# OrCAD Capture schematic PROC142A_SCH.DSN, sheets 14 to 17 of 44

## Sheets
14 13. CURRENT MONITORING DEVICES: size C; title: CURRENT MONITORING DEVICES
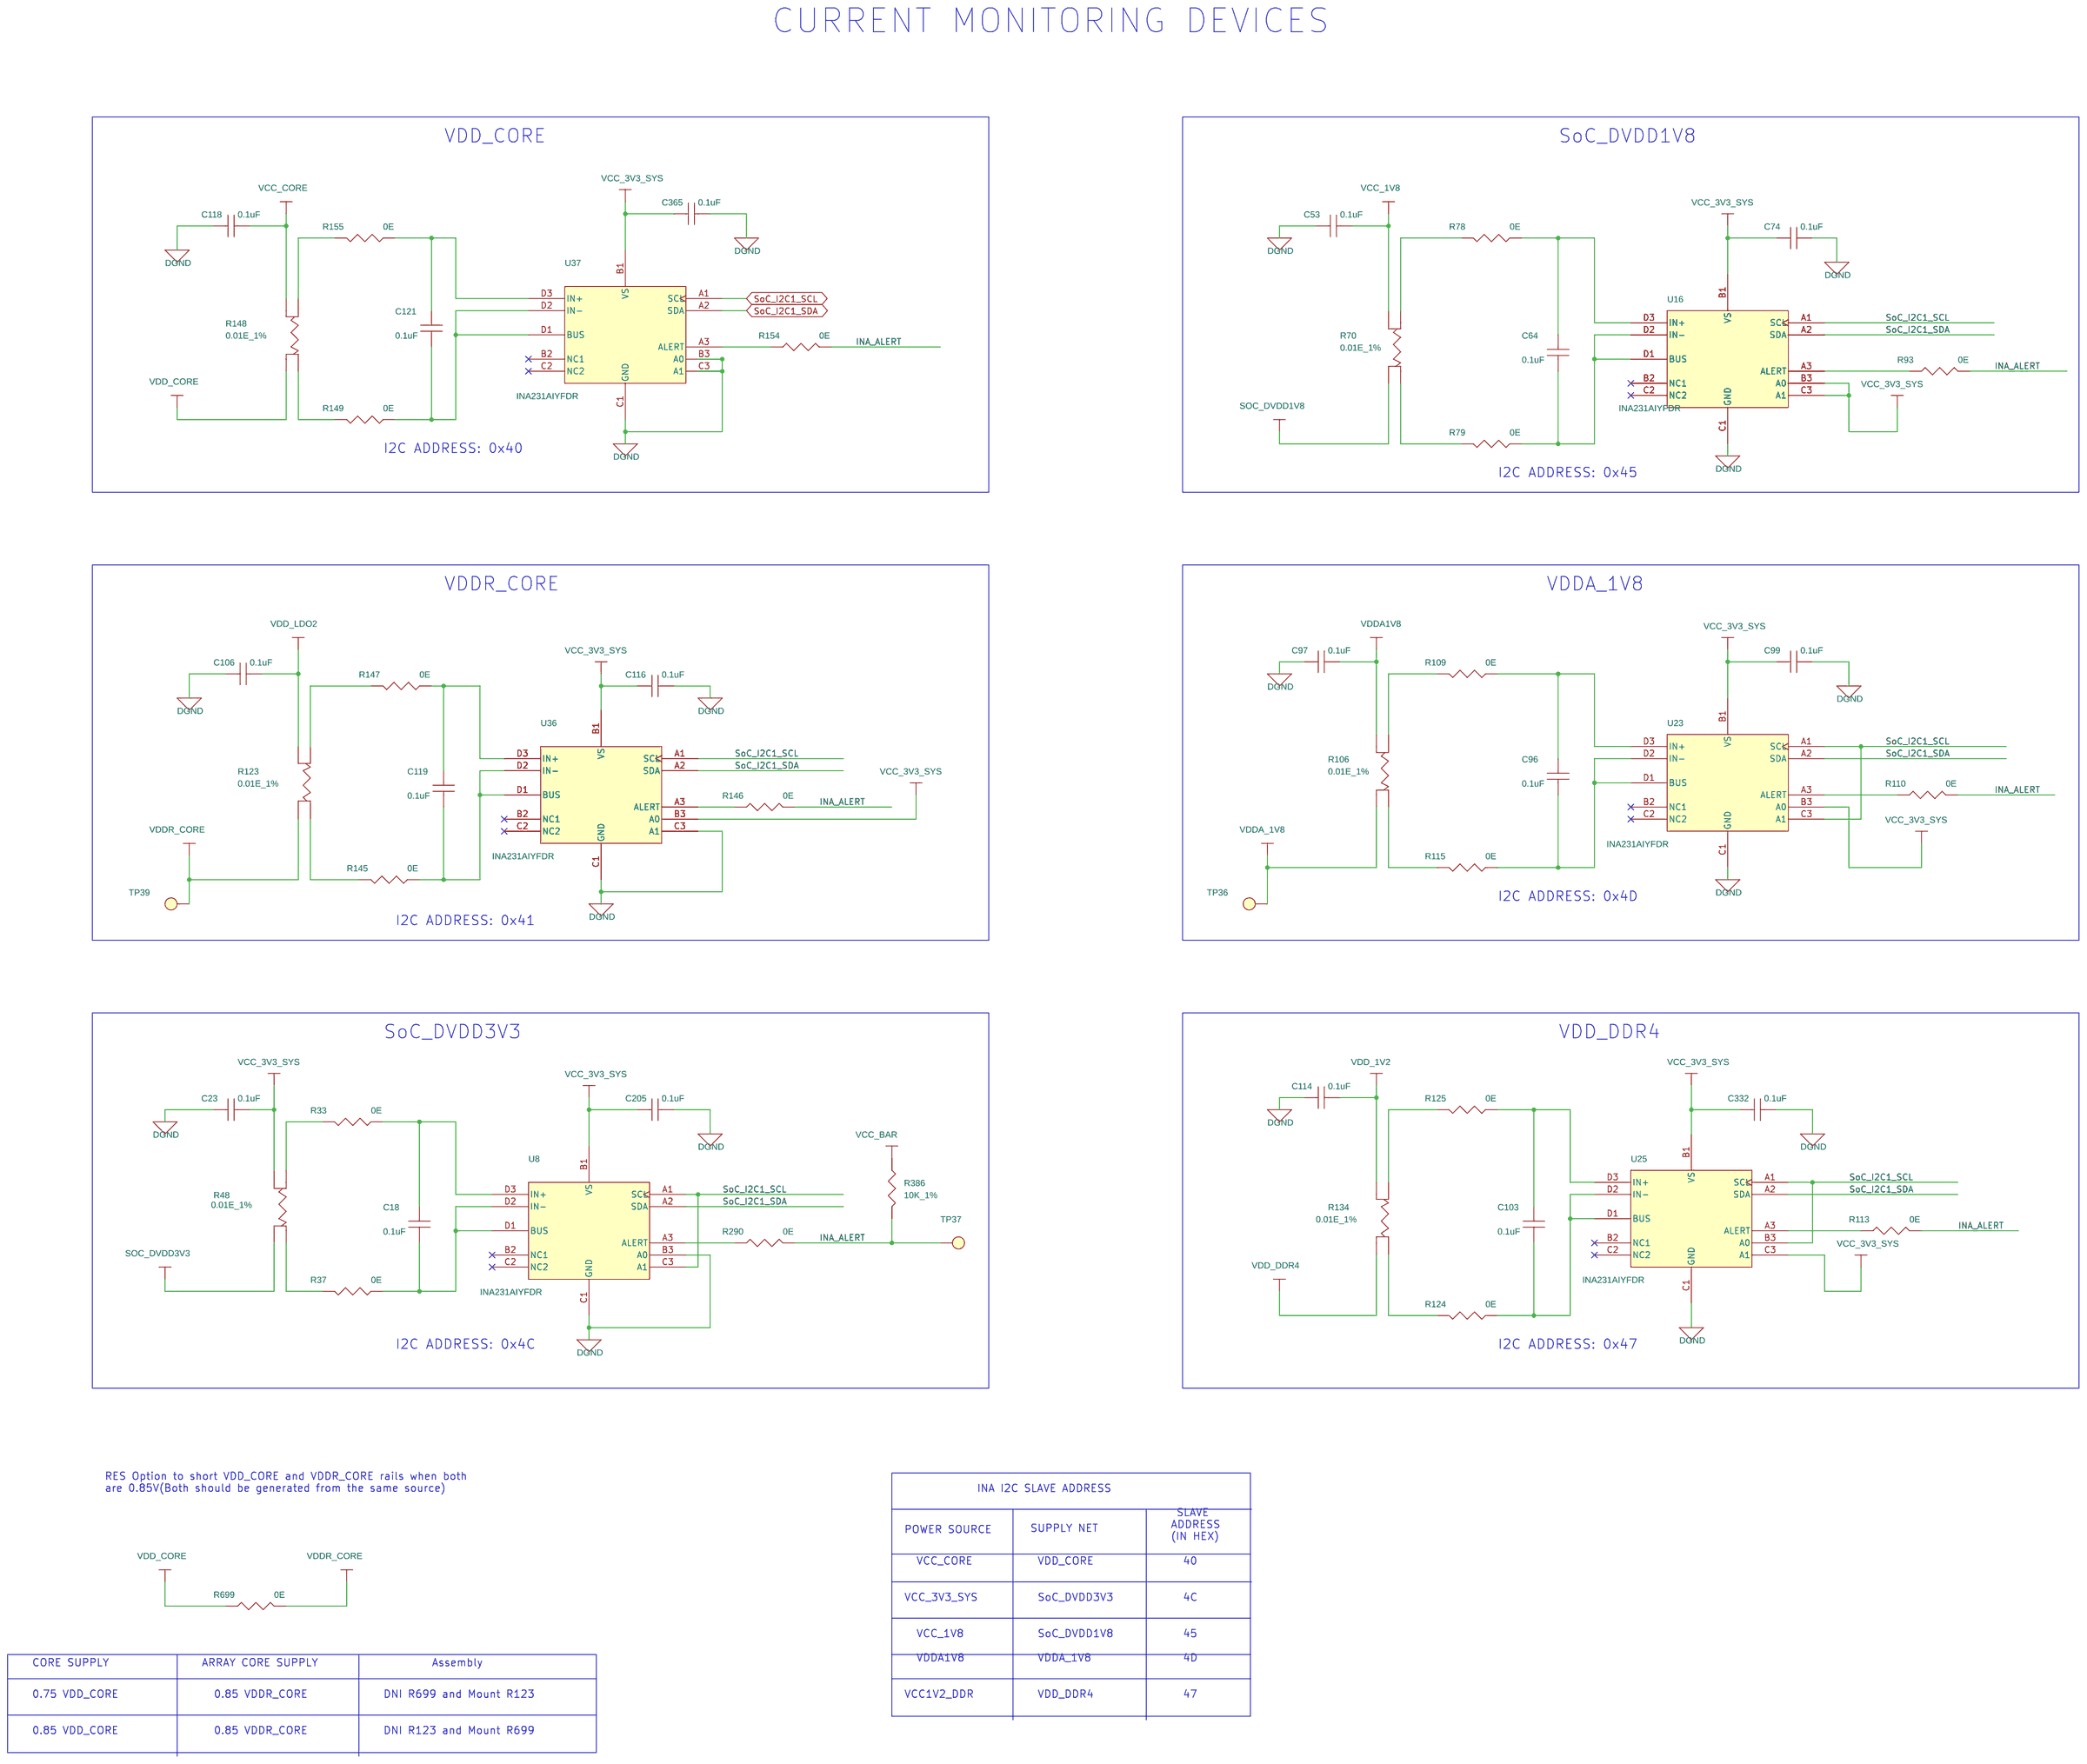
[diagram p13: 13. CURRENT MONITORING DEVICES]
15 14. SOC POWER: size C; title: SOC POWER
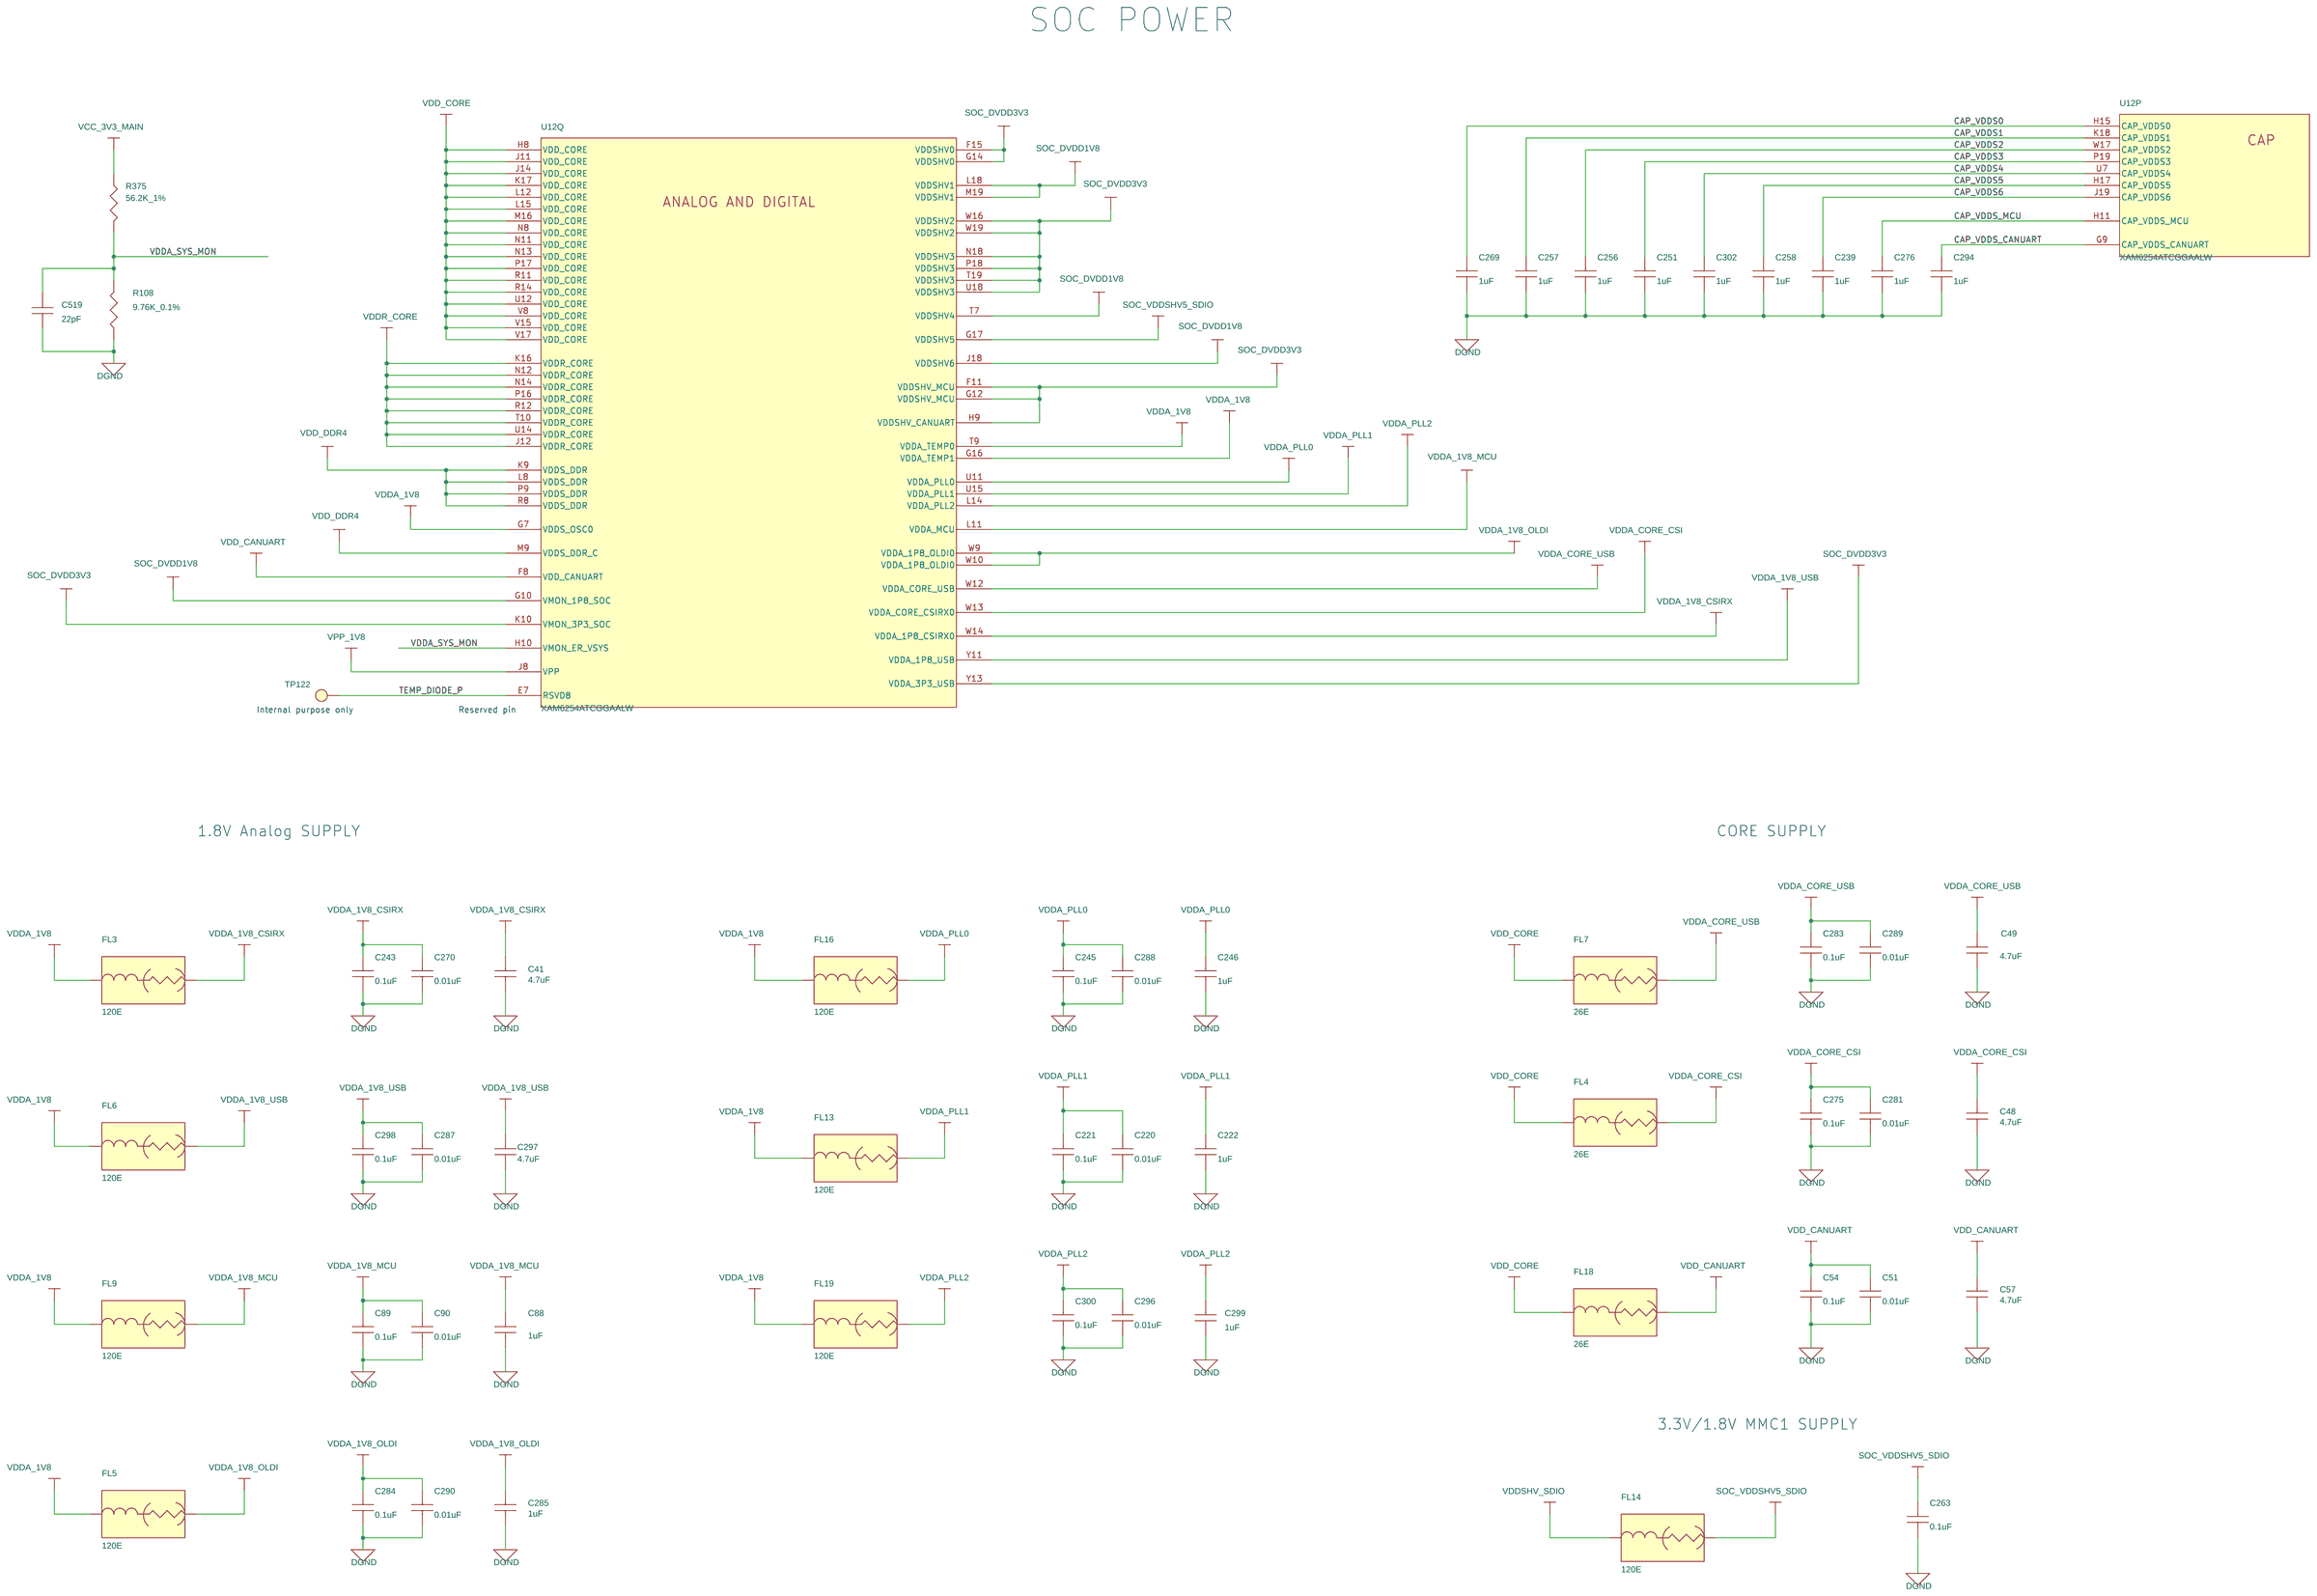
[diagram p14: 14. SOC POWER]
16 15. SOC POWER CAPS: size C; title: SOC POWER CAPS & SOC VSS
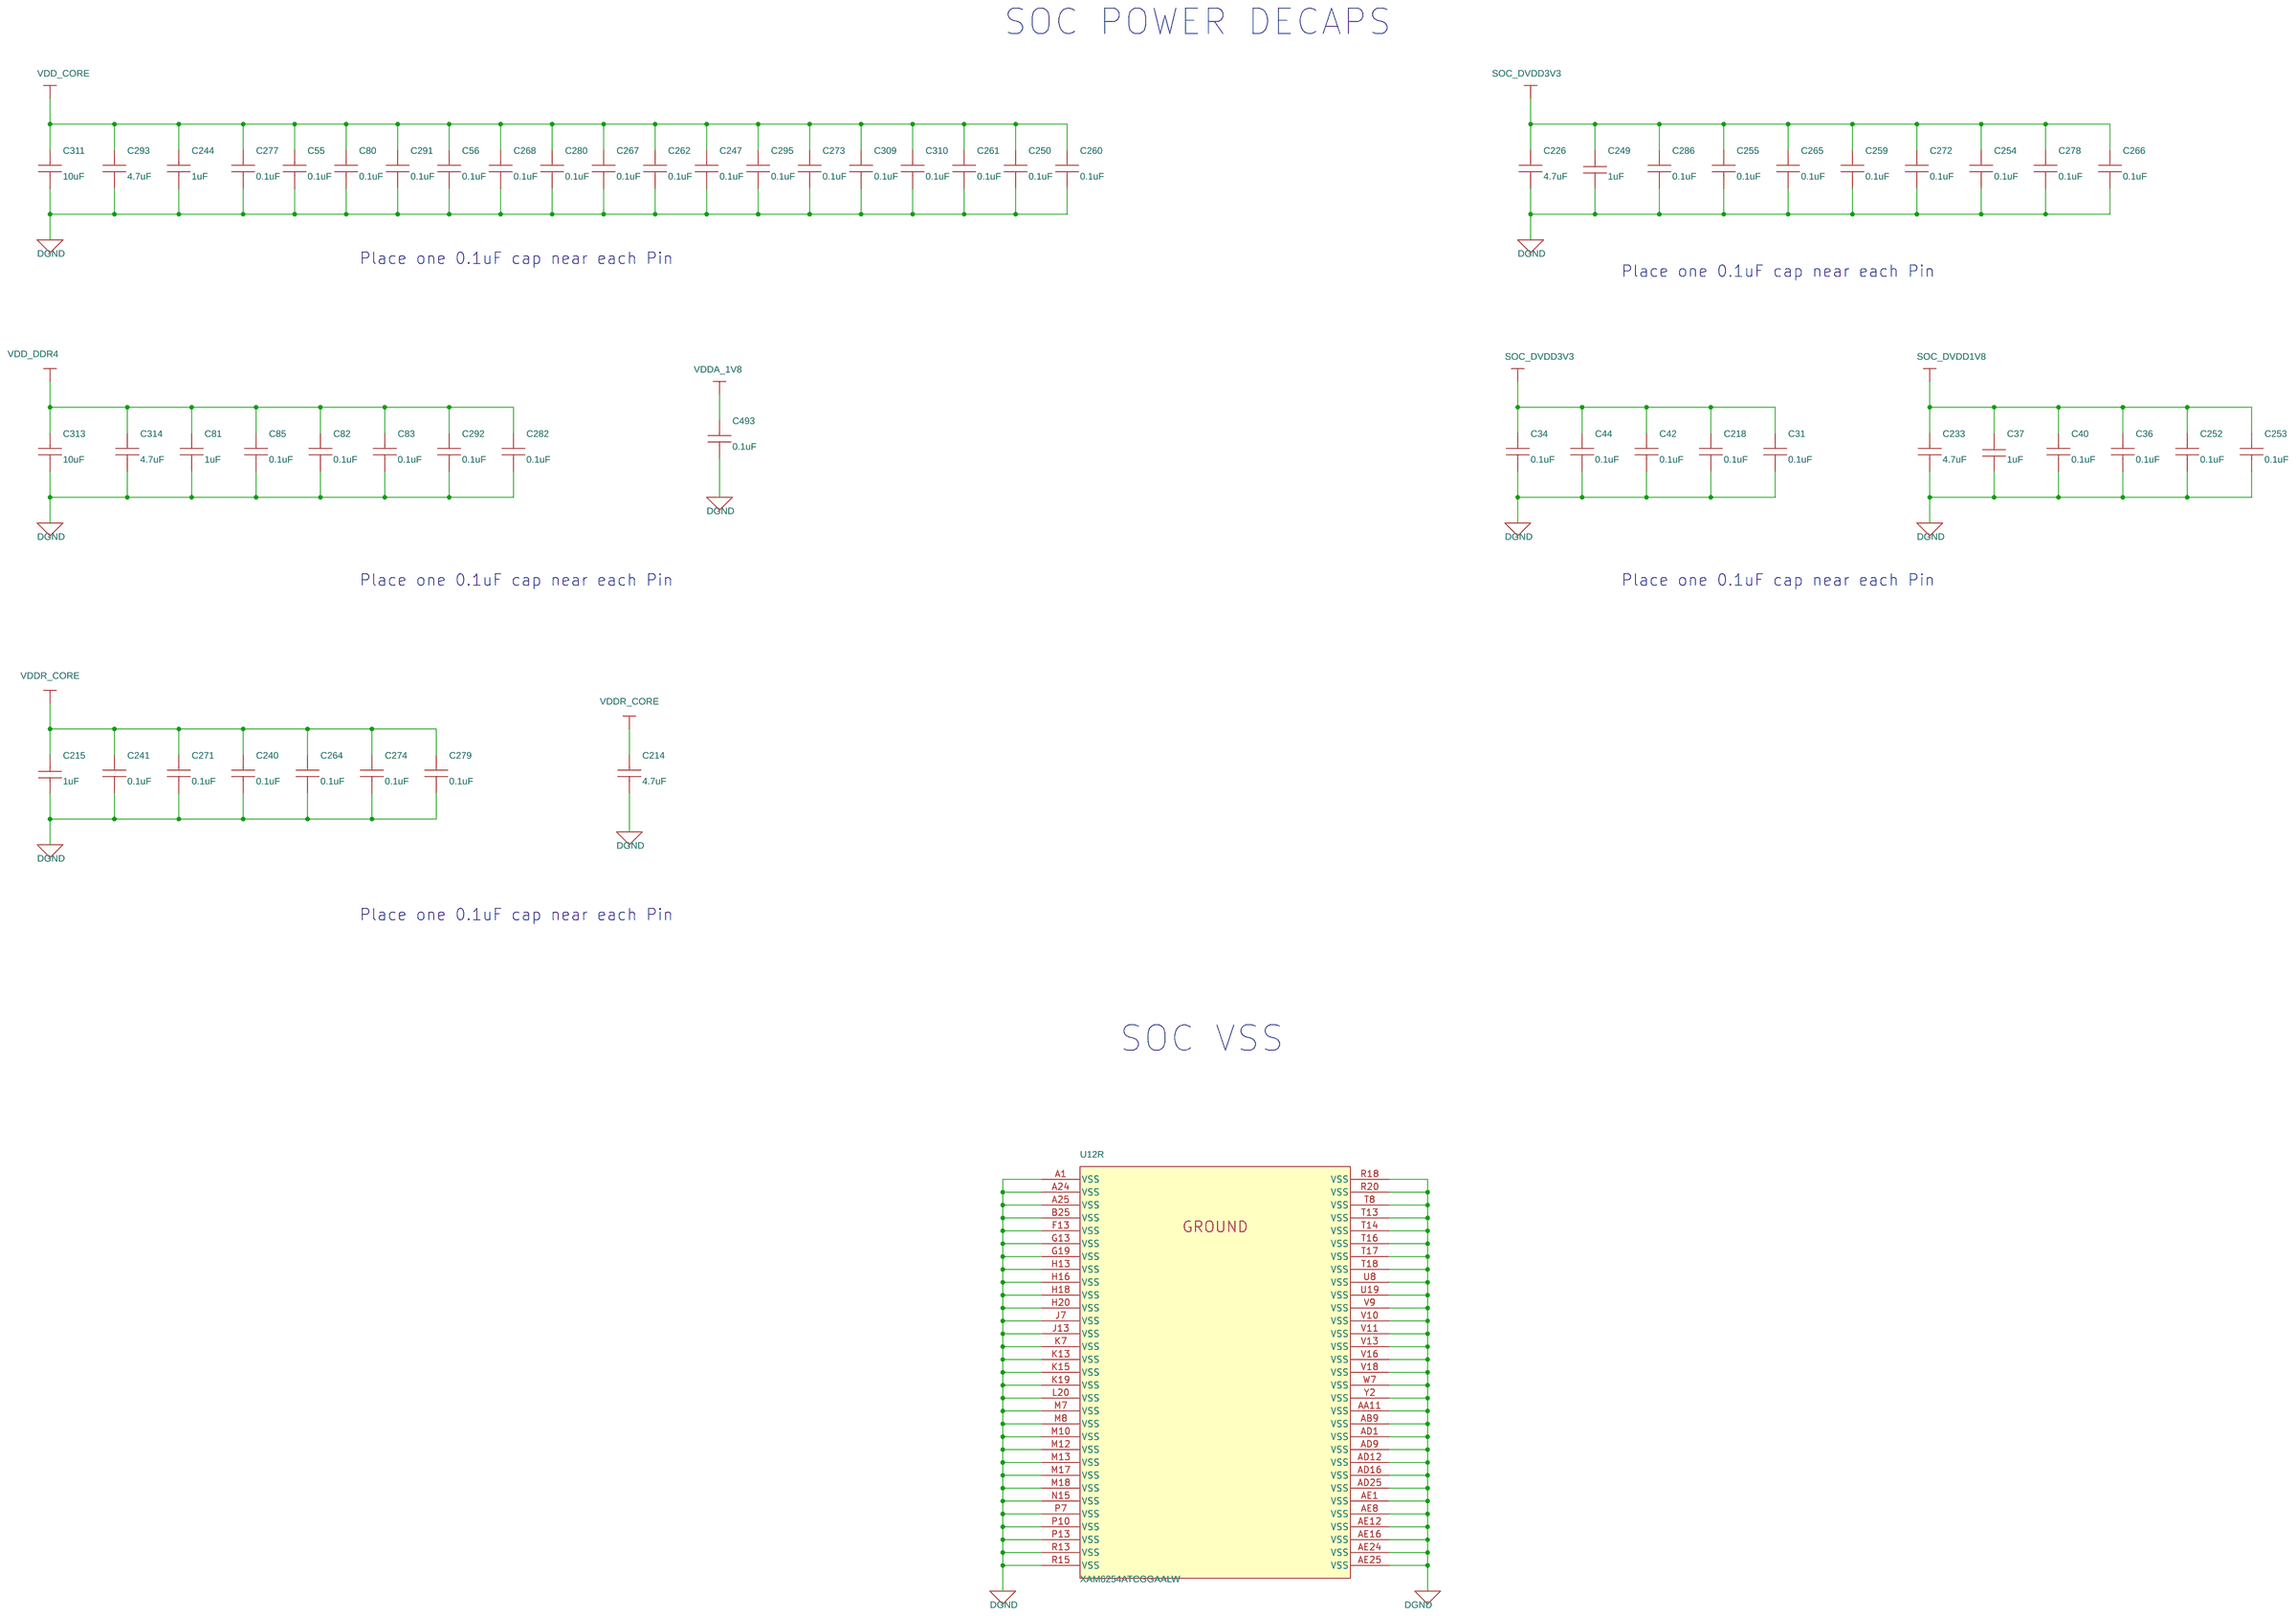
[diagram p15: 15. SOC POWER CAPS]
17 16. DDR4 INTERFACE: size C; title: DDR4 Interface

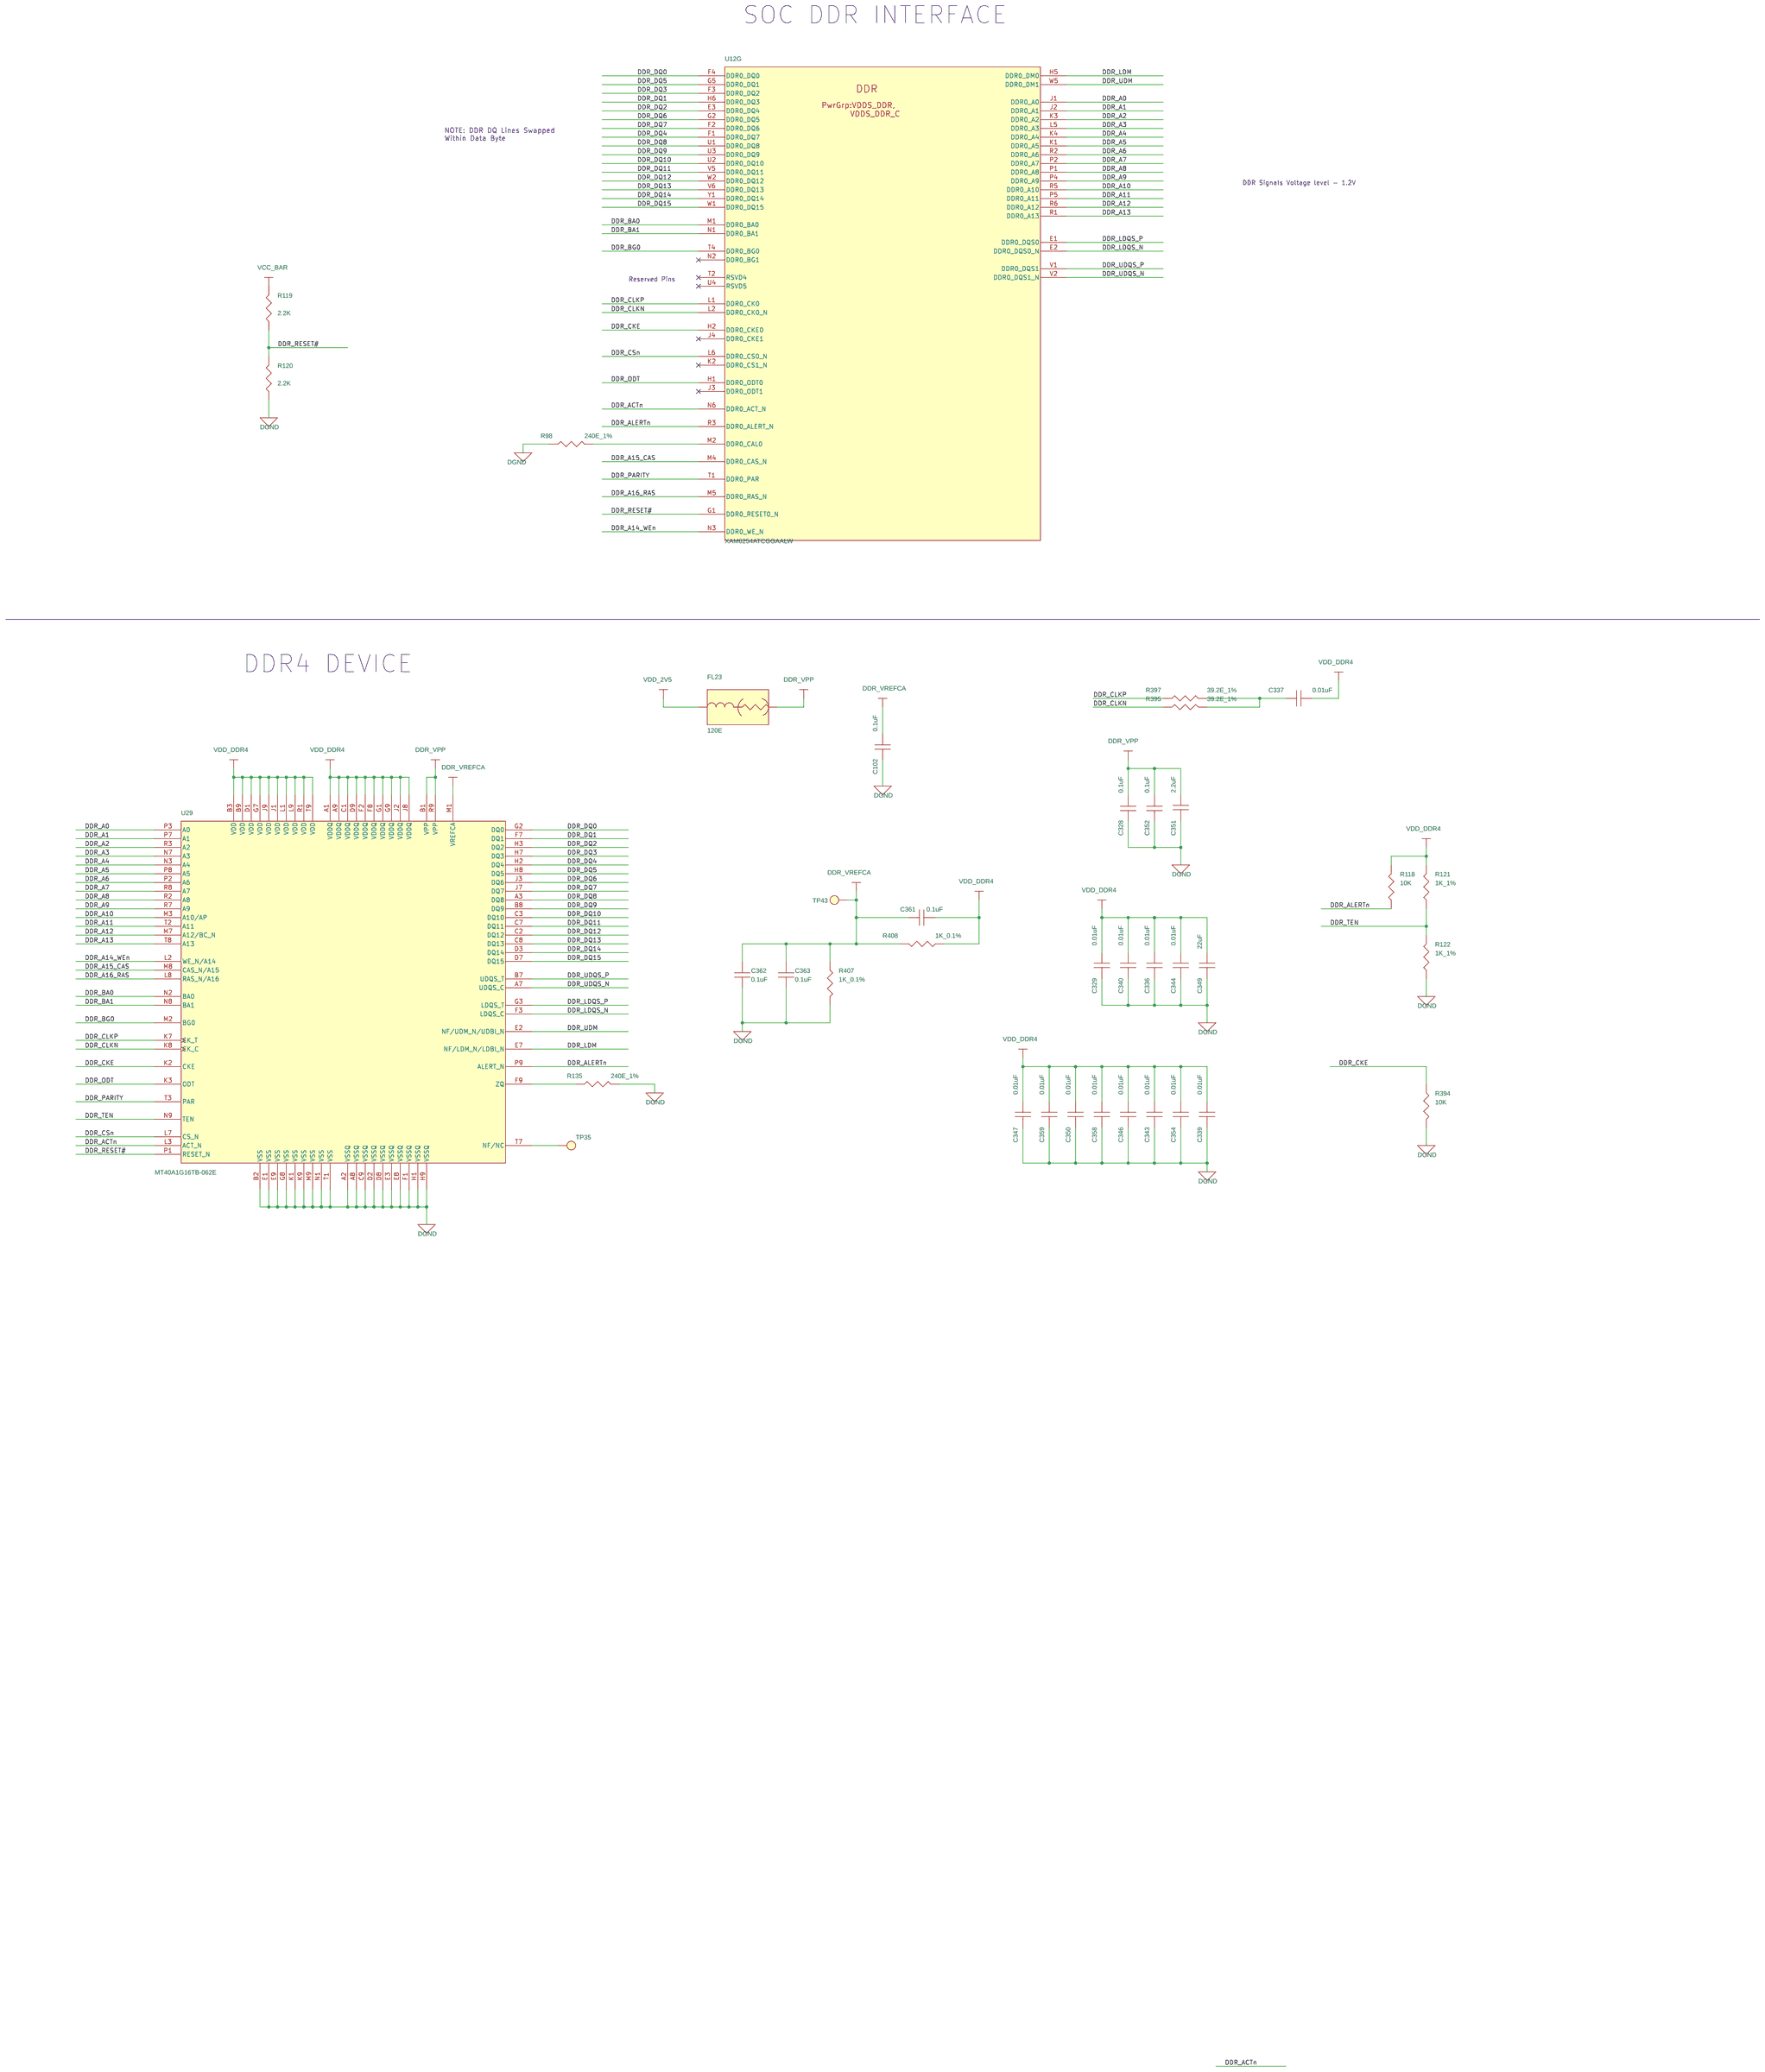
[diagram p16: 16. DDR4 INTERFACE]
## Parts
sheet 13. CURRENT MONITORING DEVICES
C18  0.1uF  [CAP0402_0-75]
C23  0.1uF  [CAP0402_0-75]
C53  0.1uF  [CAP0402_0-75]
C64  0.1uF  [CAP0402_0-75]
C74  0.1uF  [CAP0402_0-75]
C96  0.1uF  [CAP0402_0-75]
C97  0.1uF  [CAP0402_0-75]
C99  0.1uF  [CAP0402_0-75]
C103  0.1uF  [CAP0402_0-75]
C106  0.1uF  [CAP0402_0-75]
C114  0.1uF  [CAP0402_0-75]
C116  0.1uF  [CAP0402_0-75]
C118  0.1uF  [CAP0402_0-75]
C119  0.1uF  [CAP0402_0-75]
C121  0.1uF  [CAP0402_0-75]
C205  0.1uF  [CAP0402_0-75]
C332  0.1uF  [CAP0402_0-75]
C365  0.1uF  [CAP0402_0-75]
R33  0E  [RES0402_0-5]
R37  0E  [RES0402_0-5]
R48  0.01E_1%  [RES_KRL3216T4_1206-4_0-7]
R70  0.01E_1%  [RES_KRL3216T4_1206-4_0-7]
R78  0E  [RES0402_0-5]
R79  0E  [RES0402_0-5]
R93  0E  [RES0402_0-5]
R106  0.01E_1%  [RES_KRL3216T4_1206-4_0-7]
R109  0E  [RES0402_0-5]
R110  0E  [RES0402_0-5]
R113  0E  [RES0402_0-5]
R115  0E  [RES0402_0-5]
R123  0.01E_1%  [RES_KRL3216T4_1206-4_0-7]
R124  0E  [RES0402_0-5]
R125  0E  [RES0402_0-5]
R134  0.01E_1%  [RES_KRL3216T4_1206-4_0-7]
R145  0E  [RES0402_0-5]
R146  0E  [RES0402_0-5]
R147  0E  [RES0402_0-5]
R148  0.01E_1%  [RES_KRL3216T4_1206-4_0-7]
R149  0E  [RES0402_0-5]
R154  0E  [RES0402_0-5]
R155  0E  [RES0402_0-5]
R290  0E  [RES0402_0-5]
R386  10K_1%  [RES0201_0-5]
R699  0E  [RES0805_0-75]
TP36  TP20_SMD  [TP20_SMD]
TP37  TP20_SMD  [TP20_SMD]
TP39  TP20_SMD  [TP20_SMD]
U8  INA231AIYFDR  [DSBGA12_15-74_60X70_0-4]
U16  INA231AIYFDR  [DSBGA12_15-74_60X70_0-4]
U23  INA231AIYFDR  [DSBGA12_15-74_60X70_0-4]
U25  INA231AIYFDR  [DSBGA12_15-74_60X70_0-4]
U36  INA231AIYFDR  [DSBGA12_15-74_60X70_0-4]
U37  INA231AIYFDR  [DSBGA12_15-74_60X70_0-4]
sheet 14. SOC POWER
C41  4.7uF  [CAP0402_0-75]
C48  4.7uF  [CAP0402_0-75]
C49  4.7uF  [CAP0402_0-75]
C51  0.01uF  [CAP0201_0-5]
C54  0.1uF  [CAP0201_0-5]
C57  4.7uF  [CAP0402_0-75]
C88  1uF  [CAP0201_0-5]
C89  0.1uF  [CAP0201_0-5]
C90  0.01uF  [CAP0201_0-5]
C220  0.01uF  [CAP0201_0-5]
C221  0.1uF  [CAP0201_0-5]
C222  1uF  [CAP0201_0-5]
C239  1uF  [CAP0201_0-5]
C243  0.1uF  [CAP0201_0-5]
C245  0.1uF  [CAP0201_0-5]
C246  1uF  [CAP0201_0-5]
C251  1uF  [CAP0201_0-5]
C256  1uF  [CAP0201_0-5]
C257  1uF  [CAP0201_0-5]
C258  1uF  [CAP0201_0-5]
C263  0.1uF  [CAP0201_0-5]
C269  1uF  [CAP0201_0-5]
C270  0.01uF  [CAP0201_0-5]
C275  0.1uF  [CAP0201_0-5]
C276  1uF  [CAP0201_0-5]
C281  0.01uF  [CAP0201_0-5]
C283  0.1uF  [CAP0201_0-5]
C284  0.1uF  [CAP0201_0-5]
C285  1uF  [CAP0201_0-5]
C287  0.01uF  [CAP0201_0-5]
C288  0.01uF  [CAP0201_0-5]
C289  0.01uF  [CAP0201_0-5]
C290  0.01uF  [CAP0201_0-5]
C294  1uF  [CAP0201_0-5]
C296  0.01uF  [CAP0201_0-5]
C297  4.7uF  [CAP0402_0-75]
C298  0.1uF  [CAP0201_0-5]
C299  1uF  [CAP0201_0-5]
C300  0.1uF  [CAP0201_0-5]
C302  1uF  [CAP0201_0-5]
C519  22pF  [CAP0201_0-5]
FL3  120E  [EMIFIL_BLM15A_0402_0-6]
FL4  26E  [EMIFIL_BLM18K_0603_0-7]
FL5  120E  [EMIFIL_BLM15A_0402_0-6]
FL6  120E  [EMIFIL_BLM15A_0402_0-6]
FL7  26E  [EMIFIL_BLM18K_0603_0-7]
FL9  120E  [EMIFIL_BLM15A_0402_0-6]
FL13  120E  [EMIFIL_BLM15A_0402_0-6]
FL14  120E  [EMIFIL_BLM15A_0402_0-6]
FL16  120E  [EMIFIL_BLM15A_0402_0-6]
FL18  26E  [EMIFIL_BLM18K_0603_0-7]
FL19  120E  [EMIFIL_BLM15A_0402_0-6]
R108  9.76K_0.1%  [RES0402_0-5]
R375  56.2K_1%  [RES0402_0-5]
TP122  TP20_SMD  [TP20_SMD]
sheet 15. SOC POWER CAPS
C31  0.1uF  [CAP0201_0-5]
C34  0.1uF  [CAP0201_0-5]
C36  0.1uF  [CAP0201_0-5]
C37  1uF  [CAP0201_0-5]
C40  0.1uF  [CAP0201_0-5]
C42  0.1uF  [CAP0201_0-5]
C44  0.1uF  [CAP0201_0-5]
C55  0.1uF  [CAP0201_0-5]
C56  0.1uF  [CAP0201_0-5]
C80  0.1uF  [CAP0201_0-5]
C81  1uF  [CAP0201_0-5]
C82  0.1uF  [CAP0201_0-5]
C83  0.1uF  [CAP0201_0-5]
C85  0.1uF  [CAP0201_0-5]
C214  4.7uF  [CAP0402_0-75]
C215  1uF  [CAP0201_0-5]
C218  0.1uF  [CAP0201_0-5]
C226  4.7uF  [CAP0402_0-75]
C233  4.7uF  [CAP0402_0-75]
C240  0.1uF  [CAP0201_0-5]
C241  0.1uF  [CAP0201_0-5]
C244  1uF  [CAP0201_0-5]
C247  0.1uF  [CAP0201_0-5]
C249  1uF  [CAP0201_0-5]
C250  0.1uF  [CAP0201_0-5]
C252  0.1uF  [CAP0201_0-5]
C253  0.1uF  [CAP0201_0-5]
C254  0.1uF  [CAP0201_0-5]
C255  0.1uF  [CAP0201_0-5]
C259  0.1uF  [CAP0201_0-5]
C260  0.1uF  [CAP0201_0-5]
C261  0.1uF  [CAP0201_0-5]
C262  0.1uF  [CAP0201_0-5]
C264  0.1uF  [CAP0201_0-5]
C265  0.1uF  [CAP0201_0-5]
C266  0.1uF  [CAP0201_0-5]
C267  0.1uF  [CAP0201_0-5]
C268  0.1uF  [CAP0201_0-5]
C271  0.1uF  [CAP0201_0-5]
C272  0.1uF  [CAP0201_0-5]
C273  0.1uF  [CAP0201_0-5]
C274  0.1uF  [CAP0201_0-5]
C277  0.1uF  [CAP0201_0-5]
C278  0.1uF  [CAP0201_0-5]
C279  0.1uF  [CAP0201_0-5]
C280  0.1uF  [CAP0201_0-5]
C282  0.1uF  [CAP0201_0-5]
C286  0.1uF  [CAP0201_0-5]
C291  0.1uF  [CAP0201_0-5]
C292  0.1uF  [CAP0201_0-5]
C293  4.7uF  [CAP0402_0-75]
C295  0.1uF  [CAP0201_0-5]
C309  0.1uF  [CAP0201_0-5]
C310  0.1uF  [CAP0201_0-5]
C311  10uF  [CAP0402_0-75]
C313  10uF  [CAP0402_0-75]
C314  4.7uF  [CAP0402_0-75]
C493  0.1uF  [CAP0201_0-5]
sheet 16. DDR4 INTERFACE
C102  0.1uF  [CAP0201_0-5]
C328  0.1uF  [CAP0201_0-5]
C329  0.01uF  [CAP0201_0-5]
C336  0.01uF  [CAP0201_0-5]
C337  0.01uF  [CAP0201_0-5]
C339  0.01uF  [CAP0201_0-5]
C340  0.01uF  [CAP0201_0-5]
C343  0.01uF  [CAP0201_0-5]
C344  0.01uF  [CAP0201_0-5]
C346  0.01uF  [CAP0201_0-5]
C347  0.01uF  [CAP0201_0-5]
C349  22uF  [CAP0603_1]
C350  0.01uF  [CAP0201_0-5]
C351  2.2uF  [CAP0402_0-75]
C352  0.1uF  [CAP0201_0-5]
C354  0.01uF  [CAP0201_0-5]
C358  0.01uF  [CAP0201_0-5]
C359  0.01uF  [CAP0201_0-5]
C361  0.1uF  [CAP0201_0-5]
C362  0.1uF  [CAP0201_0-5]
C363  0.1uF  [CAP0201_0-5]
FL23  120E  [EMIFIL_BLM15A_0402_0-6]
R98  240E_1%  [RES0402_0-5]
R118  10K  [RES0201_0-5]
R119  2.2K  [RES0201_0-5]
R120  2.2K  [RES0402_0-5]
R121  1K_1%  [RES0402_0-5]
R122  1K_1%  [RES0402_0-5]
R135  240E_1%  [RES0402_0-5]
R394  10K  [RES0201_0-5]
R395  39.2E_1%  [RES0402_0-5]
R397  39.2E_1%  [RES0402_0-5]
R407  1K_0.1%  [RES0201_0-5]
R408  1K_0.1%  [RES0201_0-5]
TP35  TP20_SMD  [TP20_SMD]
TP43  TP20_SMD  [TP20_SMD]
U29  MT40A1G16TB-062E  [FBGA96_31-49_300X520_1-2]
sheet 29. JTAG BUFFER
U12  XAM6254ATCGGAALW  [BGA425_19-68_510X510_0-7]  (sections A,B,C,D,E,F,G,H,I,J,K,L,M,N,O,P,Q,R)

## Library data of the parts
C18 C23 C53 C64 C74 C96 C97 C99 C103 C106 C114 C116 C118 C119 C121 C205 C332 C365 = CAP: CAP CERAMIC 0.1uF 50V 10% X7R 0402; Alt_Mfr_name: YAGEO AMERICA; Alt_Mfr_part_number: CC0402KRX5R8BB104; Chkd/date: MANIRAJA/261020; Crtd /date: ALVY/211020; Custom_Duty: 15%; Customs_HS_Code: 85322990; Distributor_name: DIGIKEY; Distributor_part_number: 490-10700-1-ND; Footprint Path: Y:\MIS_DATABASE\Library\ALTIUM_TOOL\PCB_FOOTPRINTS\Altium_Footprint_Lib.PcbLib; Height: 0.55MM; Library Path: Y:\MIS_DATABASE\Library\ALTIUM_TOOL\SCHEMATICS_PARTS\MS_DISCRETE_Library.schlib; Mfr_name: MURATA; Mfr_part_number: GRM155R71H104KE14D; Mistral Part No: 120011100014-R; Package: 0402; Part_type: CAPACITORS\CERAMIC; Project: J7_CP; RoHS: RoHS; Temperature: -55°C+125°C; Tolerance: 10%; Voltage: 50V; Wattage: NA; Weight: 3.1mg; Datasheet: Y:\MIS_DATABASE\DATASHEETS\CAPACITORS\GRM155R71H104KE14.PDF
R33 R37 R78 R79 R93 R109 R110 R113 R115 R124 R125 R145-R147 R149 R154 R155 R290 = RESISTOR: RES 0E 1/16W JUMPER 0402; Chkd/date: VASANTHA/201216; Crtd /date: MUDDU/190810; Custom_Duty: 15%; Customs_HS_Code: 85332119; Distributor_name: DIGIKEY; Distributor_part_number: 541-0.0JCT-ND; Footprint Path: Y:\MIS_DATABASE\Library\ALTIUM_TOOL\PCB_FOOTPRINTS\Altium_Footprint_Lib.PcbLib; Height: 0.40MM; Library Path: Y:\MIS_DATABASE\Library\ALTIUM_TOOL\SCHEMATICS_PARTS\MS_DISCRETE_Library.schlib; Mfr_name: VISHAY; Mfr_part_number: CRCW04020000Z0ED; Mistral Part No: 110010080019-R; Package: 0402; Part_type: RESISTORS\FIXED; Project: PB_BUGBASE; RoHS: RoHS; Temperature: -55°C+155°C; Tolerance: NA; Voltage: NA; Wattage: 1/16W; Weight: 0.65mg; Datasheet: Y:\MIS_DATABASE\DATASHEETS\RESISTORS\CRCW0603.PDF
R48 R70 R106 R123 R134 R148 = RESISTOR-4TERM: RES 0.01E 1W 1% 1206-4; Chkd/date: MANIRAJA/060318; Crtd /date: MANIRAJA/060318; Custom_Duty: 15%; Customs_HS_Code: 85332119; Distributor_name: DIGIKEY; Distributor_part_number: 408-1974-1-ND; Footprint Path: Y:\MIS_DATABASE\Library\ALTIUM_TOOL\PCB_FOOTPRINTS\Altium_Footprint_Lib.PcbLib; Height: 0.70MM; Library Path: Y:\MIS_DATABASE\Library\ALTIUM_TOOL\SCHEMATICS_PARTS\MS_DISCRETE_Library.schlib; Mfr_name: SUSUMU; Mfr_part_number: KRL3216T4A-M-R010-F-T1; Mistral Part No: 110018030003-R; Package: 1206-4; Part_type: RESISTORS\FIXED; Project: GRACO SMART MODULE; RoHS: RoHS; Temperature: -55°C+155°C; Tolerance: 1%; Voltage: NA; Wattage: 1W; Weight: 16.2mg; Datasheet: Y:\MIS_DATABASE\DATASHEETS\RESISTORS\KRL-SERIES.PDF
R386 = RESISTOR: RES 10K 1/20W 1% 0201; Chkd/date: VASANTHA/270117; Crtd /date: MANIRAJA/270117; Custom_Duty: 15%; Customs_HS_Code: 85332119; Distributor_name: DIGIKEY; Distributor_part_number: 311-10.0KMCT-ND; Footprint Path: Y:\MIS_DATABASE\Library\ALTIUM_TOOL\PCB_FOOTPRINTS\Altium_Footprint_Lib.PcbLib; Height: 0.26MM; Library Path: Y:\MIS_DATABASE\Library\ALTIUM_TOOL\SCHEMATICS_PARTS\MS_DISCRETE_Library.schlib; Mfr_name: YAGEO AMERICA; Mfr_part_number: RC0201FR-0710KL; Mistral Part No: 110011040018-R; Package: 0201; Part_type: RESISTORS\FIXED; Project: GOLDEN-I LITE; RoHS: RoHS; Temperature: -55°C+125°C; Tolerance: 1%; Voltage: NA; Wattage: 1/20W; Weight: 0.17mg; Datasheet: Y:\MIS_DATABASE\DATASHEETS\RESISTORS\RCXXXXL-SER_MAR18.PDF
R699 = RESISTOR: RES 0E 1/8W 5% 0805; Chkd/date: VASANTHA/130416; Crtd /date: JEBRAN/020316; Custom_Duty: 15%; Customs_HS_Code: 85332119; Distributor_name: DIGIKEY; Distributor_part_number: 311-0.0ARCT-ND; Footprint Path: Y:\MIS_DATABASE\Library\ALTIUM_TOOL\PCB_FOOTPRINTS\Altium_Footprint_Lib.PcbLib; Height: 0.60MM; Library Path: Y:\MIS_DATABASE\Library\ALTIUM_TOOL\SCHEMATICS_PARTS\MS_DISCRETE_Library.schlib; Mfr_name: YAGEO AMERICA; Mfr_part_number: RC0805JR-070RL; Mistral Part No: 110009030074-R; Package: 0805; Part_type: RESISTORS\FIXED; Project: ZK_BIOMETRIC; RoHS: RoHS; Temperature: -55°C+155°C; Tolerance: 5%; Voltage: NA; Wattage: 1/8W; Weight: 5.5mg; Datasheet: Y:\MIS_DATABASE\DATASHEETS\RESISTORS\RCXXXXL-SER_MAR18.PDF
TP35-TP37 TP39 TP43 TP122 = TESTPOINT: TESTPOINT CIR 20 SMD; Chkd/date: SHREESHAIL/171006; Crtd /date: MAZHAR/171006; Custom_Duty: NA; Customs_HS_Code: NA; Distributor_name: NA; Distributor_part_number: NA; Footprint Path: Y:\MIS_DATABASE\Library\ALTIUM_TOOL\PCB_FOOTPRINTS\Altium_Footprint_Lib.PcbLib; Height: NA; Library Path: Y:\MIS_DATABASE\Library\ALTIUM_TOOL\SCHEMATICS_PARTS\MS_DISCRETE_Library.schlib; MECHANICAL 3D STEP FILE: NA; Mfr_name: LOCAL; Mistral Part No: NA; Package: SMD; Project: BT MODULE_CSRBC04; RoHS: NA; Temperature: NA; Tolerance: NA; Voltage: NA; Wattage: NA; Weight: NA; Datasheet: NA
U8 U16 U23 U25 U36 U37 = INA231_DSBGA12: IC HIGH OR LOW SIDE MEASUREMENT BI-DIR CURRENT AND POWER MONITOR WITH 1.8V I2C INTERFACE DSBGA12; Chkd/date: MANIRAJA/250821; Crtd /date: ALVY/250821; Custom_Duty: 15%; Customs_HS_Code: 85423100; Distributor_name: DIGIKEY; Distributor_part_number: 296-49645-1-ND; Footprint Path: Y:\MIS_DATABASE\Library\ALTIUM_TOOL\PCB_FOOTPRINTS\Altium_Footprint_Lib.PcbLib; Height: 0.40MM; Library Path: Y:\MIS_DATABASE\Library\ALTIUM_TOOL\SCHEMATICS_PARTS\MS_MISCPOWER_Library.schlib; Mfr_name: TEXAS INSTRUMENTS; Mistral Part No: 142021080022-R; Package: DSBGA12; Part_type: ICS\POWER\MANAGEMENT; Project: TI_AM62x SVB_BRD; RoHS: RoHS; Temperature: -40°C+125°C; Tolerance: NA; Voltage: NA; Wattage: NA; Weight: 200mg; Datasheet: Y:\MIS_DATABASE\DATASHEETS\ICS\POWER\INA231XXX.PDF
C41 C48 C49 C57 C214 C226 C233 C293 C297 C314 = CAP: CAP CERAMIC 4.7uF 10V 20% X5R 0402; Chkd/date: MANIRAJA/110718; Crtd /date: ALVY/110718; Custom_Duty: 15%; Customs_HS_Code: 85322990; Distributor_name: DIGIKEY; Distributor_part_number: 490-14306-1-ND; Footprint Path: Y:\MIS_DATABASE\Library\ALTIUM_TOOL\PCB_FOOTPRINTS\Altium_Footprint_Lib.PcbLib; Height: 0.65MM; Library Path: Y:\MIS_DATABASE\Library\ALTIUM_TOOL\SCHEMATICS_PARTS\MS_DISCRETE_Library.schlib; Mfr_name: MURATA; Mfr_part_number: GRM155R61A475MEAAD; Mistral Part No: 120012060002-R; Package: 0402; Part_type: CAPACITORS\CERAMIC; Project: TI_J7SVB_PCIE_ADD-ON-CARD; RoHS: RoHS; Temperature: -55°C+85°C; Tolerance: 20%; Voltage: 10V; Wattage: NA; Weight: 14mg; Datasheet: Y:\MIS_DATABASE\DATASHEETS\CAPACITORS\GRM155R61A475MEAAD.PDF
C51 C90 C220 C270 C281 C287-C290 C296 C329 C336 C337 C339 C340 C343 C344 C346 C347 C350 C354 C358 C359 = CAP: CAP CERAMIC 0.01uF 25V 10% X5R 0201; Chkd/date: MANIRAJA/230118; Crtd /date: MANIRAJA/230118; Custom_Duty: 15%; Customs_HS_Code: 85322990; Distributor_name: DIGIKEY; Distributor_part_number: GRM033R61E103KA12J-ND; Footprint Path: Y:\MIS_DATABASE\Library\ALTIUM_TOOL\PCB_FOOTPRINTS\Altium_Footprint_Lib.PcbLib; Height: 0.33MM; Library Path: Y:\MIS_DATABASE\Library\ALTIUM_TOOL\SCHEMATICS_PARTS\MS_DISCRETE_Library.schlib; Mfr_name: MURATA; Mfr_part_number: GRM033R61E103KA12J; Mistral Part No: 120018010007-R; Package: 0201; Part_type: CAPACITORS\CERAMIC; Project: TI_MAXIE_CPB; RoHS: RoHS; Temperature: -55°C+85°C; Tolerance: 10%; Voltage: 25V; Wattage: NA; Weight: 0.33mg; Datasheet: Y:\MIS_DATABASE\DATASHEETS\CAPACITORS\GRM033R61E103KA12.PDF
C31 C34 C36 C40 C42 C44 C54-C56 C80 C82 C83 C85 C89 C102 C218 C221 C240 C241 C243 C245 C247 C250 C252-C255 C259-C268 C271-C275 C277-C280 C282-C284 C286 C291 C292 C295 C298 C300 C309 C310 C328 C352 C493 = CAP: CAP CERAMIC 0.1uF 16V 10% X5R 0201; Chkd/date: MANIRAJA/230118; Crtd /date: MANIRAJA/230118; Custom_Duty: 15%; Customs_HS_Code: 85322990; Distributor_name: DIGIKEY; Distributor_part_number: 490-14305-1-ND; Footprint Path: Y:\MIS_DATABASE\Library\ALTIUM_TOOL\PCB_FOOTPRINTS\Altium_Footprint_Lib.PcbLib; Height: 0.33MM; Library Path: Y:\MIS_DATABASE\Library\ALTIUM_TOOL\SCHEMATICS_PARTS\MS_DISCRETE_Library.schlib; Mfr_name: MURATA; Mfr_part_number: GRM033R61C104KE14D; Mistral Part No: 120009030072-R; Package: 0201; Part_type: CAPACITORS\CERAMIC; Project: TI_MAXIE_CPB; RoHS: RoHS; Temperature: -55°C+85°C; Tolerance: 10%; Voltage: 16V; Wattage: NA; Weight: 0.33mg; Datasheet: Y:\MIS_DATABASE\DATASHEETS\CAPACITORS\GRM033R61C104KE14.PDF
C37 C81 C88 C215 C222 C239 C244 C246 C249 C251 C256-C258 C269 C276 C285 C294 C299 C302 = CAP: CAP CERAMIC 1uF 16V 20% X5R 0201; Chkd/date: MANIRAJA/300520; Crtd /date: ALVY/260520; Custom_Duty: 15%; Customs_HS_Code: 85322990; Distributor_name: DIGIKEY; Distributor_part_number: 490-18654-1-ND; Footprint Path: Y:\MIS_DATABASE\Library\ALTIUM_TOOL\PCB_FOOTPRINTS\Altium_Footprint_Lib.PcbLib; Height: 0.39MM; Library Path: Y:\MIS_DATABASE\Library\ALTIUM_TOOL\SCHEMATICS_PARTS\MS_DISCRETE_Library.schlib; Mfr_name: MURATA; Mfr_part_number: GRM033R61C105ME15D; Mistral Part No: 120018090038-R; Package: 0201; Part_type: CAPACITORS\CERAMIC; Project: QCS610_NANOSOM; RoHS: RoHS; Temperature: -55°C+85°C; Tolerance: 20%; Voltage: 16V; Wattage: NA; Weight: 0.33mg; Datasheet: Y:\MIS_DATABASE\DATASHEETS\CAPACITORS\GRM033R61C105ME15.PDF
C519 = CAP: CAP CERAMIC 22pF 25V 1% C0G(NP0) 0201; Chkd/date: MANIRAJA/270721; Crtd /date: ALVY/260721; Custom_Duty: 15%; Customs_HS_Code: 85322990; Distributor_name: DIGIKEY; Distributor_part_number: 490-14545-1-ND; Footprint Path: Y:\MIS_DATABASE\Library\ALTIUM_TOOL\PCB_FOOTPRINTS\Altium_Footprint_Lib.PcbLib; Height: 0.33MM; Library Path: Y:\MIS_DATABASE\Library\ALTIUM_TOOL\SCHEMATICS_PARTS\MS_DISCRETE_Library.schlib; Mfr_name: MURATA; Mfr_part_number: GRM0335C1E220FA01D; Mistral Part No: 120021070019-R; Package: 0201; Part_type: CAPACITORS\CERAMIC; Project: TI_AM335x SK_BRD; RoHS: RoHS; Temperature: -55°C+125°C; Tolerance: 1%; Voltage: 25V; Wattage: NA; Weight: 0.33mg; Datasheet: Y:\MIS_DATABASE\DATASHEETS\CAPACITORS\GRM0335C1E220FA01.PDF
FL3 FL5 FL6 FL9 FL13 FL14 FL16 FL19 FL23 = EMIFILTER_IND: IND FERRITE BEAD CHIP 120E 2A 0402; Chkd/date: NAVEED/241114; Crtd /date: USMAN/170613; Custom_Duty: 24%; Customs_HS_Code: 85369090; Distributor_name: DIGIKEY; Distributor_part_number: 490-9656-1-ND; Footprint Path: Y:\MIS_DATABASE\Library\ALTIUM_TOOL\PCB_FOOTPRINTS\Altium_Footprint_Lib.PcbLib; Height: 0.55MM; Library Path: Y:\MIS_DATABASE\Library\ALTIUM_TOOL\SCHEMATICS_PARTS\MS_FILTER_Library.schlib; Mfr_name: MURATA; Mfr_part_number: BLM15PX121SN1D; Mistral Part No: 130013060022-R; Package: 0402; Part_type: INDUCTOR; Project: GEN_3-8; RoHS: RoHS; Temperature: -55°C+125°C; Tolerance: 25%; Voltage: NA; Wattage: NA; Weight: 1mg; Datasheet: Y:\MIS_DATABASE\DATASHEETS\DISCRETES\INDUCTORS\BLM15-SN1-SER.PDF
FL4 FL7 FL18 = EMIFILTER_IND: FERRITE CHIP 26E 6A 0603; Chkd/date: NAVEED/190115; Crtd /date: USMAN/251013; Custom_Duty: 15%; Customs_HS_Code: 85412900; Distributor_name: DIGIKEY; Distributor_part_number: 490-3995-1-ND; Height: 0.65MM; Mfr_name: MURATA; Mfr_part_number: BLM18SG260TN1D; Mistral Part No: 130013100028-R; Package: 0603; Part_type: FILTER; Project: DTRM_SBAND; RoHS: RoHS; Temperature: -55°C+125°C; Tolerance: 25%; Voltage: NA; Wattage: NA; Weight: 2mg; Datasheet: Y:\MIS_DATABASE\DATASHEETS\DISCRETES\INDUCTORS\BLM18K-SERIES.PDF
R108 = RESISTOR: RES 9.76K 1/16W 0.1% 0402; Chkd/date: MANIRAJA/190419; Crtd /date: MANIRAJA/190419; Custom_Duty: 15%; Customs_HS_Code: 85332119; Distributor_name: DIGIKEY; Distributor_part_number: P9.76KDCCT-ND; Footprint Path: Y:\MIS_DATABASE\Library\ALTIUM_TOOL\PCB_FOOTPRINTS\Altium_Footprint_Lib.PcbLib; Height: 0.40MM; Library Path: Y:\MIS_DATABASE\Library\ALTIUM_TOOL\SCHEMATICS_PARTS\MS_DISCRETE_Library.schlib; Mfr_name: PANASONIC-ECG; Mfr_part_number: ERA-2AEB9761X; Mistral Part No: 110019040291-R; Package: 0402; Part_type: RESISTORS\FIXED; Project: TI_J7ES_EVM_FUSION2_SER_CAP; RoHS: RoHS; Temperature: -55°C+155°C; Tolerance: 0.1%; Voltage: NA; Wattage: 1/16W; Weight: 0.6mg; Datasheet: Y:\MIS_DATABASE\DATASHEETS\RESISTORS\ERA-1A.PDF
R375 = RESISTOR: RES 56.2K 1/16W 1% 0402; Chkd/date: SHREESHAIL/240507; Crtd /date: MAZHAR/010806; Custom_Duty: 15%; Customs_HS_Code: 85332119; Distributor_name: NA; Distributor_part_number: NA; Footprint Path: Y:\MIS_DATABASE\Library\ALTIUM_TOOL\PCB_FOOTPRINTS\Altium_Footprint_Lib.PcbLib; Height: 0.40MM; Library Path: Y:\MIS_DATABASE\Library\ALTIUM_TOOL\SCHEMATICS_PARTS\MS_DISCRETE_Library.schlib; Mfr_name: YAGEO AMERICA; Mfr_part_number: 9C04021A5622FLHF3; Mistral Part No: 110009030982; Package: 0402; Part_type: RESISTORS\FIXED; Project: POWERBOX; RoHS: NA; Temperature: -55°C+155°C; Tolerance: 1%; Voltage: NA; Wattage: 1/16W; Weight: 0.58mg; Datasheet: Y:\MIS_DATABASE\DATASHEETS\RESISTORS\9C_SERIES.PDF
C311 C313 = CAP: CAP CERAMIC 10uF 10V 20% X5R 0402; Chkd/date: MANIRAJA/300520; Crtd /date: ALVY/260520; Custom_Duty: 15%; Customs_HS_Code: 85322990; Distributor_name: DIGIKEY; Distributor_part_number: 490-GRM155R61A106ME11DTR-ND; Footprint Path: Y:\MIS_DATABASE\Library\ALTIUM_TOOL\PCB_FOOTPRINTS\Altium_Footprint_Lib.PcbLib; Height: 0.55MM; Library Path: Y:\MIS_DATABASE\Library\ALTIUM_TOOL\SCHEMATICS_PARTS\MS_DISCRETE_Library.schlib; Mfr_name: MURATA; Mfr_part_number: GRM155R61A106ME11D; Mistral Part No: 120013110019-R; Package: 0402; Part_type: CAPACITORS\CERAMIC; Project: QCS610_NANOSOM; RoHS: RoHS; Temperature: -55°C+85°C; Tolerance: 20%; Voltage: 10V; Wattage: NA; Weight: 3.1mg; Datasheet: Y:\MIS_DATABASE\DATASHEETS\CAPACITORS\MURATA-GXX-SER_NOV17.PDF
C349 = CAP: CAP CERAMIC 22uF 10V 20% X5R 0603; Chkd/date: MANIRAJA/230118; Crtd /date: MANIRAJA/230118; Custom_Duty: 15%; Customs_HS_Code: 85322990; Distributor_name: DIGIKEY; Distributor_part_number: 490-10476-1-ND; Footprint Path: Y:\MIS_DATABASE\Library\ALTIUM_TOOL\PCB_FOOTPRINTS\Altium_Footprint_Lib.PcbLib; Height: 1.00MM; Library Path: Y:\MIS_DATABASE\Library\ALTIUM_TOOL\SCHEMATICS_PARTS\MS_DISCRETE_Library.schlib; Mfr_name: MURATA; Mfr_part_number: GRM188R61A226ME15D; Mistral Part No: 120014100009-R; Package: 0603; Part_type: CAPACITORS\CERAMIC; Project: TI_MAXIE_CPB; RoHS: RoHS; Temperature: -55°C+85°C; Tolerance: 20%; Voltage: 10V; Wattage: NA; Weight: 6.3mg; Datasheet: Y:\MIS_DATABASE\DATASHEETS\CAPACITORS\GRM188R61A226ME15.PDF
C351 = CAP: CAP CERAMIC 2.2uF 25V 10% X5R 0402; Chkd/date: ALVY/010721; Crtd /date: MANIRAJA/010721; Custom_Duty: 15%; Customs_HS_Code: 85322990; Distributor_name: DIGIKEY; Distributor_part_number: 490-12703-1-ND; Footprint Path: Y:\MIS_DATABASE\Library\ALTIUM_TOOL\PCB_FOOTPRINTS\Altium_Footprint_Lib.PcbLib; Height: 0.70MM; Library Path: Y:\MIS_DATABASE\Library\ALTIUM_TOOL\SCHEMATICS_PARTS\MS_DISCRETE_Library.schlib; Mfr_name: MURATA; Mfr_part_number: GRM155R61E225KE11D; Mistral Part No: 120015120001-R; Package: 0402; Part_type: CAPACITORS\CERAMIC; Project: TI_AM263X_CC; RoHS: RoHS; Temperature: -55°C+85°C; Tolerance: 10%; Voltage: 25V; Wattage: NA; Weight: 1.5mg; Datasheet: Y:\MIS_DATABASE\DATASHEETS\CAPACITORS\GRM155R61E225KE11.PDF
C361-C363 = CAP: CAP CERAMIC 0.1uF 16V 10% X5R 0201; Alt_Mfr_name: YAGEO AMERICA; Alt_Mfr_part_number: CC0402KRX5R8BB104; Chkd/date: MANIRAJA/230118; Crtd /date: MANIRAJA/230118; Custom_Duty: 15%; Customs_HS_Code: 85322990; Distributor_name: DIGIKEY; Distributor_part_number: 490-14305-1-ND; Footprint Path: Y:\MIS_DATABASE\Library\ALTIUM_TOOL\PCB_FOOTPRINTS\Altium_Footprint_Lib.PcbLib; Height: 0.33MM; Library Path: Y:\MIS_DATABASE\Library\ALTIUM_TOOL\SCHEMATICS_PARTS\MS_DISCRETE_Library.schlib; Mfr_name: MURATA; Mfr_part_number: GRM033R61C104KE14D; Mistral Part No: 120009030072-R; Package: 0201; Part_type: CAPACITORS\CERAMIC; Project: TI_MAXIE_CPB; RoHS: RoHS; Temperature: -55°C+85°C; Tolerance: 10%; Voltage: 16V; Wattage: NA; Weight: 0.33mg; Datasheet: Y:\MIS_DATABASE\DATASHEETS\CAPACITORS\GRM033R61C104KE14.PDF
R98 R135 = RESISTOR: RES 240E 1/10W 1% 0402; Chkd/date: MAZHAR/150611; Crtd /date: BAVISH/020611; Custom_Duty: 15%; Customs_HS_Code: 85332119; Distributor_name: DIGIKEY; Distributor_part_number: P240LCT-ND; Footprint Path: Y:\MIS_DATABASE\Library\ALTIUM_TOOL\PCB_FOOTPRINTS\Altium_Footprint_Lib.PcbLib; Height: 0.40MM; Library Path: Y:\MIS_DATABASE\Library\ALTIUM_TOOL\SCHEMATICS_PARTS\MS_DISCRETE_Library.schlib; Mfr_name: PANASONIC-ECG; Mfr_part_number: ERJ-2RKF2400X; Mistral Part No: 110011060017-R; Package: 0402; Part_type: RESISTORS\FIXED; Project: AM4515_EVM_LCD; RoHS: RoHS; Temperature: -55°C+155°C; Tolerance: 1%; Voltage: NA; Wattage: 1/10W; Weight: 0.8mg; Datasheet: Y:\MIS_DATABASE\DATASHEETS\RESISTORS\PAN-ERJSER_NOV17.PDF
R118 R394 = RESISTOR: RES 10K 1/20W 5% 0201; Chkd/date: MANIRAJA/050517; Crtd /date: MANIRAJA/050517; Custom_Duty: 15%; Customs_HS_Code: 85332119; Distributor_name: DIGIKEY; Distributor_part_number: 311-10KNCT-ND; Footprint Path: Y:\MIS_DATABASE\Library\ALTIUM_TOOL\PCB_FOOTPRINTS\Altium_Footprint_Lib.PcbLib; Height: 0.26MM; Library Path: Y:\MIS_DATABASE\Library\ALTIUM_TOOL\SCHEMATICS_PARTS\MS_DISCRETE_Library.schlib; Mfr_name: YAGEO AMERICA; Mfr_part_number: RC0201JR-0710KL; Mistral Part No: 110010070051-R; Package: 0201; Part_type: RESISTORS\FIXED; Project: GOLDEN-I LITE; RoHS: RoHS; Temperature: -55°C+125°C; Tolerance: 5%; Voltage: NA; Wattage: 1/20W; Weight: 0.17mg; Datasheet: Y:\MIS_DATABASE\DATASHEETS\RESISTORS\RCXXXXL-SER_MAR18.PDF
R119 = RESISTOR: RES 2.2K 1/20W 5% 0201; Chkd/date: VASANTHA/010117; Crtd /date: MAZHAR/010605; Custom_Duty: 15%; Customs_HS_Code: 85332119; Distributor_name: DIGIKEY; Distributor_part_number: P2.2KAGCT-ND; Footprint Path: Y:\MIS_DATABASE\Library\ALTIUM_TOOL\PCB_FOOTPRINTS\Altium_Footprint_Lib.PcbLib; Height: 0.26MM; Library Path: Y:\MIS_DATABASE\Library\ALTIUM_TOOL\SCHEMATICS_PARTS\MS_DISCRETE_Library.schlib; Mfr_name: PANASONIC-ECG; Mfr_part_number: ERJ-1GEJ222C; Mistral Part No: 110009030427-R; Package: 0201; Part_type: RESISTORS\FIXED; Project: G4SLIM; RoHS: RoHS; Temperature: -55°C+125°C; Tolerance: 5%; Voltage: NA; Wattage: 1/20W; Weight: 0.15mg; Datasheet: Y:\MIS_DATABASE\DATASHEETS\RESISTORS\PAN-ERJXGE-FEB06.PDF
R120 = RESISTOR: RES 2.2K 1/16W 5% 0402; Chkd/date: VASANTHA/061216; Crtd /date: BAVISH/021210; Custom_Duty: 15%; Customs_HS_Code: 85332119; Distributor_name: DIGIKEY; Distributor_part_number: 311-2.2KJRCT-ND; Footprint Path: Y:\MIS_DATABASE\Library\ALTIUM_TOOL\PCB_FOOTPRINTS\Altium_Footprint_Lib.PcbLib; Height: 0.40MM; Library Path: Y:\MIS_DATABASE\Library\ALTIUM_TOOL\SCHEMATICS_PARTS\MS_DISCRETE_Library.schlib; Mfr_name: YAGEO AMERICA; Mfr_part_number: RC0402JR-072K2L; Mistral Part No: 110010120018-R; Package: 0402; Part_type: RESISTORS\FIXED; Project: TE4; RoHS: RoHS; Temperature: -55°C+155°C; Tolerance: 5%; Voltage: NA; Wattage: 1/16W; Weight: 0.65mg; Datasheet: Y:\MIS_DATABASE\DATASHEETS\RESISTORS\RCXXXXL-SER_MAR18.PDF
R121 R122 = RESISTOR: RES 1K 1/10W 1% 0402; Chkd/date: VASANTHA/281216; Crtd /date: MAZHAR/150506; Custom_Duty: 15%; Customs_HS_Code: 85332119; Distributor_name: DIGIKEY; Distributor_part_number: P1.00KLCT-ND; Footprint Path: Y:\MIS_DATABASE\Library\ALTIUM_TOOL\PCB_FOOTPRINTS\Altium_Footprint_Lib.PcbLib; Height: 0.40MM; Library Path: Y:\MIS_DATABASE\Library\ALTIUM_TOOL\SCHEMATICS_PARTS\MS_DISCRETE_Library.schlib; Mfr_name: PANASONIC-ECG; Mfr_part_number: ERJ-2RKF1001X; Mistral Part No: 110009030411-R; Package: 0402; Part_type: RESISTORS\FIXED; Project: VOCERA; RoHS: RoHS; Temperature: -55°C+155°C; Tolerance: 1%; Voltage: NA; Wattage: 1/10W; Weight: 0.8mg; Datasheet: Y:\MIS_DATABASE\DATASHEETS\RESISTORS\PAN-ERJSER_NOV17.PDF
R395 R397 = RESISTOR: RES 39.2E 1/16W 1% 0402; Chkd/date: RAGESH/210411; Crtd /date: MAZHAR/210411; Custom_Duty: 15%; Customs_HS_Code: 85332119; Distributor_name: DIGIKEY; Distributor_part_number: RMCF0402FT39R2CT-ND; Footprint Path: Y:\MIS_DATABASE\Library\ALTIUM_TOOL\PCB_FOOTPRINTS\Altium_Footprint_Lib.PcbLib; Height: 0.40MM; Library Path: Y:\MIS_DATABASE\Library\ALTIUM_TOOL\SCHEMATICS_PARTS\MS_DISCRETE_Library.schlib; Mfr_name: STACKPOLE ELECTRONICS; Mfr_part_number: RMCF0402FT39R2; Mistral Part No: 110011040030-R; Package: 0402; Part_type: RESISTORS\FIXED; Project: AOD_POD-BASECARD; RoHS: RoHS; Temperature: -55°C+155°C; Tolerance: 1%; Voltage: NA; Wattage: 1/16W; Weight: 0.57mg; Datasheet: Y:\MIS_DATABASE\DATASHEETS\RESISTORS\RMCF-SER_JUL18.PDF
R407 R408 = RESISTOR: RES 1K 1/20W 0.1% 0201; Chkd/date: ALVY/160222; Crtd /date: ALVY/160222; Custom_Duty: 15%; Customs_HS_Code: 85332119; Distributor_name: DIGIKEY; Distributor_part_number: P1.0KBXCT-ND; Footprint Path: Y:\MIS_DATABASE\Library\ALTIUM_TOOL\PCB_FOOTPRINTS\Altium_Footprint_Lib.PcbLib; Height: 0.26MM; Library Path: Y:\MIS_DATABASE\Library\ALTIUM_TOOL\SCHEMATICS_PARTS\MS_DISCRETE_Library.schlib; Mfr_name: PANASONIC-ECG; Mfr_part_number: ERA-1AEB102C; Mistral Part No: 110019050021-R; Package: 0201; Part_type: RESISTORS\FIXED; Project: AM263x_CC_BRD; RoHS: RoHS; Temperature: -55°C+155°C; Tolerance: 0.1%; Voltage: NA; Wattage: 1/20W; Weight: 0.14mg; Datasheet: Y:\MIS_DATABASE\DATASHEETS\RESISTORS\ERA-1A.PDF
U29 = MT40A512M16LY_FBGA96: IC 16Gb DDR4 SDRAM FBGA96; Chkd/date: PRAVEEN/031122; Crtd /date: PRAVEEN/031122; Custom_Duty: 15%; Customs_HS_Code: 85423100; Distributor_name: DIGIKEY; Distributor_part_number: 557-MT40A1G16TB-062EIT:F-ND; Footprint Path: Y:\MIS_DATABASE\Library\ALTIUM_TOOL\PCB_FOOTPRINTS\Altium_Footprint_Lib.PcbLib; Height: 1.20MM; Library Path: Y:\MIS_DATABASE\Library\ALTIUM_TOOL\SCHEMATICS_PARTS\MS_MISCMEMORY_Library.schlib; Mfr_name: MICRON; Mfr_part_number: MT40A1G16TB-062E IT:F; Mistral Part No: 141022110006-R; Package: FBGA96; Part_type: ICS\DIGITAL\MEMORY; Project: AM64x_SK_BRD; RoHS: RoHS; Temperature: -40°C+95°C; Tolerance: NA; Voltage: NA; Wattage: NA; Weight: NA; Datasheet: Y:\MIS_DATABASE\DATASHEETS\ICS\MEMORY\MT40A-SER.PDF
U12 = AM62-EVM_BGA425: IC AM62 SoC MICROPROCESSOR BGA425; Chkd/date: ALVY/110621; Crtd /date: MANIRAJA/110621; Custom_Duty: 15%; Customs_HS_Code: 85423100; Distributor_name: NA; Distributor_part_number: NA; Footprint Path: Y:\MIS_DATABASE\Library\ALTIUM_TOOL\PCB_FOOTPRINTS\Altium_Footprint_Lib.PcbLib; Height: 0.65MM; Library Path: Y:\MIS_DATABASE\Library\ALTIUM_TOOL\SCHEMATICS_PARTS\MS_MICROPROCESSOR_Library.schlib; Mfr_name: TEXAS INSTRUMENTS; Mistral Part No: 141221060001; Package: BGA425; Part_type: ICS\DIGITAL\MICROPROCESSOR; Project: AM62_EVM_BRD; RoHS: NA; Temperature: NA; Tolerance: NA; Voltage: NA; Wattage: NA; Weight: NA; Datasheet: Y:\MIS_DATABASE\DATASHEETS\ICS\DIGITAL\MICROCONTROLLER\AM62-SoC_SVB.PDF

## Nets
DGND: C23.1 C31.2 C34.2 C36.2 C37.1 C40.2 C41.2 C42.2 C44.2 C48.2 C49.2 C51.2 C53.1 C54.2 C55.2 C56.2 C57.2 C74.2 C80.2 C81.2 C82.2 C83.2 C85.2 C88.2 C89.2 C90.2 C97.1 C99.2 C102.1 C106.1 C114.1 C116.2 C118.1 C205.2 C214.2 C215.1 C218.2 C220.2 C221.2 C222.2 C226.2 C233.2 C239.2 C240.2 C241.2 C243.2 C244.2 C245.2 C246.2 C247.2 C249.1 C250.2 C251.2 C252.2 C253.2 C254.2 C255.2 C256.2 C257.2 C258.2 C259.2 C260.2 C261.2 C262.2 C263.2 C264.2 C265.2 C266.2 C267.2 C268.2 C269.2 C270.2 C271.2 C272.2 C273.2 C274.2 C275.2 C276.2 C277.2 C278.2 C279.2 C280.2 C281.2 C282.2 C283.2 C284.2 C285.2 C286.2 C287.2 C288.2 C289.2 C290.2 C291.2 C292.2 C293.2 C294.2 C295.2 C296.2 C297.2 C298.2 C299.2 C300.2 C302.2 C309.2 C310.2 C311.2 C313.2 C314.2 C328.1 C329.2 C332.2 C336.2 C339.2 C340.2 C343.2 C344.2 C346.2 C347.2 C349.2 C350.2 C351.2 C352.1 C354.2 C358.2 C359.2 C362.1 C363.1 C365.2 C493.2 C519.1 R98.2 R108.2 R120.1 R122.1 R135.2 R394.2 R407.2 U8.B3(A0) U8.C1(GND) U12.A1(VSS) U12.A24(VSS) U12.A25(VSS) U12.AA11(VSS) U12.AB9(VSS) U12.AD1(VSS) U12.AD9(VSS) U12.AD12(VSS) U12.AD16(VSS) U12.AD25(VSS) U12.AE1(VSS) U12.AE8(VSS) U12.AE12(VSS) U12.AE16(VSS) U12.AE24(VSS) U12.AE25(VSS) U12.B25(VSS) U12.F13(VSS) U12.G13(VSS) U12.G19(VSS) U12.H13(VSS) U12.H16(VSS) U12.H18(VSS) U12.H20(VSS) U12.J7(VSS) U12.J13(VSS) U12.K7(VSS) U12.K13(VSS) U12.K15(VSS) U12.K19(VSS) U12.L20(VSS) U12.M7(VSS) U12.M8(VSS) U12.M10(VSS) U12.M12(VSS) U12.M13(VSS) U12.M17(VSS) U12.M18(VSS) U12.N15(VSS) U12.P7(VSS) U12.P10(VSS) U12.P13(VSS) U12.R13(VSS) U12.R15(VSS) U12.R18(VSS) U12.R20(VSS) U12.T8(VSS) U12.T13(VSS) U12.T14(VSS) U12.T16(VSS) U12.T17(VSS) U12.T18(VSS) U12.U8(VSS) U12.U19(VSS) U12.V9(VSS) U12.V10(VSS) U12.V11(VSS) U12.V13(VSS) U12.V16(VSS) U12.V18(VSS) U12.W7(VSS) U12.Y2(VSS) U16.C1(GND) U23.C1(GND) U25.C1(GND) U29.A2(VSSQ) U29.A8(VSSQ) U29.B2(VSS) U29.C9(VSSQ) U29.D2(VSSQ) U29.D8(VSSQ) U29.E1(VSS) U29.E3(VSSQ) U29.E8(VSSQ) U29.E9(VSS) U29.F1(VSSQ) U29.G8(VSS) U29.H1(VSSQ) U29.H9(VSSQ) U29.K1(VSS) U29.K9(VSS) U29.M9(VSS) U29.N1(VSS) U29.T1(VSS) U36.C1(GND) U36.C3(A1) U37.B3(A0) U37.C1(GND) U37.C3(A1) ; also on sheet 1 10 11 12 13 18 19 20 21 22 23 24 25 26 27 28 29 30 31 32 33 34 35 36 37 38 39 40 41 42 43
VCC_1V8: C53.2 R70.2 ; also on sheet 12 13 18 19 21 25 34 37 39 40 42
VCC_3V3_MAIN: R375.1 ; also on sheet 12 13 26
VCC_3V3_SYS: C23.2 C74.1 C99.1 C116.1 C205.1 C332.1 C365.1 R48.2 R386.2 U8.B1(VS) U16.B1(VS) U16.B3(A0) U16.C3(A1) U23.B1(VS) U23.B3(A0) U25.B1(VS) U25.C3(A1) U36.B1(VS) U36.B3(A0) U37.B1(VS) ; also on sheet 10 12 13 18 19 20 22 23 24 25 26 27 29 30 31 32 33 34 35 36 37 38 39 40 41 42 43
VCC_CORE: C118.2 R148.2 ; also on sheet 13
VDD_1V2: C114.2 R134.3 ; also on sheet 13 41
VDD_2V5: FL23.1 ; also on sheet 13 23 24
VDD_CANUART: C51.1 C54.1 C57.1 FL18.2 U12.F8(VDD_CANUART)
VDD_CORE: C55.1 C56.1 C80.1 C244.1 C247.1 C250.1 C260.1 C261.1 C262.1 C267.1 C268.1 C273.1 C277.1 C280.1 C291.1 C293.1 C295.1 C309.1 C310.1 C311.1 FL4.1 FL7.1 FL18.1 R148.3 R699.1 U12.H8(VDD_CORE) U12.J11(VDD_CORE) U12.J14(VDD_CORE) U12.K17(VDD_CORE) U12.L12(VDD_CORE) U12.L15(VDD_CORE) U12.M16(VDD_CORE) U12.N8(VDD_CORE) U12.N11(VDD_CORE) U12.N13(VDD_CORE) U12.P17(VDD_CORE) U12.R11(VDD_CORE) U12.R14(VDD_CORE) U12.U12(VDD_CORE) U12.V8(VDD_CORE) U12.V15(VDD_CORE) U12.V17(VDD_CORE)
VDD_DDR4: C81.1 C82.1 C83.1 C85.1 C282.1 C292.1 C313.1 C314.1 C329.1 C336.1 C337.2 C339.1 C340.1 C343.1 C344.1 C346.1 C347.1 C349.1 C350.1 C354.1 C358.1 C359.1 C361.2 R118.2 R119.2 R121.2 R134.2 R408.1 U12.K9(VDDS_DDR) U12.L8(VDDS_DDR) U12.M9(VDDS_DDR_C) U12.P9(VDDS_DDR) U12.R8(VDDS_DDR) U29.A1(VDDQ) U29.A9(VDDQ) U29.B3(VDD) U29.B9(VDD) U29.C1(VDDQ) U29.D1(VDD) U29.D9(VDDQ) U29.F2(VDDQ) U29.F8(VDDQ) U29.G1(VDDQ) U29.G7(VDD) U29.G9(VDDQ) U29.J1(VDD) U29.J2(VDDQ) U29.J8(VDDQ) U29.J9(VDD) U29.L1(VDD) U29.L9(VDD) U29.R1(VDD) U29.T9(VDD)
VDD_LDO2: C106.2 R123.3 ; also on sheet 13
VDDA1V8: C97.2 R106.2 ; also on sheet 13
VDDA_1V8: C493.1 FL3.1 FL5.1 FL6.1 FL9.1 FL13.1 FL16.1 FL19.1 R106.3 TP36.1(TP) U12.G7(VDDS_OSC0) U12.G16(VDDA_TEMP1) U12.T9(VDDA_TEMP0)
VDDA_1V8_CSIRX: C41.1 C243.1 C270.1 FL3.2 U12.W14(VDDA_1P8_CSIRX0)
VDDA_1V8_MCU: C88.1 C89.1 C90.1 FL9.2 U12.L11(VDDA_MCU)
VDDA_1V8_OLDI: C284.1 C285.1 C290.1 FL5.2 U12.W9(VDDA_1P8_OLDI0) U12.W10(VDDA_1P8_OLDI0)
VDDA_1V8_USB: C287.1 C297.1 C298.1 FL6.2 U12.Y11(VDDA_1P8_USB)
VDDA_CORE_CSI: C48.1 C275.1 C281.1 FL4.2 U12.W13(VDDA_CORE_CSIRX0)
VDDA_CORE_USB: C49.1 C283.1 C289.1 FL7.2 U12.W12(VDDA_CORE_USB)
VDDA_PLL0: C245.1 C246.1 C288.1 FL16.2 U12.U11(VDDA_PLL0)
VDDA_PLL1: C220.1 C221.1 C222.1 FL13.2 U12.U15(VDDA_PLL1)
VDDA_PLL2: C296.1 C299.1 C300.1 FL19.2 U12.L14(VDDA_PLL2)
VDDA_SYS_MON: C519.2 R108.1 R375.2 U12.H10(VMON_ER_VSYS)
VDDR_CORE: C214.1 C215.2 C240.1 C241.1 C264.1 C271.1 C274.1 C279.1 R123.2 R699.2 TP39.1(TP) U12.J12(VDDR_CORE) U12.K16(VDDR_CORE) U12.N12(VDDR_CORE) U12.N14(VDDR_CORE) U12.P16(VDDR_CORE) U12.R12(VDDR_CORE) U12.T10(VDDR_CORE) U12.U14(VDDR_CORE)
VDDSHV_SDIO: FL14.1 ; also on sheet 13 20
CAP_VDDS0: C269.1 U12.H15(CAP_VDDS0)
CAP_VDDS1: C257.1 U12.K18(CAP_VDDS1)
CAP_VDDS2: C256.1 U12.W17(CAP_VDDS2)
CAP_VDDS3: C251.1 U12.P19(CAP_VDDS3)
CAP_VDDS4: C302.1 U12.U7(CAP_VDDS4)
CAP_VDDS5: C258.1 U12.H17(CAP_VDDS5)
CAP_VDDS6: C239.1 U12.J19(CAP_VDDS6)
CAP_VDDS_CANUART: C294.1 U12.G9(CAP_VDDS_CANUART)
CAP_VDDS_MCU: C276.1 U12.H11(CAP_VDDS_MCU)
DDR_A0: U12.J1(DDR0_A0) U29.P3(A0)
DDR_A1: U12.J2(DDR0_A1) U29.P7(A1)
DDR_A2: U12.K3(DDR0_A2) U29.R3(A2)
DDR_A3: U12.L5(DDR0_A3) U29.N7(A3)
DDR_A4: U12.K4(DDR0_A4) U29.N3(A4)
DDR_A5: U12.K1(DDR0_A5) U29.P8(A5)
DDR_A6: U12.R2(DDR0_A6) U29.P2(A6)
DDR_A7: U12.P2(DDR0_A7) U29.R8(A7)
DDR_A8: U12.P1(DDR0_A8) U29.R2(A8)
DDR_A9: U12.P4(DDR0_A9) U29.R7(A9)
DDR_A10: U12.R5(DDR0_A10) U29.M3(A10/AP)
DDR_A11: U12.P5(DDR0_A11) U29.T2(A11)
DDR_A12: U12.R6(DDR0_A12) U29.M7(A12/BC_N)
DDR_A13: U12.R1(DDR0_A13) U29.T8(A13)
DDR_A14_WEn: U12.N3(DDR0_WE_N) U29.L2(WE_N/A14)
DDR_A15_CAS: U12.M4(DDR0_CAS_N) U29.M8(CAS_N/A15)
DDR_A16_RAS: U12.M5(DDR0_RAS_N) U29.L8(RAS_N/A16)
DDR_ACTn: U12.N6(DDR0_ACT_N) U29.L3(ACT_N)
DDR_ALERTn: R118.1 U12.R3(DDR0_ALERT_N) U29.P9(ALERT_N)
DDR_BA0: U12.M1(DDR0_BA0) U29.N2(BA0)
DDR_BA1: U12.N1(DDR0_BA1) U29.N8(BA1)
DDR_BG0: U12.T4(DDR0_BG0) U29.M2(BG0)
DDR_CKE: R394.1 U12.H2(DDR0_CKE0) U29.K2(CKE)
DDR_CLKN: R395.1 U12.L2(DDR0_CK0_N) U29.K8(CK_C)
DDR_CLKP: R397.1 U12.L1(DDR0_CK0) U29.K7(CK_T)
DDR_CSn: U12.L6(DDR0_CS0_N) U29.L7(CS_N)
DDR_DQ0: U12.F4(DDR0_DQ0) U29.G2(DQ0)
DDR_DQ1: U12.H6(DDR0_DQ3) U29.F7(DQ1)
DDR_DQ2: U12.E3(DDR0_DQ4) U29.H3(DQ2)
DDR_DQ3: U12.F3(DDR0_DQ2) U29.H7(DQ3)
DDR_DQ4: U12.F1(DDR0_DQ7) U29.H2(DQ4)
DDR_DQ5: U12.G5(DDR0_DQ1) U29.H8(DQ5)
DDR_DQ6: U12.G2(DDR0_DQ5) U29.J3(DQ6)
DDR_DQ7: U12.F2(DDR0_DQ6) U29.J7(DQ7)
DDR_DQ8: U12.U1(DDR0_DQ8) U29.A3(DQ8)
DDR_DQ9: U12.U3(DDR0_DQ9) U29.B8(DQ9)
DDR_DQ10: U12.U2(DDR0_DQ10) U29.C3(DQ10)
DDR_DQ11: U12.V5(DDR0_DQ11) U29.C7(DQ11)
DDR_DQ12: U12.W2(DDR0_DQ12) U29.C2(DQ12)
DDR_DQ13: U12.V6(DDR0_DQ13) U29.C8(DQ13)
DDR_DQ14: U12.Y1(DDR0_DQ14) U29.D3(DQ14)
DDR_DQ15: U12.W1(DDR0_DQ15) U29.D7(DQ15)
DDR_LDM: U12.H5(DDR0_DM0) U29.E7(NF/LDM_N/LDBI_N)
DDR_LDQS_N: U12.E2(DDR0_DQS0_N) U29.F3(LDQS_C)
DDR_LDQS_P: U12.E1(DDR0_DQS0) U29.G3(LDQS_T)
DDR_ODT: U12.H1(DDR0_ODT0) U29.K3(ODT)
DDR_PARITY: U12.T1(DDR0_PAR) U29.T3(PAR)
DDR_RESET#: R119.1 R120.2 U12.G1(DDR0_RESET0_N) U29.P1(RESET_N)
DDR_TEN: R121.1 R122.2 U29.N9(TEN)
DDR_UDM: U12.W5(DDR0_DM1) U29.E2(NF/UDM_N/UDBI_N)
DDR_UDQS_N: U12.V2(DDR0_DQS1_N) U29.A7(UDQS_C)
DDR_UDQS_P: U12.V1(DDR0_DQS1) U29.B7(UDQS_T)
DDR_VPP: C328.2 C351.1 C352.2 FL23.2 U29.B1(VPP) U29.R9(VPP)
DDR_VREFCA: C102.2 C361.1 C362.2 C363.2 R407.1 R408.2 TP43.1(TP) U29.M1(VREFCA)
INA_ALERT: R93.2 R110.2 R113.2 R146.2 R154.2 R290.2 R386.1 TP37.1(TP)
SOC_DVDD1V8: C36.1 C37.2 C40.1 C233.1 C252.1 C253.1 R70.3 U12.G10(VMON_1P8_SOC) U12.J18(VDDSHV6) U12.L18(VDDSHV1) U12.M19(VDDSHV1) U12.T7(VDDSHV4)
SoC_DVDD3V3: C31.1 C34.1 C42.1 C44.1 C218.1 C226.1 C249.2 C254.1 C255.1 C259.1 C265.1 C266.1 C272.1 C278.1 C286.1 R48.3 U12.F11(VDDSHV_MCU) U12.F15(VDDSHV0) U12.G12(VDDSHV_MCU) U12.G14(VDDSHV0) U12.H9(VDDSHV_CANUART) U12.K10(VMON_3P3_SOC) U12.N18(VDDSHV3) U12.P18(VDDSHV3) U12.T19(VDDSHV3) U12.U18(VDDSHV3) U12.W16(VDDSHV2) U12.W19(VDDSHV2) U12.Y13(VDDA_3P3_USB)
SOC_I2C1_SCL: U8.A1(SCL) U8.C3(A1) U16.A1(SCL) U23.A1(SCL) U23.C3(A1) U25.A1(SCL) U25.B3(A0) U36.A1(SCL) U37.A1(SCL) ; also on sheet 22 26 39 40 41 42
SOC_I2C1_SDA: U8.A2(SDA) U16.A2(SDA) U23.A2(SDA) U25.A2(SDA) U36.A2(SDA) U37.A2(SDA) ; also on sheet 22 26 39 40 41 42
SoC_VDDSHV5_SDIO: C263.1 FL14.2 U12.G17(VDDSHV5)
TEMP_DIODE_P: TP122.1(TP) U12.E7(RSVD8)
VPP_1V8: U12.J8(VPP) ; also on sheet 12
N15835426: R135.1 U29.F9(ZQ)
N15835430: TP35.1(TP) U29.T7(NF/NC)
N16839912: C64.1 R78.1 U16.D3(IN+)
N16839940: C96.1 R109.1 U23.D3(IN+)
N16839975: C103.1 R125.1 U25.D3(IN+)
N16887346: R98.1 U12.M2(DDR0_CAL0)
N17010152: C337.1 R395.2 R397.2
N17153379: R148.1 R155.2
N17153381: R148.4 R149.2
N17153415: R123.4 R147.2
N17153417: R123.1 R145.2
N17153507: R33.2 R48.1
N17153509: R37.2 R48.4
N17153511: C18.2 R37.1 U8.D1(BUS) U8.D2(IN-)
N17153515: C18.1 R33.1 U8.D3(IN+)
N17153617: R70.1 R78.2
N17153619: R70.4 R79.2
N17153623: R106.1 R109.2
N17153625: R106.4 R115.2
N17153667: R125.2 R134.4
N17153669: R124.2 R134.1
N17153681: C121.1 R155.1 U37.D3(IN+)
N17153685: C121.2 R149.1 U37.D1(BUS) U37.D2(IN-)
N17153701: C119.2 R145.1 U36.D1(BUS) U36.D2(IN-)
N17153703: C119.1 R147.1 U36.D3(IN+)
N17153749: C64.2 R79.1 U16.D1(BUS) U16.D2(IN-)
N17153787: C96.2 R115.1 U23.D1(BUS) U23.D2(IN-)
N17153799: C103.2 R124.1 U25.D1(BUS) U25.D2(IN-)
N17153878: R146.1 U36.A3(ALERT)
N17153949: R93.1 U16.A3(ALERT)
N17153951: R110.1 U23.A3(ALERT)
N17154063: R113.1 U25.A3(ALERT)
N18516151: R154.1 U37.A3(ALERT)
N18520654: R290.1 U8.A3(ALERT)

Not connected (* = marked no-connect by the designer): U8 B2(NC1)* C2(NC2)*; U12 J3(DDR0_ODT1)* J4(DDR0_CKE1)* K2(DDR0_CS1_N)* N2(DDR0_BG1)* T2(RSVD4)* U4(RSVD5)*; U16 B2(NC1)* C2(NC2)*; U23 B2(NC1)* C2(NC2)*; U25 B2(NC1)* C2(NC2)*; U36 B2(NC1)* C2(NC2)*; U37 B2(NC1)* C2(NC2)*

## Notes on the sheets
sheet 14
- CURRENT MONITORING DEVICES
- VDD_CORE
- SoC_DVDD1V8
- I2C ADDRESS: 0x40
- I2C ADDRESS: 0x45
- VDDR_CORE
- VDDA_1V8
- I2C ADDRESS: 0x4D
- I2C ADDRESS: 0x41
- SoC_DVDD3V3
- VDD_DDR4
- I2C ADDRESS: 0x4C
- I2C ADDRESS: 0x47
- RES Option to short VDD_CORE and VDDR_CORE rails when both
  are 0.85V(Both should be generated from the same source)
- INA I2C SLAVE ADDRESS
- SLAVE
  ADDRESS
  (IN HEX)
- POWER SOURCE
- SUPPLY NET
- VCC_CORE
- VDD_CORE
- 40
- VCC_3V3_SYS
- SoC_DVDD3V3
- 4C
- VCC_1V8
- SoC_DVDD1V8
- 45
- VDDA1V8
- VDDA_1V8
- 4D
- CORE SUPPLY
- ARRAY CORE SUPPLY
- Assembly
- 0.75 VDD_CORE
- 0.85 VDDR_CORE
- DNI R699 and Mount R123
- VCC1V2_DDR
- VDD_DDR4
- 47
- 0.85 VDD_CORE
- 0.85 VDDR_CORE
- DNI R123 and Mount R699
sheet 15
- SOC POWER
- Internal purpose only
- Reserved pin
- 1.8V Analog SUPPLY
- CORE SUPPLY
- 3.3V/1.8V MMC1 SUPPLY
sheet 16
- SOC POWER DECAPS
- Place one 0.1uF cap near each Pin
- Place one 0.1uF cap near each Pin
- Place one 0.1uF cap near each Pin
- Place one 0.1uF cap near each Pin
- Place one 0.1uF cap near each Pin
- SOC VSS
sheet 17
- SOC DDR INTERFACE
- NOTE: DDR DQ Lines Swapped
  Within Data Byte
- DDR Signals Voltage level - 1.2V
- Reserved Pins
- DDR4 DEVICE
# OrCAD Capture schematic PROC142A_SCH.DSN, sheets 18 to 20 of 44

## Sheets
18 17. M.2 INTERFACE: size C; title: M.2 CONNECTOR
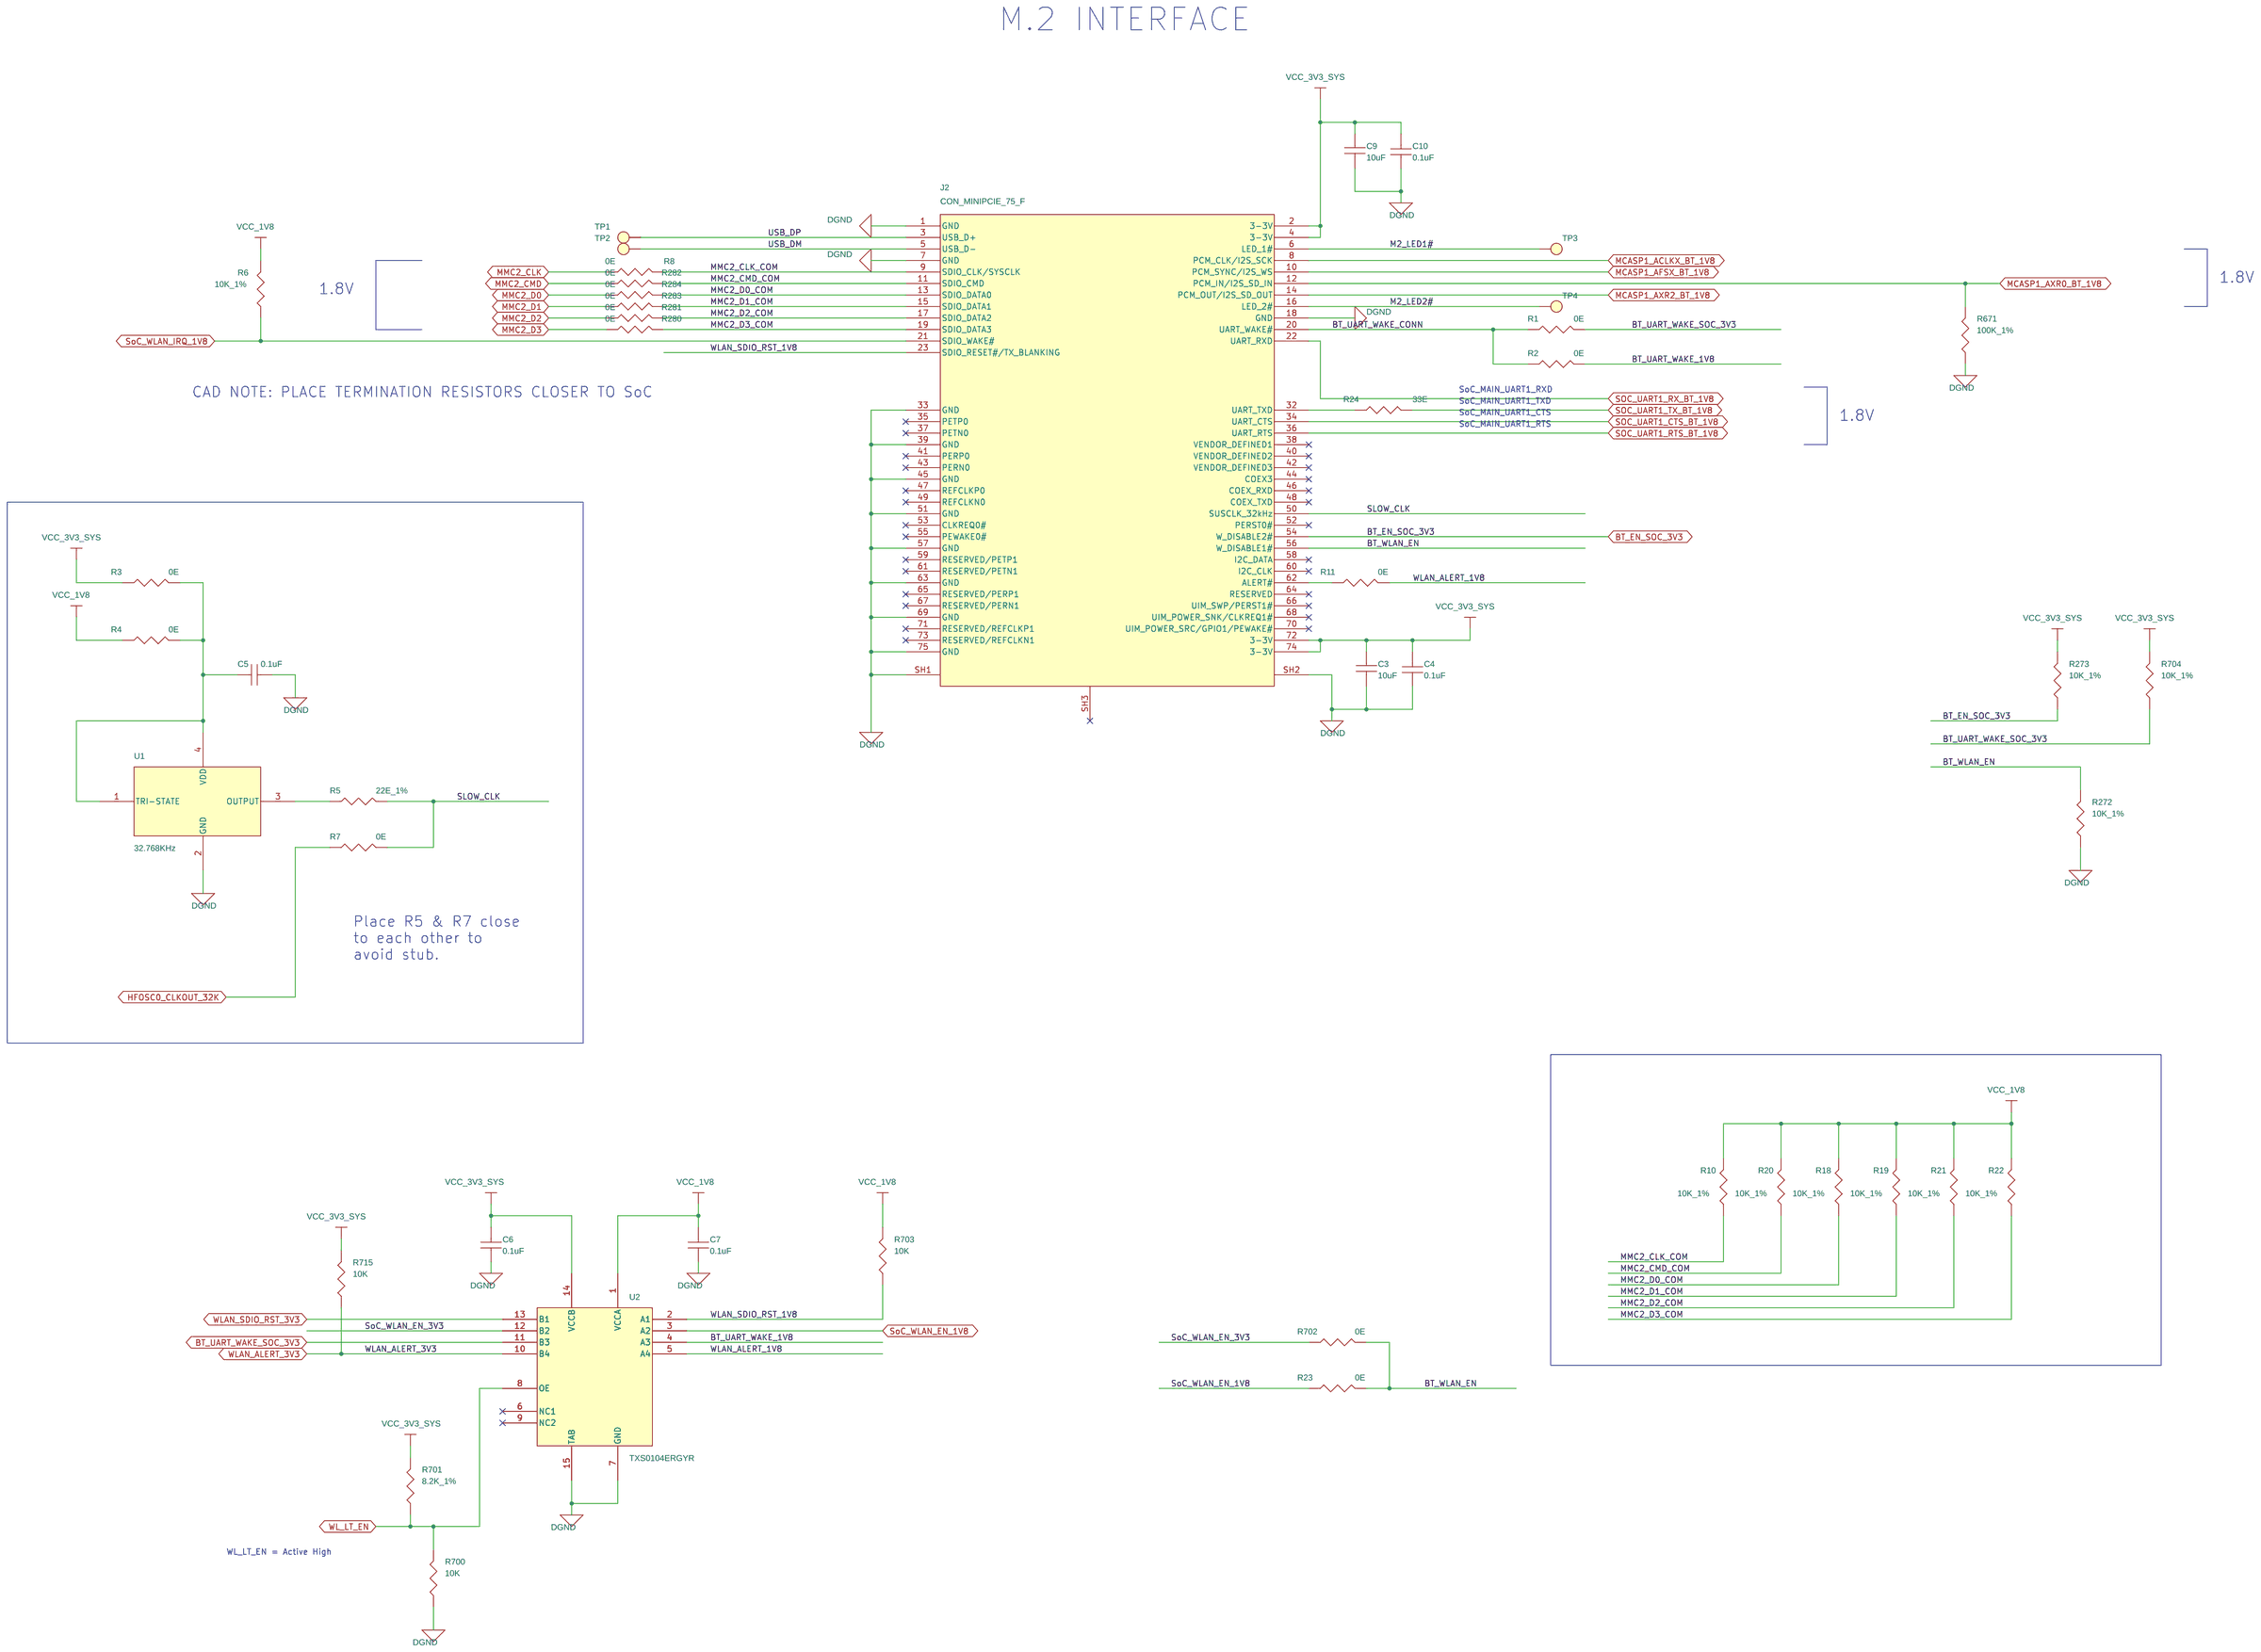
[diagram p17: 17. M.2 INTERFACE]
19 18. eMMC FLASH: size C; title: eMMC FLASH INTERFACE
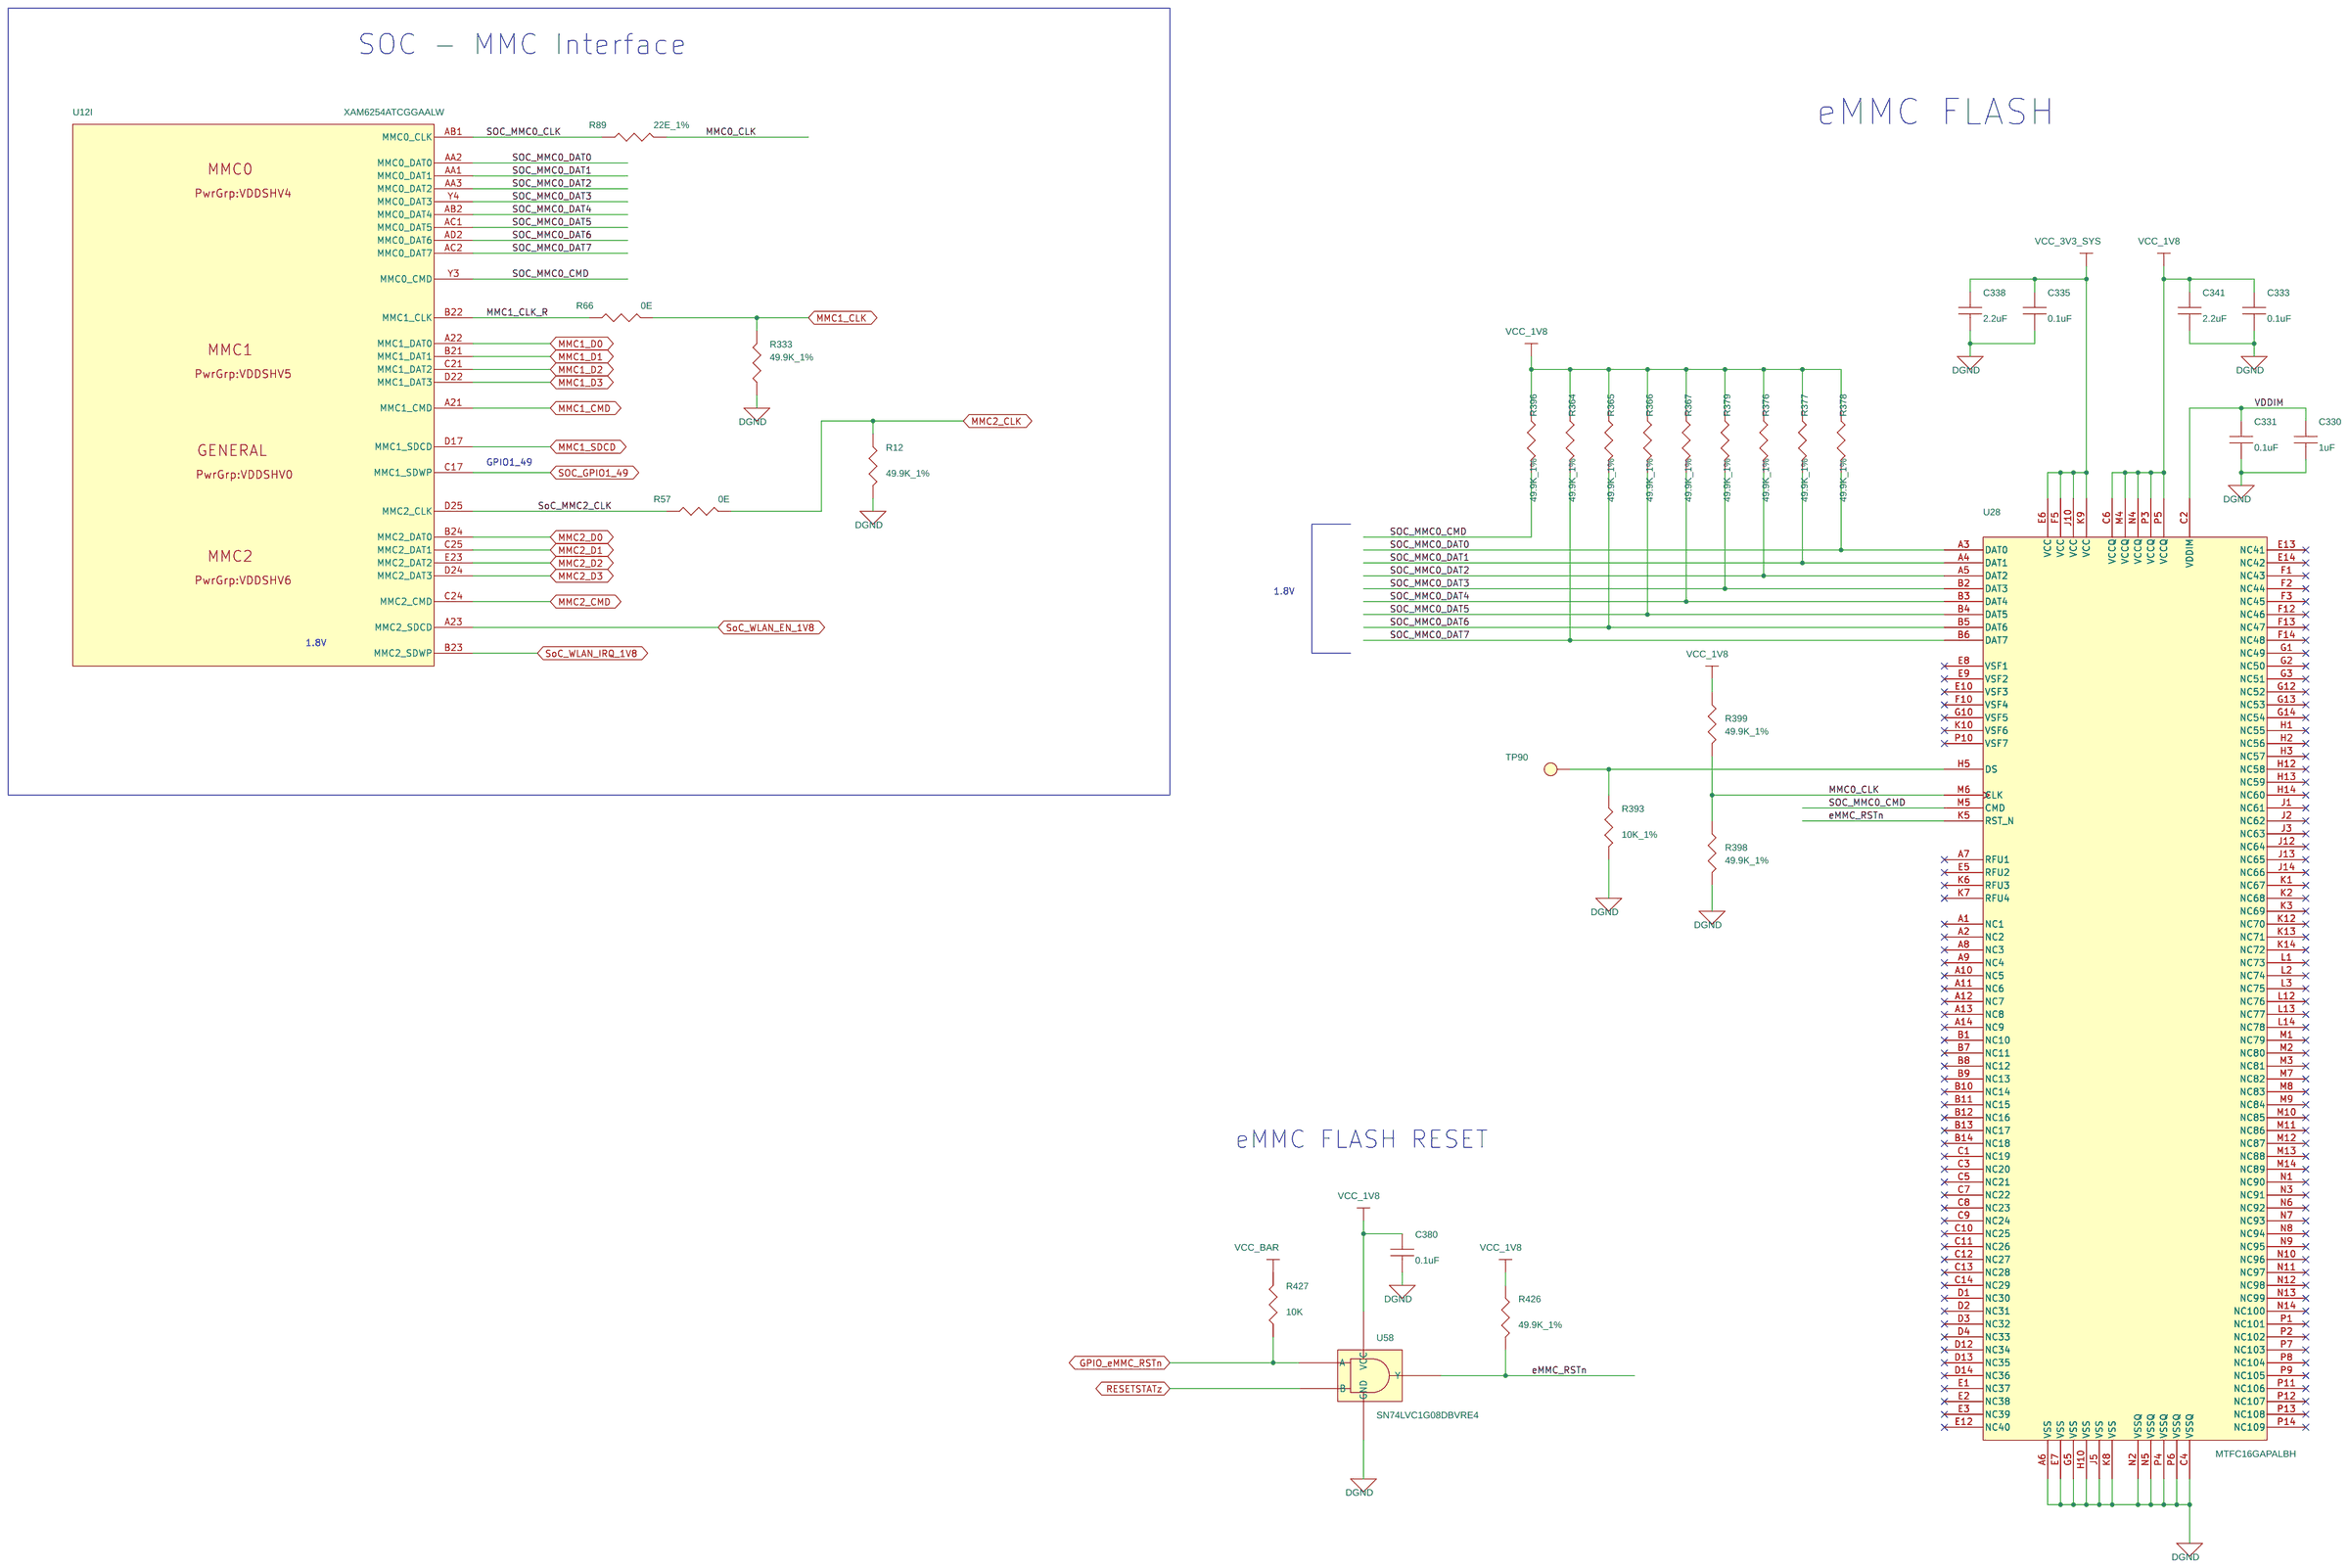
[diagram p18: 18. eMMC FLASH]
20 19. SD CARD INTERFACE: size C; title: SD CARD INTERFACE

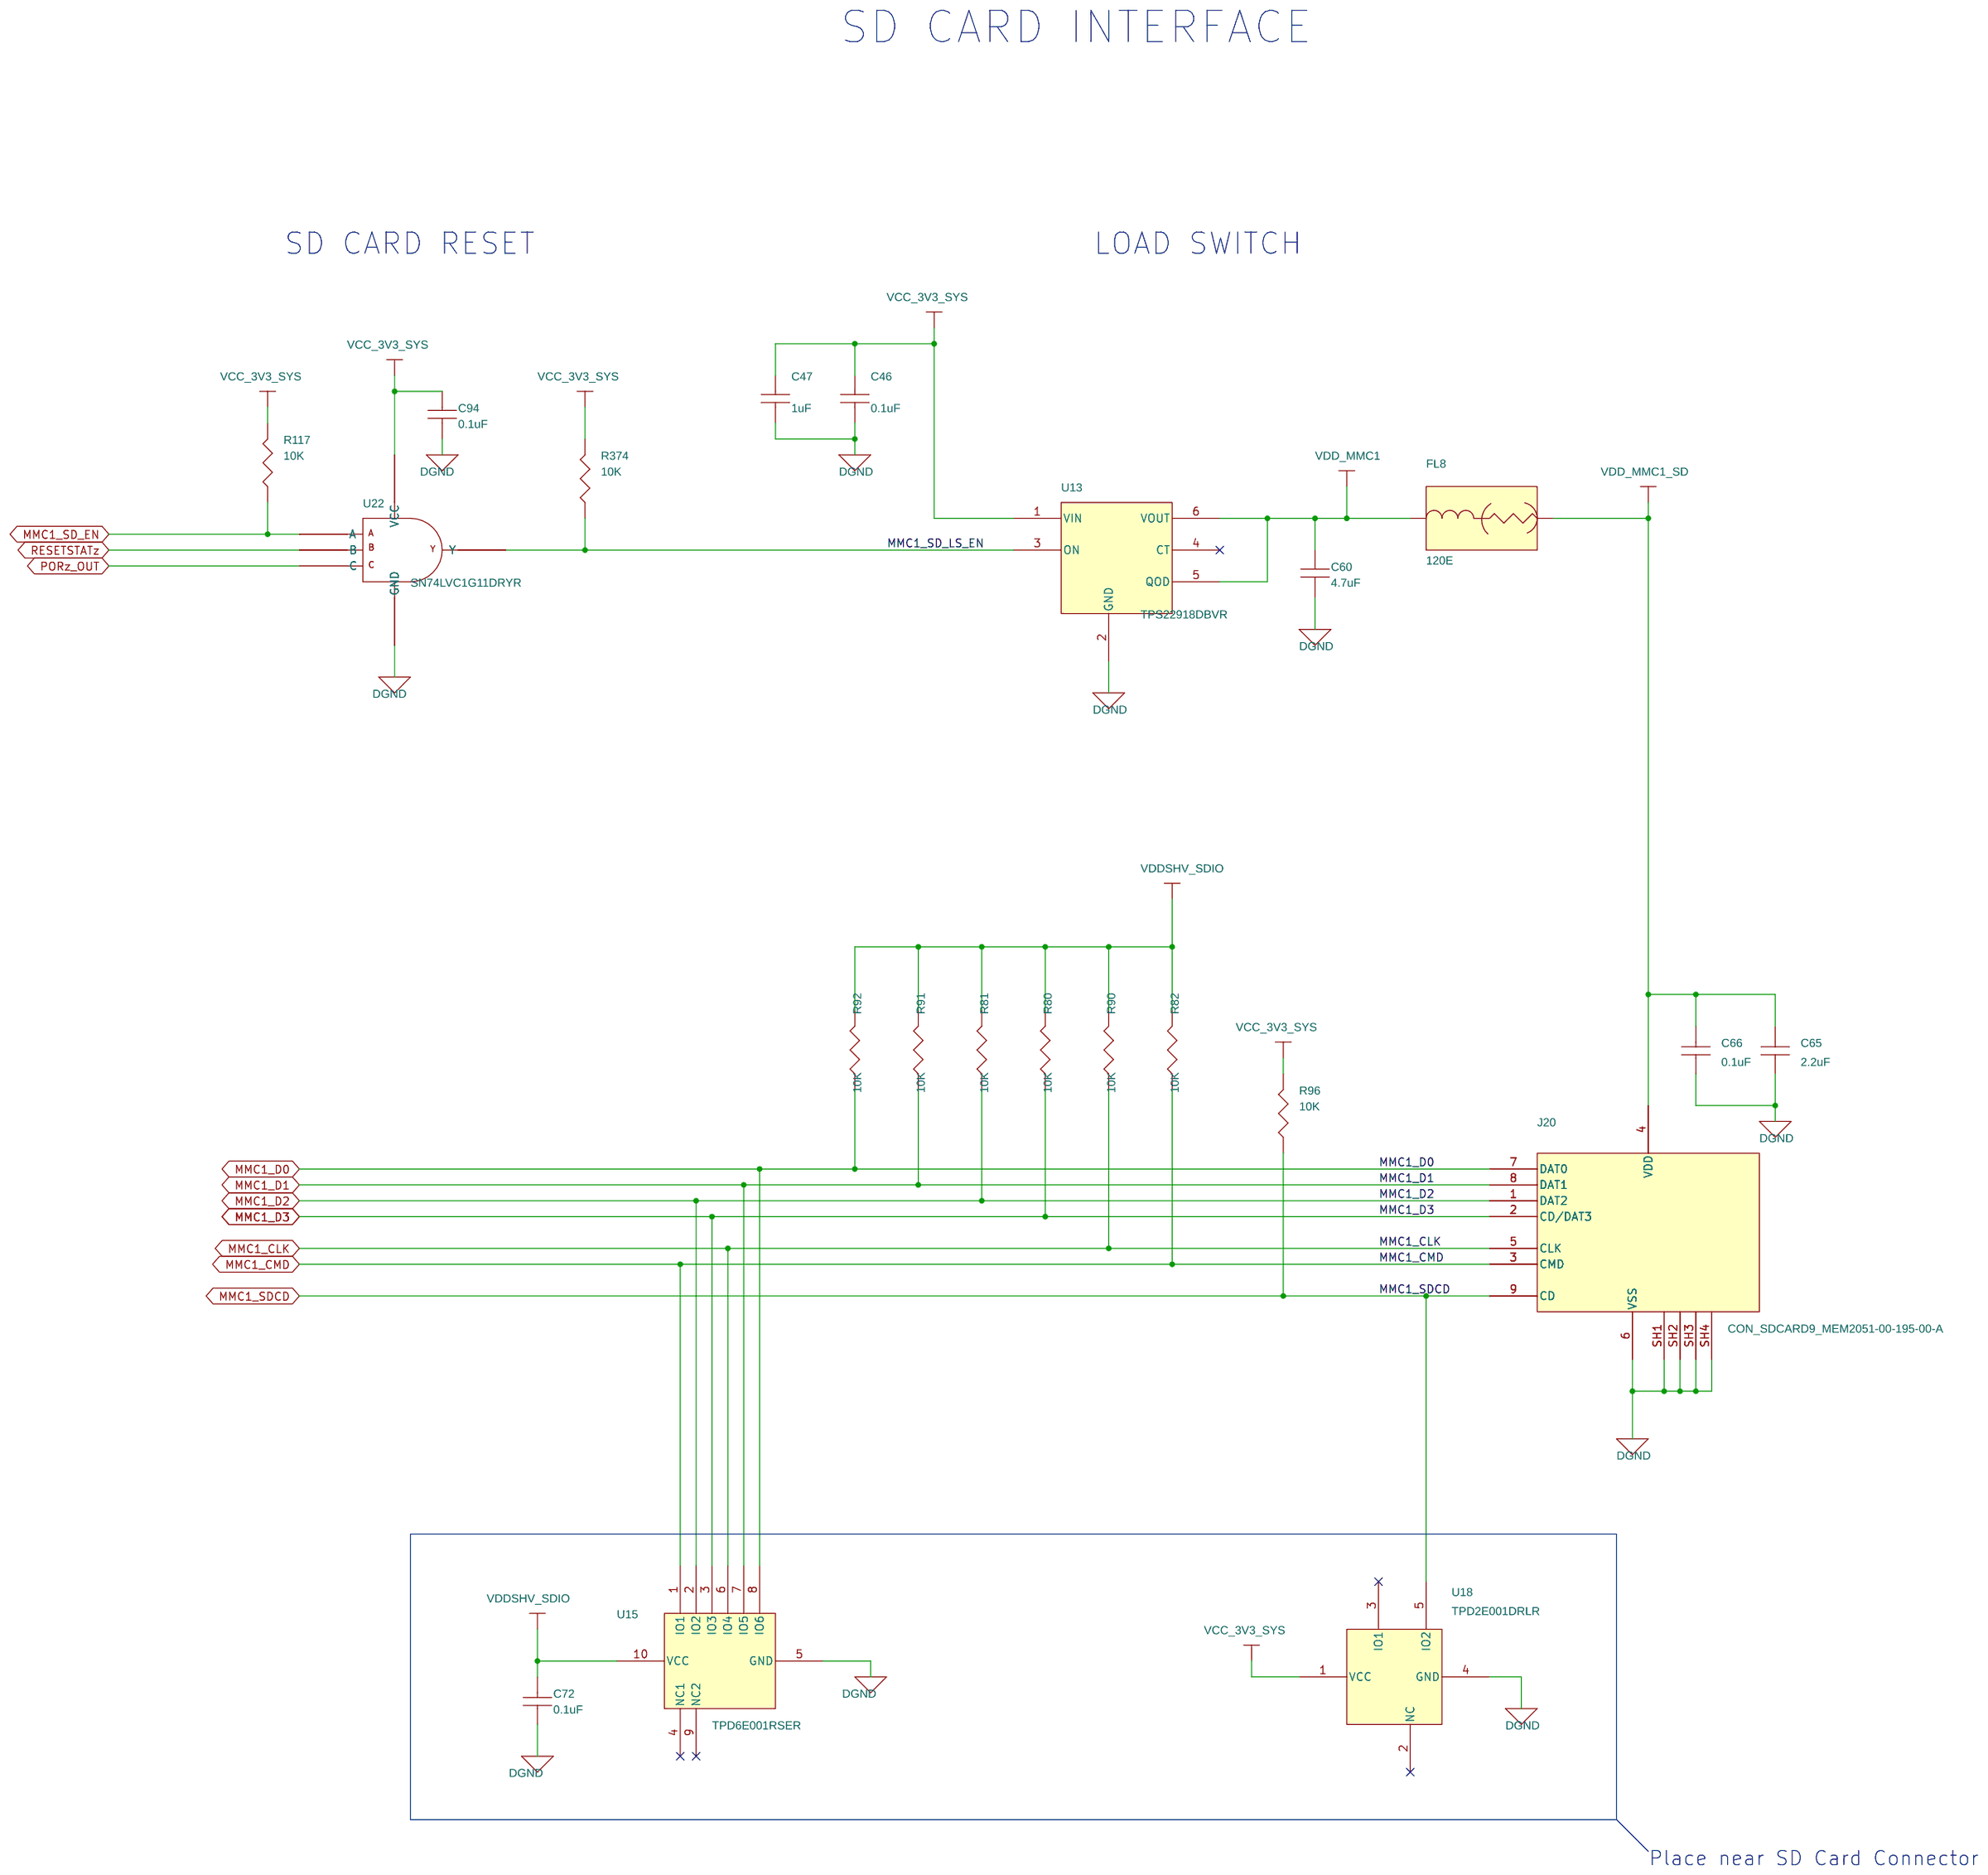
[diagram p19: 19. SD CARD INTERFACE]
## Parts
sheet 17. M.2 INTERFACE
C3  10uF  [CAP0402_0-75]
C4  0.1uF  [CAP0201_0-5]
C5  0.1uF  [CAP0201_0-5]
C6  0.1uF  [CAP0201_0-5]
C7  0.1uF  [CAP0201_0-5]
C9  10uF  [CAP0402_0-75]
C10  0.1uF  [CAP0201_0-5]
J2  CON_MINIPCIE_75_F  [CON_MINIPCI75_2199119-4_S_R_S_3-2_2230]
R1  0E  [RES0201_0-5]
R2  0E  [RES0201_0-5]
R3  0E  [RES0201_0-5]
R4  0E  [RES0201_0-5]
R5  22E_1%  [RES0201_0-5]
R6  10K_1%  [RES0201_0-5]
R7  0E  [RES0201_0-5]
R8  0E  [RES0402_0-5]
R10  10K_1%  [RES0201_0-5]
R11  0E  [RES0201_0-5]
R18  10K_1%  [RES0201_0-5]
R19  10K_1%  [RES0201_0-5]
R20  10K_1%  [RES0201_0-5]
R21  10K_1%  [RES0201_0-5]
R22  10K_1%  [RES0201_0-5]
R23  0E  [RES0201_0-5]
R24  33E  [RES0201_0-5]
R272  10K_1%  [RES0201_0-5]
R273  10K_1%  [RES0201_0-5]
R280  0E  [RES0402_0-5]
R281  0E  [RES0402_0-5]
R282  0E  [RES0402_0-5]
R283  0E  [RES0402_0-5]
R284  0E  [RES0402_0-5]
R671  100K_1%  [RES0402_0-5]
R700  10K  [RES0201_0-5]
R701  8.2K_1%  [RES0201_0-5]
R702  0E  [RES0201_0-5]
R703  10K  [RES0201_0-5]
R704  10K_1%  [RES0201_0-5]
R715  10K  [RES0201_0-5]
TP1  TP20_SMD  [TP20_SMD]
TP2  TP20_SMD  [TP20_SMD]
TP3  TP20_SMD  [TP20_SMD]
TP4  TP20_SMD  [TP20_SMD]
U1  32.768KHz  [OSC4_ASDK_105X85_SMD]
U2  TXS0104ERGYR  [QFN14_19-68_145X145]
sheet 18. eMMC FLASH
C330  1uF  [CAP0201_0-5]
C331  0.1uF  [CAP0402_0-75]
C333  0.1uF  [CAP0402_0-75]
C335  0.1uF  [CAP0402_0-75]
C338  2.2uF  [CAP0402_0-75]
C341  2.2uF  [CAP0402_0-75]
C380  0.1uF  [CAP0402_0-75]
R12  49.9K_1%  [RES0402_0-5]
R57  0E  [RES0201_0-5]
R66  0E  [RES0201_0-5]
R89  22E_1%  [RES0201_0-5]
R333  49.9K_1%  [RES0402_0-5]
R364  49.9K_1%  [RES0201_0-5]
R365  49.9K_1%  [RES0201_0-5]
R366  49.9K_1%  [RES0201_0-5]
R367  49.9K_1%  [RES0201_0-5]
R376  49.9K_1%  [RES0201_0-5]
R377  49.9K_1%  [RES0201_0-5]
R378  49.9K_1%  [RES0201_0-5]
R379  49.9K_1%  [RES0201_0-5]
R393  10K_1%  [RES0201_0-5]
R396  49.9K_1%  [RES0201_0-5]
R398  49.9K_1%  [RES0402_0-5]
R399  49.9K_1%  [RES0402_0-5]
R426  49.9K_1%  [RES0402_0-5]
R427  10K  [RES0201_0-5]
TP90  TP20_SMD  [TP20_SMD]
U28  MTFC16GAPALBH  [VFBGA153_19-68_460X520_1-1]
U58  SN74LVC1G08DBVRE4  [SOT23-5]
sheet 19. SD CARD INTERFACE
C46  0.1uF  [CAP0402_0-75]
C47  1uF  [CAP0201_0-5]
C60  4.7uF  [CAP0402_0-75]
C65  2.2uF  [CAP0402_0-75]
C66  0.1uF  [CAP0402_0-75]
C72  0.1uF  [CAP0402_0-75]
C94  0.1uF  [CAP0402_0-75]
FL8  120E  [EMIFIL_BLM15A_0402_0-6]
J20  CON_SDCARD9_MEM2051-00-195-00-A  [CON_SD9_MEM2051-00-195-00_S_R_S_2-1]
R80  10K  [RES0201_0-5]
R81  10K  [RES0201_0-5]
R82  10K  [RES0201_0-5]
R90  10K  [RES0201_0-5]
R91  10K  [RES0201_0-5]
R92  10K  [RES0201_0-5]
R96  10K  [RES0201_0-5]
R117  10K  [RES0201_0-5]
R374  10K  [RES0201_0-5]
U13  TPS22918DBVR  [SOT23-6]
U15  TPD6E001RSER  [UQFN10_19-68_80X60_0-6]
U18  TPD2E001DRLR  [SOT553-5_0-6]
U22  SN74LVC1G11DRYR  [SON6_SN74LVC2G17_40X60_0-6]
sheet 29. JTAG BUFFER
U12  XAM6254ATCGGAALW  [BGA425_19-68_510X510_0-7]  (sections A,B,C,D,E,F,G,H,I,J,K,L,M,N,O,P,Q,R)

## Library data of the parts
C3 C9 = CAP: CAP CERAMIC 10uF 10V 20% X5R 0402; Chkd/date: MANIRAJA/300520; Crtd /date: ALVY/260520; Custom_Duty: 15%; Customs_HS_Code: 85322990; Distributor_name: DIGIKEY; Distributor_part_number: 490-GRM155R61A106ME11DTR-ND; Footprint Path: Y:\MIS_DATABASE\Library\ALTIUM_TOOL\PCB_FOOTPRINTS\Altium_Footprint_Lib.PcbLib; Height: 0.55MM; Library Path: Y:\MIS_DATABASE\Library\ALTIUM_TOOL\SCHEMATICS_PARTS\MS_DISCRETE_Library.schlib; Mfr_name: MURATA; Mfr_part_number: GRM155R61A106ME11D; Mistral Part No: 120013110019-R; Package: 0402; Part_type: CAPACITORS\CERAMIC; Project: QCS610_NANOSOM; RoHS: RoHS; Temperature: -55°C+85°C; Tolerance: 20%; Voltage: 10V; Wattage: NA; Weight: 3.1mg; Datasheet: Y:\MIS_DATABASE\DATASHEETS\CAPACITORS\MURATA-GXX-SER_NOV17.PDF
C4-C7 C10 = CAP: CAP CERAMIC 0.1uF 16V 10% X5R 0201; Alt_Mfr_name: YAGEO AMERICA; Alt_Mfr_part_number: CC0402KRX5R8BB104; Chkd/date: MANIRAJA/230118; Crtd /date: MANIRAJA/230118; Custom_Duty: 15%; Customs_HS_Code: 85322990; Distributor_name: DIGIKEY; Distributor_part_number: 490-14305-1-ND; Footprint Path: Y:\MIS_DATABASE\Library\ALTIUM_TOOL\PCB_FOOTPRINTS\Altium_Footprint_Lib.PcbLib; Height: 0.33MM; Library Path: Y:\MIS_DATABASE\Library\ALTIUM_TOOL\SCHEMATICS_PARTS\MS_DISCRETE_Library.schlib; Mfr_name: MURATA; Mfr_part_number: GRM033R61C104KE14D; Mistral Part No: 120009030072-R; Package: 0201; Part_type: CAPACITORS\CERAMIC; Project: TI_MAXIE_CPB; RoHS: RoHS; Temperature: -55°C+85°C; Tolerance: 10%; Voltage: 16V; Wattage: NA; Weight: 0.33mg; Datasheet: Y:\MIS_DATABASE\DATASHEETS\CAPACITORS\GRM033R61C104KE14.PDF
J2 = CON_PCI_75_2199119-4_2230: CON MINIPCI 75POS 0.50MM PITCH FEMALE RT SMD; Chkd/date: ALVY/300521; Crtd /date: ALVY/300521; Custom_Duty: 24%; Customs_HS_Code: 85369090; Distributor_name: DIGIKEY; Distributor_part_number: A115900CT-ND; Footprint Path: Y:\MIS_DATABASE\Library\ALTIUM_TOOL\PCB_FOOTPRINTS\Altium_Footprint_Lib.PcbLib; Height: 3.20MM; Library Path: Y:\MIS_DATABASE\Library\ALTIUM_TOOL\SCHEMATICS_PARTS\MS_CONNECTOR_Library.schlib; Mfr_name: TE CONNECTIVITY; Mfr_part_number: 2199119-4_2230; Mistral Part No: 150021030016-R; Package: SMD; Part_type: CONNECTOR\PCI; Project: VOLTA_CHARGER V5; RoHS: RoHS; Temperature: -40°C+80°C; Tolerance: NA; Voltage: NA; Wattage: NA; Weight: 506mg; Datasheet: Y:\MIS_DATABASE\DATASHEETS\CONNECTORS\2199119.PDF
R1-R4 R7 R11 R23 R702 = RESISTOR: RES 0E 1/20W 5% 0201; Chkd/date: NAVEED/301214; Crtd /date: MUDDU/120710; Custom_Duty: 15%; Customs_HS_Code: 85332119; Distributor_name: DIGIKEY; Distributor_part_number: 311-0.0NCT-ND; Footprint Path: Y:\MIS_DATABASE\Library\ALTIUM_TOOL\PCB_FOOTPRINTS\Altium_Footprint_Lib.PcbLib; Height: 0.26MM; Library Path: Y:\MIS_DATABASE\Library\ALTIUM_TOOL\SCHEMATICS_PARTS\MS_DISCRETE_Library.schlib; Mfr_name: YAGEO AMERICA; Mfr_part_number: RC0201JR-070RL; Mistral Part No: 110010070067-R; Package: 0201; Part_type: RESISTORS\FIXED; Project: PB_BUGBASE; RoHS: RoHS; Temperature: -55°C+125°C; Tolerance: 5%; Voltage: NA; Wattage: 1/20W; Weight: 0.17mg; Datasheet: Y:\MIS_DATABASE\DATASHEETS\RESISTORS\RCXXXXL-SER_MAR18.PDF
R5 = RESISTOR: RES 22E 1/20W 1% 0201; Chkd/date: MAZHAR/140709; Crtd /date: MAZHAR/220807; Custom_Duty: 15%; Customs_HS_Code: 85332119; Distributor_name: DIGIKEY; Distributor_part_number: P22.0ABCT-ND; Footprint Path: Y:\MIS_DATABASE\Library\ALTIUM_TOOL\PCB_FOOTPRINTS\Altium_Footprint_Lib.PcbLib; Height: 0.26MM; Library Path: Y:\MIS_DATABASE\Library\ALTIUM_TOOL\SCHEMATICS_PARTS\MS_DISCRETE_Library.schlib; Mfr_name: PANASONIC-ECG; Mfr_part_number: ERJ-1GEF22R0C; Mistral Part No: 110009030522-R; Package: 0201; Part_type: RESISTORS\FIXED; Project: V8TS; RoHS: RoHS; Temperature: -55°C+125°C; Tolerance: 1%; Voltage: NA; Wattage: 1/20W; Weight: 0.15mg; Datasheet: Y:\MIS_DATABASE\DATASHEETS\RESISTORS\PAN-ERJSER_NOV17.PDF
R6 R10 R18-R22 R272 R273 R393 R704 = RESISTOR: RES 10K 1/20W 1% 0201; Chkd/date: VASANTHA/270117; Crtd /date: MANIRAJA/270117; Custom_Duty: 15%; Customs_HS_Code: 85332119; Distributor_name: DIGIKEY; Distributor_part_number: 311-10.0KMCT-ND; Footprint Path: Y:\MIS_DATABASE\Library\ALTIUM_TOOL\PCB_FOOTPRINTS\Altium_Footprint_Lib.PcbLib; Height: 0.26MM; Library Path: Y:\MIS_DATABASE\Library\ALTIUM_TOOL\SCHEMATICS_PARTS\MS_DISCRETE_Library.schlib; Mfr_name: YAGEO AMERICA; Mfr_part_number: RC0201FR-0710KL; Mistral Part No: 110011040018-R; Package: 0201; Part_type: RESISTORS\FIXED; Project: GOLDEN-I LITE; RoHS: RoHS; Temperature: -55°C+125°C; Tolerance: 1%; Voltage: NA; Wattage: 1/20W; Weight: 0.17mg; Datasheet: Y:\MIS_DATABASE\DATASHEETS\RESISTORS\RCXXXXL-SER_MAR18.PDF
R8 R280-R284 = RESISTOR: RES 0E 1/16W JUMPER 0402; Chkd/date: VASANTHA/201216; Crtd /date: MUDDU/190810; Custom_Duty: 15%; Customs_HS_Code: 85332119; Distributor_name: DIGIKEY; Distributor_part_number: 541-0.0JCT-ND; Footprint Path: Y:\MIS_DATABASE\Library\ALTIUM_TOOL\PCB_FOOTPRINTS\Altium_Footprint_Lib.PcbLib; Height: 0.40MM; Library Path: Y:\MIS_DATABASE\Library\ALTIUM_TOOL\SCHEMATICS_PARTS\MS_DISCRETE_Library.schlib; Mfr_name: VISHAY; Mfr_part_number: CRCW04020000Z0ED; Mistral Part No: 110010080019-R; Package: 0402; Part_type: RESISTORS\FIXED; Project: PB_BUGBASE; RoHS: RoHS; Temperature: -55°C+155°C; Tolerance: NA; Voltage: NA; Wattage: 1/16W; Weight: 0.65mg; Datasheet: Y:\MIS_DATABASE\DATASHEETS\RESISTORS\CRCW0603.PDF
R24 = RESISTOR: RES 33E 1/20W 5% 0201; Chkd/date: VASANTHA/061216; Crtd /date: MAZHAR/170505; Custom_Duty: 15%; Customs_HS_Code: 85332119; Distributor_name: DIGIKEY; Distributor_part_number: P33AGCT-ND; Footprint Path: Y:\MIS_DATABASE\Library\ALTIUM_TOOL\PCB_FOOTPRINTS\Altium_Footprint_Lib.PcbLib; Height: 0.26MM; Library Path: Y:\MIS_DATABASE\Library\ALTIUM_TOOL\SCHEMATICS_PARTS\MS_DISCRETE_Library.schlib; Mfr_name: PANASONIC-ECG; Mfr_part_number: ERJ-1GEJ330C; Mistral Part No: 110010070052-R; Package: 0201; Part_type: RESISTORS\FIXED; Project: G4SLIM; RoHS: RoHS; Temperature: -55°C+125°C; Tolerance: 5%; Voltage: NA; Wattage: 1/20W; Weight: 0.15mg; Datasheet: Y:\MIS_DATABASE\DATASHEETS\RESISTORS\PAN-ERJXGE-FEB06.PDF
R671 = RESISTOR: RES 100K 1/10W 1% 0402; Chkd/date: VASANTHA/201216; Crtd /date: MAZHAR/130306; Custom_Duty: 15%; Customs_HS_Code: 85332119; Distributor_name: DIGIKEY; Distributor_part_number: P100KLCT-ND; Footprint Path: Y:\MIS_DATABASE\Library\ALTIUM_TOOL\PCB_FOOTPRINTS\Altium_Footprint_Lib.PcbLib; Height: 0.40MM; Library Path: Y:\MIS_DATABASE\Library\ALTIUM_TOOL\SCHEMATICS_PARTS\MS_DISCRETE_Library.schlib; Mfr_name: PANASONIC-ECG; Mfr_part_number: ERJ-2RKF1003X; Mistral Part No: 110009030187-R; Package: 0402; Part_type: RESISTORS\FIXED; Project: J32; RoHS: RoHS; Temperature: -55°C+155°C; Tolerance: 1%; Voltage: NA; Wattage: 1/10W; Weight: 0.8mg; Datasheet: Y:\MIS_DATABASE\DATASHEETS\RESISTORS\PAN-ERJSER_NOV17.PDF
R80-R82 R90-R92 R96 R117 R374 R427 R700 R703 R715 = RESISTOR: RES 10K 1/20W 5% 0201; Chkd/date: MANIRAJA/050517; Crtd /date: MANIRAJA/050517; Custom_Duty: 15%; Customs_HS_Code: 85332119; Distributor_name: DIGIKEY; Distributor_part_number: 311-10KNCT-ND; Footprint Path: Y:\MIS_DATABASE\Library\ALTIUM_TOOL\PCB_FOOTPRINTS\Altium_Footprint_Lib.PcbLib; Height: 0.26MM; Library Path: Y:\MIS_DATABASE\Library\ALTIUM_TOOL\SCHEMATICS_PARTS\MS_DISCRETE_Library.schlib; Mfr_name: YAGEO AMERICA; Mfr_part_number: RC0201JR-0710KL; Mistral Part No: 110010070051-R; Package: 0201; Part_type: RESISTORS\FIXED; Project: GOLDEN-I LITE; RoHS: RoHS; Temperature: -55°C+125°C; Tolerance: 5%; Voltage: NA; Wattage: 1/20W; Weight: 0.17mg; Datasheet: Y:\MIS_DATABASE\DATASHEETS\RESISTORS\RCXXXXL-SER_MAR18.PDF
R701 = RESISTOR: RES 8.2K 1/20W 1% 0201; Chkd/date: SUHAS/230910; Crtd /date: MUDDU/060710; Custom_Duty: 15%; Customs_HS_Code: 85332119; Distributor_name: DIGIKEY; Distributor_part_number: 541-8.20KAABCT-ND; Footprint Path: Y:\MIS_DATABASE\Library\ALTIUM_TOOL\PCB_FOOTPRINTS\Altium_Footprint_Lib.PcbLib; Height: 0.28MM; Library Path: Y:\MIS_DATABASE\Library\ALTIUM_TOOL\SCHEMATICS_PARTS\MS_DISCRETE_Library.schlib; Mfr_name: VISHAY; Mfr_part_number: CRCW02018K20FKED; Mistral Part No: 110010070001-R; Package: 0201; Part_type: RESISTORS\FIXED; Project: PB_BUGBASE; RoHS: RoHS; Temperature: -55°C+155°C; Tolerance: 1%; Voltage: NA; Wattage: 1/20W; Weight: 0.17mg; Datasheet: Y:\MIS_DATABASE\DATASHEETS\RESISTORS\CRCW0201.PDF
TP1-TP4 TP90 = TESTPOINT: TESTPOINT CIR 20 SMD; Chkd/date: SHREESHAIL/171006; Crtd /date: MAZHAR/171006; Custom_Duty: NA; Customs_HS_Code: NA; Distributor_name: NA; Distributor_part_number: NA; Footprint Path: Y:\MIS_DATABASE\Library\ALTIUM_TOOL\PCB_FOOTPRINTS\Altium_Footprint_Lib.PcbLib; Height: NA; Library Path: Y:\MIS_DATABASE\Library\ALTIUM_TOOL\SCHEMATICS_PARTS\MS_DISCRETE_Library.schlib; MECHANICAL 3D STEP FILE: NA; Mfr_name: LOCAL; Mistral Part No: NA; Package: SMD; Project: BT MODULE_CSRBC04; RoHS: NA; Temperature: NA; Tolerance: NA; Voltage: NA; Wattage: NA; Weight: NA; Datasheet: NA
U1 = OSC4_ASFL3: OSC 32.768KHz 1.8V SMD; Chkd/date: SUHAS/100710; Crtd /date: USMAN/020409; Custom_Duty: 24%; Customs_HS_Code: 85437099; Distributor_name: DIGIKEY; Distributor_part_number: 535-10003-1-ND; Height: 0.95MM; Mfr_name: ABRACON; Mfr_part_number: ASDK2-32.768KHZ-LRT; Mistral Part No: 130009031113-R; Package: SMD; Part_type: OSCILLATORS; Project: AXON; RoHS: RoHS; Temperature: -40°C+85°C; Voltage: 1.8V; Weight: NA; Datasheet: Y:\MIS_DATABASE\DATASHEETS\MISC\CRY_OSC\ASDK.PDF
U2 = TXS0104ERGYR_QFN14: IC 4-BIT BIDIRECTIONAL VOLTAGE-LEVEL TRANSLATOR QFN14; Chkd/date: SHREESHAIL/170108; Crtd /date: SHREESHAIL/170108; Custom_Duty: 15%; Customs_HS_Code: 85423100; Distributor_name: DIGIKEY; Distributor_part_number: 296-20698-1-ND; Height: 1.00MM; Mfr_name: TEXAS INSTRUMENTS; Mistral Part No: 141009030362-R; Package: QFN14; Part_type: ICS\INTERFACE; Project: HS100RD; RoHS: Sb/ Br FREE; Datasheet: Y:\MIS_DATABASE\DATASHEETS\ICS\INTERFACE\TXS0104E.PDF
C47 C330 = CAP: CAP CERAMIC 1uF 16V 20% X5R 0201; Chkd/date: MANIRAJA/300520; Crtd /date: ALVY/260520; Custom_Duty: 15%; Customs_HS_Code: 85322990; Distributor_name: DIGIKEY; Distributor_part_number: 490-18654-1-ND; Footprint Path: Y:\MIS_DATABASE\Library\ALTIUM_TOOL\PCB_FOOTPRINTS\Altium_Footprint_Lib.PcbLib; Height: 0.39MM; Library Path: Y:\MIS_DATABASE\Library\ALTIUM_TOOL\SCHEMATICS_PARTS\MS_DISCRETE_Library.schlib; Mfr_name: MURATA; Mfr_part_number: GRM033R61C105ME15D; Mistral Part No: 120018090038-R; Package: 0201; Part_type: CAPACITORS\CERAMIC; Project: QCS610_NANOSOM; RoHS: RoHS; Temperature: -55°C+85°C; Tolerance: 20%; Voltage: 16V; Wattage: NA; Weight: 0.33mg; Datasheet: Y:\MIS_DATABASE\DATASHEETS\CAPACITORS\GRM033R61C105ME15.PDF
C46 C66 C72 C94 C331 C333 C335 C380 = CAP: CAP CERAMIC 0.1uF 50V 10% X7R 0402; Alt_Mfr_name: YAGEO AMERICA; Alt_Mfr_part_number: CC0402KRX5R8BB104; Chkd/date: MANIRAJA/261020; Crtd /date: ALVY/211020; Custom_Duty: 15%; Customs_HS_Code: 85322990; Distributor_name: DIGIKEY; Distributor_part_number: 490-10700-1-ND; Footprint Path: Y:\MIS_DATABASE\Library\ALTIUM_TOOL\PCB_FOOTPRINTS\Altium_Footprint_Lib.PcbLib; Height: 0.55MM; Library Path: Y:\MIS_DATABASE\Library\ALTIUM_TOOL\SCHEMATICS_PARTS\MS_DISCRETE_Library.schlib; Mfr_name: MURATA; Mfr_part_number: GRM155R71H104KE14D; Mistral Part No: 120011100014-R; Package: 0402; Part_type: CAPACITORS\CERAMIC; Project: J7_CP; RoHS: RoHS; Temperature: -55°C+125°C; Tolerance: 10%; Voltage: 50V; Wattage: NA; Weight: 3.1mg; Datasheet: Y:\MIS_DATABASE\DATASHEETS\CAPACITORS\GRM155R71H104KE14.PDF
C65 C338 C341 = CAP: CAP CERAMIC 2.2uF 25V 10% X5R 0402; Chkd/date: ALVY/010721; Crtd /date: MANIRAJA/010721; Custom_Duty: 15%; Customs_HS_Code: 85322990; Distributor_name: DIGIKEY; Distributor_part_number: 490-12703-1-ND; Footprint Path: Y:\MIS_DATABASE\Library\ALTIUM_TOOL\PCB_FOOTPRINTS\Altium_Footprint_Lib.PcbLib; Height: 0.70MM; Library Path: Y:\MIS_DATABASE\Library\ALTIUM_TOOL\SCHEMATICS_PARTS\MS_DISCRETE_Library.schlib; Mfr_name: MURATA; Mfr_part_number: GRM155R61E225KE11D; Mistral Part No: 120015120001-R; Package: 0402; Part_type: CAPACITORS\CERAMIC; Project: TI_AM263X_CC; RoHS: RoHS; Temperature: -55°C+85°C; Tolerance: 10%; Voltage: 25V; Wattage: NA; Weight: 1.5mg; Datasheet: Y:\MIS_DATABASE\DATASHEETS\CAPACITORS\GRM155R61E225KE11.PDF
R12 R333 R398 R399 R426 = RESISTOR: RES 49.9K 1/16W 1% 0402; Chkd/date: MAZHAR/220709; Crtd /date: GEETHA/090606; Custom_Duty: 15%; Customs_HS_Code: 85332119; Distributor_name: DIGIKEY; Distributor_part_number: 311-49.9KLRCT-ND; Footprint Path: Y:\MIS_DATABASE\Library\ALTIUM_TOOL\PCB_FOOTPRINTS\Altium_Footprint_Lib.PcbLib; Height: 0.40MM; Library Path: Y:\MIS_DATABASE\Library\ALTIUM_TOOL\SCHEMATICS_PARTS\MS_DISCRETE_Library.schlib; Mfr_name: YAGEO AMERICA; Mfr_part_number: RC0402FR-0749K9L; Mistral Part No: 110009030902-R; Package: 0402; Part_type: RESISTORS\FIXED; Project: PNAV; RoHS: RoHS; Temperature: -55°C+155°C; Tolerance: 1%; Voltage: NA; Wattage: 1/16W; Weight: 0.65mg; Datasheet: Y:\MIS_DATABASE\DATASHEETS\RESISTORS\RCXXXXL-SER_MAR18.PDF
R57 R66 = RESISTOR: RES 0E 1/20W 5% 0201; Chkd/date: NAVEED/301214; Crtd /date: MUDDU/120710; Custom_Duty: 15%; Customs_HS_Code: 85332119; Distributor_name: DIGIKEY; Distributor_part_number: 311-0.0NCT-ND; Footprint Path: Y:\MIS_DATABASE\Library\ALTIUM_TOOL\PCB_FOOTPRINTS\Altium_Footprint_Lib.PcbLib; Height: 0.26MM; Library Path: Y:\MIS_DATABASE\Library\ALTIUM_TOOL\SCHEMATICS_PARTS\MS_DISCRETE_Library.schlib; Mfr_name: YAGEO AMERICA; Mfr_part_number: RC0201JR-070RL; Mistral Part No: 110010070067-R; Package: 0201; Part_type: RESISTORS\FIXED; Project: PB_BUGBASE; RoHS: RoHS; SIGNAL_MODEL: RESISTOR_RES0201_0-5_0E_0E; Temperature: -55°C+125°C; Tolerance: 5%; Voltage: NA; Wattage: 1/20W; Weight: 0.17mg; Datasheet: Y:\MIS_DATABASE\DATASHEETS\RESISTORS\RCXXXXL-SER_MAR18.PDF
R89 = RESISTOR: RES 22E 1/20W 1% 0201; Chkd/date: MAZHAR/140709; Crtd /date: MAZHAR/220807; Custom_Duty: 15%; Customs_HS_Code: 85332119; Distributor_name: DIGIKEY; Distributor_part_number: P22.0ABCT-ND; Footprint Path: Y:\MIS_DATABASE\Library\ALTIUM_TOOL\PCB_FOOTPRINTS\Altium_Footprint_Lib.PcbLib; Height: 0.26MM; Library Path: Y:\MIS_DATABASE\Library\ALTIUM_TOOL\SCHEMATICS_PARTS\MS_DISCRETE_Library.schlib; Mfr_name: PANASONIC-ECG; Mfr_part_number: ERJ-1GEF22R0C; Mistral Part No: 110009030522-R; Package: 0201; Part_type: RESISTORS\FIXED; Project: V8TS; RoHS: RoHS; SIGNAL_MODEL: RESISTOR_RES0201_0-5_22E_1%_22E_1%; Temperature: -55°C+125°C; Tolerance: 1%; Voltage: NA; Wattage: 1/20W; Weight: 0.15mg; Datasheet: Y:\MIS_DATABASE\DATASHEETS\RESISTORS\PAN-ERJSER_NOV17.PDF
R364-R367 R376-R379 R396 = RESISTOR: RES 49.9K 1/20W 1% 0201; Chkd/date: MAZHAR/140108; Crtd /date: USMAN/140108; Cust_part_number: 4700-80185E; Custom_Duty: 15%; Customs_HS_Code: 85332119; Distributor_name: DIGIKEY; Distributor_part_number: P49.9KABCT-ND; Footprint Path: Y:\MIS_DATABASE\Library\ALTIUM_TOOL\PCB_FOOTPRINTS\Altium_Footprint_Lib.PcbLib; Height: 0.26MM; Library Path: Y:\MIS_DATABASE\Library\ALTIUM_TOOL\SCHEMATICS_PARTS\MS_DISCRETE_Library.schlib; Mfr_name: PANASONIC-ECG; Mfr_part_number: ERJ-1GEF4992C; Mistral Part No: 110009030900-R; Package: 0201; Part_type: RESISTORS\FIXED; Project: SD_WATERLOO; RoHS: RoHS; Temperature: -55°C+125°C; Tolerance: 1%; Voltage: NA; Wattage: 1/20W; Weight: 0.15mg; Datasheet: Y:\MIS_DATABASE\DATASHEETS\RESISTORS\PAN-ERJSER_NOV17.PDF
U28 = MTFC16GAPALBH_TFBGA153: IC 16GB e-MMC MEMORY TFBGA153; Chkd/date: MANIRAJA/220618; Crtd /date: ALVY/220618; Custom_Duty: 15%; Customs_HS_Code: 85423100; Distributor_name: DIGIKEY; Distributor_part_number: MTFC16GAPALBH-AAT-ND; Footprint Path: Y:\MIS_DATABASE\Library\ALTIUM_TOOL\PCB_FOOTPRINTS\Altium_Footprint_Lib.PcbLib; Height: 1.10MM; Library Path: Y:\MIS_DATABASE\Library\ALTIUM_TOOL\SCHEMATICS_PARTS\MS_MISCMEMORY_Library.schlib; Mfr_name: MICRON; Mfr_part_number: MTFC16GAPALBH-AAT; Mistral Part No: 141118060005-R; Package: TFBGA153; Part_type: ICS\DIGITAL\MEMORY; Project: TI_J7_SVB-DUT; RoHS: RoHS; Temperature: -40°C+105°C; Tolerance: NA; Voltage: NA; Wattage: NA; Weight: NA; Datasheet: Y:\MIS_DATABASE\DATASHEETS\ICS\MEMORY\MTFCXXX.PDF
U58 = SN74LVC1G08DBVRE4_SOT23-5: IC SINGLE 2-INPUT POSITIVE AND GATE SOT23-5; Chkd/date: SUHAS/221010; Crtd /date: USMAN/151008; Custom_Duty: 15%; Customs_HS_Code: 85423100; Distributor_name: DIGIKEY; Distributor_part_number: SN74LVC1G08DBVRE4-ND; Height: 1.45MM; Mfr_name: TEXAS INSTRUMENTS; Mistral Part No: 141009060026-R; Part_type: ICS\DIGITAL\GATES; Project: KHAN_MAIN; RoHS: Sb/ Br FREE; Temperature: -40°C+85°C; Datasheet: Y:\MIS_DATABASE\DATASHEETS\ICS\DIGITAL\GATES\SN74LVC1G08.PDF
C60 = CAP: CAP CERAMIC 4.7uF 10V 20% X5R 0402; Chkd/date: MANIRAJA/110718; Crtd /date: ALVY/110718; Custom_Duty: 15%; Customs_HS_Code: 85322990; Distributor_name: DIGIKEY; Distributor_part_number: 490-14306-1-ND; Footprint Path: Y:\MIS_DATABASE\Library\ALTIUM_TOOL\PCB_FOOTPRINTS\Altium_Footprint_Lib.PcbLib; Height: 0.65MM; Library Path: Y:\MIS_DATABASE\Library\ALTIUM_TOOL\SCHEMATICS_PARTS\MS_DISCRETE_Library.schlib; Mfr_name: MURATA; Mfr_part_number: GRM155R61A475MEAAD; Mistral Part No: 120012060002-R; Package: 0402; Part_type: CAPACITORS\CERAMIC; Project: TI_J7SVB_PCIE_ADD-ON-CARD; RoHS: RoHS; Temperature: -55°C+85°C; Tolerance: 20%; Voltage: 10V; Wattage: NA; Weight: 14mg; Datasheet: Y:\MIS_DATABASE\DATASHEETS\CAPACITORS\GRM155R61A475MEAAD.PDF
FL8 = EMIFILTER_IND: IND FERRITE BEAD CHIP 120E 2A 0402; Chkd/date: NAVEED/241114; Crtd /date: USMAN/170613; Custom_Duty: 24%; Customs_HS_Code: 85369090; Distributor_name: DIGIKEY; Distributor_part_number: 490-9656-1-ND; Footprint Path: Y:\MIS_DATABASE\Library\ALTIUM_TOOL\PCB_FOOTPRINTS\Altium_Footprint_Lib.PcbLib; Height: 0.55MM; Library Path: Y:\MIS_DATABASE\Library\ALTIUM_TOOL\SCHEMATICS_PARTS\MS_FILTER_Library.schlib; Mfr_name: MURATA; Mfr_part_number: BLM15PX121SN1D; Mistral Part No: 130013060022-R; Package: 0402; Part_type: INDUCTOR; Project: GEN_3-8; RoHS: RoHS; Temperature: -55°C+125°C; Tolerance: 25%; Voltage: NA; Wattage: NA; Weight: 1mg; Datasheet: Y:\MIS_DATABASE\DATASHEETS\DISCRETES\INDUCTORS\BLM15-SN1-SER.PDF
J20 = CON_SDCARD9_MEM2075-00-140: CON MICROSD CARD 9POS FEMALE RT SMD; Chkd/date: MANIRAJA/270921; Crtd /date: ALVY/240921; Custom_Duty: 24%; Customs_HS_Code: 85369090; Distributor_name: DIGIKEY; Distributor_part_number: 2073-MEM2051-00-195-00-ACT-ND; Footprint Path: Y:\MIS_DATABASE\Library\ALTIUM_TOOL\PCB_FOOTPRINTS\Altium_Footprint_Lib.PcbLib; Height: 2.05MM; Library Path: Y:\MIS_DATABASE\Library\ALTIUM_TOOL\SCHEMATICS_PARTS\MS_CONNECTOR_Library.schlib; Mfr_name: GCT; Mfr_part_number: MEM2051-00-195-00-A; Mistral Part No: 150021090028-R; Package: SMD; Part_type: CONNECTOR\MEMORY CARD; Project: TI_AM62x SKEVM_BRD; RoHS: RoHS; Temperature: -40°C+85°C; Tolerance: NA; Voltage: NA; Wattage: NA; Weight: 1000mg; Datasheet: Y:\MIS_DATABASE\DATASHEETS\CONNECTORS\MEM2051-00-195-00-A.PDF
U13 = TPS22918DBVR_SOT23-6: IC ON RESISTANCE LOAD SWITCH SOT23-6; Automotive Alternate_mfr_name: TEXAS INSTRUMENTS; Automotive Alternate_mfr_part_number: TPS22918TDBVRQ1; Chkd/date: VASANTHA/130516; Crtd /date: VASANTHA/130516; Custom_Duty: 15%; Customs_HS_Code: 85423100; Distributor_name: DIGIKEY; Distributor_part_number: TPS22918DBVR-ND; Height: 1.45MM; Mfr_name: TEXAS INSTRUMENTS; Mistral Part No: 142016050007-R; Part_type: ICS\POWER; Project: TMDXCSK8127; RoHS: RoHS; Temperature: -40°C to 105°C; Tolerance: NA; Voltage: NA; Wattage: NA; Weight: NA; Datasheet: Y:\MIS_DATABASE\DATASHEETS\ICS\POWER\TPS22918DBV.PDF
U15 = TPD6E001RSE_UQFN10: IC 6CH ESD-PROTECTION ARRAY UQFN10; Chkd/date: USMAN/070612; Crtd /date: BAVISH/160811; Custom_Duty: 15%; Customs_HS_Code: 85423100; Distributor_name: DIGIKEY; Distributor_part_number: 296-21888-1-ND; Footprint Path: Y:\MIS_DATABASE\Library\ALTIUM_TOOL\PCB_FOOTPRINTS\Altium_Footprint_Lib.PcbLib; Height: 0.60MM; IBISSP_MODLES: Y:\MIS_DATABASE\IBIS\ICs\INTERFACE\TPD6E001RSE.IBS; Library Path: Y:\MIS_DATABASE\Library\ALTIUM_TOOL\SCHEMATICS_PARTS\MS_MISCINTERFACE_Library.schlib; Mfr_name: TEXAS INSTRUMENTS; Mistral Part No: 141011080020-R; Package: UQFN10; Part_type: ICS\INTERFACE; Project: DM385EVM_BASE-BOARD; RoHS: RoHS; Temperature: -40°C+85°C; Tolerance: NA; Voltage: NA; Wattage: NA; Weight: 7mg; Datasheet: Y:\MIS_DATABASE\DATASHEETS\ICS\INTERFACE\TPD6E001.PDF
U18 = TPD2E001DRLR_SOT-5: IC ESD-PROTECTION DIODE ARRAYS SOT-5; Chkd/date: NAVEED/150714; Crtd /date: MUDDU/250510; Custom_Duty: 15%; Customs_HS_Code: 85423100; Distributor_name: DIGIKEY; Distributor_part_number: 296-21883-1-ND; Footprint Path: Y:\MIS_DATABASE\Library\ALTIUM_TOOL\PCB_FOOTPRINTS\Altium_Footprint_Lib.PcbLib; Height: 0.60MM; Library Path: Y:\MIS_DATABASE\Library\ALTIUM_TOOL\SCHEMATICS_PARTS\MS_FILTER_Library.schlib; Mfr_name: TEXAS INSTRUMENTS; Mistral Part No: 140110060007-R; Package: SOT-5; Part_type: ICS\ANALOG\ACTIVE FILTER; Project: CENTAURUS; RoHS: RoHS; Temperature: -40°C+85°C; Tolerance: NA; Voltage: NA; Wattage: NA; Weight: 2.8mg; Datasheet: Y:\MIS_DATABASE\DATASHEETS\ICS\MISC\TPD2E001DRLR.PDF
U22 = SN74LVC1G11DCKR_SC70-6: IC SINGLE 3-INPUT POSITIVE-AND GATE SON6; Chkd/date: MANIRAJA/270121; Crtd /date: ALVY/270121; Custom_Duty: 15%; Customs_HS_Code: 85423100; Distributor_name: DIGIKEY; Distributor_part_number: 296-30120-1-ND; Footprint Path: Y:\MIS_DATABASE\Library\ALTIUM_TOOL\PCB_FOOTPRINTS\Altium_Footprint_Lib.PcbLib; Height: 0.60MM; Library Path: Y:\MIS_DATABASE\Library\ALTIUM_TOOL\SCHEMATICS_PARTS\MS_GATE_Library.schlib; Mfr_name: TEXAS INSTRUMENTS; Mistral Part No: 141021010013-R; Package: SON6; Part_type: ICS\DIGITAL\GATES; Project: AM64X_SKEVM; RoHS: RoHS; Temperature: -40°C+125°C; Tolerance: NA; Voltage: NA; Wattage: NA; Weight: 33mg; Datasheet: Y:\MIS_DATABASE\DATASHEETS\ICS\DIGITAL\GATES\SN74LVC1G_NOV16.PDF
U12 = AM62-EVM_BGA425: IC AM62 SoC MICROPROCESSOR BGA425; Chkd/date: ALVY/110621; Crtd /date: MANIRAJA/110621; Custom_Duty: 15%; Customs_HS_Code: 85423100; Distributor_name: NA; Distributor_part_number: NA; Footprint Path: Y:\MIS_DATABASE\Library\ALTIUM_TOOL\PCB_FOOTPRINTS\Altium_Footprint_Lib.PcbLib; Height: 0.65MM; Library Path: Y:\MIS_DATABASE\Library\ALTIUM_TOOL\SCHEMATICS_PARTS\MS_MICROPROCESSOR_Library.schlib; Mfr_name: TEXAS INSTRUMENTS; Mistral Part No: 141221060001; Package: BGA425; Part_type: ICS\DIGITAL\MICROPROCESSOR; Project: AM62_EVM_BRD; RoHS: NA; Temperature: NA; Tolerance: NA; Voltage: NA; Wattage: NA; Weight: NA; Datasheet: Y:\MIS_DATABASE\DATASHEETS\ICS\DIGITAL\MICROCONTROLLER\AM62-SoC_SVB.PDF

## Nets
DGND: C3.2 C4.1 C5.2 C6.1 C7.1 C9.2 C10.1 C46.2 C47.2 C60.2 C65.1 C66.1 C72.1 C94.2 C330.2 C331.2 C333.2 C335.2 C338.2 C341.2 C380.2 J2.1(GND) J2.7(GND) J2.18(GND) J2.33(GND) J2.39(GND) J2.45(GND) J2.51(GND) J2.57(GND) J2.63(GND) J2.69(GND) J2.75(GND) J2.SH1 J2.SH2 J20.6(VSS) J20.SH1 J20.SH2 J20.SH3 J20.SH4 R12.2 R272.2 R333.2 R393.2 R398.2 R671.1 R700.1 U1.2(GND) U2.7(GND) U2.15(TAB) U13.2(GND) U15.5(GND) U18.4(GND) U22.2(GND) U28.A6(VSS) U28.C4(VSSQ) U28.E7(VSS) U28.G5(VSS) U28.H10(VSS) U28.J5(VSS) U28.K8(VSS) U28.N2(VSSQ) U28.N5(VSSQ) U28.P4(VSSQ) U28.P6(VSSQ) U58.3(GND) ; also on sheet 1 10 11 12 13 14 15 16 17 21 22 23 24 25 26 27 28 29 30 31 32 33 34 35 36 37 38 39 40 41 42 43
VCC_1V8: C7.2 C333.1 C341.1 C380.1 R4.1 R6.2 R10.2 R18.2 R19.2 R20.2 R21.2 R22.2 R364.1 R365.1 R366.1 R367.1 R376.1 R377.1 R378.1 R379.1 R396.1 R399.1 R426.1 R703.2 U2.1(VCCA) U28.C6(VCCQ) U28.M4(VCCQ) U28.N4(VCCQ) U28.P3(VCCQ) U28.P5(VCCQ) U58.5(VCC) ; also on sheet 12 13 14 21 25 34 37 39 40 42
VCC_3V3_SYS: C3.1 C4.2 C6.2 C9.1 C10.2 C46.1 C47.1 C94.1 C335.1 C338.1 J2.2(3-3V) J2.4(3-3V) J2.72(3-3V) J2.74(3-3V) R3.1 R96.2 R117.2 R273.2 R374.2 R427.2 R701.2 R704.2 R715.2 U2.14(VCCB) U13.1(VIN) U18.1(VCC) U22.5(VCC) U28.E6(VCC) U28.F5(VCC) U28.J10(VCC) U28.K9(VCC) ; also on sheet 10 12 13 14 22 23 24 25 26 27 29 30 31 32 33 34 35 36 37 38 39 40 41 42 43
VDD_MMC1: C60.1 FL8.1 U13.5(QOD) U13.6(VOUT)
VDD_MMC1_SD: C65.2 C66.2 FL8.2 J20.4(VDD)
VDDIM: C330.1 C331.1 U28.C2(VDDIM)
VDDSHV_SDIO: C72.2 R80.2 R81.2 R82.2 R90.2 R91.2 R92.2 U15.10(VCC) ; also on sheet 13 15
BT_EN_SOC_3V3: J2.54(W_DISABLE2#) R273.1 ; also on sheet 34
BT_UART_WAKE_1V8: R2.2 U2.4(A3)
BT_UART_WAKE_CONN: J2.20(UART_WAKE#) R1.1 R2.1
BT_UART_WAKE_SOC_3V3: R1.2 R704.1 U2.11(B3) ; also on sheet 39
BT_WLAN_EN: J2.56(W_DISABLE1#) R23.2 R272.1 R702.2
eMMC_RSTn: R426.2 U28.K5(RST_N) U58.4(Y)
GPIO_eMMC_RSTn: R427.1 U58.1(A) ; also on sheet 39
HFOSC0_CLKOUT_32K: R7.1 ; also on sheet 32
M2_LED1#: J2.6(LED_1#) TP3.1(TP)
M2_LED2#: J2.16(LED_2#) TP4.1(TP)
MCASP1_ACLKX_BT_1V8: J2.8(PCM_CLK/I2S_SCK) ; also on sheet 39
MCASP1_AFSX_BT_1V8: J2.10(PCM_SYNC/I2S_WS) ; also on sheet 39
MCASP1_AXR0_BT_1V8: J2.12(PCM_IN/I2S_SD_IN) R671.2 ; also on sheet 39
MCASP1_AXR2_BT_1V8: J2.14(PCM_OUT/I2S_SD_OUT) ; also on sheet 39
MMC0_CLK: R89.1 R398.1 R399.2 U28.M6(CLK)
MMC1_CLK: J20.5(CLK) R66.1 R90.1 R333.1 U15.6(IO4)
MMC1_CLK_R: R66.2 U12.B22(MMC1_CLK)
MMC1_CMD: J20.3(CMD) R82.1 U12.A21(MMC1_CMD) U15.1(IO1)
MMC1_D0: J20.7(DAT0) R92.1 U12.A22(MMC1_DAT0) U15.8(IO6)
MMC1_D1: J20.8(DAT1) R91.1 U12.B21(MMC1_DAT1) U15.7(IO5)
MMC1_D2: J20.1(DAT2) R81.1 U12.C21(MMC1_DAT2) U15.2(IO2)
MMC1_D3: J20.2(CD/DAT3) R80.1 U12.D22(MMC1_DAT3) U15.3(IO3)
MMC1_SD_EN: R117.1 U22.1(A) ; also on sheet 39
MMC1_SD_LS_EN: R374.1 U13.3(ON) U22.4(Y)
MMC1_SDCD: J20.9(CD) R96.1 U12.D17(MMC1_SDCD) U18.5(IO2)
MMC2_CLK: R8.2 R12.1 R57.2
MMC2_CLK_COM: J2.9(SDIO_CLK/SYSCLK) R8.1 R10.1
MMC2_CMD: R282.2 U12.C24(MMC2_CMD)
MMC2_CMD_COM: J2.11(SDIO_CMD) R20.1 R282.1
MMC2_D0: R284.2 U12.B24(MMC2_DAT0)
MMC2_D0_COM: J2.13(SDIO_DATA0) R18.1 R284.1
MMC2_D1: R283.2 U12.C25(MMC2_DAT1)
MMC2_D1_COM: J2.15(SDIO_DATA1) R19.1 R283.1
MMC2_D2: R281.2 U12.E23(MMC2_DAT2)
MMC2_D2_COM: J2.17(SDIO_DATA2) R21.1 R281.1
MMC2_D3: R280.2 U12.D24(MMC2_DAT3)
MMC2_D3_COM: J2.19(SDIO_DATA3) R22.1 R280.1
PORz_OUT: U22.6(C) ; also on sheet 23 24 27 42
RESETSTATz: U22.3(B) U58.2(B) ; also on sheet 13 21 23 24 27 32 33 37 39 40 41 42
SLOW_CLK: J2.50(SUSCLK_32kHz) R5.2 R7.2
SOC_GPIO1_49: U12.C17(MMC1_SDWP) ; also on sheet 38
SOC_MMC0_CLK: R89.2 U12.AB1(MMC0_CLK)
SOC_MMC0_CMD: R396.2 U12.Y3(MMC0_CMD) U28.M5(CMD)
SOC_MMC0_DAT0: R378.2 U12.AA2(MMC0_DAT0) U28.A3(DAT0)
SOC_MMC0_DAT1: R377.2 U12.AA1(MMC0_DAT1) U28.A4(DAT1)
SOC_MMC0_DAT2: R376.2 U12.AA3(MMC0_DAT2) U28.A5(DAT2)
SOC_MMC0_DAT3: R379.2 U12.Y4(MMC0_DAT3) U28.B2(DAT3)
SOC_MMC0_DAT4: R367.2 U12.AB2(MMC0_DAT4) U28.B3(DAT4)
SOC_MMC0_DAT5: R366.2 U12.AC1(MMC0_DAT5) U28.B4(DAT5)
SOC_MMC0_DAT6: R365.2 U12.AD2(MMC0_DAT6) U28.B5(DAT6)
SOC_MMC0_DAT7: R364.2 U12.AC2(MMC0_DAT7) U28.B6(DAT7)
SoC_MMC2_CLK: R57.1 U12.D25(MMC2_CLK)
SOC_UART1_CTS_BT_1V8: J2.34(UART_CTS) ; also on sheet 37
SOC_UART1_RTS_BT_1V8: J2.36(UART_RTS) ; also on sheet 37
SOC_UART1_RX_BT_1V8: J2.22(UART_RXD) ; also on sheet 37
SOC_UART1_TX_BT_1V8: R24.2 ; also on sheet 37
SoC_WLAN_EN_1V8: R23.1 U2.3(A2) U12.A23(MMC2_SDCD)
SoC_WLAN_EN_3V3: R702.1 U2.12(B2)
SoC_WLAN_IRQ_1V8: J2.21(SDIO_WAKE#) R6.1 U12.B23(MMC2_SDWP)
USB_DM: J2.5(USB_D-) TP2.1(TP)
USB_DP: J2.3(USB_D+) TP1.1(TP)
WL_LT_EN: R700.2 R701.1 U2.8(OE) ; also on sheet 39
WLAN_ALERT_1V8: R11.2 U2.5(A4)
WLAN_ALERT_3V3: R715.1 U2.10(B4) ; also on sheet 39
WLAN_SDIO_RST_1V8: J2.23(SDIO_RESET#/TX_BLANKING) R703.1 U2.2(A1)
WLAN_SDIO_RST_3V3: U2.13(B1) ; also on sheet 39
N15951745: C5.1 R3.2 R4.2 U1.1(TRI-STATE) U1.4(VDD)
N15952254: R5.1 U1.3(OUTPUT)
N16878497: R393.1 TP90.1(TP) U28.H5(DS)
N20600664: J2.32(UART_TXD) R24.1
N20605838: J2.62(ALERT#) R11.1

Not connected (* = marked no-connect by the designer): J2 35(PETP0)* 37(PETN0)* 38(VENDOR_DEFINED1)* 40(VENDOR_DEFINED2)* 41(PERP0)* 42(VENDOR_DEFINED3)* 43(PERN0)* 44(COEX3)* 46(COEX_RXD)* 47(REFCLKP0)* 48(COEX_TXD)* 49(REFCLKN0)* 52(PERST0#)* 53(CLKREQ0#)* 55(PEWAKE0#)* 58(I2C_DATA)* 59(RESERVED/PETP1)* 60(I2C_CLK)* 61(RESERVED/PETN1)* 64(RESERVED)* 65(RESERVED/PERP1)* 66(UIM_SWP/PERST1#)* 67(RESERVED/PERN1)* 68(UIM_POWER_SNK/CLKREQ1#)* 70(UIM_POWER_SRC/GPIO1/PEWAKE#)* 71(RESERVED/REFCLKP1)* 73(RESERVED/REFCLKN1)* SH3*; U2 6(NC1)* 9(NC2)*; U13 4(CT)*; U15 4(NC1)* 9(NC2)*; U18 2(NC)* 3(IO1)*; U28 A1(NC1)* A2(NC2)* A7(RFU1)* A8(NC3)* A9(NC4)* A10(NC5)* A11(NC6)* A12(NC7)* A13(NC8)* A14(NC9)* B1(NC10)* B7(NC11)* B8(NC12)* B9(NC13)* B10(NC14)* B11(NC15)* B12(NC16)* B13(NC17)* B14(NC18)* C1(NC19)* C3(NC20)* C5(NC21)* C7(NC22)* C8(NC23)* C9(NC24)* C10(NC25)* C11(NC26)* C12(NC27)* C13(NC28)* C14(NC29)* D1(NC30)* D2(NC31)* D3(NC32)* D4(NC33)* D12(NC34)* D13(NC35)* D14(NC36)* E1(NC37)* E2(NC38)* E3(NC39)* E5(RFU2)* E8(VSF1)* E9(VSF2)* E10(VSF3)* E12(NC40)* E13(NC41)* E14(NC42)* F1(NC43)* F2(NC44)* F3(NC45)* F10(VSF4)* F12(NC46)* F13(NC47)* F14(NC48)* G1(NC49)* G2(NC50)* G3(NC51)* G10(VSF5)* G12(NC52)* G13(NC53)* G14(NC54)* H1(NC55)* H2(NC56)* H3(NC57)* H12(NC58)* H13(NC59)* H14(NC60)* J1(NC61)* J2(NC62)* J3(NC63)* J12(NC64)* J13(NC65)* J14(NC66)* K1(NC67)* K2(NC68)* K3(NC69)* K6(RFU3)* K7(RFU4)* K10(VSF6)* K12(NC70)* K13(NC71)* K14(NC72)* L1(NC73)* L2(NC74)* L3(NC75)* L12(NC76)* L13(NC77)* L14(NC78)* M1(NC79)* M2(NC80)* M3(NC81)* M7(NC82)* M8(NC83)* M9(NC84)* M10(NC85)* M11(NC86)* M12(NC87)* M13(NC88)* M14(NC89)* N1(NC90)* N3(NC91)* N6(NC92)* N7(NC93)* N8(NC94)* N9(NC95)* N10(NC96)* N11(NC97)* N12(NC98)* N13(NC99)* N14(NC100)* P1(NC101)* P2(NC102)* P7(NC103)* P8(NC104)* P9(NC105)* P10(VSF7)* P11(NC106)* P12(NC107)* P13(NC108)* P14(NC109)*

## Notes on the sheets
sheet 18
- M.2 INTERFACE
- 1.8V
- 1.8V
- CAD NOTE: PLACE TERMINATION RESISTORS CLOSER TO SoC
- SoC_MAIN_UART1_RXD
- SoC_MAIN_UART1_TXD
- SoC_MAIN_UART1_CTS
- 1.8V
- SoC_MAIN_UART1_RTS
- Place R5 & R7 close
  to each other to
  avoid stub.
- WL_LT_EN = Active High
sheet 19
- SOC - MMC Interface
- eMMC FLASH
- GPIO1_49
- 1.8V
- 1.8V
- eMMC FLASH RESET
sheet 20
- SD CARD INTERFACE
- SD CARD RESET
- LOAD SWITCH
- Place near SD Card Connector
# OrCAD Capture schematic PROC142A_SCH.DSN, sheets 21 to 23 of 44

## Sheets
21 20. OSPI INTERFACE: size C; title: OSPI INTERFACE
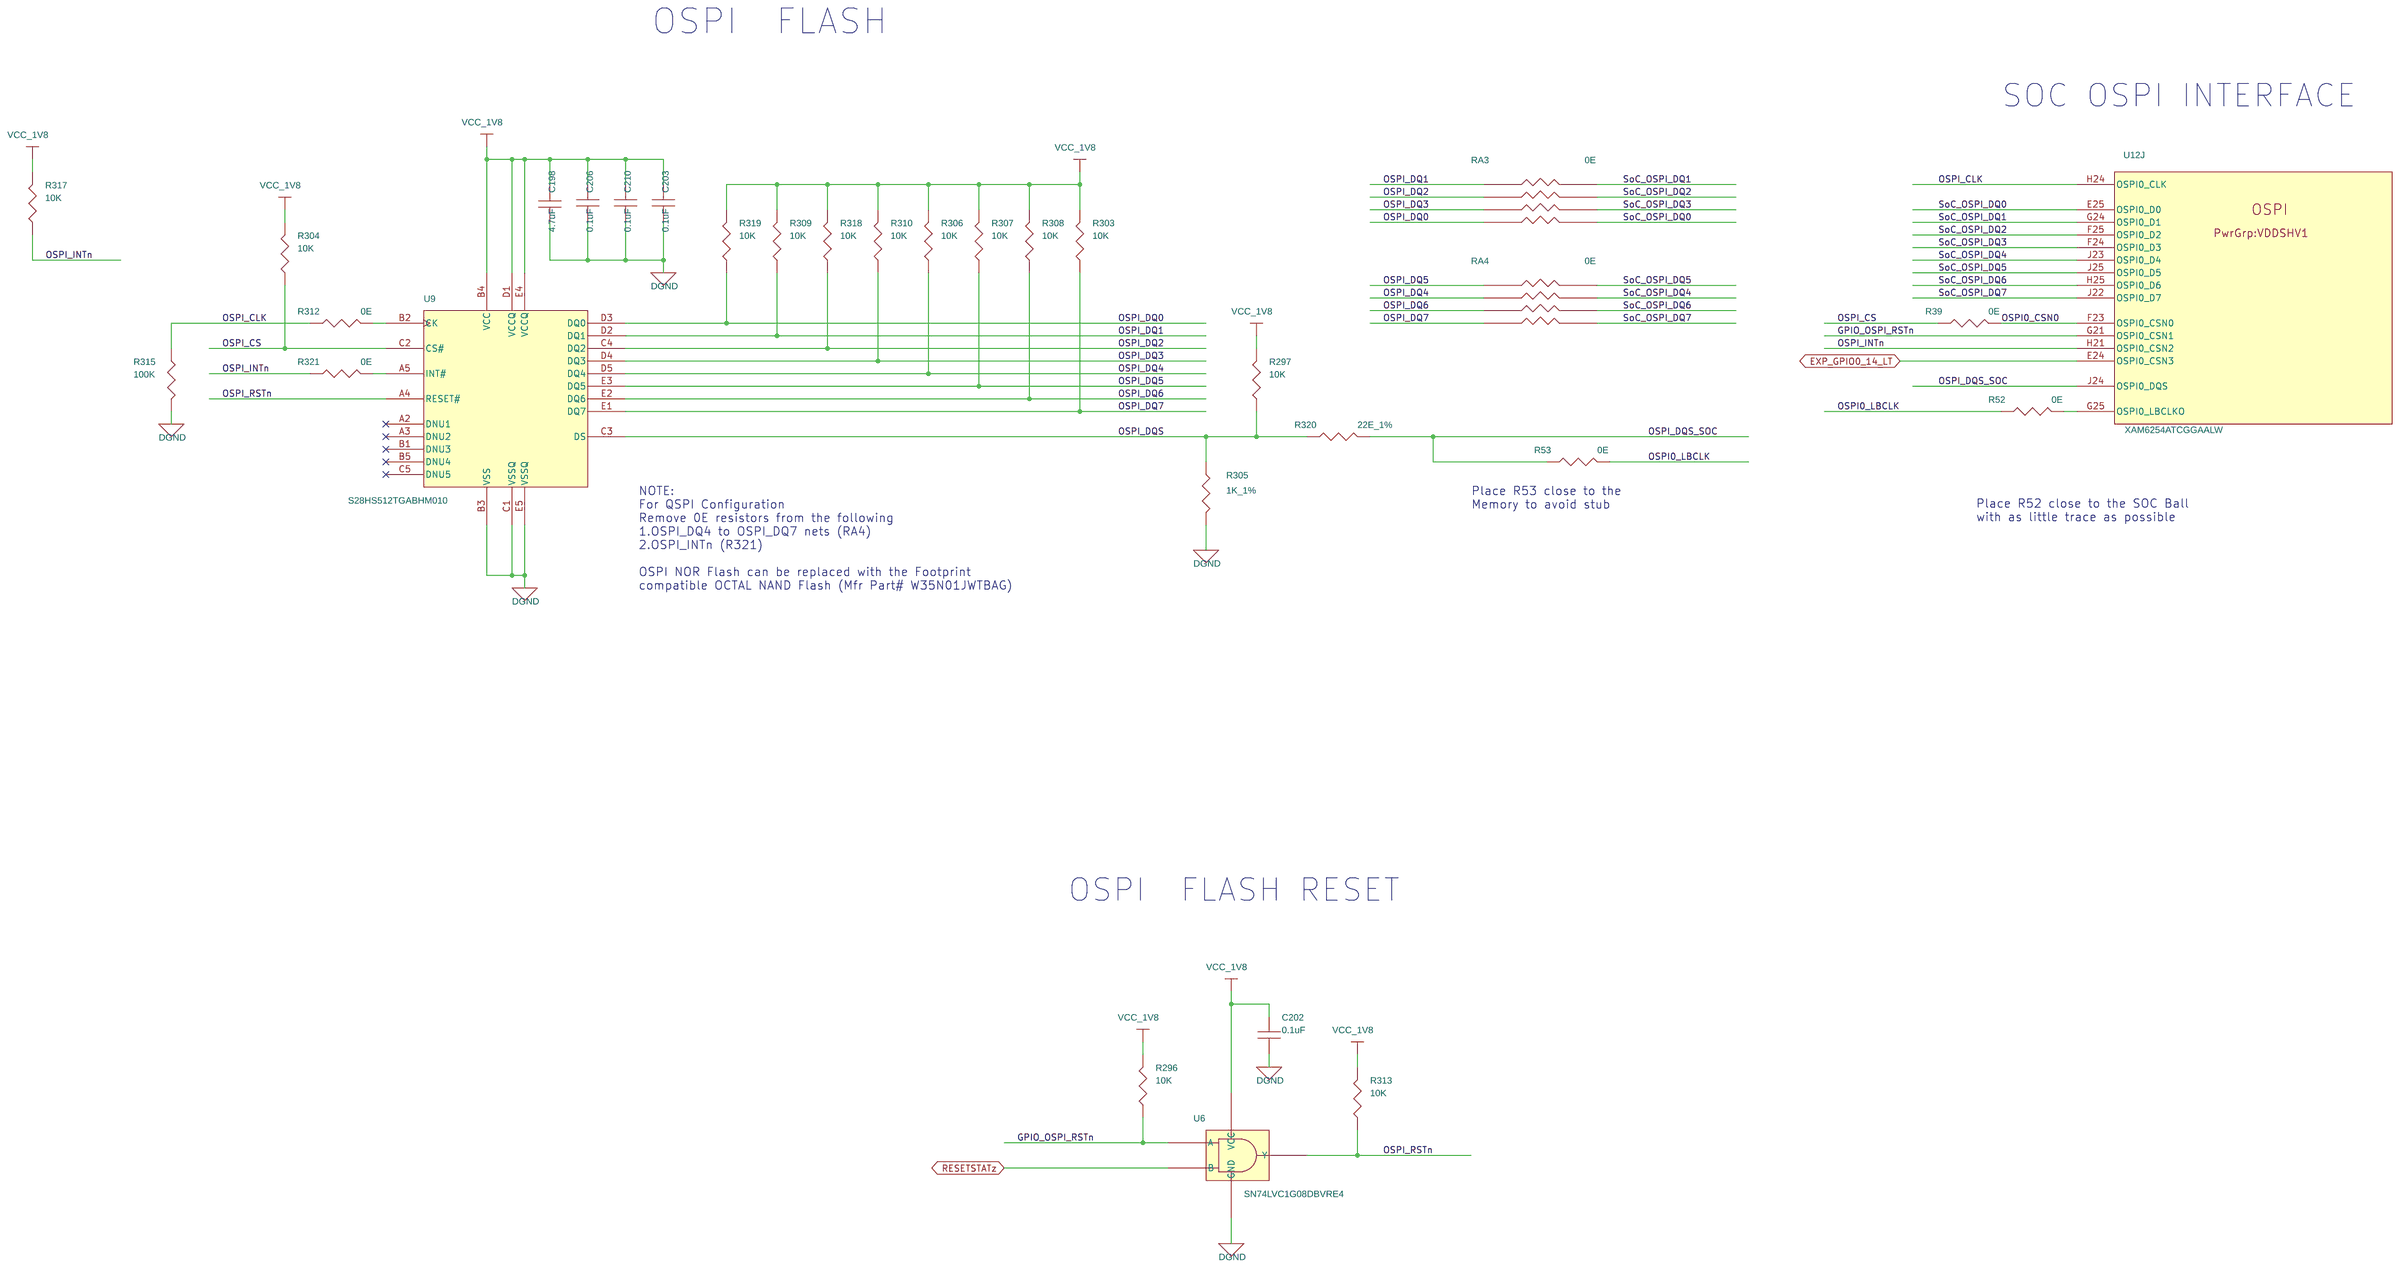
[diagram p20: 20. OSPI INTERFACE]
22 21. BRD ID EEPROM &TEMP SENSORS: size C; title: BOARD ID EEPROM & TEMPERATURE SENSORS
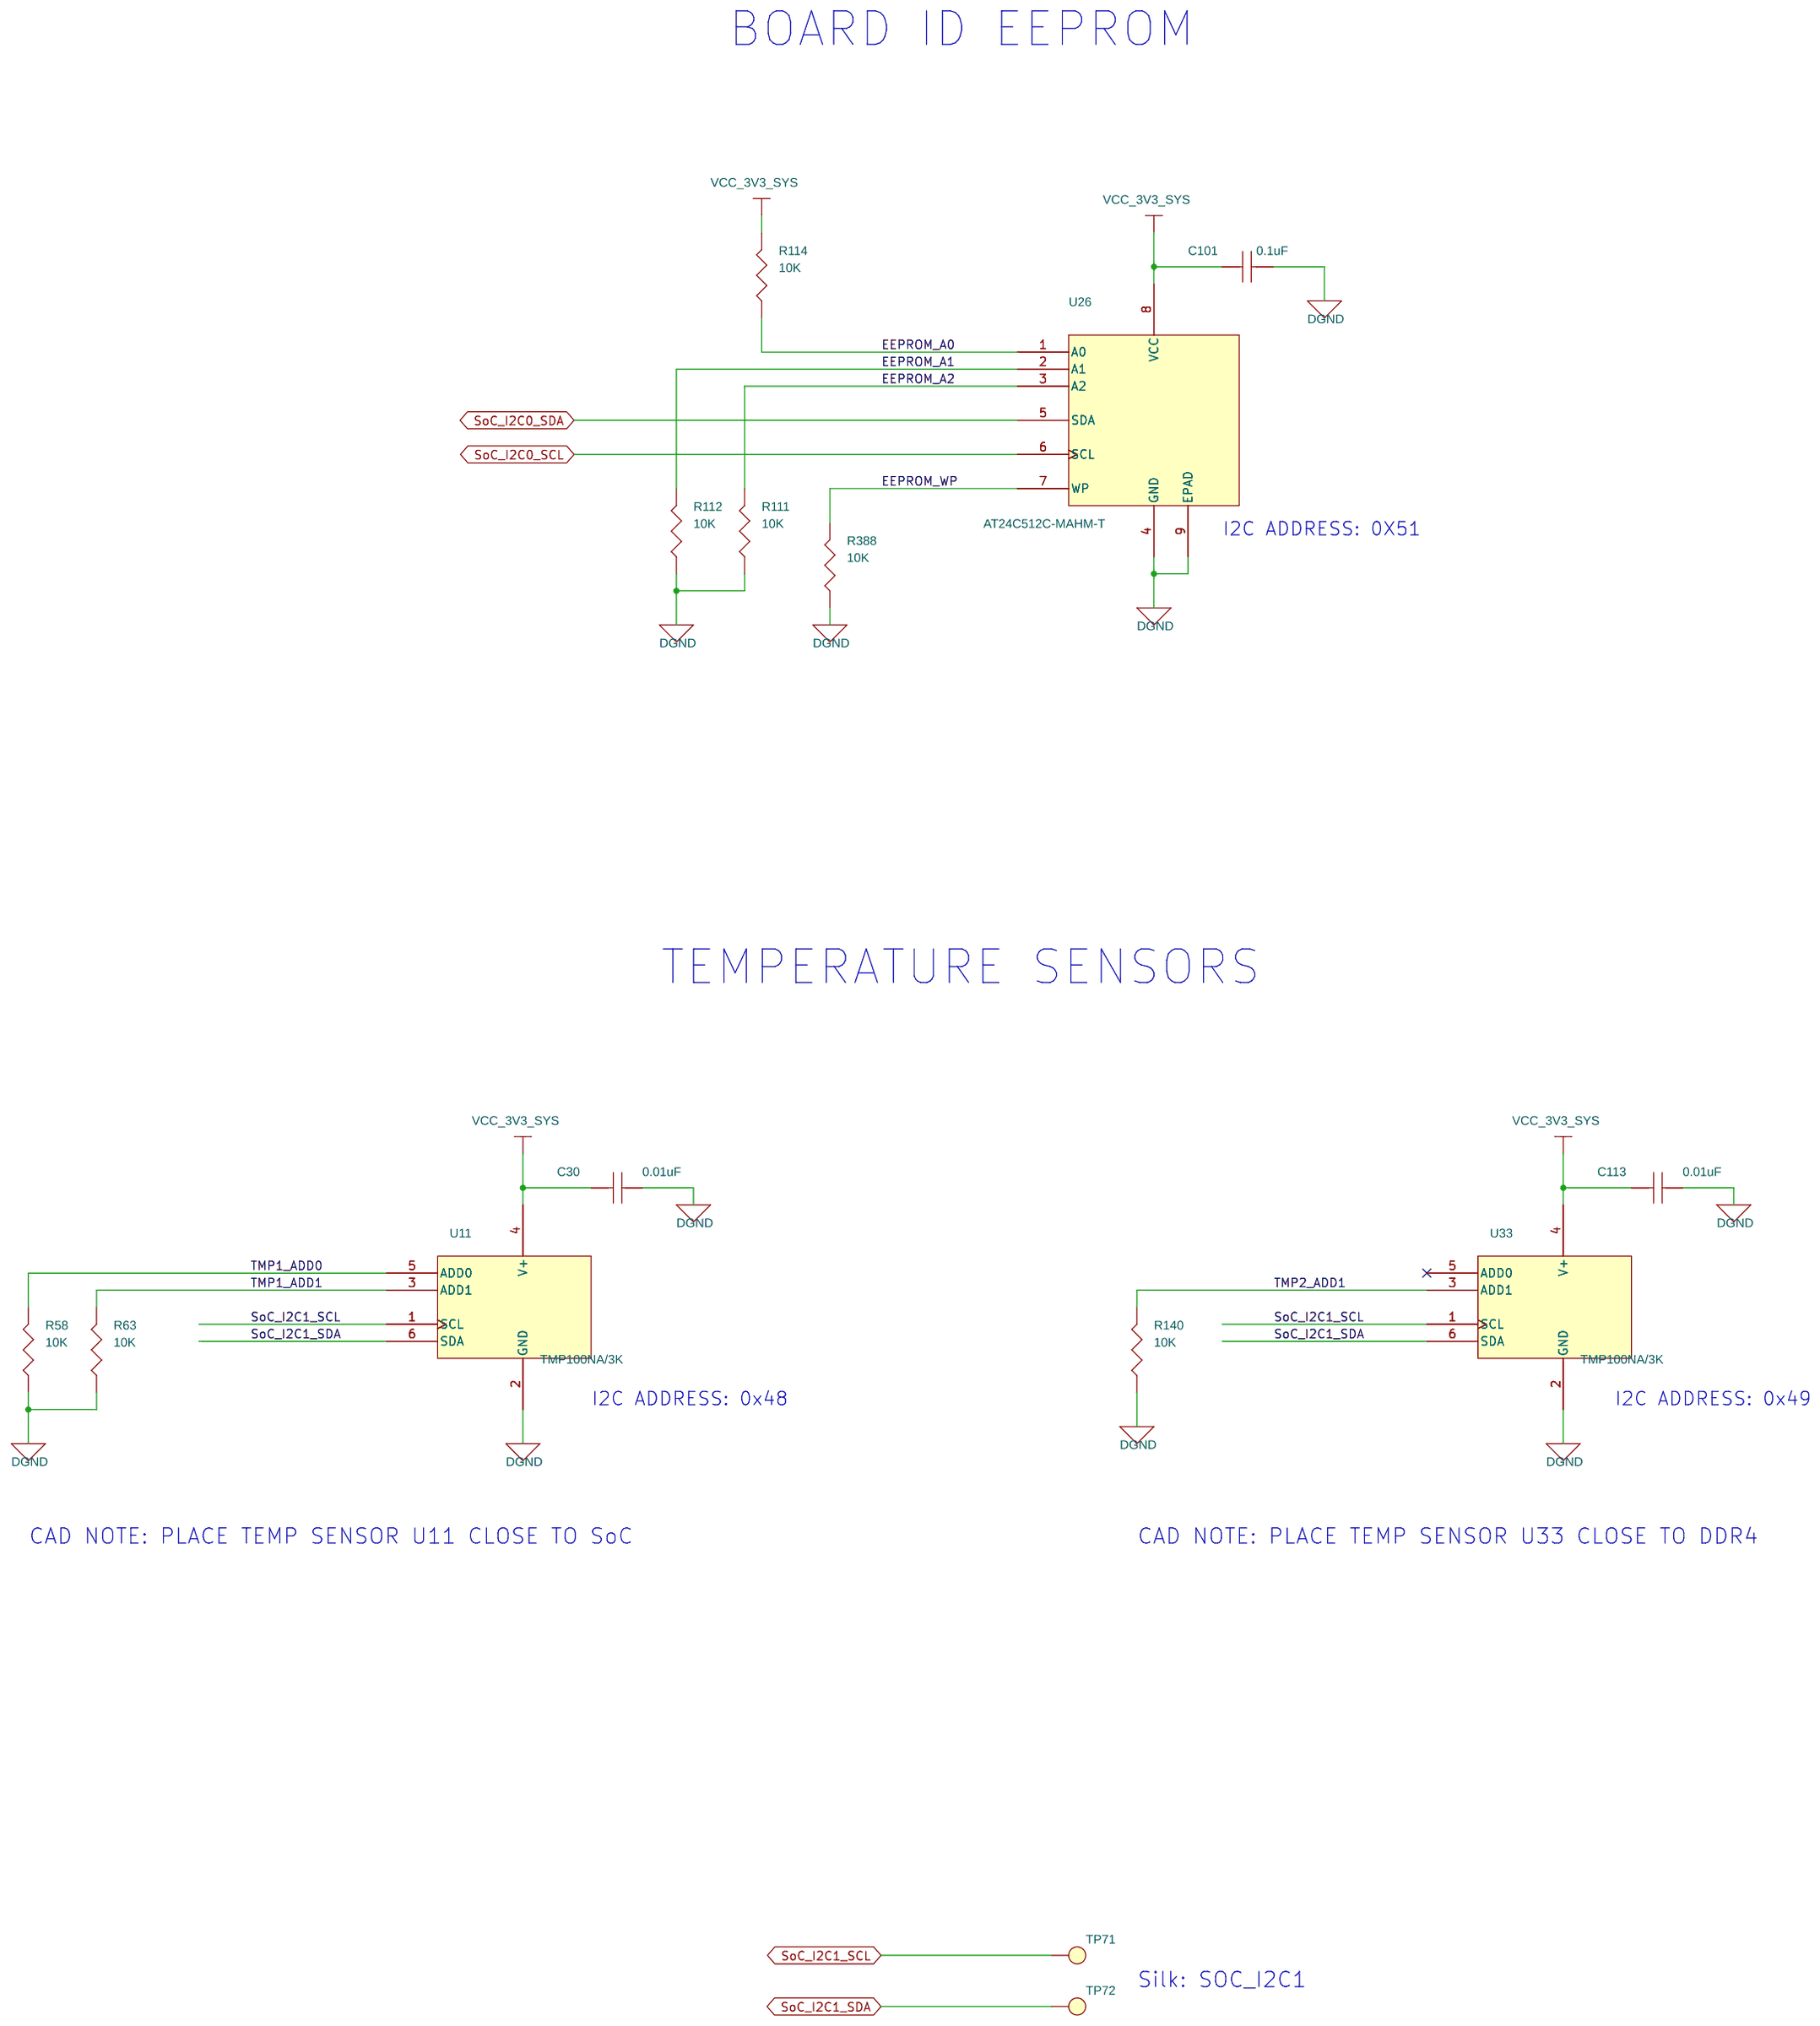
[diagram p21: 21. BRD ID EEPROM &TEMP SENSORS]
23 22. CPSW RGMII_1 ETHERNET PHY: size C; title: CPSW RGMII_1 ETHERNET PHY

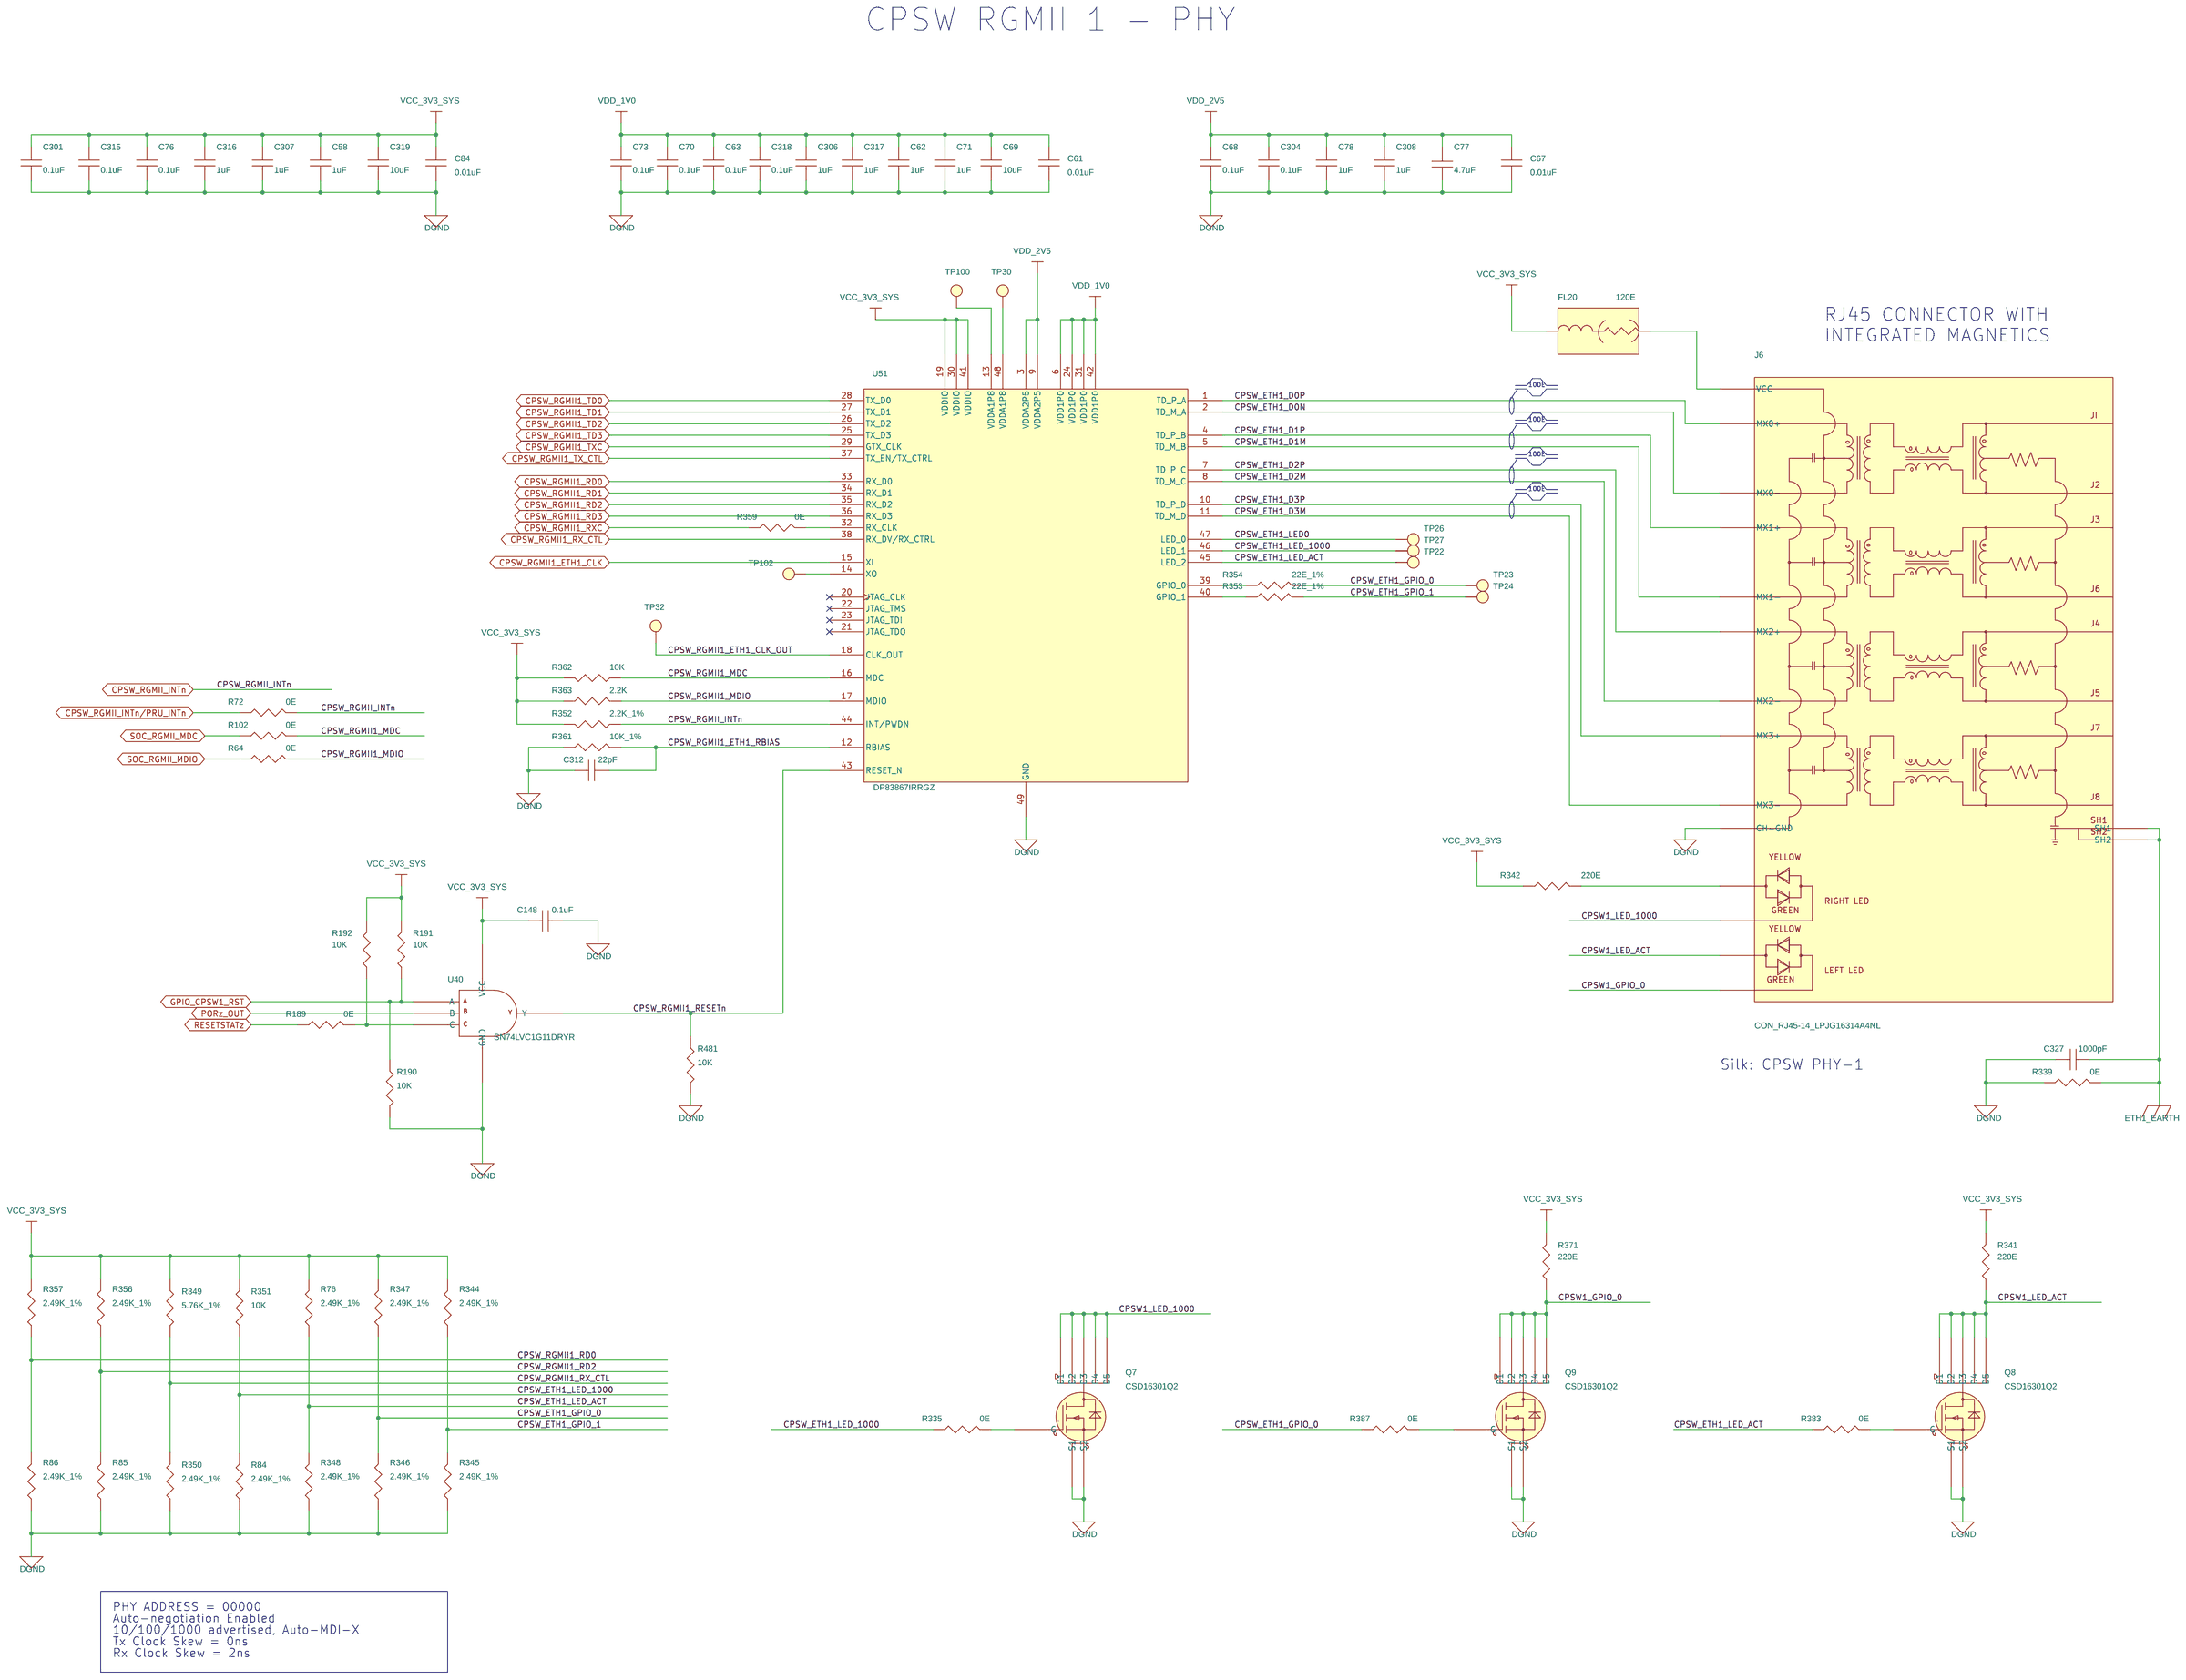
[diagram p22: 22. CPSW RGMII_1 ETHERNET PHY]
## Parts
sheet 20. OSPI INTERFACE
C198  4.7uF  [CAP0402_0-75]
C202  0.1uF  [CAP0402_0-75]
C203  0.1uF  [CAP0402_0-75]
C206  0.1uF  [CAP0402_0-75]
C210  0.1uF  [CAP0402_0-75]
R39  0E  [RES0201_0-5]
R52  0E  [RES0201_0-5]
R53  0E  [RES0201_0-5]
R296  10K  [RES0201_0-5]
R297  10K  [RES0201_0-5]
R303  10K  [RES0201_0-5]
R304  10K  [RES0201_0-5]
R305  1K_1%  [RES0402_0-5]
R306  10K  [RES0201_0-5]
R307  10K  [RES0201_0-5]
R308  10K  [RES0201_0-5]
R309  10K  [RES0201_0-5]
R310  10K  [RES0201_0-5]
R312  0E  [RES0402_0-5]
R313  10K  [RES0201_0-5]
R315  100K  [RES0201_0-5]
R317  10K  [RES0201_0-5]
R318  10K  [RES0201_0-5]
R319  10K  [RES0201_0-5]
R320  22E_1%  [RES0201_0-5]
R321  0E  [RES0402_0-5]
RA3  0E  [RESA_EXB_0201-4_0-5]
RA4  0E  [RESA_EXB_0201-4_0-5]
U6  SN74LVC1G08DBVRE4  [SOT23-5]
U9  S28HS512TGABHM010  [BGA24_39-37_240X310_1]
sheet 21. BRD ID EEPROM &TEMP SENSORS
C30  0.01uF  [CAP0201_0-5]
C101  0.1uF  [CAP0402_0-75]
C113  0.01uF  [CAP0201_0-5]
R58  10K  [RES0201_0-5]
R63  10K  [RES0201_0-5]
R111  10K  [RES0201_0-5]
R112  10K  [RES0201_0-5]
R114  10K  [RES0201_0-5]
R140  10K  [RES0201_0-5]
R388  10K  [RES0201_0-5]
TP71  THRU HOLE  [TP_36X22]
TP72  THRU HOLE  [TP_36X22]
U11  TMP100NA/3K  [SOT23-6_1-5]
U26  AT24C512C-MAHM-T  [UDFN8_19-68_120X80_0-6]
U33  TMP100NA/3K  [SOT23-6_1-5]
sheet 22. CPSW RGMII_1 ETHERNET PHY
C58  1uF  [CAP0201_0-5]
C61  0.01uF  [CAP0201_0-5]
C62  1uF  [CAP0201_0-5]
C63  0.1uF  [CAP0201_0-5]
C67  0.01uF  [CAP0201_0-5]
C68  0.1uF  [CAP0201_0-5]
C69  10uF  [CAP0402_0-75]
C70  0.1uF  [CAP0201_0-5]
C71  1uF  [CAP0201_0-5]
C73  0.1uF  [CAP0201_0-5]
C76  0.1uF  [CAP0201_0-5]
C77  4.7uF  [CAP0402_0-75]
C78  1uF  [CAP0201_0-5]
C84  0.01uF  [CAP0201_0-5]
C148  0.1uF  [CAP0201_0-5]
C301  0.1uF  [CAP0201_0-5]
C304  0.1uF  [CAP0201_0-5]
C306  1uF  [CAP0201_0-5]
C307  1uF  [CAP0201_0-5]
C308  1uF  [CAP0201_0-5]
C312  22pF  [CAP0201_0-5]
C315  0.1uF  [CAP0201_0-5]
C316  1uF  [CAP0201_0-5]
C317  1uF  [CAP0201_0-5]
C318  0.1uF  [CAP0201_0-5]
C319  10uF  [CAP0402_0-75]
C327  1000pF  [CAP1206_1-75]
FL20  120E  [EMIFIL_BLM15P_0402]
J6  CON_RJ45-14_LPJG16314A4NL  [CON_RJ45-14_LPJG16314A4NL_S_R_T_13-6]
Q7  CSD16301Q2  [WSON6_CSD13202Q2_80X80_0-8]
Q8  CSD16301Q2  [WSON6_CSD13202Q2_80X80_0-8]
Q9  CSD16301Q2  [WSON6_CSD13202Q2_80X80_0-8]
R64  0E  [RES0402_0-5]
R72  0E  [RES0402_0-5]
R76  2.49K_1%  [RES0402_0-5]
R84  2.49K_1%  [RES0402_0-5]
R85  2.49K_1%  [RES0402_0-5]
R86  2.49K_1%  [RES0402_0-5]
R102  0E  [RES0402_0-5]
R189  0E  [RES0402_0-5]
R190  10K  [RES0201_0-5]
R191  10K  [RES0201_0-5]
R192  10K  [RES0201_0-5]
R335  0E  [RES0402_0-5]
R339  0E  [RES0603_0-75]
R341  220E  [RES0402_0-5]
R342  220E  [RES0402_0-5]
R344  2.49K_1%  [RES0402_0-5]
R345  2.49K_1%  [RES0402_0-5]
R346  2.49K_1%  [RES0402_0-5]
R347  2.49K_1%  [RES0402_0-5]
R348  2.49K_1%  [RES0402_0-5]
R349  5.76K_1%  [RES0402_0-5]
R350  2.49K_1%  [RES0402_0-5]
R351  10K  [RES0201_0-5]
R352  2.2K_1%  [RES0201_0-5]
R353  22E_1%  [RES0201_0-5]
R354  22E_1%  [RES0201_0-5]
R356  2.49K_1%  [RES0402_0-5]
R357  2.49K_1%  [RES0402_0-5]
R359  0E  [RES0402_0-5]
R361  10K_1%  [RES0201_0-5]
R362  10K  [RES0201_0-5]
R363  2.2K  [RES0201_0-5]
R371  220E  [RES0402_0-5]
R383  0E  [RES0402_0-5]
R387  0E  [RES0402_0-5]
R481  10K  [RES0201_0-5]
TP22  TP20_SMD  [TP20_SMD]
TP23  TP20_SMD  [TP20_SMD]
TP24  TP20_SMD  [TP20_SMD]
TP26  TP20_SMD  [TP20_SMD]
TP27  TP20_SMD  [TP20_SMD]
TP30  TP20_SMD  [TP20_SMD]
TP32  TP20_SMD  [TP20_SMD]
TP100  TP20_SMD  [TP20_SMD]
TP102  TP20_SMD  [TP20_SMD]
U40  SN74LVC1G11DRYR  [SON6_SN74LVC2G17_40X60_0-6]
U51  DP83867IRRGZ  [QFN48_19-68_280X280_1]
sheet 29. JTAG BUFFER
U12  XAM6254ATCGGAALW  [BGA425_19-68_510X510_0-7]  (sections A,B,C,D,E,F,G,H,I,J,K,L,M,N,O,P,Q,R)

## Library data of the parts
C77 C198 = CAP: CAP CERAMIC 4.7uF 10V 20% X5R 0402; Chkd/date: MANIRAJA/110718; Crtd /date: ALVY/110718; Custom_Duty: 15%; Customs_HS_Code: 85322990; Distributor_name: DIGIKEY; Distributor_part_number: 490-14306-1-ND; Footprint Path: Y:\MIS_DATABASE\Library\ALTIUM_TOOL\PCB_FOOTPRINTS\Altium_Footprint_Lib.PcbLib; Height: 0.65MM; Library Path: Y:\MIS_DATABASE\Library\ALTIUM_TOOL\SCHEMATICS_PARTS\MS_DISCRETE_Library.schlib; Mfr_name: MURATA; Mfr_part_number: GRM155R61A475MEAAD; Mistral Part No: 120012060002-R; Package: 0402; Part_type: CAPACITORS\CERAMIC; Project: TI_J7SVB_PCIE_ADD-ON-CARD; RoHS: RoHS; Temperature: -55°C+85°C; Tolerance: 20%; Voltage: 10V; Wattage: NA; Weight: 14mg; Datasheet: Y:\MIS_DATABASE\DATASHEETS\CAPACITORS\GRM155R61A475MEAAD.PDF
C101 C202 C203 C206 C210 = CAP: CAP CERAMIC 0.1uF 50V 10% X7R 0402; Alt_Mfr_name: YAGEO AMERICA; Alt_Mfr_part_number: CC0402KRX5R8BB104; Chkd/date: MANIRAJA/261020; Crtd /date: ALVY/211020; Custom_Duty: 15%; Customs_HS_Code: 85322990; Distributor_name: DIGIKEY; Distributor_part_number: 490-10700-1-ND; Footprint Path: Y:\MIS_DATABASE\Library\ALTIUM_TOOL\PCB_FOOTPRINTS\Altium_Footprint_Lib.PcbLib; Height: 0.55MM; Library Path: Y:\MIS_DATABASE\Library\ALTIUM_TOOL\SCHEMATICS_PARTS\MS_DISCRETE_Library.schlib; Mfr_name: MURATA; Mfr_part_number: GRM155R71H104KE14D; Mistral Part No: 120011100014-R; Package: 0402; Part_type: CAPACITORS\CERAMIC; Project: J7_CP; RoHS: RoHS; Temperature: -55°C+125°C; Tolerance: 10%; Voltage: 50V; Wattage: NA; Weight: 3.1mg; Datasheet: Y:\MIS_DATABASE\DATASHEETS\CAPACITORS\GRM155R71H104KE14.PDF
R39 R52 R53 = RESISTOR: RES 0E 1/20W 5% 0201; Chkd/date: NAVEED/301214; Crtd /date: MUDDU/120710; Custom_Duty: 15%; Customs_HS_Code: 85332119; Distributor_name: DIGIKEY; Distributor_part_number: 311-0.0NCT-ND; Footprint Path: Y:\MIS_DATABASE\Library\ALTIUM_TOOL\PCB_FOOTPRINTS\Altium_Footprint_Lib.PcbLib; Height: 0.26MM; Library Path: Y:\MIS_DATABASE\Library\ALTIUM_TOOL\SCHEMATICS_PARTS\MS_DISCRETE_Library.schlib; Mfr_name: YAGEO AMERICA; Mfr_part_number: RC0201JR-070RL; Mistral Part No: 110010070067-R; Package: 0201; Part_type: RESISTORS\FIXED; Project: PB_BUGBASE; RoHS: RoHS; SIGNAL_MODEL: RESISTOR_RES0201_0-5_0E_0E; Temperature: -55°C+125°C; Tolerance: 5%; Voltage: NA; Wattage: 1/20W; Weight: 0.17mg; Datasheet: Y:\MIS_DATABASE\DATASHEETS\RESISTORS\RCXXXXL-SER_MAR18.PDF
R58 R63 R111 R112 R114 R140 R190-R192 R296 R297 R303 R304 R306-R310 R313 R317-R319 R351 R362 R388 R481 = RESISTOR: RES 10K 1/20W 5% 0201; Chkd/date: MANIRAJA/050517; Crtd /date: MANIRAJA/050517; Custom_Duty: 15%; Customs_HS_Code: 85332119; Distributor_name: DIGIKEY; Distributor_part_number: 311-10KNCT-ND; Footprint Path: Y:\MIS_DATABASE\Library\ALTIUM_TOOL\PCB_FOOTPRINTS\Altium_Footprint_Lib.PcbLib; Height: 0.26MM; Library Path: Y:\MIS_DATABASE\Library\ALTIUM_TOOL\SCHEMATICS_PARTS\MS_DISCRETE_Library.schlib; Mfr_name: YAGEO AMERICA; Mfr_part_number: RC0201JR-0710KL; Mistral Part No: 110010070051-R; Package: 0201; Part_type: RESISTORS\FIXED; Project: GOLDEN-I LITE; RoHS: RoHS; Temperature: -55°C+125°C; Tolerance: 5%; Voltage: NA; Wattage: 1/20W; Weight: 0.17mg; Datasheet: Y:\MIS_DATABASE\DATASHEETS\RESISTORS\RCXXXXL-SER_MAR18.PDF
R305 = RESISTOR: RES 1K 1/10W 1% 0402; Chkd/date: VASANTHA/281216; Crtd /date: MAZHAR/150506; Custom_Duty: 15%; Customs_HS_Code: 85332119; Distributor_name: DIGIKEY; Distributor_part_number: P1.00KLCT-ND; Footprint Path: Y:\MIS_DATABASE\Library\ALTIUM_TOOL\PCB_FOOTPRINTS\Altium_Footprint_Lib.PcbLib; Height: 0.40MM; Library Path: Y:\MIS_DATABASE\Library\ALTIUM_TOOL\SCHEMATICS_PARTS\MS_DISCRETE_Library.schlib; Mfr_name: PANASONIC-ECG; Mfr_part_number: ERJ-2RKF1001X; Mistral Part No: 110009030411-R; Package: 0402; Part_type: RESISTORS\FIXED; Project: VOCERA; RoHS: RoHS; Temperature: -55°C+155°C; Tolerance: 1%; Voltage: NA; Wattage: 1/10W; Weight: 0.8mg; Datasheet: Y:\MIS_DATABASE\DATASHEETS\RESISTORS\PAN-ERJSER_NOV17.PDF
R312 R359 = RESISTOR: RES 0E 1/16W JUMPER 0402; Chkd/date: VASANTHA/201216; Crtd /date: MUDDU/190810; Custom_Duty: 15%; Customs_HS_Code: 85332119; Distributor_name: DIGIKEY; Distributor_part_number: 541-0.0JCT-ND; Footprint Path: Y:\MIS_DATABASE\Library\ALTIUM_TOOL\PCB_FOOTPRINTS\Altium_Footprint_Lib.PcbLib; Height: 0.40MM; Library Path: Y:\MIS_DATABASE\Library\ALTIUM_TOOL\SCHEMATICS_PARTS\MS_DISCRETE_Library.schlib; Mfr_name: VISHAY; Mfr_part_number: CRCW04020000Z0ED; Mistral Part No: 110010080019-R; Package: 0402; Part_type: RESISTORS\FIXED; Project: PB_BUGBASE; RoHS: RoHS; SIGNAL_MODEL: RESISTOR_RES0402_0-5_0E_0E; Temperature: -55°C+155°C; Tolerance: NA; Voltage: NA; Wattage: 1/16W; Weight: 0.65mg; Datasheet: Y:\MIS_DATABASE\DATASHEETS\RESISTORS\CRCW0603.PDF
R315 = RESISTOR: RES 100K 1/20W 5% 0201; Chkd/date: VASANTHA/061216; Crtd /date: MAZHAR/141105; Custom_Duty: 15%; Customs_HS_Code: 85332119; Distributor_name: DIGIKEY; Distributor_part_number: P100KAGCT-ND; Footprint Path: Y:\MIS_DATABASE\Library\ALTIUM_TOOL\PCB_FOOTPRINTS\Altium_Footprint_Lib.PcbLib; Height: 0.26MM; Library Path: Y:\MIS_DATABASE\Library\ALTIUM_TOOL\SCHEMATICS_PARTS\MS_DISCRETE_Library.schlib; Mfr_name: PANASONIC-ECG; Mfr_part_number: ERJ-1GEJ104C; Mistral Part No: 110009030176-R; Package: 0201; Part_type: RESISTORS\FIXED; Project: J30; RoHS: RoHS; Temperature: -55°C+125°C; Tolerance: 5%; Voltage: NA; Wattage: 1/20W; Weight: 0.15mg; Datasheet: Y:\MIS_DATABASE\DATASHEETS\RESISTORS\PAN-ERJXGE-FEB06.PDF
R320 = RESISTOR: RES 22E 1/20W 1% 0201; Chkd/date: MAZHAR/140709; Crtd /date: MAZHAR/220807; Custom_Duty: 15%; Customs_HS_Code: 85332119; Distributor_name: DIGIKEY; Distributor_part_number: P22.0ABCT-ND; Footprint Path: Y:\MIS_DATABASE\Library\ALTIUM_TOOL\PCB_FOOTPRINTS\Altium_Footprint_Lib.PcbLib; Height: 0.26MM; Library Path: Y:\MIS_DATABASE\Library\ALTIUM_TOOL\SCHEMATICS_PARTS\MS_DISCRETE_Library.schlib; Mfr_name: PANASONIC-ECG; Mfr_part_number: ERJ-1GEF22R0C; Mistral Part No: 110009030522-R; Package: 0201; Part_type: RESISTORS\FIXED; Project: V8TS; RoHS: RoHS; SIGNAL_MODEL: RESISTOR_RES0201_0-5_22E_1%_22E_1%; Temperature: -55°C+125°C; Tolerance: 1%; Voltage: NA; Wattage: 1/20W; Weight: 0.15mg; Datasheet: Y:\MIS_DATABASE\DATASHEETS\RESISTORS\PAN-ERJSER_NOV17.PDF
R64 R72 R102 R189 R321 R335 R383 R387 = RESISTOR: RES 0E 1/16W JUMPER 0402; Chkd/date: VASANTHA/201216; Crtd /date: MUDDU/190810; Custom_Duty: 15%; Customs_HS_Code: 85332119; Distributor_name: DIGIKEY; Distributor_part_number: 541-0.0JCT-ND; Footprint Path: Y:\MIS_DATABASE\Library\ALTIUM_TOOL\PCB_FOOTPRINTS\Altium_Footprint_Lib.PcbLib; Height: 0.40MM; Library Path: Y:\MIS_DATABASE\Library\ALTIUM_TOOL\SCHEMATICS_PARTS\MS_DISCRETE_Library.schlib; Mfr_name: VISHAY; Mfr_part_number: CRCW04020000Z0ED; Mistral Part No: 110010080019-R; Package: 0402; Part_type: RESISTORS\FIXED; Project: PB_BUGBASE; RoHS: RoHS; Temperature: -55°C+155°C; Tolerance: NA; Voltage: NA; Wattage: 1/16W; Weight: 0.65mg; Datasheet: Y:\MIS_DATABASE\DATASHEETS\RESISTORS\CRCW0603.PDF
RA3 RA4 = RESARR_ISO4: RES ARRAY 0E 31mW JUMPER 0201-4; Chkd/date: MANIRAJA/290918; Crtd /date: MANIRAJA/290918; Custom_Duty: 15%; Customs_HS_Code: 85332119; Distributor_name: DIGIKEY; Distributor_part_number: Y6000CT-ND; Footprint Path: Y:\MIS_DATABASE\Library\ALTIUM_TOOL\PCB_FOOTPRINTS\Altium_Footprint_Lib.PcbLib; Height: 0.45MM; Library Path: Y:\MIS_DATABASE\Library\ALTIUM_TOOL\SCHEMATICS_PARTS\MS_DISCRETE_Library.schlib; Manufacturer: PANASONIC-ECG; Mfr_part_number: EXB-18VR000X; Mistral Part No: 110018090033-R; Package: 0201-4; Part_type: RESISTORS\ARRAY; Project: TI_60GHz-AOP; RoHS: RoHS; Temperature: -55°C+125°C; Tolerance: NA; Voltage: NA; Wattage: 31mW; Weight: 1mg; Datasheet: Y:\MIS_DATABASE\DATASHEETS\RESISTORS\EXB-18V.PDF
U6 = SN74LVC1G08DBVRE4_SOT23-5: IC SINGLE 2-INPUT POSITIVE AND GATE SOT23-5; Chkd/date: SUHAS/221010; Crtd /date: USMAN/151008; Custom_Duty: 15%; Customs_HS_Code: 85423100; Distributor_name: DIGIKEY; Distributor_part_number: SN74LVC1G08DBVRE4-ND; Height: 1.45MM; Mfr_name: TEXAS INSTRUMENTS; Mistral Part No: 141009060026-R; Part_type: ICS\DIGITAL\GATES; Project: KHAN_MAIN; RoHS: Sb/ Br FREE; Temperature: -40°C+85°C; Datasheet: Y:\MIS_DATABASE\DATASHEETS\ICS\DIGITAL\GATES\SN74LVC1G08.PDF
U9 = S28HS512T_BGA24: IC 1.8V 512Mb SEMPER FLASH WITH OCTAL INTERFACE BGA24; Chkd/date: MANIRAJA/170120; Crtd /date: ALVY/170120; Custom_Duty: 15%; Customs_HS_Code: 85423100; Distributor_name: NA; Distributor_part_number: NA; Footprint Path: Y:\MIS_DATABASE\Library\ALTIUM_TOOL\PCB_FOOTPRINTS\Altium_Footprint_Lib.PcbLib; Height: 1.00MM; Library Path: Y:\MIS_DATABASE\Library\ALTIUM_TOOL\SCHEMATICS_PARTS\MS_MISCMEMORY_Library.schlib; Mfr_name: CYPRESS SEMICONDUCTOR; Mistral Part No: 141120010002; Package: BGA24; Part_type: ICS\DIGITAL\MEMORY; Project: J7VCL_SOM DUAL LEO PMIC; RoHS: NA; Temperature: -40°C+125°C; Tolerance: NA; Voltage: NA; Wattage: NA; Weight: NA; Datasheet: Y:\MIS_DATABASE\DATASHEETS\ICS\MEMORY\S28HS512T.PDF
C30 C61 C67 C84 C113 = CAP: CAP CERAMIC 0.01uF 25V 10% X5R 0201; Chkd/date: MANIRAJA/230118; Crtd /date: MANIRAJA/230118; Custom_Duty: 15%; Customs_HS_Code: 85322990; Distributor_name: DIGIKEY; Distributor_part_number: GRM033R61E103KA12J-ND; Footprint Path: Y:\MIS_DATABASE\Library\ALTIUM_TOOL\PCB_FOOTPRINTS\Altium_Footprint_Lib.PcbLib; Height: 0.33MM; Library Path: Y:\MIS_DATABASE\Library\ALTIUM_TOOL\SCHEMATICS_PARTS\MS_DISCRETE_Library.schlib; Mfr_name: MURATA; Mfr_part_number: GRM033R61E103KA12J; Mistral Part No: 120018010007-R; Package: 0201; Part_type: CAPACITORS\CERAMIC; Project: TI_MAXIE_CPB; RoHS: RoHS; Temperature: -55°C+85°C; Tolerance: 10%; Voltage: 25V; Wattage: NA; Weight: 0.33mg; Datasheet: Y:\MIS_DATABASE\DATASHEETS\CAPACITORS\GRM033R61E103KA12.PDF
TP71 TP72 = TESTPOINT: TESTPOINT 0.56MM DRILL PTH; Chkd/date: BAVISH/040311; Crtd /date: MAZHAR/110405; Distributor_name: NA; Distributor_part_number: NA; Height: NA; Mfr_name: LOCAL; Mistral Part No: 130010010008; Package: THRU-HOLE; Project: KOPIN_MODULS; Temperature: NA; Tolerance: NA; Voltage: NA; Wattage: NA; Weight: NA; Datasheet: NA
U11 U33 = TMP100NA_3K_SOT23-6: IC TEMPERATURE SENSOR WITH I2C AND SMBUS INTERFACE SOT23-6; Chkd/date: MANIRAJA/290817; Crtd /date: MANIRAJA/290817; Custom_Duty: 15%; Customs_HS_Code: 85423100; Distributor_name: DIGIKEY; Distributor_part_number: 296-26833-1-ND; Height: 1.45MM; Library Ref: TMP100NA/3K_SOT23-6; Mfr_name: TEXAS INSTRUMENTS; Mistral Part No: 141017080030-R; Package: SOT23-6; Part_type: ICS\DIGITAL\PERIPHERAL; Project: TI_MAXIE_CPB; RoHS: RoHS; Temperature: -55°C+125°C; Tolerance: NA; Voltage: NA; Wattage: NA; Weight: 120mg; Datasheet: Y:\MIS_DATABASE\DATASHEETS\ICS\DIGITAL\PERIPHERAL\TMP10XX.PDF
U26 = AT24C64D-MAHM-T_UDFN8: IC 1.7-3.6V 512Kb I2C COMPATIBLE SERIAL EEPROM UDFN8; Chkd/date: MANIRAJA/240919; Crtd /date: ALVY/240919; Custom_Duty: 15%; Customs_HS_Code: 85423100; Distributor_name: DIGIKEY; Distributor_part_number: AT24C512C-MAHM-TCT-ND; Footprint Path: Y:\MIS_DATABASE\Library\ALTIUM_TOOL\PCB_FOOTPRINTS\Altium_Footprint_Lib.PcbLib; Height: 0.60MM; Library Path: Y:\MIS_DATABASE\Library\ALTIUM_TOOL\SCHEMATICS_PARTS\MS_MISCMEMORY_Library.schlib; Mfr_name: MICROCHIP; Mistral Part No: 141119090004-R; Package: UDFN8; Part_type: ICS\DIGITAL\MEMORY; Project: HAL_3U-T1042-SBC; RoHS: RoHS; Temperature: -40°C+85°C; Tolerance: NA; Voltage: NA; Wattage: NA; Weight: 9.5mg; Datasheet: Y:\MIS_DATABASE\DATASHEETS\ICS\MEMORY\AT24C512C.PDF
C58 C62 C71 C78 C306-C308 C316 C317 = CAP: CAP CERAMIC 1uF 16V 20% X5R 0201; Chkd/date: MANIRAJA/300520; Crtd /date: ALVY/260520; Custom_Duty: 15%; Customs_HS_Code: 85322990; Distributor_name: DIGIKEY; Distributor_part_number: 490-18654-1-ND; Footprint Path: Y:\MIS_DATABASE\Library\ALTIUM_TOOL\PCB_FOOTPRINTS\Altium_Footprint_Lib.PcbLib; Height: 0.39MM; Library Path: Y:\MIS_DATABASE\Library\ALTIUM_TOOL\SCHEMATICS_PARTS\MS_DISCRETE_Library.schlib; Mfr_name: MURATA; Mfr_part_number: GRM033R61C105ME15D; Mistral Part No: 120018090038-R; Package: 0201; Part_type: CAPACITORS\CERAMIC; Project: QCS610_NANOSOM; RoHS: RoHS; Temperature: -55°C+85°C; Tolerance: 20%; Voltage: 16V; Wattage: NA; Weight: 0.33mg; Datasheet: Y:\MIS_DATABASE\DATASHEETS\CAPACITORS\GRM033R61C105ME15.PDF
C63 C68 C70 C73 C76 C148 C301 C304 C315 C318 = CAP: CAP CERAMIC 0.1uF 16V 10% X5R 0201; Alt_Mfr_name: YAGEO AMERICA; Alt_Mfr_part_number: CC0402KRX5R8BB104; Chkd/date: MANIRAJA/230118; Crtd /date: MANIRAJA/230118; Custom_Duty: 15%; Customs_HS_Code: 85322990; Distributor_name: DIGIKEY; Distributor_part_number: 490-14305-1-ND; Footprint Path: Y:\MIS_DATABASE\Library\ALTIUM_TOOL\PCB_FOOTPRINTS\Altium_Footprint_Lib.PcbLib; Height: 0.33MM; Library Path: Y:\MIS_DATABASE\Library\ALTIUM_TOOL\SCHEMATICS_PARTS\MS_DISCRETE_Library.schlib; Mfr_name: MURATA; Mfr_part_number: GRM033R61C104KE14D; Mistral Part No: 120009030072-R; Package: 0201; Part_type: CAPACITORS\CERAMIC; Project: TI_MAXIE_CPB; RoHS: RoHS; Temperature: -55°C+85°C; Tolerance: 10%; Voltage: 16V; Wattage: NA; Weight: 0.33mg; Datasheet: Y:\MIS_DATABASE\DATASHEETS\CAPACITORS\GRM033R61C104KE14.PDF
C69 C319 = CAP: CAP CERAMIC 10uF 10V 20% X5R 0402; Chkd/date: MANIRAJA/300520; Crtd /date: ALVY/260520; Custom_Duty: 15%; Customs_HS_Code: 85322990; Distributor_name: DIGIKEY; Distributor_part_number: 490-GRM155R61A106ME11DTR-ND; Footprint Path: Y:\MIS_DATABASE\Library\ALTIUM_TOOL\PCB_FOOTPRINTS\Altium_Footprint_Lib.PcbLib; Height: 0.55MM; Library Path: Y:\MIS_DATABASE\Library\ALTIUM_TOOL\SCHEMATICS_PARTS\MS_DISCRETE_Library.schlib; Mfr_name: MURATA; Mfr_part_number: GRM155R61A106ME11D; Mistral Part No: 120013110019-R; Package: 0402; Part_type: CAPACITORS\CERAMIC; Project: QCS610_NANOSOM; RoHS: RoHS; Temperature: -55°C+85°C; Tolerance: 20%; Voltage: 10V; Wattage: NA; Weight: 3.1mg; Datasheet: Y:\MIS_DATABASE\DATASHEETS\CAPACITORS\MURATA-GXX-SER_NOV17.PDF
C312 = CAP: CAP CERAMIC 22pF 25V 1% C0G(NP0) 0201; Chkd/date: MANIRAJA/270721; Crtd /date: ALVY/260721; Custom_Duty: 15%; Customs_HS_Code: 85322990; Distributor_name: DIGIKEY; Distributor_part_number: 490-14545-1-ND; Footprint Path: Y:\MIS_DATABASE\Library\ALTIUM_TOOL\PCB_FOOTPRINTS\Altium_Footprint_Lib.PcbLib; Height: 0.33MM; Library Path: Y:\MIS_DATABASE\Library\ALTIUM_TOOL\SCHEMATICS_PARTS\MS_DISCRETE_Library.schlib; Mfr_name: MURATA; Mfr_part_number: GRM0335C1E220FA01D; Mistral Part No: 120021070019-R; Package: 0201; Part_type: CAPACITORS\CERAMIC; Project: TI_AM335x SK_BRD; RoHS: RoHS; Temperature: -55°C+125°C; Tolerance: 1%; Voltage: 25V; Wattage: NA; Weight: 0.33mg; Datasheet: Y:\MIS_DATABASE\DATASHEETS\CAPACITORS\GRM0335C1E220FA01.PDF
C327 = CAP: CAP CERAMIC 1000pF 2KV 10% X7R 1206; Chkd/date: SHREESHAIL/291106; Crtd /date: MAZHAR/281106; Custom_Duty: 15%; Customs_HS_Code: 85322990; Distributor_name: DIGIKEY; Distributor_part_number: 478-2956-1-ND; Footprint Path: Y:\MIS_DATABASE\Library\ALTIUM_TOOL\PCB_FOOTPRINTS\Altium_Footprint_Lib.PcbLib; Height: 1.52MM; Library Path: Y:\MIS_DATABASE\Library\ALTIUM_TOOL\SCHEMATICS_PARTS\MS_DISCRETE_Library.schlib; Mfr_name: AVX CORPORATION; Mfr_part_number: 1206GC102KAT1A; Mistral Part No: 120015080006-R; Package: 1206; Part_type: CAPACITORS\CERAMIC; Project: ADR1B; RoHS: RoHS; Temperature: -55°C+125°C; Tolerance: 10%; Voltage: 2KV; Wattage: NA; Weight: 16.2mg; Datasheet: Y:\MIS_DATABASE\DATASHEETS\CAPACITORS\AVX_HV-MLC.PDF
FL20 = EMIFILTER_IND: FERRITE CHIP 120E 2A 0402; Chkd/date: NAVEED/241114; Crtd /date: USMAN/170613; Custom_Duty: 24%; Customs_HS_Code: 85369090; Distributor_name: MOUSER; Distributor_part_number: 81-BLM15PX121SN1D; Height: 0.55MM; Mfr_name: MURATA; Mfr_part_number: BLM15PX121SN1D; Mistral Part No: 130013060022-R; Package: 0402; Part_type: FILTER; Project: GEN_3-8; RoHS: RoHS; Temperature: -55°C+125°C; Tolerance: 25%; Voltage: NA; Wattage: NA; Weight: NA; Datasheet: Y:\MIS_DATABASE\DATASHEETS\DISCRETES\INDUCTORS\BLM15X.PDF
J6 = CON_RJ45-14_LPJG16314A4NL: CON RJ-45 FEMALE 14POS RT TH; Chkd/date: VASANTHA/150714; Crtd /date: BALACHANDAR/120614; Custom_Duty: 24%; Customs_HS_Code: 85369090; Distributor_name: NA; Distributor_part_number: NA; Footprint Path: Y:\MIS_DATABASE\Library\ALTIUM_TOOL\PCB_FOOTPRINTS\Altium_Footprint_Lib.PcbLib; Height: 13.60MM; Library Path: Y:\MIS_DATABASE\Library\ALTIUM_TOOL\SCHEMATICS_PARTS\MS_CONNECTOR_Library.schlib; Mfr_name: LINK-PP; Mfr_part_number: LPJG16314A4NL; Mistral Part No: 150014060029-R; Package: THRU-HOLE; Part_type: CONNECTOR\JACK; Project: AEGIS; RoHS: RoHS; Temperature: -0°C+70°C; Tolerance: NA; Voltage: NA; Wattage: NA; Weight: NA; Datasheet: Y:\MIS_DATABASE\DATASHEETS\CONNECTORS\LPJG16314A4NL.PDF
Q7-Q9 = MOSFET_CSD17313Q2: IC MOSFET N-CHANNEL NEXFET 25V WSON6; Chkd/date: ALVY/071220; Crtd /date: MANIRAJA/071220; Custom_Duty: 15%; Customs_HS_Code: 85423100; Distributor_name: DIGIKEY; Distributor_part_number: 296-25260-1-ND; Footprint Path: Y:\MIS_DATABASE\Library\ALTIUM_TOOL\PCB_FOOTPRINTS\Altium_Footprint_Lib.PcbLib; Height: 0.80MM; Library Path: Y:\MIS_DATABASE\Library\ALTIUM_TOOL\SCHEMATICS_PARTS\MS_MOSFET_Library.schlib; Mfr_name: TEXAS INSTRUMENTS; Mistral Part No: 142020120008-R; Package: WSON6; Part_type: ICS\POWER\MOSFET; Project: TI_AM243x LP EVM; RoHS: RoHS; Temperature: -55°C+150°C; Tolerance: NA; Voltage: NA; Wattage: NA; Weight: 8.7mg; Datasheet: Y:\MIS_DATABASE\DATASHEETS\ICS\POWER\CSD16301Q2.PDF
R76 R84-R86 R344-R348 R350 R356 R357 = RESISTOR: RES 2.49K 1/16W 1% 0402; Chkd/date: VASANTHA/270516; Crtd /date: VASANTHA/270516; Custom_Duty: 15%; Customs_HS_Code: 85332119; Distributor_name: DIGIKEY; Distributor_part_number: 311-2.49KLRCT-ND; Footprint Path: Y:\MIS_DATABASE\Library\ALTIUM_TOOL\PCB_FOOTPRINTS\Altium_Footprint_Lib.PcbLib; Height: 0.40MM; Library Path: Y:\MIS_DATABASE\Library\ALTIUM_TOOL\SCHEMATICS_PARTS\MS_DISCRETE_Library.schlib; Mfr_name: YAGEO AMERICA; Mfr_part_number: RC0402FR-072K49L; Mistral Part No: 110016050020-R; Package: 0402; Part_type: RESISTORS\FIXED; Project: TMDXCSKCC; RoHS: RoHS; Temperature: -55°C+155°C; Tolerance: 1%; Voltage: NA; Wattage: 1/16W; Weight: 0.65mg; Datasheet: Y:\MIS_DATABASE\DATASHEETS\RESISTORS\RCXXXXL-SER_MAR18.PDF
R339 = RESISTOR: RES 0E 1/10W 5% 0603; Chkd/date: MANIRAJA/051217; Crtd /date: BAVISH/180211; Custom_Duty: 15%; Customs_HS_Code: 85332119; Distributor_name: DIGIKEY; Distributor_part_number: 311-0.0GRCT-ND; Footprint Path: Y:\MIS_DATABASE\Library\ALTIUM_TOOL\PCB_FOOTPRINTS\Altium_Footprint_Lib.PcbLib; Height: 0.55MM; Library Path: Y:\MIS_DATABASE\Library\ALTIUM_TOOL\SCHEMATICS_PARTS\MS_DISCRETE_Library.schlib; Manufacturer: YAGEO AMERICA; Mfr_name: PANASONIC-ECG; Mfr_part_number: RC0603JR-070RL; Mistral Part No: 110011020013-R; Package: 0603; Part_type: RESISTORS\FIXED; Project: KENNEL; RoHS: RoHS; Temperature: -55°C+155°C; Tolerance: 5%; Voltage: NA; Wattage: 1/10W; Weight: 2mg; Datasheet: Y:\MIS_DATABASE\DATASHEETS\RESISTORS\RCXXXXL-SER_MAR18.PDF
R341 R342 R371 = RESISTOR: RES 220E 1/10W 5% 0402; Chkd/date: VASANTHA/291216; Crtd /date: GEETHA/260406; Custom_Duty: 15%; Customs_HS_Code: 85332119; Distributor_name: DIGIKEY; Distributor_part_number: P220JCT-ND; Footprint Path: Y:\MIS_DATABASE\Library\ALTIUM_TOOL\PCB_FOOTPRINTS\Altium_Footprint_Lib.PcbLib; Height: 0.40MM; Library Path: Y:\MIS_DATABASE\Library\ALTIUM_TOOL\SCHEMATICS_PARTS\MS_DISCRETE_Library.schlib; Mfr_name: PANASONIC-ECG; Mfr_part_number: ERJ-2GEJ221X; Mistral Part No: 110009030506-R; Package: 0402; Part_type: RESISTORS\FIXED; Project: RED EYE; RoHS: RoHS; Temperature: -55°C+155°C; Tolerance: 5%; Voltage: NA; Wattage: 1/10W; Weight: 0.8mg; Datasheet: Y:\MIS_DATABASE\DATASHEETS\RESISTORS\PAN-ERJSER_NOV17.PDF
R349 = RESISTOR: RES 5.76K 1/10W 1% 0402; Chkd/date: MAZHAR/150709; Crtd /date: USMAN/220808; Custom_Duty: 15%; Customs_HS_Code: 85332119; Distributor_name: DIGIKEY; Distributor_part_number: P5.76KLCT-ND; Footprint Path: Y:\MIS_DATABASE\Library\ALTIUM_TOOL\PCB_FOOTPRINTS\Altium_Footprint_Lib.PcbLib; Height: 0.40MM; Library Path: Y:\MIS_DATABASE\Library\ALTIUM_TOOL\SCHEMATICS_PARTS\MS_DISCRETE_Library.schlib; Mfr_name: PANASONIC-ECG; Mfr_part_number: ERJ-2RKF5761X; Mistral Part No: 110009030945-R; Package: 0402; Part_type: RESISTORS\FIXED; Project: CPB; RoHS: RoHS; Temperature: -55°C+155°C; Tolerance: 1%; Voltage: NA; Wattage: 1/10W; Weight: 0.8mg; Datasheet: Y:\MIS_DATABASE\DATASHEETS\RESISTORS\PAN-ERJSER_NOV17.PDF
R352 = RESISTOR: RES 2.2K 1/20W 1% 0201; Chkd/date: VASANTHA/270117; Crtd /date: MANIRAJA/270117; Custom_Duty: 15%; Customs_HS_Code: 85332119; Distributor_name: DIGIKEY; Distributor_part_number: YAG2572CT-ND; Footprint Path: Y:\MIS_DATABASE\Library\ALTIUM_TOOL\PCB_FOOTPRINTS\Altium_Footprint_Lib.PcbLib; Height: 0.26MM; Library Path: Y:\MIS_DATABASE\Library\ALTIUM_TOOL\SCHEMATICS_PARTS\MS_DISCRETE_Library.schlib; Manufacturer: YAGEO AMERICA; Mfr_name: PANASONIC-ECG; Mfr_part_number: RC0201FR-072K2L; Mistral Part No: 110017010016-R; Package: 0201; Part_type: RESISTORS\FIXED; Project: GOLDEN-I LITE; RoHS: RoHS; Temperature: -55°C+125°C; Tolerance: 1%; Voltage: NA; Wattage: 1/20W; Weight: 0.17mg; Datasheet: Y:\MIS_DATABASE\DATASHEETS\RESISTORS\RCXXXXL-SER_MAR18.PDF
R353 R354 = RESISTOR: RES 22E 1/20W 1% 0201; Chkd/date: MAZHAR/140709; Crtd /date: MAZHAR/220807; Custom_Duty: 15%; Customs_HS_Code: 85332119; Distributor_name: DIGIKEY; Distributor_part_number: P22.0ABCT-ND; Footprint Path: Y:\MIS_DATABASE\Library\ALTIUM_TOOL\PCB_FOOTPRINTS\Altium_Footprint_Lib.PcbLib; Height: 0.26MM; Library Path: Y:\MIS_DATABASE\Library\ALTIUM_TOOL\SCHEMATICS_PARTS\MS_DISCRETE_Library.schlib; Mfr_name: PANASONIC-ECG; Mfr_part_number: ERJ-1GEF22R0C; Mistral Part No: 110009030522-R; Package: 0201; Part_type: RESISTORS\FIXED; Project: V8TS; RoHS: RoHS; Temperature: -55°C+125°C; Tolerance: 1%; Voltage: NA; Wattage: 1/20W; Weight: 0.15mg; Datasheet: Y:\MIS_DATABASE\DATASHEETS\RESISTORS\PAN-ERJSER_NOV17.PDF
R361 = RESISTOR: RES 10K 1/20W 1% 0201; Chkd/date: VASANTHA/270117; Crtd /date: MANIRAJA/270117; Custom_Duty: 15%; Customs_HS_Code: 85332119; Distributor_name: DIGIKEY; Distributor_part_number: 311-10.0KMCT-ND; Footprint Path: Y:\MIS_DATABASE\Library\ALTIUM_TOOL\PCB_FOOTPRINTS\Altium_Footprint_Lib.PcbLib; Height: 0.26MM; Library Path: Y:\MIS_DATABASE\Library\ALTIUM_TOOL\SCHEMATICS_PARTS\MS_DISCRETE_Library.schlib; Manufacturer: YAGEO AMERICA; Mfr_name: YAGEO AMERICA; Mfr_part_number: RC0201FR-0710KL; Mistral Part No: 110011040018-R; Package: 0201; Part_type: RESISTORS\FIXED; Project: GOLDEN-I LITE; RoHS: RoHS; Temperature: -55°C+125°C; Tolerance: 1%; Voltage: NA; Wattage: 1/20W; Weight: 0.17mg; Datasheet: Y:\MIS_DATABASE\DATASHEETS\RESISTORS\RCXXXXL-SER_MAR18.PDF
R363 = RESISTOR: RES 2.2K 1/20W 5% 0201; Chkd/date: VASANTHA/010117; Crtd /date: MAZHAR/010605; Custom_Duty: 15%; Customs_HS_Code: 85332119; Distributor_name: DIGIKEY; Distributor_part_number: P2.2KAGCT-ND; Footprint Path: Y:\MIS_DATABASE\Library\ALTIUM_TOOL\PCB_FOOTPRINTS\Altium_Footprint_Lib.PcbLib; Height: 0.26MM; Library Path: Y:\MIS_DATABASE\Library\ALTIUM_TOOL\SCHEMATICS_PARTS\MS_DISCRETE_Library.schlib; Mfr_name: PANASONIC-ECG; Mfr_part_number: ERJ-1GEJ222C; Mistral Part No: 110009030427-R; Package: 0201; Part_type: RESISTORS\FIXED; Project: G4SLIM; RoHS: RoHS; Temperature: -55°C+125°C; Tolerance: 5%; Voltage: NA; Wattage: 1/20W; Weight: 0.15mg; Datasheet: Y:\MIS_DATABASE\DATASHEETS\RESISTORS\PAN-ERJXGE-FEB06.PDF
TP22-TP24 TP26 TP27 TP30 TP32 TP100 TP102 = TESTPOINT: TESTPOINT CIR 20 SMD; Chkd/date: SHREESHAIL/171006; Crtd /date: MAZHAR/171006; Custom_Duty: NA; Customs_HS_Code: NA; Distributor_name: NA; Distributor_part_number: NA; Footprint Path: Y:\MIS_DATABASE\Library\ALTIUM_TOOL\PCB_FOOTPRINTS\Altium_Footprint_Lib.PcbLib; Height: NA; Library Path: Y:\MIS_DATABASE\Library\ALTIUM_TOOL\SCHEMATICS_PARTS\MS_DISCRETE_Library.schlib; MECHANICAL 3D STEP FILE: NA; Mfr_name: LOCAL; Mistral Part No: NA; Package: SMD; Project: BT MODULE_CSRBC04; RoHS: NA; Temperature: NA; Tolerance: NA; Voltage: NA; Wattage: NA; Weight: NA; Datasheet: NA
U40 = SN74LVC1G11DCKR_SC70-6: IC SINGLE 3-INPUT POSITIVE-AND GATE SON6; Chkd/date: MANIRAJA/270121; Crtd /date: ALVY/270121; Custom_Duty: 15%; Customs_HS_Code: 85423100; Distributor_name: DIGIKEY; Distributor_part_number: 296-30120-1-ND; Footprint Path: Y:\MIS_DATABASE\Library\ALTIUM_TOOL\PCB_FOOTPRINTS\Altium_Footprint_Lib.PcbLib; Height: 0.60MM; Library Path: Y:\MIS_DATABASE\Library\ALTIUM_TOOL\SCHEMATICS_PARTS\MS_GATE_Library.schlib; Mfr_name: TEXAS INSTRUMENTS; Mistral Part No: 141021010013-R; Package: SON6; Part_type: ICS\DIGITAL\GATES; Project: AM64X_SKEVM; RoHS: RoHS; Temperature: -40°C+125°C; Tolerance: NA; Voltage: NA; Wattage: NA; Weight: 33mg; Datasheet: Y:\MIS_DATABASE\DATASHEETS\ICS\DIGITAL\GATES\SN74LVC1G_NOV16.PDF
U51 = DP83867IRRGZ_VQFN48: IC HIGH IMMUNITY 10/100/1000 Mb/s ETHERNET PHY LAYER TRANSCEIVER VQFN48; Chkd/date: MANIRAJA/110817; Crtd /date: MANIRAJA/110817; Custom_Duty: 15%; Customs_HS_Code: 85423100; Distributor_name: DIGIKEY; Distributor_part_number: DP83867IRRGZT-ND; Height: 1.00MM; Mfr_name: TEXAS INSTRUMENTS; Mistral Part No: 143017080002-R; Package: VQFN48; Part_type: ICS\TELECOM\TRANSCEIVER; Project: TI_SVB_CONTROLLER CARD; RoHS: RoHS; Temperature: -40°C+85°C; Tolerance: NA; Voltage: NA; Wattage: NA; Weight: NA; Datasheet: Y:\MIS_DATABASE\DATASHEETS\ICS\DIGITAL\BUSTRANSCEIVER\DP83867I.PDF
U12 = AM62-EVM_BGA425: IC AM62 SoC MICROPROCESSOR BGA425; Chkd/date: ALVY/110621; Crtd /date: MANIRAJA/110621; Custom_Duty: 15%; Customs_HS_Code: 85423100; Distributor_name: NA; Distributor_part_number: NA; Footprint Path: Y:\MIS_DATABASE\Library\ALTIUM_TOOL\PCB_FOOTPRINTS\Altium_Footprint_Lib.PcbLib; Height: 0.65MM; Library Path: Y:\MIS_DATABASE\Library\ALTIUM_TOOL\SCHEMATICS_PARTS\MS_MICROPROCESSOR_Library.schlib; Mfr_name: TEXAS INSTRUMENTS; Mistral Part No: 141221060001; Package: BGA425; Part_type: ICS\DIGITAL\MICROPROCESSOR; Project: AM62_EVM_BRD; RoHS: NA; Temperature: NA; Tolerance: NA; Voltage: NA; Wattage: NA; Weight: NA; Datasheet: Y:\MIS_DATABASE\DATASHEETS\ICS\DIGITAL\MICROCONTROLLER\AM62-SoC_SVB.PDF

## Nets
DGND: C30.1 C58.2 C61.2 C62.2 C63.2 C67.2 C68.2 C69.2 C70.2 C71.2 C73.2 C76.2 C77.1 C78.2 C84.2 C101.2 C113.1 C148.2 C198.1 C202.2 C203.2 C206.2 C210.2 C301.2 C304.2 C306.2 C307.2 C308.2 C312.1 C315.2 C316.2 C317.2 C318.2 C319.2 C327.2 J6.1(CH-GND) Q7.4(S1) Q7.7(S2) Q8.4(S1) Q8.7(S2) Q9.4(S1) Q9.7(S2) R58.2 R63.2 R84.1 R85.1 R86.1 R111.2 R112.2 R140.2 R190.2 R305.2 R315.2 R339.2 R345.1 R346.1 R348.1 R350.1 R361.2 R388.2 R481.2 U6.3(GND) U9.B3(VSS) U9.C1(VSSQ) U9.E5(VSSQ) U11.2(GND) U26.4(GND) U26.9(EPAD) U33.2(GND) U40.2(GND) U51.49(GND) ; also on sheet 1 10 11 12 13 14 15 16 17 18 19 20 24 25 26 27 28 29 30 31 32 33 34 35 36 37 38 39 40 41 42 43
VCC_1V8: C198.2 C202.1 C203.1 C206.1 C210.1 R296.2 R297.2 R303.2 R304.2 R306.2 R307.2 R308.2 R309.2 R310.2 R313.2 R317.2 R318.2 R319.2 U6.5(VCC) U9.B4(VCC) U9.D1(VCCQ) U9.E4(VCCQ) ; also on sheet 12 13 14 18 19 25 34 37 39 40 42
VCC_3V3_SYS: C30.2 C58.1 C76.1 C84.1 C101.1 C113.2 C148.1 C301.1 C307.1 C315.1 C316.1 C319.1 FL20.1 R76.2 R114.1 R191.2 R192.2 R341.2 R342.1 R344.2 R347.2 R349.1 R351.2 R352.2 R356.2 R357.2 R362.2 R363.1 R371.2 U11.4(V+) U26.8(VCC) U33.4(V+) U40.5(VCC) U51.19(VDDIO) U51.30(VDDIO) U51.41(VDDIO) ; also on sheet 10 12 13 14 18 19 20 24 25 26 27 29 30 31 32 33 34 35 36 37 38 39 40 41 42 43
VDD_1V0: C61.1 C62.1 C63.1 C69.1 C70.1 C71.1 C73.1 C306.1 C317.1 C318.1 U51.6(VDD1P0) U51.24(VDD1P0) U51.31(VDD1P0) U51.42(VDD1P0) ; also on sheet 12 24
VDD_2V5: C67.1 C68.1 C77.2 C78.1 C304.1 C308.1 U51.3(VDDA2P5) U51.9(VDDA2P5) ; also on sheet 13 17 24
CPSW1_GPIO_0: J6.14 Q9.1(D1) Q9.2(D2) Q9.5(D3) Q9.6(D4) Q9.8(D5) R371.1
CPSW1_LED_1000: J6.12 Q7.1(D1) Q7.2(D2) Q7.5(D3) Q7.6(D4) Q7.8(D5)
CPSW1_LED_ACT: J6.13 Q8.1(D1) Q8.2(D2) Q8.5(D3) Q8.6(D4) Q8.8(D5) R341.1
CPSW_ETH1_D0N: J6.10(MX0-) U51.2(TD_M_A)
CPSW_ETH1_D0P: J6.9(MX0+) U51.1(TD_P_A)
CPSW_ETH1_D1M: J6.8(MX1-) U51.5(TD_M_B)
CPSW_ETH1_D1P: J6.7(MX1+) U51.4(TD_P_B)
CPSW_ETH1_D2M: J6.6(MX2-) U51.8(TD_M_C)
CPSW_ETH1_D2P: J6.5(MX2+) U51.7(TD_P_C)
CPSW_ETH1_D3M: J6.4(MX3-) U51.11(TD_M_D)
CPSW_ETH1_D3P: J6.3(MX3+) U51.10(TD_P_D)
CPSW_ETH1_GPIO_0: R346.2 R347.1 R354.1 R387.1 TP23.1(TP)
CPSW_ETH1_GPIO_1: R344.1 R345.2 R353.1 TP24.1(TP)
CPSW_ETH1_LED0: TP26.1(TP) U51.47(LED_0)
CPSW_ETH1_LED_1000: R84.2 R335.1 R351.1 TP27.1(TP) U51.46(LED_1)
CPSW_ETH1_LED_ACT: R76.1 R348.2 R383.1 TP22.1(TP) U51.45(LED_2)
CPSW_RGMII1_ETH1_CLK: U51.15(XI) ; also on sheet 25
CPSW_RGMII1_ETH1_CLK_OUT: TP32.1(TP) U51.18(CLK_OUT)
CPSW_RGMII1_ETH1_RBIAS: C312.2 R361.1 U51.12(RBIAS)
CPSW_RGMII1_MDC: R102.2 R362.1 U51.16(MDC)
CPSW_RGMII1_MDIO: R64.2 R363.2 U51.17(MDIO)
CPSW_RGMII1_RD0: R86.2 R357.1 U51.33(RX_D0) ; also on sheet 25
CPSW_RGMII1_RD1: U51.34(RX_D1) ; also on sheet 25
CPSW_RGMII1_RD2: R85.2 R356.1 U51.35(RX_D2) ; also on sheet 25
CPSW_RGMII1_RD3: U51.36(RX_D3) ; also on sheet 25
CPSW_RGMII1_RESETn: R481.1 U40.4(Y) U51.43(RESET_N)
CPSW_RGMII1_RX_CTL: R349.2 R350.2 U51.38(RX_DV/RX_CTRL) ; also on sheet 25
CPSW_RGMII1_RXC: R359.1 ; also on sheet 25
CPSW_RGMII1_TD0: U51.28(TX_D0) ; also on sheet 25
CPSW_RGMII1_TD1: U51.27(TX_D1) ; also on sheet 25
CPSW_RGMII1_TD2: U51.26(TX_D2) ; also on sheet 25
CPSW_RGMII1_TD3: U51.25(TX_D3) ; also on sheet 25
CPSW_RGMII1_TX_CTL: U51.37(TX_EN/TX_CTRL) ; also on sheet 25
CPSW_RGMII1_TXC: U51.29(GTX_CLK) ; also on sheet 25
CPSW_RGMII_INTn: R72.2 R352.1 U51.44(INT/PWDN) ; also on sheet 24
CPSW_RGMII_INTn/PRU_INTn: R72.1 ; also on sheet 32 42
EEPROM_A0: R114.2 U26.1(A0)
EEPROM_A1: R112.1 U26.2(A1)
EEPROM_A2: R111.1 U26.3(A2)
EEPROM_WP: R388.1 U26.7(WP)
ETH1_EARTH: C327.1 J6.15(SH1) J6.16(SH2) R339.1
EXP_GPIO0_14_LT: U12.E24(OSPI0_CSN3) ; also on sheet 34
GPIO_CPSW1_RST: R190.1 R191.1 U40.1(A) ; also on sheet 39
GPIO_OSPI_RSTn: R296.1 U6.1(A) U12.G21(OSPI0_CSN1)
OSPI0_CSN0: R39.2 U12.F23(OSPI0_CSN0)
OSPI0_LBCLK: R52.1 R53.2
OSPI_CLK: R312.1 R315.1 U12.H24(OSPI0_CLK)
OSPI_CS: R39.1 R304.1 U9.C2(CS#)
OSPI_DQ0: R319.1 RA3.4 U9.D3(DQ0)
OSPI_DQ1: R309.1 RA3.1 U9.D2(DQ1)
OSPI_DQ2: R318.1 RA3.2 U9.C4(DQ2)
OSPI_DQ3: R310.1 RA3.3 U9.D4(DQ3)
OSPI_DQ4: R306.1 RA4.2 U9.D5(DQ4)
OSPI_DQ5: R307.1 RA4.1 U9.E3(DQ5)
OSPI_DQ6: R308.1 RA4.3 U9.E2(DQ6)
OSPI_DQ7: R303.1 RA4.4 U9.E1(DQ7)
OSPI_DQS: R297.1 R305.1 R320.1 U9.C3(DS)
OSPI_DQS_SOC: R53.1 R320.2 U12.J24(OSPI0_DQS)
OSPI_INTn: R317.1 R321.1 U12.H21(OSPI0_CSN2)
OSPI_RSTn: R313.1 U6.4(Y) U9.A4(RESET#)
PORz_OUT: U40.3(B) ; also on sheet 20 24 27 42
RESETSTATz: R189.1 U6.2(B) ; also on sheet 13 19 20 24 27 32 33 37 39 40 41 42
SoC_I2C0_SCL: U26.6(SCL) ; also on sheet 10 13 32 33 37 42
SoC_I2C0_SDA: U26.5(SDA) ; also on sheet 10 13 32 33 37 42
SOC_I2C1_SCL: TP71.1(TP) U11.1(SCL) U33.1(SCL) ; also on sheet 14 26 39 40 41 42
SOC_I2C1_SDA: TP72.1(TP) U11.6(SDA) U33.6(SDA) ; also on sheet 14 26 39 40 41 42
SoC_OSPI_DQ0: RA3.5 U12.E25(OSPI0_D0)
SoC_OSPI_DQ1: RA3.8 U12.G24(OSPI0_D1)
SoC_OSPI_DQ2: RA3.7 U12.F25(OSPI0_D2)
SoC_OSPI_DQ3: RA3.6 U12.F24(OSPI0_D3)
SoC_OSPI_DQ4: RA4.7 U12.J23(OSPI0_D4)
SoC_OSPI_DQ5: RA4.8 U12.J25(OSPI0_D5)
SoC_OSPI_DQ6: RA4.6 U12.H25(OSPI0_D6)
SoC_OSPI_DQ7: RA4.5 U12.J22(OSPI0_D7)
SOC_RGMII_MDC: R102.1 ; also on sheet 24 32
SOC_RGMII_MDIO: R64.1 ; also on sheet 24 32
TMP1_ADD0: R58.1 U11.5(ADD0)
TMP1_ADD1: R63.1 U11.3(ADD1)
TMP2_ADD1: R140.1 U33.3(ADD1)
N16956470: R52.2 U12.G25(OSPI0_LBCLKO)
N16960510: R321.2 U9.A5(INT#)
N16960546: R312.2 U9.B2(CK)
N17110597: TP100.1(TP) U51.13(VDDA1P8)
N17133547: FL20.2 J6.2(VCC)
N17137240: J6.11 R342.2
N17167245: R359.2 U51.32(RX_CLK)
N17269599: R189.2 R192.1 U40.6(C)
N17653582: Q7.3(G) R335.2
N17796705: Q8.3(G) R383.2
N17796716: Q9.3(G) R387.2
N18576337: R354.2 U51.39(GPIO_0)
N18576340: R353.2 U51.40(GPIO_1)
N20273833: TP30.1(TP) U51.48(VDDA1P8)
N20274021: TP102.1(TP) U51.14(XO)

Not connected (* = marked no-connect by the designer): U9 A2(DNU1)* A3(DNU2)* B1(DNU3)* B5(DNU4)* C5(DNU5)*; U33 5(ADD0)*; U51 20(JTAG_CLK)* 21(JTAG_TDO)* 22(JTAG_TMS)* 23(JTAG_TDI)*

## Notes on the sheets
sheet 21
- OSPI  FLASH
- SOC OSPI INTERFACE
- NOTE:
  For QSPI Configuration
  Remove 0E resistors from the following
  1.OSPI_DQ4 to OSPI_DQ7 nets (RA4)
  2.OSPI_INTn (R321)
  OSPI NOR Flash can be replaced with the Footprint
  compatible OCTAL NAND Flash (Mfr Part# W35N01JWTBAG)
- Place R53 close to the
  Memory to avoid stub
- Place R52 close to the SOC Ball
  with as little trace as possible
- OSPI  FLASH RESET
sheet 22
- BOARD ID EEPROM
- I2C ADDRESS: 0X51
- TEMPERATURE SENSORS
- I2C ADDRESS: 0x48
- I2C ADDRESS: 0x49
- CAD NOTE: PLACE TEMP SENSOR U11 CLOSE TO SoC
- CAD NOTE: PLACE TEMP SENSOR U33 CLOSE TO DDR4
- Silk: SOC_I2C1
sheet 23
- CPSW RGMII 1 - PHY
- RJ45 CONNECTOR WITH
  INTEGRATED MAGNETICS
- 100E
- 100E
- 100E
- 100E
- Silk: CPSW PHY-1
- PHY ADDRESS = 00000
- Auto-negotiation Enabled
- 10/100/1000 advertised, Auto-MDI-X
- Tx Clock Skew = 0ns
- Rx Clock Skew = 2ns
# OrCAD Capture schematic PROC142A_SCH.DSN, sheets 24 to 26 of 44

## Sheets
24 23. CPSW RGMII_2 ETHERNET PHY: size C; title: CPSW RGMII_2 ETHERNET PHY
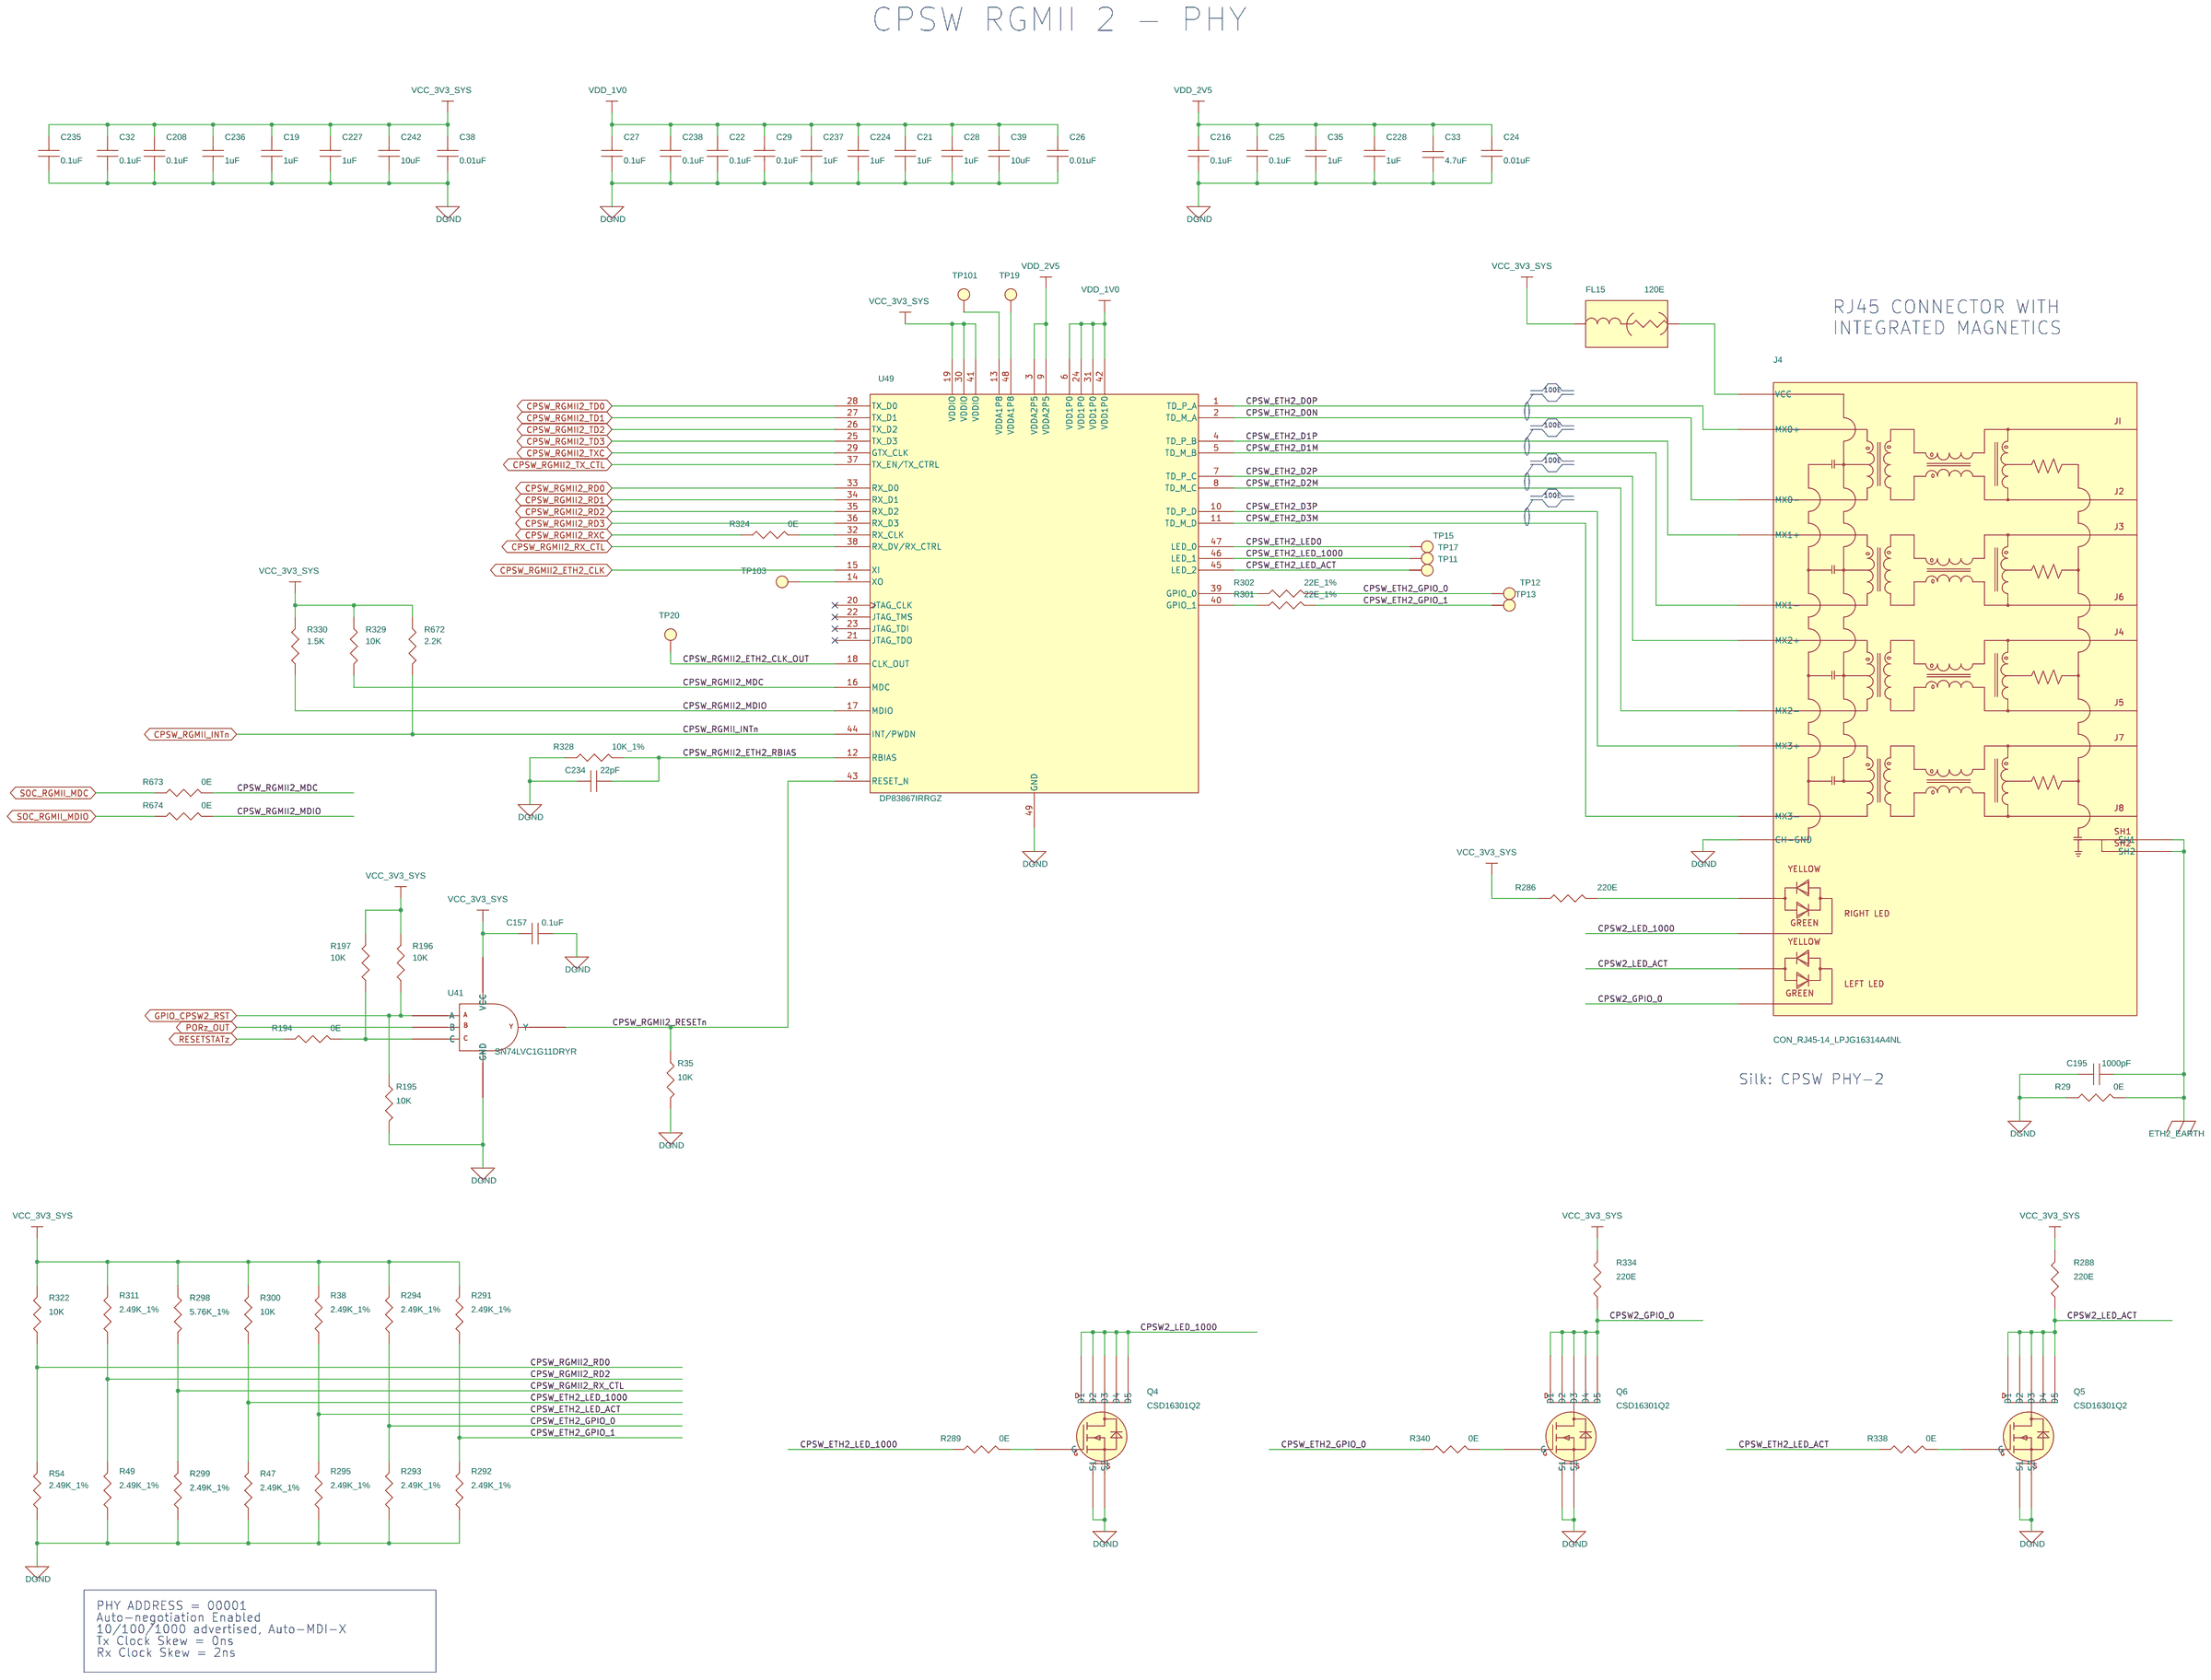
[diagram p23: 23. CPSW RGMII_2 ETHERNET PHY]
25 24. PHY CLK & LED DRIVER: size C; title: ETHERNET PHY CLOCK BUFFER & LED DRIVER
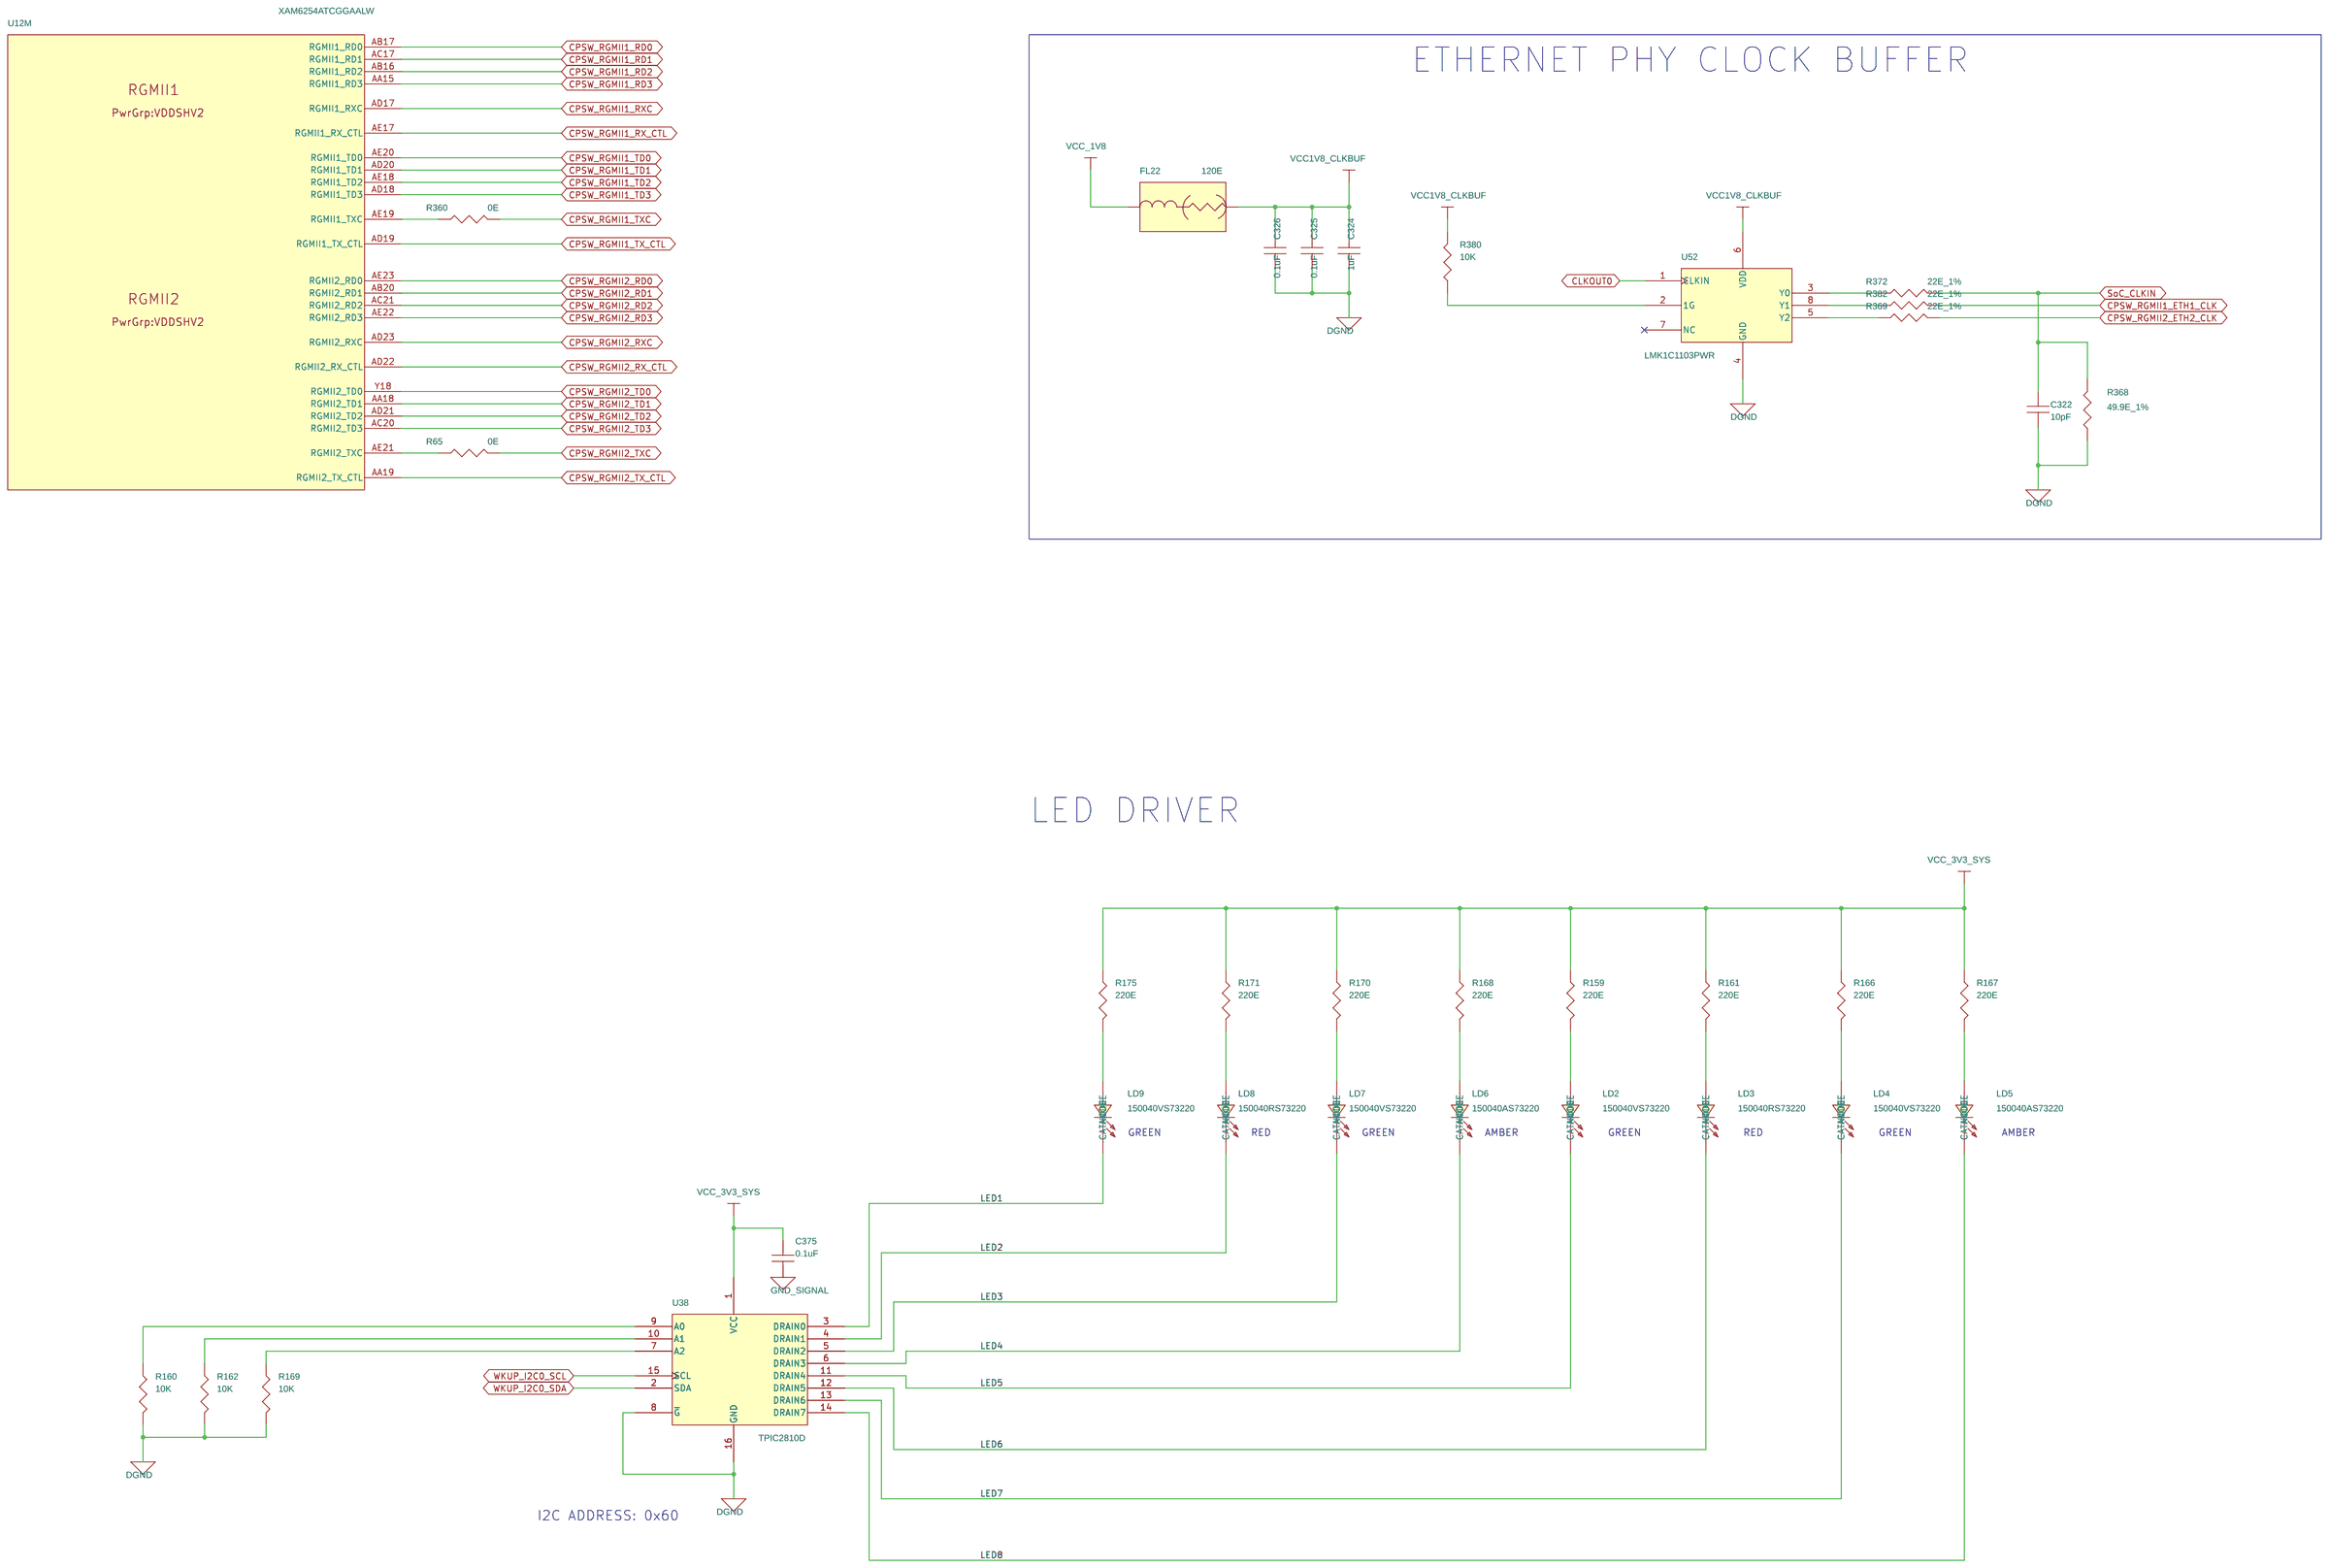
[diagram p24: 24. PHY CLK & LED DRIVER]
26 25. TEST AUTOMATION: size C; title: TEST AUTOMATION

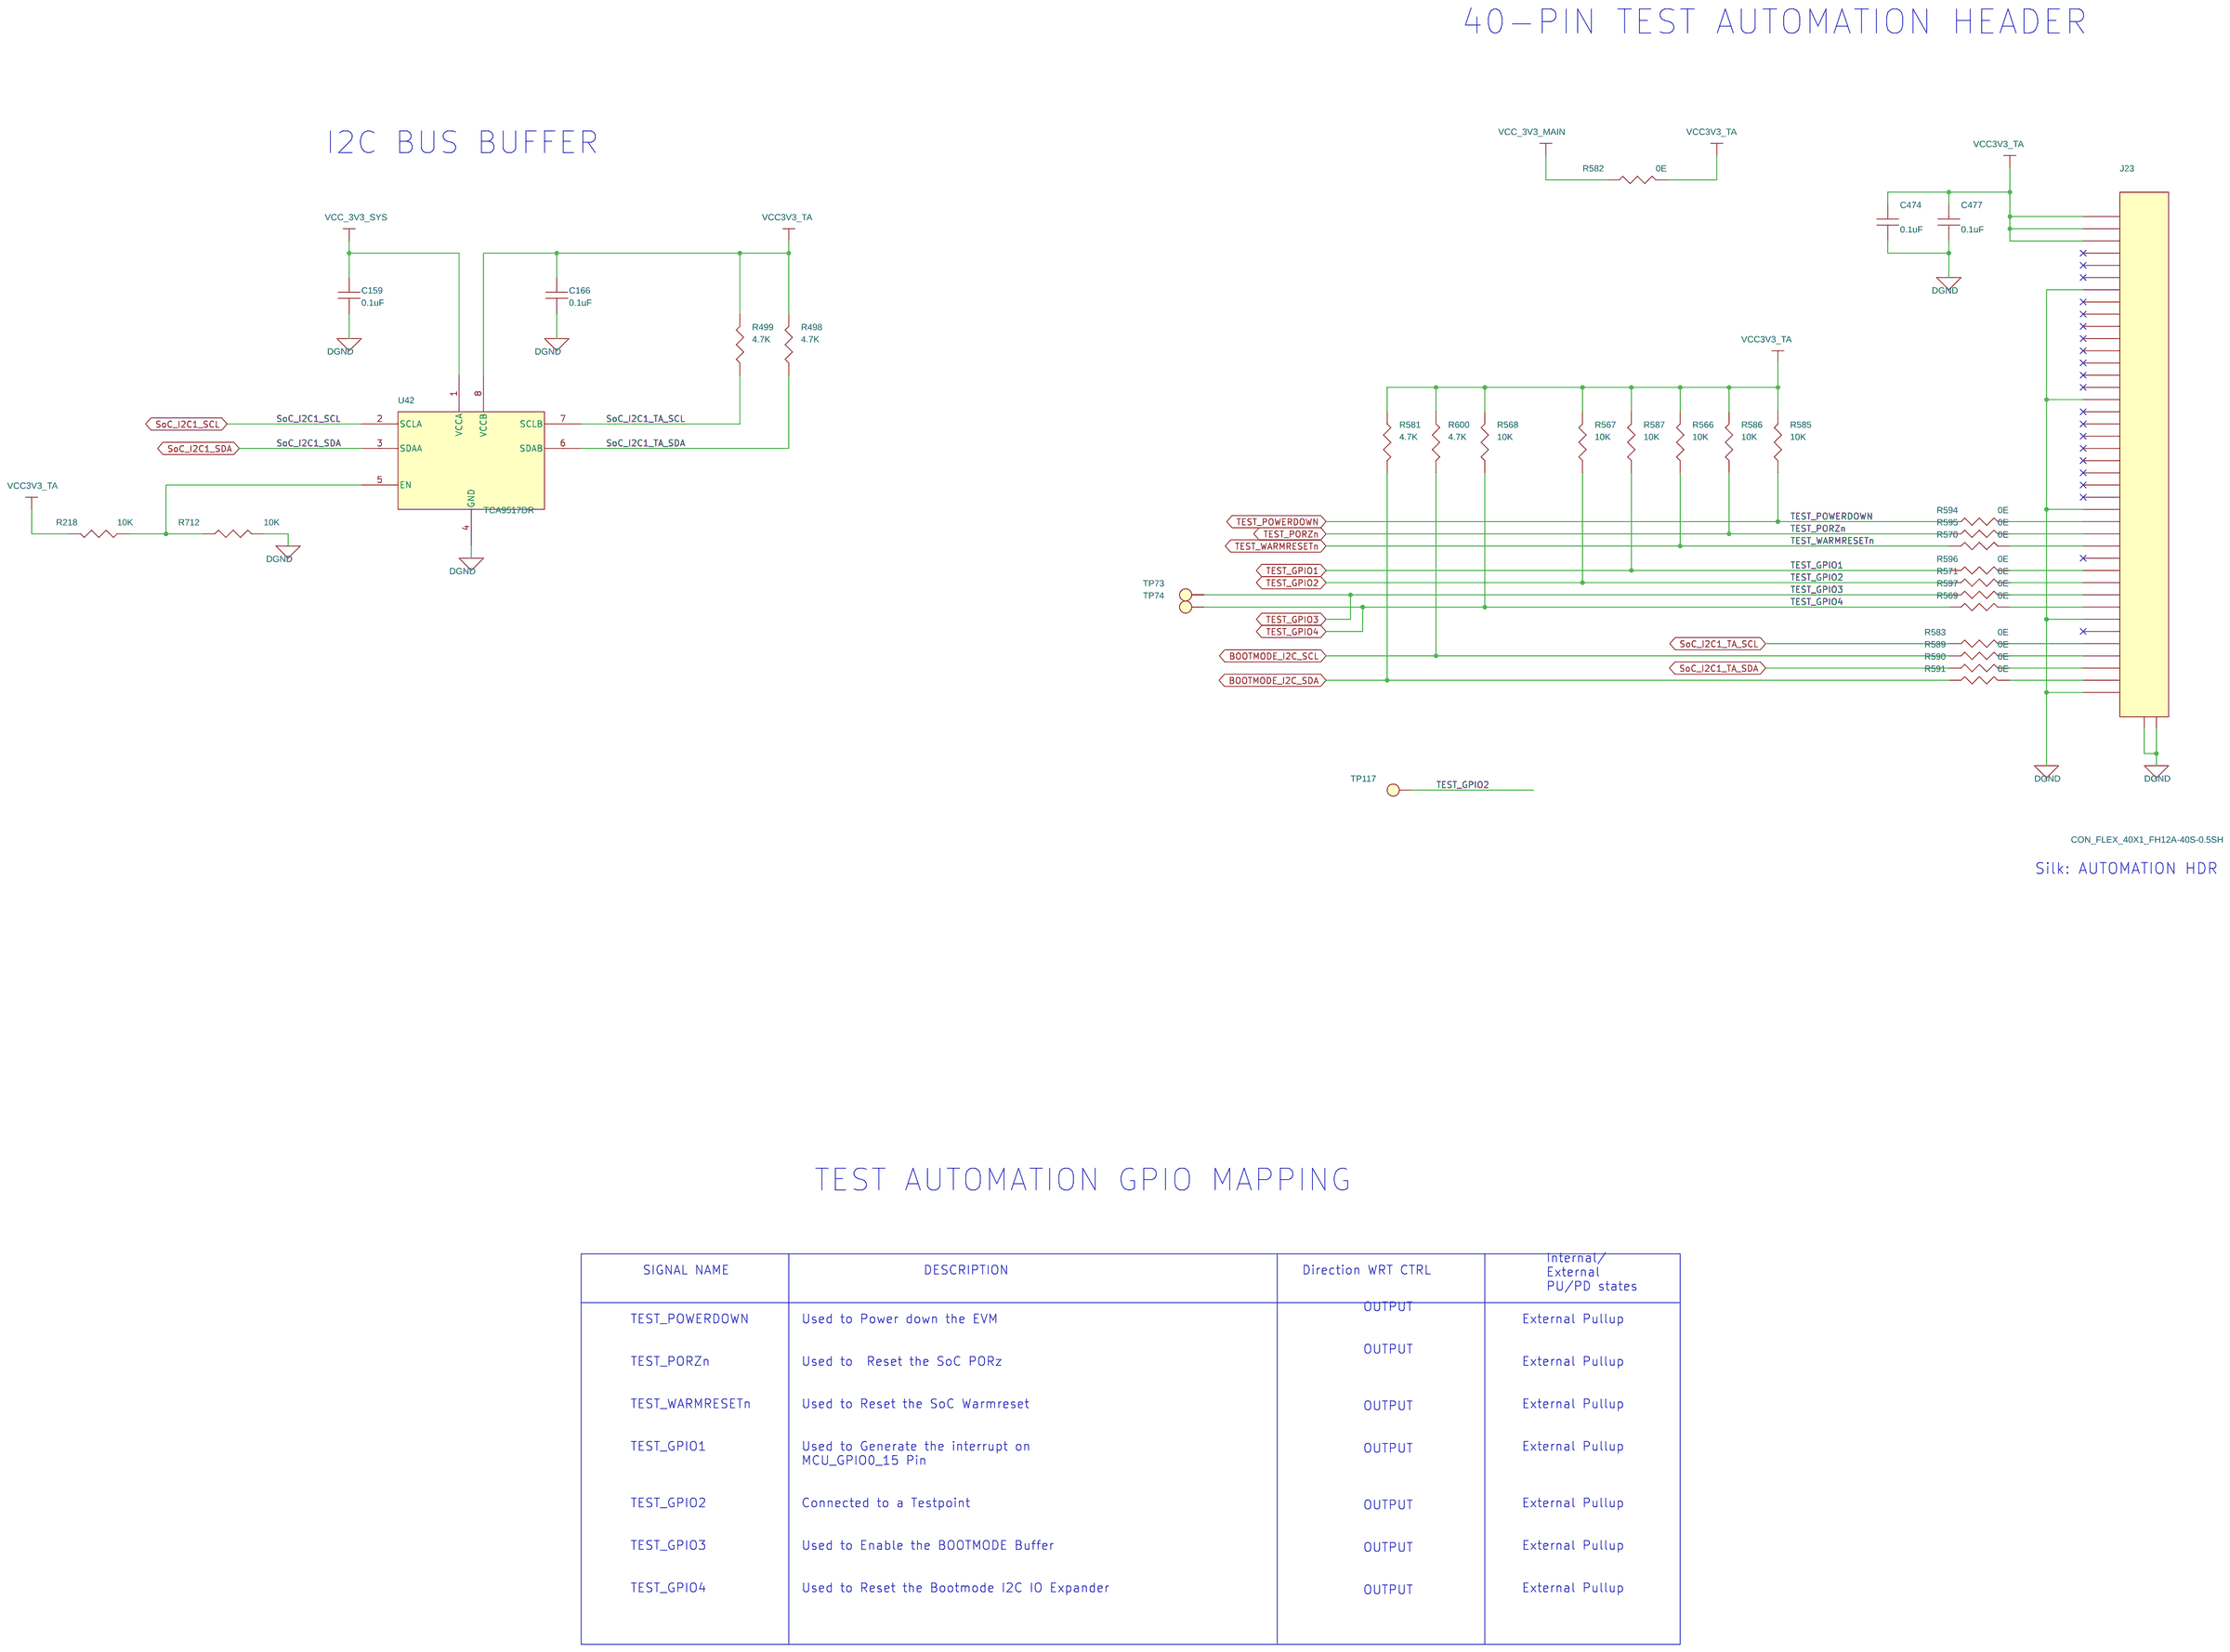
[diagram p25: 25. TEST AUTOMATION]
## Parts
sheet 23. CPSW RGMII_2 ETHERNET PHY
C19  1uF  [CAP0201_0-5]
C21  1uF  [CAP0201_0-5]
C22  0.1uF  [CAP0201_0-5]
C24  0.01uF  [CAP0201_0-5]
C25  0.1uF  [CAP0201_0-5]
C26  0.01uF  [CAP0201_0-5]
C27  0.1uF  [CAP0201_0-5]
C28  1uF  [CAP0201_0-5]
C29  0.1uF  [CAP0201_0-5]
C32  0.1uF  [CAP0201_0-5]
C33  4.7uF  [CAP0402_0-75]
C35  1uF  [CAP0201_0-5]
C38  0.01uF  [CAP0201_0-5]
C39  10uF  [CAP0402_0-75]
C157  0.1uF  [CAP0201_0-5]
C195  1000pF  [CAP1206_1-75]
C208  0.1uF  [CAP0201_0-5]
C216  0.1uF  [CAP0201_0-5]
C224  1uF  [CAP0201_0-5]
C227  1uF  [CAP0201_0-5]
C228  1uF  [CAP0201_0-5]
C234  22pF  [CAP0201_0-5]
C235  0.1uF  [CAP0201_0-5]
C236  1uF  [CAP0201_0-5]
C237  1uF  [CAP0201_0-5]
C238  0.1uF  [CAP0201_0-5]
C242  10uF  [CAP0402_0-75]
FL15  120E  [EMIFIL_BLM15P_0402]
J4  CON_RJ45-14_LPJG16314A4NL  [CON_RJ45-14_LPJG16314A4NL_S_R_T_13-6]
Q4  CSD16301Q2  [WSON6_CSD13202Q2_80X80_0-8]
Q5  CSD16301Q2  [WSON6_CSD13202Q2_80X80_0-8]
Q6  CSD16301Q2  [WSON6_CSD13202Q2_80X80_0-8]
R29  0E  [RES0603_0-75]
R35  10K  [RES0201_0-5]
R38  2.49K_1%  [RES0402_0-5]
R47  2.49K_1%  [RES0402_0-5]
R49  2.49K_1%  [RES0402_0-5]
R54  2.49K_1%  [RES0402_0-5]
R194  0E  [RES0402_0-5]
R195  10K  [RES0201_0-5]
R196  10K  [RES0201_0-5]
R197  10K  [RES0201_0-5]
R286  220E  [RES0402_0-5]
R288  220E  [RES0402_0-5]
R289  0E  [RES0402_0-5]
R291  2.49K_1%  [RES0402_0-5]
R292  2.49K_1%  [RES0402_0-5]
R293  2.49K_1%  [RES0402_0-5]
R294  2.49K_1%  [RES0402_0-5]
R295  2.49K_1%  [RES0402_0-5]
R298  5.76K_1%  [RES0402_0-5]
R299  2.49K_1%  [RES0402_0-5]
R300  10K  [RES0201_0-5]
R301  22E_1%  [RES0201_0-5]
R302  22E_1%  [RES0201_0-5]
R311  2.49K_1%  [RES0402_0-5]
R322  10K  [RES0201_0-5]
R324  0E  [RES0402_0-5]
R328  10K_1%  [RES0201_0-5]
R329  10K  [RES0201_0-5]
R330  1.5K  [RES0201_0-5]
R334  220E  [RES0402_0-5]
R338  0E  [RES0402_0-5]
R340  0E  [RES0402_0-5]
R672  2.2K  [RES0201_0-5]
R673  0E  [RES0402_0-5]
R674  0E  [RES0402_0-5]
TP11  TP20_SMD  [TP20_SMD]
TP12  TP20_SMD  [TP20_SMD]
TP13  TP20_SMD  [TP20_SMD]
TP15  TP20_SMD  [TP20_SMD]
TP17  TP20_SMD  [TP20_SMD]
TP19  TP20_SMD  [TP20_SMD]
TP20  TP20_SMD  [TP20_SMD]
TP101  TP20_SMD  [TP20_SMD]
TP103  TP20_SMD  [TP20_SMD]
U41  SN74LVC1G11DRYR  [SON6_SN74LVC2G17_40X60_0-6]
U49  DP83867IRRGZ  [QFN48_19-68_280X280_1]
sheet 24. PHY CLK & LED DRIVER
C322  10pF  [CAP0201_0-5]
C324  1uF  [CAP0201_0-5]
C325  0.1uF  [CAP0201_0-5]
C326  0.1uF  [CAP0201_0-5]
C375  0.1uF  [CAP0201_0-5]
FL22  120E  [EMIFIL_BLM15A_0402_0-6]
LD2  150040VS73220  [LED_150040GS73220_40X20_SMD_0-4]
LD3  150040RS73220  [LED_150040GS73220_40X20_SMD_0-4]
LD4  150040VS73220  [LED_150040GS73220_40X20_SMD_0-4]
LD5  150040AS73220  [LED_150040GS73220_40X20_SMD_0-4]
LD6  150040AS73220  [LED_150040GS73220_40X20_SMD_0-4]
LD7  150040VS73220  [LED_150040GS73220_40X20_SMD_0-4]
LD8  150040RS73220  [LED_150040GS73220_40X20_SMD_0-4]
LD9  150040VS73220  [LED_150040GS73220_40X20_SMD_0-4]
R65  0E  [RES0402_0-5]
R159  220E  [RES0402_0-5]
R160  10K  [RES0201_0-5]
R161  220E  [RES0402_0-5]
R162  10K  [RES0201_0-5]
R166  220E  [RES0402_0-5]
R167  220E  [RES0402_0-5]
R168  220E  [RES0402_0-5]
R169  10K  [RES0201_0-5]
R170  220E  [RES0402_0-5]
R171  220E  [RES0402_0-5]
R175  220E  [RES0402_0-5]
R360  0E  [RES0402_0-5]
R368  49.9E_1%  [RES0402_0-5]
R369  22E_1%  [RES0201_0-5]
R372  22E_1%  [RES0201_0-5]
R380  10K  [RES0201_0-5]
R382  22E_1%  [RES0201_0-5]
U38  TPIC2810D  [SOIC16_1-8]
U52  LMK1C1103PWR  [TSSOP8_25-59_125X180_1-2]
sheet 25. TEST AUTOMATION
C159  0.1uF  [CAP0201_0-5]
C166  0.1uF  [CAP0201_0-5]
C474  0.1uF  [CAP0201_0-5]
C477  0.1uF  [CAP0201_0-5]
J23  CON_FLEX_40X1_FH12A-40S-0.5SH  [CON_FLEX40X1_FH12A_S_R_S]
R218  10K  [RES0201_0-5]
R498  4.7K  [RES0201_0-5]
R499  4.7K  [RES0201_0-5]
R566  10K  [RES0201_0-5]
R567  10K  [RES0201_0-5]
R568  10K  [RES0201_0-5]
R569  0E  [RES0402_0-5]
R570  0E  [RES0402_0-5]
R571  0E  [RES0402_0-5]
R581  4.7K  [RES0201_0-5]
R582  0E  [RES0805_0-75]
R583  0E  [RES0402_0-5]
R585  10K  [RES0201_0-5]
R586  10K  [RES0201_0-5]
R587  10K  [RES0201_0-5]
R589  0E  [RES0402_0-5]
R590  0E  [RES0402_0-5]
R591  0E  [RES0402_0-5]
R594  0E  [RES0402_0-5]
R595  0E  [RES0402_0-5]
R596  0E  [RES0402_0-5]
R597  0E  [RES0402_0-5]
R600  4.7K  [RES0201_0-5]
R712  10K  [RES0201_0-5]
TP73  TP20_SMD  [TP20_SMD]
TP74  TP20_SMD  [TP20_SMD]
TP117  TP20_SMD  [TP20_SMD]
U42  TCA9517DR  [SOIC8_1-8]
sheet 29. JTAG BUFFER
U12  XAM6254ATCGGAALW  [BGA425_19-68_510X510_0-7]  (sections A,B,C,D,E,F,G,H,I,J,K,L,M,N,O,P,Q,R)

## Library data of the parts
C19 C21 C28 C35 C224 C227 C228 C236 C237 C324 = CAP: CAP CERAMIC 1uF 16V 20% X5R 0201; Chkd/date: MANIRAJA/300520; Crtd /date: ALVY/260520; Custom_Duty: 15%; Customs_HS_Code: 85322990; Distributor_name: DIGIKEY; Distributor_part_number: 490-18654-1-ND; Footprint Path: Y:\MIS_DATABASE\Library\ALTIUM_TOOL\PCB_FOOTPRINTS\Altium_Footprint_Lib.PcbLib; Height: 0.39MM; Library Path: Y:\MIS_DATABASE\Library\ALTIUM_TOOL\SCHEMATICS_PARTS\MS_DISCRETE_Library.schlib; Mfr_name: MURATA; Mfr_part_number: GRM033R61C105ME15D; Mistral Part No: 120018090038-R; Package: 0201; Part_type: CAPACITORS\CERAMIC; Project: QCS610_NANOSOM; RoHS: RoHS; Temperature: -55°C+85°C; Tolerance: 20%; Voltage: 16V; Wattage: NA; Weight: 0.33mg; Datasheet: Y:\MIS_DATABASE\DATASHEETS\CAPACITORS\GRM033R61C105ME15.PDF
C22 C25 C27 C29 C32 C157 C159 C166 C208 C216 C235 C238 C325 C326 C375 C474 C477 = CAP: CAP CERAMIC 0.1uF 16V 10% X5R 0201; Alt_Mfr_name: YAGEO AMERICA; Alt_Mfr_part_number: CC0402KRX5R8BB104; Chkd/date: MANIRAJA/230118; Crtd /date: MANIRAJA/230118; Custom_Duty: 15%; Customs_HS_Code: 85322990; Distributor_name: DIGIKEY; Distributor_part_number: 490-14305-1-ND; Footprint Path: Y:\MIS_DATABASE\Library\ALTIUM_TOOL\PCB_FOOTPRINTS\Altium_Footprint_Lib.PcbLib; Height: 0.33MM; Library Path: Y:\MIS_DATABASE\Library\ALTIUM_TOOL\SCHEMATICS_PARTS\MS_DISCRETE_Library.schlib; Mfr_name: MURATA; Mfr_part_number: GRM033R61C104KE14D; Mistral Part No: 120009030072-R; Package: 0201; Part_type: CAPACITORS\CERAMIC; Project: TI_MAXIE_CPB; RoHS: RoHS; Temperature: -55°C+85°C; Tolerance: 10%; Voltage: 16V; Wattage: NA; Weight: 0.33mg; Datasheet: Y:\MIS_DATABASE\DATASHEETS\CAPACITORS\GRM033R61C104KE14.PDF
C24 C26 C38 = CAP: CAP CERAMIC 0.01uF 25V 10% X5R 0201; Chkd/date: MANIRAJA/230118; Crtd /date: MANIRAJA/230118; Custom_Duty: 15%; Customs_HS_Code: 85322990; Distributor_name: DIGIKEY; Distributor_part_number: GRM033R61E103KA12J-ND; Footprint Path: Y:\MIS_DATABASE\Library\ALTIUM_TOOL\PCB_FOOTPRINTS\Altium_Footprint_Lib.PcbLib; Height: 0.33MM; Library Path: Y:\MIS_DATABASE\Library\ALTIUM_TOOL\SCHEMATICS_PARTS\MS_DISCRETE_Library.schlib; Mfr_name: MURATA; Mfr_part_number: GRM033R61E103KA12J; Mistral Part No: 120018010007-R; Package: 0201; Part_type: CAPACITORS\CERAMIC; Project: TI_MAXIE_CPB; RoHS: RoHS; Temperature: -55°C+85°C; Tolerance: 10%; Voltage: 25V; Wattage: NA; Weight: 0.33mg; Datasheet: Y:\MIS_DATABASE\DATASHEETS\CAPACITORS\GRM033R61E103KA12.PDF
C33 = CAP: CAP CERAMIC 4.7uF 10V 20% X5R 0402; Chkd/date: MANIRAJA/110718; Crtd /date: ALVY/110718; Custom_Duty: 15%; Customs_HS_Code: 85322990; Distributor_name: DIGIKEY; Distributor_part_number: 490-14306-1-ND; Footprint Path: Y:\MIS_DATABASE\Library\ALTIUM_TOOL\PCB_FOOTPRINTS\Altium_Footprint_Lib.PcbLib; Height: 0.65MM; Library Path: Y:\MIS_DATABASE\Library\ALTIUM_TOOL\SCHEMATICS_PARTS\MS_DISCRETE_Library.schlib; Mfr_name: MURATA; Mfr_part_number: GRM155R61A475MEAAD; Mistral Part No: 120012060002-R; Package: 0402; Part_type: CAPACITORS\CERAMIC; Project: TI_J7SVB_PCIE_ADD-ON-CARD; RoHS: RoHS; Temperature: -55°C+85°C; Tolerance: 20%; Voltage: 10V; Wattage: NA; Weight: 14mg; Datasheet: Y:\MIS_DATABASE\DATASHEETS\CAPACITORS\GRM155R61A475MEAAD.PDF
C39 C242 = CAP: CAP CERAMIC 10uF 10V 20% X5R 0402; Chkd/date: MANIRAJA/300520; Crtd /date: ALVY/260520; Custom_Duty: 15%; Customs_HS_Code: 85322990; Distributor_name: DIGIKEY; Distributor_part_number: 490-GRM155R61A106ME11DTR-ND; Footprint Path: Y:\MIS_DATABASE\Library\ALTIUM_TOOL\PCB_FOOTPRINTS\Altium_Footprint_Lib.PcbLib; Height: 0.55MM; Library Path: Y:\MIS_DATABASE\Library\ALTIUM_TOOL\SCHEMATICS_PARTS\MS_DISCRETE_Library.schlib; Mfr_name: MURATA; Mfr_part_number: GRM155R61A106ME11D; Mistral Part No: 120013110019-R; Package: 0402; Part_type: CAPACITORS\CERAMIC; Project: QCS610_NANOSOM; RoHS: RoHS; Temperature: -55°C+85°C; Tolerance: 20%; Voltage: 10V; Wattage: NA; Weight: 3.1mg; Datasheet: Y:\MIS_DATABASE\DATASHEETS\CAPACITORS\MURATA-GXX-SER_NOV17.PDF
C195 = CAP: CAP CERAMIC 1000pF 2KV 10% X7R 1206; Chkd/date: SHREESHAIL/291106; Crtd /date: MAZHAR/281106; Custom_Duty: 15%; Customs_HS_Code: 85322990; Distributor_name: DIGIKEY; Distributor_part_number: 478-2956-1-ND; Footprint Path: Y:\MIS_DATABASE\Library\ALTIUM_TOOL\PCB_FOOTPRINTS\Altium_Footprint_Lib.PcbLib; Height: 1.52MM; Library Path: Y:\MIS_DATABASE\Library\ALTIUM_TOOL\SCHEMATICS_PARTS\MS_DISCRETE_Library.schlib; Mfr_name: AVX CORPORATION; Mfr_part_number: 1206GC102KAT1A; Mistral Part No: 120015080006-R; Package: 1206; Part_type: CAPACITORS\CERAMIC; Project: ADR1B; RoHS: RoHS; Temperature: -55°C+125°C; Tolerance: 10%; Voltage: 2KV; Wattage: NA; Weight: 16.2mg; Datasheet: Y:\MIS_DATABASE\DATASHEETS\CAPACITORS\AVX_HV-MLC.PDF
C234 = CAP: CAP CERAMIC 22pF 25V 1% C0G(NP0) 0201; Chkd/date: MANIRAJA/270721; Crtd /date: ALVY/260721; Custom_Duty: 15%; Customs_HS_Code: 85322990; Distributor_name: DIGIKEY; Distributor_part_number: 490-14545-1-ND; Footprint Path: Y:\MIS_DATABASE\Library\ALTIUM_TOOL\PCB_FOOTPRINTS\Altium_Footprint_Lib.PcbLib; Height: 0.33MM; Library Path: Y:\MIS_DATABASE\Library\ALTIUM_TOOL\SCHEMATICS_PARTS\MS_DISCRETE_Library.schlib; Mfr_name: MURATA; Mfr_part_number: GRM0335C1E220FA01D; Mistral Part No: 120021070019-R; Package: 0201; Part_type: CAPACITORS\CERAMIC; Project: TI_AM335x SK_BRD; RoHS: RoHS; Temperature: -55°C+125°C; Tolerance: 1%; Voltage: 25V; Wattage: NA; Weight: 0.33mg; Datasheet: Y:\MIS_DATABASE\DATASHEETS\CAPACITORS\GRM0335C1E220FA01.PDF
FL15 = EMIFILTER_IND: FERRITE CHIP 120E 2A 0402; Chkd/date: NAVEED/241114; Crtd /date: USMAN/170613; Custom_Duty: 24%; Customs_HS_Code: 85369090; Distributor_name: MOUSER; Distributor_part_number: 81-BLM15PX121SN1D; Height: 0.55MM; Mfr_name: MURATA; Mfr_part_number: BLM15PX121SN1D; Mistral Part No: 130013060022-R; Package: 0402; Part_type: FILTER; Project: GEN_3-8; RoHS: RoHS; Temperature: -55°C+125°C; Tolerance: 25%; Voltage: NA; Wattage: NA; Weight: NA; Datasheet: Y:\MIS_DATABASE\DATASHEETS\DISCRETES\INDUCTORS\BLM15X.PDF
J4 = CON_RJ45-14_LPJG16314A4NL: CON RJ-45 FEMALE 14POS RT TH; Chkd/date: VASANTHA/150714; Crtd /date: BALACHANDAR/120614; Custom_Duty: 24%; Customs_HS_Code: 85369090; Distributor_name: NA; Distributor_part_number: NA; Footprint Path: Y:\MIS_DATABASE\Library\ALTIUM_TOOL\PCB_FOOTPRINTS\Altium_Footprint_Lib.PcbLib; Height: 13.60MM; Library Path: Y:\MIS_DATABASE\Library\ALTIUM_TOOL\SCHEMATICS_PARTS\MS_CONNECTOR_Library.schlib; Mfr_name: LINK-PP; Mfr_part_number: LPJG16314A4NL; Mistral Part No: 150014060029-R; Package: THRU-HOLE; Part_type: CONNECTOR\JACK; Project: AEGIS; RoHS: RoHS; Temperature: -0°C+70°C; Tolerance: NA; Voltage: NA; Wattage: NA; Weight: NA; Datasheet: Y:\MIS_DATABASE\DATASHEETS\CONNECTORS\LPJG16314A4NL.PDF
Q4-Q6 = MOSFET_CSD17313Q2: IC MOSFET N-CHANNEL NEXFET 25V WSON6; Chkd/date: ALVY/071220; Crtd /date: MANIRAJA/071220; Custom_Duty: 15%; Customs_HS_Code: 85423100; Distributor_name: DIGIKEY; Distributor_part_number: 296-25260-1-ND; Footprint Path: Y:\MIS_DATABASE\Library\ALTIUM_TOOL\PCB_FOOTPRINTS\Altium_Footprint_Lib.PcbLib; Height: 0.80MM; Library Path: Y:\MIS_DATABASE\Library\ALTIUM_TOOL\SCHEMATICS_PARTS\MS_MOSFET_Library.schlib; Mfr_name: TEXAS INSTRUMENTS; Mistral Part No: 142020120008-R; Package: WSON6; Part_type: ICS\POWER\MOSFET; Project: TI_AM243x LP EVM; RoHS: RoHS; Temperature: -55°C+150°C; Tolerance: NA; Voltage: NA; Wattage: NA; Weight: 8.7mg; Datasheet: Y:\MIS_DATABASE\DATASHEETS\ICS\POWER\CSD16301Q2.PDF
R29 = RESISTOR: RES 0E 1/10W 5% 0603; Chkd/date: MANIRAJA/051217; Crtd /date: BAVISH/180211; Custom_Duty: 15%; Customs_HS_Code: 85332119; Distributor_name: DIGIKEY; Distributor_part_number: 311-0.0GRCT-ND; Footprint Path: Y:\MIS_DATABASE\Library\ALTIUM_TOOL\PCB_FOOTPRINTS\Altium_Footprint_Lib.PcbLib; Height: 0.55MM; Library Path: Y:\MIS_DATABASE\Library\ALTIUM_TOOL\SCHEMATICS_PARTS\MS_DISCRETE_Library.schlib; Manufacturer: YAGEO AMERICA; Mfr_name: PANASONIC-ECG; Mfr_part_number: RC0603JR-070RL; Mistral Part No: 110011020013-R; Package: 0603; Part_type: RESISTORS\FIXED; Project: KENNEL; RoHS: RoHS; Temperature: -55°C+155°C; Tolerance: 5%; Voltage: NA; Wattage: 1/10W; Weight: 2mg; Datasheet: Y:\MIS_DATABASE\DATASHEETS\RESISTORS\RCXXXXL-SER_MAR18.PDF
R35 R160 R162 R169 R195-R197 R218 R300 R322 R329 R380 R566-R568 R585-R587 R712 = RESISTOR: RES 10K 1/20W 5% 0201; Chkd/date: MANIRAJA/050517; Crtd /date: MANIRAJA/050517; Custom_Duty: 15%; Customs_HS_Code: 85332119; Distributor_name: DIGIKEY; Distributor_part_number: 311-10KNCT-ND; Footprint Path: Y:\MIS_DATABASE\Library\ALTIUM_TOOL\PCB_FOOTPRINTS\Altium_Footprint_Lib.PcbLib; Height: 0.26MM; Library Path: Y:\MIS_DATABASE\Library\ALTIUM_TOOL\SCHEMATICS_PARTS\MS_DISCRETE_Library.schlib; Mfr_name: YAGEO AMERICA; Mfr_part_number: RC0201JR-0710KL; Mistral Part No: 110010070051-R; Package: 0201; Part_type: RESISTORS\FIXED; Project: GOLDEN-I LITE; RoHS: RoHS; Temperature: -55°C+125°C; Tolerance: 5%; Voltage: NA; Wattage: 1/20W; Weight: 0.17mg; Datasheet: Y:\MIS_DATABASE\DATASHEETS\RESISTORS\RCXXXXL-SER_MAR18.PDF
R38 R47 R49 R54 R291-R295 R299 R311 = RESISTOR: RES 2.49K 1/16W 1% 0402; Chkd/date: VASANTHA/270516; Crtd /date: VASANTHA/270516; Custom_Duty: 15%; Customs_HS_Code: 85332119; Distributor_name: DIGIKEY; Distributor_part_number: 311-2.49KLRCT-ND; Footprint Path: Y:\MIS_DATABASE\Library\ALTIUM_TOOL\PCB_FOOTPRINTS\Altium_Footprint_Lib.PcbLib; Height: 0.40MM; Library Path: Y:\MIS_DATABASE\Library\ALTIUM_TOOL\SCHEMATICS_PARTS\MS_DISCRETE_Library.schlib; Mfr_name: YAGEO AMERICA; Mfr_part_number: RC0402FR-072K49L; Mistral Part No: 110016050020-R; Package: 0402; Part_type: RESISTORS\FIXED; Project: TMDXCSKCC; RoHS: RoHS; Temperature: -55°C+155°C; Tolerance: 1%; Voltage: NA; Wattage: 1/16W; Weight: 0.65mg; Datasheet: Y:\MIS_DATABASE\DATASHEETS\RESISTORS\RCXXXXL-SER_MAR18.PDF
R194 R289 R338 R340 R569-R571 R583 R589-R591 R594-R597 R673 R674 = RESISTOR: RES 0E 1/16W JUMPER 0402; Chkd/date: VASANTHA/201216; Crtd /date: MUDDU/190810; Custom_Duty: 15%; Customs_HS_Code: 85332119; Distributor_name: DIGIKEY; Distributor_part_number: 541-0.0JCT-ND; Footprint Path: Y:\MIS_DATABASE\Library\ALTIUM_TOOL\PCB_FOOTPRINTS\Altium_Footprint_Lib.PcbLib; Height: 0.40MM; Library Path: Y:\MIS_DATABASE\Library\ALTIUM_TOOL\SCHEMATICS_PARTS\MS_DISCRETE_Library.schlib; Mfr_name: VISHAY; Mfr_part_number: CRCW04020000Z0ED; Mistral Part No: 110010080019-R; Package: 0402; Part_type: RESISTORS\FIXED; Project: PB_BUGBASE; RoHS: RoHS; Temperature: -55°C+155°C; Tolerance: NA; Voltage: NA; Wattage: 1/16W; Weight: 0.65mg; Datasheet: Y:\MIS_DATABASE\DATASHEETS\RESISTORS\CRCW0603.PDF
R286 R288 R334 = RESISTOR: RES 220E 1/10W 5% 0402; Chkd/date: VASANTHA/291216; Crtd /date: GEETHA/260406; Custom_Duty: 15%; Customs_HS_Code: 85332119; Distributor_name: DIGIKEY; Distributor_part_number: P220JCT-ND; Footprint Path: Y:\MIS_DATABASE\Library\ALTIUM_TOOL\PCB_FOOTPRINTS\Altium_Footprint_Lib.PcbLib; Height: 0.40MM; Library Path: Y:\MIS_DATABASE\Library\ALTIUM_TOOL\SCHEMATICS_PARTS\MS_DISCRETE_Library.schlib; Mfr_name: PANASONIC-ECG; Mfr_part_number: ERJ-2GEJ221X; Mistral Part No: 110009030506-R; Package: 0402; Part_type: RESISTORS\FIXED; Project: RED EYE; RoHS: RoHS; Temperature: -55°C+155°C; Tolerance: 5%; Voltage: NA; Wattage: 1/10W; Weight: 0.8mg; Datasheet: Y:\MIS_DATABASE\DATASHEETS\RESISTORS\PAN-ERJSER_NOV17.PDF
R298 = RESISTOR: RES 5.76K 1/10W 1% 0402; Chkd/date: MAZHAR/150709; Crtd /date: USMAN/220808; Custom_Duty: 15%; Customs_HS_Code: 85332119; Distributor_name: DIGIKEY; Distributor_part_number: P5.76KLCT-ND; Footprint Path: Y:\MIS_DATABASE\Library\ALTIUM_TOOL\PCB_FOOTPRINTS\Altium_Footprint_Lib.PcbLib; Height: 0.40MM; Library Path: Y:\MIS_DATABASE\Library\ALTIUM_TOOL\SCHEMATICS_PARTS\MS_DISCRETE_Library.schlib; Mfr_name: PANASONIC-ECG; Mfr_part_number: ERJ-2RKF5761X; Mistral Part No: 110009030945-R; Package: 0402; Part_type: RESISTORS\FIXED; Project: CPB; RoHS: RoHS; Temperature: -55°C+155°C; Tolerance: 1%; Voltage: NA; Wattage: 1/10W; Weight: 0.8mg; Datasheet: Y:\MIS_DATABASE\DATASHEETS\RESISTORS\PAN-ERJSER_NOV17.PDF
R301 R302 R369 R372 R382 = RESISTOR: RES 22E 1/20W 1% 0201; Chkd/date: MAZHAR/140709; Crtd /date: MAZHAR/220807; Custom_Duty: 15%; Customs_HS_Code: 85332119; Distributor_name: DIGIKEY; Distributor_part_number: P22.0ABCT-ND; Footprint Path: Y:\MIS_DATABASE\Library\ALTIUM_TOOL\PCB_FOOTPRINTS\Altium_Footprint_Lib.PcbLib; Height: 0.26MM; Library Path: Y:\MIS_DATABASE\Library\ALTIUM_TOOL\SCHEMATICS_PARTS\MS_DISCRETE_Library.schlib; Mfr_name: PANASONIC-ECG; Mfr_part_number: ERJ-1GEF22R0C; Mistral Part No: 110009030522-R; Package: 0201; Part_type: RESISTORS\FIXED; Project: V8TS; RoHS: RoHS; Temperature: -55°C+125°C; Tolerance: 1%; Voltage: NA; Wattage: 1/20W; Weight: 0.15mg; Datasheet: Y:\MIS_DATABASE\DATASHEETS\RESISTORS\PAN-ERJSER_NOV17.PDF
R65 R324 R360 = RESISTOR: RES 0E 1/16W JUMPER 0402; Chkd/date: VASANTHA/201216; Crtd /date: MUDDU/190810; Custom_Duty: 15%; Customs_HS_Code: 85332119; Distributor_name: DIGIKEY; Distributor_part_number: 541-0.0JCT-ND; Footprint Path: Y:\MIS_DATABASE\Library\ALTIUM_TOOL\PCB_FOOTPRINTS\Altium_Footprint_Lib.PcbLib; Height: 0.40MM; Library Path: Y:\MIS_DATABASE\Library\ALTIUM_TOOL\SCHEMATICS_PARTS\MS_DISCRETE_Library.schlib; Mfr_name: VISHAY; Mfr_part_number: CRCW04020000Z0ED; Mistral Part No: 110010080019-R; Package: 0402; Part_type: RESISTORS\FIXED; Project: PB_BUGBASE; RoHS: RoHS; SIGNAL_MODEL: RESISTOR_RES0402_0-5_0E_0E; Temperature: -55°C+155°C; Tolerance: NA; Voltage: NA; Wattage: 1/16W; Weight: 0.65mg; Datasheet: Y:\MIS_DATABASE\DATASHEETS\RESISTORS\CRCW0603.PDF
R328 = RESISTOR: RES 10K 1/20W 1% 0201; Chkd/date: VASANTHA/270117; Crtd /date: MANIRAJA/270117; Custom_Duty: 15%; Customs_HS_Code: 85332119; Distributor_name: DIGIKEY; Distributor_part_number: 311-10.0KMCT-ND; Footprint Path: Y:\MIS_DATABASE\Library\ALTIUM_TOOL\PCB_FOOTPRINTS\Altium_Footprint_Lib.PcbLib; Height: 0.26MM; Library Path: Y:\MIS_DATABASE\Library\ALTIUM_TOOL\SCHEMATICS_PARTS\MS_DISCRETE_Library.schlib; Manufacturer: YAGEO AMERICA; Mfr_name: YAGEO AMERICA; Mfr_part_number: RC0201FR-0710KL; Mistral Part No: 110011040018-R; Package: 0201; Part_type: RESISTORS\FIXED; Project: GOLDEN-I LITE; RoHS: RoHS; Temperature: -55°C+125°C; Tolerance: 1%; Voltage: NA; Wattage: 1/20W; Weight: 0.17mg; Datasheet: Y:\MIS_DATABASE\DATASHEETS\RESISTORS\RCXXXXL-SER_MAR18.PDF
R330 = RESISTOR: RES 1.5K 1/20W 5% 0201; Chkd/date: MAZHAR/130208; Crtd /date: USMAN/130208; Custom_Duty: 15%; Customs_HS_Code: 85332119; Distributor_name: DIGIKEY; Distributor_part_number: P1.5KAGCT-ND; Footprint Path: Y:\MIS_DATABASE\Library\ALTIUM_TOOL\PCB_FOOTPRINTS\Altium_Footprint_Lib.PcbLib; Height: 0.26MM; Library Path: Y:\MIS_DATABASE\Library\ALTIUM_TOOL\SCHEMATICS_PARTS\MS_DISCRETE_Library.schlib; Manufacturer: PANASONIC-ECG; Mfr_name: PANASONIC-ECG; Mfr_part_number: ERJ-1GEJ152C; Mistral Part No: 110010070057-R; Package: 0201; Part_type: RESISTORS\FIXED; Project: SMART VIEW_IP CAMERA; RoHS: RoHS; Temperature: -55°C+125°C; Tolerance: 5%; Voltage: NA; Wattage: 1/20W; Weight: 0.15mg; Datasheet: Y:\MIS_DATABASE\DATASHEETS\RESISTORS\PAN-ERJXGE-FEB06.PDF
R672 = RESISTOR: RES 2.2K 1/20W 5% 0201; Chkd/date: VASANTHA/010117; Crtd /date: MAZHAR/010605; Custom_Duty: 15%; Customs_HS_Code: 85332119; Distributor_name: DIGIKEY; Distributor_part_number: P2.2KAGCT-ND; Footprint Path: Y:\MIS_DATABASE\Library\ALTIUM_TOOL\PCB_FOOTPRINTS\Altium_Footprint_Lib.PcbLib; Height: 0.26MM; Library Path: Y:\MIS_DATABASE\Library\ALTIUM_TOOL\SCHEMATICS_PARTS\MS_DISCRETE_Library.schlib; Mfr_name: PANASONIC-ECG; Mfr_part_number: ERJ-1GEJ222C; Mistral Part No: 110009030427-R; Package: 0201; Part_type: RESISTORS\FIXED; Project: G4SLIM; RoHS: RoHS; Temperature: -55°C+125°C; Tolerance: 5%; Voltage: NA; Wattage: 1/20W; Weight: 0.15mg; Datasheet: Y:\MIS_DATABASE\DATASHEETS\RESISTORS\PAN-ERJXGE-FEB06.PDF
TP11-TP13 TP15 TP17 TP19 TP20 TP73 TP74 TP101 TP103 TP117 = TESTPOINT: TESTPOINT CIR 20 SMD; Chkd/date: SHREESHAIL/171006; Crtd /date: MAZHAR/171006; Custom_Duty: NA; Customs_HS_Code: NA; Distributor_name: NA; Distributor_part_number: NA; Footprint Path: Y:\MIS_DATABASE\Library\ALTIUM_TOOL\PCB_FOOTPRINTS\Altium_Footprint_Lib.PcbLib; Height: NA; Library Path: Y:\MIS_DATABASE\Library\ALTIUM_TOOL\SCHEMATICS_PARTS\MS_DISCRETE_Library.schlib; MECHANICAL 3D STEP FILE: NA; Mfr_name: LOCAL; Mistral Part No: NA; Package: SMD; Project: BT MODULE_CSRBC04; RoHS: NA; Temperature: NA; Tolerance: NA; Voltage: NA; Wattage: NA; Weight: NA; Datasheet: NA
U41 = SN74LVC1G11DCKR_SC70-6: IC SINGLE 3-INPUT POSITIVE-AND GATE SON6; Chkd/date: MANIRAJA/270121; Crtd /date: ALVY/270121; Custom_Duty: 15%; Customs_HS_Code: 85423100; Distributor_name: DIGIKEY; Distributor_part_number: 296-30120-1-ND; Footprint Path: Y:\MIS_DATABASE\Library\ALTIUM_TOOL\PCB_FOOTPRINTS\Altium_Footprint_Lib.PcbLib; Height: 0.60MM; Library Path: Y:\MIS_DATABASE\Library\ALTIUM_TOOL\SCHEMATICS_PARTS\MS_GATE_Library.schlib; Mfr_name: TEXAS INSTRUMENTS; Mistral Part No: 141021010013-R; Package: SON6; Part_type: ICS\DIGITAL\GATES; Project: AM64X_SKEVM; RoHS: RoHS; Temperature: -40°C+125°C; Tolerance: NA; Voltage: NA; Wattage: NA; Weight: 33mg; Datasheet: Y:\MIS_DATABASE\DATASHEETS\ICS\DIGITAL\GATES\SN74LVC1G_NOV16.PDF
U49 = DP83867IRRGZ_VQFN48: IC HIGH IMMUNITY 10/100/1000 Mb/s ETHERNET PHY LAYER TRANSCEIVER VQFN48; Chkd/date: MANIRAJA/110817; Crtd /date: MANIRAJA/110817; Custom_Duty: 15%; Customs_HS_Code: 85423100; Distributor_name: DIGIKEY; Distributor_part_number: DP83867IRRGZT-ND; Height: 1.00MM; Mfr_name: TEXAS INSTRUMENTS; Mistral Part No: 143017080002-R; Package: VQFN48; Part_type: ICS\TELECOM\TRANSCEIVER; Project: TI_SVB_CONTROLLER CARD; RoHS: RoHS; Temperature: -40°C+85°C; Tolerance: NA; Voltage: NA; Wattage: NA; Weight: NA; Datasheet: Y:\MIS_DATABASE\DATASHEETS\ICS\DIGITAL\BUSTRANSCEIVER\DP83867I.PDF
C322 = CAP: CAP CERAMIC 10pF 25V 5% HI-Q C0G(NP0) 0201; Chkd/date: VASANTHA/081216; Crtd /date: MANIRAJA/081216; Custom_Duty: 15%; Customs_HS_Code: 85322990; Distributor_name: DIGIKEY; Distributor_part_number: 490-13312-1-ND; Footprint Path: Y:\MIS_DATABASE\Library\ALTIUM_TOOL\PCB_FOOTPRINTS\Altium_Footprint_Lib.PcbLib; Height: 0.33MM; Library Path: Y:\MIS_DATABASE\Library\ALTIUM_TOOL\SCHEMATICS_PARTS\MS_DISCRETE_Library.schlib; Mfr_name: MURATA; Mfr_part_number: GJM0335C1E100JB01D; Mistral Part No: 120016120010-R; Package: 0201; Part_type: CAPACITORS\CERAMIC; Project: OCTBTS5200; RoHS: RoHS; Temperature: -55°C+125°C; Tolerance: 5%; Voltage: 25V; Wattage: NA; Weight: 0.33mg; Datasheet: Y:\MIS_DATABASE\DATASHEETS\CAPACITORS\MURATA-GXX-SER_NOV17.PDF
FL22 = EMIFILTER_IND: IND FERRITE BEAD CHIP 120E 2A 0402; Chkd/date: NAVEED/241114; Crtd /date: USMAN/170613; Custom_Duty: 24%; Customs_HS_Code: 85369090; Distributor_name: DIGIKEY; Distributor_part_number: 490-9656-1-ND; Footprint Path: Y:\MIS_DATABASE\Library\ALTIUM_TOOL\PCB_FOOTPRINTS\Altium_Footprint_Lib.PcbLib; Height: 0.55MM; Library Path: Y:\MIS_DATABASE\Library\ALTIUM_TOOL\SCHEMATICS_PARTS\MS_FILTER_Library.schlib; Mfr_name: MURATA; Mfr_part_number: BLM15PX121SN1D; Mistral Part No: 130013060022-R; Package: 0402; Part_type: INDUCTOR; Project: GEN_3-8; RoHS: RoHS; Temperature: -55°C+125°C; Tolerance: 25%; Voltage: NA; Wattage: NA; Weight: 1mg; Datasheet: Y:\MIS_DATABASE\DATASHEETS\DISCRETES\INDUCTORS\BLM15-SN1-SER.PDF
LD2 LD4 LD7 LD9 = DIODE_LED: DIODE LED BRIGHT GREEN SMD; Chkd/date: MANIRAJA/261120; Crtd /date: ALVY/261120; Custom_Duty: 24%; Customs_HS_Code: 85439000; Distributor_name: DIGIKEY; Distributor_part_number: 732-13425-1-ND; Footprint Path: Y:\MIS_DATABASE\Library\ALTIUM_TOOL\PCB_FOOTPRINTS\Altium_Footprint_Lib.PcbLib; Height: 0.35MM; Library Path: Y:\MIS_DATABASE\Library\ALTIUM_TOOL\SCHEMATICS_PARTS\MS_OPTO_Library.schlib; Mfr_name: WURTH ELECTRONIK; Mistral Part No: 130020110071-R; Package: SMD; Part_type: OPTO\LED; Project: AM64X_SKEVM; RoHS: RoHS; Temperature: -40°C+85°C; Tolerance: NA; Voltage: NA; Wattage: NA; Weight: 29.3mg; Datasheet: Y:\MIS_DATABASE\DATASHEETS\DISCRETES\LEDS\150040VS73220.PDF
LD3 LD8 = DIODE_LED: DIODE LED RED SMD; Chkd/date: MANIRAJA/100920; Crtd /date: ALVY/100920; Custom_Duty: 24%; Customs_HS_Code: 85439000; Distributor_name: DIGIKEY; Distributor_part_number: 732-13422-1-ND; Footprint Path: Y:\MIS_DATABASE\Library\ALTIUM_TOOL\PCB_FOOTPRINTS\Altium_Footprint_Lib.PcbLib; Height: 0.35MM; Library Path: Y:\MIS_DATABASE\Library\ALTIUM_TOOL\SCHEMATICS_PARTS\MS_OPTO_Library.schlib; Mfr_name: WURTH ELECTRONICS; Mistral Part No: 130020090020-R; Package: SMD; Part_type: OPTO\LED; Project: AM64X_SKEVM; RoHS: RoHS; Temperature: -40°C+85°C; Tolerance: NA; Voltage: NA; Wattage: NA; Weight: 29.3mg; Datasheet: Y:\MIS_DATABASE\DATASHEETS\DISCRETES\LEDS\150040RS73220.PDF
LD5 LD6 = DIODE_LED: DIODE LED AMBER SMD; Chkd/date: MANIRAJA/100920; Crtd /date: ALVY/100920; Custom_Duty: 24%; Customs_HS_Code: 85439000; Distributor_name: DIGIKEY; Distributor_part_number: 732-13423-1-ND; Footprint Path: Y:\MIS_DATABASE\Library\ALTIUM_TOOL\PCB_FOOTPRINTS\Altium_Footprint_Lib.PcbLib; Height: 0.35MM; Library Path: Y:\MIS_DATABASE\Library\ALTIUM_TOOL\SCHEMATICS_PARTS\MS_OPTO_Library.schlib; Mfr_name: WURTH ELECTRONICS; Mistral Part No: 130020090022-R; Package: SMD; Part_type: OPTO\LED; Project: AM64X_SKEVM; RoHS: RoHS; Temperature: -40°C+85°C; Tolerance: NA; Voltage: NA; Wattage: NA; Weight: 29.3mg; Datasheet: Y:\MIS_DATABASE\DATASHEETS\DISCRETES\LEDS\150040AS73220.PDF
R159 R161 R166-R168 R170 R171 R175 = RESISTOR: RES 220E 1/10W 5% 0402; Chkd/date: VASANTHA/291216; Crtd /date: GEETHA/260406; Custom_Duty: 15%; Customs_HS_Code: 85332119; Distributor_name: DIGIKEY; Distributor_part_number: P220JCT-ND; Footprint Path: Y:\MIS_DATABASE\Library\ALTIUM_TOOL\PCB_FOOTPRINTS\Altium_Footprint_Lib.PcbLib; Height: 0.40MM; Library Path: Y:\MIS_DATABASE\Library\ALTIUM_TOOL\SCHEMATICS_PARTS\MS_DISCRETE_Library.schlib; Manufacturer: PANASONIC-ECG; Mfr_name: PANASONIC-ECG; Mfr_part_number: ERJ-2GEJ221X; Mistral Part No: 110009030506-R; Package: 0402; Part_type: RESISTORS\FIXED; Project: RED EYE; RoHS: RoHS; Temperature: -55°C+155°C; Tolerance: 5%; Voltage: NA; Wattage: 1/10W; Weight: 0.8mg; Datasheet: Y:\MIS_DATABASE\DATASHEETS\RESISTORS\PAN-ERJSER_NOV17.PDF
R368 = RESISTOR: RES 49.9E 1/16W 1% 0402; Chkd/date: MANIRAJA/210519; Crtd /date: MANIRAJA/210519; Custom_Duty: 15%; Customs_HS_Code: 85332119; Distributor_name: DIGIKEY; Distributor_part_number: 541-3967-1-ND; Footprint Path: Y:\MIS_DATABASE\Library\ALTIUM_TOOL\PCB_FOOTPRINTS\Altium_Footprint_Lib.PcbLib; Height: 0.35MM; Library Path: Y:\MIS_DATABASE\Library\ALTIUM_TOOL\SCHEMATICS_PARTS\MS_DISCRETE_Library.schlib; Mfr_name: VISHAY; Mfr_part_number: CRCW040249R9FKEDC; Mistral Part No: 110009030846-R; Package: 0402; Part_type: RESISTORS\FIXED; Project: RFSU_RFTJ_CARD; RoHS: RoHS; Temperature: -55°C+155°C; Tolerance: 1%; Voltage: NA; Wattage: 1/16W; Weight: 0.65mg; Datasheet: Y:\MIS_DATABASE\DATASHEETS\RESISTORS\CRCW_C-SER.PDF
U38 = TPIC2810D_SOIC16: IC 8-BIT LED DRIVER WITH I2C INTERFACE SOIC16; Chkd/date: MANIRAJA/230817; Crtd /date: MANIRAJA/220817; Custom_Duty: 15%; Customs_HS_Code: 85423100; Distributor_name: DIGIKEY; Distributor_part_number: 296-13746-5-ND; Height: 1.75MM; Mfr_name: TEXAS INSTRUMENTS; Mistral Part No: 141017080026-R; Package: SOIC16; Part_type: ICS\INTERFACE; Project: TI_MAXIE_CPB; RoHS: RoHS; Temperature: -40°C+125°C; Tolerance: NA; Voltage: NA; Wattage: NA; Weight: NA; Datasheet: Y:\MIS_DATABASE\DATASHEETS\ICS\INTERFACE\TPIC2810D.PDF
U52 = LMK1C1103_TSSOP8: IC 3-CHANNEL LVCMOS CLOCK BUFFER TSSOP8; Chkd/date: MANIRAJA/080920; Crtd /date: ALVY/070920; Custom_Duty: 15%; Customs_HS_Code: 85423100; Distributor_name: DIGIKEY; Distributor_part_number: 296-LMK1C1103PWRCT-ND; Footprint Path: Y:\MIS_DATABASE\Library\ALTIUM_TOOL\PCB_FOOTPRINTS\Altium_Footprint_Lib.PcbLib; Height: 1.20MM; Library Path: Y:\MIS_DATABASE\Library\ALTIUM_TOOL\SCHEMATICS_PARTS\MS_COMBINATIONAL_Library.schlib; Mfr_name: TEXAS INSTRUMENTS; Mistral Part No: 141020090002-R; Package: TSSOP8; Part_type: ICS\DIGITAL\COMBINATIONAL; Project: AM64X_SKEVM; RoHS: RoHS; Temperature: -40°C+125°C; Tolerance: NA; Voltage: NA; Wattage: NA; Weight: 34.1mg; Datasheet: Y:\MIS_DATABASE\DATASHEETS\ICS\DIGITAL\COMBINATIONAL\LMK1C110X.PDF
J23 = CON_FLEX_40X1_FH12A-40S-0.5SH: CON FPC 40X1 0.50MM PITCH RT TOP SMD; Chkd/date: SHREESHAIL/201106; Crtd /date: MAZHAR/171106; Custom_Duty: 24%; Customs_HS_Code: 85369090; Distributor_name: DIGIKEY; Distributor_part_number: HFK40CT-ND; Height: 2.00MM; Mfr_name: HIROSE ELECTRIC EUROPE; Mfr_part_number: FH12A-40S-0.5SH(55); Mistral Part No: 150009030176-R; Package: SMD; Part_type: CONNECTOR\FPC; Project: PMP LCD BOARD; Datasheet: Y:\MIS_DATABASE\DATASHEETS\CONNECTORS\FH12SERIES.PDF
R498 R499 R581 R600 = RESISTOR: RES 4.7K 1/20W 5% 0201; Chkd/date: MANIRAJA/200921; Crtd /date: ALVY/200921; Custom_Duty: 15%; Customs_HS_Code: 85332119; Distributor_name: DIGIKEY; Distributor_part_number: 311-4.7KNCT-ND; Footprint Path: Y:\MIS_DATABASE\Library\ALTIUM_TOOL\PCB_FOOTPRINTS\Altium_Footprint_Lib.PcbLib; Height: 0.26MM; Library Path: Y:\MIS_DATABASE\Library\ALTIUM_TOOL\SCHEMATICS_PARTS\MS_DISCRETE_Library.schlib; Mfr_name: YAGEO AMERICA; Mfr_part_number: RC0201JR-074K7L; Mistral Part No: 110021090007-R; Package: 0201; Part_type: RESISTORS\FIXED; Project: TI_AM62x SKEVM_BRD; RoHS: RoHS; Temperature: -55°C+125°C; Tolerance: 5%; Voltage: NA; Wattage: 1/20W; Weight: 0.17mg; Datasheet: Y:\MIS_DATABASE\DATASHEETS\RESISTORS\RCXXXXL-SER_MAR18.PDF
R582 = RESISTOR: RES 0E 1/8W 5% 0805; Chkd/date: VASANTHA/130416; Crtd /date: JEBRAN/020316; Custom_Duty: 15%; Customs_HS_Code: 85332119; Distributor_name: DIGIKEY; Distributor_part_number: 311-0.0ARCT-ND; Footprint Path: Y:\MIS_DATABASE\Library\ALTIUM_TOOL\PCB_FOOTPRINTS\Altium_Footprint_Lib.PcbLib; Height: 0.60MM; Library Path: Y:\MIS_DATABASE\Library\ALTIUM_TOOL\SCHEMATICS_PARTS\MS_DISCRETE_Library.schlib; Mfr_name: YAGEO AMERICA; Mfr_part_number: RC0805JR-070RL; Mistral Part No: 110009030074-R; Package: 0805; Part_type: RESISTORS\FIXED; Project: ZK_BIOMETRIC; RoHS: RoHS; Temperature: -55°C+155°C; Tolerance: 5%; Voltage: NA; Wattage: 1/8W; Weight: 5.5mg; Datasheet: Y:\MIS_DATABASE\DATASHEETS\RESISTORS\RCXXXXL-SER_MAR18.PDF
U42 = TCA9517DGKR_VSSOP8: IC 2-CHANNEL BI-DIR LEVEL-SHIFTING I2C BUS REPEATER SOIC8; Chkd/date: MANIRAJA/171121; Crtd /date: ALVY/161121; Custom_Duty: 15%; Customs_HS_Code: 85423100; Distributor_name: DIGIKEY; Distributor_part_number: 296-39221-1-ND; Footprint Path: Y:\MIS_DATABASE\Library\ALTIUM_TOOL\PCB_FOOTPRINTS\Altium_Footprint_Lib.PcbLib; Height: 1.75MM; Library Path: Y:\MIS_DATABASE\Library\ALTIUM_TOOL\SCHEMATICS_PARTS\MS_MISCINTERFACE_Library.schlib; Mfr_name: TEXAS INSTRUMENTS; Mistral Part No: 141021110017-R; Package: SOIC8; Part_type: ICS\INTERFACE\LEVEL TRANSLATOR; Project: EXCITER MULTI-CH RX UNIT; RoHS: RoHS; Temperature: -40°C+85°C; Tolerance: NA; Voltage: NA; Wattage: NA; Weight: 540mg; Datasheet: Y:\MIS_DATABASE\DATASHEETS\ICS\INTERFACE\TCA9517.PDF
U12 = AM62-EVM_BGA425: IC AM62 SoC MICROPROCESSOR BGA425; Chkd/date: ALVY/110621; Crtd /date: MANIRAJA/110621; Custom_Duty: 15%; Customs_HS_Code: 85423100; Distributor_name: NA; Distributor_part_number: NA; Footprint Path: Y:\MIS_DATABASE\Library\ALTIUM_TOOL\PCB_FOOTPRINTS\Altium_Footprint_Lib.PcbLib; Height: 0.65MM; Library Path: Y:\MIS_DATABASE\Library\ALTIUM_TOOL\SCHEMATICS_PARTS\MS_MICROPROCESSOR_Library.schlib; Mfr_name: TEXAS INSTRUMENTS; Mistral Part No: 141221060001; Package: BGA425; Part_type: ICS\DIGITAL\MICROPROCESSOR; Project: AM62_EVM_BRD; RoHS: NA; Temperature: NA; Tolerance: NA; Voltage: NA; Wattage: NA; Weight: NA; Datasheet: Y:\MIS_DATABASE\DATASHEETS\ICS\DIGITAL\MICROCONTROLLER\AM62-SoC_SVB.PDF

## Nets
DGND: C19.2 C21.2 C22.2 C24.2 C25.2 C26.2 C27.2 C28.2 C29.2 C32.2 C33.1 C35.2 C38.2 C39.2 C157.2 C159.2 C166.2 C195.2 C208.2 C216.2 C224.2 C227.2 C228.2 C234.1 C235.2 C236.2 C237.2 C238.2 C242.2 C322.2 C324.1 C325.1 C326.1 C375.2 C474.2 C477.2 J4.1(CH-GND) J23.7 J23.16 J23.25 J23.34 J23.40 J23.41 J23.42 Q4.4(S1) Q4.7(S2) Q5.4(S1) Q5.7(S2) Q6.4(S1) Q6.7(S2) R29.2 R35.2 R47.1 R49.1 R54.1 R160.2 R162.2 R169.2 R195.2 R292.1 R293.1 R295.1 R299.1 R328.2 R368.1 R712.1 U38.8(~{G}) U38.16(GND) U41.2(GND) U42.4(GND) U49.49(GND) U52.4(GND) ; also on sheet 1 10 11 12 13 14 15 16 17 18 19 20 21 22 23 27 28 29 30 31 32 33 34 35 36 37 38 39 40 41 42 43
VCC1V8_CLKBUF: C324.2 C325.2 C326.2 FL22.2 R380.2 U52.6(VDD) ; also on sheet 42
VCC3V3_TA: C166.1 C474.1 C477.1 J23.1 J23.2 J23.3 R218.1 R498.1 R499.1 R566.2 R567.2 R568.2 R581.1 R582.1 R585.2 R586.2 R587.2 R600.1 U42.8(VCCB) ; also on sheet 1 27
VCC_1V8: FL22.1 ; also on sheet 12 13 14 18 19 21 34 37 39 40 42
VCC_3V3_MAIN: R582.2 ; also on sheet 12 13 15
VCC_3V3_SYS: C19.1 C32.1 C38.1 C157.1 C159.1 C208.1 C227.1 C235.1 C236.1 C242.1 C375.1 FL15.1 R38.2 R159.1 R161.1 R166.1 R167.1 R168.1 R170.1 R171.1 R175.1 R196.2 R197.2 R286.1 R288.2 R291.2 R294.2 R298.1 R300.2 R311.2 R322.2 R329.1 R330.2 R334.2 R672.1 U38.1(VCC) U41.5(VCC) U42.1(VCCA) U49.19(VDDIO) U49.30(VDDIO) U49.41(VDDIO) ; also on sheet 10 12 13 14 18 19 20 22 23 27 29 30 31 32 33 34 35 36 37 38 39 40 41 42 43
VDD_1V0: C21.1 C22.1 C26.1 C27.1 C28.1 C29.1 C39.1 C224.1 C237.1 C238.1 U49.6(VDD1P0) U49.24(VDD1P0) U49.31(VDD1P0) U49.42(VDD1P0) ; also on sheet 12 23
VDD_2V5: C24.1 C25.1 C33.2 C35.1 C216.1 C228.1 U49.3(VDDA2P5) U49.9(VDDA2P5) ; also on sheet 13 17 23
BOOTMODE_I2C_SCL: R589.1 R600.2 ; also on sheet 1 27
BOOTMODE_I2C_SDA: R581.2 R591.1 ; also on sheet 1 27
CLKOUT0: U52.1(CLKIN) ; also on sheet 42
CPSW2_GPIO_0: J4.14 Q6.1(D1) Q6.2(D2) Q6.5(D3) Q6.6(D4) Q6.8(D5) R334.1
CPSW2_LED_1000: J4.12 Q4.1(D1) Q4.2(D2) Q4.5(D3) Q4.6(D4) Q4.8(D5)
CPSW2_LED_ACT: J4.13 Q5.1(D1) Q5.2(D2) Q5.5(D3) Q5.6(D4) Q5.8(D5) R288.1
CPSW_ETH2_D0N: J4.10(MX0-) U49.2(TD_M_A)
CPSW_ETH2_D0P: J4.9(MX0+) U49.1(TD_P_A)
CPSW_ETH2_D1M: J4.8(MX1-) U49.5(TD_M_B)
CPSW_ETH2_D1P: J4.7(MX1+) U49.4(TD_P_B)
CPSW_ETH2_D2M: J4.6(MX2-) U49.8(TD_M_C)
CPSW_ETH2_D2P: J4.5(MX2+) U49.7(TD_P_C)
CPSW_ETH2_D3M: J4.4(MX3-) U49.11(TD_M_D)
CPSW_ETH2_D3P: J4.3(MX3+) U49.10(TD_P_D)
CPSW_ETH2_GPIO_0: R293.2 R294.1 R302.1 R340.1 TP12.1(TP)
CPSW_ETH2_GPIO_1: R291.1 R292.2 R301.1 TP13.1(TP)
CPSW_ETH2_LED0: TP15.1(TP) U49.47(LED_0)
CPSW_ETH2_LED_1000: R47.2 R289.1 R300.1 TP17.1(TP) U49.46(LED_1)
CPSW_ETH2_LED_ACT: R38.1 R295.2 R338.1 TP11.1(TP) U49.45(LED_2)
CPSW_RGMII1_ETH1_CLK: R382.2 ; also on sheet 23
CPSW_RGMII1_RD0: U12.AB17(RGMII1_RD0) ; also on sheet 23
CPSW_RGMII1_RD1: U12.AC17(RGMII1_RD1) ; also on sheet 23
CPSW_RGMII1_RD2: U12.AB16(RGMII1_RD2) ; also on sheet 23
CPSW_RGMII1_RD3: U12.AA15(RGMII1_RD3) ; also on sheet 23
CPSW_RGMII1_RX_CTL: U12.AE17(RGMII1_RX_CTL) ; also on sheet 23
CPSW_RGMII1_RXC: U12.AD17(RGMII1_RXC) ; also on sheet 23
CPSW_RGMII1_TD0: U12.AE20(RGMII1_TD0) ; also on sheet 23
CPSW_RGMII1_TD1: U12.AD20(RGMII1_TD1) ; also on sheet 23
CPSW_RGMII1_TD2: U12.AE18(RGMII1_TD2) ; also on sheet 23
CPSW_RGMII1_TD3: U12.AD18(RGMII1_TD3) ; also on sheet 23
CPSW_RGMII1_TX_CTL: U12.AD19(RGMII1_TX_CTL) ; also on sheet 23
CPSW_RGMII1_TXC: R360.2 ; also on sheet 23
CPSW_RGMII2_ETH2_CLK: R369.2 U49.15(XI)
CPSW_RGMII2_ETH2_CLK_OUT: TP20.1(TP) U49.18(CLK_OUT)
CPSW_RGMII2_ETH2_RBIAS: C234.2 R328.1 U49.12(RBIAS)
CPSW_RGMII2_MDC: R329.2 R673.2 U49.16(MDC)
CPSW_RGMII2_MDIO: R330.1 R674.2 U49.17(MDIO)
CPSW_RGMII2_RD0: R54.2 R322.1 U12.AE23(RGMII2_RD0) U49.33(RX_D0)
CPSW_RGMII2_RD1: U12.AB20(RGMII2_RD1) U49.34(RX_D1)
CPSW_RGMII2_RD2: R49.2 R311.1 U12.AC21(RGMII2_RD2) U49.35(RX_D2)
CPSW_RGMII2_RD3: U12.AE22(RGMII2_RD3) U49.36(RX_D3)
CPSW_RGMII2_RESETn: R35.1 U41.4(Y) U49.43(RESET_N)
CPSW_RGMII2_RX_CTL: R298.2 R299.2 U12.AD22(RGMII2_RX_CTL) U49.38(RX_DV/RX_CTRL)
CPSW_RGMII2_RXC: R324.1 U12.AD23(RGMII2_RXC)
CPSW_RGMII2_TD0: U12.Y18(RGMII2_TD0) U49.28(TX_D0)
CPSW_RGMII2_TD1: U12.AA18(RGMII2_TD1) U49.27(TX_D1)
CPSW_RGMII2_TD2: U12.AD21(RGMII2_TD2) U49.26(TX_D2)
CPSW_RGMII2_TD3: U12.AC20(RGMII2_TD3) U49.25(TX_D3)
CPSW_RGMII2_TX_CTL: U12.AA19(RGMII2_TX_CTL) U49.37(TX_EN/TX_CTRL)
CPSW_RGMII2_TXC: R65.2 U49.29(GTX_CLK)
CPSW_RGMII_INTn: R672.2 U49.44(INT/PWDN) ; also on sheet 23
ETH2_EARTH: C195.1 J4.15(SH1) J4.16(SH2) R29.1
GPIO_CPSW2_RST: R195.1 R196.1 U41.1(A) ; also on sheet 39
LED1: LD9.1(CATHODE) U38.3(DRAIN0)
LED2: LD8.1(CATHODE) U38.4(DRAIN1)
LED3: LD7.1(CATHODE) U38.5(DRAIN2)
LED4: LD6.1(CATHODE) U38.6(DRAIN3)
LED5: LD2.1(CATHODE) U38.11(DRAIN4)
LED6: LD3.1(CATHODE) U38.12(DRAIN5)
LED7: LD4.1(CATHODE) U38.13(DRAIN6)
LED8: LD5.1(CATHODE) U38.14(DRAIN7)
PORz_OUT: U41.3(B) ; also on sheet 20 23 27 42
RESETSTATz: R194.1 ; also on sheet 13 19 20 21 23 27 32 33 37 39 40 41 42
SoC_CLKIN: C322.1 R368.2 R372.2 ; also on sheet 34
SOC_I2C1_SCL: U42.2(SCLA) ; also on sheet 14 22 39 40 41 42
SOC_I2C1_SDA: U42.3(SDAA) ; also on sheet 14 22 39 40 41 42
SoC_I2C1_TA_SCL: R499.2 R583.1 U42.7(SCLB) ; also on sheet 1
SoC_I2C1_TA_SDA: R498.2 R590.1 U42.6(SDAB) ; also on sheet 1
SOC_RGMII_MDC: R673.1 ; also on sheet 23 32
SOC_RGMII_MDIO: R674.1 ; also on sheet 23 32
TEST_GPIO1: R587.1 R596.1 ; also on sheet 1 43
TEST_GPIO2: R567.1 R571.1 TP117.1(TP) ; also on sheet 1
TEST_GPIO3: R597.1 TP73.1(TP) ; also on sheet 1 27
TEST_GPIO4: R568.1 R569.1 TP74.1(TP) ; also on sheet 1 27
TEST_PORZn: R586.1 R595.1 ; also on sheet 1 42
TEST_POWERDOWN: R585.1 R594.1 ; also on sheet 1 13
TEST_WARMRESETn: R566.1 R570.1 ; also on sheet 1 43
WKUP_I2C0_SCL: U38.15(SCL) ; also on sheet 32
WKUP_I2C0_SDA: U38.2(SDA) ; also on sheet 32
N16800246: FL15.2 J4.2(VCC)
N16943223: R380.1 U52.2(1G)
N16943354: R372.1 U52.3(Y0)
N16943356: R382.1 U52.8(Y1)
N16943358: R369.1 U52.5(Y2)
N16944070: R360.1 U12.AE19(RGMII1_TXC)
N16944341: R65.1 U12.AE21(RGMII2_TXC)
N16944941: LD9.2(ANODE) R175.2
N16944943: LD8.2(ANODE) R171.2
N16944955: LD7.2(ANODE) R170.2
N16944965: LD6.2(ANODE) R168.2
N16944969: LD2.2(ANODE) R159.2
N16944978: LD3.2(ANODE) R161.2
N16944987: LD4.2(ANODE) R166.2
N16944997: LD5.2(ANODE) R167.2
N16945140: R169.1 U38.7(A2)
N16945144: R162.1 U38.10(A1)
N16945148: R160.1 U38.9(A0)
N16990175: J23.27 R595.2
N16990176: J23.30 R596.2
N16990179: J23.31 R571.2
N16990180: J23.32 R597.2
N16990246: J23.26 R594.2
N16990247: J23.28 R570.2
N16990252: J23.33 R569.2
N17149186: TP101.1(TP) U49.13(VDDA1P8)
N17149287: J4.11 R286.2
N17167691: R324.2 U49.32(RX_CLK)
N17434691: TP19.1(TP) U49.48(VDDA1P8)
N17473283: R194.2 R197.1 U41.6(C)
N17654451: Q4.3(G) R289.2
N17799775: Q6.3(G) R340.2
N17800599: Q5.3(G) R338.2
N18374804: J23.36 R583.2
N18374807: J23.37 R589.2
N18374810: J23.38 R590.2
N18374813: J23.39 R591.2
N18576730: R302.2 U49.39(GPIO_0)
N18576733: R301.2 U49.40(GPIO_1)
N20274420: TP103.1(TP) U49.14(XO)
N20607945: R218.2 R712.2 U42.5(EN)

Not connected (* = marked no-connect by the designer): J23 4* 5* 6* 8* 9* 10* 11* 12* 13* 14* 15* 17* 18* 19* 20* 21* 22* 23* 24* 29* 35*; U49 20(JTAG_CLK)* 21(JTAG_TDO)* 22(JTAG_TMS)* 23(JTAG_TDI)*; U52 7(NC)*

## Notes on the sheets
sheet 24
- CPSW RGMII 2 - PHY
- RJ45 CONNECTOR WITH
  INTEGRATED MAGNETICS
- 100E
- 100E
- 100E
- 100E
- Silk: CPSW PHY-2
- PHY ADDRESS = 00001
- 10/100/1000 advertised, Auto-MDI-X
- Auto-negotiation Enabled
- Tx Clock Skew = 0ns
- Rx Clock Skew = 2ns
sheet 25
- ETHERNET PHY CLOCK BUFFER
- LED DRIVER
- GREEN
- RED
- GREEN
- AMBER
- GREEN
- RED
- GREEN
- AMBER
- I2C ADDRESS: 0x60
sheet 26
- 40-PIN TEST AUTOMATION HEADER
- I2C BUS BUFFER
- Silk: AUTOMATION HDR
- TEST AUTOMATION GPIO MAPPING
- Internal/
  External
  PU/PD states
- SIGNAL NAME
- DESCRIPTION
- Direction WRT CTRL
- OUTPUT
  OUTPUT
  OUTPUT
  OUTPUT
  OUTPUT
  OUTPUT
  OUTPUT
- TEST_POWERDOWN
  TEST_PORZn
  TEST_WARMRESETn
  TEST_GPIO1
  TEST_GPIO2
  TEST_GPIO3
  TEST_GPIO4
- Used to Power down the EVM
  Used to  Reset the SoC PORz
  Used to Reset the SoC Warmreset
  Used to Generate the interrupt on
  MCU_GPIO0_15 Pin
  Connected to a Testpoint
  Used to Enable the BOOTMODE Buffer
  Used to Reset the Bootmode I2C IO Expander
- External Pullup
  External Pullup
  External Pullup
  External Pullup
  External Pullup
  External Pullup
  External Pullup
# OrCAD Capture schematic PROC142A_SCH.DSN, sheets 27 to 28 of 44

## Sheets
27 26. BOOT MODE BUFFER & SWITCHES: size C; title: BOOT MODE BUFFER & SWITCHES
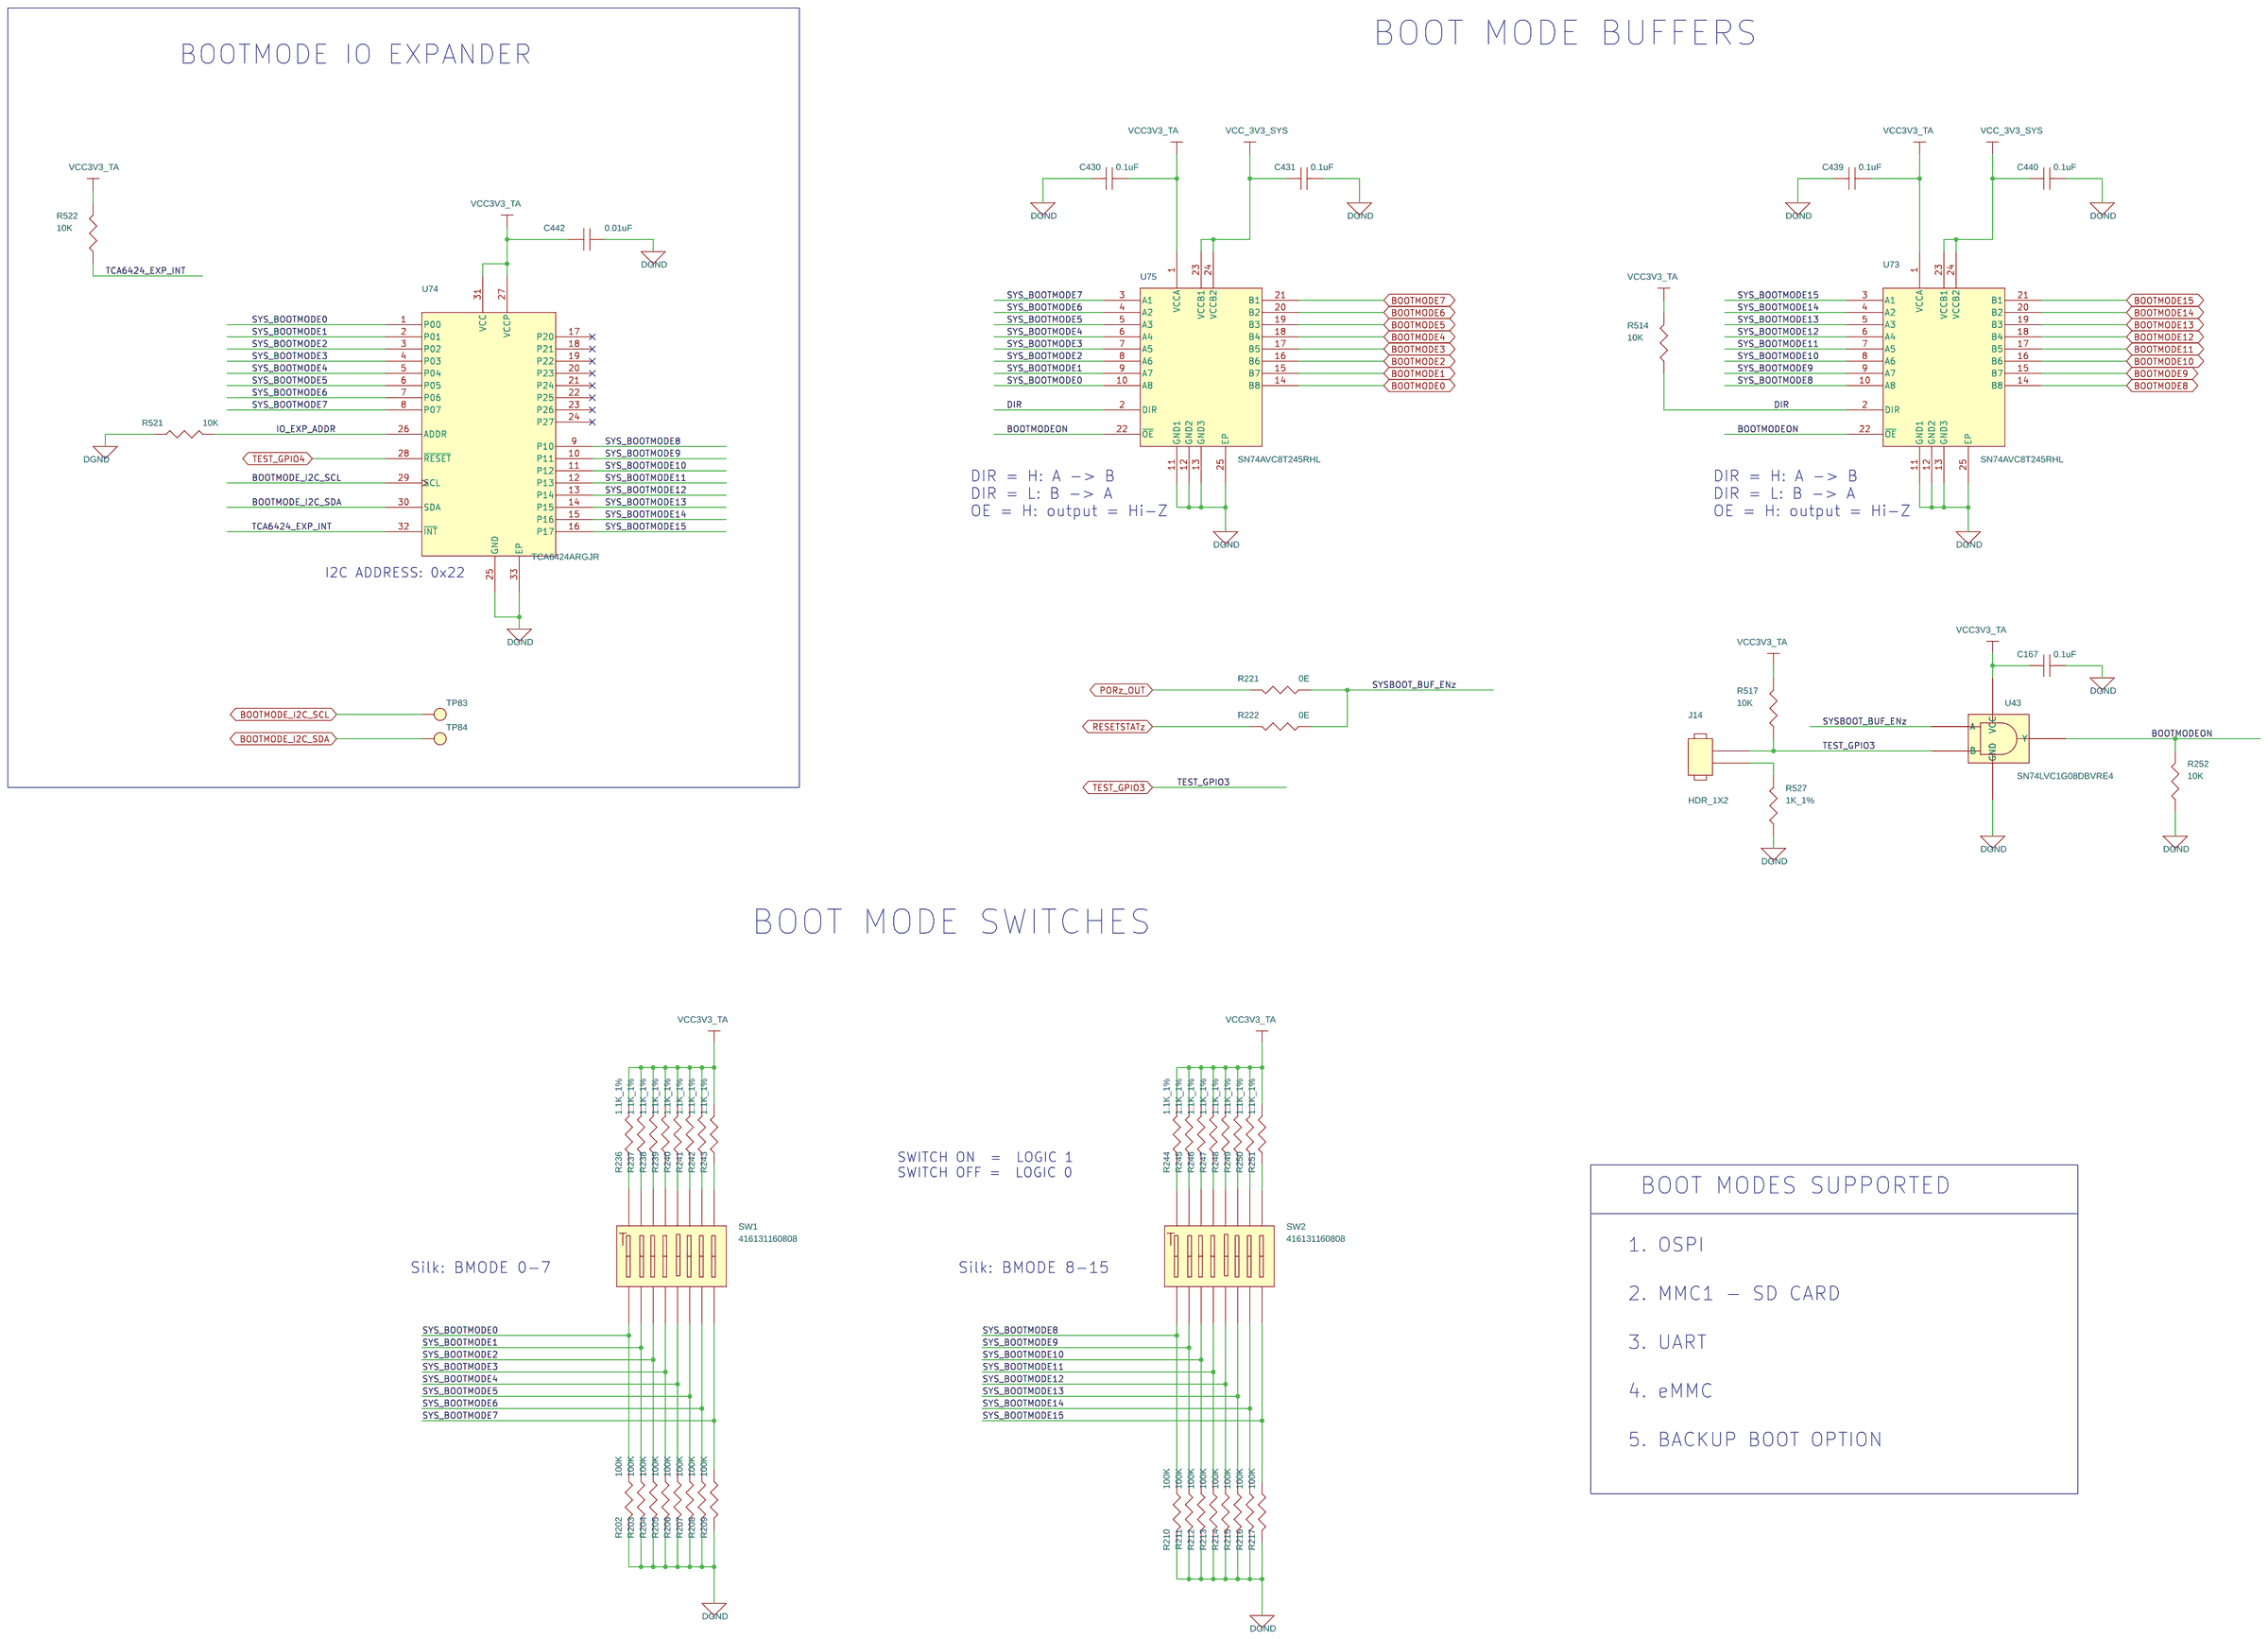
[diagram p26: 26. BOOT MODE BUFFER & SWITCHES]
28 27. XDS110 DEBUGGER: size C; title: XDS110 DEBUGGER

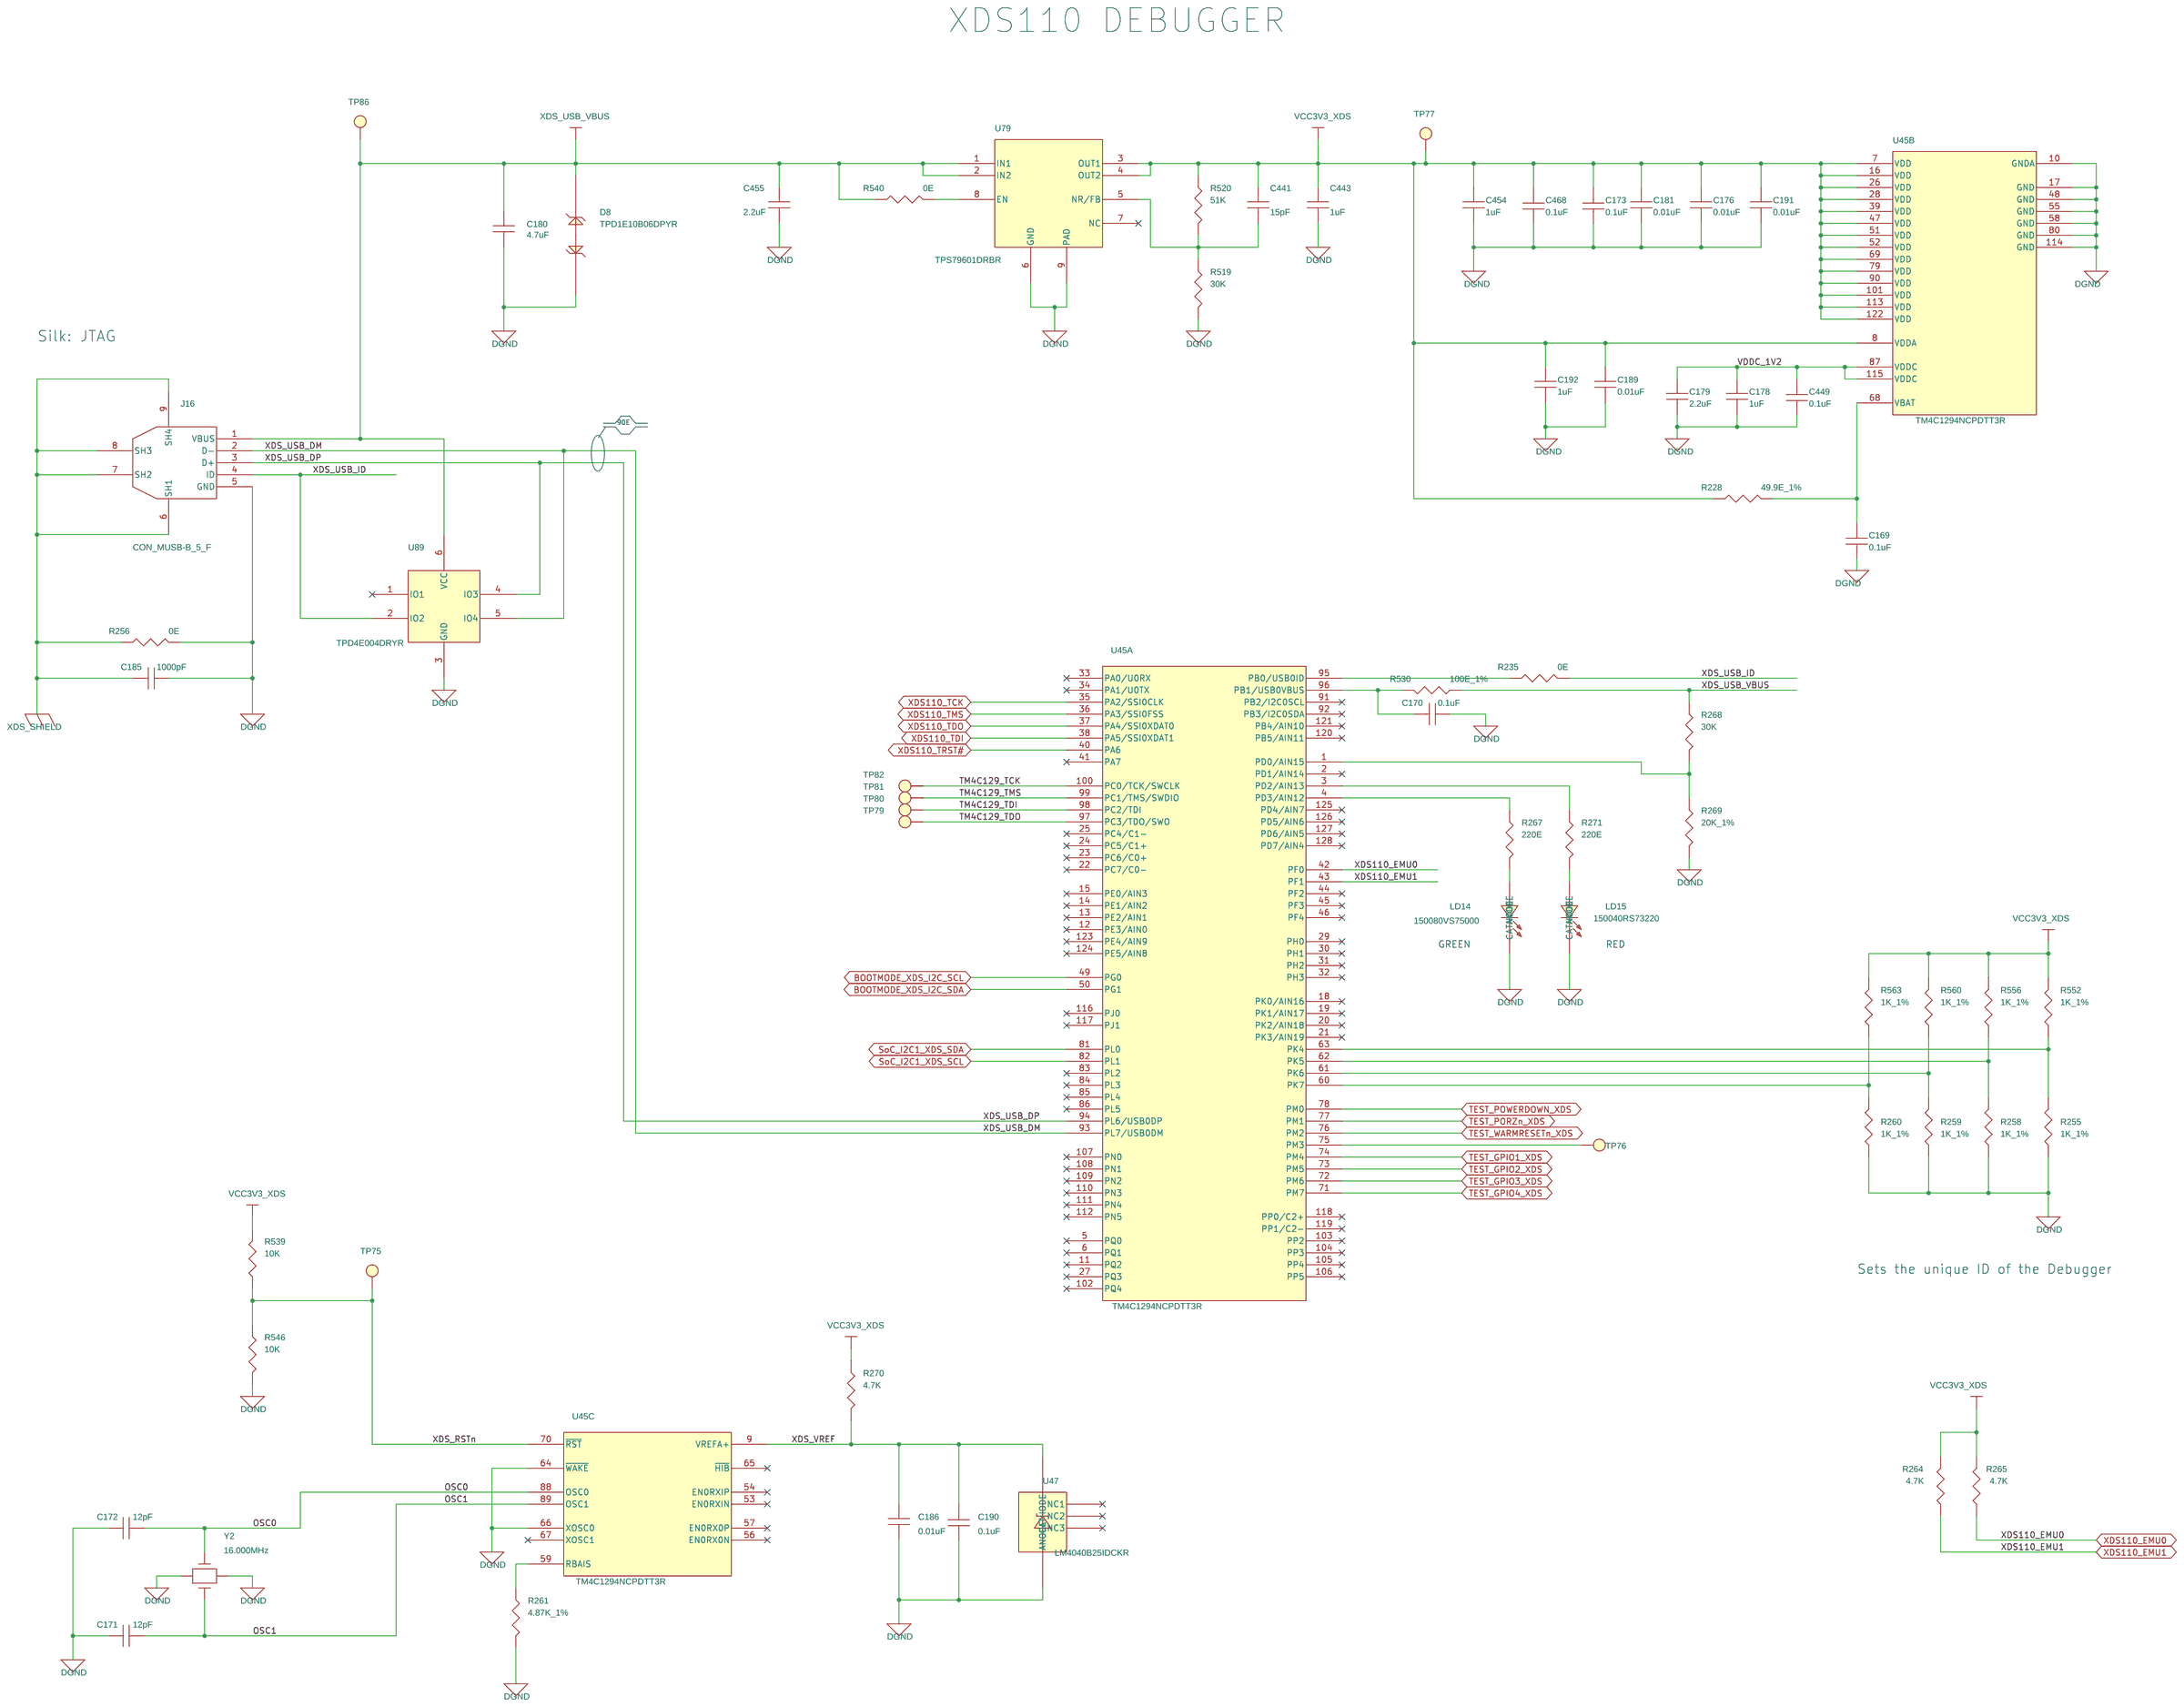
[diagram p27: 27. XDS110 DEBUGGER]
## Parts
sheet 26. BOOT MODE BUFFER & SWITCHES
C167  0.1uF  [CAP0201_0-5]
C430  0.1uF  [CAP0201_0-5]
C431  0.1uF  [CAP0201_0-5]
C439  0.1uF  [CAP0201_0-5]
C440  0.1uF  [CAP0201_0-5]
C442  0.01uF  [CAP0201_0-5]
J14  HDR_1X2  [HDR_1X2_90120-0122_S_T_5-6]
R202  100K  [RES0201_0-5]
R203  100K  [RES0201_0-5]
R204  100K  [RES0201_0-5]
R205  100K  [RES0201_0-5]
R206  100K  [RES0201_0-5]
R207  100K  [RES0201_0-5]
R208  100K  [RES0201_0-5]
R209  100K  [RES0201_0-5]
R210  100K  [RES0201_0-5]
R211  100K  [RES0201_0-5]
R212  100K  [RES0201_0-5]
R213  100K  [RES0201_0-5]
R214  100K  [RES0201_0-5]
R215  100K  [RES0201_0-5]
R216  100K  [RES0201_0-5]
R217  100K  [RES0201_0-5]
R221  0E  [RES0201_0-5]
R222  0E  [RES0402_0-5]
R236  1.1K_1%  [RES0201_0-5]
R237  1.1K_1%  [RES0201_0-5]
R238  1.1K_1%  [RES0201_0-5]
R239  1.1K_1%  [RES0201_0-5]
R240  1.1K_1%  [RES0201_0-5]
R241  1.1K_1%  [RES0201_0-5]
R242  1.1K_1%  [RES0201_0-5]
R243  1.1K_1%  [RES0201_0-5]
R244  1.1K_1%  [RES0201_0-5]
R245  1.1K_1%  [RES0201_0-5]
R246  1.1K_1%  [RES0201_0-5]
R247  1.1K_1%  [RES0201_0-5]
R248  1.1K_1%  [RES0201_0-5]
R249  1.1K_1%  [RES0201_0-5]
R250  1.1K_1%  [RES0201_0-5]
R251  1.1K_1%  [RES0201_0-5]
R252  10K  [RES0201_0-5]
R514  10K  [RES0201_0-5]
R517  10K  [RES0201_0-5]
R521  10K  [RES0201_0-5]
R522  10K  [RES0201_0-5]
R527  1K_1%  [RES0402_0-5]
SW1  416131160808  [SW16_416131160808_460X230_SMD_2-7]
SW2  416131160808  [SW16_416131160808_460X230_SMD_2-7]
TP83  TP20_SMD  [TP20_SMD]
TP84  TP20_SMD  [TP20_SMD]
U43  SN74LVC1G08DBVRE4  [SOT23-5]
U73  SN74AVC8T245RHL  [QFN24_19-68_220X140_1]
U74  TCA6424ARGJR  [QFN32_19-68_200X200]
U75  SN74AVC8T245RHL  [QFN24_19-68_220X140_1]
sheet 27. XDS110 DEBUGGER
C169  0.1uF  [CAP0201_0-5]
C170  0.1uF  [CAP0201_0-5]
C171  12pF  [CAP0201_0-5]
C172  12pF  [CAP0201_0-5]
C173  0.1uF  [CAP0201_0-5]
C176  0.01uF  [CAP0201_0-5]
C178  1uF  [CAP0201_0-5]
C179  2.2uF  [CAP0402_0-75]
C180  4.7uF  [CAP0402_0-75]
C181  0.01uF  [CAP0201_0-5]
C185  1000pF  [CAP1206_1-75]
C186  0.01uF  [CAP0201_0-5]
C189  0.01uF  [CAP0201_0-5]
C190  0.1uF  [CAP0201_0-5]
C191  0.01uF  [CAP0201_0-5]
C192  1uF  [CAP0201_0-5]
C441  15pF  [CAP0201_0-5]
C443  1uF  [CAP0201_0-5]
C449  0.1uF  [CAP0201_0-5]
C454  1uF  [CAP0201_0-5]
C455  2.2uF  [CAP0402_0-75]
C468  0.1uF  [CAP0201_0-5]
D8  TPD1E10B06DPYR  [DIO_DFN0402_0-5]
J16  CON_MUSB-B_5_F  [CON_MUSBB5_629105150521_S_R_S_2-7]
LD14  150080VS75000  [LED_150080VS75000_80X50_SMD_0-8]
LD15  150040RS73220  [LED_150040GS73220_40X20_SMD_0-4]
R228  49.9E_1%  [RES0402_0-5]
R235  0E  [RES0402_0-5]
R255  1K_1%  [RES0402_0-5]
R256  0E  [RES0603_0-75]
R258  1K_1%  [RES0402_0-5]
R259  1K_1%  [RES0402_0-5]
R260  1K_1%  [RES0402_0-5]
R261  4.87K_1%  [RES0402]
R264  4.7K  [RES0201_0-5]
R265  4.7K  [RES0201_0-5]
R267  220E  [RES0402_0-5]
R268  30K  [RES0402_0-5]
R269  20K_1%  [RES0402_0-5]
R270  4.7K  [RES0201_0-5]
R271  220E  [RES0402_0-5]
R519  30K  [RES0402_0-5]
R520  51K  [RES0402_0-5]
R530  100E_1%  [RES0402_0-5]
R539  10K  [RES0201_0-5]
R540  0E  [RES0201_0-5]
R546  10K  [RES0201_0-5]
R552  1K_1%  [RES0402_0-5]
R556  1K_1%  [RES0402_0-5]
R560  1K_1%  [RES0402_0-5]
R563  1K_1%  [RES0402_0-5]
TP75  TP20_SMD  [TP20_SMD]
TP76  TP20_SMD  [TP20_SMD]
TP77  TP20_SMD  [TP20_SMD]
TP79  TP20_SMD  [TP20_SMD]
TP80  TP20_SMD  [TP20_SMD]
TP81  TP20_SMD  [TP20_SMD]
TP82  TP20_SMD  [TP20_SMD]
TP86  TP20_SMD  [TP20_SMD]
U45  TM4C1294NCPDTT3R  [TQFP128_15-74_550X550_1-2]  (sections A,B,C)
U47  LM4040B25IDCKR  [SC70-5_1-1]
U79  TPS79601DRBR  [SON8_25-59_130X130_1]
U89  TPD4E004DRYR  [SON6_19-68_40X60_PB_0-6]
Y2  16.000MHz  [XTAL4_XRCGB-FM_80X60_SMD_0-7]

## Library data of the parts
C167 C169 C170 C173 C190 C430 C431 C439 C440 C449 C468 = CAP: CAP CERAMIC 0.1uF 16V 10% X5R 0201; Alt_Mfr_name: YAGEO AMERICA; Alt_Mfr_part_number: CC0402KRX5R8BB104; Chkd/date: MANIRAJA/230118; Crtd /date: MANIRAJA/230118; Custom_Duty: 15%; Customs_HS_Code: 85322990; Distributor_name: DIGIKEY; Distributor_part_number: 490-14305-1-ND; Footprint Path: Y:\MIS_DATABASE\Library\ALTIUM_TOOL\PCB_FOOTPRINTS\Altium_Footprint_Lib.PcbLib; Height: 0.33MM; Library Path: Y:\MIS_DATABASE\Library\ALTIUM_TOOL\SCHEMATICS_PARTS\MS_DISCRETE_Library.schlib; Mfr_name: MURATA; Mfr_part_number: GRM033R61C104KE14D; Mistral Part No: 120009030072-R; Package: 0201; Part_type: CAPACITORS\CERAMIC; Project: TI_MAXIE_CPB; RoHS: RoHS; Temperature: -55°C+85°C; Tolerance: 10%; Voltage: 16V; Wattage: NA; Weight: 0.33mg; Datasheet: Y:\MIS_DATABASE\DATASHEETS\CAPACITORS\GRM033R61C104KE14.PDF
C176 C181 C186 C189 C191 C442 = CAP: CAP CERAMIC 0.01uF 25V 10% X5R 0201; Chkd/date: MANIRAJA/230118; Crtd /date: MANIRAJA/230118; Custom_Duty: 15%; Customs_HS_Code: 85322990; Distributor_name: DIGIKEY; Distributor_part_number: GRM033R61E103KA12J-ND; Footprint Path: Y:\MIS_DATABASE\Library\ALTIUM_TOOL\PCB_FOOTPRINTS\Altium_Footprint_Lib.PcbLib; Height: 0.33MM; Library Path: Y:\MIS_DATABASE\Library\ALTIUM_TOOL\SCHEMATICS_PARTS\MS_DISCRETE_Library.schlib; Mfr_name: MURATA; Mfr_part_number: GRM033R61E103KA12J; Mistral Part No: 120018010007-R; Package: 0201; Part_type: CAPACITORS\CERAMIC; Project: TI_MAXIE_CPB; RoHS: RoHS; Temperature: -55°C+85°C; Tolerance: 10%; Voltage: 25V; Wattage: NA; Weight: 0.33mg; Datasheet: Y:\MIS_DATABASE\DATASHEETS\CAPACITORS\GRM033R61E103KA12.PDF
J14 = HEADER_2X1: CON HDR 1X2 2.54MM PITCH ST TH; Chkd/date: NAVEED/210714; Crtd /date: USMAN/031012; Custom_Duty: 24%; Customs_HS_Code: 85369090; Distributor_name: DIGIKEY; Distributor_part_number: WM8072-ND; Footprint Path: Y:\MIS_DATABASE\Library\ALTIUM_TOOL\PCB_FOOTPRINTS\Altium_Footprint_Lib.PcbLib; Height: 5.60MM; Library Path: Y:\MIS_DATABASE\Library\ALTIUM_TOOL\SCHEMATICS_PARTS\MS_CONNECTOR_Library.schlib; Mfr_name: MOLEX; Mfr_part_number: 90120-0122; Mistral Part No: 150012100005-R; Package: THRU-HOLE; Part_type: CONNECTOR\HEADERS; Project: NPOL_FEP; RoHS: RoHS; Temperature: -55°C+125°C; Tolerance: NA; Voltage: NA; Wattage: NA; Weight: 122mg; Datasheet: Y:\MIS_DATABASE\DATASHEETS\CONNECTORS\90120-XX.PDF
R202-R217 = RESISTOR: RES 100K 1/20W 5% 0201; Chkd/date: VASANTHA/061216; Crtd /date: MAZHAR/141105; Custom_Duty: 15%; Customs_HS_Code: 85332119; Distributor_name: DIGIKEY; Distributor_part_number: P100KAGCT-ND; Footprint Path: Y:\MIS_DATABASE\Library\ALTIUM_TOOL\PCB_FOOTPRINTS\Altium_Footprint_Lib.PcbLib; Height: 0.26MM; Library Path: Y:\MIS_DATABASE\Library\ALTIUM_TOOL\SCHEMATICS_PARTS\MS_DISCRETE_Library.schlib; Mfr_name: PANASONIC-ECG; Mfr_part_number: ERJ-1GEJ104C; Mistral Part No: 110009030176-R; Package: 0201; Part_type: RESISTORS\FIXED; Project: J30; RoHS: RoHS; Temperature: -55°C+125°C; Tolerance: 5%; Voltage: NA; Wattage: 1/20W; Weight: 0.15mg; Datasheet: Y:\MIS_DATABASE\DATASHEETS\RESISTORS\PAN-ERJXGE-FEB06.PDF
R221 R540 = RESISTOR: RES 0E 1/20W 5% 0201; Chkd/date: NAVEED/301214; Crtd /date: MUDDU/120710; Custom_Duty: 15%; Customs_HS_Code: 85332119; Distributor_name: DIGIKEY; Distributor_part_number: 311-0.0NCT-ND; Footprint Path: Y:\MIS_DATABASE\Library\ALTIUM_TOOL\PCB_FOOTPRINTS\Altium_Footprint_Lib.PcbLib; Height: 0.26MM; Library Path: Y:\MIS_DATABASE\Library\ALTIUM_TOOL\SCHEMATICS_PARTS\MS_DISCRETE_Library.schlib; Mfr_name: YAGEO AMERICA; Mfr_part_number: RC0201JR-070RL; Mistral Part No: 110010070067-R; Package: 0201; Part_type: RESISTORS\FIXED; Project: PB_BUGBASE; RoHS: RoHS; Temperature: -55°C+125°C; Tolerance: 5%; Voltage: NA; Wattage: 1/20W; Weight: 0.17mg; Datasheet: Y:\MIS_DATABASE\DATASHEETS\RESISTORS\RCXXXXL-SER_MAR18.PDF
R222 R235 = RESISTOR: RES 0E 1/16W JUMPER 0402; Chkd/date: VASANTHA/201216; Crtd /date: MUDDU/190810; Custom_Duty: 15%; Customs_HS_Code: 85332119; Distributor_name: DIGIKEY; Distributor_part_number: 541-0.0JCT-ND; Footprint Path: Y:\MIS_DATABASE\Library\ALTIUM_TOOL\PCB_FOOTPRINTS\Altium_Footprint_Lib.PcbLib; Height: 0.40MM; Library Path: Y:\MIS_DATABASE\Library\ALTIUM_TOOL\SCHEMATICS_PARTS\MS_DISCRETE_Library.schlib; Mfr_name: VISHAY; Mfr_part_number: CRCW04020000Z0ED; Mistral Part No: 110010080019-R; Package: 0402; Part_type: RESISTORS\FIXED; Project: PB_BUGBASE; RoHS: RoHS; Temperature: -55°C+155°C; Tolerance: NA; Voltage: NA; Wattage: 1/16W; Weight: 0.65mg; Datasheet: Y:\MIS_DATABASE\DATASHEETS\RESISTORS\CRCW0603.PDF
R236-R251 = RESISTOR: RES 1.1K 1/20W 1% 0201; Chkd/date: MAZHAR/121207; Crtd /date: USMAN/121207; Custom_Duty: 15%; Customs_HS_Code: 85332119; Distributor_name: DIGIKEY; Distributor_part_number: P1.10KABCT-ND; Footprint Path: Y:\MIS_DATABASE\Library\ALTIUM_TOOL\PCB_FOOTPRINTS\Altium_Footprint_Lib.PcbLib; Height: 0.26MM; Library Path: Y:\MIS_DATABASE\Library\ALTIUM_TOOL\SCHEMATICS_PARTS\MS_DISCRETE_Library.schlib; Mfr_name: PANASONIC-ECG; Mfr_part_number: ERJ-1GEF1101C; Mistral Part No: 110009030097-R; Package: 0201; Part_type: RESISTORS\FIXED; Project: SD_WATERLOO; RoHS: RoHS; Temperature: -55°C+125°C; Tolerance: 1%; Voltage: NA; Wattage: 1/20W; Weight: 0.15mg; Datasheet: Y:\MIS_DATABASE\DATASHEETS\RESISTORS\PAN-ERJSER_NOV17.PDF
R252 R514 R517 R521 R522 R539 R546 = RESISTOR: RES 10K 1/20W 5% 0201; Chkd/date: MANIRAJA/050517; Crtd /date: MANIRAJA/050517; Custom_Duty: 15%; Customs_HS_Code: 85332119; Distributor_name: DIGIKEY; Distributor_part_number: 311-10KNCT-ND; Footprint Path: Y:\MIS_DATABASE\Library\ALTIUM_TOOL\PCB_FOOTPRINTS\Altium_Footprint_Lib.PcbLib; Height: 0.26MM; Library Path: Y:\MIS_DATABASE\Library\ALTIUM_TOOL\SCHEMATICS_PARTS\MS_DISCRETE_Library.schlib; Mfr_name: YAGEO AMERICA; Mfr_part_number: RC0201JR-0710KL; Mistral Part No: 110010070051-R; Package: 0201; Part_type: RESISTORS\FIXED; Project: GOLDEN-I LITE; RoHS: RoHS; Temperature: -55°C+125°C; Tolerance: 5%; Voltage: NA; Wattage: 1/20W; Weight: 0.17mg; Datasheet: Y:\MIS_DATABASE\DATASHEETS\RESISTORS\RCXXXXL-SER_MAR18.PDF
R255 R258-R260 R527 R552 R556 R560 R563 = RESISTOR: RES 1K 1/10W 1% 0402; Chkd/date: VASANTHA/281216; Crtd /date: MAZHAR/150506; Custom_Duty: 15%; Customs_HS_Code: 85332119; Distributor_name: DIGIKEY; Distributor_part_number: P1.00KLCT-ND; Footprint Path: Y:\MIS_DATABASE\Library\ALTIUM_TOOL\PCB_FOOTPRINTS\Altium_Footprint_Lib.PcbLib; Height: 0.40MM; Library Path: Y:\MIS_DATABASE\Library\ALTIUM_TOOL\SCHEMATICS_PARTS\MS_DISCRETE_Library.schlib; Mfr_name: PANASONIC-ECG; Mfr_part_number: ERJ-2RKF1001X; Mistral Part No: 110009030411-R; Package: 0402; Part_type: RESISTORS\FIXED; Project: VOCERA; RoHS: RoHS; Temperature: -55°C+155°C; Tolerance: 1%; Voltage: NA; Wattage: 1/10W; Weight: 0.8mg; Datasheet: Y:\MIS_DATABASE\DATASHEETS\RESISTORS\PAN-ERJSER_NOV17.PDF
SW1 SW2 = SW16_CHS-08A: SWITCH SLIDE SPST ST SMD; Chkd/date: MANIRAJA/051020; Crtd /date: ALVY/011020; Custom_Duty: 24%; Customs_HS_Code: 85369090; Distributor_name: DIGIKEY; Distributor_part_number: 732-3857-1-ND; Footprint Path: Y:\MIS_DATABASE\Library\ALTIUM_TOOL\PCB_FOOTPRINTS\Altium_Footprint_Lib.PcbLib; Height: 2.65MM; Library Path: Y:\MIS_DATABASE\Library\ALTIUM_TOOL\SCHEMATICS_PARTS\MS_SWITCH_Library.schlib; Mfr_name: WURTH ELECTRONICS; Mistral Part No: 130020100001-R; Package: SMD; Part_type: ELECTRO-MECHANICAL\SWITCH; Project: AM64X_SKEVM; RoHS: RoHS; Temperature: -40°C+85°C; Tolerance: NA; Voltage: NA; Wattage: NA; Weight: 281.7mg; Datasheet: Y:\MIS_DATABASE\DATASHEETS\MISC\SWITCHES\4161311608XX.PDF
TP75-TP77 TP79-TP84 TP86 = TESTPOINT: TESTPOINT CIR 20 SMD; Chkd/date: SHREESHAIL/171006; Crtd /date: MAZHAR/171006; Custom_Duty: NA; Customs_HS_Code: NA; Distributor_name: NA; Distributor_part_number: NA; Footprint Path: Y:\MIS_DATABASE\Library\ALTIUM_TOOL\PCB_FOOTPRINTS\Altium_Footprint_Lib.PcbLib; Height: NA; Library Path: Y:\MIS_DATABASE\Library\ALTIUM_TOOL\SCHEMATICS_PARTS\MS_DISCRETE_Library.schlib; MECHANICAL 3D STEP FILE: NA; Mfr_name: LOCAL; Mistral Part No: NA; Package: SMD; Project: BT MODULE_CSRBC04; RoHS: NA; Temperature: NA; Tolerance: NA; Voltage: NA; Wattage: NA; Weight: NA; Datasheet: NA
U43 = SN74LVC1G08DBVRE4_SOT23-5: IC SINGLE 2-INPUT POSITIVE AND GATE SOT23-5; Chkd/date: SUHAS/221010; Crtd /date: USMAN/151008; Custom_Duty: 15%; Customs_HS_Code: 85423100; Distributor_name: DIGIKEY; Distributor_part_number: SN74LVC1G08DBVRE4-ND; Height: 1.45MM; Mfr_name: TEXAS INSTRUMENTS; Mistral Part No: 141009060026-R; Part_type: ICS\DIGITAL\GATES; Project: KHAN_MAIN; RoHS: Sb/ Br FREE; Temperature: -40°C+85°C; Datasheet: Y:\MIS_DATABASE\DATASHEETS\ICS\DIGITAL\GATES\SN74LVC1G08.PDF
U73 U75 = SN74AVC8T245RHL_QFN24: IC BUS TRANSCEIVER 8-BIT DUAL-SUPPLY QFN24; Chkd/date: VASANTHA/231216; Crtd /date: BAVISH/290411; Custom_Duty: 15%; Customs_HS_Code: 85423100; Distributor_name: DIGIKEY; Distributor_part_number: 296-17859-1-ND; Height: 1.00MM; Mfr_name: TEXAS INSTRUMENTS; Mfr_part_number: SN74AVC8T245RHLR; Mistral Part No: 143011040001-R; Package: QFN24; Part_type: ICS\TELECOM\TRANSCEIVER; Project: OMAPL1_PEC20; RoHS: RoHS; Temperature: -40°C+85°C; Tolerance: NA; Voltage: NA; Wattage: NA; Weight: NA; Datasheet: Y:\MIS_DATABASE\DATASHEETS\ICS\DIGITAL\BUSTRANSCEIVER\SN74AVC8T245.PDF
U74 = TCA6424ARGJR_QFN32: IC I2C I/O EXPANDER 24B UQFN32; Chkd/date: NAVEED/100715; Crtd /date: NAVEED/100914; Custom_Duty: 15%; Customs_HS_Code: 85423100; Distributor_name: DIGIKEY; Distributor_part_number: 296-27844-1-ND; Height: 0.60MM; Mfr_name: TEXAS INSTRUMENTS; Mistral Part No: 141014090009-R; Package: UQFN32; Part_type: ICS\DIGITAL\BUSTRANSCEIVER; Project: ZK_BIOMETRIC; RoHS: RoHS; Temperature: -40°C+85°C; Weight: NA; Datasheet: Y:\MIS_DATABASE\DATASHEETS\ICS\DIGITAL\BUSTRANSCEIVER\TCA6424AR.PDF
C171 C172 = CAP: CAP CERAMIC 12pF 25V 5% C0G(NP0) 0201; Chkd/date: MANIRAJA/020620; Crtd /date: ALVY/300520; Custom_Duty: 15%; Customs_HS_Code: 85322990; Distributor_name: DIGIKEY; Distributor_part_number: 490-3144-1-ND; Footprint Path: Y:\MIS_DATABASE\Library\ALTIUM_TOOL\PCB_FOOTPRINTS\Altium_Footprint_Lib.PcbLib; Height: 0.33MM; Library Path: Y:\MIS_DATABASE\Library\ALTIUM_TOOL\SCHEMATICS_PARTS\MS_DISCRETE_Library.schlib; Mfr_name: MURATA; Mfr_part_number: GRM0335C1E120JA01D; Mistral Part No: 120009030213-R; Package: 0201; Part_type: CAPACITORS\CERAMIC; Project: QCS610_NANOSOM; RoHS: RoHS; Temperature: -55°C+125°C; Tolerance: 5%; Voltage: 25V; Wattage: NA; Weight: 0.33mg; Datasheet: Y:\MIS_DATABASE\DATASHEETS\CAPACITORS\GRM0335C1E120JA01.PDF
C178 C192 C443 C454 = CAP: CAP CERAMIC 1uF 16V 20% X5R 0201; Chkd/date: MANIRAJA/300520; Crtd /date: ALVY/260520; Custom_Duty: 15%; Customs_HS_Code: 85322990; Distributor_name: DIGIKEY; Distributor_part_number: 490-18654-1-ND; Footprint Path: Y:\MIS_DATABASE\Library\ALTIUM_TOOL\PCB_FOOTPRINTS\Altium_Footprint_Lib.PcbLib; Height: 0.39MM; Library Path: Y:\MIS_DATABASE\Library\ALTIUM_TOOL\SCHEMATICS_PARTS\MS_DISCRETE_Library.schlib; Mfr_name: MURATA; Mfr_part_number: GRM033R61C105ME15D; Mistral Part No: 120018090038-R; Package: 0201; Part_type: CAPACITORS\CERAMIC; Project: QCS610_NANOSOM; RoHS: RoHS; Temperature: -55°C+85°C; Tolerance: 20%; Voltage: 16V; Wattage: NA; Weight: 0.33mg; Datasheet: Y:\MIS_DATABASE\DATASHEETS\CAPACITORS\GRM033R61C105ME15.PDF
C179 C455 = CAP: CAP CERAMIC 2.2uF 25V 10% X5R 0402; Chkd/date: ALVY/010721; Crtd /date: MANIRAJA/010721; Custom_Duty: 15%; Customs_HS_Code: 85322990; Distributor_name: DIGIKEY; Distributor_part_number: 490-12703-1-ND; Footprint Path: Y:\MIS_DATABASE\Library\ALTIUM_TOOL\PCB_FOOTPRINTS\Altium_Footprint_Lib.PcbLib; Height: 0.70MM; Library Path: Y:\MIS_DATABASE\Library\ALTIUM_TOOL\SCHEMATICS_PARTS\MS_DISCRETE_Library.schlib; Mfr_name: MURATA; Mfr_part_number: GRM155R61E225KE11D; Mistral Part No: 120015120001-R; Package: 0402; Part_type: CAPACITORS\CERAMIC; Project: TI_AM263X_CC; RoHS: RoHS; Temperature: -55°C+85°C; Tolerance: 10%; Voltage: 25V; Wattage: NA; Weight: 1.5mg; Datasheet: Y:\MIS_DATABASE\DATASHEETS\CAPACITORS\GRM155R61E225KE11.PDF
C180 = CAP: CAP CERAMIC 4.7uF 10V 20% X5R 0402; Chkd/date: MANIRAJA/110718; Crtd /date: ALVY/110718; Custom_Duty: 15%; Customs_HS_Code: 85322990; Distributor_name: DIGIKEY; Distributor_part_number: 490-14306-1-ND; Footprint Path: Y:\MIS_DATABASE\Library\ALTIUM_TOOL\PCB_FOOTPRINTS\Altium_Footprint_Lib.PcbLib; Height: 0.65MM; Library Path: Y:\MIS_DATABASE\Library\ALTIUM_TOOL\SCHEMATICS_PARTS\MS_DISCRETE_Library.schlib; Mfr_name: MURATA; Mfr_part_number: GRM155R61A475MEAAD; Mistral Part No: 120012060002-R; Package: 0402; Part_type: CAPACITORS\CERAMIC; Project: TI_J7SVB_PCIE_ADD-ON-CARD; RoHS: RoHS; Temperature: -55°C+85°C; Tolerance: 20%; Voltage: 10V; Wattage: NA; Weight: 14mg; Datasheet: Y:\MIS_DATABASE\DATASHEETS\CAPACITORS\GRM155R61A475MEAAD.PDF
C185 = CAP: CAP CERAMIC 1000pF 2KV 10% X7R 1206; Chkd/date: SHREESHAIL/291106; Crtd /date: MAZHAR/281106; Custom_Duty: 15%; Customs_HS_Code: 85322990; Distributor_name: DIGIKEY; Distributor_part_number: 478-2956-1-ND; Footprint Path: Y:\MIS_DATABASE\Library\ALTIUM_TOOL\PCB_FOOTPRINTS\Altium_Footprint_Lib.PcbLib; Height: 1.52MM; Library Path: Y:\MIS_DATABASE\Library\ALTIUM_TOOL\SCHEMATICS_PARTS\MS_DISCRETE_Library.schlib; Mfr_name: AVX CORPORATION; Mfr_part_number: 1206GC102KAT1A; Mistral Part No: 120015080006-R; Package: 1206; Part_type: CAPACITORS\CERAMIC; Project: ADR1B; RoHS: RoHS; Temperature: -55°C+125°C; Tolerance: 10%; Voltage: 2KV; Wattage: NA; Weight: 16.2mg; Datasheet: Y:\MIS_DATABASE\DATASHEETS\CAPACITORS\AVX_HV-MLC.PDF
C441 = CAP: CAP CERAMIC 15pF 25V 2% HI-Q C0G(NP0) 0201; Chkd/date: VASANTHA/081216; Crtd /date: MANIRAJA/081216; Custom_Duty: 15%; Customs_HS_Code: 85322990; Distributor_name: DIGIKEY; Distributor_part_number: 490-10562-1-ND; Footprint Path: Y:\MIS_DATABASE\Library\ALTIUM_TOOL\PCB_FOOTPRINTS\Altium_Footprint_Lib.PcbLib; Height: 0.33MM; Library Path: Y:\MIS_DATABASE\Library\ALTIUM_TOOL\SCHEMATICS_PARTS\MS_DISCRETE_Library.schlib; Mfr_name: MURATA; Mfr_part_number: GJM0335C1E150GB01D; Mistral Part No: 120016120011-R; Package: 0201; Part_type: CAPACITORS\CERAMIC; Project: OCTBTS5200; RoHS: RoHS; Temperature: -55°C+125°C; Tolerance: 2%; Voltage: 25V; Wattage: NA; Weight: 0.33mg; Datasheet: Y:\MIS_DATABASE\DATASHEETS\CAPACITORS\MURATA-GXX-SER_NOV17.PDF
D8 = DIODE_SOD323: DIODE 1CH ESD PROTECTION X1SON2; Chkd/date: MANIRAJA/040420; Crtd /date: VASANTHA/181114; Custom_Duty: 15%; Customs_HS_Code: 85423100; Distributor_name: DIGIKEY; Distributor_part_number: 296-30406-1-ND; Footprint Path: Y:\MIS_DATABASE\Library\ALTIUM_TOOL\PCB_FOOTPRINTS\Altium_Footprint_Lib.PcbLib; Height: 0.45MM; Library Path: Y:\MIS_DATABASE\Library\ALTIUM_TOOL\SCHEMATICS_PARTS\MS_DISCRETE_Library.schlib; Mfr_name: TEXAS INSTRUMENTS; Mistral Part No: 130014110022-R; Package: X1SON2; Part_type: DIODE; Project: GALILEO_EVM; RoHS: RoHS; Temperature: -40°C+125°C; Tolerance: NA; Voltage: NA; Wattage: NA; Weight: 1mg; Datasheet: Y:\MIS_DATABASE\DATASHEETS\ICS\INTERFACE\TPD1E10B06-SER.PDF
J16 = CON_USB_MINI-B: CON MICRO USB TYPE B 5POS FEMALE RT SMD; Chkd/date: MANIRAJA/150519; Crtd /date: ALVY/150519; Custom_Duty: 24%; Customs_HS_Code: 85369090; Distributor_name: DIGIKEY; Distributor_part_number: 732-5960-1-ND; Footprint Path: Y:\MIS_DATABASE\Library\ALTIUM_TOOL\PCB_FOOTPRINTS\Altium_Footprint_Lib.PcbLib; Height: 2.66MM; Library Path: Y:\MIS_DATABASE\Library\ALTIUM_TOOL\SCHEMATICS_PARTS\MS_CONNECTOR_Library.schlib; Mfr_name: WURTH ELECTRONICS; Mfr_part_number: 629105150521; Mistral Part No: 150019050015-R; Package: SMD; Part_type: CONNECTOR\USB; Project: NEXTNAV_ALT-STATION_ATE_BRD; RoHS: RoHS; Temperature: -40°C+85°C; Tolerance: NA; Voltage: NA; Wattage: NA; Weight: 360mg; Datasheet: Y:\MIS_DATABASE\DATASHEETS\CONNECTORS\629105150521.PDF
LD14 = DIODE_LED: DIODE LED BRIGHT GREEN SMD; Chkd/date: MANIRAJA/180820; Crtd /date: ALVY/180820; Custom_Duty: 24%; Customs_HS_Code: 85439000; Distributor_name: DIGIKEY; Distributor_part_number: 732-4986-1-ND; Footprint Path: Y:\MIS_DATABASE\Library\ALTIUM_TOOL\PCB_FOOTPRINTS\Altium_Footprint_Lib.PcbLib; Height: 0.80MM; Library Path: Y:\MIS_DATABASE\Library\ALTIUM_TOOL\SCHEMATICS_PARTS\MS_OPTO_Library.schlib; Mfr_name: WURTH ELECTRONICS; Mistral Part No: 130020080012-R; Package: SMD; Part_type: OPTO\LED; Project: AM64x_EVM_BRD; RoHS: RoHS; Temperature: -40°C+85°C; Tolerance: NA; Voltage: NA; Wattage: NA; Weight: 10mg; Datasheet: Y:\MIS_DATABASE\DATASHEETS\DISCRETES\LEDS\150080VS75000.PDF
LD15 = DIODE_LED: DIODE LED RED SMD; Chkd/date: MANIRAJA/100920; Crtd /date: ALVY/100920; Custom_Duty: 24%; Customs_HS_Code: 85439000; Distributor_name: DIGIKEY; Distributor_part_number: 732-13422-1-ND; Footprint Path: Y:\MIS_DATABASE\Library\ALTIUM_TOOL\PCB_FOOTPRINTS\Altium_Footprint_Lib.PcbLib; Height: 0.35MM; Library Path: Y:\MIS_DATABASE\Library\ALTIUM_TOOL\SCHEMATICS_PARTS\MS_OPTO_Library.schlib; Mfr_name: WURTH ELECTRONICS; Mistral Part No: 130020090020-R; Package: SMD; Part_type: OPTO\LED; Project: AM64X_SKEVM; RoHS: RoHS; Temperature: -40°C+85°C; Tolerance: NA; Voltage: NA; Wattage: NA; Weight: 29.3mg; Datasheet: Y:\MIS_DATABASE\DATASHEETS\DISCRETES\LEDS\150040RS73220.PDF
R228 = RESISTOR: RES 49.9E 1/16W 1% 0402; Chkd/date: MANIRAJA/210519; Crtd /date: MANIRAJA/210519; Custom_Duty: 15%; Customs_HS_Code: 85332119; Distributor_name: DIGIKEY; Distributor_part_number: 541-3967-1-ND; Footprint Path: Y:\MIS_DATABASE\Library\ALTIUM_TOOL\PCB_FOOTPRINTS\Altium_Footprint_Lib.PcbLib; Height: 0.35MM; Library Path: Y:\MIS_DATABASE\Library\ALTIUM_TOOL\SCHEMATICS_PARTS\MS_DISCRETE_Library.schlib; Mfr_name: VISHAY; Mfr_part_number: CRCW040249R9FKEDC; Mistral Part No: 110009030846-R; Package: 0402; Part_type: RESISTORS\FIXED; Project: RFSU_RFTJ_CARD; RoHS: RoHS; Temperature: -55°C+155°C; Tolerance: 1%; Voltage: NA; Wattage: 1/16W; Weight: 0.65mg; Datasheet: Y:\MIS_DATABASE\DATASHEETS\RESISTORS\CRCW_C-SER.PDF
R256 = RESISTOR: RES 0E 1/10W 5% 0603; Chkd/date: MANIRAJA/051217; Crtd /date: BAVISH/180211; Custom_Duty: 15%; Customs_HS_Code: 85332119; Distributor_name: DIGIKEY; Distributor_part_number: 311-0.0GRCT-ND; Footprint Path: Y:\MIS_DATABASE\Library\ALTIUM_TOOL\PCB_FOOTPRINTS\Altium_Footprint_Lib.PcbLib; Height: 0.55MM; Library Path: Y:\MIS_DATABASE\Library\ALTIUM_TOOL\SCHEMATICS_PARTS\MS_DISCRETE_Library.schlib; Manufacturer: YAGEO AMERICA; Mfr_name: PANASONIC-ECG; Mfr_part_number: RC0603JR-070RL; Mistral Part No: 110011020013-R; Package: 0603; Part_type: RESISTORS\FIXED; Project: KENNEL; RoHS: RoHS; Temperature: -55°C+155°C; Tolerance: 5%; Voltage: NA; Wattage: 1/10W; Weight: 2mg; Datasheet: Y:\MIS_DATABASE\DATASHEETS\RESISTORS\RCXXXXL-SER_MAR18.PDF
R261 = RESISTOR: RES 4.87K 1/16W 1% 0402; Chkd/date: MAZHAR/150709; Crtd /date: USMAN/150109; Custom_Duty: 15%; Customs_HS_Code: 85332119; Distributor_name: DIGIKEY; Distributor_part_number: P4.87KLCT-ND; Footprint Path: Y:\MIS_DATABASE\Library\ALTIUM_TOOL\PCB_FOOTPRINTS\Altium_Footprint_Lib.PcbLib; Height: 0.40MM; Library Path: Y:\MIS_DATABASE\Library\ALTIUM_TOOL\SCHEMATICS_PARTS\MS_DISCRETE_Library.schlib; Mfr_name: PANASONIC-ECG; Mfr_part_number: ERJ2RKF4871X; Mistral Part No: 110009030803-R; Package: 0402; Part_type: RESISTORS\FIXED; Project: BSN-II; RoHS: RoHS; Temperature: -55°C+155°C; Tolerance: 1%; Voltage: NA; Wattage: 1/16W; Weight: 0.8mg; Datasheet: Y:\MIS_DATABASE\DATASHEETS\RESISTORS\PAN-ERJSERIES.PDF
R264 R265 R270 = RESISTOR: RES 4.7K 1/20W 5% 0201; Chkd/date: MANIRAJA/200921; Crtd /date: ALVY/200921; Custom_Duty: 15%; Customs_HS_Code: 85332119; Distributor_name: DIGIKEY; Distributor_part_number: 311-4.7KNCT-ND; Footprint Path: Y:\MIS_DATABASE\Library\ALTIUM_TOOL\PCB_FOOTPRINTS\Altium_Footprint_Lib.PcbLib; Height: 0.26MM; Library Path: Y:\MIS_DATABASE\Library\ALTIUM_TOOL\SCHEMATICS_PARTS\MS_DISCRETE_Library.schlib; Mfr_name: YAGEO AMERICA; Mfr_part_number: RC0201JR-074K7L; Mistral Part No: 110021090007-R; Package: 0201; Part_type: RESISTORS\FIXED; Project: TI_AM62x SKEVM_BRD; RoHS: RoHS; Temperature: -55°C+125°C; Tolerance: 5%; Voltage: NA; Wattage: 1/20W; Weight: 0.17mg; Datasheet: Y:\MIS_DATABASE\DATASHEETS\RESISTORS\RCXXXXL-SER_MAR18.PDF
R267 R271 = RESISTOR: RES 220E 1/10W 5% 0402; Chkd/date: VASANTHA/291216; Crtd /date: GEETHA/260406; Custom_Duty: 15%; Customs_HS_Code: 85332119; Distributor_name: DIGIKEY; Distributor_part_number: P220JCT-ND; Footprint Path: Y:\MIS_DATABASE\Library\ALTIUM_TOOL\PCB_FOOTPRINTS\Altium_Footprint_Lib.PcbLib; Height: 0.40MM; Library Path: Y:\MIS_DATABASE\Library\ALTIUM_TOOL\SCHEMATICS_PARTS\MS_DISCRETE_Library.schlib; Mfr_name: PANASONIC-ECG; Mfr_part_number: ERJ-2GEJ221X; Mistral Part No: 110009030506-R; Package: 0402; Part_type: RESISTORS\FIXED; Project: RED EYE; RoHS: RoHS; Temperature: -55°C+155°C; Tolerance: 5%; Voltage: NA; Wattage: 1/10W; Weight: 0.8mg; Datasheet: Y:\MIS_DATABASE\DATASHEETS\RESISTORS\PAN-ERJSER_NOV17.PDF
R268 R519 = RESISTOR: RES 30K 1/16W 5% 0402; Chkd/date: MANIRAJA/230817; Crtd /date: MANIRAJA/230817; Custom_Duty: 15%; Customs_HS_Code: 85332119; Distributor_name: DIGIKEY; Distributor_part_number: 541-30KJCT-ND; Footprint Path: Y:\MIS_DATABASE\Library\ALTIUM_TOOL\PCB_FOOTPRINTS\Altium_Footprint_Lib.PcbLib; Height: 0.40MM; Library Path: Y:\MIS_DATABASE\Library\ALTIUM_TOOL\SCHEMATICS_PARTS\MS_DISCRETE_Library.schlib; Mfr_name: VISHAY; Mfr_part_number: CRCW040230K0JNED; Mistral Part No: 110017080023-R; Package: 0402; Part_type: RESISTORS\FIXED; Project: TI_MAXIE_CPB; RoHS: RoHS; Temperature: -55°C+155°C; Tolerance: 5%; Voltage: NA; Wattage: 1/16W; Weight: 0.65mg; Datasheet: Y:\MIS_DATABASE\DATASHEETS\RESISTORS\CRCW0603.PDF
R269 = RESISTOR: RES 20K 1/16W 1% 0402; Chkd/date: MANIRAJA/021120; Crtd /date: MANIRAJA/021120; Custom_Duty: 15%; Customs_HS_Code: 85332119; Distributor_name: DIGIKEY; Distributor_part_number: 541-20.0KLCT-ND; Footprint Path: Y:\MIS_DATABASE\Library\ALTIUM_TOOL\PCB_FOOTPRINTS\Altium_Footprint_Lib.PcbLib; Height: 0.40MM; Library Path: Y:\MIS_DATABASE\Library\ALTIUM_TOOL\SCHEMATICS_PARTS\MS_DISCRETE_Library.schlib; Mfr_name: VISHAY; Mfr_part_number: CRCW040220K0FKED; Mistral Part No: 110009030486-R; Package: 0402; Part_type: RESISTORS\FIXED; Project: VAGG_SBC_BRD; RoHS: RoHS; Temperature: -55°C+155°C; Tolerance: 1%; Voltage: NA; Wattage: 1/16W; Weight: 0.65mg; Datasheet: Y:\MIS_DATABASE\DATASHEETS\RESISTORS\CRCW0603.PDF
R520 = RESISTOR: RES 51K 1/16W 5% 0402; Chkd/date: MANIRAJA/230817; Crtd /date: MANIRAJA/230817; Custom_Duty: 15%; Customs_HS_Code: 85332119; Distributor_name: DIGIKEY; Distributor_part_number: 541-51KJCT-ND; Footprint Path: Y:\MIS_DATABASE\Library\ALTIUM_TOOL\PCB_FOOTPRINTS\Altium_Footprint_Lib.PcbLib; Height: 0.40MM; Library Path: Y:\MIS_DATABASE\Library\ALTIUM_TOOL\SCHEMATICS_PARTS\MS_DISCRETE_Library.schlib; Mfr_name: VISHAY; Mfr_part_number: CRCW040251K0JNED; Mistral Part No: 110009030966-R; Package: 0402; Part_type: RESISTORS\FIXED; Project: TI_MAXIE_CPB; RoHS: RoHS; Temperature: -55°C+155°C; Tolerance: 5%; Voltage: NA; Wattage: 1/16W; Weight: 0.65mg; Datasheet: Y:\MIS_DATABASE\DATASHEETS\RESISTORS\CRCW0603.PDF
R530 = RESISTOR: RES 100E 1/16W 1% 0402; Chkd/date: MANIRAJA/060318; Crtd /date: NAVEED/220714; Custom_Duty: 15%; Customs_HS_Code: 85332119; Distributor_name: DIGIKEY; Distributor_part_number: 311-100LRCT-ND; Footprint Path: Y:\MIS_DATABASE\Library\ALTIUM_TOOL\PCB_FOOTPRINTS\Altium_Footprint_Lib.PcbLib; Height: 0.40MM; Library Path: Y:\MIS_DATABASE\Library\ALTIUM_TOOL\SCHEMATICS_PARTS\MS_DISCRETE_Library.schlib; Mfr_name: YAGEO AMERICA; Mfr_part_number: RC0402FR-07100RL; Mistral Part No: 110014070015-R; Package: 0402; Part_type: RESISTORS\FIXED; Project: DLRU; RoHS: RoHS; Temperature: -55°C+155°C; Tolerance: 1%; Voltage: NA; Wattage: 1/16W; Weight: 0.65mg; Datasheet: Y:\MIS_DATABASE\DATASHEETS\RESISTORS\RCXXXXL-SER_MAR18.PDF
U45 = TM4C1294NCPDTT3R_TQFP128: IC 32-BIT MICROCONTROLLER WITH 1MB FLASH TQFP128; Chkd/date: MANIRAJA/220817; Crtd /date: MANIRAJA/220817; Custom_Duty: 15%; Customs_HS_Code: 85423100; Distributor_name: DIGIKEY; Distributor_part_number: TM4C1294NCPDTT3R-ND; Height: 1.20MM; Mfr_name: TEXAS INSTRUMENTS; Mistral Part No: 141217080002-R; Package: TQF9128; Part_type: ICS\DIGITAL\MICROCONTROLLER; Project: TI_MAXIE_CPB; RoHS: RoHS; Temperature: -40°C+105°C; Tolerance: NA; Voltage: NA; Wattage: NA; Weight: 503.5mg; Datasheet: Y:\MIS_DATABASE\DATASHEETS\ICS\DIGITAL\MICROCONTROLLER\TM4C1294NCPD.PDF
U47 = LM4040B25IDCKR_SC70-5: IC PRECISION MICROPOWER SHUNT VOLTAGE REFERENCE SC70-5; Chkd/date: MANIRAJA/230817; Crtd /date: MANIRAJA/230817; Custom_Duty: 15%; Customs_HS_Code: 85423100; Distributor_name: DIGIKEY; Distributor_part_number: 296-20873-1-ND; Height: 1.10MM; Mfr_name: TEXAS INSTRUMENTS; Mistral Part No: 142017080015-R; Package: SC70-5; Part_type: ICS\POWER\VOLTAGE REGULATOR; Project: TI_MAXIE_CPB; RoHS: RoHS; Temperature: -40°C+85°C; Tolerance: NA; Voltage: NA; Wattage: NA; Weight: 30mg; Datasheet: Y:\MIS_DATABASE\DATASHEETS\ICS\POWER\LM4040B25I.PDF
U79 = TPS79601DRBR_SON8: IC 1A HIGH PSRR RF ADJ LDO LINEAR REGULATOR SON8; Chkd/date: MANIRAJA/030518; Crtd /date: MAZHAR/280809; Custom_Duty: 15%; Customs_HS_Code: 85423100; Distributor_name: DIGIKEY; Distributor_part_number: 296-23107-1-ND; Footprint Path: Y:\MIS_DATABASE\Library\ALTIUM_TOOL\PCB_FOOTPRINTS\Altium_Footprint_Lib.PcbLib; Height: 1.00MM; Library Path: Y:\MIS_DATABASE\Library\ALTIUM_TOOL\SCHEMATICS_PARTS\MS_MISCPOWER_Library.schlib; Mfr_name: TEXAS INSTRUMENTS; Mistral Part No: 142009080012-R; Package: SON8; Part_type: ICS\POWER\VOLTAGE REGULATOR; Project: DIO_TXRX; RoHS: RoHS; Temperature: -40°C+125°C; Tolerance: NA; Voltage: NA; Wattage: NA; Weight: 24mg; Datasheet: Y:\MIS_DATABASE\DATASHEETS\MISC\REGULATORS\TPS796XX.PDF
U89 = TPD4E004_SON6: IC 4-CH ESD PROTECTION ARRAY FOR HIGH SPEED DATA INTERFACE SON6; Chkd/date: MANIRAJA/100320; Crtd /date: MUDDU/010310; Custom_Duty: 15%; Customs_HS_Code: 85423100; Distributor_name: DIGIKEY; Distributor_part_number: 296-23618-1-ND; Footprint Path: Y:\MIS_DATABASE\Library\ALTIUM_TOOL\PCB_FOOTPRINTS\Altium_Footprint_Lib.PcbLib; Height: 0.60MM; Library Path: Y:\MIS_DATABASE\Library\ALTIUM_TOOL\SCHEMATICS_PARTS\MS_MISCINTERFACE_Library.schlib; Mfr_name: TEXAS INSTRUMENTS; Mistral Part No: 141010020012-R; Package: SON6; Part_type: ICS\INTERFACE; Project: BUG_BASE-II; RoHS: RoHS; Temperature: -40°C+85°C; Tolerance: NA; Voltage: NA; Wattage: NA; Weight: 3.2mg; Datasheet: Y:\MIS_DATABASE\DATASHEETS\ICS\INTERFACE\TPD4E004-SER.PDF
Y2 = CRY4_13: CRY 16.000MHz 8pF SMD; Chkd/date: MANIRAJA/151020; Crtd /date: ALVY/151020; Custom_Duty: 24%; Customs_HS_Code: 85439000; Distributor_name: DIGIKEY; Distributor_part_number: 490-18283-1-ND; Footprint Path: Y:\MIS_DATABASE\Library\ALTIUM_TOOL\PCB_FOOTPRINTS\Altium_Footprint_Lib.PcbLib; Height: 0.70MM; Library Path: Y:\MIS_DATABASE\Library\ALTIUM_TOOL\SCHEMATICS_PARTS\MS_DISCRETE_Library.schlib; Mfr_name: MURATA; Mfr_part_number: XRCGB16M000FXN01R0; Mistral Part No: 130020100044-R; Package: SMD; Part_type: CRYSTAL; Project: AM64X_SKEVM; RoHS: RoHS; Temperature: -30°C+85°C; Tolerance: NA; Voltage: NA; Wattage: NA; Weight: 195.4mg; Datasheet: Y:\MIS_DATABASE\DATASHEETS\MISC\CRY_OSC\XRCGB16M000FXN01R0.PDF

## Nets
DGND: C167.2 C169.1 C170.1 C171.1 C172.1 C173.1 C176.2 C178.2 C179.2 C180.2 C181.2 C185.1 C186.2 C189.2 C190.1 C191.2 C192.2 C430.1 C431.2 C439.1 C440.2 C442.1 C443.2 C449.1 C454.2 C455.2 C468.1 D8.1 J16.5(GND) LD14.1(CATHODE) LD15.1(CATHODE) R202.2 R203.2 R204.2 R205.2 R206.2 R207.2 R208.2 R209.2 R210.2 R211.2 R212.2 R213.2 R214.2 R215.2 R216.2 R217.2 R252.1 R255.1 R256.1 R258.1 R259.1 R260.1 R261.2 R269.2 R519.2 R521.2 R527.1 R546.2 U43.3(GND) U45.10(GNDA) U45.17(GND) U45.48(GND) U45.55(GND) U45.58(GND) U45.64(~{WAKE}) U45.66(XOSC0) U45.80(GND) U45.114(GND) U47.1(ANODE) U73.11(GND1) U73.12(GND2) U73.13(GND3) U73.25(EP) U74.25(GND) U74.33(EP) U75.11(GND1) U75.12(GND2) U75.13(GND3) U75.25(EP) U79.6(GND) U79.9(PAD) U89.3(GND) Y2.2 Y2.4 ; also on sheet 1 10 11 12 13 14 15 16 17 18 19 20 21 22 23 24 25 26 29 30 31 32 33 34 35 36 37 38 39 40 41 42 43
VCC3V3_TA: C167.1 C430.2 C439.2 C442.2 R236.2 R237.2 R238.2 R239.2 R240.2 R241.2 R242.2 R243.2 R244.2 R245.2 R246.2 R247.2 R248.2 R249.2 R250.2 R251.2 R514.2 R517.2 R522.2 U43.5(VCC) U73.1(VCCA) U74.27(VCCP) U74.31(VCC) U75.1(VCCA) ; also on sheet 1 26
VCC3V3_XDS: C173.2 C176.1 C181.1 C189.1 C191.1 C192.1 C441.1 C443.1 C454.1 C468.2 R228.2 R264.1 R265.1 R270.1 R520.1 R539.2 R552.2 R556.2 R560.2 R563.2 TP77.1(TP) U45.7(VDD) U45.8(VDDA) U45.16(VDD) U45.26(VDD) U45.28(VDD) U45.39(VDD) U45.47(VDD) U45.51(VDD) U45.52(VDD) U45.69(VDD) U45.79(VDD) U45.90(VDD) U45.101(VDD) U45.113(VDD) U45.122(VDD) U79.3(OUT1) U79.4(OUT2) ; also on sheet 1 29
VCC_3V3_SYS: C431.1 C440.1 U73.23(VCCB1) U73.24(VCCB2) U75.23(VCCB1) U75.24(VCCB2) ; also on sheet 10 12 13 14 18 19 20 22 23 24 25 26 29 30 31 32 33 34 35 36 37 38 39 40 41 42 43
VDDC_1V2: C178.1 C179.1 C449.2 U45.87(VDDC) U45.115(VDDC)
BOOTMODE0: U75.14(B8) ; also on sheet 32
BOOTMODE1: U75.15(B7) ; also on sheet 32
BOOTMODE2: U75.16(B6) ; also on sheet 32
BOOTMODE3: U75.17(B5) ; also on sheet 32
BOOTMODE4: U75.18(B4) ; also on sheet 32
BOOTMODE5: U75.19(B3) ; also on sheet 32
BOOTMODE6: U75.20(B2) ; also on sheet 32
BOOTMODE7: U75.21(B1) ; also on sheet 32
BOOTMODE8: U73.14(B8) ; also on sheet 32
BOOTMODE9: U73.15(B7) ; also on sheet 32
BOOTMODE10: U73.16(B6) ; also on sheet 32
BOOTMODE11: U73.17(B5) ; also on sheet 32
BOOTMODE12: U73.18(B4) ; also on sheet 32
BOOTMODE13: U73.19(B3) ; also on sheet 32
BOOTMODE14: U73.20(B2) ; also on sheet 32
BOOTMODE15: U73.21(B1) ; also on sheet 32
BOOTMODE_I2C_SCL: TP83.1(TP) U74.29(SCL) ; also on sheet 1 26
BOOTMODE_I2C_SDA: TP84.1(TP) U74.30(SDA) ; also on sheet 1 26
BOOTMODE_XDS_I2C_SCL: U45.49(PG0) ; also on sheet 1
BOOTMODE_XDS_I2C_SDA: U45.50(PG1) ; also on sheet 1
BOOTMODEON: R252.2 U43.4(Y) U73.22(~{OE}) U75.22(~{OE})
DIR: R514.1 U73.2(DIR) U75.2(DIR)
IO_EXP_ADDR: R521.1 U74.26(ADDR)
OSC0: C172.2 U45.88(OSC0) Y2.3
OSC1: C171.2 U45.89(OSC1) Y2.1
PORz_OUT: R221.2 ; also on sheet 20 23 24 42
RESETSTATz: R222.2 ; also on sheet 13 19 20 21 23 24 32 33 37 39 40 41 42
SoC_I2C1_XDS_SCL: U45.82(PL1) ; also on sheet 1
SoC_I2C1_XDS_SDA: U45.81(PL0) ; also on sheet 1
SYS_BOOTMODE0: R202.1 SW1.1 U74.1(P00) U75.10(A8)
SYS_BOOTMODE1: R203.1 SW1.2 U74.2(P01) U75.9(A7)
SYS_BOOTMODE2: R204.1 SW1.3 U74.3(P02) U75.8(A6)
SYS_BOOTMODE3: R205.1 SW1.4 U74.4(P03) U75.7(A5)
SYS_BOOTMODE4: R206.1 SW1.5 U74.5(P04) U75.6(A4)
SYS_BOOTMODE5: R207.1 SW1.6 U74.6(P05) U75.5(A3)
SYS_BOOTMODE6: R208.1 SW1.7 U74.7(P06) U75.4(A2)
SYS_BOOTMODE7: R209.1 SW1.8 U74.8(P07) U75.3(A1)
SYS_BOOTMODE8: R210.1 SW2.1 U73.10(A8) U74.9(P10)
SYS_BOOTMODE9: R211.1 SW2.2 U73.9(A7) U74.10(P11)
SYS_BOOTMODE10: R212.1 SW2.3 U73.8(A6) U74.11(P12)
SYS_BOOTMODE11: R213.1 SW2.4 U73.7(A5) U74.12(P13)
SYS_BOOTMODE12: R214.1 SW2.5 U73.6(A4) U74.13(P14)
SYS_BOOTMODE13: R215.1 SW2.6 U73.5(A3) U74.14(P15)
SYS_BOOTMODE14: R216.1 SW2.7 U73.4(A2) U74.15(P16)
SYS_BOOTMODE15: R217.1 SW2.8 U73.3(A1) U74.16(P17)
SYSBOOT_BUF_ENz: R221.1 R222.1 U43.1(A)
TCA6424_EXP_INT: R522.1 U74.32(~{INT})
TEST_GPIO1_XDS: U45.74(PM4) ; also on sheet 1
TEST_GPIO2_XDS: U45.73(PM5) ; also on sheet 1
TEST_GPIO3: J14.1 R517.1 U43.2(B) ; also on sheet 1 26
TEST_GPIO3_XDS: U45.72(PM6) ; also on sheet 1
TEST_GPIO4: U74.28(~{RESET}) ; also on sheet 1 26
TEST_GPIO4_XDS: U45.71(PM7) ; also on sheet 1
TEST_PORZn_XDS: U45.77(PM1) ; also on sheet 1
TEST_POWERDOWN_XDS: U45.78(PM0) ; also on sheet 1
TEST_WARMRESETn_XDS: U45.76(PM2) ; also on sheet 1
TM4C129_TCK: TP82.1(TP) U45.100(PC0/TCK/SWCLK)
TM4C129_TDI: TP80.1(TP) U45.98(PC2/TDI)
TM4C129_TDO: TP79.1(TP) U45.97(PC3/TDO/SWO)
TM4C129_TMS: TP81.1(TP) U45.99(PC1/TMS/SWDIO)
XDS110_EMU0: R265.2 U45.42(PF0) ; also on sheet 29
XDS110_EMU1: R264.2 U45.43(PF1) ; also on sheet 29
XDS110_TCK: U45.35(PA2/SSI0CLK) ; also on sheet 29
XDS110_TDI: U45.38(PA5/SSI0XDAT1) ; also on sheet 29
XDS110_TDO: U45.37(PA4/SSI0XDAT0) ; also on sheet 29
XDS110_TMS: U45.36(PA3/SSI0FSS) ; also on sheet 29
XDS110_TRST#: U45.40(PA6) ; also on sheet 29
XDS_RSTn: R539.1 R546.1 TP75.1(TP) U45.70(~{RST})
XDS_SHIELD: C185.2 J16.6(SH1) J16.7(SH2) J16.8(SH3) J16.9(SH4) R256.2
XDS_USB_DM: J16.2(D-) U45.93(PL7/USB0DM) U89.5(IO4)
XDS_USB_DP: J16.3(D+) U45.94(PL6/USB0DP) U89.4(IO3)
XDS_USB_ID: J16.4(ID) R235.2 U89.2(IO2)
XDS_USB_VBUS: C180.1 C455.1 D8.2 J16.1(VBUS) R268.1 R530.1 R540.1 TP86.1(TP) U79.1(IN1) U79.2(IN2) U89.6(VCC)
XDS_VREF: C186.1 C190.2 R270.2 U45.9(VREFA+) U47.3(CATHODE)
N16997746: R261.1 U45.59(RBAIS)
N17078351: R239.1 SW1.13
N17078353: R238.1 SW1.14
N17078355: R237.1 SW1.15
N17078357: R236.1 SW1.16
N17078758: R249.1 SW2.11
N17078760: R248.1 SW2.12
N17078762: R247.1 SW2.13
N17078764: R246.1 SW2.14
N17078766: R251.1 SW2.9
N17078768: R250.1 SW2.10
N17078770: R245.1 SW2.15
N17078778: R244.1 SW2.16
N17078974: J14.2 R527.2
N17084256: R243.1 SW1.9
N17084257: R242.1 SW1.10
N17084258: R241.1 SW1.11
N17084259: R240.1 SW1.12
N17479799: R540.2 U79.8(EN)
N17479805: C441.2 R519.1 R520.2 U79.5(NR/FB)
N17479881: C169.2 R228.1 U45.68(VBAT)
N17481587: LD14.2(ANODE) R267.2
N17481598: C170.2 R530.2 U45.96(PB1/USB0VBUS)
N17481613: R235.1 U45.95(PB0/USB0ID)
N17481619: R268.2 R269.1 U45.1(PD0/AIN15)
N17481621: R260.2 R563.1 U45.60(PK7)
N17481627: R271.1 U45.3(PD2/AIN13)
N17481631: LD15.2(ANODE) R271.2
N17481633: R255.2 R552.1 U45.63(PK4)
N17481635: R259.2 R560.1 U45.61(PK6)
N17481637: R267.1 U45.4(PD3/AIN12)
N17481641: R258.2 R556.1 U45.62(PK5)
N18374561: TP76.1(TP) U45.75(PM3)

Not connected (* = marked no-connect by the designer): U45 2(PD1/AIN14)* 5(PQ0)* 6(PQ1)* 11(PQ2)* 12(PE3/AIN0)* 13(PE2/AIN1)* 14(PE1/AIN2)* 15(PE0/AIN3)* 18(PK0/AIN16)* 19(PK1/AIN17)* 20(PK2/AIN18)* 21(PK3/AIN19)* 22(PC7/C0-)* 23(PC6/C0+)* 24(PC5/C1+)* 25(PC4/C1-)* 27(PQ3)* 29(PH0)* 30(PH1)* 31(PH2)* 32(PH3)* 33(PA0/U0RX)* 34(PA1/U0TX)* 41(PA7)* 44(PF2)* 45(PF3)* 46(PF4)* 53(EN0RXIN)* 54(EN0RXIP)* 56(EN0RX0N)* 57(EN0RX0P)* 65(~{HIB})* 67(XOSC1)* 83(PL2)* 84(PL3)* 85(PL4)* 86(PL5)* 91(PB2/I2C0SCL)* 92(PB3/I2C0SDA)* 102(PQ4)* 103(PP2)* 104(PP3)* 105(PP4)* 106(PP5)* 107(PN0)* 108(PN1)* 109(PN2)* 110(PN3)* 111(PN4)* 112(PN5)* 116(PJ0)* 117(PJ1)* 118(PP0/C2+)* 119(PP1/C2-)* 120(PB5/AIN11)* 121(PB4/AIN10)* 123(PE4/AIN9)* 124(PE5/AIN8)* 125(PD4/AIN7)* 126(PD5/AIN6)* 127(PD6/AIN5)* 128(PD7/AIN4)*; U47 2(NC1)* 4(NC2)* 5(NC3)*; U74 17(P20)* 18(P21)* 19(P22)* 20(P23)* 21(P24)* 22(P25)* 23(P26)* 24(P27)*; U79 7(NC)*; U89 1(IO1)*

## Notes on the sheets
sheet 27
- BOOT MODE BUFFERS
- BOOTMODE IO EXPANDER
- DIR = H: A -> B
  DIR = L: B -> A
  OE = H: output = Hi-Z
- DIR = H: A -> B
  DIR = L: B -> A
  OE = H: output = Hi-Z
- I2C ADDRESS: 0x22
- BOOT MODE SWITCHES
- SWITCH ON  =  LOGIC 1
  SWITCH OFF =  LOGIC 0
- BOOT MODES SUPPORTED
- 1. OSPI
- Silk: BMODE 0-7
- Silk: BMODE 8-15
- 2. MMC1 - SD CARD
- 3. UART
- 4. eMMC
- 5. BACKUP BOOT OPTION
sheet 28
- XDS110 DEBUGGER
- Silk: JTAG
- 90E
- GREEN
- RED
- Sets the unique ID of the Debugger
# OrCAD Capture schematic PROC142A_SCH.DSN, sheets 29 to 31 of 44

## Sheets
29 29. JTAG BUFFER: size C; title: JTAG BUFFER
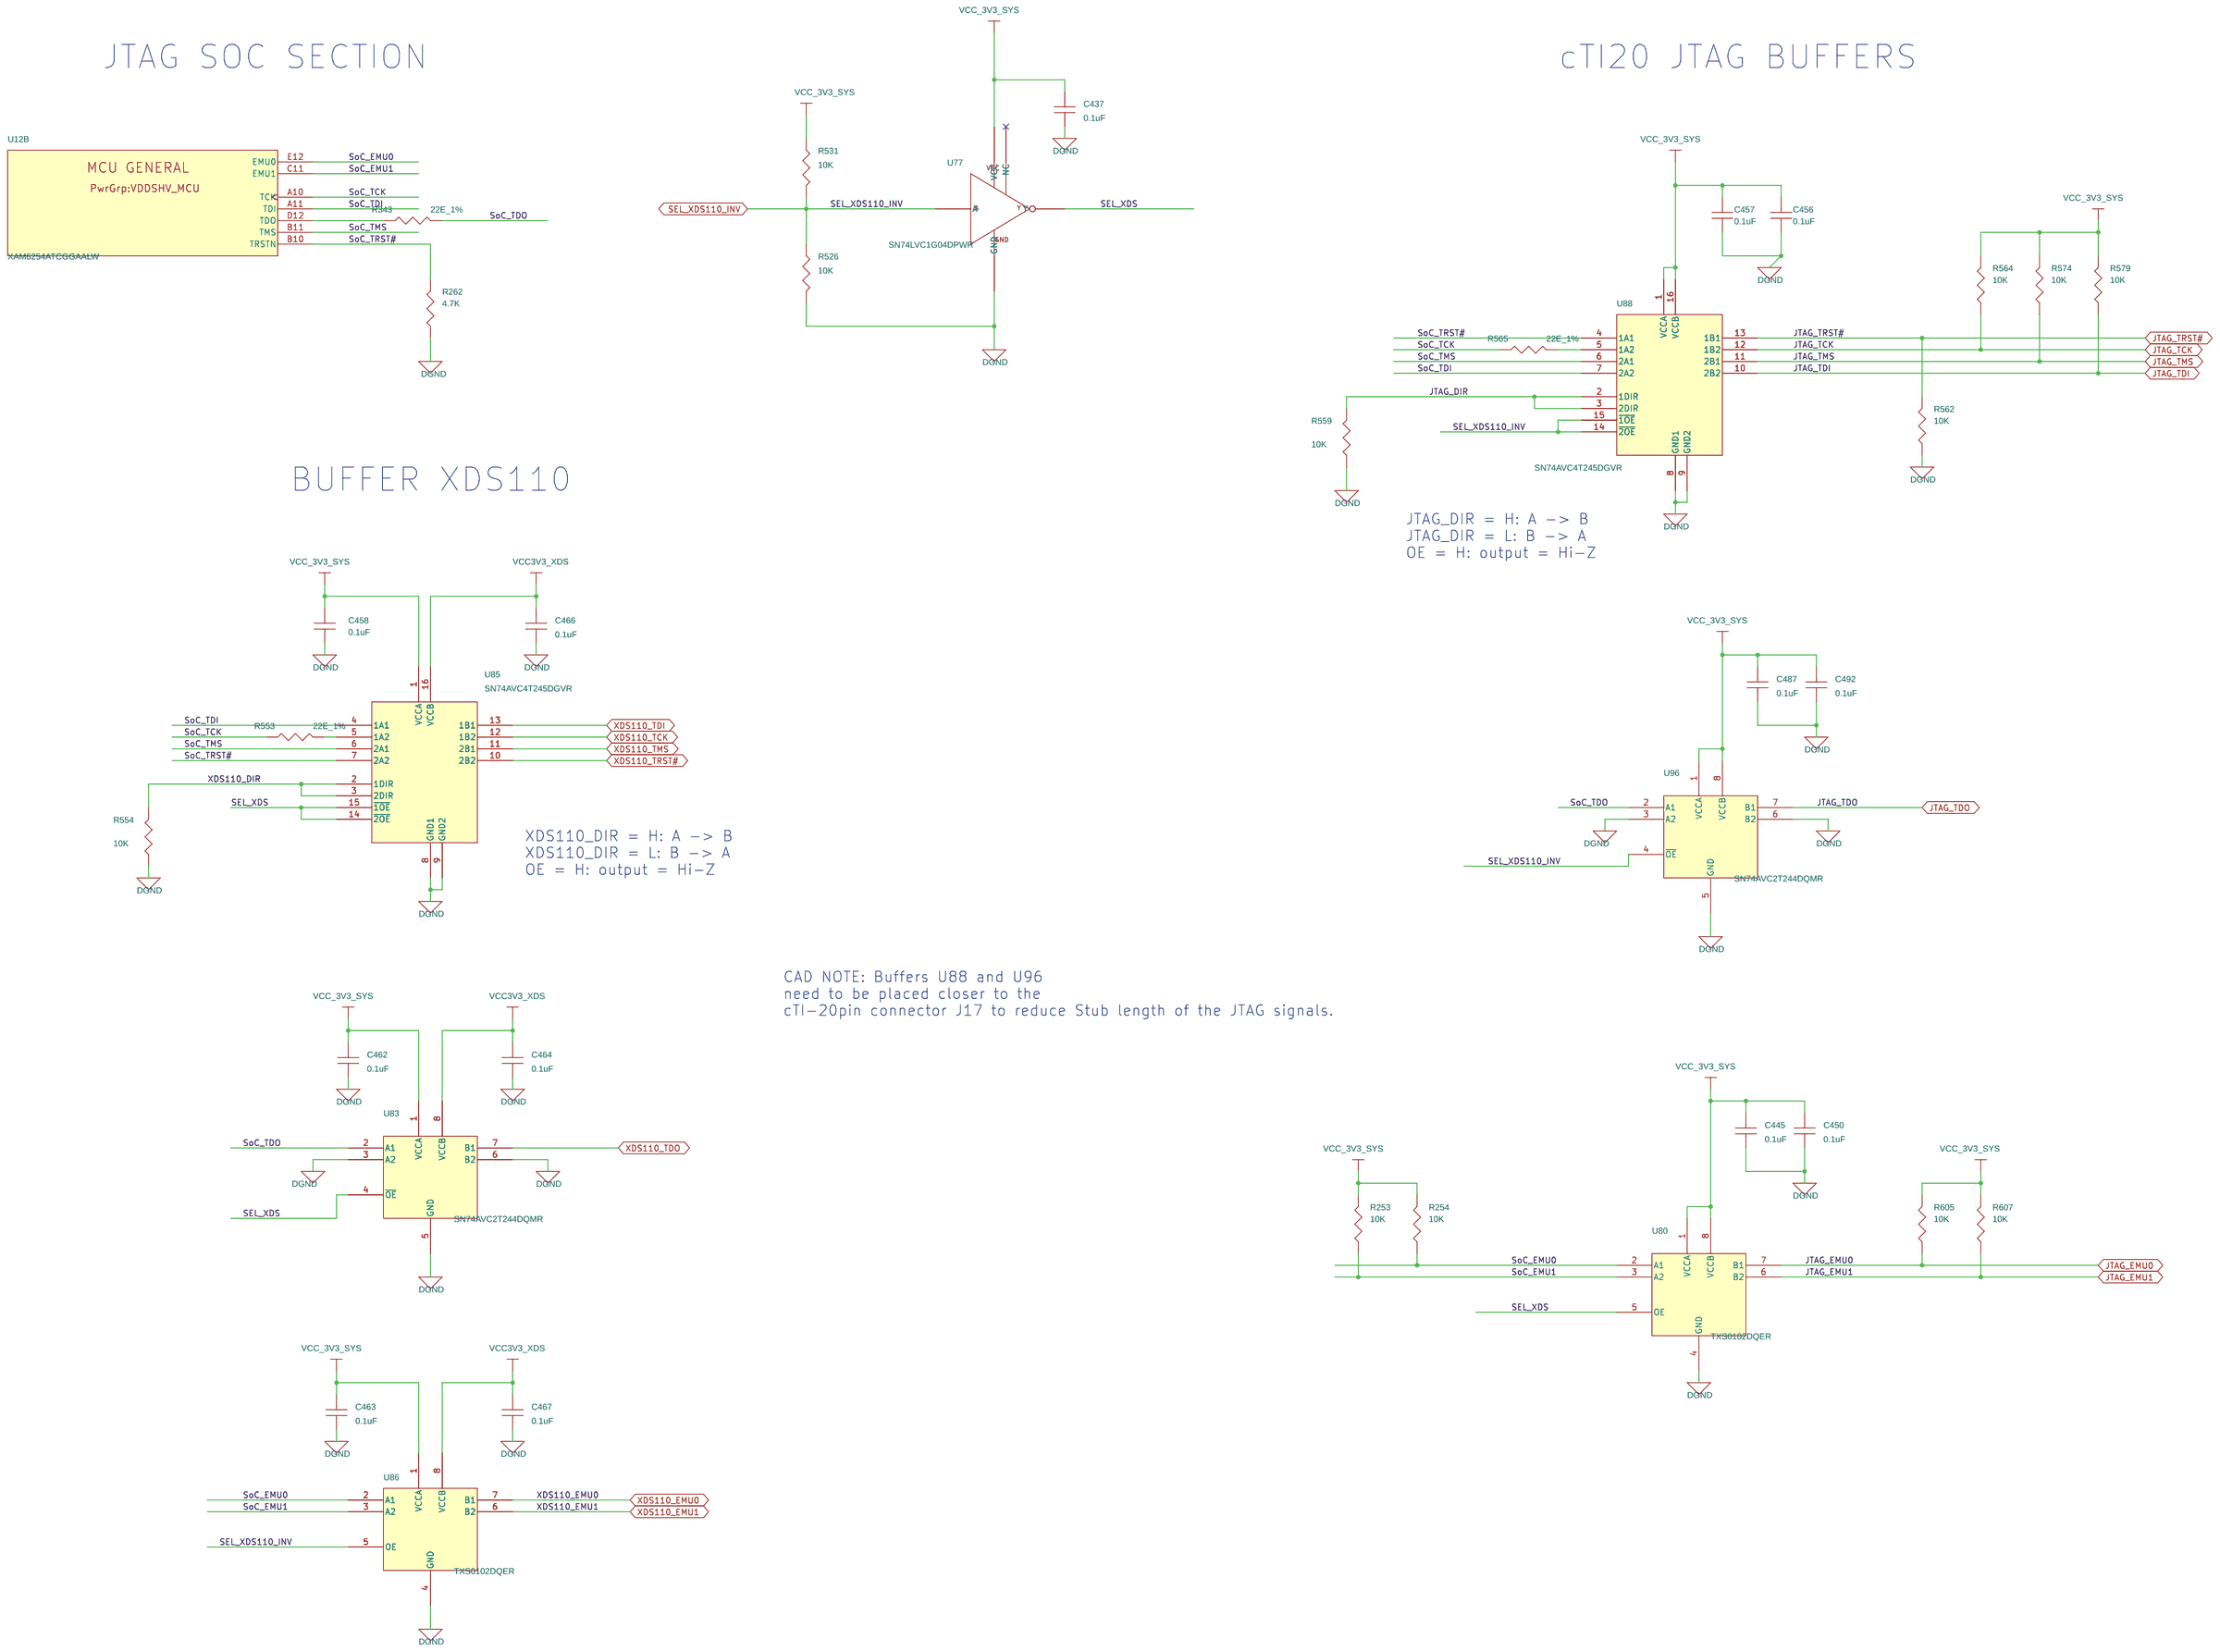
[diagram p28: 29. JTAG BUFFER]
30 30. JTAG 20 PIN cTI CONNECTOR: size C; title: JTAG 20 PIN cTI CONNECTOR
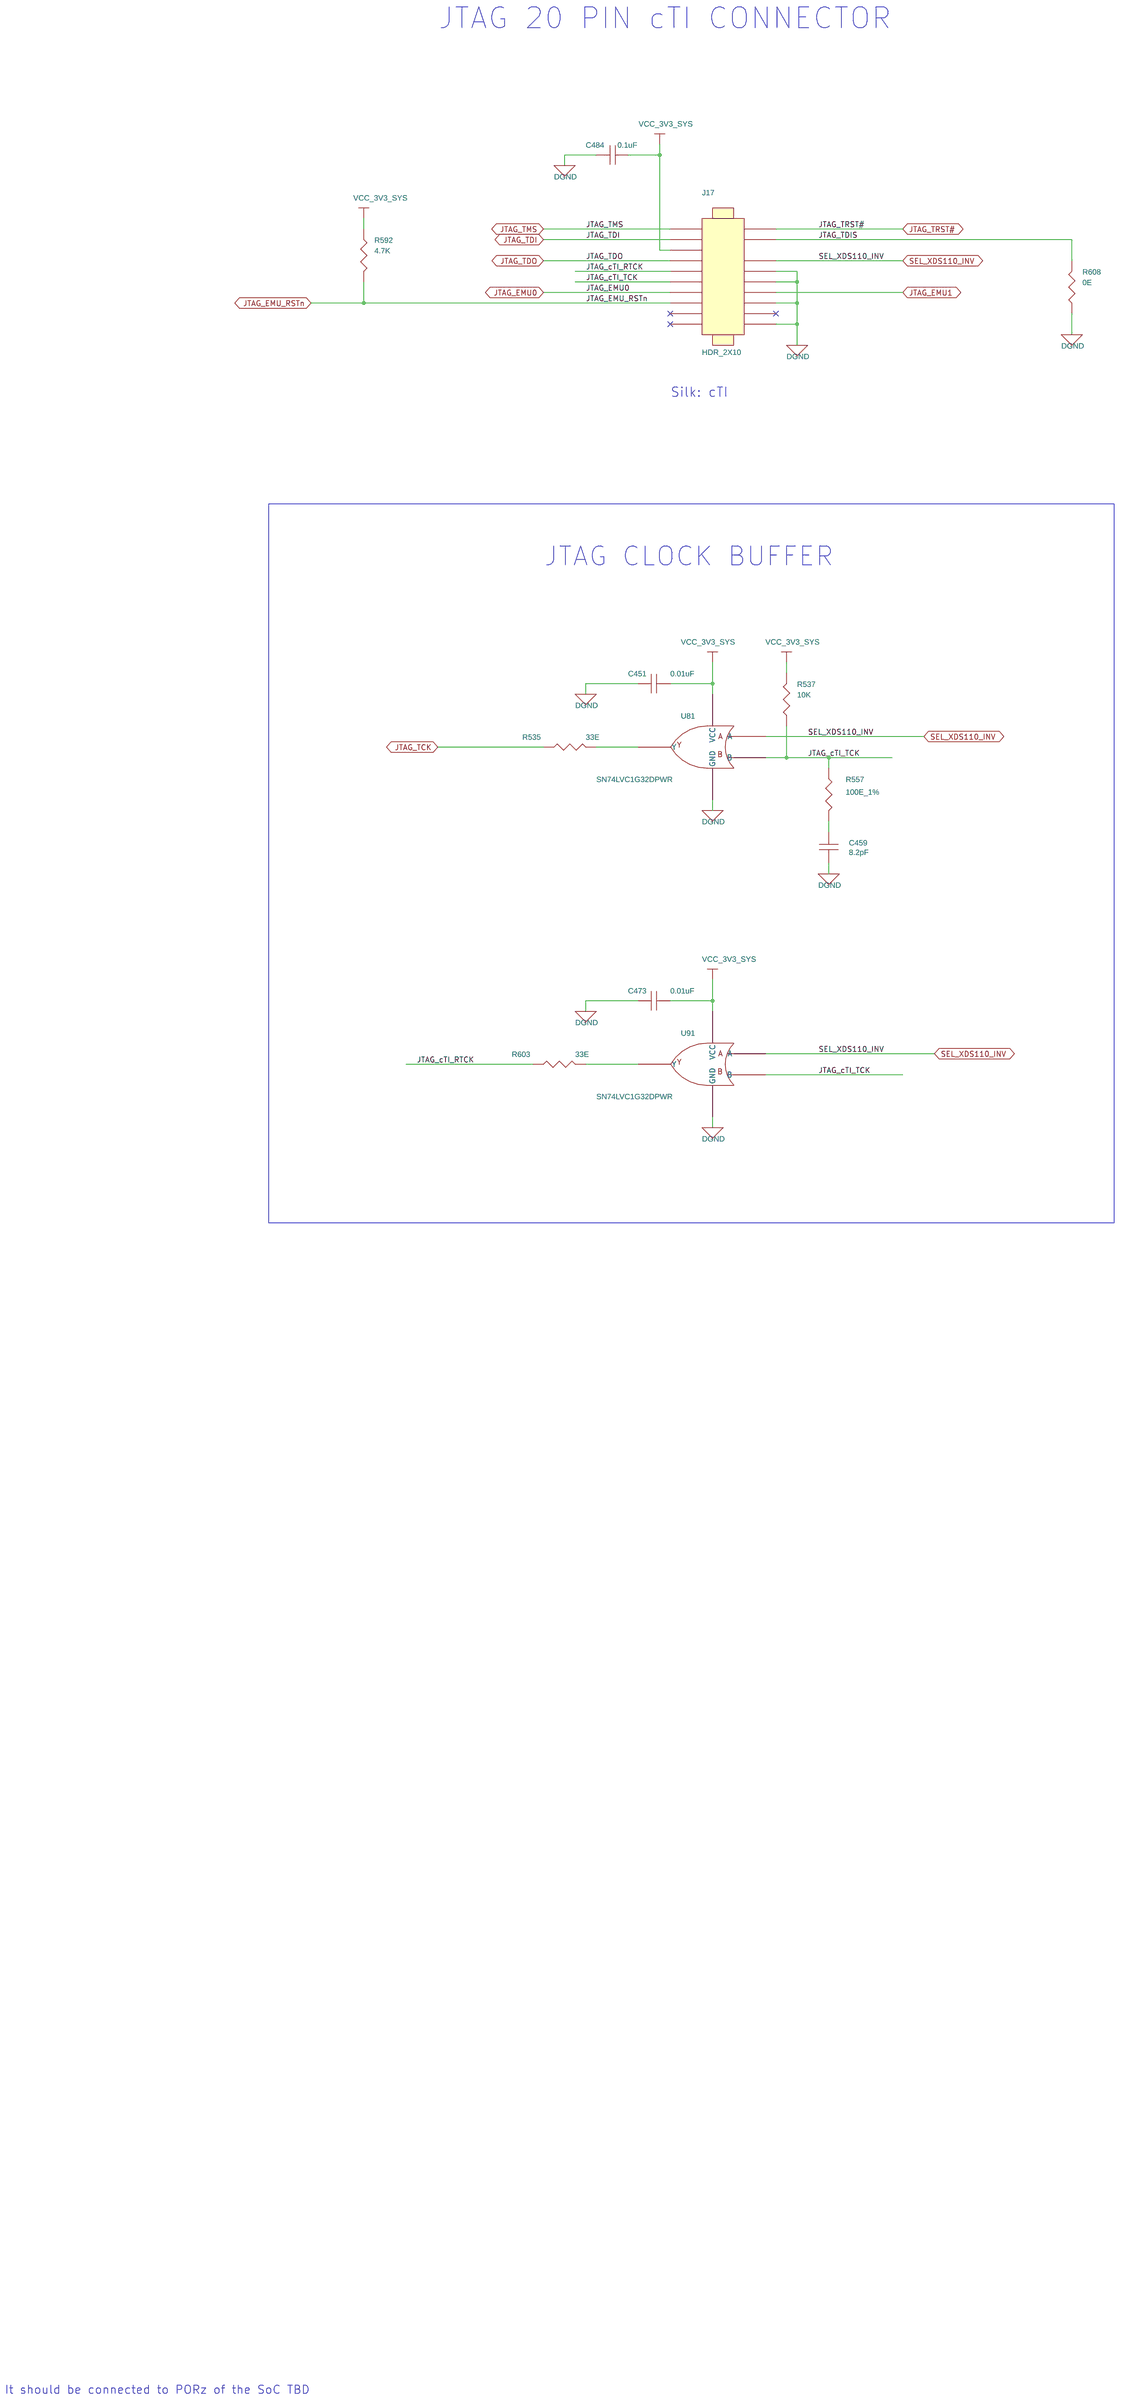
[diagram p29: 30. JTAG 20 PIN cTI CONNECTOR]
31 31. FT4232 UART TO USB BRIDGE: size C; title: FT4232 UART TO USB BRIDGE

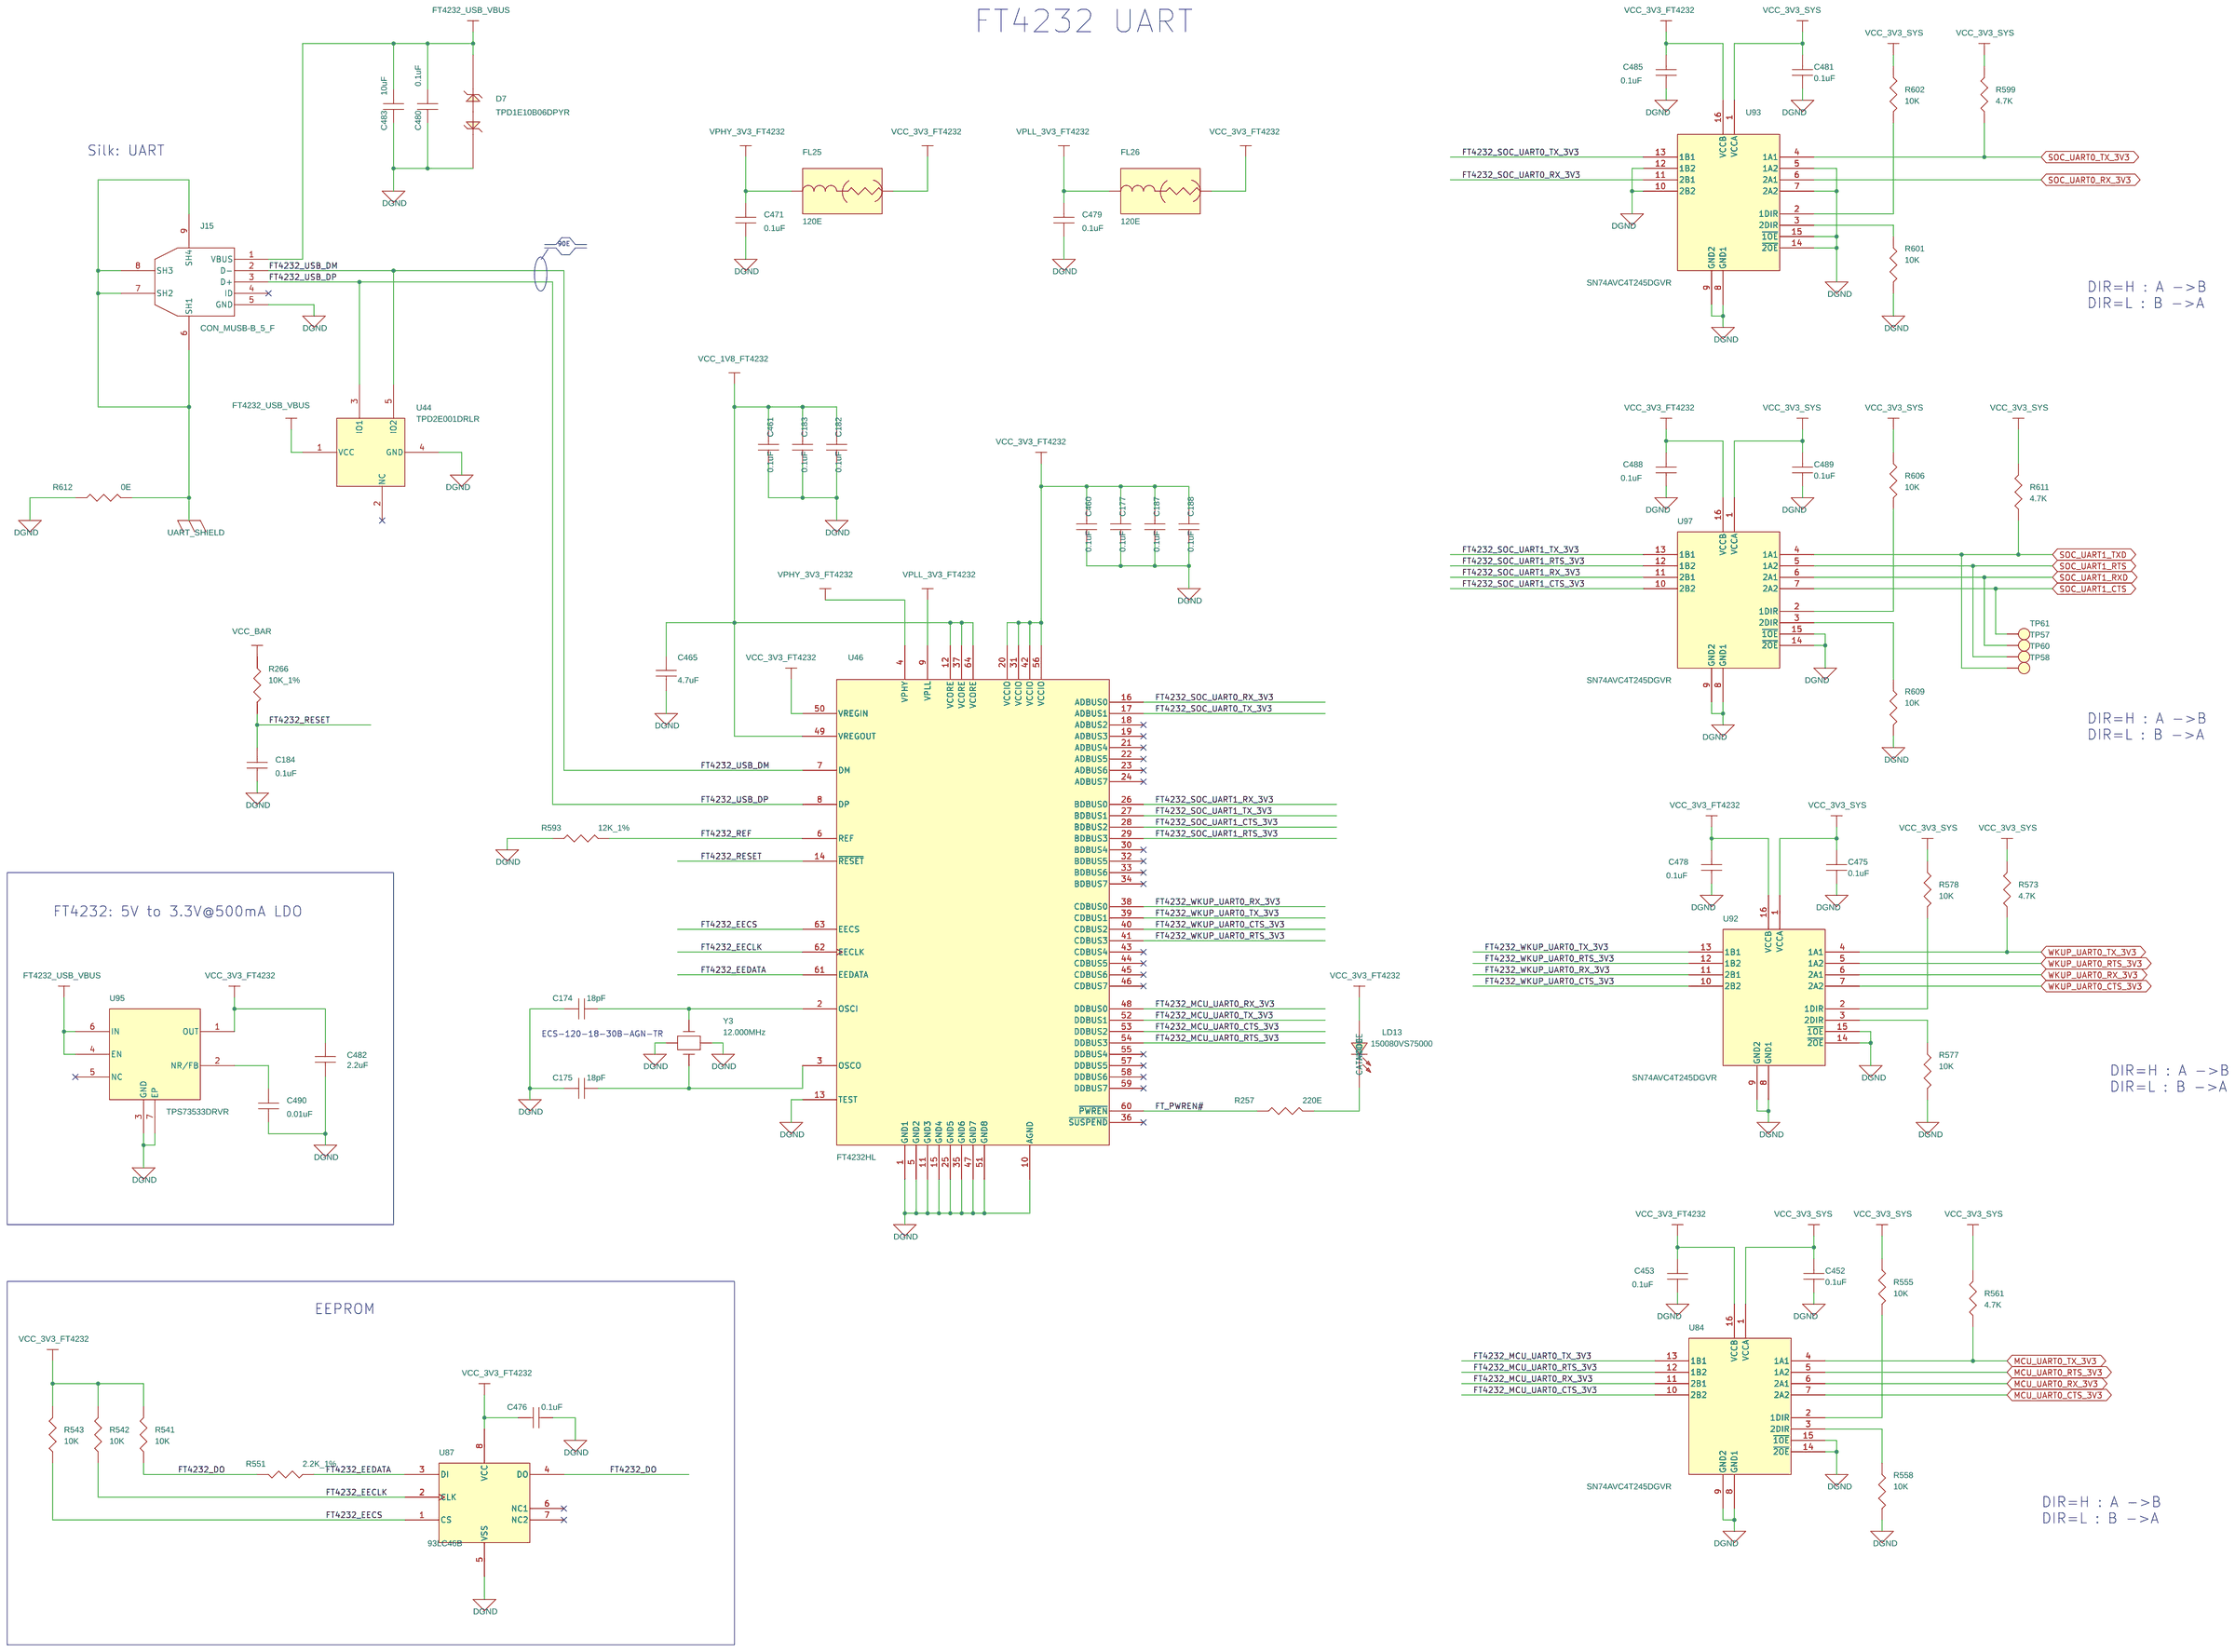
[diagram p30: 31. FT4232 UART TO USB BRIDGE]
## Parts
sheet 29. JTAG BUFFER
C437  0.1uF  [CAP0201_0-5]
C445  0.1uF  [CAP0201_0-5]
C450  0.1uF  [CAP0201_0-5]
C456  0.1uF  [CAP0201_0-5]
C457  0.1uF  [CAP0201_0-5]
C458  0.1uF  [CAP0201_0-5]
C462  0.1uF  [CAP0201_0-5]
C463  0.1uF  [CAP0201_0-5]
C464  0.1uF  [CAP0201_0-5]
C466  0.1uF  [CAP0201_0-5]
C467  0.1uF  [CAP0201_0-5]
C487  0.1uF  [CAP0201_0-5]
C492  0.1uF  [CAP0201_0-5]
R253  10K  [RES0201_0-5]
R254  10K  [RES0201_0-5]
R262  4.7K  [RES0201_0-5]
R343  22E_1%  [RES0201_0-5]
R526  10K  [RES0201_0-5]
R531  10K  [RES0201_0-5]
R553  22E_1%  [RES0201_0-5]
R554  10K  [RES0201_0-5]
R559  10K  [RES0201_0-5]
R562  10K  [RES0201_0-5]
R564  10K  [RES0201_0-5]
R565  22E_1%  [RES0201_0-5]
R574  10K  [RES0201_0-5]
R579  10K  [RES0201_0-5]
R605  10K  [RES0201_0-5]
R607  10K  [RES0201_0-5]
U12  XAM6254ATCGGAALW  [BGA425_19-68_510X510_0-7]  (sections A,B,C,D,E,F,G,H,I,J,K,L,M,N,O,P,Q,R)
U77  SN74LVC1G04DPWR  [X2SON5_TLV7021_30X30_0-4]
U80  TXS0102DQER  [X2SON8_TXS0102_40X60_0-4]
U83  SN74AVC2T244DQMR  [X2SON8_15-74_70X50]
U85  SN74AVC4T245DGVR  [TVSOP16_15-74_150X180]
U86  TXS0102DQER  [X2SON8_TXS0102_40X60_0-4]
U88  SN74AVC4T245DGVR  [TVSOP16_15-74_150X180]
U96  SN74AVC2T244DQMR  [X2SON8_15-74_70X50]
sheet 30. JTAG 20 PIN cTI CONNECTOR
C451  0.01uF  [CAP0201_0-5]
C459  8.2pF  [CAP0201_0-5]
C473  0.01uF  [CAP0201_0-5]
C484  0.1uF  [CAP0201_0-5]
J17  HDR_2X10  [HDR_2X10_FTR-110-51-D-06_S_S_8-7]
R535  33E  [RES0201_0-5]
R537  10K  [RES0201_0-5]
R557  100E_1%  [RES0402_0-5]
R592  4.7K  [RES0201_0-5]
R603  33E  [RES0201_0-5]
R608  0E  [RES0201_0-5]
U81  SN74LVC1G32DPWR  [X2SON5_TLV7021_30X30_0-4]
U91  SN74LVC1G32DPWR  [X2SON5_TLV7021_30X30_0-4]
sheet 31. FT4232 UART TO USB BRIDGE
C174  18pF  [CAP0402_0-75]
C175  18pF  [CAP0402_0-75]
C177  0.1uF  [CAP0402_0-75]
C182  0.1uF  [CAP0402_0-75]
C183  0.1uF  [CAP0402_0-75]
C184  0.1uF  [CAP0201_0-5]
C187  0.1uF  [CAP0402_0-75]
C188  0.1uF  [CAP0402_0-75]
C452  0.1uF  [CAP0201_0-5]
C453  0.1uF  [CAP0201_0-5]
C460  0.1uF  [CAP0402_0-75]
C461  0.1uF  [CAP0402_0-75]
C465  4.7uF  [CAP0402_0-75]
C471  0.1uF  [CAP0402_0-75]
C475  0.1uF  [CAP0201_0-5]
C476  0.1uF  [CAP0402_0-75]
C478  0.1uF  [CAP0201_0-5]
C479  0.1uF  [CAP0402_0-75]
C480  0.1uF  [CAP0402_0-75]
C481  0.1uF  [CAP0201_0-5]
C482  2.2uF  [CAP0402_0-75]
C483  10uF  [CAP0402_0-75]
C485  0.1uF  [CAP0201_0-5]
C488  0.1uF  [CAP0201_0-5]
C489  0.1uF  [CAP0201_0-5]
C490  0.01uF  [CAP0201_0-5]
D7  TPD1E10B06DPYR  [DIO_DFN0402_0-5]
FL25  120E  [EMIFIL_BLM15A_0402_0-6]
FL26  120E  [EMIFIL_BLM15A_0402_0-6]
J15  CON_MUSB-B_5_F  [CON_MUSBB5_629105150521_S_R_S_2-7]
LD13  150080VS75000  [LED_150080VS75000_80X50_SMD_0-8]
R257  220E  [RES0402_0-5]
R266  10K_1%  [RES0201_0-5]
R541  10K  [RES0201_0-5]
R542  10K  [RES0201_0-5]
R543  10K  [RES0201_0-5]
R551  2.2K_1%  [RES0201_0-5]
R555  10K  [RES0201_0-5]
R558  10K  [RES0201_0-5]
R561  4.7K  [RES0201_0-5]
R573  4.7K  [RES0201_0-5]
R577  10K  [RES0201_0-5]
R578  10K  [RES0201_0-5]
R593  12K_1%  [RES0402_0-5]
R599  4.7K  [RES0201_0-5]
R601  10K  [RES0201_0-5]
R602  10K  [RES0201_0-5]
R606  10K  [RES0201_0-5]
R609  10K  [RES0201_0-5]
R611  4.7K  [RES0201_0-5]
R612  0E  [RES0805_0-75]
TP57  THRU HOLE  [TP_36X22]
TP58  THRU HOLE  [TP_36X22]
TP60  TP20_SMD  [TP20_SMD]
TP61  TP20_SMD  [TP20_SMD]
U44  TPD2E001DRLR  [SOT553-5_0-6]
U46  FT4232HL  [LQFP64_19-68_390X390_1-6]
U84  SN74AVC4T245DGVR  [TVSOP16_15-74_150X180]
U87  93LC46B  [MSOP8_25-59_125X125_1-1]
U92  SN74AVC4T245DGVR  [TVSOP16_15-74_150X180]
U93  SN74AVC4T245DGVR  [TVSOP16_15-74_150X180]
U95  TPS73533DRVR  [SON6_25-59_85X85]
U97  SN74AVC4T245DGVR  [TVSOP16_15-74_150X180]
Y3  12.000MHz  [XTAL4_ECX-53BQ_200X130_SMD_0-9]

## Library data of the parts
C184 C437 C445 C450 C452 C453 C456-C458 C462-C464 C466 C467 C475 C478 C481 C484 C485 C487-C489 C492 = CAP: CAP CERAMIC 0.1uF 16V 10% X5R 0201; Alt_Mfr_name: YAGEO AMERICA; Alt_Mfr_part_number: CC0402KRX5R8BB104; Chkd/date: MANIRAJA/230118; Crtd /date: MANIRAJA/230118; Custom_Duty: 15%; Customs_HS_Code: 85322990; Distributor_name: DIGIKEY; Distributor_part_number: 490-14305-1-ND; Footprint Path: Y:\MIS_DATABASE\Library\ALTIUM_TOOL\PCB_FOOTPRINTS\Altium_Footprint_Lib.PcbLib; Height: 0.33MM; Library Path: Y:\MIS_DATABASE\Library\ALTIUM_TOOL\SCHEMATICS_PARTS\MS_DISCRETE_Library.schlib; Mfr_name: MURATA; Mfr_part_number: GRM033R61C104KE14D; Mistral Part No: 120009030072-R; Package: 0201; Part_type: CAPACITORS\CERAMIC; Project: TI_MAXIE_CPB; RoHS: RoHS; Temperature: -55°C+85°C; Tolerance: 10%; Voltage: 16V; Wattage: NA; Weight: 0.33mg; Datasheet: Y:\MIS_DATABASE\DATASHEETS\CAPACITORS\GRM033R61C104KE14.PDF
R253 R254 R526 R531 R537 R541-R543 R554 R555 R558 R559 R562 R564 R574 R577-R579 R601 R602 R605-R607 R609 = RESISTOR: RES 10K 1/20W 5% 0201; Chkd/date: MANIRAJA/050517; Crtd /date: MANIRAJA/050517; Custom_Duty: 15%; Customs_HS_Code: 85332119; Distributor_name: DIGIKEY; Distributor_part_number: 311-10KNCT-ND; Footprint Path: Y:\MIS_DATABASE\Library\ALTIUM_TOOL\PCB_FOOTPRINTS\Altium_Footprint_Lib.PcbLib; Height: 0.26MM; Library Path: Y:\MIS_DATABASE\Library\ALTIUM_TOOL\SCHEMATICS_PARTS\MS_DISCRETE_Library.schlib; Mfr_name: YAGEO AMERICA; Mfr_part_number: RC0201JR-0710KL; Mistral Part No: 110010070051-R; Package: 0201; Part_type: RESISTORS\FIXED; Project: GOLDEN-I LITE; RoHS: RoHS; Temperature: -55°C+125°C; Tolerance: 5%; Voltage: NA; Wattage: 1/20W; Weight: 0.17mg; Datasheet: Y:\MIS_DATABASE\DATASHEETS\RESISTORS\RCXXXXL-SER_MAR18.PDF
R262 R561 R573 R592 R599 R611 = RESISTOR: RES 4.7K 1/20W 5% 0201; Chkd/date: MANIRAJA/200921; Crtd /date: ALVY/200921; Custom_Duty: 15%; Customs_HS_Code: 85332119; Distributor_name: DIGIKEY; Distributor_part_number: 311-4.7KNCT-ND; Footprint Path: Y:\MIS_DATABASE\Library\ALTIUM_TOOL\PCB_FOOTPRINTS\Altium_Footprint_Lib.PcbLib; Height: 0.26MM; Library Path: Y:\MIS_DATABASE\Library\ALTIUM_TOOL\SCHEMATICS_PARTS\MS_DISCRETE_Library.schlib; Mfr_name: YAGEO AMERICA; Mfr_part_number: RC0201JR-074K7L; Mistral Part No: 110021090007-R; Package: 0201; Part_type: RESISTORS\FIXED; Project: TI_AM62x SKEVM_BRD; RoHS: RoHS; Temperature: -55°C+125°C; Tolerance: 5%; Voltage: NA; Wattage: 1/20W; Weight: 0.17mg; Datasheet: Y:\MIS_DATABASE\DATASHEETS\RESISTORS\RCXXXXL-SER_MAR18.PDF
R343 R553 R565 = RESISTOR: RES 22E 1/20W 1% 0201; Chkd/date: MAZHAR/140709; Crtd /date: MAZHAR/220807; Custom_Duty: 15%; Customs_HS_Code: 85332119; Distributor_name: DIGIKEY; Distributor_part_number: P22.0ABCT-ND; Footprint Path: Y:\MIS_DATABASE\Library\ALTIUM_TOOL\PCB_FOOTPRINTS\Altium_Footprint_Lib.PcbLib; Height: 0.26MM; Library Path: Y:\MIS_DATABASE\Library\ALTIUM_TOOL\SCHEMATICS_PARTS\MS_DISCRETE_Library.schlib; Mfr_name: PANASONIC-ECG; Mfr_part_number: ERJ-1GEF22R0C; Mistral Part No: 110009030522-R; Package: 0201; Part_type: RESISTORS\FIXED; Project: V8TS; RoHS: RoHS; Temperature: -55°C+125°C; Tolerance: 1%; Voltage: NA; Wattage: 1/20W; Weight: 0.15mg; Datasheet: Y:\MIS_DATABASE\DATASHEETS\RESISTORS\PAN-ERJSER_NOV17.PDF
U12 = AM62-EVM_BGA425: IC AM62 SoC MICROPROCESSOR BGA425; Chkd/date: ALVY/110621; Crtd /date: MANIRAJA/110621; Custom_Duty: 15%; Customs_HS_Code: 85423100; Distributor_name: NA; Distributor_part_number: NA; Footprint Path: Y:\MIS_DATABASE\Library\ALTIUM_TOOL\PCB_FOOTPRINTS\Altium_Footprint_Lib.PcbLib; Height: 0.65MM; Library Path: Y:\MIS_DATABASE\Library\ALTIUM_TOOL\SCHEMATICS_PARTS\MS_MICROPROCESSOR_Library.schlib; Mfr_name: TEXAS INSTRUMENTS; Mistral Part No: 141221060001; Package: BGA425; Part_type: ICS\DIGITAL\MICROPROCESSOR; Project: AM62_EVM_BRD; RoHS: NA; Temperature: NA; Tolerance: NA; Voltage: NA; Wattage: NA; Weight: NA; Datasheet: Y:\MIS_DATABASE\DATASHEETS\ICS\DIGITAL\MICROCONTROLLER\AM62-SoC_SVB.PDF
U77 = SN74LVC1G04DCKR_SC70-5: IC SINGLE INVERTER GATE X2SON5; Chkd/date: MANIRAJA/141020; Crtd /date: ALVY/131020; Custom_Duty: 15%; Customs_HS_Code: 85423100; Distributor_name: DIGIKEY; Distributor_part_number: 296-37758-1-ND; Footprint Path: Y:\MIS_DATABASE\Library\ALTIUM_TOOL\PCB_FOOTPRINTS\Altium_Footprint_Lib.PcbLib; Height: 0.40MM; Library Path: Y:\MIS_DATABASE\Library\ALTIUM_TOOL\SCHEMATICS_PARTS\MS_GATE_Library.schlib; Mfr_name: TEXAS INSTRUMENTS; Mistral Part No: 141020100010-R; Package: X2SON5; Part_type: ICS\DIGITAL\GATES; Project: AM64X_SKEVM; RoHS: RoHS; Temperature: -40°C+125°C; Tolerance: NA; Voltage: NA; Wattage: NA; Weight: 0.6mg; Datasheet: Y:\MIS_DATABASE\DATASHEETS\ICS\DIGITAL\GATES\SN74LVC1G04XX.PDF
U80 U86 = TXS0102DQX_SON8: IC 2-BIT BI-DIR VOLTAGE-LEVEL TRANSLATOR FOR OPEN-DRAIN AND PUSH-PULL X2SON8; Chkd/date: MANIRAJA/010719; Crtd /date: CHAITHANYA230512; Custom_Duty: 15%; Customs_HS_Code: 85423100; Distributor_name: DIGIKEY; Distributor_part_number: 296-28368-1-ND; Footprint Path: Y:\MIS_DATABASE\Library\ALTIUM_TOOL\PCB_FOOTPRINTS\Altium_Footprint_Lib.PcbLib; Height: 0.40MM; Library Path: Y:\MIS_DATABASE\Library\ALTIUM_TOOL\SCHEMATICS_PARTS\MS_MISCINTERFACE_Library.schlib; Mfr_name: TEXAS INSTRUMENTS; Mistral Part No: 141012050010-R; Package: X2SON8; Part_type: ICS\INTERFACE\LEVEL TRANSLATOR; Project: GEN_3-8_DB; RoHS: RoHS; Temperature: -40°C+85°C; Tolerance: NA; Voltage: NA; Wattage: NA; Weight: 1.2mg; Datasheet: Y:\MIS_DATABASE\DATASHEETS\ICS\INTERFACE\TXS0102-SER.PDF
U83 U96 = SN74AVC2T244DQMR_X2SON8: IC 2-BIT UNDIRECTIONAL VOLTAGE-LEVEL TRANSLATOR X2SON8; Chkd/date: VASANTHA/060516; Crtd /date: VASANTHA/030316; Customs_HS_Code: 15%; Distributor_name: DIGIKEY; Distributor_part_number: 296-29674-1-ND; Height: 0.40MM; Mfr_name: TEXAS INSTRUMENTS; Mistral Part No: 141016030002-R; Package: X2SON8; Part_type: ICS\INTERFACE\LEVEL TRANSLATOR; Pb-Free: 85423100; Project: OCTASIC_3600; RoHS: RoHS; Temperature: -40°C+85°C; Tolerance: NA; Voltage: NA; Wattage: NA; Weight: NA; Datasheet: Y:\MIS_DATABASE\DATASHEETS\ICS\INTERFACE\SN74AVC2T244.PDF
U84 U85 U88 U92 U93 U97 = SN74AVC4T245DGVR_TVSOP16: IC 4-BIT DUAL SUPPLY BUS TRANSCEIVER TVSOP16; Chkd/date: SUHAS/251010; Crtd /date: MAZHAR/201109; Custom_Duty: 15%; Customs_HS_Code: 85423100; Distributor_name: DIGIKEY; Distributor_part_number: 296-18054-1-ND; Height: 1.20MM; Mfr_name: TEXAS INSTRUMENTS; Mistral Part No: 141009110005-P; Package: TVSOP16; Part_type: ICS\DIGITAL\COMBINATIONAL; Project: GOLDEN-I; RoHS: Sb/ Br FREE; Temperature: -40°C+85°C; Datasheet: Y:\MIS_DATABASE\DATASHEETS\ICS\DIGITAL\BUSTRANSCEIVER\SN74AVC4T245.PDF
C451 C473 C490 = CAP: CAP CERAMIC 0.01uF 25V 10% X5R 0201; Chkd/date: MANIRAJA/230118; Crtd /date: MANIRAJA/230118; Custom_Duty: 15%; Customs_HS_Code: 85322990; Distributor_name: DIGIKEY; Distributor_part_number: GRM033R61E103KA12J-ND; Footprint Path: Y:\MIS_DATABASE\Library\ALTIUM_TOOL\PCB_FOOTPRINTS\Altium_Footprint_Lib.PcbLib; Height: 0.33MM; Library Path: Y:\MIS_DATABASE\Library\ALTIUM_TOOL\SCHEMATICS_PARTS\MS_DISCRETE_Library.schlib; Mfr_name: MURATA; Mfr_part_number: GRM033R61E103KA12J; Mistral Part No: 120018010007-R; Package: 0201; Part_type: CAPACITORS\CERAMIC; Project: TI_MAXIE_CPB; RoHS: RoHS; Temperature: -55°C+85°C; Tolerance: 10%; Voltage: 25V; Wattage: NA; Weight: 0.33mg; Datasheet: Y:\MIS_DATABASE\DATASHEETS\CAPACITORS\GRM033R61E103KA12.PDF
C459 = CAP: CAP CERAMIC 8.2pF 25V 0.5pF C0G(NP0) 0201; Chkd/date: MANIRAJA/121020; Crtd /date: ALVY/091020; Custom_Duty: 15%; Customs_HS_Code: 85322990; Distributor_name: DIGIKEY; Distributor_part_number: 490-3140-1-ND; Footprint Path: Y:\MIS_DATABASE\Library\ALTIUM_TOOL\PCB_FOOTPRINTS\Altium_Footprint_Lib.PcbLib; Height: 0.33MM; Library Path: Y:\MIS_DATABASE\Library\ALTIUM_TOOL\SCHEMATICS_PARTS\MS_DISCRETE_Library.schlib; Mfr_name: MURATA; Mfr_part_number: GRM0335C1E8R2DA01D; Mistral Part No: 120020100018-R; Package: 0201; Part_type: CAPACITORS\CERAMIC; Project: AM64X_SKEVM; RoHS: RoHS; Temperature: -55°C+125°C; Tolerance: 0.5pF%; Voltage: 25V; Wattage: NA; Weight: 0.33mg; Datasheet: Y:\MIS_DATABASE\DATASHEETS\CAPACITORS\GRM0335C1E8R2DA01.PDF
J17 = HEADER_10X2_FTR-06: CON HDR 2X10 1.27MM PITCH ST SMD; Chkd/date: MANIRAJA/031218; Crtd /date: CHAITHANYA/050811; Custom_Duty: 24%; Customs_HS_Code: 85369090; Distributor_name: DIGIKEY; Distributor_part_number: SAM8792-ND; Footprint Path: Y:\MIS_DATABASE\Library\ALTIUM_TOOL\PCB_FOOTPRINTS\Altium_Footprint_Lib.PcbLib; Height: 8.67MM; Library Path: Y:\MIS_DATABASE\Library\ALTIUM_TOOL\SCHEMATICS_PARTS\MS_CONNECTOR_Library.schlib; Mfr_name: SAMTEC; Mfr_part_number: FTR-110-51-S-D-06; Mistral Part No: 150011090001-R; Package: SMD; Part_type: CONNECTOR\HEADERS; Project: GEMYC; RoHS: RoHS; Temperature: -55°C+125°C; Tolerance: NA; Voltage: NA; Wattage: NA; Weight: NA; Datasheet: Y:\MIS_DATABASE\DATASHEETS\CONNECTORS\FTR-D-SER.PDF
R535 R603 = RESISTOR: RES 33E 1/20W 5% 0201; Chkd/date: VASANTHA/061216; Crtd /date: MAZHAR/170505; Custom_Duty: 15%; Customs_HS_Code: 85332119; Distributor_name: DIGIKEY; Distributor_part_number: P33AGCT-ND; Footprint Path: Y:\MIS_DATABASE\Library\ALTIUM_TOOL\PCB_FOOTPRINTS\Altium_Footprint_Lib.PcbLib; Height: 0.26MM; Library Path: Y:\MIS_DATABASE\Library\ALTIUM_TOOL\SCHEMATICS_PARTS\MS_DISCRETE_Library.schlib; Mfr_name: PANASONIC-ECG; Mfr_part_number: ERJ-1GEJ330C; Mistral Part No: 110010070052-R; Package: 0201; Part_type: RESISTORS\FIXED; Project: G4SLIM; RoHS: RoHS; Temperature: -55°C+125°C; Tolerance: 5%; Voltage: NA; Wattage: 1/20W; Weight: 0.15mg; Datasheet: Y:\MIS_DATABASE\DATASHEETS\RESISTORS\PAN-ERJXGE-FEB06.PDF
R557 = RESISTOR: RES 100E 1/16W 1% 0402; Chkd/date: MANIRAJA/060318; Crtd /date: NAVEED/220714; Custom_Duty: 15%; Customs_HS_Code: 85332119; Distributor_name: DIGIKEY; Distributor_part_number: 311-100LRCT-ND; Footprint Path: Y:\MIS_DATABASE\Library\ALTIUM_TOOL\PCB_FOOTPRINTS\Altium_Footprint_Lib.PcbLib; Height: 0.40MM; Library Path: Y:\MIS_DATABASE\Library\ALTIUM_TOOL\SCHEMATICS_PARTS\MS_DISCRETE_Library.schlib; Mfr_name: YAGEO AMERICA; Mfr_part_number: RC0402FR-07100RL; Mistral Part No: 110014070015-R; Package: 0402; Part_type: RESISTORS\FIXED; Project: DLRU; RoHS: RoHS; Temperature: -55°C+155°C; Tolerance: 1%; Voltage: NA; Wattage: 1/16W; Weight: 0.65mg; Datasheet: Y:\MIS_DATABASE\DATASHEETS\RESISTORS\RCXXXXL-SER_MAR18.PDF
R608 = RESISTOR: RES 0E 1/20W 5% 0201; Chkd/date: NAVEED/301214; Crtd /date: MUDDU/120710; Custom_Duty: 15%; Customs_HS_Code: 85332119; Distributor_name: DIGIKEY; Distributor_part_number: 311-0.0NCT-ND; Footprint Path: Y:\MIS_DATABASE\Library\ALTIUM_TOOL\PCB_FOOTPRINTS\Altium_Footprint_Lib.PcbLib; Height: 0.26MM; Library Path: Y:\MIS_DATABASE\Library\ALTIUM_TOOL\SCHEMATICS_PARTS\MS_DISCRETE_Library.schlib; Mfr_name: YAGEO AMERICA; Mfr_part_number: RC0201JR-070RL; Mistral Part No: 110010070067-R; Package: 0201; Part_type: RESISTORS\FIXED; Project: PB_BUGBASE; RoHS: RoHS; Temperature: -55°C+125°C; Tolerance: 5%; Voltage: NA; Wattage: 1/20W; Weight: 0.17mg; Datasheet: Y:\MIS_DATABASE\DATASHEETS\RESISTORS\RCXXXXL-SER_MAR18.PDF
U81 U91 = SN74LVC1G32_X2SON5: IC SINGLE 2-INPUT POSITIVE-OR GATE X2SON5; Chkd/date: MANIRAJA/141020; Crtd /date: ALVY/131020; Custom_Duty: 15%; Customs_HS_Code: 85423100; Distributor_name: DIGIKEY; Distributor_part_number: 296-SN74LVC1G32DPWRCT-ND; Footprint Path: Y:\MIS_DATABASE\Library\ALTIUM_TOOL\PCB_FOOTPRINTS\Altium_Footprint_Lib.PcbLib; Height: 0.40MM; Library Path: Y:\MIS_DATABASE\Library\ALTIUM_TOOL\SCHEMATICS_PARTS\MS_GATE_Library.schlib; Mfr_name: TEXAS INSTRUMENTS; Mistral Part No: 141020100011-R; Package: X2SON5; Part_type: ICS\DIGITAL\GATES; Project: AM64X_SKEVM; RoHS: RoHS; Temperature: -40°C+125°C; Tolerance: NA; Voltage: NA; Wattage: NA; Weight: 0.6mg; Datasheet: Y:\MIS_DATABASE\DATASHEETS\ICS\DIGITAL\GATES\SN74LVC1G32XX.PDF
C174 C175 = CAP: CAP CERAMIC 18pF 50V 5% HI-Q C0G(NP0) 0402; Chkd/date: VASANTHA/030315; Crtd /date: NAVEED/271014; Custom_Duty: 15%; Customs_HS_Code: 85322990; Distributor_name: DIGIKEY; Distributor_part_number: 490-3119-1-ND; Footprint Path: Y:\MIS_DATABASE\Library\ALTIUM_TOOL\PCB_FOOTPRINTS\Altium_Footprint_Lib.PcbLib; Height: 0.55MM; Library Path: Y:\MIS_DATABASE\Library\ALTIUM_TOOL\SCHEMATICS_PARTS\MS_DISCRETE_Library.schlib; Mfr_name: MURATA; Mfr_part_number: GJM1555C1H180JB01D; Mistral Part No: 120014100019-R; Package: 0402; Part_type: CAPACITORS\CERAMIC; Project: DC_MIST_RDC; RoHS: RoHS; Temperature: -55°C+125°C; Tolerance: 5%; Voltage: 50V; Wattage: NA; Weight: 6mg; Datasheet: Y:\MIS_DATABASE\DATASHEETS\CAPACITORS\MURATA-GXX-SER_NOV17.PDF
C177 C182 C183 C187 C188 C460 C461 C471 C476 C479 C480 = CAP: CAP CERAMIC 0.1uF 50V 10% X7R 0402; Alt_Mfr_name: YAGEO AMERICA; Alt_Mfr_part_number: CC0402KRX5R8BB104; Chkd/date: MANIRAJA/261020; Crtd /date: ALVY/211020; Custom_Duty: 15%; Customs_HS_Code: 85322990; Distributor_name: DIGIKEY; Distributor_part_number: 490-10700-1-ND; Footprint Path: Y:\MIS_DATABASE\Library\ALTIUM_TOOL\PCB_FOOTPRINTS\Altium_Footprint_Lib.PcbLib; Height: 0.55MM; Library Path: Y:\MIS_DATABASE\Library\ALTIUM_TOOL\SCHEMATICS_PARTS\MS_DISCRETE_Library.schlib; Mfr_name: MURATA; Mfr_part_number: GRM155R71H104KE14D; Mistral Part No: 120011100014-R; Package: 0402; Part_type: CAPACITORS\CERAMIC; Project: J7_CP; RoHS: RoHS; Temperature: -55°C+125°C; Tolerance: 10%; Voltage: 50V; Wattage: NA; Weight: 3.1mg; Datasheet: Y:\MIS_DATABASE\DATASHEETS\CAPACITORS\GRM155R71H104KE14.PDF
C465 = CAP: CAP CERAMIC 4.7uF 10V 20% X5R 0402; Chkd/date: MANIRAJA/110718; Crtd /date: ALVY/110718; Custom_Duty: 15%; Customs_HS_Code: 85322990; Distributor_name: DIGIKEY; Distributor_part_number: 490-14306-1-ND; Footprint Path: Y:\MIS_DATABASE\Library\ALTIUM_TOOL\PCB_FOOTPRINTS\Altium_Footprint_Lib.PcbLib; Height: 0.65MM; Library Path: Y:\MIS_DATABASE\Library\ALTIUM_TOOL\SCHEMATICS_PARTS\MS_DISCRETE_Library.schlib; Mfr_name: MURATA; Mfr_part_number: GRM155R61A475MEAAD; Mistral Part No: 120012060002-R; Package: 0402; Part_type: CAPACITORS\CERAMIC; Project: TI_J7SVB_PCIE_ADD-ON-CARD; RoHS: RoHS; Temperature: -55°C+85°C; Tolerance: 20%; Voltage: 10V; Wattage: NA; Weight: 14mg; Datasheet: Y:\MIS_DATABASE\DATASHEETS\CAPACITORS\GRM155R61A475MEAAD.PDF
C482 = CAP: CAP CERAMIC 2.2uF 25V 10% X5R 0402; Chkd/date: ALVY/010721; Crtd /date: MANIRAJA/010721; Custom_Duty: 15%; Customs_HS_Code: 85322990; Distributor_name: DIGIKEY; Distributor_part_number: 490-12703-1-ND; Footprint Path: Y:\MIS_DATABASE\Library\ALTIUM_TOOL\PCB_FOOTPRINTS\Altium_Footprint_Lib.PcbLib; Height: 0.70MM; Library Path: Y:\MIS_DATABASE\Library\ALTIUM_TOOL\SCHEMATICS_PARTS\MS_DISCRETE_Library.schlib; Mfr_name: MURATA; Mfr_part_number: GRM155R61E225KE11D; Mistral Part No: 120015120001-R; Package: 0402; Part_type: CAPACITORS\CERAMIC; Project: TI_AM263X_CC; RoHS: RoHS; Temperature: -55°C+85°C; Tolerance: 10%; Voltage: 25V; Wattage: NA; Weight: 1.5mg; Datasheet: Y:\MIS_DATABASE\DATASHEETS\CAPACITORS\GRM155R61E225KE11.PDF
C483 = CAP: CAP CERAMIC 10uF 10V 20% X5R 0402; Chkd/date: MANIRAJA/300520; Crtd /date: ALVY/260520; Custom_Duty: 15%; Customs_HS_Code: 85322990; Distributor_name: DIGIKEY; Distributor_part_number: 490-GRM155R61A106ME11DTR-ND; Footprint Path: Y:\MIS_DATABASE\Library\ALTIUM_TOOL\PCB_FOOTPRINTS\Altium_Footprint_Lib.PcbLib; Height: 0.55MM; Library Path: Y:\MIS_DATABASE\Library\ALTIUM_TOOL\SCHEMATICS_PARTS\MS_DISCRETE_Library.schlib; Mfr_name: MURATA; Mfr_part_number: GRM155R61A106ME11D; Mistral Part No: 120013110019-R; Package: 0402; Part_type: CAPACITORS\CERAMIC; Project: QCS610_NANOSOM; RoHS: RoHS; Temperature: -55°C+85°C; Tolerance: 20%; Voltage: 10V; Wattage: NA; Weight: 3.1mg; Datasheet: Y:\MIS_DATABASE\DATASHEETS\CAPACITORS\MURATA-GXX-SER_NOV17.PDF
D7 = DIODE_SOD323: DIODE 1CH ESD PROTECTION X1SON2; Chkd/date: MANIRAJA/040420; Crtd /date: VASANTHA/181114; Custom_Duty: 15%; Customs_HS_Code: 85423100; Distributor_name: DIGIKEY; Distributor_part_number: 296-30406-1-ND; Footprint Path: Y:\MIS_DATABASE\Library\ALTIUM_TOOL\PCB_FOOTPRINTS\Altium_Footprint_Lib.PcbLib; Height: 0.45MM; Library Path: Y:\MIS_DATABASE\Library\ALTIUM_TOOL\SCHEMATICS_PARTS\MS_DISCRETE_Library.schlib; Mfr_name: TEXAS INSTRUMENTS; Mistral Part No: 130014110022-R; Package: X1SON2; Part_type: DIODE; Project: GALILEO_EVM; RoHS: RoHS; Temperature: -40°C+125°C; Tolerance: NA; Voltage: NA; Wattage: NA; Weight: 1mg; Datasheet: Y:\MIS_DATABASE\DATASHEETS\ICS\INTERFACE\TPD1E10B06-SER.PDF
FL25 FL26 = EMIFILTER_IND: IND FERRITE BEAD CHIP 120E 2A 0402; Chkd/date: NAVEED/241114; Crtd /date: USMAN/170613; Custom_Duty: 24%; Customs_HS_Code: 85369090; Distributor_name: DIGIKEY; Distributor_part_number: 490-9656-1-ND; Footprint Path: Y:\MIS_DATABASE\Library\ALTIUM_TOOL\PCB_FOOTPRINTS\Altium_Footprint_Lib.PcbLib; Height: 0.55MM; Library Path: Y:\MIS_DATABASE\Library\ALTIUM_TOOL\SCHEMATICS_PARTS\MS_FILTER_Library.schlib; Mfr_name: MURATA; Mfr_part_number: BLM15PX121SN1D; Mistral Part No: 130013060022-R; Package: 0402; Part_type: INDUCTOR; Project: GEN_3-8; RoHS: RoHS; Temperature: -55°C+125°C; Tolerance: 25%; Voltage: NA; Wattage: NA; Weight: 1mg; Datasheet: Y:\MIS_DATABASE\DATASHEETS\DISCRETES\INDUCTORS\BLM15-SN1-SER.PDF
J15 = CON_USB_MINI-B: CON MICRO USB TYPE B 5POS FEMALE RT SMD; Chkd/date: MANIRAJA/150519; Crtd /date: ALVY/150519; Custom_Duty: 24%; Customs_HS_Code: 85369090; Distributor_name: DIGIKEY; Distributor_part_number: 732-5960-1-ND; Footprint Path: Y:\MIS_DATABASE\Library\ALTIUM_TOOL\PCB_FOOTPRINTS\Altium_Footprint_Lib.PcbLib; Height: 2.66MM; Library Path: Y:\MIS_DATABASE\Library\ALTIUM_TOOL\SCHEMATICS_PARTS\MS_CONNECTOR_Library.schlib; Mfr_name: WURTH ELECTRONICS; Mfr_part_number: 629105150521; Mistral Part No: 150019050015-R; Package: SMD; Part_type: CONNECTOR\USB; Project: NEXTNAV_ALT-STATION_ATE_BRD; RoHS: RoHS; Temperature: -40°C+85°C; Tolerance: NA; Voltage: NA; Wattage: NA; Weight: 360mg; Datasheet: Y:\MIS_DATABASE\DATASHEETS\CONNECTORS\629105150521.PDF
LD13 = DIODE_LED: DIODE LED BRIGHT GREEN SMD; Chkd/date: MANIRAJA/180820; Crtd /date: ALVY/180820; Custom_Duty: 24%; Customs_HS_Code: 85439000; Distributor_name: DIGIKEY; Distributor_part_number: 732-4986-1-ND; Footprint Path: Y:\MIS_DATABASE\Library\ALTIUM_TOOL\PCB_FOOTPRINTS\Altium_Footprint_Lib.PcbLib; Height: 0.80MM; Library Path: Y:\MIS_DATABASE\Library\ALTIUM_TOOL\SCHEMATICS_PARTS\MS_OPTO_Library.schlib; Mfr_name: WURTH ELECTRONICS; Mistral Part No: 130020080012-R; Package: SMD; Part_type: OPTO\LED; Project: AM64x_EVM_BRD; RoHS: RoHS; Temperature: -40°C+85°C; Tolerance: NA; Voltage: NA; Wattage: NA; Weight: 10mg; Datasheet: Y:\MIS_DATABASE\DATASHEETS\DISCRETES\LEDS\150080VS75000.PDF
R257 = RESISTOR: RES 220E 1/10W 5% 0402; Chkd/date: VASANTHA/291216; Crtd /date: GEETHA/260406; Custom_Duty: 15%; Customs_HS_Code: 85332119; Distributor_name: DIGIKEY; Distributor_part_number: P220JCT-ND; Footprint Path: Y:\MIS_DATABASE\Library\ALTIUM_TOOL\PCB_FOOTPRINTS\Altium_Footprint_Lib.PcbLib; Height: 0.40MM; Library Path: Y:\MIS_DATABASE\Library\ALTIUM_TOOL\SCHEMATICS_PARTS\MS_DISCRETE_Library.schlib; Mfr_name: PANASONIC-ECG; Mfr_part_number: ERJ-2GEJ221X; Mistral Part No: 110009030506-R; Package: 0402; Part_type: RESISTORS\FIXED; Project: RED EYE; RoHS: RoHS; Temperature: -55°C+155°C; Tolerance: 5%; Voltage: NA; Wattage: 1/10W; Weight: 0.8mg; Datasheet: Y:\MIS_DATABASE\DATASHEETS\RESISTORS\PAN-ERJSER_NOV17.PDF
R266 = RESISTOR: RES 10K 1/20W 1% 0201; Chkd/date: VASANTHA/270117; Crtd /date: MANIRAJA/270117; Custom_Duty: 15%; Customs_HS_Code: 85332119; Distributor_name: DIGIKEY; Distributor_part_number: 311-10.0KMCT-ND; Footprint Path: Y:\MIS_DATABASE\Library\ALTIUM_TOOL\PCB_FOOTPRINTS\Altium_Footprint_Lib.PcbLib; Height: 0.26MM; Library Path: Y:\MIS_DATABASE\Library\ALTIUM_TOOL\SCHEMATICS_PARTS\MS_DISCRETE_Library.schlib; Mfr_name: YAGEO AMERICA; Mfr_part_number: RC0201FR-0710KL; Mistral Part No: 110011040018-R; Package: 0201; Part_type: RESISTORS\FIXED; Project: GOLDEN-I LITE; RoHS: RoHS; Temperature: -55°C+125°C; Tolerance: 1%; Voltage: NA; Wattage: 1/20W; Weight: 0.17mg; Datasheet: Y:\MIS_DATABASE\DATASHEETS\RESISTORS\RCXXXXL-SER_MAR18.PDF
R551 = RESISTOR: RES 2.2K 1/20W 1% 0201; Chkd/date: VASANTHA/270117; Crtd /date: MANIRAJA/270117; Custom_Duty: 15%; Customs_HS_Code: 85332119; Distributor_name: DIGIKEY; Distributor_part_number: YAG2572CT-ND; Footprint Path: Y:\MIS_DATABASE\Library\ALTIUM_TOOL\PCB_FOOTPRINTS\Altium_Footprint_Lib.PcbLib; Height: 0.26MM; Library Path: Y:\MIS_DATABASE\Library\ALTIUM_TOOL\SCHEMATICS_PARTS\MS_DISCRETE_Library.schlib; Manufacturer: YAGEO AMERICA; Mfr_name: PANASONIC-ECG; Mfr_part_number: RC0201FR-072K2L; Mistral Part No: 110017010016-R; Package: 0201; Part_type: RESISTORS\FIXED; Project: GOLDEN-I LITE; RoHS: RoHS; Temperature: -55°C+125°C; Tolerance: 1%; Voltage: NA; Wattage: 1/20W; Weight: 0.17mg; Datasheet: Y:\MIS_DATABASE\DATASHEETS\RESISTORS\RCXXXXL-SER_MAR18.PDF
R593 = RESISTOR: RES 12K 1/10W 1% 0402; Chkd/date: VASANTHA/041215; Crtd /date: VASANTHA/041215; Custom_Duty: 15%; Customs_HS_Code: 85332119; Distributor_name: DIGIKEY; Distributor_part_number: P12.0KLCT-ND; Footprint Path: Y:\MIS_DATABASE\Library\ALTIUM_TOOL\PCB_FOOTPRINTS\Altium_Footprint_Lib.PcbLib; Height: 0.40MM; Library Path: Y:\MIS_DATABASE\Library\ALTIUM_TOOL\SCHEMATICS_PARTS\MS_DISCRETE_Library.schlib; Mfr_name: PANASONIC-ECG; Mfr_part_number: ERJ-2RKF1202X; Mistral Part No: 110019040053-R; Package: 0402; Part_type: RESISTORS\FIXED; Project: TI_C5545; RoHS: RoHS; Temperature: -55°C+155°C; Tolerance: 1%; Voltage: NA; Wattage: 1/10W; Weight: 0.8mg; Datasheet: Y:\MIS_DATABASE\DATASHEETS\RESISTORS\PAN-ERJSER_NOV17.PDF
R612 = RESISTOR: RES 0E 1/8W 5% 0805; Chkd/date: VASANTHA/130416; Crtd /date: JEBRAN/020316; Custom_Duty: 15%; Customs_HS_Code: 85332119; Distributor_name: DIGIKEY; Distributor_part_number: 311-0.0ARCT-ND; Footprint Path: Y:\MIS_DATABASE\Library\ALTIUM_TOOL\PCB_FOOTPRINTS\Altium_Footprint_Lib.PcbLib; Height: 0.60MM; Library Path: Y:\MIS_DATABASE\Library\ALTIUM_TOOL\SCHEMATICS_PARTS\MS_DISCRETE_Library.schlib; Mfr_name: YAGEO AMERICA; Mfr_part_number: RC0805JR-070RL; Mistral Part No: 110009030074-R; Package: 0805; Part_type: RESISTORS\FIXED; Project: ZK_BIOMETRIC; RoHS: RoHS; Temperature: -55°C+155°C; Tolerance: 5%; Voltage: NA; Wattage: 1/8W; Weight: 5.5mg; Datasheet: Y:\MIS_DATABASE\DATASHEETS\RESISTORS\RCXXXXL-SER_MAR18.PDF
TP57 TP58 = TESTPOINT: TESTPOINT 0.56MM DRILL PTH; Chkd/date: BAVISH/040311; Crtd /date: MAZHAR/110405; Distributor_name: NA; Distributor_part_number: NA; Height: NA; Mfr_name: LOCAL; Mistral Part No: 130010010008; Package: THRU-HOLE; Project: KOPIN_MODULS; Temperature: NA; Tolerance: NA; Voltage: NA; Wattage: NA; Weight: NA; Datasheet: NA
TP60 TP61 = TESTPOINT: TESTPOINT CIR 20 SMD; Chkd/date: SHREESHAIL/171006; Crtd /date: MAZHAR/171006; Custom_Duty: NA; Customs_HS_Code: NA; Distributor_name: NA; Distributor_part_number: NA; Footprint Path: Y:\MIS_DATABASE\Library\ALTIUM_TOOL\PCB_FOOTPRINTS\Altium_Footprint_Lib.PcbLib; Height: NA; Library Path: Y:\MIS_DATABASE\Library\ALTIUM_TOOL\SCHEMATICS_PARTS\MS_DISCRETE_Library.schlib; MECHANICAL 3D STEP FILE: NA; Mfr_name: LOCAL; Mistral Part No: NA; Package: SMD; Project: BT MODULE_CSRBC04; RoHS: NA; Temperature: NA; Tolerance: NA; Voltage: NA; Wattage: NA; Weight: NA; Datasheet: NA
U44 = TPD2E001DRLR_SOT-5: IC ESD-PROTECTION DIODE ARRAYS SOT-5; Chkd/date: NAVEED/150714; Crtd /date: MUDDU/250510; Custom_Duty: 15%; Customs_HS_Code: 85423100; Distributor_name: DIGIKEY; Distributor_part_number: 296-21883-1-ND; Footprint Path: Y:\MIS_DATABASE\Library\ALTIUM_TOOL\PCB_FOOTPRINTS\Altium_Footprint_Lib.PcbLib; Height: 0.60MM; Library Path: Y:\MIS_DATABASE\Library\ALTIUM_TOOL\SCHEMATICS_PARTS\MS_FILTER_Library.schlib; Mfr_name: TEXAS INSTRUMENTS; Mistral Part No: 140110060007-R; Package: SOT-5; Part_type: ICS\ANALOG\ACTIVE FILTER; Project: CENTAURUS; RoHS: RoHS; Temperature: -40°C+85°C; Tolerance: NA; Voltage: NA; Wattage: NA; Weight: 2.8mg; Datasheet: Y:\MIS_DATABASE\DATASHEETS\ICS\MISC\TPD2E001DRLR.PDF
U46 = FT4232H_LQFP64: IC HIGH SPEED QUAD USB UART LQFP64; Chkd/date: MANIRAJA/110917; Crtd /date: VIJAYALAKSHMI/120813; Custom_Duty: 15%; Customs_HS_Code: 85423100; Distributor_name: DIGIKEY; Distributor_part_number: 768-1026-1-ND; Footprint Path: Y:\MIS_DATABASE\Library\ALTIUM_TOOL\PCB_FOOTPRINTS\Altium_Footprint_Lib.PcbLib; Height: 1.60MM; Library Path: Y:\MIS_DATABASE\Library\ALTIUM_TOOL\SCHEMATICS_PARTS\MS_COMBINATIONAL_Library.schlib; Mfr_name: FTDI; Mfr_part_number: FT4232HL-REEL; Mistral Part No: 141013080006-R; Package: LQFP64; Part_type: ICS\DIGITAL\PERIPHERAL; Project: DM37XX; RoHS: RoHS; Temperature: -40°C+85°C; Tolerance: NA; Voltage: NA; Wattage: NA; Weight: 342.7mg; Datasheet: Y:\MIS_DATABASE\DATASHEETS\ICS\DIGITAL\PERIPHERAL\FT4232HX.PDF
U87 = 93LC46B_MSOP8: IC 1K MICROWIRE COMPATIBLE SERIAL EEPROM MSOP8; Chkd/date: MANIRAJA/150218; Crtd /date: ALVY/150218; Custom_Duty: 15%; Customs_HS_Code: 85423100; Distributor_name: DIGIKEY; Distributor_part_number: 93LC46B-I/MS-ND; Footprint Path: Y:\MIS_DATABASE\Library\ALTIUM_TOOL\PCB_FOOTPRINTS\Altium_Footprint_Lib.PcbLib; Height: 1.10MM; Library Path: Y:\MIS_DATABASE\Library\ALTIUM_TOOL\SCHEMATICS_PARTS\MS_MISCMEMORY_Library.schlib; Mfr_name: MICROCHIP; Mfr_part_number: 93LC46B-I/MS; Mistral Part No: 141118020002-R; Package: MSOP8; Part_type: ICS\DIGITAL\MEMORY; Project: TI_MAXIE_CPB; RoHS: RoHS; Temperature: -40°C+85°C; Tolerance: NA; Voltage: NA; Wattage: NA; Weight: 140mg; Datasheet: Y:\MIS_DATABASE\DATASHEETS\ICS\MEMORY\93LC46B.PDF
U95 = TPS73501DRVR_SON6: IC 500mA LOW DROPOUT REGULATOR SON6; Chkd/date: VASANTHA/280915; Crtd /date: NAVEED/011014; Custom_Duty: 15%; Customs_HS_Code: 85423100; Distributor_name: DIGIKEY; Distributor_part_number: TPS73533DRVR-ND; Height: 0.80MM; Mfr_name: TEXAS INSTRUMENTS; Mistral Part No: 142014100001-R; Package: SON6; Part_type: ICS\POWER\VOLTAGE REGULATOR; Project: BLUETOOTH_WATCH; RoHS: RoHS; Temperature: -40°C+125°C; Tolerance: NA; Voltage: NA; Wattage: NA; Weight: NA; Datasheet: Y:\MIS_DATABASE\DATASHEETS\ICS\POWER\TPS735.PDF
Y3 = CRY4_13: CRY 12.000MHz 18pF SMD; Chkd/date: MANIRAJA/271021; Crtd /date: ALVY/271021; Custom_Duty: 24%; Customs_HS_Code: 85439000; Distributor_name: DIGIKEY; Distributor_part_number: XC2719CT-ND; Footprint Path: Y:\MIS_DATABASE\Library\ALTIUM_TOOL\PCB_FOOTPRINTS\Altium_Footprint_Lib.PcbLib; Height: 0.85MM; Library Path: Y:\MIS_DATABASE\Library\ALTIUM_TOOL\SCHEMATICS_PARTS\MS_DISCRETE_Library.schlib; Mfr_name: ECS INC; Mfr_part_number: ECS-120-18-30B-AGN-TR; Mistral Part No: 130021100037-R; Package: SMD; Part_type: CRYSTAL; Project: TI_AM62x SKEVM_BRD; RoHS: RoHS; Temperature: -40°C+85°C; Tolerance: NA; Voltage: NA; Wattage: NA; Weight: 159.425mg; Datasheet: Y:\MIS_DATABASE\DATASHEETS\MISC\CRY_OSC\ECS-53B.PDF

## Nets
DGND: C174.2 C175.2 C177.1 C182.1 C183.1 C184.1 C187.1 C188.1 C437.1 C445.1 C450.1 C451.1 C452.1 C453.1 C456.1 C457.1 C458.1 C459.2 C460.1 C461.1 C462.1 C463.1 C464.1 C465.2 C466.1 C467.1 C471.1 C473.1 C475.1 C476.1 C478.1 C479.1 C480.1 C481.1 C482.2 C483.1 C484.2 C485.1 C487.1 C488.1 C489.1 C490.1 C492.1 D7.1 J15.5(GND) J17.10 J17.12 J17.16 J17.20 R262.2 R526.1 R554.1 R558.1 R559.1 R562.1 R577.1 R593.1 R601.1 R608.1 R609.1 R612.1 U44.4(GND) U46.1(GND1) U46.5(GND2) U46.10(AGND) U46.11(GND3) U46.13(TEST) U46.15(GND4) U46.25(GND5) U46.35(GND6) U46.47(GND7) U46.51(GND8) U77.3(GND) U80.4(GND) U81.3(GND) U83.3(A2) U83.5(GND) U83.6(B2) U84.8(GND1) U84.9(GND2) U84.14(~{2OE}) U84.15(~{1OE}) U85.8(GND1) U85.9(GND2) U86.4(GND) U87.5(VSS) U88.8(GND1) U88.9(GND2) U91.3(GND) U92.8(GND1) U92.9(GND2) U92.14(~{2OE}) U92.15(~{1OE}) U93.5(1A2) U93.7(2A2) U93.8(GND1) U93.9(GND2) U93.10(2B2) U93.12(1B2) U93.14(~{2OE}) U93.15(~{1OE}) U95.3(GND) U95.7(EP) U96.3(A2) U96.5(GND) U96.6(B2) U97.8(GND1) U97.9(GND2) U97.14(~{2OE}) U97.15(~{1OE}) Y3.2 Y3.4 ; also on sheet 1 10 11 12 13 14 15 16 17 18 19 20 21 22 23 24 25 26 27 28 32 33 34 35 36 37 38 39 40 41 42 43
VCC3V3_XDS: C464.2 C466.2 C467.2 U83.8(VCCB) U85.16(VCCB) U86.8(VCCB) ; also on sheet 1 28
VCC_1V8_FT4232: C182.2 C183.2 C461.2 C465.1 U46.12(VCORE) U46.37(VCORE) U46.49(VREGOUT) U46.64(VCORE)
VCC_3V3_FT4232: C177.2 C187.2 C188.2 C453.2 C460.2 C476.2 C478.2 C482.1 C485.2 C488.2 FL25.2 FL26.2 LD13.2(ANODE) R541.2 R542.2 R543.2 U46.20(VCCIO) U46.31(VCCIO) U46.42(VCCIO) U46.50(VREGIN) U46.56(VCCIO) U84.16(VCCB) U87.8(VCC) U92.16(VCCB) U93.16(VCCB) U95.1(OUT) U97.16(VCCB)
VCC_3V3_SYS: C437.2 C445.2 C450.2 C451.2 C452.2 C456.2 C457.2 C458.2 C462.2 C463.2 C473.2 C475.2 C481.2 C484.1 C487.2 C489.2 C492.2 J17.5 R253.1 R254.1 R531.2 R537.2 R555.2 R561.1 R564.2 R573.1 R574.2 R578.2 R579.2 R592.1 R599.1 R602.2 R605.1 R606.2 R607.1 R611.1 U77.5(VCC) U80.1(VCCA) U80.8(VCCB) U81.5(VCC) U83.1(VCCA) U84.1(VCCA) U85.1(VCCA) U86.1(VCCA) U88.1(VCCA) U88.16(VCCB) U91.5(VCC) U92.1(VCCA) U93.1(VCCA) U96.1(VCCA) U96.8(VCCB) U97.1(VCCA) ; also on sheet 10 12 13 14 18 19 20 22 23 24 25 26 27 32 33 34 35 36 37 38 39 40 41 42 43
FT4232_DO: R541.1 R551.2 U87.4(DO)
FT4232_EECLK: R542.1 U46.62(EECLK) U87.2(CLK)
FT4232_EECS: R543.1 U46.63(EECS) U87.1(CS)
FT4232_EEDATA: R551.1 U46.61(EEDATA) U87.3(DI)
FT4232_MCU_UART0_CTS_3V3: U46.53(DDBUS2) U84.10(2B2)
FT4232_MCU_UART0_RTS_3V3: U46.54(DDBUS3) U84.12(1B2)
FT4232_MCU_UART0_RX_3V3: U46.48(DDBUS0) U84.11(2B1)
FT4232_MCU_UART0_TX_3V3: U46.52(DDBUS1) U84.13(1B1)
FT4232_REF: R593.2 U46.6(REF)
FT4232_RESET: C184.2 R266.1 U46.14(~{RESET})
FT4232_SOC_UART0_RX_3V3: U46.16(ADBUS0) U93.11(2B1)
FT4232_SOC_UART0_TX_3V3: U46.17(ADBUS1) U93.13(1B1)
FT4232_SOC_UART1_CTS_3V3: U46.28(BDBUS2) U97.10(2B2)
FT4232_SOC_UART1_RTS_3V3: U46.29(BDBUS3) U97.12(1B2)
FT4232_SOC_UART1_RX_3V3: U46.26(BDBUS0) U97.11(2B1)
FT4232_SOC_UART1_TX_3V3: U46.27(BDBUS1) U97.13(1B1)
FT4232_USB_DM: J15.2(D-) U44.5(IO2) U46.7(DM)
FT4232_USB_DP: J15.3(D+) U44.3(IO1) U46.8(DP)
FT4232_USB_VBUS: C480.2 C483.2 D7.2 J15.1(VBUS) U44.1(VCC) U95.4(EN) U95.6(IN)
FT4232_WKUP_UART0_CTS_3V3: U46.40(CDBUS2) U92.10(2B2)
FT4232_WKUP_UART0_RTS_3V3: U46.41(CDBUS3) U92.12(1B2)
FT4232_WKUP_UART0_RX_3V3: U46.38(CDBUS0) U92.11(2B1)
FT4232_WKUP_UART0_TX_3V3: U46.39(CDBUS1) U92.13(1B1)
FT_PWREN#: R257.1 U46.60(~{PWREN})
JTAG_cTI_RTCK: J17.9 R603.1
JTAG_cTI_TCK: J17.11 R537.1 R557.1 U81.1(B) U91.1(B)
JTAG_DIR: R559.2 U88.2(1DIR) U88.3(2DIR)
JTAG_EMU0: J17.13 R605.2 U80.7(B1)
JTAG_EMU1: J17.14 R607.2 U80.6(B2)
JTAG_EMU_RSTn: J17.15 R592.2 ; also on sheet 42
JTAG_TCK: R535.1 R564.1 U88.12(1B2)
JTAG_TDI: J17.3 R579.1 U88.10(2B2)
JTAG_TDIS: J17.4 R608.2
JTAG_TDO: J17.7 U96.7(B1)
JTAG_TMS: J17.1 R574.1 U88.11(2B1)
JTAG_TRST#: J17.2 R562.2 U88.13(1B1)
MCU_UART0_CTS_3V3: U84.7(2A2) ; also on sheet 34
MCU_UART0_RTS_3V3: U84.5(1A2) ; also on sheet 34
MCU_UART0_RX_3V3: U84.6(2A1) ; also on sheet 34
MCU_UART0_TX_3V3: R561.2 U84.4(1A1) ; also on sheet 34
SEL_XDS: U77.4(Y) U80.5(OE) U83.4(~{OE}) U85.14(~{2OE}) U85.15(~{1OE})
SEL_XDS110_INV: J17.8 R526.2 R531.1 U77.2(A) U81.2(A) U86.5(OE) U88.14(~{2OE}) U88.15(~{1OE}) U91.2(A) U96.4(~{OE})
SoC_EMU0: R254.2 U12.E12(EMU0) U80.2(A1) U86.2(A1)
SoC_EMU1: R253.2 U12.C11(EMU1) U80.3(A2) U86.3(A2)
SoC_TCK: R553.1 R565.1 U12.A10(TCK)
SoC_TDI: U12.A11(TDI) U85.4(1A1) U88.7(2A2)
SoC_TDO: R343.1 U83.2(A1) U96.2(A1)
SoC_TMS: U12.B11(TMS) U85.6(2A1) U88.6(2A1)
SoC_TRST#: R262.1 U12.B10(TRSTN) U85.7(2A2) U88.4(1A1)
SOC_UART0_RX_3V3: U93.6(2A1) ; also on sheet 42
SOC_UART0_TX_3V3: R599.2 U93.4(1A1) ; also on sheet 42
SOC_UART1_CTS: TP61.1(TP) U97.7(2A2) ; also on sheet 37
SOC_UART1_RTS: TP60.1(TP) U97.5(1A2) ; also on sheet 37
SOC_UART1_RXD: TP57.1(TP) U97.6(2A1) ; also on sheet 37
SOC_UART1_TXD: R611.2 TP58.1(TP) U97.4(1A1) ; also on sheet 37
UART_SHIELD: J15.6(SH1) J15.7(SH2) J15.8(SH3) J15.9(SH4) R612.2
VPHY_3V3_FT4232: C471.2 FL25.1 U46.4(VPHY)
VPLL_3V3_FT4232: C479.2 FL26.1 R266.2 U46.9(VPLL)
WKUP_UART0_CTS_3V3: U92.7(2A2) ; also on sheet 32
WKUP_UART0_RTS_3V3: U92.5(1A2) ; also on sheet 32
WKUP_UART0_RX_3V3: U92.6(2A1) ; also on sheet 32
WKUP_UART0_TX_3V3: R573.2 U92.4(1A1) ; also on sheet 32
XDS110_DIR: R554.2 U85.2(1DIR) U85.3(2DIR)
XDS110_EMU0: U86.7(B1) ; also on sheet 28
XDS110_EMU1: U86.6(B2) ; also on sheet 28
XDS110_TCK: U85.12(1B2) ; also on sheet 28
XDS110_TDI: U85.13(1B1) ; also on sheet 28
XDS110_TDO: U83.7(B1) ; also on sheet 28
XDS110_TMS: U85.11(2B1) ; also on sheet 28
XDS110_TRST#: U85.10(2B2) ; also on sheet 28
N16856152: C175.1 U46.3(OSCO) Y3.3
N16856224: C174.1 U46.2(OSCI) Y3.1
N16857368: C490.2 U95.2(NR/FB)
N16894003: R577.2 U92.3(2DIR)
N16894009: R578.1 U92.2(1DIR)
N16994873: R535.2 U81.4(Y)
N16994875: R603.2 U91.4(Y)
N16995245: C459.1 R557.2
N17030548: R343.2 U12.D12(TDO)
N17034231: R565.2 U88.5(1A2)
N17378539: LD13.1(CATHODE) R257.2
N18571509: R609.2 U97.3(2DIR)
N18571515: R606.1 U97.2(1DIR)
N20674580: R602.1 U93.2(1DIR)
N20674790: R601.2 U93.3(2DIR)
N20689650: R558.2 U84.3(2DIR)
N20689656: R555.1 U84.2(1DIR)
N20696645: R553.2 U85.5(1A2)

Not connected (* = marked no-connect by the designer): J15 4(ID)*; J17 17* 18* 19*; U44 2(NC)*; U46 18(ADBUS2)* 19(ADBUS3)* 21(ADBUS4)* 22(ADBUS5)* 23(ADBUS6)* 24(ADBUS7)* 30(BDBUS4)* 32(BDBUS5)* 33(BDBUS6)* 34(BDBUS7)* 36(~{SUSPEND})* 43(CDBUS4)* 44(CDBUS5)* 45(CDBUS6)* 46(CDBUS7)* 55(DDBUS4)* 57(DDBUS5)* 58(DDBUS6)* 59(DDBUS7)*; U77 1(NC)*; U87 6(NC1)* 7(NC2)*; U95 5(NC)*

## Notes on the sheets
sheet 29
- JTAG SOC SECTION
- cTI20 JTAG BUFFERS
- BUFFER XDS110
- JTAG_DIR = H: A -> B
  JTAG_DIR = L: B -> A
  OE = H: output = Hi-Z
- XDS110_DIR = H: A -> B
  XDS110_DIR = L: B -> A
  OE = H: output = Hi-Z
- CAD NOTE: Buffers U88 and U96
  need to be placed closer to the
  cTI-20pin connector J17 to reduce Stub length of the JTAG signals.
sheet 30
- JTAG 20 PIN cTI CONNECTOR
- Silk: cTI
- JTAG CLOCK BUFFER
- It should be connected to PORz of the SoC TBD
sheet 31
- FT4232 UART
- Silk: UART
- 90E
- DIR=H : A ->B
  DIR=L : B ->A
- DIR=H : A ->B
  DIR=L : B ->A
- FT4232: 5V to 3.3V@500mA LDO
- ECS-120-18-30B-AGN-TR
- DIR=H : A ->B
  DIR=L : B ->A
- EEPROM
- DIR=H : A ->B
  DIR=L : B ->A
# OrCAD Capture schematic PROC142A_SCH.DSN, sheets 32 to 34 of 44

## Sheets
32 32. PRU HEADER: size C; title: PRU HEADER
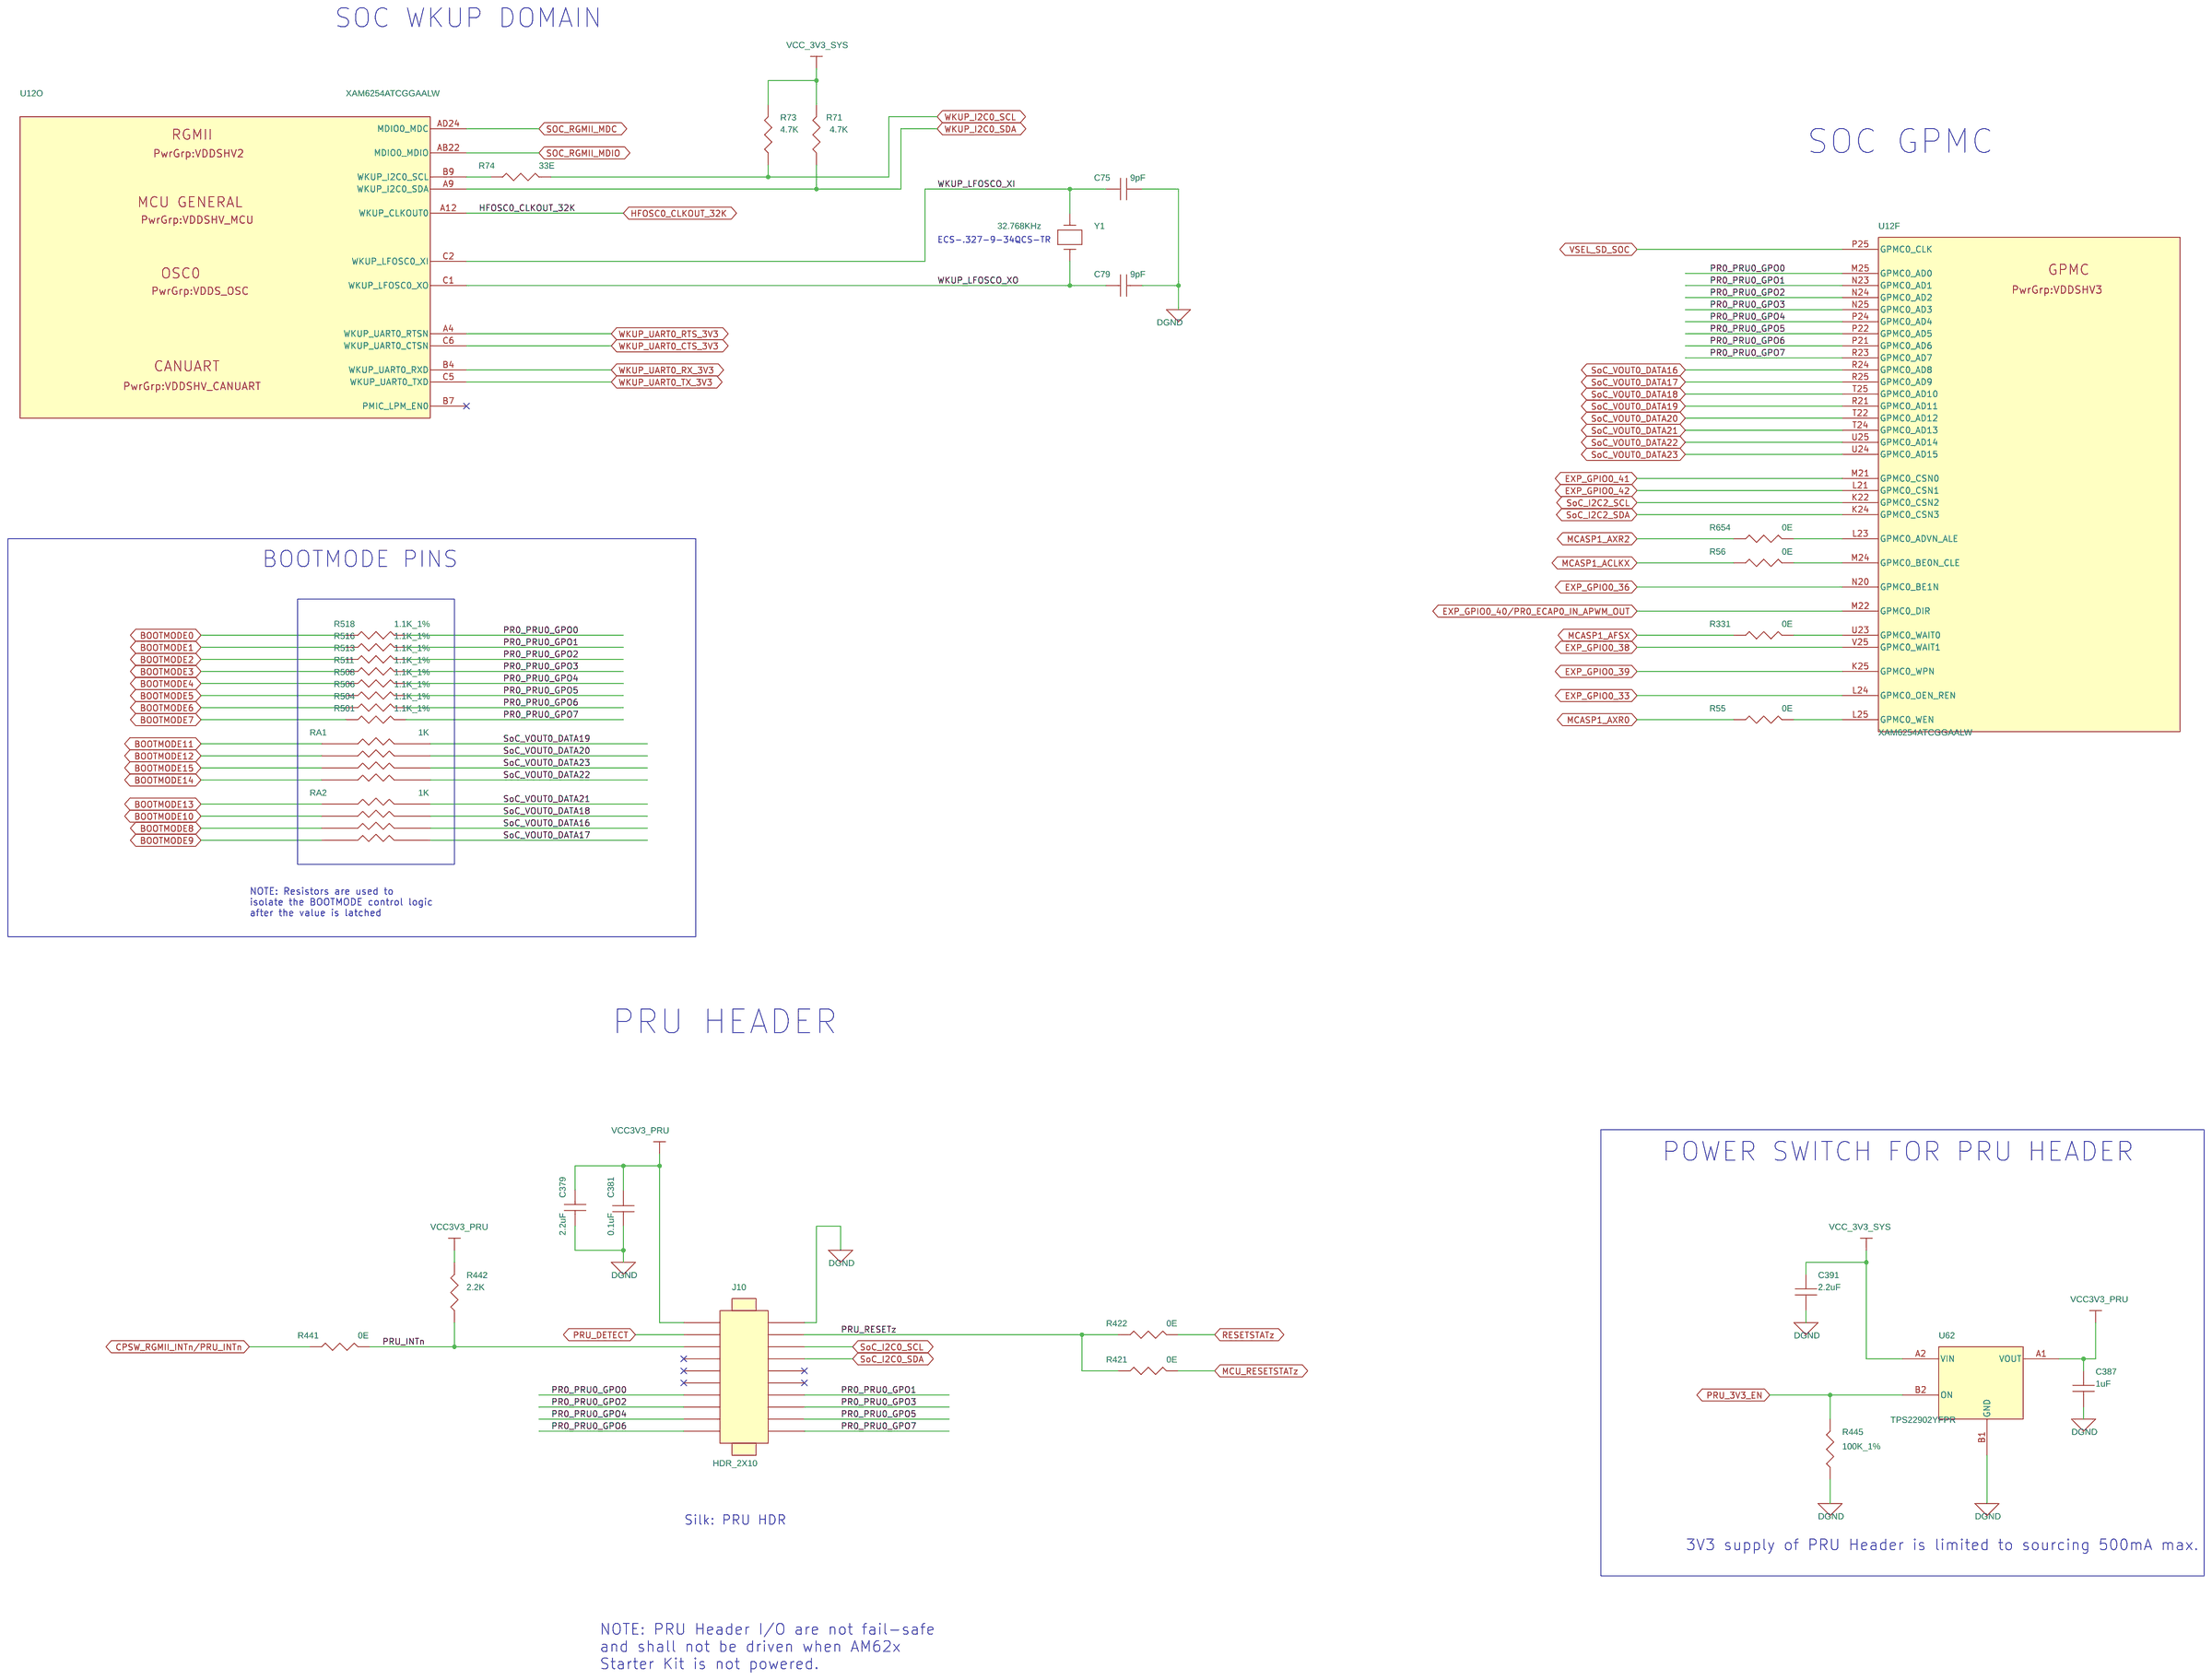
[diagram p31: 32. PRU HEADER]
33 33. USER EXPANSION CONNECTOR: size C; title: USER EXPANSION CONNECTOR
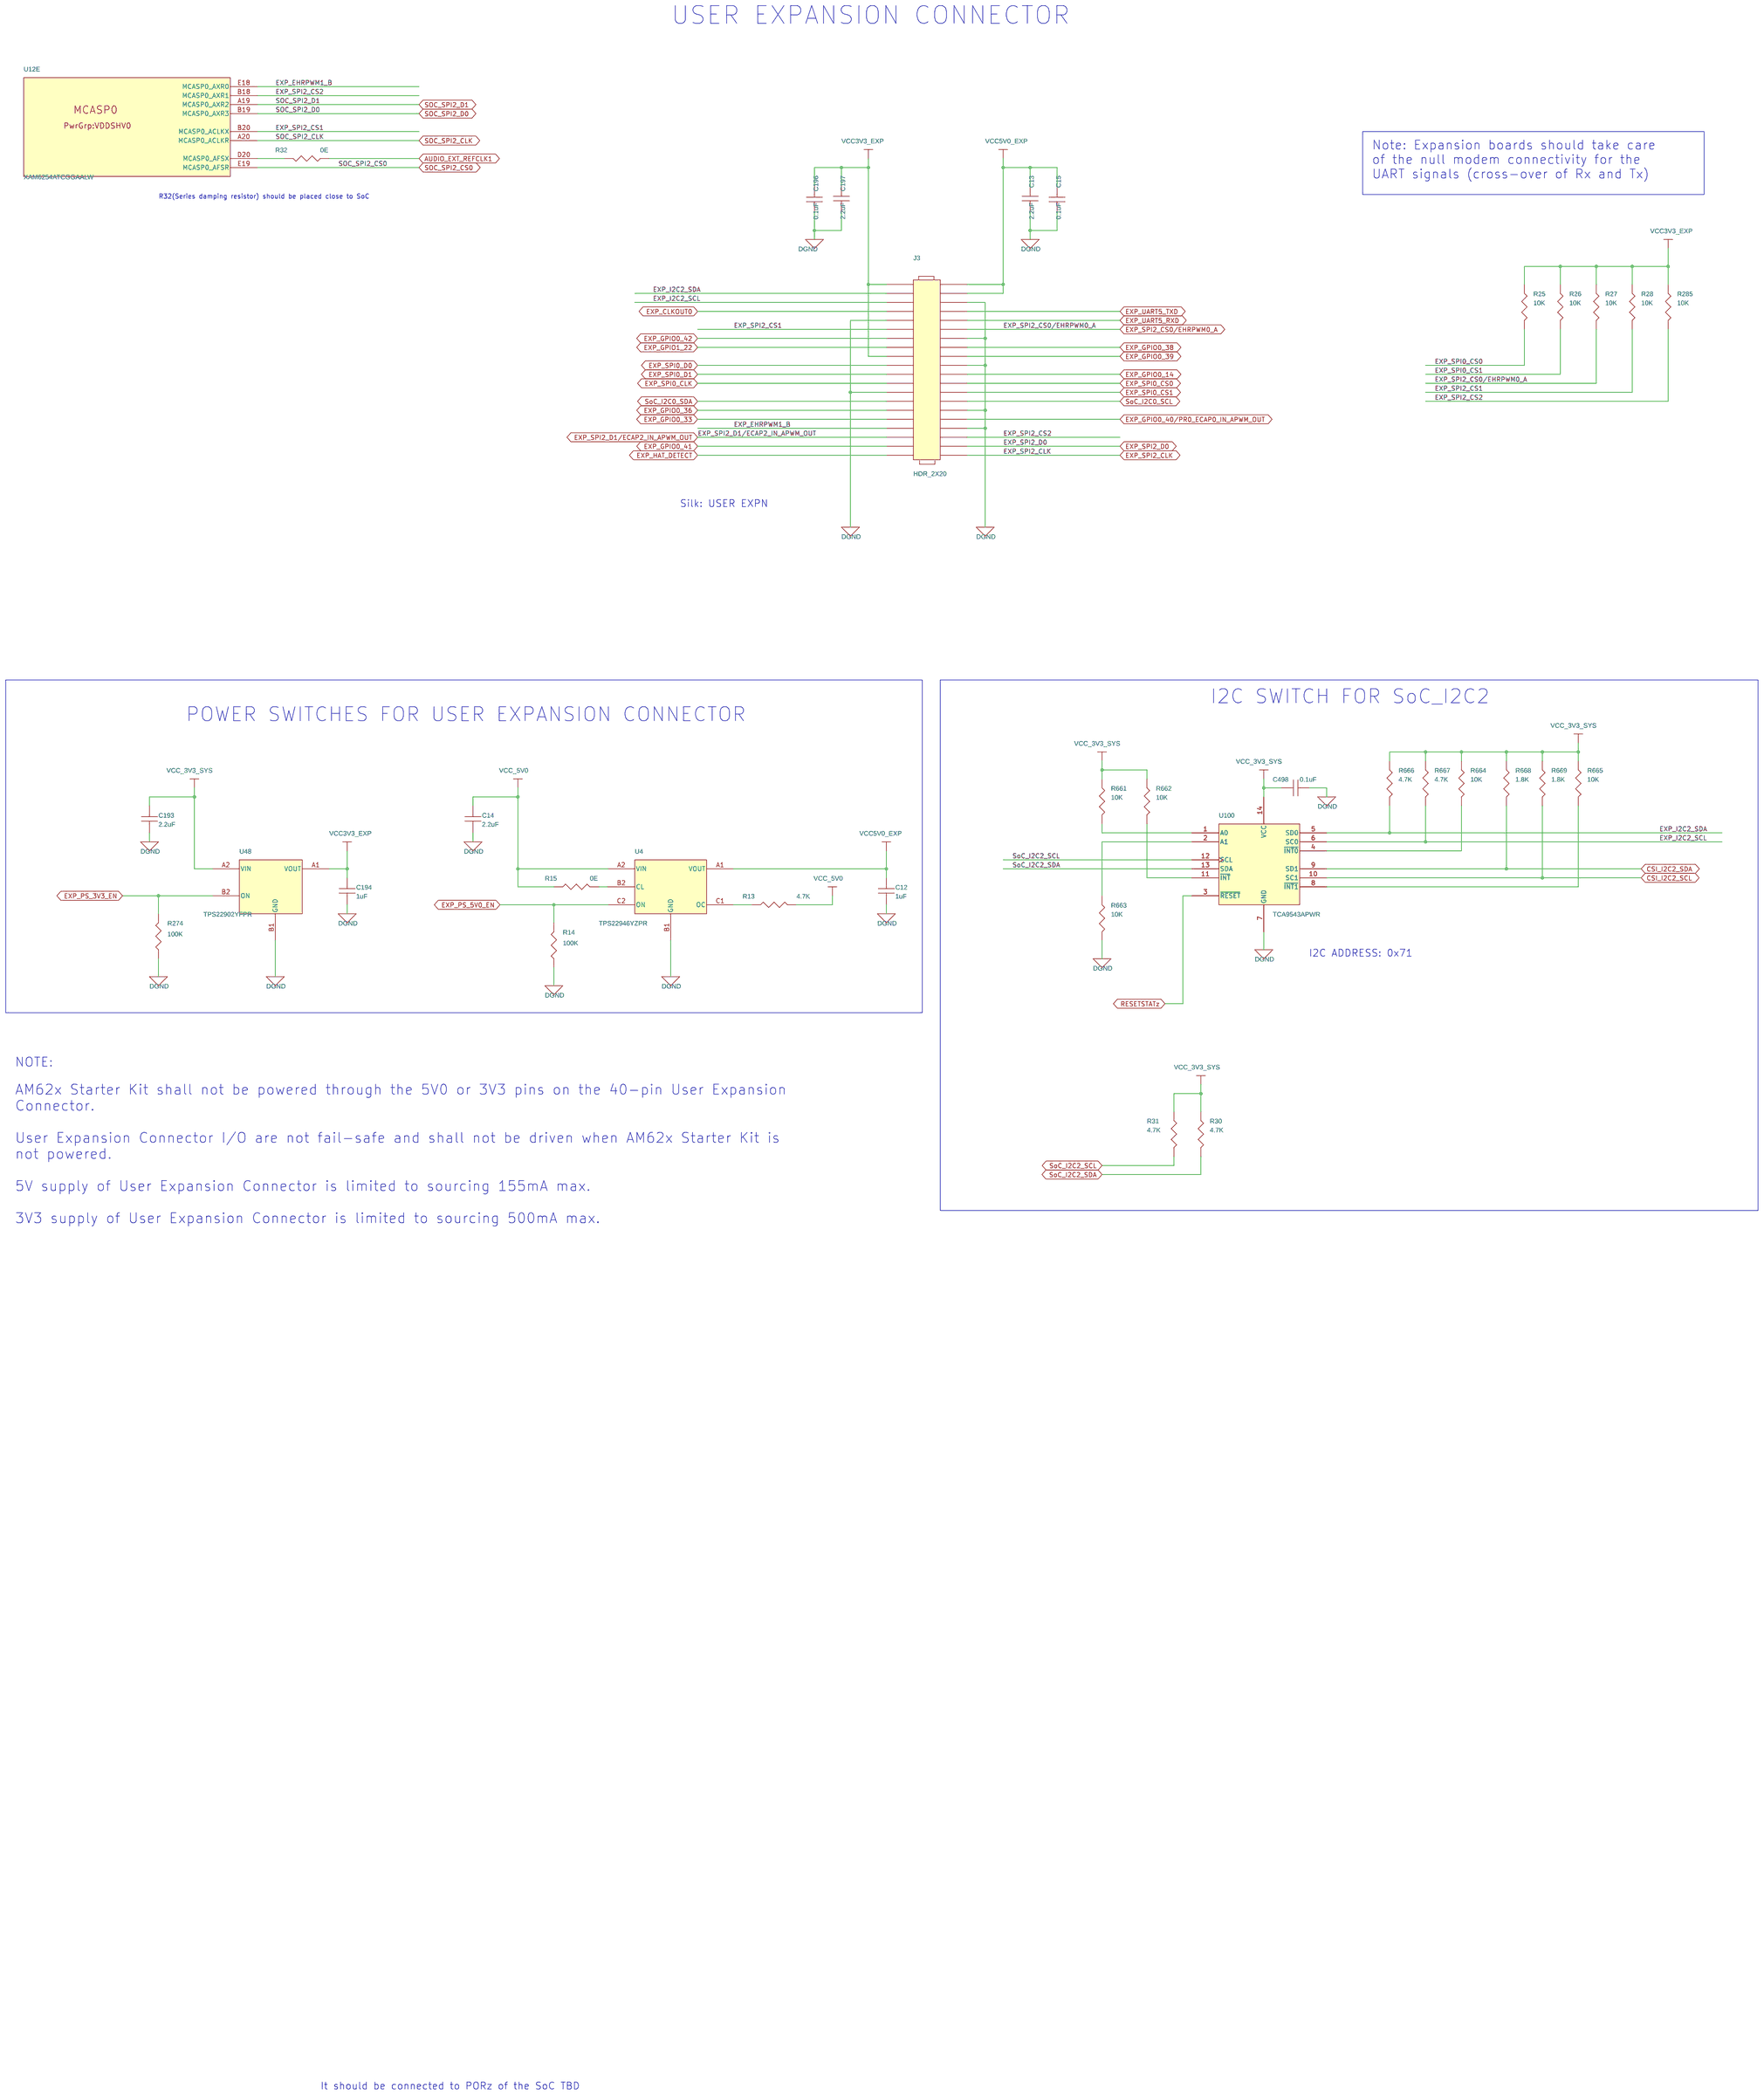
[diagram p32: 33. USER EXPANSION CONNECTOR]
34 34. MCU HEADER: size C; title: MCU HEADER

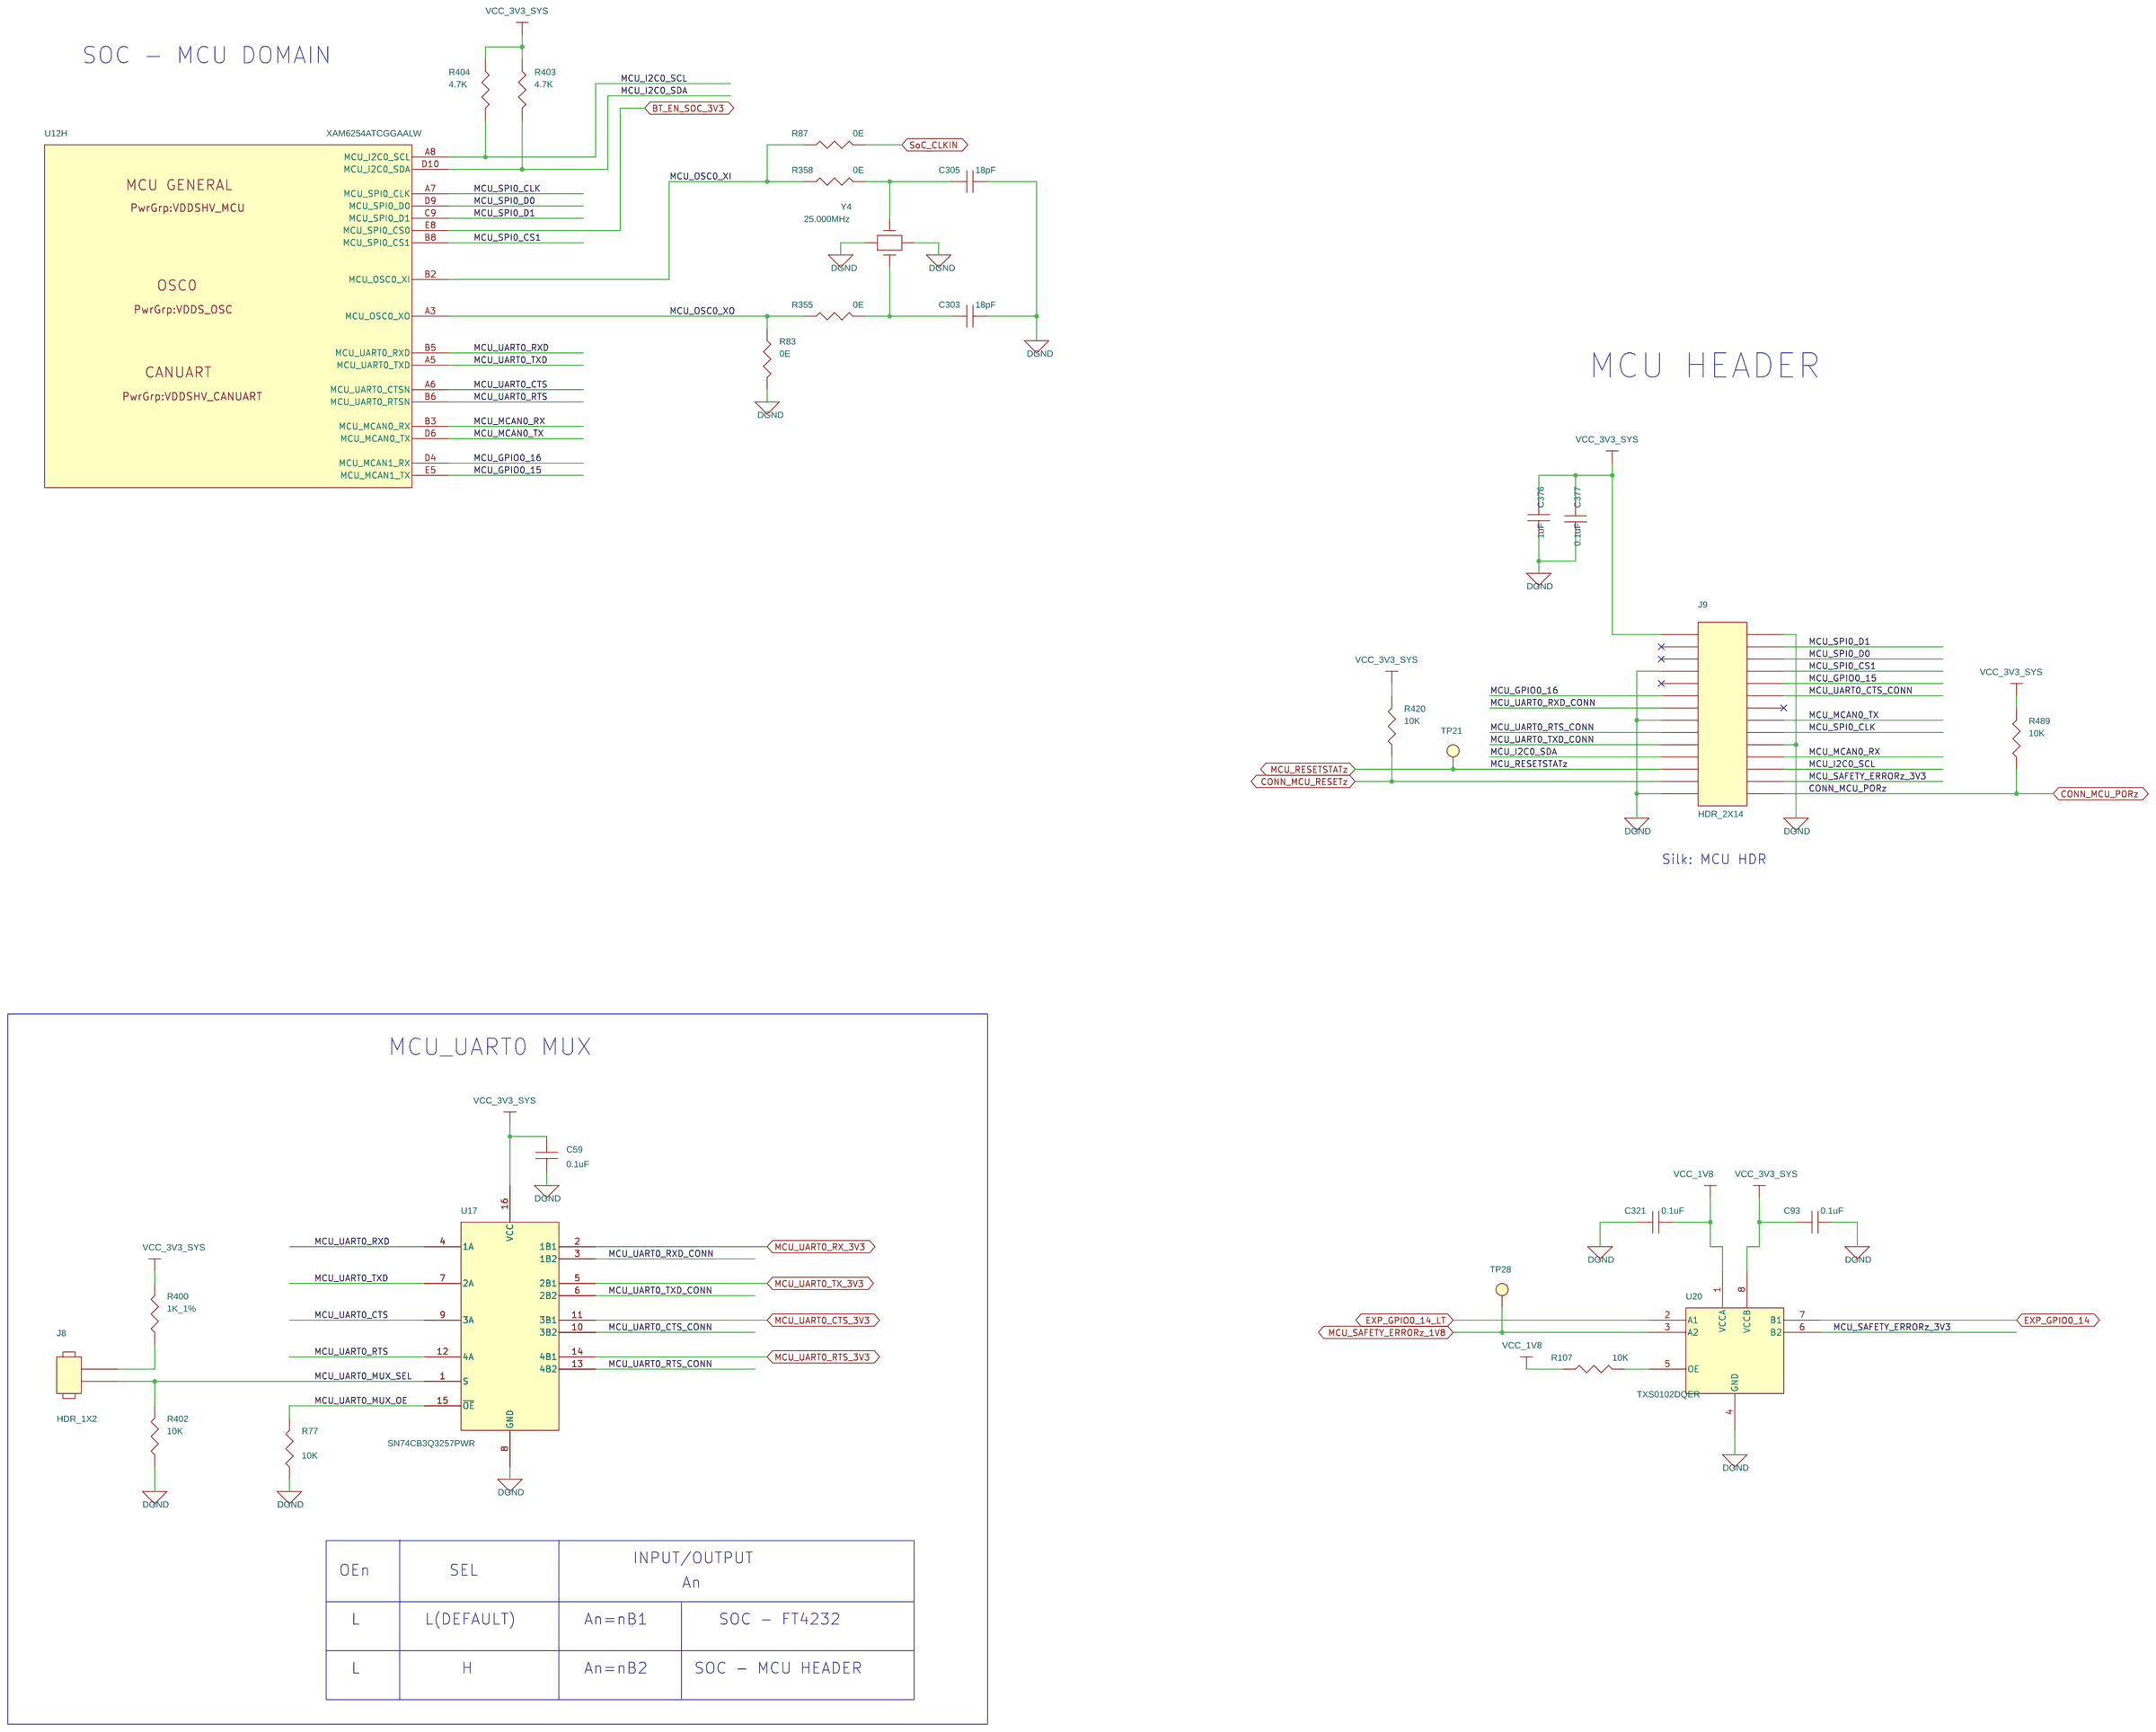
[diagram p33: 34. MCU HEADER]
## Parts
sheet 29. JTAG BUFFER
U12  XAM6254ATCGGAALW  [BGA425_19-68_510X510_0-7]  (sections A,B,C,D,E,F,G,H,I,J,K,L,M,N,O,P,Q,R)
sheet 32. PRU HEADER
C75  9pF  [CAP0402_0-75]
C79  9pF  [CAP0402_0-75]
C379  2.2uF  [CAP0402_0-75]
C381  0.1uF  [CAP0201_0-5]
C387  1uF  [CAP0201_0-5]
C391  2.2uF  [CAP0402_0-75]
J10  HDR_2X10  [HDR_2X10_PREC010DAAN_S_T_8-4]
R55  0E  [RES0201_0-5]
R56  0E  [RES0201_0-5]
R71  4.7K  [RES0201_0-5]
R73  4.7K  [RES0201_0-5]
R74  33E  [RES0201_0-5]
R331  0E  [RES0201_0-5]
R421  0E  [RES0402_0-5]
R422  0E  [RES0201_0-5]
R441  0E  [RES0201_0-5]
R442  2.2K  [RES0201_0-5]
R445  100K_1%  [RES0402_0-5]
R501  1.1K_1%  [RES0201_0-5]
R504  1.1K_1%  [RES0201_0-5]
R506  1.1K_1%  [RES0201_0-5]
R508  1.1K_1%  [RES0201_0-5]
R511  1.1K_1%  [RES0201_0-5]
R513  1.1K_1%  [RES0201_0-5]
R516  1.1K_1%  [RES0201_0-5]
R518  1.1K_1%  [RES0201_0-5]
R654  0E  [RES0201_0-5]
RA1  1K  [RESA_EXB_0201-4_0-5]
RA2  1K  [RESA_EXB_0201-4_0-5]
U62  TPS22902YFPR  [DSBGA4_15-74_30X30_0-5]
Y1  32.768KHz  [XTAL_ECS-32_130X60_SMD_0-9]
sheet 33. USER EXPANSION CONNECTOR
C12  1uF  [CAP0201_0-5]
C13  2.2uF  [CAP0402_0-75]
C14  2.2uF  [CAP0402_0-75]
C15  0.1uF  [CAP0402_0-75]
C193  2.2uF  [CAP0402_0-75]
C194  1uF  [CAP0201_0-5]
C196  0.1uF  [CAP0402_0-75]
C197  2.2uF  [CAP0402_0-75]
C498  0.1uF  [CAP0402_0-75]
J3  HDR_2X20  [HDR_2X20_PEC20DAAN_S_T_8-6]
R13  4.7K  [RES0201_0-5]
R14  100K  [RES0201_0-5]
R15  0E  [RES0201_0-5]
R25  10K  [RES0201_0-5]
R26  10K  [RES0201_0-5]
R27  10K  [RES0201_0-5]
R28  10K  [RES0201_0-5]
R30  4.7K  [RES0201_0-5]
R31  4.7K  [RES0201_0-5]
R32  0E  [RES0201_0-5]
R274  100K  [RES0201_0-5]
R285  10K  [RES0201_0-5]
R661  10K  [RES0201_0-5]
R662  10K  [RES0201_0-5]
R663  10K  [RES0201_0-5]
R664  10K  [RES0201_0-5]
R665  10K  [RES0201_0-5]
R666  4.7K  [RES0201_0-5]
R667  4.7K  [RES0201_0-5]
R668  1.8K  [RES0201_0-5]
R669  1.8K  [RES0201_0-5]
U4  TPS22946YZPR  [DSBGA6_19-68_40X60_0-5]
U48  TPS22902YFPR  [DSBGA4_15-74_30X30_0-5]
U100  TCA9543APWR  [TSSOP14_25-59_205X180_1-2]
sheet 34. MCU HEADER
C59  0.1uF  [CAP0402_0-75]
C93  0.1uF  [CAP0201_0-5]
C303  18pF  [CAP0402_0-75]
C305  18pF  [CAP0402_0-75]
C321  0.1uF  [CAP0201_0-5]
C376  1uF  [CAP0201_0-5]
C377  0.1uF  [CAP0402_0-75]
J8  HDR_1X2  [HDR_1X2_90120-0122_S_T_5-6]
J9  HDR_2X14  [HDR_14X2_100_S_T]
R77  10K  [RES0201_0-5]
R83  0E  [RES0201_0-5]
R87  0E  [RES0201_0-5]
R107  10K  [RES0201_0-5]
R355  0E  [RES0402_0-5]
R358  0E  [RES0402_0-5]
R400  1K_1%  [RES0402_0-5]
R402  10K  [RES0201_0-5]
R403  4.7K  [RES0201_0-5]
R404  4.7K  [RES0201_0-5]
R420  10K  [RES0201_0-5]
R489  10K  [RES0201_0-5]
TP21  TP20_SMD  [TP20_SMD]
TP28  TP20_SMD  [TP20_SMD]
U17  SN74CB3Q3257PWR  [TSSOP16_25-59_205X180]
U20  TXS0102DQER  [X2SON8_TXS0102_40X60_0-4]
Y4  25.000MHz  [XTAL4_XRCGB-FM_80X60_SMD_0-7]

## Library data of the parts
U12 = AM62-EVM_BGA425: IC AM62 SoC MICROPROCESSOR BGA425; Chkd/date: ALVY/110621; Crtd /date: MANIRAJA/110621; Custom_Duty: 15%; Customs_HS_Code: 85423100; Distributor_name: NA; Distributor_part_number: NA; Footprint Path: Y:\MIS_DATABASE\Library\ALTIUM_TOOL\PCB_FOOTPRINTS\Altium_Footprint_Lib.PcbLib; Height: 0.65MM; Library Path: Y:\MIS_DATABASE\Library\ALTIUM_TOOL\SCHEMATICS_PARTS\MS_MICROPROCESSOR_Library.schlib; Mfr_name: TEXAS INSTRUMENTS; Mistral Part No: 141221060001; Package: BGA425; Part_type: ICS\DIGITAL\MICROPROCESSOR; Project: AM62_EVM_BRD; RoHS: NA; Temperature: NA; Tolerance: NA; Voltage: NA; Wattage: NA; Weight: NA; Datasheet: Y:\MIS_DATABASE\DATASHEETS\ICS\DIGITAL\MICROCONTROLLER\AM62-SoC_SVB.PDF
C75 C79 = CAP: CAP CERAMIC 9pF 50V 0.5pF HI-Q C0G(NP0) 0402; Chkd/date: MANIRAJA/160921; Crtd /date: ALVY/150921; Custom_Duty: 15%; Customs_HS_Code: 85322990; Distributor_name: DIGIKEY; Distributor_part_number: 490-14793-1-ND; Footprint Path: Y:\MIS_DATABASE\Library\ALTIUM_TOOL\PCB_FOOTPRINTS\Altium_Footprint_Lib.PcbLib; Height: 0.55MM; Library Path: Y:\MIS_DATABASE\Library\ALTIUM_TOOL\SCHEMATICS_PARTS\MS_DISCRETE_Library.schlib; Mfr_name: MURATA; Mfr_part_number: GJM1555C1H9R0DB01D; Mistral Part No: 120021090005-R; Package: 0402; Part_type: CAPACITORS\CERAMIC; Project: TI_AM62x SKEVM_BRD; RoHS: RoHS; Temperature: -55°C+125°C; Tolerance: 0.5pF%; Voltage: 50V; Wattage: NA; Weight: 1.5mg; Datasheet: Y:\MIS_DATABASE\DATASHEETS\CAPACITORS\GJM1555C1H9R0DB01.PDF
C13 C14 C193 C197 C379 C391 = CAP: CAP CERAMIC 2.2uF 25V 10% X5R 0402; Chkd/date: ALVY/010721; Crtd /date: MANIRAJA/010721; Custom_Duty: 15%; Customs_HS_Code: 85322990; Distributor_name: DIGIKEY; Distributor_part_number: 490-12703-1-ND; Footprint Path: Y:\MIS_DATABASE\Library\ALTIUM_TOOL\PCB_FOOTPRINTS\Altium_Footprint_Lib.PcbLib; Height: 0.70MM; Library Path: Y:\MIS_DATABASE\Library\ALTIUM_TOOL\SCHEMATICS_PARTS\MS_DISCRETE_Library.schlib; Mfr_name: MURATA; Mfr_part_number: GRM155R61E225KE11D; Mistral Part No: 120015120001-R; Package: 0402; Part_type: CAPACITORS\CERAMIC; Project: TI_AM263X_CC; RoHS: RoHS; Temperature: -55°C+85°C; Tolerance: 10%; Voltage: 25V; Wattage: NA; Weight: 1.5mg; Datasheet: Y:\MIS_DATABASE\DATASHEETS\CAPACITORS\GRM155R61E225KE11.PDF
C93 C321 C381 = CAP: CAP CERAMIC 0.1uF 16V 10% X5R 0201; Alt_Mfr_name: YAGEO AMERICA; Alt_Mfr_part_number: CC0402KRX5R8BB104; Chkd/date: MANIRAJA/230118; Crtd /date: MANIRAJA/230118; Custom_Duty: 15%; Customs_HS_Code: 85322990; Distributor_name: DIGIKEY; Distributor_part_number: 490-14305-1-ND; Footprint Path: Y:\MIS_DATABASE\Library\ALTIUM_TOOL\PCB_FOOTPRINTS\Altium_Footprint_Lib.PcbLib; Height: 0.33MM; Library Path: Y:\MIS_DATABASE\Library\ALTIUM_TOOL\SCHEMATICS_PARTS\MS_DISCRETE_Library.schlib; Mfr_name: MURATA; Mfr_part_number: GRM033R61C104KE14D; Mistral Part No: 120009030072-R; Package: 0201; Part_type: CAPACITORS\CERAMIC; Project: TI_MAXIE_CPB; RoHS: RoHS; Temperature: -55°C+85°C; Tolerance: 10%; Voltage: 16V; Wattage: NA; Weight: 0.33mg; Datasheet: Y:\MIS_DATABASE\DATASHEETS\CAPACITORS\GRM033R61C104KE14.PDF
C12 C194 C376 C387 = CAP: CAP CERAMIC 1uF 16V 20% X5R 0201; Chkd/date: MANIRAJA/300520; Crtd /date: ALVY/260520; Custom_Duty: 15%; Customs_HS_Code: 85322990; Distributor_name: DIGIKEY; Distributor_part_number: 490-18654-1-ND; Footprint Path: Y:\MIS_DATABASE\Library\ALTIUM_TOOL\PCB_FOOTPRINTS\Altium_Footprint_Lib.PcbLib; Height: 0.39MM; Library Path: Y:\MIS_DATABASE\Library\ALTIUM_TOOL\SCHEMATICS_PARTS\MS_DISCRETE_Library.schlib; Mfr_name: MURATA; Mfr_part_number: GRM033R61C105ME15D; Mistral Part No: 120018090038-R; Package: 0201; Part_type: CAPACITORS\CERAMIC; Project: QCS610_NANOSOM; RoHS: RoHS; Temperature: -55°C+85°C; Tolerance: 20%; Voltage: 16V; Wattage: NA; Weight: 0.33mg; Datasheet: Y:\MIS_DATABASE\DATASHEETS\CAPACITORS\GRM033R61C105ME15.PDF
J10 = HEADER_10X2: CON HDR 2X10 2.54MM PITCH ST TH; Chkd/date: MANIRAJA/270721; Crtd /date: ALVY/260721; Custom_Duty: 24%; Customs_HS_Code: 85369090; Distributor_name: DIGIKEY; Distributor_part_number: S2012EC-10-ND; Footprint Path: Y:\MIS_DATABASE\Library\ALTIUM_TOOL\PCB_FOOTPRINTS\Altium_Footprint_Lib.PcbLib; Height: 8.34MM; Library Path: Y:\MIS_DATABASE\Library\ALTIUM_TOOL\SCHEMATICS_PARTS\MS_CONNECTOR_Library.schlib; Mfr_name: SULLINS CONNECTOR; Mfr_part_number: PREC010DAAN-RC; Mistral Part No: 150021070022-R; Package: THRU-HOLE; Part_type: CONNECTOR\HEADERS; Project: TI_AM335x SK_BRD; RoHS: RoHS; Temperature: -40°C+105°C; Tolerance: NA; Voltage: NA; Wattage: NA; Weight: NA; Datasheet: Y:\MIS_DATABASE\DATASHEETS\CONNECTORS\PRPCXXDXXN-SER.PDF
R55 R331 R654 = RESISTOR: RES 0E 1/20W 5% 0201; Chkd/date: NAVEED/301214; Crtd /date: MUDDU/120710; Custom_Duty: 15%; Customs_HS_Code: 85332119; Distributor_name: DIGIKEY; Distributor_part_number: 311-0.0NCT-ND; Footprint Path: Y:\MIS_DATABASE\Library\ALTIUM_TOOL\PCB_FOOTPRINTS\Altium_Footprint_Lib.PcbLib; Height: 0.26MM; Library Path: Y:\MIS_DATABASE\Library\ALTIUM_TOOL\SCHEMATICS_PARTS\MS_DISCRETE_Library.schlib; Mfr_name: YAGEO AMERICA; Mfr_part_number: RC0201JR-070RL; Mistral Part No: 110010070067-R; Package: 0201; Part_type: RESISTORS\FIXED; Project: PB_BUGBASE; RoHS: RoHS; SIGNAL_MODEL: RESISTOR_RES0201_0-5_0E_0E; Temperature: -55°C+125°C; Tolerance: 5%; Voltage: NA; Wattage: 1/20W; Weight: 0.17mg; Datasheet: Y:\MIS_DATABASE\DATASHEETS\RESISTORS\RCXXXXL-SER_MAR18.PDF
R15 R32 R56 R83 R87 R422 R441 = RESISTOR: RES 0E 1/20W 5% 0201; Chkd/date: NAVEED/301214; Crtd /date: MUDDU/120710; Custom_Duty: 15%; Customs_HS_Code: 85332119; Distributor_name: DIGIKEY; Distributor_part_number: 311-0.0NCT-ND; Footprint Path: Y:\MIS_DATABASE\Library\ALTIUM_TOOL\PCB_FOOTPRINTS\Altium_Footprint_Lib.PcbLib; Height: 0.26MM; Library Path: Y:\MIS_DATABASE\Library\ALTIUM_TOOL\SCHEMATICS_PARTS\MS_DISCRETE_Library.schlib; Mfr_name: YAGEO AMERICA; Mfr_part_number: RC0201JR-070RL; Mistral Part No: 110010070067-R; Package: 0201; Part_type: RESISTORS\FIXED; Project: PB_BUGBASE; RoHS: RoHS; Temperature: -55°C+125°C; Tolerance: 5%; Voltage: NA; Wattage: 1/20W; Weight: 0.17mg; Datasheet: Y:\MIS_DATABASE\DATASHEETS\RESISTORS\RCXXXXL-SER_MAR18.PDF
R13 R30 R31 R71 R73 R403 R404 R666 R667 = RESISTOR: RES 4.7K 1/20W 5% 0201; Chkd/date: MANIRAJA/200921; Crtd /date: ALVY/200921; Custom_Duty: 15%; Customs_HS_Code: 85332119; Distributor_name: DIGIKEY; Distributor_part_number: 311-4.7KNCT-ND; Footprint Path: Y:\MIS_DATABASE\Library\ALTIUM_TOOL\PCB_FOOTPRINTS\Altium_Footprint_Lib.PcbLib; Height: 0.26MM; Library Path: Y:\MIS_DATABASE\Library\ALTIUM_TOOL\SCHEMATICS_PARTS\MS_DISCRETE_Library.schlib; Mfr_name: YAGEO AMERICA; Mfr_part_number: RC0201JR-074K7L; Mistral Part No: 110021090007-R; Package: 0201; Part_type: RESISTORS\FIXED; Project: TI_AM62x SKEVM_BRD; RoHS: RoHS; Temperature: -55°C+125°C; Tolerance: 5%; Voltage: NA; Wattage: 1/20W; Weight: 0.17mg; Datasheet: Y:\MIS_DATABASE\DATASHEETS\RESISTORS\RCXXXXL-SER_MAR18.PDF
R74 = RESISTOR: RES 33E 1/20W 5% 0201; Chkd/date: VASANTHA/061216; Crtd /date: MAZHAR/170505; Custom_Duty: 15%; Customs_HS_Code: 85332119; Distributor_name: DIGIKEY; Distributor_part_number: P33AGCT-ND; Footprint Path: Y:\MIS_DATABASE\Library\ALTIUM_TOOL\PCB_FOOTPRINTS\Altium_Footprint_Lib.PcbLib; Height: 0.26MM; Library Path: Y:\MIS_DATABASE\Library\ALTIUM_TOOL\SCHEMATICS_PARTS\MS_DISCRETE_Library.schlib; Mfr_name: PANASONIC-ECG; Mfr_part_number: ERJ-1GEJ330C; Mistral Part No: 110010070052-R; Package: 0201; Part_type: RESISTORS\FIXED; Project: G4SLIM; RoHS: RoHS; Temperature: -55°C+125°C; Tolerance: 5%; Voltage: NA; Wattage: 1/20W; Weight: 0.15mg; Datasheet: Y:\MIS_DATABASE\DATASHEETS\RESISTORS\PAN-ERJXGE-FEB06.PDF
R355 R358 R421 = RESISTOR: RES 0E 1/16W JUMPER 0402; Chkd/date: VASANTHA/201216; Crtd /date: MUDDU/190810; Custom_Duty: 15%; Customs_HS_Code: 85332119; Distributor_name: DIGIKEY; Distributor_part_number: 541-0.0JCT-ND; Footprint Path: Y:\MIS_DATABASE\Library\ALTIUM_TOOL\PCB_FOOTPRINTS\Altium_Footprint_Lib.PcbLib; Height: 0.40MM; Library Path: Y:\MIS_DATABASE\Library\ALTIUM_TOOL\SCHEMATICS_PARTS\MS_DISCRETE_Library.schlib; Mfr_name: VISHAY; Mfr_part_number: CRCW04020000Z0ED; Mistral Part No: 110010080019-R; Package: 0402; Part_type: RESISTORS\FIXED; Project: PB_BUGBASE; RoHS: RoHS; Temperature: -55°C+155°C; Tolerance: NA; Voltage: NA; Wattage: 1/16W; Weight: 0.65mg; Datasheet: Y:\MIS_DATABASE\DATASHEETS\RESISTORS\CRCW0603.PDF
R442 = RESISTOR: RES 2.2K 1/20W 5% 0201; Chkd/date: VASANTHA/010117; Crtd /date: MAZHAR/010605; Custom_Duty: 15%; Customs_HS_Code: 85332119; Distributor_name: DIGIKEY; Distributor_part_number: P2.2KAGCT-ND; Footprint Path: Y:\MIS_DATABASE\Library\ALTIUM_TOOL\PCB_FOOTPRINTS\Altium_Footprint_Lib.PcbLib; Height: 0.26MM; Library Path: Y:\MIS_DATABASE\Library\ALTIUM_TOOL\SCHEMATICS_PARTS\MS_DISCRETE_Library.schlib; Mfr_name: PANASONIC-ECG; Mfr_part_number: ERJ-1GEJ222C; Mistral Part No: 110009030427-R; Package: 0201; Part_type: RESISTORS\FIXED; Project: G4SLIM; RoHS: RoHS; Temperature: -55°C+125°C; Tolerance: 5%; Voltage: NA; Wattage: 1/20W; Weight: 0.15mg; Datasheet: Y:\MIS_DATABASE\DATASHEETS\RESISTORS\PAN-ERJXGE-FEB06.PDF
R445 = RESISTOR: RES 100K 1/10W 1% 0402; Chkd/date: VASANTHA/201216; Crtd /date: MAZHAR/130306; Custom_Duty: 15%; Customs_HS_Code: 85332119; Distributor_name: DIGIKEY; Distributor_part_number: P100KLCT-ND; Footprint Path: Y:\MIS_DATABASE\Library\ALTIUM_TOOL\PCB_FOOTPRINTS\Altium_Footprint_Lib.PcbLib; Height: 0.40MM; Library Path: Y:\MIS_DATABASE\Library\ALTIUM_TOOL\SCHEMATICS_PARTS\MS_DISCRETE_Library.schlib; Mfr_name: PANASONIC-ECG; Mfr_part_number: ERJ-2RKF1003X; Mistral Part No: 110009030187-R; Package: 0402; Part_type: RESISTORS\FIXED; Project: J32; RoHS: RoHS; Temperature: -55°C+155°C; Tolerance: 1%; Voltage: NA; Wattage: 1/10W; Weight: 0.8mg; Datasheet: Y:\MIS_DATABASE\DATASHEETS\RESISTORS\PAN-ERJSER_NOV17.PDF
R501 R504 R506 R508 R511 R513 R516 R518 = RESISTOR: RES 1.1K 1/20W 1% 0201; Chkd/date: MAZHAR/121207; Crtd /date: USMAN/121207; Custom_Duty: 15%; Customs_HS_Code: 85332119; Distributor_name: DIGIKEY; Distributor_part_number: P1.10KABCT-ND; Footprint Path: Y:\MIS_DATABASE\Library\ALTIUM_TOOL\PCB_FOOTPRINTS\Altium_Footprint_Lib.PcbLib; Height: 0.26MM; Library Path: Y:\MIS_DATABASE\Library\ALTIUM_TOOL\SCHEMATICS_PARTS\MS_DISCRETE_Library.schlib; Mfr_name: PANASONIC-ECG; Mfr_part_number: ERJ-1GEF1101C; Mistral Part No: 110009030097-R; Package: 0201; Part_type: RESISTORS\FIXED; Project: SD_WATERLOO; RoHS: RoHS; Temperature: -55°C+125°C; Tolerance: 1%; Voltage: NA; Wattage: 1/20W; Weight: 0.15mg; Datasheet: Y:\MIS_DATABASE\DATASHEETS\RESISTORS\PAN-ERJSER_NOV17.PDF
RA1 RA2 = RESARR_ISO4: RES ARRAY 1K 31mW 5% 0201-4; Chkd/date: NAVEED/110515; Crtd /date: VASANTHA/080515; Custom_Duty: 15%; Customs_HS_Code: 85332119; Distributor_name: DIGIKEY; Distributor_part_number: Y6102CT-ND; Footprint Path: Y:\MIS_DATABASE\Library\ALTIUM_TOOL\PCB_FOOTPRINTS\Altium_Footprint_Lib.PcbLib; Height: 0.45MM; Library Path: Y:\MIS_DATABASE\Library\ALTIUM_TOOL\SCHEMATICS_PARTS\MS_DISCRETE_Library.schlib; Manufacturer: PANASONIC-ECG; Mfr_part_number: EXB-18V102JX; Mistral Part No: 110015050003-R; Package: 0201-4; Part_type: RESISTORS\ARRAY; Project: FREE SCALE NANO; RoHS: RoHS; Temperature: -55°C+125°C; Tolerance: 5%; Voltage: NA; Wattage: 31mW; Weight: 1mg; Datasheet: Y:\MIS_DATABASE\DATASHEETS\RESISTORS\EXB-18V.PDF
U48 U62 = TPS22912CYZVR_DSBGA4: IC 3.6V 500mA 78mE ON-RESISTANCE LOAD SWITCH WITH CONTROLLED TURNON DSBGA4; Chkd/date: MANIRAJA/170920; Crtd /date: ALVY/160920; Custom_Duty: 15%; Customs_HS_Code: 85423100; Distributor_name: DIGIKEY; Distributor_part_number: 296-24472-1-ND; Footprint Path: Y:\MIS_DATABASE\Library\ALTIUM_TOOL\PCB_FOOTPRINTS\Altium_Footprint_Lib.PcbLib; Height: 0.50MM; Library Path: Y:\MIS_DATABASE\Library\ALTIUM_TOOL\SCHEMATICS_PARTS\MS_MISCPOWER_Library.schlib; Mfr_name: TEXAS INSTRUMENTS; Mistral Part No: 142020090007-R; Package: DSBGA4; Part_type: ICS\POWER; Project: AM64X_SKEVM; RoHS: RoHS; Temperature: -40°C+85°C; Tolerance: NA; Voltage: NA; Wattage: NA; Weight: 0.7mg; Datasheet: Y:\MIS_DATABASE\DATASHEETS\ICS\POWER\TPS22901-2-3.PDF
Y1 = CRY: CRY 32.768KHz 9pF SMD; Chkd/date: VASANTHA/090419; Crtd /date: ALVY/090419; Custom_Duty: 24%; Customs_HS_Code: 85439000; Distributor_name: DIGIKEY; Distributor_part_number: XC2160CT-ND; Footprint Path: Y:\MIS_DATABASE\Library\ALTIUM_TOOL\PCB_FOOTPRINTS\Altium_Footprint_Lib.PcbLib; Height: 0.90MM; Library Path: Y:\MIS_DATABASE\Library\ALTIUM_TOOL\SCHEMATICS_PARTS\MS_DISCRETE_Library.schlib; Mfr_name: ECS INC; Mfr_part_number: ECS-.327-9-34QCS-TR; Mistral Part No: 130019040003-R; Package: SMD; Part_type: CRYSTAL; Project: J7ES_SOM_DUAL-LEO_PMIC; RoHS: RoHS; Temperature: -40°C+125°C; Tolerance: NA; Voltage: NA; Wattage: NA; Weight: 16mg; Datasheet: Y:\MIS_DATABASE\DATASHEETS\MISC\CRY_OSC\ECS-34Q.PDF
C15 C59 C196 C377 C498 = CAP: CAP CERAMIC 0.1uF 50V 10% X7R 0402; Alt_Mfr_name: YAGEO AMERICA; Alt_Mfr_part_number: CC0402KRX5R8BB104; Chkd/date: MANIRAJA/261020; Crtd /date: ALVY/211020; Custom_Duty: 15%; Customs_HS_Code: 85322990; Distributor_name: DIGIKEY; Distributor_part_number: 490-10700-1-ND; Footprint Path: Y:\MIS_DATABASE\Library\ALTIUM_TOOL\PCB_FOOTPRINTS\Altium_Footprint_Lib.PcbLib; Height: 0.55MM; Library Path: Y:\MIS_DATABASE\Library\ALTIUM_TOOL\SCHEMATICS_PARTS\MS_DISCRETE_Library.schlib; Mfr_name: MURATA; Mfr_part_number: GRM155R71H104KE14D; Mistral Part No: 120011100014-R; Package: 0402; Part_type: CAPACITORS\CERAMIC; Project: J7_CP; RoHS: RoHS; Temperature: -55°C+125°C; Tolerance: 10%; Voltage: 50V; Wattage: NA; Weight: 3.1mg; Datasheet: Y:\MIS_DATABASE\DATASHEETS\CAPACITORS\GRM155R71H104KE14.PDF
J3 = HEADER_20X2: CON HDR 2X20 2.54MM PITCH ST TH; Chkd/date: MANIRAJA/261020; Crtd /date: MANIRAJA/261020; Custom_Duty: 24%; Customs_HS_Code: 85369090; Distributor_name: DIGIKEY; Distributor_part_number: S2012E-20-ND; Footprint Path: Y:\MIS_DATABASE\Library\ALTIUM_TOOL\PCB_FOOTPRINTS\Altium_Footprint_Lib.PcbLib; Height: 8.58MM; Library Path: Y:\MIS_DATABASE\Library\ALTIUM_TOOL\SCHEMATICS_PARTS\MS_CONNECTOR_Library.schlib; Mfr_name: SULLINS CONNECTOR; Mfr_part_number: PEC20DAAN; Mistral Part No: 150020100013-R; Package: THRU-HOLE; Part_type: CONNECTOR\HEADERS; Project: AM64X_SKEVM; RoHS: RoHS; Temperature: -65°C+125°C; Tolerance: NA; Voltage: NA; Wattage: NA; Weight: NA; Datasheet: Y:\MIS_DATABASE\DATASHEETS\CONNECTORS\XXCXXDXXN.PDF
R14 R274 = RESISTOR: RES 100K 1/20W 5% 0201; Chkd/date: VASANTHA/061216; Crtd /date: MAZHAR/141105; Custom_Duty: 15%; Customs_HS_Code: 85332119; Distributor_name: DIGIKEY; Distributor_part_number: P100KAGCT-ND; Footprint Path: Y:\MIS_DATABASE\Library\ALTIUM_TOOL\PCB_FOOTPRINTS\Altium_Footprint_Lib.PcbLib; Height: 0.26MM; Library Path: Y:\MIS_DATABASE\Library\ALTIUM_TOOL\SCHEMATICS_PARTS\MS_DISCRETE_Library.schlib; Mfr_name: PANASONIC-ECG; Mfr_part_number: ERJ-1GEJ104C; Mistral Part No: 110009030176-R; Package: 0201; Part_type: RESISTORS\FIXED; Project: J30; RoHS: RoHS; Temperature: -55°C+125°C; Tolerance: 5%; Voltage: NA; Wattage: 1/20W; Weight: 0.15mg; Datasheet: Y:\MIS_DATABASE\DATASHEETS\RESISTORS\PAN-ERJXGE-FEB06.PDF
R25-R28 R77 R107 R285 R402 R420 R489 R661-R665 = RESISTOR: RES 10K 1/20W 5% 0201; Chkd/date: MANIRAJA/050517; Crtd /date: MANIRAJA/050517; Custom_Duty: 15%; Customs_HS_Code: 85332119; Distributor_name: DIGIKEY; Distributor_part_number: 311-10KNCT-ND; Footprint Path: Y:\MIS_DATABASE\Library\ALTIUM_TOOL\PCB_FOOTPRINTS\Altium_Footprint_Lib.PcbLib; Height: 0.26MM; Library Path: Y:\MIS_DATABASE\Library\ALTIUM_TOOL\SCHEMATICS_PARTS\MS_DISCRETE_Library.schlib; Mfr_name: YAGEO AMERICA; Mfr_part_number: RC0201JR-0710KL; Mistral Part No: 110010070051-R; Package: 0201; Part_type: RESISTORS\FIXED; Project: GOLDEN-I LITE; RoHS: RoHS; Temperature: -55°C+125°C; Tolerance: 5%; Voltage: NA; Wattage: 1/20W; Weight: 0.17mg; Datasheet: Y:\MIS_DATABASE\DATASHEETS\RESISTORS\RCXXXXL-SER_MAR18.PDF
R668 R669 = RESISTOR: RES 1.8K 1/20W 1% 0201; Chkd/date: SHREESHAIL/091205; Crtd /date: MAZHAR/211005; Custom_Duty: 15%; Customs_HS_Code: 85332119; Distributor_name: DIGIKEY; Distributor_part_number: P1.8KABCT-ND; Footprint Path: Y:\MIS_DATABASE\Library\ALTIUM_TOOL\PCB_FOOTPRINTS\Altium_Footprint_Lib.PcbLib; Height: 0.26MM; Library Path: Y:\MIS_DATABASE\Library\ALTIUM_TOOL\SCHEMATICS_PARTS\MS_DISCRETE_Library.schlib; Manufacturer: PANASONIC-ECG; Mfr_name: YAGEO AMERICA; Mfr_part_number: ERJ-1GEF182C; Mistral Part No: 110009030149-R; Package: 0201; Part_type: RESISTORS\FIXED; Project: G4SLIM; RoHS: RoHS; Temperature: -55°C+125°C; Tolerance: 1%; Voltage: NA; Wattage: 1/20W; Weight: 0.15mg; Datasheet: Y:\MIS_DATABASE\DATASHEETS\RESISTORS\PAN-ERJSER_NOV17.PDF
U4 = TPS22946_DSBGA6: IC CURRENT-LIMITED LOAD SWITCH WITH SHUTOFF AUTO-RESTART AND OVERCURRENT CONDITION TIME-OUT DSBGA6; Chkd/date: MANIRAJA/220121; Crtd /date: ALVY/220121; Custom_Duty: 15%; Customs_HS_Code: 85423100; Distributor_name: DIGIKEY; Distributor_part_number: 296-25219-1-ND; Footprint Path: Y:\MIS_DATABASE\Library\ALTIUM_TOOL\PCB_FOOTPRINTS\Altium_Footprint_Lib.PcbLib; Height: 0.50MM; Library Path: Y:\MIS_DATABASE\Library\ALTIUM_TOOL\SCHEMATICS_PARTS\MS_MISCPOWER_Library.schlib; Mfr_name: TEXAS INSTRUMENTS; Mistral Part No: 142021010016-R; Package: DSBGA6; Part_type: ICS\POWER\MANAGEMENT; Project: AM64X_SKEVM; RoHS: RoHS; Temperature: -40°C+85°C; Tolerance: NA; Voltage: NA; Wattage: NA; Weight: 1.7mg; Datasheet: Y:\MIS_DATABASE\DATASHEETS\ICS\POWER\TPS22946.PDF
U100 = TCA9543APWR_TSSOP14: IC 2-CHANNEL I2C BUS SWITCH WITH INTERRUPT LOGIC AND RESET TSSOP14; Chkd/date: VASANTHA/060516; Crtd /date: VASANTHA/070316; Custom_Duty: 15%; Customs_HS_Code: 85423100; Distributor_name: DIGIKEY; Distributor_part_number: 296-42157-1-ND; Footprint Path: Y:\MIS_DATABASE\Library\ALTIUM_TOOL\PCB_FOOTPRINTS\Altium_Footprint_Lib.PcbLib; Height: 1.20MM; Library Path: Y:\MIS_DATABASE\Library\ALTIUM_TOOL\SCHEMATICS_PARTS\MS_BUSDRIVERTRANSCEIVER_Library.schlib; Manufacturer: TEXAS INSTRUMENTS; Mistral Part No: 141016030006-R; Package: TSSOP14; Part_type: ICS\DIGITAL\BUSTRANSCEIVER; Project: OCTASIC_3600; RoHS: RoHS; Temperature: -40°C+85°C; Tolerance: NA; Voltage: NA; Wattage: NA; Weight: NA; Datasheet: Y:\MIS_DATABASE\DATASHEETS\ICS\DIGITAL\BUSTRANSCEIVER\TCA9543A.PDF
C303 C305 = CAP: CAP CERAMIC 18pF 50V 5% HI-Q C0G(NP0) 0402; Chkd/date: VASANTHA/030315; Crtd /date: NAVEED/271014; Custom_Duty: 15%; Customs_HS_Code: 85322990; Distributor_name: DIGIKEY; Distributor_part_number: 490-3119-1-ND; Footprint Path: Y:\MIS_DATABASE\Library\ALTIUM_TOOL\PCB_FOOTPRINTS\Altium_Footprint_Lib.PcbLib; Height: 0.55MM; Library Path: Y:\MIS_DATABASE\Library\ALTIUM_TOOL\SCHEMATICS_PARTS\MS_DISCRETE_Library.schlib; Mfr_name: MURATA; Mfr_part_number: GJM1555C1H180JB01D; Mistral Part No: 120014100019-R; Package: 0402; Part_type: CAPACITORS\CERAMIC; Project: DC_MIST_RDC; RoHS: RoHS; Temperature: -55°C+125°C; Tolerance: 5%; Voltage: 50V; Wattage: NA; Weight: 6mg; Datasheet: Y:\MIS_DATABASE\DATASHEETS\CAPACITORS\MURATA-GXX-SER_NOV17.PDF
J8 = HEADER_2X1: CON HDR 1X2 2.54MM PITCH ST TH; Chkd/date: NAVEED/210714; Crtd /date: USMAN/031012; Custom_Duty: 24%; Customs_HS_Code: 85369090; Distributor_name: DIGIKEY; Distributor_part_number: WM8072-ND; Footprint Path: Y:\MIS_DATABASE\Library\ALTIUM_TOOL\PCB_FOOTPRINTS\Altium_Footprint_Lib.PcbLib; Height: 5.60MM; Library Path: Y:\MIS_DATABASE\Library\ALTIUM_TOOL\SCHEMATICS_PARTS\MS_CONNECTOR_Library.schlib; Mfr_name: MOLEX; Mfr_part_number: 90120-0122; Mistral Part No: 150012100005-R; Package: THRU-HOLE; Part_type: CONNECTOR\HEADERS; Project: NPOL_FEP; RoHS: RoHS; Temperature: -55°C+125°C; Tolerance: NA; Voltage: NA; Wattage: NA; Weight: 122mg; Datasheet: Y:\MIS_DATABASE\DATASHEETS\CONNECTORS\90120-XX.PDF
J9 = HEADER_14x2: CON HDR 2X14 2.54MM PITCH ST TH; Chkd/date: NAVEED/280515; Crtd /date: VASANTHA/111114; Custom_Duty: 0.24; Customs_HS_Code: 85369090; Distributor_name: DIGIKEY; Distributor_part_number: S2012EC-14-ND; Height: 8.34MM; Mfr_name: SULLINS; Mfr_part_number: PREC014DAAN-RC; Mistral Part No: 150014110005-R; Package: THRU-HOLE; Part_type: CONNECTOR\HEADERS; Project: GALILEO_EVM; RoHS: RoHS; Temperature: -40°C+105°C; Tolerance: NA; Voltage: NA; Wattage: NA; Weight: NA; Datasheet: Y:\MIS_DATABASE\DATASHEETS\CONNECTORS\PRXXXN-RC.PDF
R400 = RESISTOR: RES 1K 1/10W 1% 0402; Chkd/date: VASANTHA/281216; Crtd /date: MAZHAR/150506; Custom_Duty: 15%; Customs_HS_Code: 85332119; Distributor_name: DIGIKEY; Distributor_part_number: P1.00KLCT-ND; Footprint Path: Y:\MIS_DATABASE\Library\ALTIUM_TOOL\PCB_FOOTPRINTS\Altium_Footprint_Lib.PcbLib; Height: 0.40MM; Library Path: Y:\MIS_DATABASE\Library\ALTIUM_TOOL\SCHEMATICS_PARTS\MS_DISCRETE_Library.schlib; Mfr_name: PANASONIC-ECG; Mfr_part_number: ERJ-2RKF1001X; Mistral Part No: 110009030411-R; Package: 0402; Part_type: RESISTORS\FIXED; Project: VOCERA; RoHS: RoHS; Temperature: -55°C+155°C; Tolerance: 1%; Voltage: NA; Wattage: 1/10W; Weight: 0.8mg; Datasheet: Y:\MIS_DATABASE\DATASHEETS\RESISTORS\PAN-ERJSER_NOV17.PDF
TP21 TP28 = TESTPOINT: TESTPOINT CIR 20 SMD; Chkd/date: SHREESHAIL/171006; Crtd /date: MAZHAR/171006; Custom_Duty: NA; Customs_HS_Code: NA; Distributor_name: NA; Distributor_part_number: NA; Footprint Path: Y:\MIS_DATABASE\Library\ALTIUM_TOOL\PCB_FOOTPRINTS\Altium_Footprint_Lib.PcbLib; Height: NA; Library Path: Y:\MIS_DATABASE\Library\ALTIUM_TOOL\SCHEMATICS_PARTS\MS_DISCRETE_Library.schlib; MECHANICAL 3D STEP FILE: NA; Mfr_name: LOCAL; Mistral Part No: NA; Package: SMD; Project: BT MODULE_CSRBC04; RoHS: NA; Temperature: NA; Tolerance: NA; Voltage: NA; Wattage: NA; Weight: NA; Datasheet: NA
U17 = SN74CB3Q3257PWR_TSSOP16: IC 4BIT 1-OF-2 FET MULTIPLEXER/DEMULTIPLEXER TSSOP16; Chkd/date: SUHAS/251010; Crtd /date: USMAN/060109; Custom_Duty: 15%; Customs_HS_Code: 85423100; Distributor_name: DIGIKEY; Distributor_part_number: 296-19138-1-ND; Height: 1.20MM; Mfr_name: TEXAS INSTRUMENTS; Mistral Part No: 141009030117-R; Package: TSSOP16; Part_type: ICS\DIGITAL\COMBINATIONAL; Project: OMAP_EVM; RoHS: Sb/ Br FREE; Temperature: -40°C+85°C; Datasheet: Y:\MIS_DATABASE\DATASHEETS\ICS\DIGITAL\COMBINATIONAL\SN74CB3Q3257.PDF
U20 = TXS0102DQX_SON8: IC 2-BIT BI-DIR VOLTAGE-LEVEL TRANSLATOR FOR OPEN-DRAIN AND PUSH-PULL X2SON8; Chkd/date: MANIRAJA/010719; Crtd /date: CHAITHANYA230512; Custom_Duty: 15%; Customs_HS_Code: 85423100; Distributor_name: DIGIKEY; Distributor_part_number: 296-28368-1-ND; Footprint Path: Y:\MIS_DATABASE\Library\ALTIUM_TOOL\PCB_FOOTPRINTS\Altium_Footprint_Lib.PcbLib; Height: 0.40MM; Library Path: Y:\MIS_DATABASE\Library\ALTIUM_TOOL\SCHEMATICS_PARTS\MS_MISCINTERFACE_Library.schlib; Mfr_name: TEXAS INSTRUMENTS; Mistral Part No: 141012050010-R; Package: X2SON8; Part_type: ICS\INTERFACE\LEVEL TRANSLATOR; Project: GEN_3-8_DB; RoHS: RoHS; Temperature: -40°C+85°C; Tolerance: NA; Voltage: NA; Wattage: NA; Weight: 1.2mg; Datasheet: Y:\MIS_DATABASE\DATASHEETS\ICS\INTERFACE\TXS0102-SER.PDF
Y4 = CRY4_13: CRY 25.000MHz 6pF SMD; Chkd/date: MANIRAJA/151020; Crtd /date: ALVY/151020; Custom_Duty: 24%; Customs_HS_Code: 85439000; Distributor_name: DIGIKEY; Distributor_part_number: 490-5578-1-ND; Footprint Path: Y:\MIS_DATABASE\Library\ALTIUM_TOOL\PCB_FOOTPRINTS\Altium_Footprint_Lib.PcbLib; Height: 0.70MM; Library Path: Y:\MIS_DATABASE\Library\ALTIUM_TOOL\SCHEMATICS_PARTS\MS_DISCRETE_Library.schlib; Mfr_name: MURATA; Mfr_part_number: XRCGB25M000F3M00R0; Mistral Part No: 130020100043-R; Package: SMD; Part_type: CRYSTAL; Project: AM64X_SKEVM; RoHS: RoHS; Temperature: -30°C+85°C; Tolerance: NA; Voltage: NA; Wattage: NA; Weight: 23mg; Datasheet: Y:\MIS_DATABASE\DATASHEETS\MISC\CRY_OSC\XRCGB.PDF

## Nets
DGND: C12.2 C13.2 C14.2 C15.1 C59.1 C75.2 C79.2 C93.1 C193.2 C194.2 C196.1 C197.2 C303.1 C305.1 C321.2 C376.2 C377.1 C379.2 C381.1 C387.2 C391.2 C498.1 J3.6 J3.9 J3.14 J3.20 J3.25 J3.30 J3.34 J9.2 J9.7 J9.15 J9.20 J9.27 J10.2 R14.1 R77.2 R83.1 R274.1 R402.1 R445.1 R663.2 U4.B1(GND) U17.8(GND) U20.4(GND) U48.B1(GND) U62.B1(GND) U100.7(GND) Y4.2 Y4.4 ; also on sheet 1 10 11 12 13 14 15 16 17 18 19 20 21 22 23 24 25 26 27 28 29 30 31 35 36 37 38 39 40 41 42 43
VCC3V3_EXP: C194.1 C196.2 C197.1 J3.1 J3.17 R25.1 R26.1 R27.1 R28.1 R285.1 U48.A1(VOUT)
VCC3V3_PRU: C379.1 C381.2 C387.1 J10.1 R442.1 U62.A1(VOUT)
VCC5V0_EXP: C12.1 C13.1 C15.2 J3.2 J3.4 U4.A1(VOUT)
VCC_1V8: C321.1 R107.1 U20.1(VCCA) ; also on sheet 12 13 14 18 19 21 25 37 39 40 42
VCC_3V3_SYS: C59.2 C93.2 C193.1 C376.1 C377.2 C391.1 C498.2 J9.1 R30.1 R31.1 R71.1 R73.1 R400.2 R403.1 R404.1 R420.2 R489.2 R661.1 R662.1 R664.1 R665.1 R666.1 R667.1 R668.1 R669.1 U17.16(VCC) U20.8(VCCB) U48.A2(VIN) U62.A2(VIN) U100.14(VCC) ; also on sheet 10 12 13 14 18 19 20 22 23 24 25 26 27 29 30 31 35 36 37 38 39 40 41 42 43
VCC_5V0: C14.1 R13.2 R15.1 U4.A2(VIN) ; also on sheet 10 11 36 41
AUDIO_EXT_REFCLK1: R32.1 ; also on sheet 41
BOOTMODE0: R518.1 ; also on sheet 27
BOOTMODE1: R516.1 ; also on sheet 27
BOOTMODE2: R513.1 ; also on sheet 27
BOOTMODE3: R511.1 ; also on sheet 27
BOOTMODE4: R508.1 ; also on sheet 27
BOOTMODE5: R506.1 ; also on sheet 27
BOOTMODE6: R504.1 ; also on sheet 27
BOOTMODE7: R501.1 ; also on sheet 27
BOOTMODE8: RA2.3 ; also on sheet 27
BOOTMODE9: RA2.4 ; also on sheet 27
BOOTMODE10: RA2.2 ; also on sheet 27
BOOTMODE11: RA1.1 ; also on sheet 27
BOOTMODE12: RA1.2 ; also on sheet 27
BOOTMODE13: RA2.1 ; also on sheet 27
BOOTMODE14: RA1.4 ; also on sheet 27
BOOTMODE15: RA1.3 ; also on sheet 27
BT_EN_SOC_3V3: U12.E8(MCU_SPI0_CS0) ; also on sheet 18
CONN_MCU_PORz: J9.28 R489.1 ; also on sheet 42
CONN_MCU_RESETz: J9.25 R420.1 ; also on sheet 43
CPSW_RGMII_INTn/PRU_INTn: R441.1 ; also on sheet 23 42
CSI_I2C2_SCL: R669.2 U100.10(SC1) ; also on sheet 38
CSI_I2C2_SDA: R668.2 U100.9(SD1) ; also on sheet 38
EXP_CLKOUT0: J3.7 ; also on sheet 42
EXP_EHRPWM1_B: J3.33 U12.E18(MCASP0_AXR0)
EXP_GPIO0_14: J3.22 U20.7(B1)
EXP_GPIO0_14_LT: U20.2(A1) ; also on sheet 21
EXP_GPIO0_33: J3.31 U12.L24(GPMC0_OEN_REN)
EXP_GPIO0_36: J3.29 U12.N20(GPMC0_BE1N)
EXP_GPIO0_38: J3.16 U12.V25(GPMC0_WAIT1)
EXP_GPIO0_39: J3.18 U12.K25(GPMC0_WPN)
EXP_GPIO0_40/PR0_ECAP0_IN_APWM_OUT: J3.32 U12.M22(GPMC0_DIR)
EXP_GPIO0_41: J3.37 U12.M21(GPMC0_CSN0)
EXP_GPIO0_42: J3.13 U12.L21(GPMC0_CSN1)
EXP_GPIO1_22: J3.15 ; also on sheet 42
EXP_HAT_DETECT: J3.39 ; also on sheet 39
EXP_I2C2_SCL: J3.5 R667.2 U100.6(SC0)
EXP_I2C2_SDA: J3.3 R666.2 U100.5(SD0)
EXP_PS_3V3_EN: R274.2 U48.B2(ON) ; also on sheet 39
EXP_PS_5V0_EN: R14.2 U4.C2(ON) ; also on sheet 39
EXP_SPI0_CLK: J3.23 ; also on sheet 42
EXP_SPI0_CS0: J3.24 R25.2 ; also on sheet 42
EXP_SPI0_CS1: J3.26 R26.2 ; also on sheet 42
EXP_SPI0_D0: J3.19 ; also on sheet 42
EXP_SPI0_D1: J3.21 ; also on sheet 42
EXP_SPI2_CLK: J3.40 ; also on sheet 37
EXP_SPI2_CS0/EHRPWM0_A: J3.12 R27.2 ; also on sheet 37
EXP_SPI2_CS1: J3.11 R28.2 U12.B20(MCASP0_ACLKX)
EXP_SPI2_CS2: J3.36 R285.2 U12.B18(MCASP0_AXR1)
EXP_SPI2_D0: J3.38 ; also on sheet 37
EXP_SPI2_D1/ECAP2_IN_APWM_OUT: J3.35 ; also on sheet 37
EXP_UART5_RXD: J3.10 ; also on sheet 42
EXP_UART5_TXD: J3.8 ; also on sheet 42
HFOSC0_CLKOUT_32K: U12.A12(WKUP_CLKOUT0) ; also on sheet 18
MCASP1_ACLKX: R56.1 ; also on sheet 39
MCASP1_AFSX: R331.1 ; also on sheet 39
MCASP1_AXR0: R55.1 ; also on sheet 39
MCASP1_AXR2: R654.1 ; also on sheet 39
MCU_GPIO0_15: J9.10 U12.E5(MCU_MCAN1_TX)
MCU_GPIO0_16: J9.11 U12.D4(MCU_MCAN1_RX)
MCU_I2C0_SCL: J9.24 R404.2 U12.A8(MCU_I2C0_SCL)
MCU_I2C0_SDA: J9.21 R403.2 U12.D10(MCU_I2C0_SDA)
MCU_MCAN0_RX: J9.22 U12.B3(MCU_MCAN0_RX)
MCU_MCAN0_TX: J9.16 U12.D6(MCU_MCAN0_TX)
MCU_OSC0_XI: R87.2 R358.2 U12.B2(MCU_OSC0_XI)
MCU_OSC0_XO: R83.2 R355.2 U12.A3(MCU_OSC0_XO)
MCU_RESETSTATz: J9.23 R421.1 TP21.1(TP) ; also on sheet 42
MCU_SAFETY_ERRORz_1V8: TP28.1(TP) U20.3(A2) ; also on sheet 42
MCU_SAFETY_ERRORz_3V3: J9.26 U20.6(B2)
MCU_SPI0_CLK: J9.18 U12.A7(MCU_SPI0_CLK)
MCU_SPI0_CS1: J9.8 U12.B8(MCU_SPI0_CS1)
MCU_SPI0_D0: J9.6 U12.D9(MCU_SPI0_D0)
MCU_SPI0_D1: J9.4 U12.C9(MCU_SPI0_D1)
MCU_UART0_CTS: U12.A6(MCU_UART0_CTSN) U17.9(3A)
MCU_UART0_CTS_3V3: U17.11(3B1) ; also on sheet 31
MCU_UART0_CTS_CONN: J9.12 U17.10(3B2)
MCU_UART0_MUX_OE: R77.1 U17.15(~{OE})
MCU_UART0_MUX_SEL: J8.2 R402.2 U17.1(S)
MCU_UART0_RTS: U12.B6(MCU_UART0_RTSN) U17.12(4A)
MCU_UART0_RTS_3V3: U17.14(4B1) ; also on sheet 31
MCU_UART0_RTS_CONN: J9.17 U17.13(4B2)
MCU_UART0_RX_3V3: U17.2(1B1) ; also on sheet 31
MCU_UART0_RXD: U12.B5(MCU_UART0_RXD) U17.4(1A)
MCU_UART0_RXD_CONN: J9.13 U17.3(1B2)
MCU_UART0_TX_3V3: U17.5(2B1) ; also on sheet 31
MCU_UART0_TXD: U12.A5(MCU_UART0_TXD) U17.7(2A)
MCU_UART0_TXD_CONN: J9.19 U17.6(2B2)
PR0_PRU0_GPO0: J10.13 R518.2 U12.M25(GPMC0_AD0)
PR0_PRU0_GPO1: J10.14 R516.2 U12.N23(GPMC0_AD1)
PR0_PRU0_GPO2: J10.15 R513.2 U12.N24(GPMC0_AD2)
PR0_PRU0_GPO3: J10.16 R511.2 U12.N25(GPMC0_AD3)
PR0_PRU0_GPO4: J10.17 R508.2 U12.P24(GPMC0_AD4)
PR0_PRU0_GPO5: J10.18 R506.2 U12.P22(GPMC0_AD5)
PR0_PRU0_GPO6: J10.19 R504.2 U12.P21(GPMC0_AD6)
PR0_PRU0_GPO7: J10.20 R501.2 U12.R23(GPMC0_AD7)
PRU_3V3_EN: R445.2 U62.B2(ON) ; also on sheet 39
PRU_DETECT: J10.3 ; also on sheet 39
PRU_INTn: J10.5 R441.2 R442.2
PRU_RESETz: J10.4 R421.2 R422.2
RESETSTATz: R422.1 U100.3(~{RESET}) ; also on sheet 13 19 20 21 23 24 27 37 39 40 41 42
SoC_CLKIN: R87.1 ; also on sheet 25
SoC_I2C0_SCL: J3.28 J10.6 ; also on sheet 10 13 22 37 42
SoC_I2C0_SDA: J3.27 J10.8 ; also on sheet 10 13 22 37 42
SoC_I2C2_SCL: R31.2 U12.K22(GPMC0_CSN2) U100.12(SCL)
SoC_I2C2_SDA: R30.2 U12.K24(GPMC0_CSN3) U100.13(SDA)
SOC_RGMII_MDC: U12.AD24(MDIO0_MDC) ; also on sheet 23 24
SOC_RGMII_MDIO: U12.AB22(MDIO0_MDIO) ; also on sheet 23 24
SOC_SPI2_CLK: U12.A20(MCASP0_ACLKR) ; also on sheet 37
SOC_SPI2_CS0: U12.E19(MCASP0_AFSR) ; also on sheet 37
SOC_SPI2_D0: U12.B19(MCASP0_AXR3) ; also on sheet 37
SOC_SPI2_D1: U12.A19(MCASP0_AXR2) ; also on sheet 37
SoC_VOUT0_DATA16: RA2.6 U12.R24(GPMC0_AD8) ; also on sheet 41
SoC_VOUT0_DATA17: RA2.5 U12.R25(GPMC0_AD9) ; also on sheet 41
SoC_VOUT0_DATA18: RA2.7 U12.T25(GPMC0_AD10) ; also on sheet 41
SoC_VOUT0_DATA19: RA1.8 U12.R21(GPMC0_AD11) ; also on sheet 41
SoC_VOUT0_DATA20: RA1.7 U12.T22(GPMC0_AD12) ; also on sheet 41
SoC_VOUT0_DATA21: RA2.8 U12.T24(GPMC0_AD13) ; also on sheet 41
SoC_VOUT0_DATA22: RA1.5 U12.U25(GPMC0_AD14) ; also on sheet 41
SoC_VOUT0_DATA23: RA1.6 U12.U24(GPMC0_AD15) ; also on sheet 41
VSEL_SD_SOC: U12.P25(GPMC0_CLK) ; also on sheet 13
WKUP_I2C0_SCL: R73.2 R74.2 ; also on sheet 25
WKUP_I2C0_SDA: R71.2 U12.A9(WKUP_I2C0_SDA) ; also on sheet 25
WKUP_LFOSCO_XI: C75.1 U12.C2(WKUP_LFOSC0_XI) Y1.1
WKUP_LFOSCO_XO: C79.1 U12.C1(WKUP_LFOSC0_XO) Y1.2
WKUP_UART0_CTS_3V3: U12.C6(WKUP_UART0_CTSN) ; also on sheet 31
WKUP_UART0_RTS_3V3: U12.A4(WKUP_UART0_RTSN) ; also on sheet 31
WKUP_UART0_RX_3V3: U12.B4(WKUP_UART0_RXD) ; also on sheet 31
WKUP_UART0_TX_3V3: U12.C5(WKUP_UART0_TXD) ; also on sheet 31
N16906426: C305.2 R358.1 Y4.1
N16906432: C303.2 R355.1 Y4.3
N16931396: R15.2 U4.B2(CL)
N16931420: R13.1 U4.C1(OC)
N17395932: R74.1 U12.B9(WKUP_I2C0_SCL)
N17492093: R107.2 U20.5(OE)
N17492111: J8.1 R400.1
N19066697: R56.2 U12.M24(GPMC0_BE0N_CLE)
N19066711: R331.2 U12.U23(GPMC0_WAIT0)
N19066744: R55.2 U12.L25(GPMC0_WEN)
N20055845: R654.2 U12.L23(GPMC0_ADVN_ALE)
N20190775: R32.2 U12.D20(MCASP0_AFSX)
N20275668: R661.2 U100.1(A0)
N20275680: R663.1 U100.2(A1)
N20275684: R662.2 U100.11(~{INT})
N20275795: R664.2 U100.4(~{INT0})
N20275817: R665.2 U100.8(~{INT1})

Not connected (* = marked no-connect by the designer): J9 3* 5* 9* 14*; J10 7* 9* 10* 11* 12*; U12 B7(PMIC_LPM_EN0)*

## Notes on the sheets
sheet 32
- SOC WKUP DOMAIN
- SOC GPMC
- ECS-.327-9-34QCS-TR
- BOOTMODE PINS
- NOTE: Resistors are used to
  isolate the BOOTMODE control logic
  after the value is latched
- PRU HEADER
- POWER SWITCH FOR PRU HEADER
- Silk: PRU HDR
- 3V3 supply of PRU Header is limited to sourcing 500mA max.
- NOTE: PRU Header I/O are not fail-safe
  and shall not be driven when AM62x
  Starter Kit is not powered.
sheet 33
- USER EXPANSION CONNECTOR
- Note: Expansion boards should take care
  of the null modem connectivity for the
  UART signals (cross-over of Rx and Tx)
- R32(Series damping resistor) should be placed close to SoC
- Silk: USER EXPN
- I2C SWITCH FOR SoC_I2C2
- POWER SWITCHES FOR USER EXPANSION CONNECTOR
- I2C ADDRESS: 0x71
- NOTE:
- AM62x Starter Kit shall not be powered through the 5V0 or 3V3 pins on the 40-pin User Expansion
  Connector.
  User Expansion Connector I/O are not fail-safe and shall not be driven when AM62x Starter Kit is
  not powered.
  5V supply of User Expansion Connector is limited to sourcing 155mA max.
  3V3 supply of User Expansion Connector is limited to sourcing 500mA max.
- It should be connected to PORz of the SoC TBD
sheet 34
- SOC - MCU DOMAIN
- MCU HEADER
- Silk: MCU HDR
- MCU_UART0 MUX
- INPUT/OUTPUT
- OEn
- SEL
- An
- L
- L(DEFAULT)
- An=nB1
- SOC - FT4232
- L
- H
- An=nB2
- SOC - MCU HEADER
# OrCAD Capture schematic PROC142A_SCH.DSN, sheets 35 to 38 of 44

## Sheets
35 35. USB0 TYPE-C DRP: size C; title: USB0 TYPE-C DRP
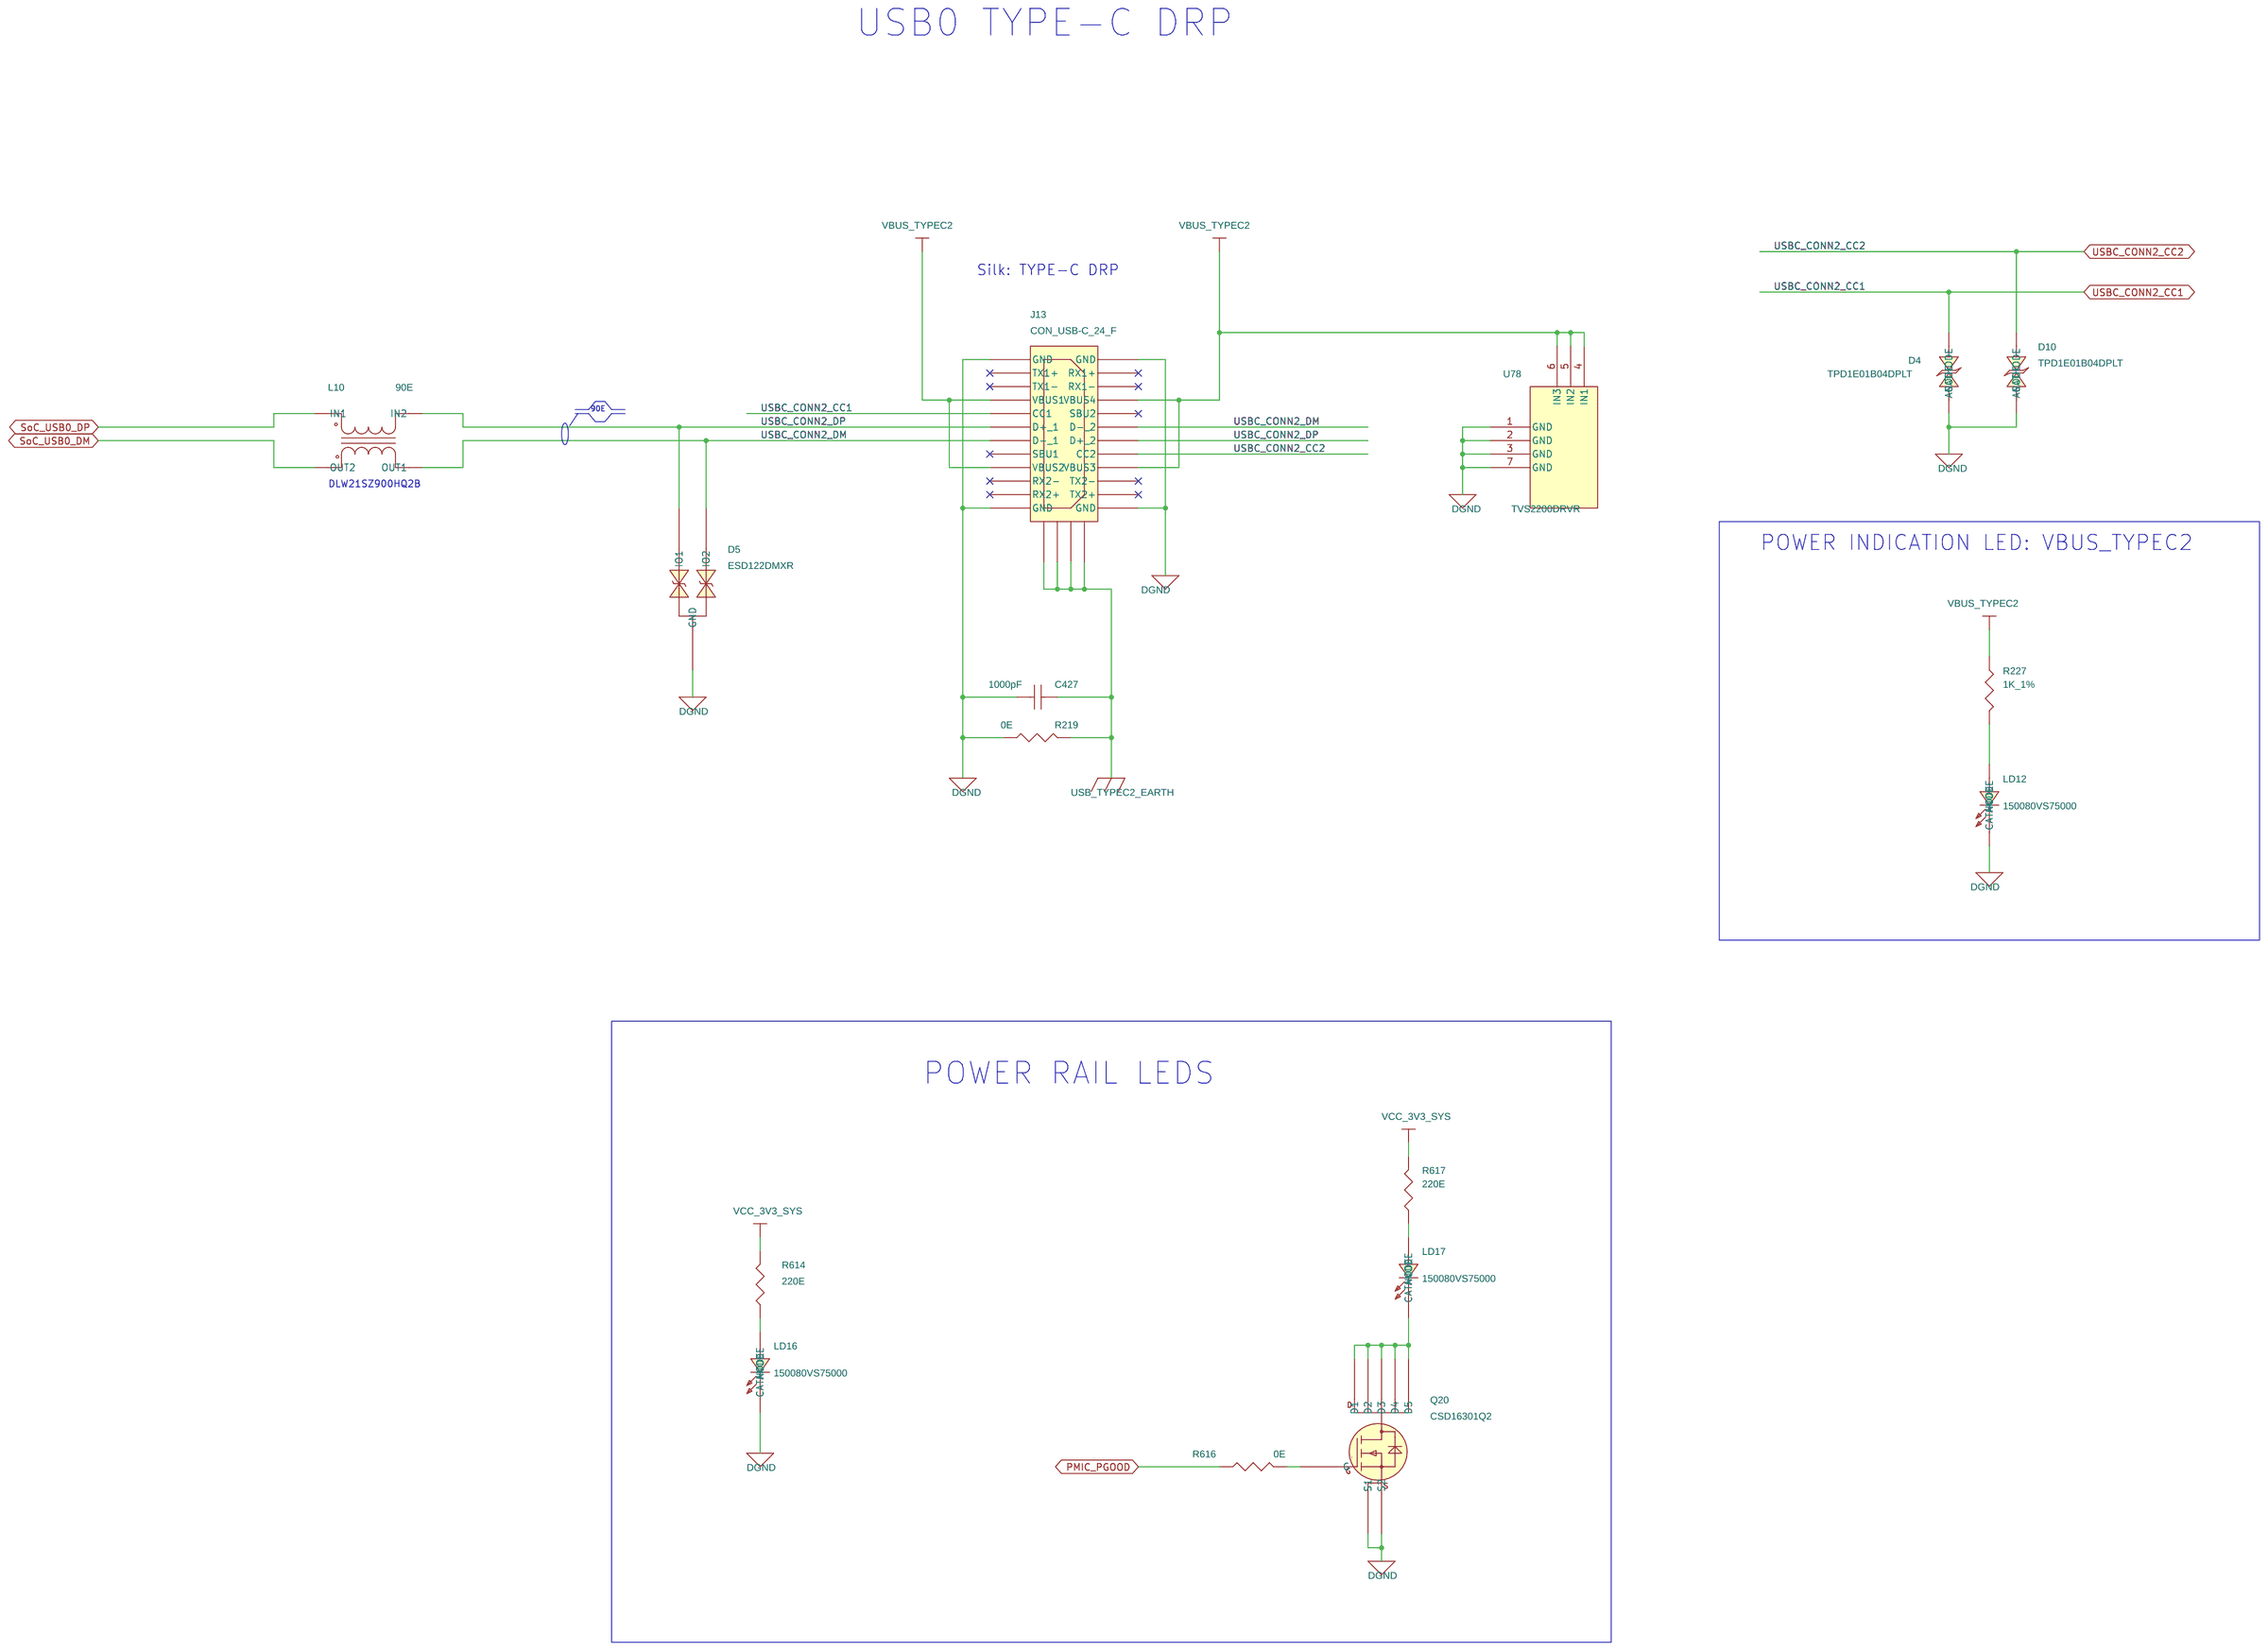
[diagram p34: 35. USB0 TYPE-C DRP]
36 36. USB1 TYPE A: size C; title: USB1 TYPE-A
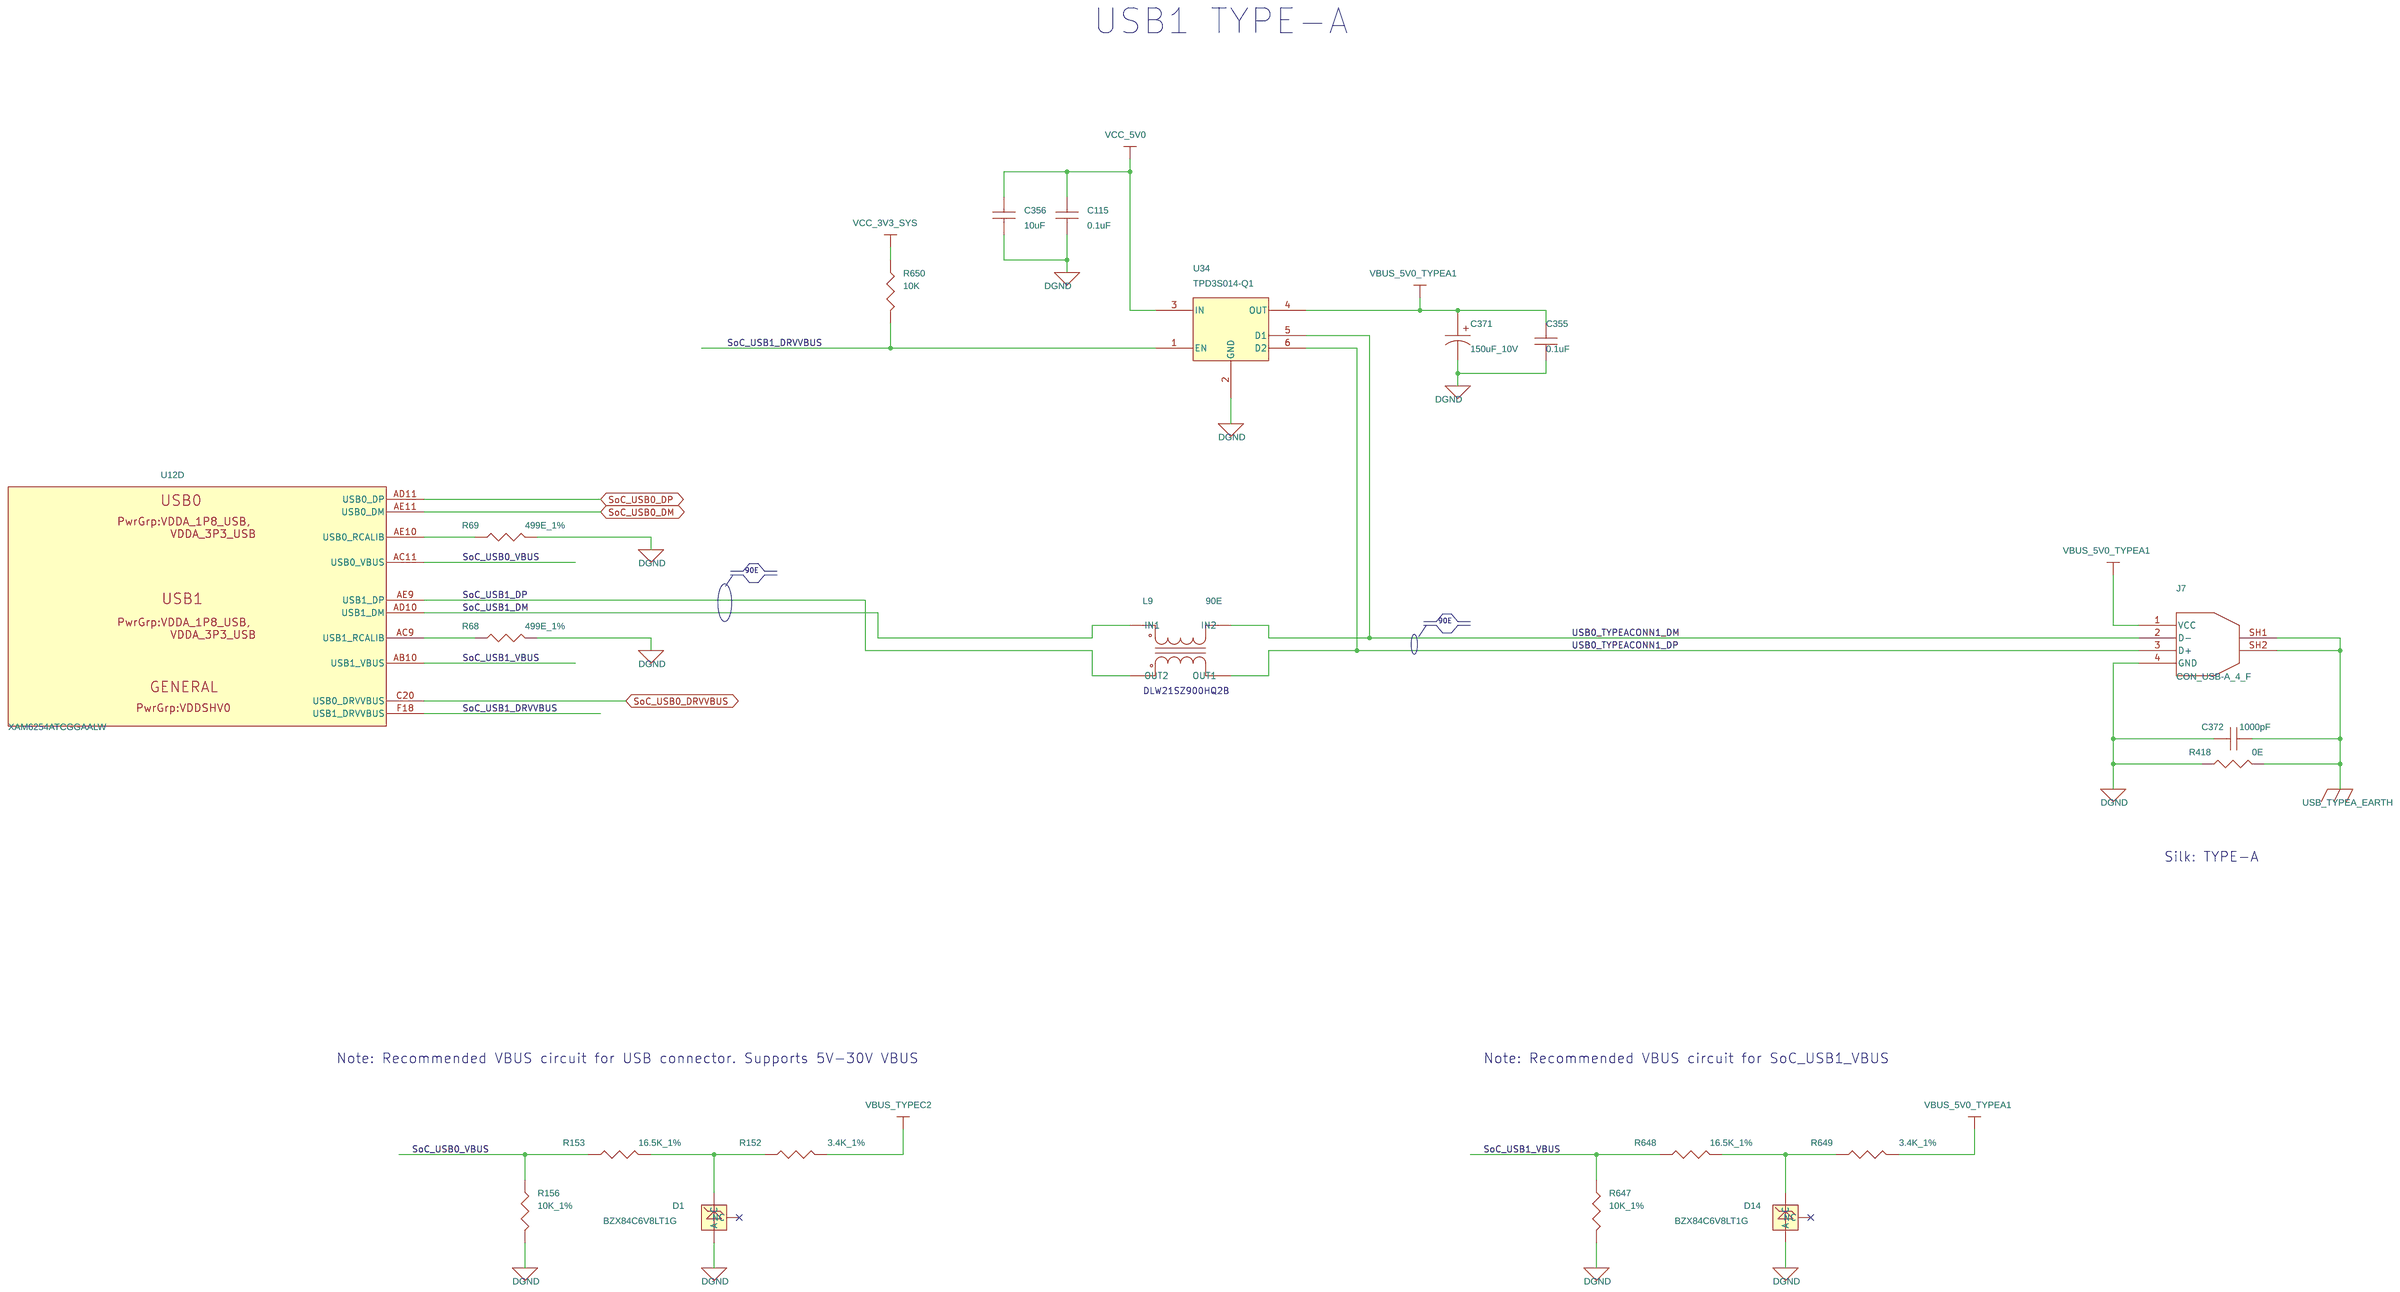
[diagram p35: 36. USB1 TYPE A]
37 37. OLDI DISPLAY INTERFACE: size C; title: OLDI DISPLAY INTERFACE
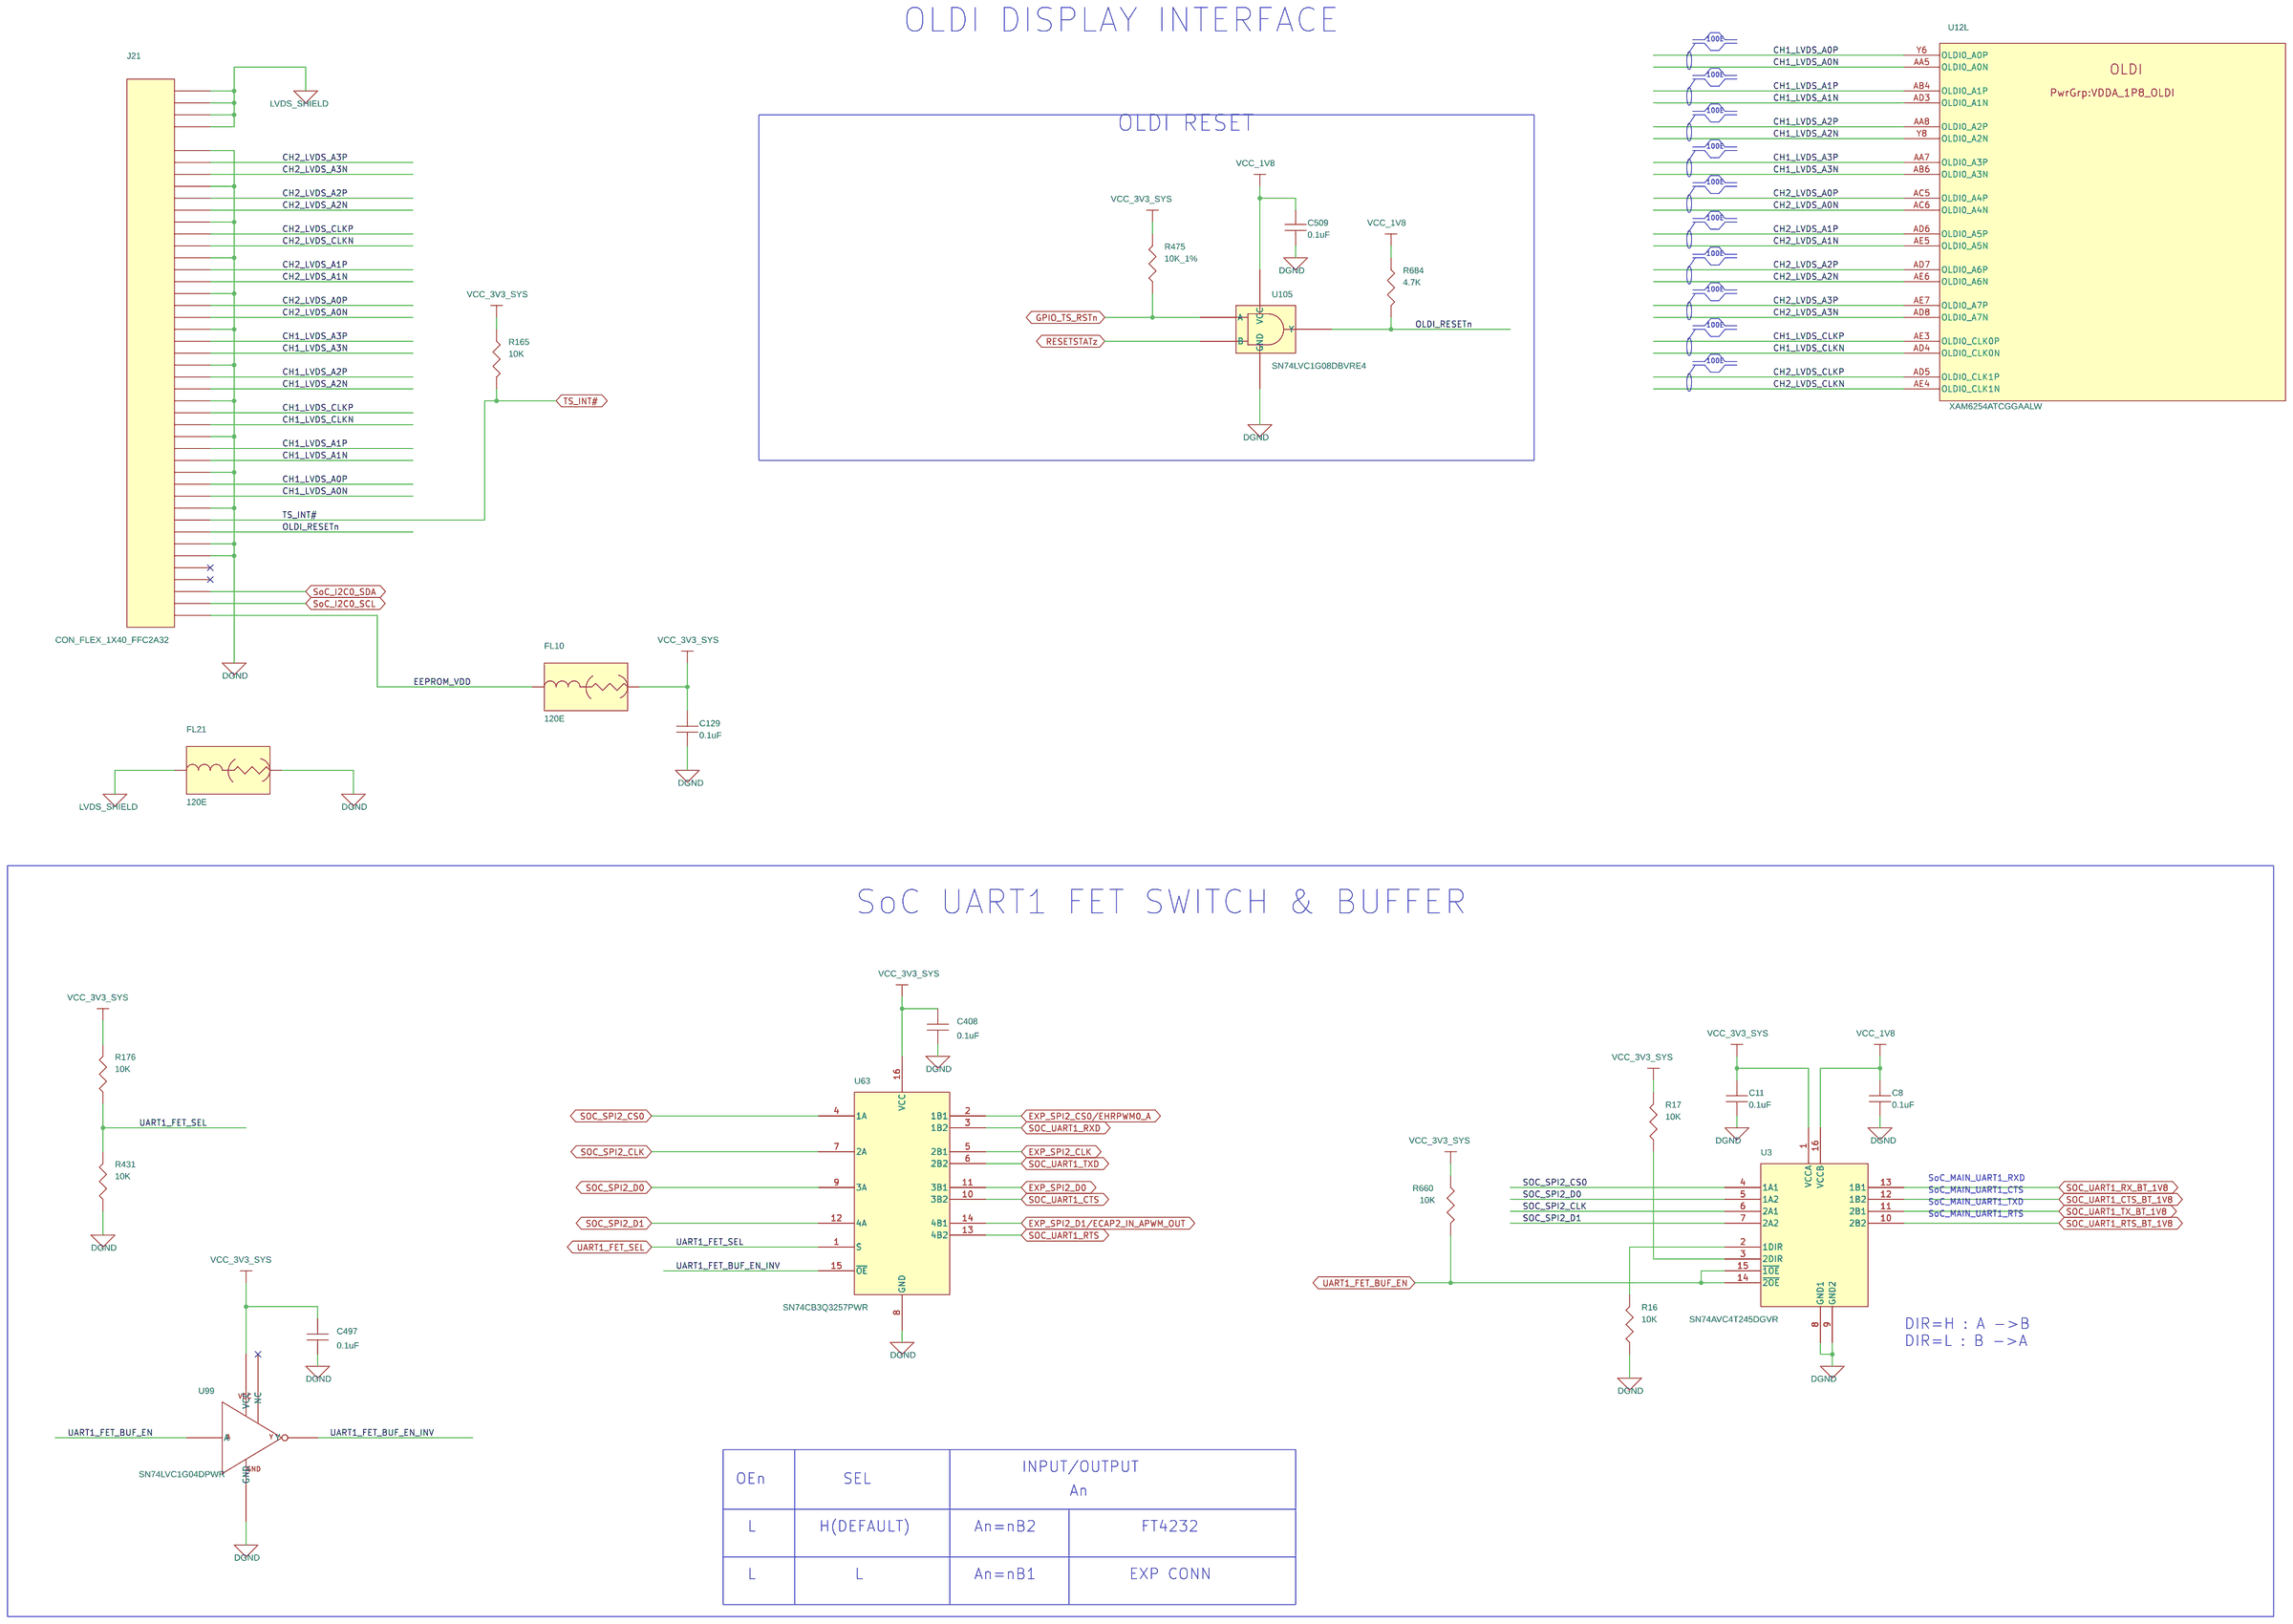
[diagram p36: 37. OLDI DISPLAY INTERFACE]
38 38. CSI INTERFACE & TEST LEDS: size C; title: CSI INTERFACE & USER TEST LEDS

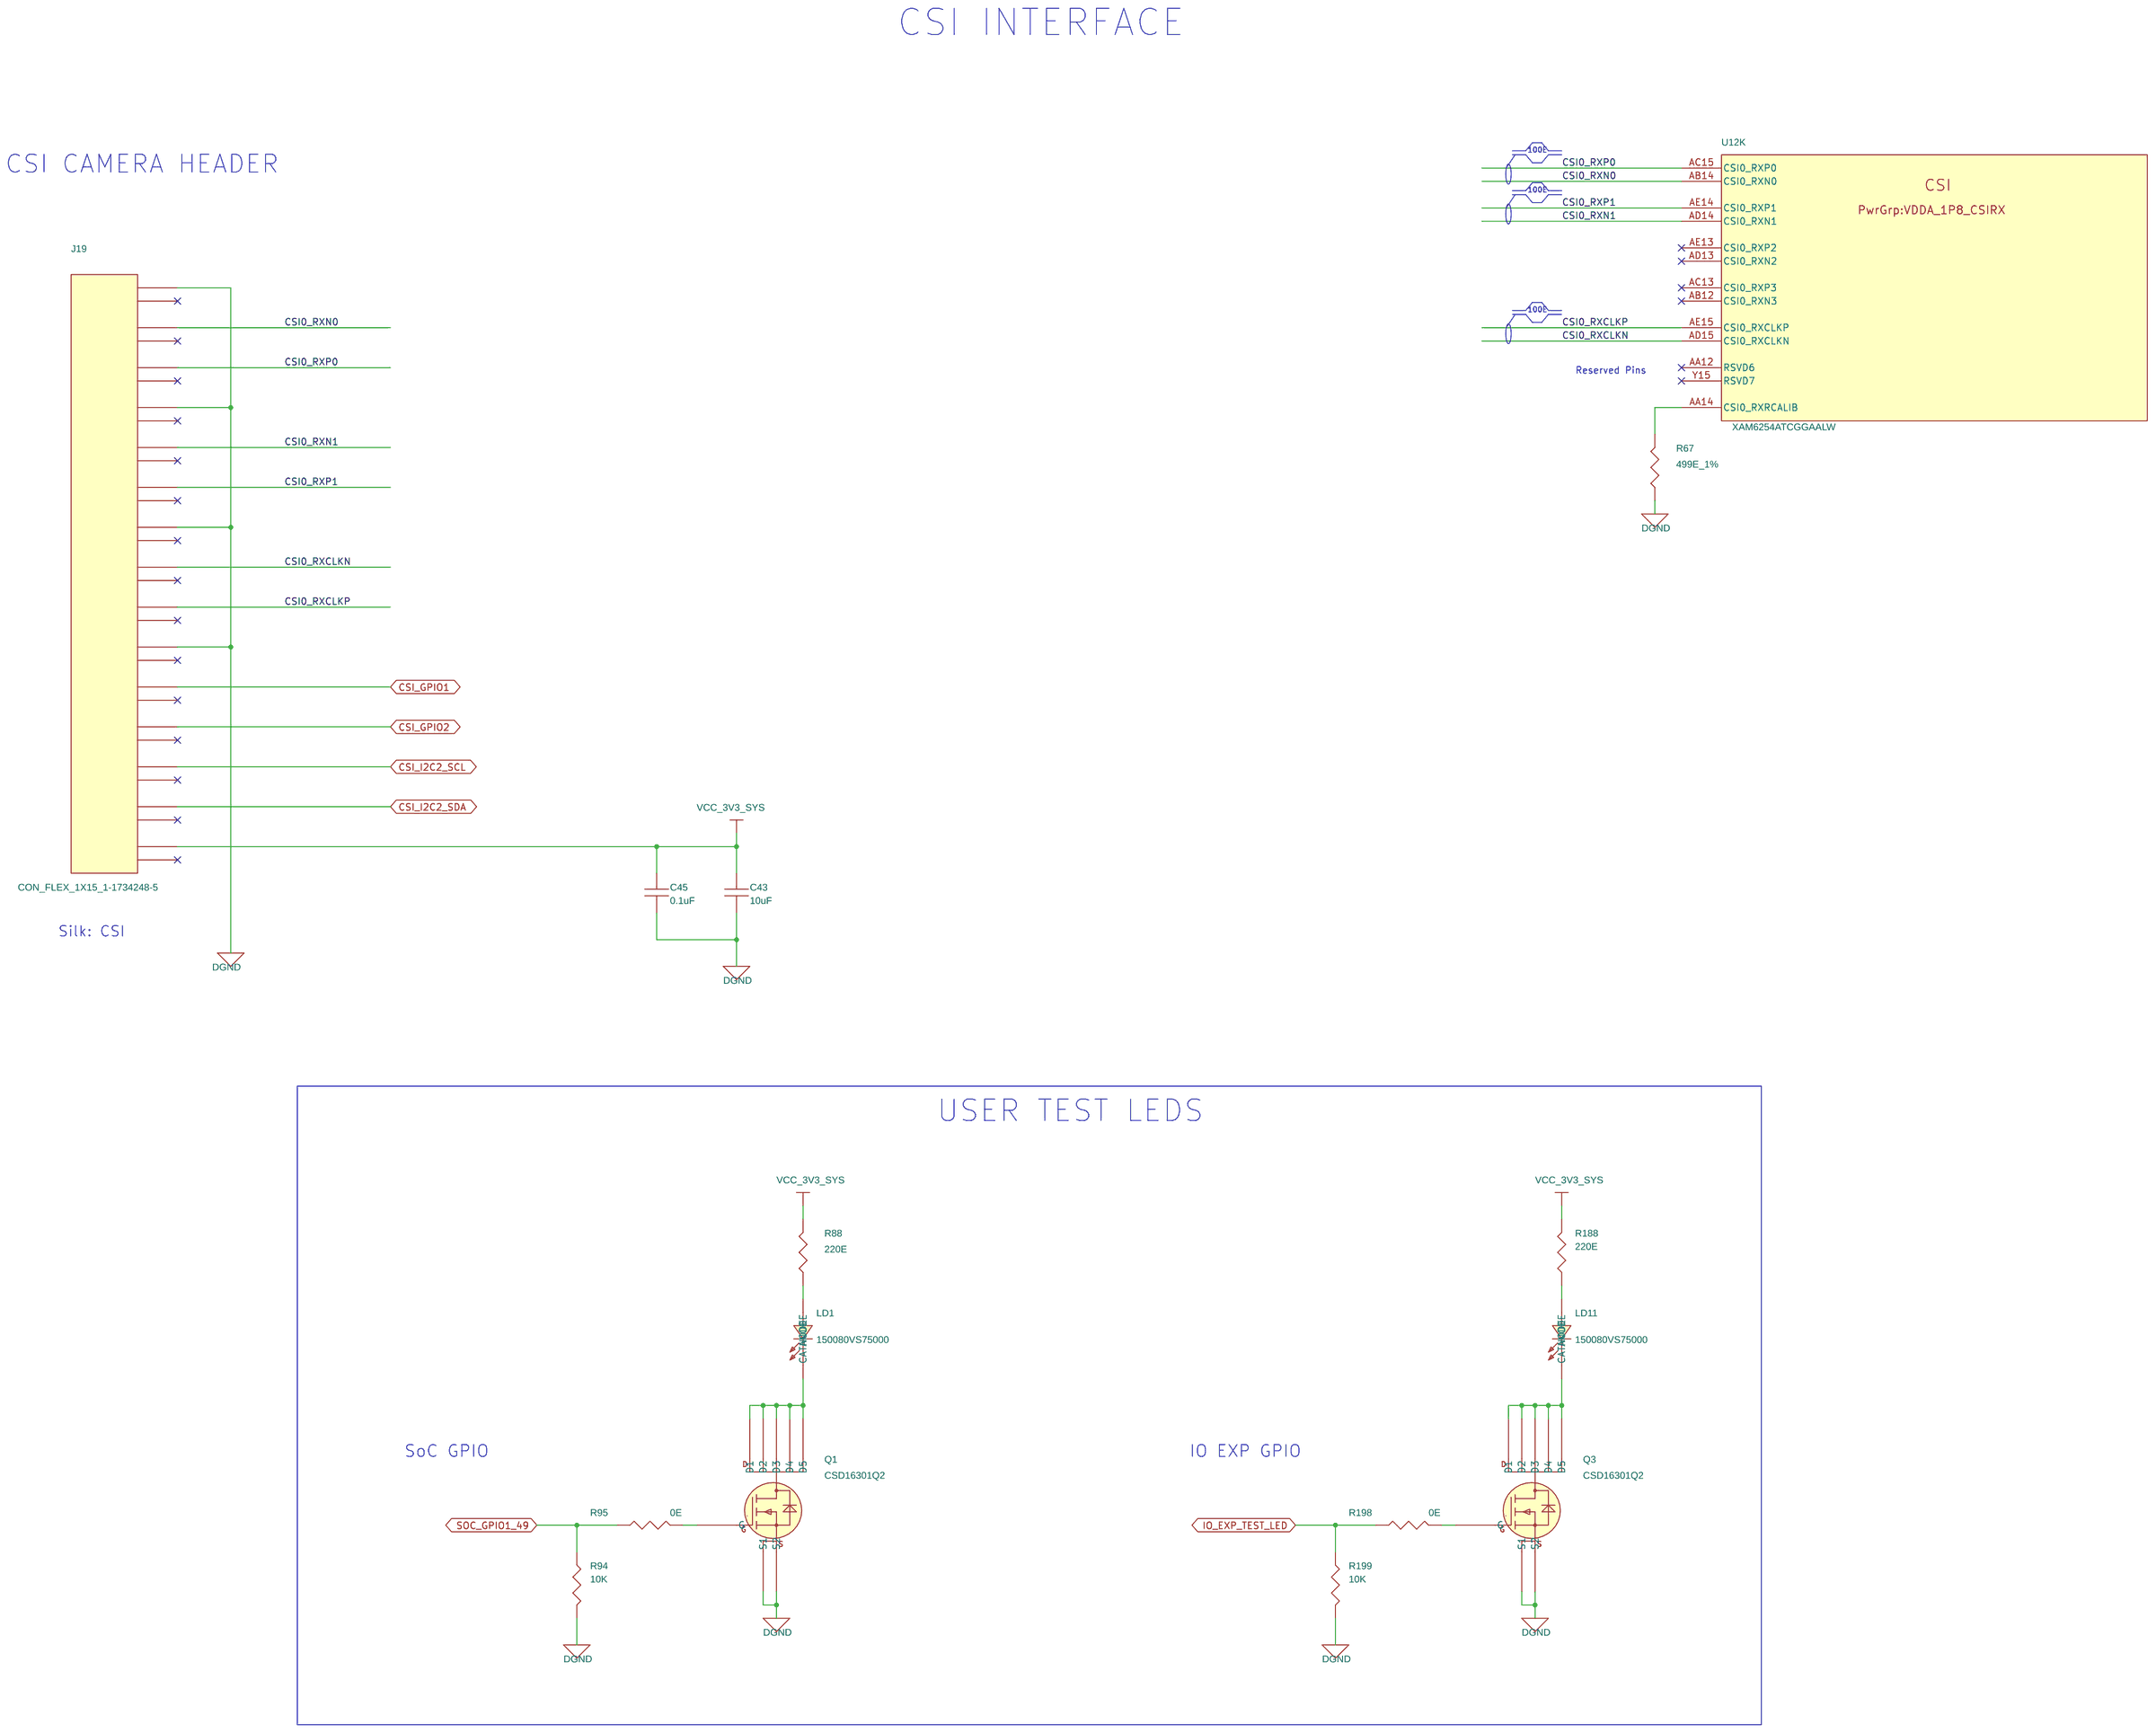
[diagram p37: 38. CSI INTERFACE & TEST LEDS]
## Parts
sheet 29. JTAG BUFFER
U12  XAM6254ATCGGAALW  [BGA425_19-68_510X510_0-7]  (sections A,B,C,D,E,F,G,H,I,J,K,L,M,N,O,P,Q,R)
sheet 35. USB0 TYPE-C DRP
C427  1000pF  [CAP1206_1-75]
D4  TPD1E01B04DPLT  [DIO_DFN0201_0-4]
D5  ESD122DMXR  [X2SON3_ESD122DMX_30X40_0-4]
D10  TPD1E01B04DPLT  [DIO_DFN0201_0-4]
J13  CON_USB-C_24_F  [CON_USBC24_2012670_S_R_S_3-9]
L10  90E  [IND4_DLW21H_90X60_SMD_1-4]
LD12  150080VS75000  [LED_150080VS75000_80X50_SMD_0-8]
LD16  150080VS75000  [LED_150080VS75000_80X50_SMD_0-8]
LD17  150080VS75000  [LED_150080VS75000_80X50_SMD_0-8]
Q20  CSD16301Q2  [WSON6_CSD13202Q2_80X80_0-8]
R219  0E  [RES0603_0-75]
R227  1K_1%  [RES0402_0-5]
R614  220E  [RES0402_0-5]
R616  0E  [RES0402_0-5]
R617  220E  [RES0402_0-5]
U78  TVS2200DRVR  [SON6_25-59_85X85_0-8]
sheet 36. USB1 TYPE A
C115  0.1uF  [CAP0201_0-5]
C355  0.1uF  [CAP0201_0-5]
C356  10uF  [CAP0603_1]
C371  150uF_10V  [CAPT7343D_3-25]
C372  1000pF  [CAP1206_1-75]
D1  BZX84C6V8LT1G  [SOT23-123_1-2]
D14  BZX84C6V8LT1G  [SOT23-123_1-2]
J7  CON_USB-A_4_F  [CON_USBA4_629104151_S_R_S_7-4]
L9  90E  [IND4_DLW21H_90X60_SMD_1-4]
R68  499E_1%  [RES0402_0-5]
R69  499E_1%  [RES0402_0-5]
R152  3.4K_1%  [RES0201_0-5]
R153  16.5K_1%  [RES0402_0-5]
R156  10K_1%  [RES0201_0-5]
R418  0E  [RES0603_0-75]
R647  10K_1%  [RES0201_0-5]
R648  16.5K_1%  [RES0402_0-5]
R649  3.4K_1%  [RES0201_0-5]
R650  10K  [RES0201_0-5]
U34  TPD3S014-Q1  [SOT23-6_1-5]
sheet 37. OLDI DISPLAY INTERFACE
C8  0.1uF  [CAP0201_0-5]
C11  0.1uF  [CAP0201_0-5]
C129  0.1uF  [CAP0201_0-5]
C408  0.1uF  [CAP0402_0-75]
C497  0.1uF  [CAP0201_0-5]
C509  0.1uF  [CAP0402_0-75]
FL10  120E  [EMIFIL_BLM15A_0402_0-6]
FL21  120E  [EMIFIL_BLM15A_0402_0-6]
J21  CON_FLEX_1X40_FFC2A32  [CON_FLEX1X40_FFC2A32-40-T_S_S_S_4-3]
R16  10K  [RES0201_0-5]
R17  10K  [RES0201_0-5]
R165  10K  [RES0201_0-5]
R176  10K  [RES0201_0-5]
R431  10K  [RES0201_0-5]
R475  10K_1%  [RES0201_0-5]
R660  10K  [RES0201_0-5]
R684  4.7K  [RES0201_0-5]
U3  SN74AVC4T245DGVR  [TVSOP16_15-74_150X180]
U63  SN74CB3Q3257PWR  [TSSOP16_25-59_205X180]
U99  SN74LVC1G04DPWR  [X2SON5_TLV7021_30X30_0-4]
U105  SN74LVC1G08DBVRE4  [SOT23-5]
sheet 38. CSI INTERFACE & TEST LEDS
C43  10uF  [CAP0402_0-75]
C45  0.1uF  [CAP0402_0-75]
J19  CON_FLEX_1X15_1-1734248-5  [CON_FLEX1X15_1-1734248-5_S_S_S_7-7]
LD1  150080VS75000  [LED_150080VS75000_80X50_SMD_0-8]
LD11  150080VS75000  [LED_150080VS75000_80X50_SMD_0-8]
Q1  CSD16301Q2  [WSON6_CSD13202Q2_80X80_0-8]
Q3  CSD16301Q2  [WSON6_CSD13202Q2_80X80_0-8]
R67  499E_1%  [RES0402_0-5]
R88  220E  [RES0402_0-5]
R94  10K  [RES0201_0-5]
R95  0E  [RES0402_0-5]
R188  220E  [RES0402_0-5]
R198  0E  [RES0402_0-5]
R199  10K  [RES0201_0-5]

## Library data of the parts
U12 = AM62-EVM_BGA425: IC AM62 SoC MICROPROCESSOR BGA425; Chkd/date: ALVY/110621; Crtd /date: MANIRAJA/110621; Custom_Duty: 15%; Customs_HS_Code: 85423100; Distributor_name: NA; Distributor_part_number: NA; Footprint Path: Y:\MIS_DATABASE\Library\ALTIUM_TOOL\PCB_FOOTPRINTS\Altium_Footprint_Lib.PcbLib; Height: 0.65MM; Library Path: Y:\MIS_DATABASE\Library\ALTIUM_TOOL\SCHEMATICS_PARTS\MS_MICROPROCESSOR_Library.schlib; Mfr_name: TEXAS INSTRUMENTS; Mistral Part No: 141221060001; Package: BGA425; Part_type: ICS\DIGITAL\MICROPROCESSOR; Project: AM62_EVM_BRD; RoHS: NA; Temperature: NA; Tolerance: NA; Voltage: NA; Wattage: NA; Weight: NA; Datasheet: Y:\MIS_DATABASE\DATASHEETS\ICS\DIGITAL\MICROCONTROLLER\AM62-SoC_SVB.PDF
C372 C427 = CAP: CAP CERAMIC 1000pF 2KV 10% X7R 1206; Chkd/date: SHREESHAIL/291106; Crtd /date: MAZHAR/281106; Custom_Duty: 15%; Customs_HS_Code: 85322990; Distributor_name: DIGIKEY; Distributor_part_number: 478-2956-1-ND; Footprint Path: Y:\MIS_DATABASE\Library\ALTIUM_TOOL\PCB_FOOTPRINTS\Altium_Footprint_Lib.PcbLib; Height: 1.52MM; Library Path: Y:\MIS_DATABASE\Library\ALTIUM_TOOL\SCHEMATICS_PARTS\MS_DISCRETE_Library.schlib; Mfr_name: AVX CORPORATION; Mfr_part_number: 1206GC102KAT1A; Mistral Part No: 120015080006-R; Package: 1206; Part_type: CAPACITORS\CERAMIC; Project: ADR1B; RoHS: RoHS; Temperature: -55°C+125°C; Tolerance: 10%; Voltage: 2KV; Wattage: NA; Weight: 16.2mg; Datasheet: Y:\MIS_DATABASE\DATASHEETS\CAPACITORS\AVX_HV-MLC.PDF
D4 D10 = DIODE_TVS_DUAL: DIODE 1CH ESD PROTECTION FOR USB TYPE-C AND THUNDERBOLT3 X2SON2; Chkd/date: MANIRAJA/230920; Crtd /date: ALVY/230920; Custom_Duty: 15%; Customs_HS_Code: 85412900; Distributor_name: DIGIKEY; Distributor_part_number: 296-44484-1-ND; Footprint Path: Y:\MIS_DATABASE\Library\ALTIUM_TOOL\PCB_FOOTPRINTS\Altium_Footprint_Lib.PcbLib; Height: 0.32MM; Library Path: Y:\MIS_DATABASE\Library\ALTIUM_TOOL\SCHEMATICS_PARTS\MS_DISCRETE_Library.schlib; Mfr_name: TEXAS INSTRUMENTS; Mistral Part No: 130020090037-R; Package: X2SON2; Part_type: DIODE\TVS; Project: AM64X_SKEVM; RoHS: RoHS; Temperature: -40°C+125°C; Tolerance: NA; Voltage: NA; Wattage: NA; Weight: 0.2mg; Datasheet: Y:\MIS_DATABASE\DATASHEETS\DISCRETES\DIODES\TPD1E01B04.PDF
D5 = DIODE_ESD122DMXR: DIODE 2-CH ESD PROTECTION FOR USB TYPE-C AND HDMI 2.0 X2SON-3; Chkd/date: MANIRAJA/140817; Crtd /date: MANIRAJA/140817; Custom_Duty: 15%; Customs_HS_Code: 85412900; Distributor_name: DIGIKEY; Distributor_part_number: ESD122DMXR-ND; Height: 0.40MM; Mfr_name: TEXAS INSTRUMENTS; Mistral Part No: 130017080015-R; Package: X2SON-3; Part_type: DIODE\TVS; Project: TI_SVB_CONTROLLER CARD; RoHS: RoHS; Temperature: -40°C+125°C; Tolerance: NA; Voltage: NA; Wattage: NA; Weight: NA; Datasheet: Y:\MIS_DATABASE\DATASHEETS\DISCRETES\DIODES\ESD122XX.PDF
J13 = CON_USB-C_24_1240183621: CON USB-C TYPE 24POS FEMALE RT SMD; Chkd/date: MANIRAJA/050618; Crtd /date: ALVY/040618; Custom_Duty: 24%; Customs_HS_Code: 85369090; Distributor_name: DIGIKEY; Distributor_part_number: WM17992CT-ND; Footprint Path: Y:\MIS_DATABASE\Library\ALTIUM_TOOL\PCB_FOOTPRINTS\Altium_Footprint_Lib.PcbLib; Height: 3.86MM; Library Path: Y:\MIS_DATABASE\Library\ALTIUM_TOOL\SCHEMATICS_PARTS\MS_CONNECTOR_Library.schlib; Mfr_name: MOLEX; Mfr_part_number: 2012670005; Mistral Part No: 150018060002-R; Package: SMD; Part_type: CONNECTOR\USB; Project: TI_J7SVB_USB_ADD-ON-CARD; RoHS: RoHS; Temperature: -40°C+105°C; Tolerance: NA; Voltage: NA; Wattage: NA; Weight: 0.686g; Datasheet: Y:\MIS_DATABASE\DATASHEETS\CONNECTORS\2012670X.PDF
L9 L10 = INDUCTOR_DLW31S: IND COMMON MODE CHOKE 90E 280mA SMD; Chkd/date: MANIRAJA/270619; Crtd /date: MANIRAJA/270619; Custom_Duty: 24%; Customs_HS_Code: 85437099; Distributor_name: NA; Distributor_part_number: NA; Footprint Path: Y:\MIS_DATABASE\Library\ALTIUM_TOOL\PCB_FOOTPRINTS\Altium_Footprint_Lib.PcbLib; Height: 1.40MM; Library Path: Y:\MIS_DATABASE\Library\ALTIUM_TOOL\SCHEMATICS_PARTS\MS_DISCRETE_Library.schlib; Mfr_name: MURATA; Mfr_part_number: DLW21SZ900HQ2B; Mistral Part No: 130019060035-R; Package: SMD; Part_type: INDUCTOR; Project: TI_J7ES_CP; RoHS: RoHS; Temperature: -40°C+105°C; Tolerance: NA; Voltage: NA; Wattage: NA; Weight: 11mg; Datasheet: Y:\MIS_DATABASE\DATASHEETS\DISCRETES\INDUCTORS\DLW21SZ900HQ2B.PDF
LD1 LD11 LD12 LD16 LD17 = DIODE_LED: DIODE LED BRIGHT GREEN SMD; Chkd/date: MANIRAJA/180820; Crtd /date: ALVY/180820; Custom_Duty: 24%; Customs_HS_Code: 85439000; Distributor_name: DIGIKEY; Distributor_part_number: 732-4986-1-ND; Footprint Path: Y:\MIS_DATABASE\Library\ALTIUM_TOOL\PCB_FOOTPRINTS\Altium_Footprint_Lib.PcbLib; Height: 0.80MM; Library Path: Y:\MIS_DATABASE\Library\ALTIUM_TOOL\SCHEMATICS_PARTS\MS_OPTO_Library.schlib; Mfr_name: WURTH ELECTRONICS; Mistral Part No: 130020080012-R; Package: SMD; Part_type: OPTO\LED; Project: AM64x_EVM_BRD; RoHS: RoHS; Temperature: -40°C+85°C; Tolerance: NA; Voltage: NA; Wattage: NA; Weight: 10mg; Datasheet: Y:\MIS_DATABASE\DATASHEETS\DISCRETES\LEDS\150080VS75000.PDF
Q1 Q3 Q20 = MOSFET_CSD17313Q2: IC MOSFET N-CHANNEL NEXFET 25V WSON6; Chkd/date: ALVY/071220; Crtd /date: MANIRAJA/071220; Custom_Duty: 15%; Customs_HS_Code: 85423100; Distributor_name: DIGIKEY; Distributor_part_number: 296-25260-1-ND; Footprint Path: Y:\MIS_DATABASE\Library\ALTIUM_TOOL\PCB_FOOTPRINTS\Altium_Footprint_Lib.PcbLib; Height: 0.80MM; Library Path: Y:\MIS_DATABASE\Library\ALTIUM_TOOL\SCHEMATICS_PARTS\MS_MOSFET_Library.schlib; Mfr_name: TEXAS INSTRUMENTS; Mistral Part No: 142020120008-R; Package: WSON6; Part_type: ICS\POWER\MOSFET; Project: TI_AM243x LP EVM; RoHS: RoHS; Temperature: -55°C+150°C; Tolerance: NA; Voltage: NA; Wattage: NA; Weight: 8.7mg; Datasheet: Y:\MIS_DATABASE\DATASHEETS\ICS\POWER\CSD16301Q2.PDF
R219 R418 = RESISTOR: RES 0E 1/10W 5% 0603; Chkd/date: MANIRAJA/051217; Crtd /date: BAVISH/180211; Custom_Duty: 15%; Customs_HS_Code: 85332119; Distributor_name: DIGIKEY; Distributor_part_number: 311-0.0GRCT-ND; Footprint Path: Y:\MIS_DATABASE\Library\ALTIUM_TOOL\PCB_FOOTPRINTS\Altium_Footprint_Lib.PcbLib; Height: 0.55MM; Library Path: Y:\MIS_DATABASE\Library\ALTIUM_TOOL\SCHEMATICS_PARTS\MS_DISCRETE_Library.schlib; Manufacturer: YAGEO AMERICA; Mfr_name: PANASONIC-ECG; Mfr_part_number: RC0603JR-070RL; Mistral Part No: 110011020013-R; Package: 0603; Part_type: RESISTORS\FIXED; Project: KENNEL; RoHS: RoHS; Temperature: -55°C+155°C; Tolerance: 5%; Voltage: NA; Wattage: 1/10W; Weight: 2mg; Datasheet: Y:\MIS_DATABASE\DATASHEETS\RESISTORS\RCXXXXL-SER_MAR18.PDF
R227 = RESISTOR: RES 1K 1/10W 1% 0402; Chkd/date: VASANTHA/281216; Crtd /date: MAZHAR/150506; Custom_Duty: 15%; Customs_HS_Code: 85332119; Distributor_name: DIGIKEY; Distributor_part_number: P1.00KLCT-ND; Footprint Path: Y:\MIS_DATABASE\Library\ALTIUM_TOOL\PCB_FOOTPRINTS\Altium_Footprint_Lib.PcbLib; Height: 0.40MM; Library Path: Y:\MIS_DATABASE\Library\ALTIUM_TOOL\SCHEMATICS_PARTS\MS_DISCRETE_Library.schlib; Mfr_name: PANASONIC-ECG; Mfr_part_number: ERJ-2RKF1001X; Mistral Part No: 110009030411-R; Package: 0402; Part_type: RESISTORS\FIXED; Project: VOCERA; RoHS: RoHS; Temperature: -55°C+155°C; Tolerance: 1%; Voltage: NA; Wattage: 1/10W; Weight: 0.8mg; Datasheet: Y:\MIS_DATABASE\DATASHEETS\RESISTORS\PAN-ERJSER_NOV17.PDF
R88 R188 R614 R617 = RESISTOR: RES 220E 1/10W 5% 0402; Chkd/date: VASANTHA/291216; Crtd /date: GEETHA/260406; Custom_Duty: 15%; Customs_HS_Code: 85332119; Distributor_name: DIGIKEY; Distributor_part_number: P220JCT-ND; Footprint Path: Y:\MIS_DATABASE\Library\ALTIUM_TOOL\PCB_FOOTPRINTS\Altium_Footprint_Lib.PcbLib; Height: 0.40MM; Library Path: Y:\MIS_DATABASE\Library\ALTIUM_TOOL\SCHEMATICS_PARTS\MS_DISCRETE_Library.schlib; Mfr_name: PANASONIC-ECG; Mfr_part_number: ERJ-2GEJ221X; Mistral Part No: 110009030506-R; Package: 0402; Part_type: RESISTORS\FIXED; Project: RED EYE; RoHS: RoHS; Temperature: -55°C+155°C; Tolerance: 5%; Voltage: NA; Wattage: 1/10W; Weight: 0.8mg; Datasheet: Y:\MIS_DATABASE\DATASHEETS\RESISTORS\PAN-ERJSER_NOV17.PDF
R95 R198 R616 = RESISTOR: RES 0E 1/16W JUMPER 0402; Chkd/date: VASANTHA/201216; Crtd /date: MUDDU/190810; Custom_Duty: 15%; Customs_HS_Code: 85332119; Distributor_name: DIGIKEY; Distributor_part_number: 541-0.0JCT-ND; Footprint Path: Y:\MIS_DATABASE\Library\ALTIUM_TOOL\PCB_FOOTPRINTS\Altium_Footprint_Lib.PcbLib; Height: 0.40MM; Library Path: Y:\MIS_DATABASE\Library\ALTIUM_TOOL\SCHEMATICS_PARTS\MS_DISCRETE_Library.schlib; Mfr_name: VISHAY; Mfr_part_number: CRCW04020000Z0ED; Mistral Part No: 110010080019-R; Package: 0402; Part_type: RESISTORS\FIXED; Project: PB_BUGBASE; RoHS: RoHS; Temperature: -55°C+155°C; Tolerance: NA; Voltage: NA; Wattage: 1/16W; Weight: 0.65mg; Datasheet: Y:\MIS_DATABASE\DATASHEETS\RESISTORS\CRCW0603.PDF
U78 = TVS2200_WSON6: IC 22V FLAT-CLAMP SURGE PROTECTION DEVICE WSON6; Chkd/date: MANIRAJA/011021; Crtd /date: ALVY/011021; Custom_Duty: 15%; Customs_HS_Code: 85423100; Distributor_name: DIGIKEY; Distributor_part_number: 296-52187-1-ND; Footprint Path: Y:\MIS_DATABASE\Library\ALTIUM_TOOL\PCB_FOOTPRINTS\Altium_Footprint_Lib.PcbLib; Height: 0.80MM; Library Path: Y:\MIS_DATABASE\Library\ALTIUM_TOOL\SCHEMATICS_PARTS\MS_MISCPOWER_Library.schlib; Mfr_name: TEXAS INSTRUMENTS; Mistral Part No: 142021100001-R; Package: WSON6; Part_type: ICS\POWER; Project: TI_AM62x SKEVM_BRD; RoHS: RoHS; Temperature: -40°C+125°C; Tolerance: NA; Voltage: NA; Wattage: NA; Weight: 12mg; Datasheet: Y:\MIS_DATABASE\DATASHEETS\ICS\POWER\TVS2200.PDF
C115 C355 = CAP: CAP CERAMIC 0.1uF 16V 10% X5R 0201; Chkd/date: MANIRAJA/230118; Crtd /date: MANIRAJA/230118; Custom_Duty: 15%; Customs_HS_Code: 85322990; Distributor_name: DIGIKEY; Distributor_part_number: 490-14305-1-ND; Footprint Path: Y:\MIS_DATABASE\Library\ALTIUM_TOOL\PCB_FOOTPRINTS\Altium_Footprint_Lib.PcbLib; Height: 0.33MM; Library Path: Y:\MIS_DATABASE\Library\ALTIUM_TOOL\SCHEMATICS_PARTS\MS_DISCRETE_Library.schlib; Mfr_name: MURATA; Mfr_part_number: GRM033R61C104KE14D; Mistral Part No: 120009030072-R; Package: 0201; Part_type: CAPACITORS\CERAMIC; Project: TI_MAXIE_CPB; RoHS: RoHS; Temperature: -55°C+85°C; Tolerance: 10%; Voltage: 16V; Wattage: NA; Weight: 0.33mg; Datasheet: Y:\MIS_DATABASE\DATASHEETS\CAPACITORS\GRM033R61C104KE14.PDF
C356 = CAP: CAP CERAMIC 10uF 35V 20% X5R 0603; Chkd/date: MANIRAJA/170519; Crtd /date: ALVY/160519; Custom_Duty: 15%; Customs_HS_Code: 85322990; Distributor_name: DIGIKEY; Distributor_part_number: 490-13248-1-ND; Footprint Path: Y:\MIS_DATABASE\Library\ALTIUM_TOOL\PCB_FOOTPRINTS\Altium_Footprint_Lib.PcbLib; Height: 1.00MM; Library Path: Y:\MIS_DATABASE\Library\ALTIUM_TOOL\SCHEMATICS_PARTS\MS_DISCRETE_Library.schlib; Mfr_name: MURATA; Mfr_part_number: GRM188R6YA106MA73D; Mistral Part No: 120019050016-R; Package: 0603; Part_type: CAPACITORS\CERAMIC; Project: BRUKER_SD820_COMMONDO; RoHS: RoHS; Temperature: -55°C+85°C; Tolerance: 20%; Voltage: 35V; Wattage: NA; Weight: 9mg; Datasheet: Y:\MIS_DATABASE\DATASHEETS\CAPACITORS\GRM188R6YA106MA73.PDF
C371 = CAP_POL: CAP TANTALUM 150uF 10V 10% ESR 600mE D7343; Chkd/date: ALVY/200921; Crtd /date: MANIRAJA/200921; Custom_Duty: 15%; Customs_HS_Code: 85322990; Distributor_name: DIGIKEY; Distributor_part_number: 718-1960-1-ND; Footprint Path: Y:\MIS_DATABASE\Library\ALTIUM_TOOL\PCB_FOOTPRINTS\Altium_Footprint_Lib.PcbLib; Height: 3.10MM; Library Path: Y:\MIS_DATABASE\Library\ALTIUM_TOOL\SCHEMATICS_PARTS\MS_DISCRETE_Library.schlib; Mfr_name: VISHAY; Mfr_part_number: 293D157X9010D2TE3; Mistral Part No: 120021090007-R; Package: D7343; Part_type: CAPACITORS\TANTALUM; Project: TI_AM62x SKEVM_BRD; RoHS: RoHS; Temperature: -55°C+125°C; Tolerance: 10%; Voltage: 10V; Wattage: NA; Weight: 400mg; Datasheet: Y:\MIS_DATABASE\DATASHEETS\CAPACITORS\293D_SER_MAR20.PDF
D1 D14 = DIODE_ZENER_SOT23_13: DIODE ZENER 250mW 6.8V SOT23-123; Chkd/date: MANIRAJA/031017; Crtd /date: MANIRAJA/031017; Custom_Duty: 15%; Customs_HS_Code: 85412900; Distributor_name: DIGIKEY; Distributor_part_number: BZX84C6V8LT1GOSCT-ND; Height: 1.11MM; Mfr_name: ON SEMICONDUCTOR; Mistral Part No: 130017100002-R; Package: SOT23-123; Part_type: DIODE\ZENER; Project: TI_MAXIE_CPB; RoHS: RoHS; Temperature: -65°C+150°C; Tolerance: NA; Voltage: 6.8V; Wattage: NA; Weight: 8mg; Datasheet: Y:\MIS_DATABASE\DATASHEETS\DISCRETES\DIODES\BZX84XX.PDF
J7 = CON_USB-A_4_2SH: CON USB-A TYPE 4POS FEMALE RT SMD; Chkd/date: MANIRAJA/271017; Crtd /date: MANIRAJA/271017; Custom_Duty: 24%; Customs_HS_Code: 85369090; Distributor_name: DIGIKEY; Distributor_part_number: 732-5969-1-ND; Height: 7.35MM; Mfr_name: WURTH ELECTRONICS; Mfr_part_number: 629104151021; Mistral Part No: 150017100042-R; Package: SMD; Part_type: CONNECTOR\USB; Project: TI_SVB_MAXWELL_SPM; RoHS: RoHS; Temperature: -40°C+85°C; Tolerance: NA; Voltage: NA; Wattage: NA; Weight: NA; Datasheet: Y:\MIS_DATABASE\DATASHEETS\CONNECTORS\629104151021.PDF
R67-R69 = RESISTOR: RES 499E 1/16W 1% 0402; Chkd/date: MANIRAJA/051020; Crtd /date: ALVY/051020; Custom_Duty: 15%; Customs_HS_Code: 85332119; Distributor_name: DIGIKEY; Distributor_part_number: 311-499LRCT-ND; Footprint Path: Y:\MIS_DATABASE\Library\ALTIUM_TOOL\PCB_FOOTPRINTS\Altium_Footprint_Lib.PcbLib; Height: 0.40MM; Library Path: Y:\MIS_DATABASE\Library\ALTIUM_TOOL\SCHEMATICS_PARTS\MS_DISCRETE_Library.schlib; Mfr_name: YAGEO AMERICA; Mfr_part_number: RC0402FR-07499RL; Mistral Part No: 110020080006-R; Package: 0402; Part_type: RESISTORS\FIXED; Project: AM64XX_EVM; RoHS: RoHS; Temperature: -55°C+155°C; Tolerance: 1%; Voltage: NA; Wattage: 1/16W; Weight: 0.65mg; Datasheet: Y:\MIS_DATABASE\DATASHEETS\RESISTORS\RCXXXXL-SER_MAR18.PDF
R152 R649 = RESISTOR: RES 3.4K 1/20W 1% 0201; Chkd/date: VASANTHA/250116; Crtd /date: VASANTHA/250116; Custom_Duty: 15%; Customs_HS_Code: 85332119; Distributor_name: DIGIKEY; Distributor_part_number: ERJ-1GNF3401C-ND; Footprint Path: Y:\MIS_DATABASE\Library\ALTIUM_TOOL\PCB_FOOTPRINTS\Altium_Footprint_Lib.PcbLib; Height: 0.26MM; Library Path: Y:\MIS_DATABASE\Library\ALTIUM_TOOL\SCHEMATICS_PARTS\MS_DISCRETE_Library.schlib; Mfr_name: PANASONIC-ECG; Mfr_part_number: ERJ-1GNF3401C; Mistral Part No: 110016010003-R; Package: 0201; Part_type: RESISTORS\FIXED; Project: QUADIO; RoHS: RoHS; Temperature: -55°C+125°C; Tolerance: 1%; Voltage: NA; Wattage: 1/20W; Weight: 0.15mg; Datasheet: Y:\MIS_DATABASE\DATASHEETS\RESISTORS\PAN-ERJSER_NOV17.PDF
R153 R648 = RESISTOR: RES 16.5K 1/16W 1% 0402; Chkd/date: ALVY/091220; Crtd /date: MANIRAJA/091220; Custom_Duty: 15%; Customs_HS_Code: 85332119; Distributor_name: DIGIKEY; Distributor_part_number: YAG3002CT-ND; Footprint Path: Y:\MIS_DATABASE\Library\ALTIUM_TOOL\PCB_FOOTPRINTS\Altium_Footprint_Lib.PcbLib; Height: 0.40MM; Library Path: Y:\MIS_DATABASE\Library\ALTIUM_TOOL\SCHEMATICS_PARTS\MS_DISCRETE_Library.schlib; Mfr_name: YAGEO AMERICA; Mfr_part_number: RC0402FR-0716K5L; Mistral Part No: 110020120011-R; Package: 0402; Part_type: RESISTORS\FIXED; Project: TI_AM243x LP EVM; RoHS: RoHS; Temperature: -55°C+155°C; Tolerance: 1%; Voltage: NA; Wattage: 1/16W; Weight: 0.65mg; Datasheet: Y:\MIS_DATABASE\DATASHEETS\RESISTORS\RCXXXXL-SER_MAR18.PDF
R156 R475 R647 = RESISTOR: RES 10K 1/20W 1% 0201; Chkd/date: VASANTHA/270117; Crtd /date: MANIRAJA/270117; Custom_Duty: 15%; Customs_HS_Code: 85332119; Distributor_name: DIGIKEY; Distributor_part_number: 311-10.0KMCT-ND; Footprint Path: Y:\MIS_DATABASE\Library\ALTIUM_TOOL\PCB_FOOTPRINTS\Altium_Footprint_Lib.PcbLib; Height: 0.26MM; Library Path: Y:\MIS_DATABASE\Library\ALTIUM_TOOL\SCHEMATICS_PARTS\MS_DISCRETE_Library.schlib; Mfr_name: YAGEO AMERICA; Mfr_part_number: RC0201FR-0710KL; Mistral Part No: 110011040018-R; Package: 0201; Part_type: RESISTORS\FIXED; Project: GOLDEN-I LITE; RoHS: RoHS; Temperature: -55°C+125°C; Tolerance: 1%; Voltage: NA; Wattage: 1/20W; Weight: 0.17mg; Datasheet: Y:\MIS_DATABASE\DATASHEETS\RESISTORS\RCXXXXL-SER_MAR18.PDF
R16 R17 R94 R165 R176 R199 R431 R650 R660 = RESISTOR: RES 10K 1/20W 5% 0201; Chkd/date: MANIRAJA/050517; Crtd /date: MANIRAJA/050517; Custom_Duty: 15%; Customs_HS_Code: 85332119; Distributor_name: DIGIKEY; Distributor_part_number: 311-10KNCT-ND; Footprint Path: Y:\MIS_DATABASE\Library\ALTIUM_TOOL\PCB_FOOTPRINTS\Altium_Footprint_Lib.PcbLib; Height: 0.26MM; Library Path: Y:\MIS_DATABASE\Library\ALTIUM_TOOL\SCHEMATICS_PARTS\MS_DISCRETE_Library.schlib; Mfr_name: YAGEO AMERICA; Mfr_part_number: RC0201JR-0710KL; Mistral Part No: 110010070051-R; Package: 0201; Part_type: RESISTORS\FIXED; Project: GOLDEN-I LITE; RoHS: RoHS; Temperature: -55°C+125°C; Tolerance: 5%; Voltage: NA; Wattage: 1/20W; Weight: 0.17mg; Datasheet: Y:\MIS_DATABASE\DATASHEETS\RESISTORS\RCXXXXL-SER_MAR18.PDF
U34 = TPD3S014D_SOT23-6: IC ESD PROTECTION FOR AUTO USB PORT WITH CURRENT LIMIT SWITCH SOT23-6; Chkd/date: MANIRAJA/180918; Crtd /date: ALVY/180918; Custom_Duty: 15%; Customs_HS_Code: 85423100; Distributor_name: DIGIKEY; Distributor_part_number: 296-44163-1-ND; Footprint Path: Y:\MIS_DATABASE\Library\ALTIUM_TOOL\PCB_FOOTPRINTS\Altium_Footprint_Lib.PcbLib; Height: 1.45MM; Library Path: Y:\MIS_DATABASE\Library\ALTIUM_TOOL\SCHEMATICS_PARTS\MS_MISCINTERFACE_Library.schlib; Mfr_name: TEXAS INSTRUMENTS; Mfr_part_number: TPD3S014TDBVRQ1; Mistral Part No: 141018090014-R; Package: SOT23-6; Part_type: ICS\INTERFACE; Project: TI_J7ES_EVM_CP; RoHS: RoHS; Temperature: -40°C+105°C; Tolerance: NA; Voltage: NA; Wattage: NA; Weight: NA; Datasheet: Y:\MIS_DATABASE\DATASHEETS\ICS\INTERFACE\TPD3S014-Q1.PDF
C8 C11 C129 C497 = CAP: CAP CERAMIC 0.1uF 16V 10% X5R 0201; Alt_Mfr_name: YAGEO AMERICA; Alt_Mfr_part_number: CC0402KRX5R8BB104; Chkd/date: MANIRAJA/230118; Crtd /date: MANIRAJA/230118; Custom_Duty: 15%; Customs_HS_Code: 85322990; Distributor_name: DIGIKEY; Distributor_part_number: 490-14305-1-ND; Footprint Path: Y:\MIS_DATABASE\Library\ALTIUM_TOOL\PCB_FOOTPRINTS\Altium_Footprint_Lib.PcbLib; Height: 0.33MM; Library Path: Y:\MIS_DATABASE\Library\ALTIUM_TOOL\SCHEMATICS_PARTS\MS_DISCRETE_Library.schlib; Mfr_name: MURATA; Mfr_part_number: GRM033R61C104KE14D; Mistral Part No: 120009030072-R; Package: 0201; Part_type: CAPACITORS\CERAMIC; Project: TI_MAXIE_CPB; RoHS: RoHS; Temperature: -55°C+85°C; Tolerance: 10%; Voltage: 16V; Wattage: NA; Weight: 0.33mg; Datasheet: Y:\MIS_DATABASE\DATASHEETS\CAPACITORS\GRM033R61C104KE14.PDF
C45 C408 C509 = CAP: CAP CERAMIC 0.1uF 50V 10% X7R 0402; Alt_Mfr_name: YAGEO AMERICA; Alt_Mfr_part_number: CC0402KRX5R8BB104; Chkd/date: MANIRAJA/261020; Crtd /date: ALVY/211020; Custom_Duty: 15%; Customs_HS_Code: 85322990; Distributor_name: DIGIKEY; Distributor_part_number: 490-10700-1-ND; Footprint Path: Y:\MIS_DATABASE\Library\ALTIUM_TOOL\PCB_FOOTPRINTS\Altium_Footprint_Lib.PcbLib; Height: 0.55MM; Library Path: Y:\MIS_DATABASE\Library\ALTIUM_TOOL\SCHEMATICS_PARTS\MS_DISCRETE_Library.schlib; Mfr_name: MURATA; Mfr_part_number: GRM155R71H104KE14D; Mistral Part No: 120011100014-R; Package: 0402; Part_type: CAPACITORS\CERAMIC; Project: J7_CP; RoHS: RoHS; Temperature: -55°C+125°C; Tolerance: 10%; Voltage: 50V; Wattage: NA; Weight: 3.1mg; Datasheet: Y:\MIS_DATABASE\DATASHEETS\CAPACITORS\GRM155R71H104KE14.PDF
FL10 FL21 = EMIFILTER_IND: IND FERRITE BEAD CHIP 120E 2A 0402; Chkd/date: NAVEED/241114; Crtd /date: USMAN/170613; Custom_Duty: 24%; Customs_HS_Code: 85369090; Distributor_name: DIGIKEY; Distributor_part_number: 490-9656-1-ND; Footprint Path: Y:\MIS_DATABASE\Library\ALTIUM_TOOL\PCB_FOOTPRINTS\Altium_Footprint_Lib.PcbLib; Height: 0.55MM; Library Path: Y:\MIS_DATABASE\Library\ALTIUM_TOOL\SCHEMATICS_PARTS\MS_FILTER_Library.schlib; Mfr_name: MURATA; Mfr_part_number: BLM15PX121SN1D; Mistral Part No: 130013060022-R; Package: 0402; Part_type: INDUCTOR; Project: GEN_3-8; RoHS: RoHS; Temperature: -55°C+125°C; Tolerance: 25%; Voltage: NA; Wattage: NA; Weight: 1mg; Datasheet: Y:\MIS_DATABASE\DATASHEETS\DISCRETES\INDUCTORS\BLM15-SN1-SER.PDF
J21 = CON_FLEX_40X1_SH4: CON FPC 1X40 0.50MM PITCH FEMALE ST SMD; Chkd/date: MANIRAJA/061021; Crtd /date: ALVY/041021; Custom_Duty: 24%; Customs_HS_Code: 85369090; Distributor_name: DIGIKEY; Distributor_part_number: 2073-FFC2A32-40-TCT-ND; Footprint Path: Y:\MIS_DATABASE\Library\ALTIUM_TOOL\PCB_FOOTPRINTS\Altium_Footprint_Lib.PcbLib; Height: 4.25MM; Library Path: Y:\MIS_DATABASE\Library\ALTIUM_TOOL\SCHEMATICS_PARTS\MS_CONNECTOR_Library.schlib; Mfr_name: GCT; Mfr_part_number: FFC2A32-40-T; Mistral Part No: 150021100004-R; Package: SMD; Part_type: CONNECTOR\FPC; Project: TI_AM62x SKEVM_BRD; RoHS: RoHS; Temperature: -25°C+85°C; Tolerance: NA; Voltage: NA; Wattage: NA; Weight: 710mg; Datasheet: Y:\MIS_DATABASE\DATASHEETS\CONNECTORS\FFC2A32.PDF
R684 = RESISTOR: RES 4.7K 1/20W 5% 0201; Chkd/date: MANIRAJA/200921; Crtd /date: ALVY/200921; Custom_Duty: 15%; Customs_HS_Code: 85332119; Distributor_name: DIGIKEY; Distributor_part_number: 311-4.7KNCT-ND; Footprint Path: Y:\MIS_DATABASE\Library\ALTIUM_TOOL\PCB_FOOTPRINTS\Altium_Footprint_Lib.PcbLib; Height: 0.26MM; Library Path: Y:\MIS_DATABASE\Library\ALTIUM_TOOL\SCHEMATICS_PARTS\MS_DISCRETE_Library.schlib; Mfr_name: YAGEO AMERICA; Mfr_part_number: RC0201JR-074K7L; Mistral Part No: 110021090007-R; Package: 0201; Part_type: RESISTORS\FIXED; Project: TI_AM62x SKEVM_BRD; RoHS: RoHS; Temperature: -55°C+125°C; Tolerance: 5%; Voltage: NA; Wattage: 1/20W; Weight: 0.17mg; Datasheet: Y:\MIS_DATABASE\DATASHEETS\RESISTORS\RCXXXXL-SER_MAR18.PDF
U3 = SN74AVC4T245DGVR_TVSOP16: IC 4-BIT DUAL SUPPLY BUS TRANSCEIVER TVSOP16; Chkd/date: SUHAS/251010; Crtd /date: MAZHAR/201109; Custom_Duty: 15%; Customs_HS_Code: 85423100; Distributor_name: DIGIKEY; Distributor_part_number: 296-18054-1-ND; Height: 1.20MM; Mfr_name: TEXAS INSTRUMENTS; Mistral Part No: 141009110005-P; Package: TVSOP16; Part_type: ICS\DIGITAL\COMBINATIONAL; Project: GOLDEN-I; RoHS: Sb/ Br FREE; Temperature: -40°C+85°C; Datasheet: Y:\MIS_DATABASE\DATASHEETS\ICS\DIGITAL\BUSTRANSCEIVER\SN74AVC4T245.PDF
U63 = SN74CB3Q3257PWR_TSSOP16: IC 4BIT 1-OF-2 FET MULTIPLEXER/DEMULTIPLEXER TSSOP16; Chkd/date: SUHAS/251010; Crtd /date: USMAN/060109; Custom_Duty: 15%; Customs_HS_Code: 85423100; Distributor_name: DIGIKEY; Distributor_part_number: 296-19138-1-ND; Height: 1.20MM; Mfr_name: TEXAS INSTRUMENTS; Mistral Part No: 141009030117-R; Package: TSSOP16; Part_type: ICS\DIGITAL\COMBINATIONAL; Project: OMAP_EVM; RoHS: Sb/ Br FREE; Temperature: -40°C+85°C; Datasheet: Y:\MIS_DATABASE\DATASHEETS\ICS\DIGITAL\COMBINATIONAL\SN74CB3Q3257.PDF
U99 = SN74LVC1G04DCKR_SC70-5: IC SINGLE INVERTER GATE X2SON5; Chkd/date: MANIRAJA/141020; Crtd /date: ALVY/131020; Custom_Duty: 15%; Customs_HS_Code: 85423100; Distributor_name: DIGIKEY; Distributor_part_number: 296-37758-1-ND; Footprint Path: Y:\MIS_DATABASE\Library\ALTIUM_TOOL\PCB_FOOTPRINTS\Altium_Footprint_Lib.PcbLib; Height: 0.40MM; Library Path: Y:\MIS_DATABASE\Library\ALTIUM_TOOL\SCHEMATICS_PARTS\MS_GATE_Library.schlib; Mfr_name: TEXAS INSTRUMENTS; Mistral Part No: 141020100010-R; Package: X2SON5; Part_type: ICS\DIGITAL\GATES; Project: AM64X_SKEVM; RoHS: RoHS; Temperature: -40°C+125°C; Tolerance: NA; Voltage: NA; Wattage: NA; Weight: 0.6mg; Datasheet: Y:\MIS_DATABASE\DATASHEETS\ICS\DIGITAL\GATES\SN74LVC1G04XX.PDF
U105 = SN74LVC1G08DBVRE4_SOT23-5: IC SINGLE 2-INPUT POSITIVE AND GATE SOT23-5; Chkd/date: SUHAS/221010; Crtd /date: USMAN/151008; Custom_Duty: 15%; Customs_HS_Code: 85423100; Distributor_name: DIGIKEY; Distributor_part_number: SN74LVC1G08DBVRE4-ND; Height: 1.45MM; Mfr_name: TEXAS INSTRUMENTS; Mistral Part No: 141009060026-R; Part_type: ICS\DIGITAL\GATES; Project: KHAN_MAIN; RoHS: Sb/ Br FREE; Temperature: -40°C+85°C; Datasheet: Y:\MIS_DATABASE\DATASHEETS\ICS\DIGITAL\GATES\SN74LVC1G08.PDF
C43 = CAP: CAP CERAMIC 10uF 10V 20% X5R 0402; Chkd/date: MANIRAJA/300520; Crtd /date: ALVY/260520; Custom_Duty: 15%; Customs_HS_Code: 85322990; Distributor_name: DIGIKEY; Distributor_part_number: 490-GRM155R61A106ME11DTR-ND; Footprint Path: Y:\MIS_DATABASE\Library\ALTIUM_TOOL\PCB_FOOTPRINTS\Altium_Footprint_Lib.PcbLib; Height: 0.55MM; Library Path: Y:\MIS_DATABASE\Library\ALTIUM_TOOL\SCHEMATICS_PARTS\MS_DISCRETE_Library.schlib; Mfr_name: MURATA; Mfr_part_number: GRM155R61A106ME11D; Mistral Part No: 120013110019-R; Package: 0402; Part_type: CAPACITORS\CERAMIC; Project: QCS610_NANOSOM; RoHS: RoHS; Temperature: -55°C+85°C; Tolerance: 20%; Voltage: 10V; Wattage: NA; Weight: 3.1mg; Datasheet: Y:\MIS_DATABASE\DATASHEETS\CAPACITORS\MURATA-GXX-SER_NOV17.PDF
J19 = CON_FLEX_15X1_1-1734248-5: CON FPC 1X15 1.00MM PITCH FEMALE ST SMD; Chkd/date: ALVY/030620; Crtd /date: ALVY/030620; Custom_Duty: 24%; Customs_HS_Code: 85369090; Distributor_name: DIGIKEY; Distributor_part_number: A101418CT-ND; Footprint Path: Y:\MIS_DATABASE\Library\ALTIUM_TOOL\PCB_FOOTPRINTS\Altium_Footprint_Lib.PcbLib; Height: 7.70MM; Library Path: Y:\MIS_DATABASE\Library\ALTIUM_TOOL\SCHEMATICS_PARTS\MS_CONNECTOR_Library.schlib; Mfr_name: TE CONNECTIVITY; Mfr_part_number: 1-1734248-5; Mistral Part No: 150020060004-R; Package: SMD; Part_type: CONNECTOR\FPC; Project: JETSON_CARRIER_BRD; RoHS: RoHS; Temperature: -20°C+85°C; Tolerance: NA; Voltage: NA; Wattage: NA; Weight: 612mg; Datasheet: Y:\MIS_DATABASE\DATASHEETS\CONNECTORS\1734248.PDF

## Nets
DGND: C8.1 C11.1 C43.2 C45.2 C115.2 C129.1 C355.2 C356.2 C371.2 C372.2 C408.1 C427.2 C497.1 C509.2 D1.1(A) D4.2(ANODE) D5.1(GND) D10.2(ANODE) D14.1(A) FL21.2 J7.4(GND) J13.A1(GND) J13.A12(GND) J13.B1(GND) J13.B12(GND) J19.1A J19.4A J19.7A J19.10A J21.6 J21.7 J21.10 J21.13 J21.16 J21.19 J21.22 J21.25 J21.28 J21.31 J21.34 J21.37 J21.40 LD12.1(CATHODE) LD16.1(CATHODE) Q1.4(S1) Q1.7(S2) Q3.4(S1) Q3.7(S2) Q20.4(S1) Q20.7(S2) R16.1 R67.1 R68.2 R69.2 R94.1 R156.2 R199.1 R219.2 R418.2 R431.1 R647.2 U3.8(GND1) U3.9(GND2) U34.2(GND) U63.8(GND) U78.1(GND) U78.2(GND) U78.3(GND) U78.7(GND) U99.3(GND) U105.3(GND) ; also on sheet 1 10 11 12 13 14 15 16 17 18 19 20 21 22 23 24 25 26 27 28 29 30 31 32 33 34 39 40 41 42 43
VBUS_5V0_TYPEA1: C355.1 C371.1 J7.1(VCC) R649.2 U34.4(OUT)
VBUS_TYPEC2: J13.A4(VBUS1) J13.A9(VBUS2) J13.B4(VBUS3) J13.B9(VBUS4) R152.2 R227.1 U78.4(IN1) U78.5(IN2) U78.6(IN3) ; also on sheet 10
VCC_1V8: C8.2 C509.1 R684.1 U3.16(VCCB) U105.5(VCC) ; also on sheet 12 13 14 18 19 21 25 34 39 40 42
VCC_3V3_SYS: C11.2 C43.1 C45.1 C129.2 C408.2 C497.2 FL10.2 J19.15A R17.2 R88.2 R165.1 R176.2 R188.2 R475.1 R614.2 R617.2 R650.1 R660.2 U3.1(VCCA) U63.16(VCC) U99.5(VCC) ; also on sheet 10 12 13 14 18 19 20 22 23 24 25 26 27 29 30 31 32 33 34 39 40 41 42 43
VCC_5V0: C115.1 C356.1 U34.3(IN) ; also on sheet 10 11 33 41
CH1_LVDS_A0N: J21.11 U12.AA5(OLDI0_A0N)
CH1_LVDS_A0P: J21.12 U12.Y6(OLDI0_A0P)
CH1_LVDS_A1N: J21.14 U12.AD3(OLDI0_A1N)
CH1_LVDS_A1P: J21.15 U12.AB4(OLDI0_A1P)
CH1_LVDS_A2N: J21.20 U12.Y8(OLDI0_A2N)
CH1_LVDS_A2P: J21.21 U12.AA8(OLDI0_A2P)
CH1_LVDS_A3N: J21.23 U12.AB6(OLDI0_A3N)
CH1_LVDS_A3P: J21.24 U12.AA7(OLDI0_A3P)
CH1_LVDS_CLKN: J21.17 U12.AD4(OLDI0_CLK0N)
CH1_LVDS_CLKP: J21.18 U12.AE3(OLDI0_CLK0P)
CH2_LVDS_A0N: J21.26 U12.AC6(OLDI0_A4N)
CH2_LVDS_A0P: J21.27 U12.AC5(OLDI0_A4P)
CH2_LVDS_A1N: J21.29 U12.AE5(OLDI0_A5N)
CH2_LVDS_A1P: J21.30 U12.AD6(OLDI0_A5P)
CH2_LVDS_A2N: J21.35 U12.AE6(OLDI0_A6N)
CH2_LVDS_A2P: J21.36 U12.AD7(OLDI0_A6P)
CH2_LVDS_A3N: J21.38 U12.AD8(OLDI0_A7N)
CH2_LVDS_A3P: J21.39 U12.AE7(OLDI0_A7P)
CH2_LVDS_CLKN: J21.32 U12.AE4(OLDI0_CLK1N)
CH2_LVDS_CLKP: J21.33 U12.AD5(OLDI0_CLK1P)
CSI0_RXCLKN: J19.8A U12.AD15(CSI0_RXCLKN)
CSI0_RXCLKP: J19.9A U12.AE15(CSI0_RXCLKP)
CSI0_RXN0: J19.2A U12.AB14(CSI0_RXN0)
CSI0_RXN1: J19.5A U12.AD14(CSI0_RXN1)
CSI0_RXP0: J19.3A U12.AC15(CSI0_RXP0)
CSI0_RXP1: J19.6A U12.AE14(CSI0_RXP1)
CSI_GPIO1: J19.11A ; also on sheet 39
CSI_GPIO2: J19.12A ; also on sheet 39
CSI_I2C2_SCL: J19.13A ; also on sheet 33
CSI_I2C2_SDA: J19.14A ; also on sheet 33
EEPROM_VDD: FL10.1 J21.1
EXP_SPI2_CLK: U63.5(2B1) ; also on sheet 33
EXP_SPI2_CS0/EHRPWM0_A: U63.2(1B1) ; also on sheet 33
EXP_SPI2_D0: U63.11(3B1) ; also on sheet 33
EXP_SPI2_D1/ECAP2_IN_APWM_OUT: U63.14(4B1) ; also on sheet 33
GPIO_TS_RSTn: R475.2 U105.1(A) ; also on sheet 39
IO_EXP_TEST_LED: R198.1 R199.2 ; also on sheet 39
LVDS_SHIELD: FL21.1 J21.SH1 J21.SH2 J21.SH3 J21.SH4
OLDI_RESETn: J21.8 R684.2 U105.4(Y)
PMIC_PGOOD: R616.1 ; also on sheet 13 42
RESETSTATz: U105.2(B) ; also on sheet 13 19 20 21 23 24 27 32 33 39 40 41 42
SOC_GPIO1_49: R94.2 R95.1 ; also on sheet 19
SoC_I2C0_SCL: J21.2 ; also on sheet 10 13 22 32 33 42
SoC_I2C0_SDA: J21.3 ; also on sheet 10 13 22 32 33 42
SOC_SPI2_CLK: U3.6(2A1) U63.7(2A) ; also on sheet 33
SOC_SPI2_CS0: U3.4(1A1) U63.4(1A) ; also on sheet 33
SOC_SPI2_D0: U3.5(1A2) U63.9(3A) ; also on sheet 33
SOC_SPI2_D1: U3.7(2A2) U63.12(4A) ; also on sheet 33
SOC_UART1_CTS: U63.10(3B2) ; also on sheet 31
SOC_UART1_CTS_BT_1V8: U3.12(1B2) ; also on sheet 18
SOC_UART1_RTS: U63.13(4B2) ; also on sheet 31
SOC_UART1_RTS_BT_1V8: U3.10(2B2) ; also on sheet 18
SOC_UART1_RX_BT_1V8: U3.13(1B1) ; also on sheet 18
SOC_UART1_RXD: U63.3(1B2) ; also on sheet 31
SOC_UART1_TX_BT_1V8: U3.11(2B1) ; also on sheet 18
SOC_UART1_TXD: U63.6(2B2) ; also on sheet 31
SoC_USB0_DM: L10.4(OUT2) U12.AE11(USB0_DM)
SoC_USB0_DP: L10.1(IN1) U12.AD11(USB0_DP)
SoC_USB0_DRVVBUS: U12.C20(USB0_DRVVBUS) ; also on sheet 10
SoC_USB0_VBUS: R153.1 R156.1 U12.AC11(USB0_VBUS)
SoC_USB1_DM: L9.1(IN1) U12.AD10(USB1_DM)
SoC_USB1_DP: L9.4(OUT2) U12.AE9(USB1_DP)
SoC_USB1_DRVVBUS: R650.2 U12.F18(USB1_DRVVBUS) U34.1(EN)
SoC_USB1_VBUS: R647.1 R648.1 U12.AB10(USB1_VBUS)
TS_INT#: J21.9 R165.2 ; also on sheet 39
UART1_FET_BUF_EN: R660.1 U3.14(~{2OE}) U3.15(~{1OE}) U99.2(A) ; also on sheet 39
UART1_FET_BUF_EN_INV: U63.15(~{OE}) U99.4(Y)
UART1_FET_SEL: R176.1 R431.2 U63.1(S) ; also on sheet 39
USB0_TYPEACONN1_DM: J7.2(D-) L9.2(IN2) U34.5(D1)
USB0_TYPEACONN1_DP: J7.3(D+) L9.3(OUT1) U34.6(D2)
USB_TYPEA_EARTH: C372.1 J7.SH1 J7.SH2 R418.1
USB_TYPEC2_EARTH: C427.1 J13.SH1 J13.SH2 J13.SH3 J13.SH4 R219.1
USBC_CONN2_CC1: D4.1(CATHODE) J13.A5(CC1) ; also on sheet 10
USBC_CONN2_CC2: D10.1(CATHODE) J13.B5(CC2) ; also on sheet 10
USBC_CONN2_DM: D5.3(IO2) J13.A7(D-_1) J13.B7(D-_2) L10.3(OUT1)
USBC_CONN2_DP: D5.2(IO1) J13.A6(D+_1) J13.B6(D+_2) L10.2(IN2)
N16925380: R67.2 U12.AA14(CSI0_RXRCALIB)
N17031262: LD12.2(ANODE) R227.2
N17726648: D1.3(C) R152.1 R153.2
N18904630: LD1.1(CATHODE) Q1.1(D1) Q1.2(D2) Q1.5(D3) Q1.6(D4) Q1.8(D5)
N18904632: Q1.3(G) R95.2
N18904656: LD1.2(ANODE) R88.1
N18904815: LD11.1(CATHODE) Q3.1(D1) Q3.2(D2) Q3.5(D3) Q3.6(D4) Q3.8(D5)
N18904817: Q3.3(G) R198.2
N18904841: LD11.2(ANODE) R188.1
N19738714: LD16.2(ANODE) R614.1
N19738757: LD17.1(CATHODE) Q20.1(D1) Q20.2(D2) Q20.5(D3) Q20.6(D4) Q20.8(D5)
N19738770: Q20.3(G) R616.2
N19738786: LD17.2(ANODE) R617.1
N19880817: R68.1 U12.AC9(USB1_RCALIB)
N19880821: R69.1 U12.AE10(USB0_RCALIB)
N19885322: D14.3(C) R648.2 R649.1
N20704463: R16.2 U3.2(1DIR)
N20704480: R17.1 U3.3(2DIR)

Not connected (* = marked no-connect by the designer): D1 2(NC)*; D14 2(NC)*; J13 A2(TX1+)* A3(TX1-)* A8(SBU1)* A10(RX2-)* A11(RX2+)* B2(TX2+)* B3(TX2-)* B8(SBU2)* B10(RX1-)* B11(RX1+)*; J19 1B* 2B* 3B* 4B* 5B* 6B* 7B* 8B* 9B* 10B* 11B* 12B* 13B* 14B* 15B*; J21 4* 5*; U12 AA12(RSVD6)* AB12(CSI0_RXN3)* AC13(CSI0_RXP3)* AD13(CSI0_RXN2)* AE13(CSI0_RXP2)* Y15(RSVD7)*; U99 1(NC)*

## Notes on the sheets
sheet 35
- USB0 TYPE-C DRP
- Silk: TYPE-C DRP
- 90E
- DLW21SZ900HQ2B
- POWER INDICATION LED: VBUS_TYPEC2
- POWER RAIL LEDS
sheet 36
- USB1 TYPE-A
- 90E
- 90E
- DLW21SZ900HQ2B
- Silk: TYPE-A
- Note: Recommended VBUS circuit for USB connector. Supports 5V-30V VBUS
- Note: Recommended VBUS circuit for SoC_USB1_VBUS
sheet 37
- OLDI DISPLAY INTERFACE
- 100E
- 100E
- 100E
- OLDI RESET
- 100E
- 100E
- 100E
- 100E
- 100E
- 100E
- 100E
- SoC UART1 FET SWITCH & BUFFER
- SoC_MAIN_UART1_RXD
- SoC_MAIN_UART1_CTS
- SoC_MAIN_UART1_TXD
- SoC_MAIN_UART1_RTS
- DIR=H : A ->B
  DIR=L : B ->A
- INPUT/OUTPUT
- OEn
- SEL
- An
- L
- H(DEFAULT)
- An=nB2
- FT4232
- L
- L
- An=nB1
- EXP CONN
sheet 38
- CSI INTERFACE
- CSI CAMERA HEADER
- 100E
- 100E
- 100E
- Reserved Pins
- Silk: CSI
- USER TEST LEDS
- SoC GPIO
- IO EXP GPIO
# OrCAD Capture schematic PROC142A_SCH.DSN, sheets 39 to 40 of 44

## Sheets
39 39. IO EXPANDER: size C; title: IO EXPANDER
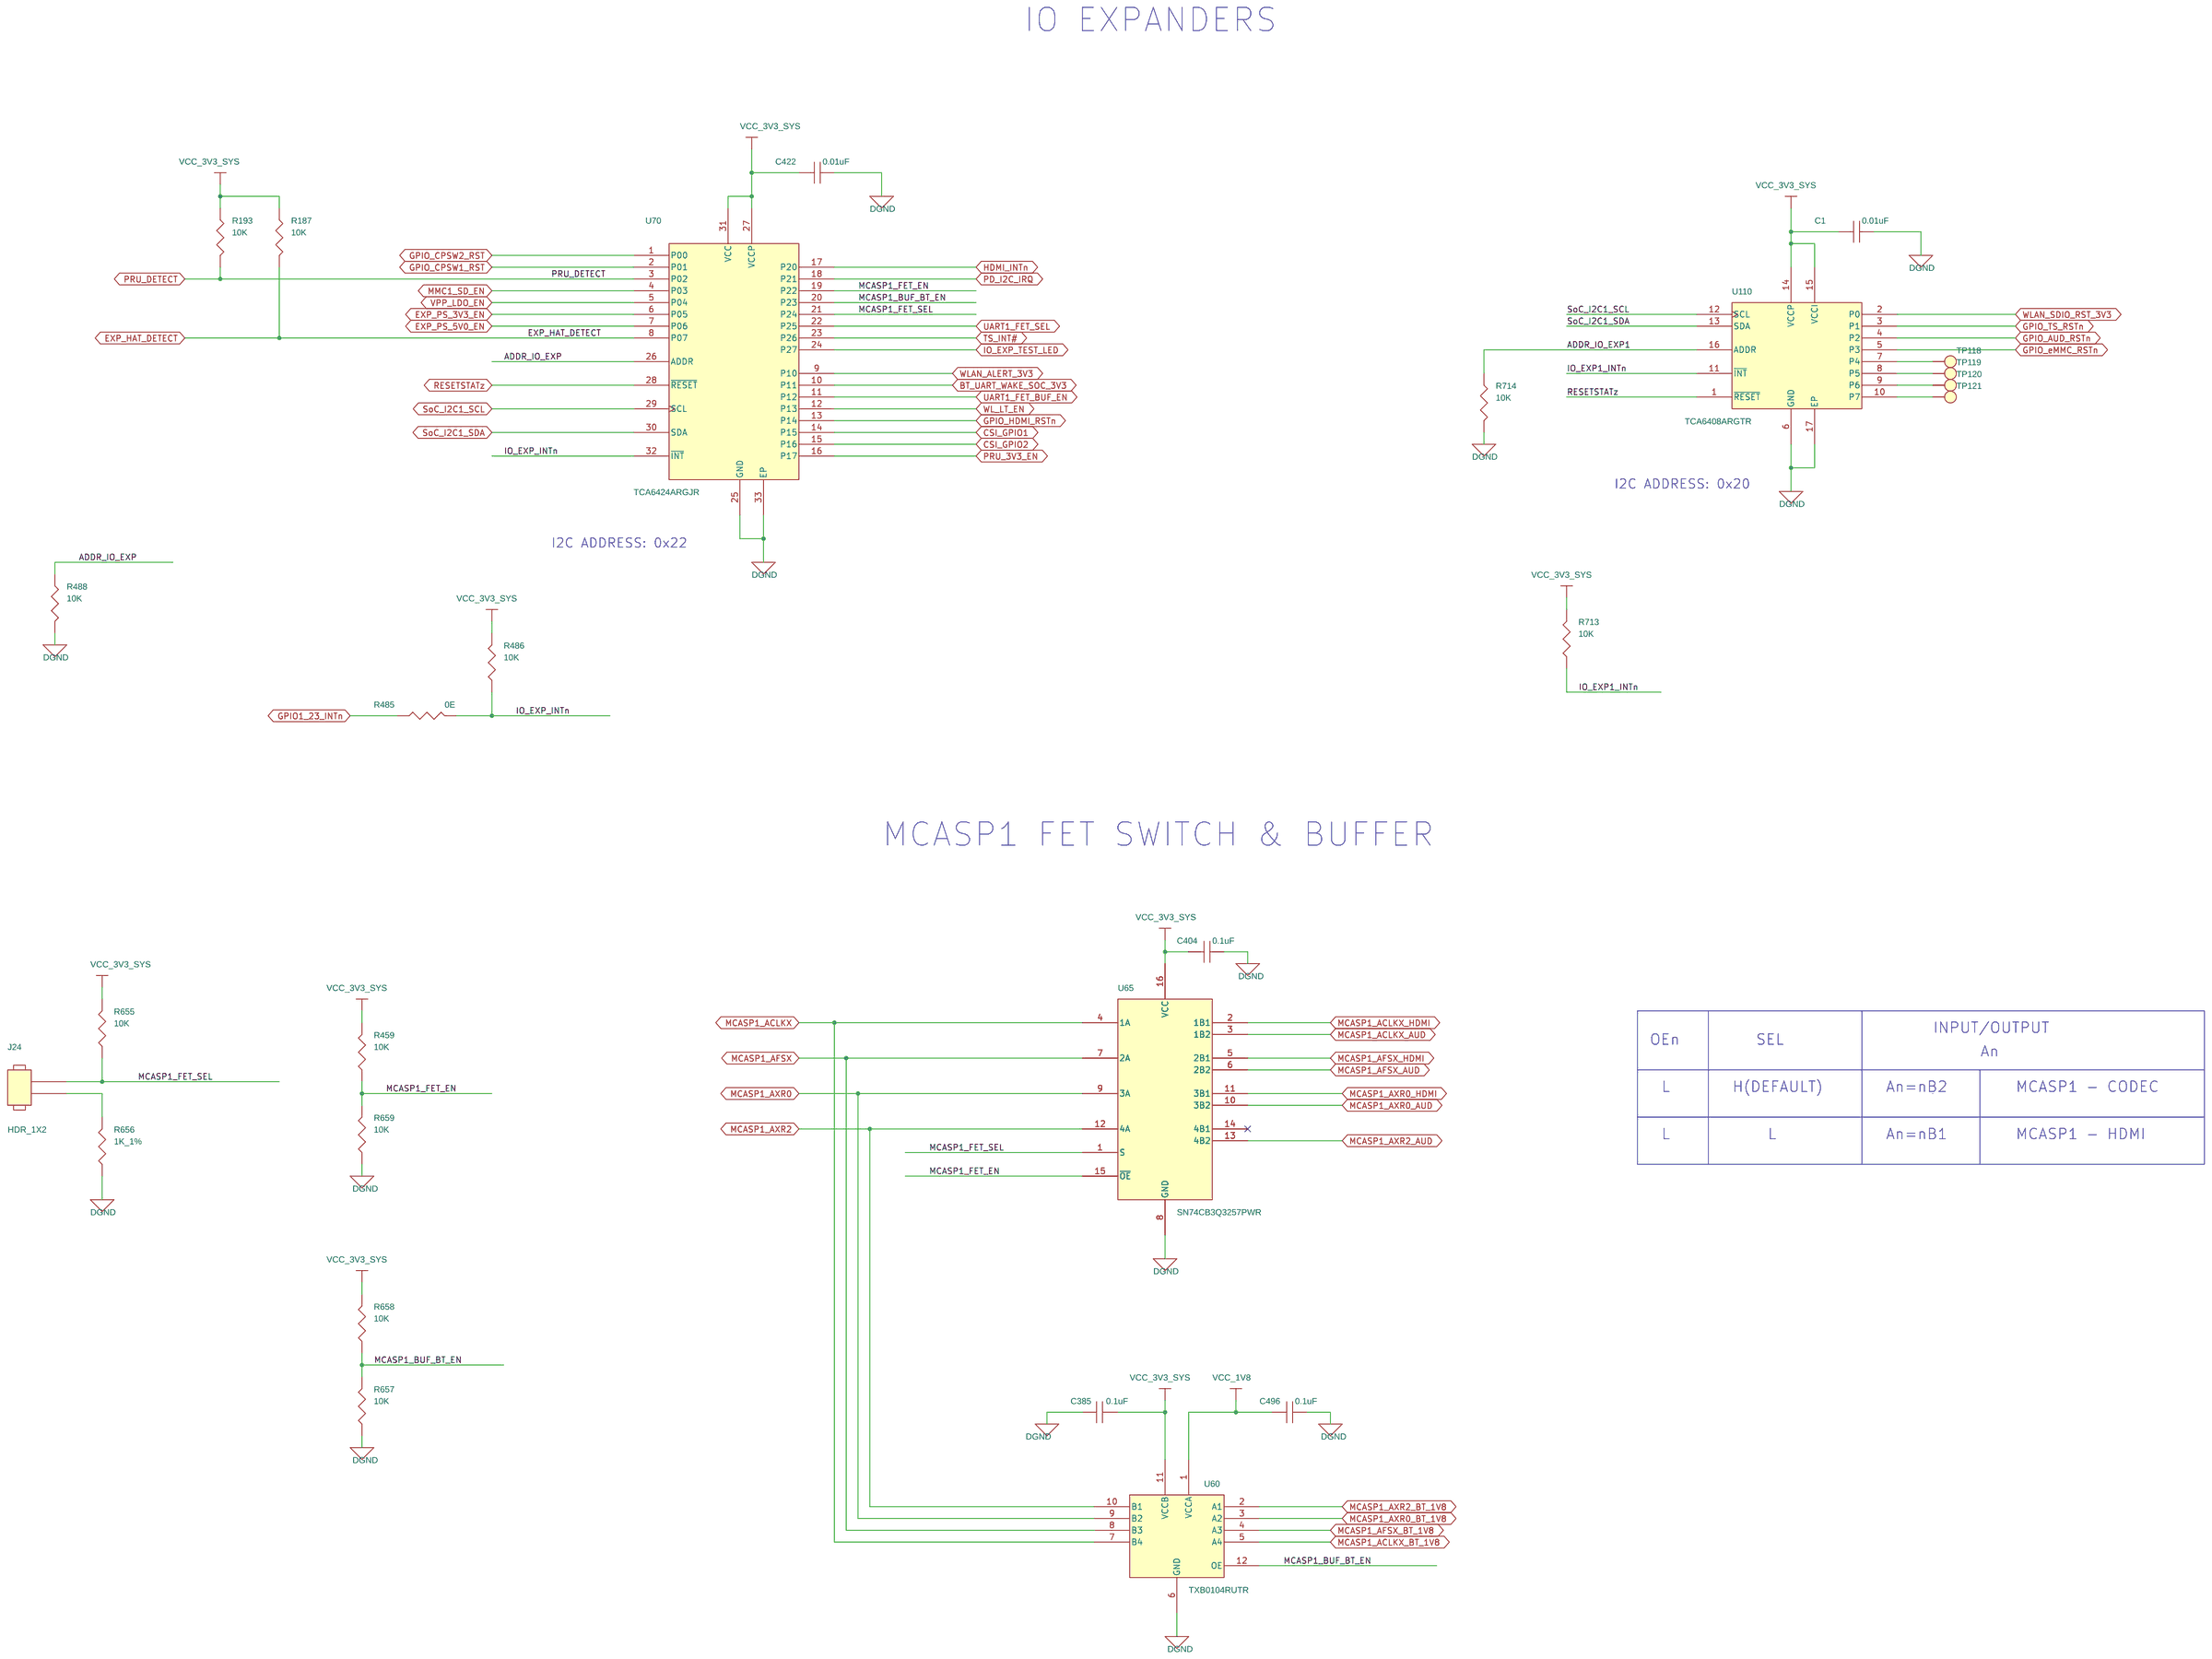
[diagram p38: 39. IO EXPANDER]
40 40. AUDIO CODEC: size C; title: AUDIO CODEC

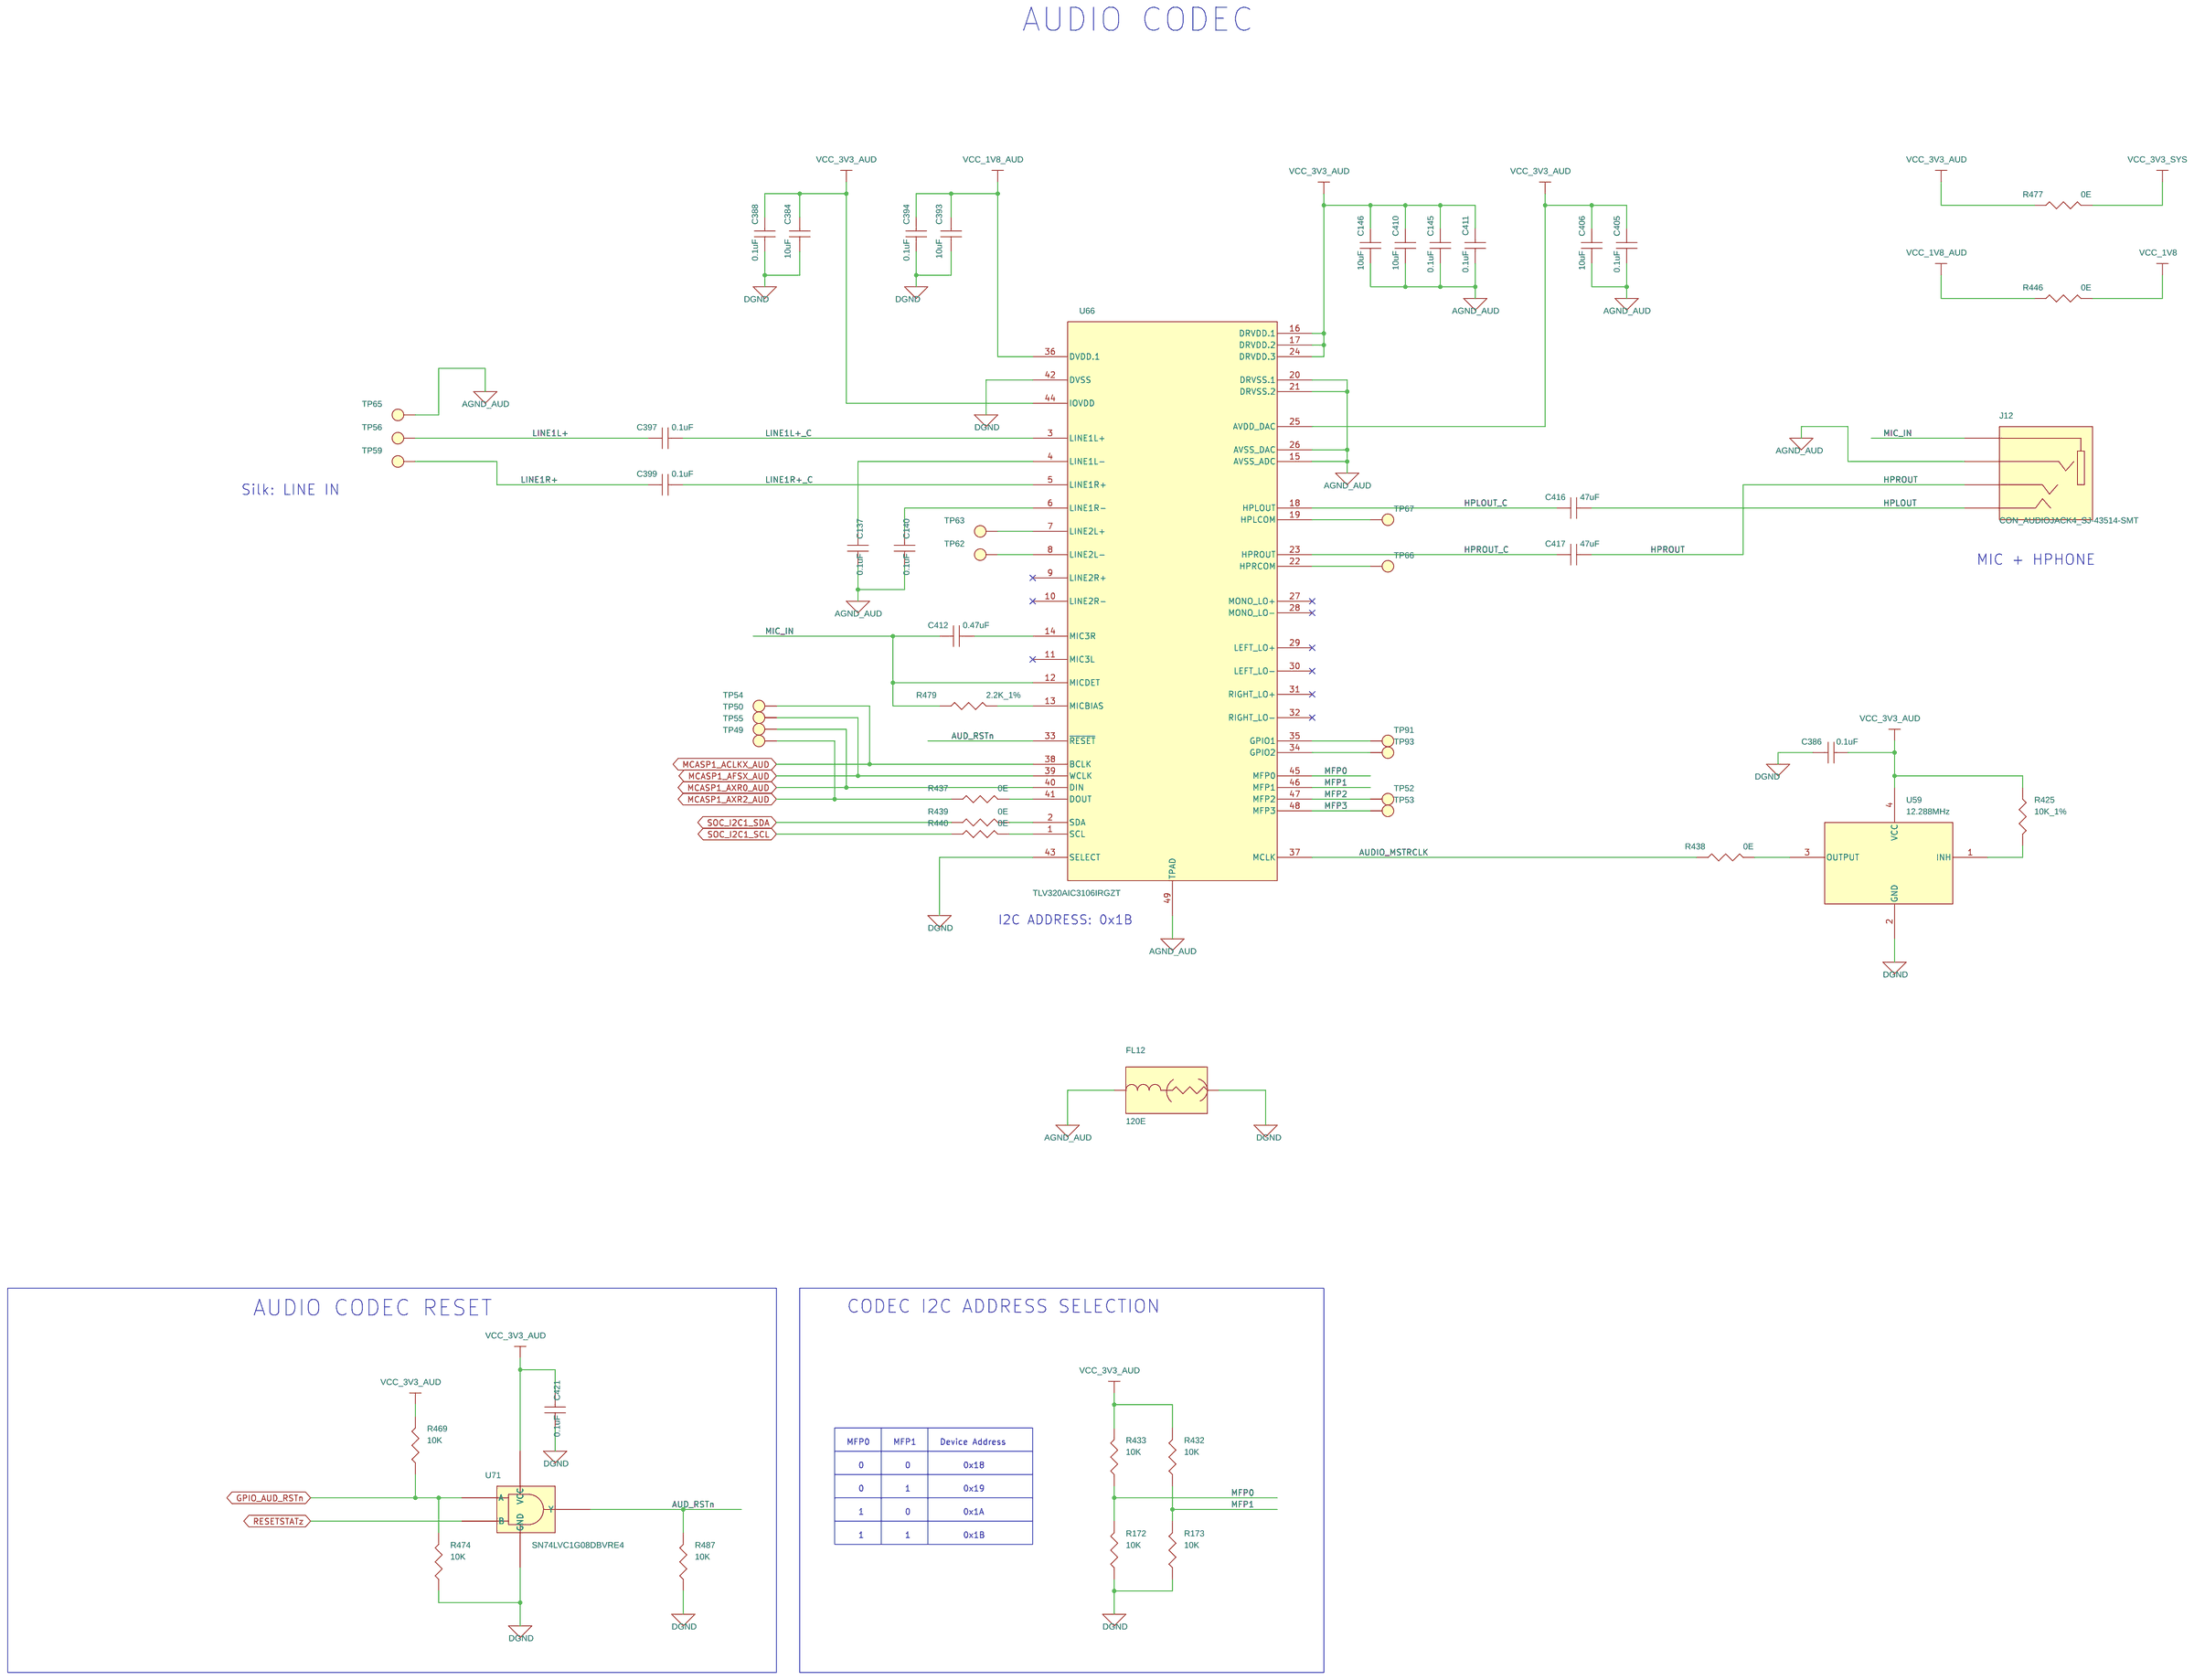
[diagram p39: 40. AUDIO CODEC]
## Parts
sheet 39. IO EXPANDER
C1  0.01uF  [CAP0201_0-5]
C385  0.1uF  [CAP0201_0-5]
C404  0.1uF  [CAP0201_0-5]
C422  0.01uF  [CAP0201_0-5]
C496  0.1uF  [CAP0201_0-5]
J24  HDR_1X2  [HDR_1X2_90120-0122_S_T_5-6]
R187  10K  [RES0201_0-5]
R193  10K  [RES0201_0-5]
R459  10K  [RES0201_0-5]
R485  0E  [RES0402_0-5]
R486  10K  [RES0201_0-5]
R488  10K  [RES0201_0-5]
R655  10K  [RES0201_0-5]
R656  1K_1%  [RES0402_0-5]
R657  10K  [RES0201_0-5]
R658  10K  [RES0201_0-5]
R659  10K  [RES0201_0-5]
R713  10K  [RES0201_0-5]
R714  10K  [RES0201_0-5]
TP118  TP20_SMD  [TP20_SMD]
TP119  TP20_SMD  [TP20_SMD]
TP120  TP20_SMD  [TP20_SMD]
TP121  TP20_SMD  [TP20_SMD]
U60  TXB0104RUTR  [UQFN12_TXB0104RUT_70X80_0-6]
U65  SN74CB3Q3257PWR  [TSSOP16_25-59_205X180]
U70  TCA6424ARGJR  [QFN32_19-68_200X200]
U110  TCA6408ARGTR  [QFN16_19-68_120X120_1_EP1-6]
sheet 40. AUDIO CODEC
C137  0.1uF  [CAP0201_0-5]
C140  0.1uF  [CAP0201_0-5]
C145  0.1uF  [CAP0201_0-5]
C146  10uF  [CAP0402_0-75]
C384  10uF  [CAP0402_0-75]
C386  0.1uF  [CAP0201_0-5]
C388  0.1uF  [CAP0201_0-5]
C393  10uF  [CAP0402_0-75]
C394  0.1uF  [CAP0201_0-5]
C397  0.1uF  [CAP0402_0-75]
C399  0.1uF  [CAP0402_0-75]
C405  0.1uF  [CAP0201_0-5]
C406  10uF  [CAP0402_0-75]
C410  10uF  [CAP0402_0-75]
C411  0.1uF  [CAP0201_0-5]
C412  0.47uF  [CAP0402_0-75]
C416  47uF  [CAP1206_2]
C417  47uF  [CAP1206_2]
C421  0.1uF  [CAP0402_0-75]
FL12  120E  [EMIFIL_BLM15A_0402_0-6]
J12  CON_AUDIOJACK4_SJ-43514-SMT  [CON_AV4_SJ-43514-SMT_S_R_S_5-1]
R172  10K  [RES0201_0-5]
R173  10K  [RES0201_0-5]
R425  10K_1%  [RES0201_0-5]
R432  10K  [RES0201_0-5]
R433  10K  [RES0201_0-5]
R437  0E  [RES0201_0-5]
R438  0E  [RES0201_0-5]
R439  0E  [RES0201_0-5]
R440  0E  [RES0201_0-5]
R446  0E  [RES0201_0-5]
R469  10K  [RES0201_0-5]
R474  10K  [RES0201_0-5]
R477  0E  [RES0201_0-5]
R479  2.2K_1%  [RES0201_0-5]
R487  10K  [RES0201_0-5]
TP49  TP20_SMD  [TP20_SMD]
TP50  TP20_SMD  [TP20_SMD]
TP52  TP20_SMD  [TP20_SMD]
TP53  TP20_SMD  [TP20_SMD]
TP54  TP20_SMD  [TP20_SMD]
TP55  TP20_SMD  [TP20_SMD]
TP56  THRU HOLE  [TP_40X65]
TP59  THRU HOLE  [TP_40X65]
TP62  TP20_SMD  [TP20_SMD]
TP63  TP20_SMD  [TP20_SMD]
TP65  THRU HOLE  [TP_40X65]
TP66  TP20_SMD  [TP20_SMD]
TP67  TP20_SMD  [TP20_SMD]
TP91  TP20_SMD  [TP20_SMD]
TP93  TP20_SMD  [TP20_SMD]
U59  12.288MHz  [OSC4_KC2520B_100X80_SMD_0-8]
U66  TLV320AIC3106IRGZT  [VQFN48_19-68_285X285]
U71  SN74LVC1G08DBVRE4  [SOT23-5]

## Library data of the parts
C1 C422 = CAP: CAP CERAMIC 0.01uF 25V 10% X5R 0201; Chkd/date: MANIRAJA/230118; Crtd /date: MANIRAJA/230118; Custom_Duty: 15%; Customs_HS_Code: 85322990; Distributor_name: DIGIKEY; Distributor_part_number: GRM033R61E103KA12J-ND; Footprint Path: Y:\MIS_DATABASE\Library\ALTIUM_TOOL\PCB_FOOTPRINTS\Altium_Footprint_Lib.PcbLib; Height: 0.33MM; Library Path: Y:\MIS_DATABASE\Library\ALTIUM_TOOL\SCHEMATICS_PARTS\MS_DISCRETE_Library.schlib; Mfr_name: MURATA; Mfr_part_number: GRM033R61E103KA12J; Mistral Part No: 120018010007-R; Package: 0201; Part_type: CAPACITORS\CERAMIC; Project: TI_MAXIE_CPB; RoHS: RoHS; Temperature: -55°C+85°C; Tolerance: 10%; Voltage: 25V; Wattage: NA; Weight: 0.33mg; Datasheet: Y:\MIS_DATABASE\DATASHEETS\CAPACITORS\GRM033R61E103KA12.PDF
C385 C404 C496 = CAP: CAP CERAMIC 0.1uF 16V 10% X5R 0201; Alt_Mfr_name: YAGEO AMERICA; Alt_Mfr_part_number: CC0402KRX5R8BB104; Chkd/date: MANIRAJA/230118; Crtd /date: MANIRAJA/230118; Custom_Duty: 15%; Customs_HS_Code: 85322990; Distributor_name: DIGIKEY; Distributor_part_number: 490-14305-1-ND; Footprint Path: Y:\MIS_DATABASE\Library\ALTIUM_TOOL\PCB_FOOTPRINTS\Altium_Footprint_Lib.PcbLib; Height: 0.33MM; Library Path: Y:\MIS_DATABASE\Library\ALTIUM_TOOL\SCHEMATICS_PARTS\MS_DISCRETE_Library.schlib; Mfr_name: MURATA; Mfr_part_number: GRM033R61C104KE14D; Mistral Part No: 120009030072-R; Package: 0201; Part_type: CAPACITORS\CERAMIC; Project: TI_MAXIE_CPB; RoHS: RoHS; Temperature: -55°C+85°C; Tolerance: 10%; Voltage: 16V; Wattage: NA; Weight: 0.33mg; Datasheet: Y:\MIS_DATABASE\DATASHEETS\CAPACITORS\GRM033R61C104KE14.PDF
J24 = HEADER_2X1: CON HDR 1X2 2.54MM PITCH ST TH; Chkd/date: NAVEED/210714; Crtd /date: USMAN/031012; Custom_Duty: 24%; Customs_HS_Code: 85369090; Distributor_name: DIGIKEY; Distributor_part_number: WM8072-ND; Footprint Path: Y:\MIS_DATABASE\Library\ALTIUM_TOOL\PCB_FOOTPRINTS\Altium_Footprint_Lib.PcbLib; Height: 5.60MM; Library Path: Y:\MIS_DATABASE\Library\ALTIUM_TOOL\SCHEMATICS_PARTS\MS_CONNECTOR_Library.schlib; Mfr_name: MOLEX; Mfr_part_number: 90120-0122; Mistral Part No: 150012100005-R; Package: THRU-HOLE; Part_type: CONNECTOR\HEADERS; Project: NPOL_FEP; RoHS: RoHS; Temperature: -55°C+125°C; Tolerance: NA; Voltage: NA; Wattage: NA; Weight: 122mg; Datasheet: Y:\MIS_DATABASE\DATASHEETS\CONNECTORS\90120-XX.PDF
R172 R173 R187 R193 R432 R433 R459 R469 R474 R486-R488 R655 R657-R659 R713 R714 = RESISTOR: RES 10K 1/20W 5% 0201; Chkd/date: MANIRAJA/050517; Crtd /date: MANIRAJA/050517; Custom_Duty: 15%; Customs_HS_Code: 85332119; Distributor_name: DIGIKEY; Distributor_part_number: 311-10KNCT-ND; Footprint Path: Y:\MIS_DATABASE\Library\ALTIUM_TOOL\PCB_FOOTPRINTS\Altium_Footprint_Lib.PcbLib; Height: 0.26MM; Library Path: Y:\MIS_DATABASE\Library\ALTIUM_TOOL\SCHEMATICS_PARTS\MS_DISCRETE_Library.schlib; Mfr_name: YAGEO AMERICA; Mfr_part_number: RC0201JR-0710KL; Mistral Part No: 110010070051-R; Package: 0201; Part_type: RESISTORS\FIXED; Project: GOLDEN-I LITE; RoHS: RoHS; Temperature: -55°C+125°C; Tolerance: 5%; Voltage: NA; Wattage: 1/20W; Weight: 0.17mg; Datasheet: Y:\MIS_DATABASE\DATASHEETS\RESISTORS\RCXXXXL-SER_MAR18.PDF
R485 = RESISTOR: RES 0E 1/16W JUMPER 0402; Chkd/date: VASANTHA/201216; Crtd /date: MUDDU/190810; Custom_Duty: 15%; Customs_HS_Code: 85332119; Distributor_name: DIGIKEY; Distributor_part_number: 541-0.0JCT-ND; Footprint Path: Y:\MIS_DATABASE\Library\ALTIUM_TOOL\PCB_FOOTPRINTS\Altium_Footprint_Lib.PcbLib; Height: 0.40MM; Library Path: Y:\MIS_DATABASE\Library\ALTIUM_TOOL\SCHEMATICS_PARTS\MS_DISCRETE_Library.schlib; Mfr_name: VISHAY; Mfr_part_number: CRCW04020000Z0ED; Mistral Part No: 110010080019-R; Package: 0402; Part_type: RESISTORS\FIXED; Project: PB_BUGBASE; RoHS: RoHS; Temperature: -55°C+155°C; Tolerance: NA; Voltage: NA; Wattage: 1/16W; Weight: 0.65mg; Datasheet: Y:\MIS_DATABASE\DATASHEETS\RESISTORS\CRCW0603.PDF
R656 = RESISTOR: RES 1K 1/10W 1% 0402; Chkd/date: VASANTHA/281216; Crtd /date: MAZHAR/150506; Custom_Duty: 15%; Customs_HS_Code: 85332119; Distributor_name: DIGIKEY; Distributor_part_number: P1.00KLCT-ND; Footprint Path: Y:\MIS_DATABASE\Library\ALTIUM_TOOL\PCB_FOOTPRINTS\Altium_Footprint_Lib.PcbLib; Height: 0.40MM; Library Path: Y:\MIS_DATABASE\Library\ALTIUM_TOOL\SCHEMATICS_PARTS\MS_DISCRETE_Library.schlib; Mfr_name: PANASONIC-ECG; Mfr_part_number: ERJ-2RKF1001X; Mistral Part No: 110009030411-R; Package: 0402; Part_type: RESISTORS\FIXED; Project: VOCERA; RoHS: RoHS; Temperature: -55°C+155°C; Tolerance: 1%; Voltage: NA; Wattage: 1/10W; Weight: 0.8mg; Datasheet: Y:\MIS_DATABASE\DATASHEETS\RESISTORS\PAN-ERJSER_NOV17.PDF
TP49 TP50 TP52-TP55 TP62 TP63 TP66 TP67 TP91 TP93 TP118-TP121 = TESTPOINT: TESTPOINT CIR 20 SMD; Chkd/date: SHREESHAIL/171006; Crtd /date: MAZHAR/171006; Custom_Duty: NA; Customs_HS_Code: NA; Distributor_name: NA; Distributor_part_number: NA; Footprint Path: Y:\MIS_DATABASE\Library\ALTIUM_TOOL\PCB_FOOTPRINTS\Altium_Footprint_Lib.PcbLib; Height: NA; Library Path: Y:\MIS_DATABASE\Library\ALTIUM_TOOL\SCHEMATICS_PARTS\MS_DISCRETE_Library.schlib; MECHANICAL 3D STEP FILE: NA; Mfr_name: LOCAL; Mistral Part No: NA; Package: SMD; Project: BT MODULE_CSRBC04; RoHS: NA; Temperature: NA; Tolerance: NA; Voltage: NA; Wattage: NA; Weight: NA; Datasheet: NA
U60 = TXB0104RUTR_UQFN12: IC 4-BIT BIDIRECTIONAL VOLTAGE-LEVEL TRANSLATOR UQFN12; Chkd/date: MANIRAJA/281117; Crtd /date: ALVY/271117; Custom_Duty: 15%; Customs_HS_Code: 85423100; Distributor_name: DIGIKEY; Distributor_part_number: 296-25888-1-ND; Height: 0.55MM; Manufacturer: TEXAS INSTRUMENTS; Mistral Part No: 141017110007-R; Package: UQFN12; Part_type: ICS\INTERFACE\LEVEL TRANSLATOR; Project: RSAPR_TYPE-II_3U-SBC; RoHS: RoHS; Temperature: -40°C+85°C; Tolerance: NA; Voltage: NA; Wattage: NA; Weight: 4.70mg; Datasheet: Y:\MIS_DATABASE\DATASHEETS\ICS\INTERFACE\TXB0104.PDF
U65 = SN74CB3Q3257PWR_TSSOP16: IC 4BIT 1-OF-2 FET MULTIPLEXER/DEMULTIPLEXER TSSOP16; Chkd/date: SUHAS/251010; Crtd /date: USMAN/060109; Custom_Duty: 15%; Customs_HS_Code: 85423100; Distributor_name: DIGIKEY; Distributor_part_number: 296-19138-1-ND; Height: 1.20MM; Manufacturer: TEXAS INSTRUMENTS; Mistral Part No: 141009030117-R; Package: TSSOP16; Part_type: ICS\DIGITAL\COMBINATIONAL; Project: OMAP_EVM; RoHS: Sb/ Br FREE; Temperature: -40°C+85°C; Datasheet: Y:\MIS_DATABASE\DATASHEETS\ICS\DIGITAL\COMBINATIONAL\SN74CB3Q3257.PDF
U70 = TCA6424ARGJR_QFN32: IC I2C I/O EXPANDER 24B UQFN32; Chkd/date: NAVEED/100715; Crtd /date: NAVEED/100914; Custom_Duty: 15%; Customs_HS_Code: 85423100; Distributor_name: DIGIKEY; Distributor_part_number: 296-27844-1-ND; Height: 0.60MM; Mfr_name: TEXAS INSTRUMENTS; Mistral Part No: 141014090009-R; Package: UQFN32; Part_type: ICS\DIGITAL\BUSTRANSCEIVER; Project: ZK_BIOMETRIC; RoHS: RoHS; Temperature: -40°C+85°C; Weight: NA; Datasheet: Y:\MIS_DATABASE\DATASHEETS\ICS\DIGITAL\BUSTRANSCEIVER\TCA6424AR.PDF
U110 = TCA6408ARGTR_VQFN16: IC 8-BIT I2C AND SMBUS I/O EXPANDER WITH INTERRUPT O/P VQFN16; Chkd/date: MANIRAJA/151018; Crtd /date: MANIRAJA/151018; Custom_Duty: 15%; Customs_HS_Code: 85423100; Distributor_name: DIGIKEY; Distributor_part_number: 296-24825-1-ND; Footprint Path: Y:\MIS_DATABASE\Library\ALTIUM_TOOL\PCB_FOOTPRINTS\Altium_Footprint_Lib.PcbLib; Height: 1.00MM; Library Path: Y:\MIS_DATABASE\Library\ALTIUM_TOOL\SCHEMATICS_PARTS\MS_MISCINTERFACE_Library.schlib; Mfr_name: TEXAS INSTRUMENTS; Mistral Part No: 141018100011-R; Package: VQFN16; Part_type: ICS\INTERFACE; Project: TI_60GHz-AOP; RoHS: RoHS; Temperature: -40°C+85°C; Tolerance: NA; Voltage: NA; Wattage: NA; Weight: 24.1mg; Datasheet: Y:\MIS_DATABASE\DATASHEETS\ICS\INTERFACE\TCA6408AXX.PDF
C137 C140 C145 C386 C388 C394 C405 C411 = CAP: CAP CERAMIC 0.1uF 16V 10% X5R 0201; Chkd/date: MANIRAJA/230118; Crtd /date: MANIRAJA/230118; Custom_Duty: 15%; Customs_HS_Code: 85322990; Distributor_name: DIGIKEY; Distributor_part_number: 490-14305-1-ND; Footprint Path: Y:\MIS_DATABASE\Library\ALTIUM_TOOL\PCB_FOOTPRINTS\Altium_Footprint_Lib.PcbLib; Height: 0.33MM; Library Path: Y:\MIS_DATABASE\Library\ALTIUM_TOOL\SCHEMATICS_PARTS\MS_DISCRETE_Library.schlib; Mfr_name: MURATA; Mfr_part_number: GRM033R61C104KE14D; Mistral Part No: 120009030072-R; Package: 0201; Part_type: CAPACITORS\CERAMIC; Project: TI_MAXIE_CPB; RoHS: RoHS; Temperature: -55°C+85°C; Tolerance: 10%; Voltage: 16V; Wattage: NA; Weight: 0.33mg; Datasheet: Y:\MIS_DATABASE\DATASHEETS\CAPACITORS\GRM033R61C104KE14.PDF
C146 C384 C393 C406 C410 = CAP: CAP CERAMIC 10uF 10V 20% X5R 0402; Chkd/date: MANIRAJA/300520; Crtd /date: ALVY/260520; Custom_Duty: 15%; Customs_HS_Code: 85322990; Distributor_name: DIGIKEY; Distributor_part_number: 490-GRM155R61A106ME11DTR-ND; Footprint Path: Y:\MIS_DATABASE\Library\ALTIUM_TOOL\PCB_FOOTPRINTS\Altium_Footprint_Lib.PcbLib; Height: 0.55MM; Library Path: Y:\MIS_DATABASE\Library\ALTIUM_TOOL\SCHEMATICS_PARTS\MS_DISCRETE_Library.schlib; Mfr_name: MURATA; Mfr_part_number: GRM155R61A106ME11D; Mistral Part No: 120013110019-R; Package: 0402; Part_type: CAPACITORS\CERAMIC; Project: QCS610_NANOSOM; RoHS: RoHS; Temperature: -55°C+85°C; Tolerance: 20%; Voltage: 10V; Wattage: NA; Weight: 3.1mg; Datasheet: Y:\MIS_DATABASE\DATASHEETS\CAPACITORS\MURATA-GXX-SER_NOV17.PDF
C397 C399 C421 = CAP: CAP CERAMIC 0.1uF 50V 10% X7R 0402; Chkd/date: MANIRAJA/261020; Crtd /date: ALVY/211020; Custom_Duty: 15%; Customs_HS_Code: 85322990; Distributor_name: DIGIKEY; Distributor_part_number: 490-10700-1-ND; Footprint Path: Y:\MIS_DATABASE\Library\ALTIUM_TOOL\PCB_FOOTPRINTS\Altium_Footprint_Lib.PcbLib; Height: 0.55MM; Library Path: Y:\MIS_DATABASE\Library\ALTIUM_TOOL\SCHEMATICS_PARTS\MS_DISCRETE_Library.schlib; Mfr_name: MURATA; Mfr_part_number: GRM155R71H104KE14D; Mistral Part No: 120011100014-R; Package: 0402; Part_type: CAPACITORS\CERAMIC; Project: J7_CP; RoHS: RoHS; Temperature: -55°C+125°C; Tolerance: 10%; Voltage: 50V; Wattage: NA; Weight: 3.1mg; Datasheet: Y:\MIS_DATABASE\DATASHEETS\CAPACITORS\GRM155R71H104KE14.PDF
C412 = CAP: CAP CERAMIC 0.47uF 10V 10% X7R 0402; Chkd/date: MANIRAJA/310821; Crtd /date: ALVY/310821; Custom_Duty: 15%; Customs_HS_Code: 85322990; Distributor_name: DIGIKEY; Distributor_part_number: 490-14366-1-ND; Footprint Path: Y:\MIS_DATABASE\Library\ALTIUM_TOOL\PCB_FOOTPRINTS\Altium_Footprint_Lib.PcbLib; Height: 0.55MM; Library Path: Y:\MIS_DATABASE\Library\ALTIUM_TOOL\SCHEMATICS_PARTS\MS_DISCRETE_Library.schlib; Mfr_name: MURATA; Mfr_part_number: GRM155R71A474KE01D; Mistral Part No: 120021060019-R; Package: 0402; Part_type: CAPACITORS\CERAMIC; Project: TI_AM335x SK_BRD; RoHS: RoHS; Temperature: -55°C+125°C; Tolerance: 10%; Voltage: 10V; Wattage: NA; Weight: 1.5mg; Datasheet: Y:\MIS_DATABASE\DATASHEETS\CAPACITORS\GRM155R71A474KE01.PDF
C416 C417 = CAP: CAP CERAMIC 47uF 10V 20% X5R 1206; Chkd/date: USMAN/121213; Crtd /date: USMAN/121213; Custom_Duty: 15%; Customs_HS_Code: 85322990; Distributor_name: DIGIKEY; Distributor_part_number: 490-5528-1-ND; Footprint Path: Y:\MIS_DATABASE\Library\ALTIUM_TOOL\PCB_FOOTPRINTS\Altium_Footprint_Lib.PcbLib; Height: 1.80MM; Library Path: Y:\MIS_DATABASE\Library\ALTIUM_TOOL\SCHEMATICS_PARTS\MS_DISCRETE_Library.schlib; Mfr_name: MURATA; Mfr_part_number: GRM31CR61A476ME15L; Mistral Part No: 120013120015-R; Package: 1206; Part_type: CAPACITORS\CERAMIC; Project: DMP; RoHS: RoHS; Temperature: -55°C+85°C; Tolerance: 20%; Voltage: 10V; Wattage: NA; Weight: 40mg; Datasheet: Y:\MIS_DATABASE\DATASHEETS\CAPACITORS\MURATA-GXX-SER_NOV17.PDF
FL12 = EMIFILTER_IND: IND FERRITE BEAD CHIP 120E 2A 0402; Chkd/date: NAVEED/241114; Crtd /date: USMAN/170613; Custom_Duty: 24%; Customs_HS_Code: 85369090; Distributor_name: DIGIKEY; Distributor_part_number: 490-9656-1-ND; Footprint Path: Y:\MIS_DATABASE\Library\ALTIUM_TOOL\PCB_FOOTPRINTS\Altium_Footprint_Lib.PcbLib; Height: 0.55MM; Library Path: Y:\MIS_DATABASE\Library\ALTIUM_TOOL\SCHEMATICS_PARTS\MS_FILTER_Library.schlib; Mfr_name: MURATA; Mfr_part_number: BLM15PX121SN1D; Mistral Part No: 130013060022-R; Package: 0402; Part_type: INDUCTOR; Project: GEN_3-8; RoHS: RoHS; Temperature: -55°C+125°C; Tolerance: 25%; Voltage: NA; Wattage: NA; Weight: 1mg; Datasheet: Y:\MIS_DATABASE\DATASHEETS\DISCRETES\INDUCTORS\BLM15-SN1-SER.PDF
J12 = CON_AUDIOJACK4_SJ-43514-SMT: CON AUDIO JACK 4POS FEMALE RT SMD; Chkd/date: MAZHAR/230211; Crtd /date: MUDDU/300610; Custom_Duty: 24%; Customs_HS_Code: 85369090; Distributor_name: DIGIKEY; Distributor_part_number: CP-43514SJCT-ND; Footprint Path: Y:\MIS_DATABASE\Library\ALTIUM_TOOL\PCB_FOOTPRINTS\Altium_Footprint_Lib.PcbLib; Height: 5.10MM; Library Path: Y:\MIS_DATABASE\Library\ALTIUM_TOOL\SCHEMATICS_PARTS\MS_CONNECTOR_Library.schlib; Mfr_name: CUI INC; Mfr_part_number: SJ-43514-SMT-TR; Mistral Part No: 150010060028-R; Package: SMD; Part_type: CONNECTOR\JACK; Project: PB_BUGBASE; RoHS: RoHS; Temperature: -25°C+85°C; Tolerance: NA; Voltage: NA; Wattage: NA; Weight: 1100mg; Datasheet: Y:\MIS_DATABASE\DATASHEETS\CONNECTORS\SJ-4351X-SMT.PDF
R425 = RESISTOR: RES 10K 1/20W 1% 0201; Chkd/date: VASANTHA/270117; Crtd /date: MANIRAJA/270117; Custom_Duty: 15%; Customs_HS_Code: 85332119; Distributor_name: DIGIKEY; Distributor_part_number: 311-10.0KMCT-ND; Footprint Path: Y:\MIS_DATABASE\Library\ALTIUM_TOOL\PCB_FOOTPRINTS\Altium_Footprint_Lib.PcbLib; Height: 0.26MM; Library Path: Y:\MIS_DATABASE\Library\ALTIUM_TOOL\SCHEMATICS_PARTS\MS_DISCRETE_Library.schlib; Mfr_name: YAGEO AMERICA; Mfr_part_number: RC0201FR-0710KL; Mistral Part No: 110011040018-R; Package: 0201; Part_type: RESISTORS\FIXED; Project: GOLDEN-I LITE; RoHS: RoHS; Temperature: -55°C+125°C; Tolerance: 1%; Voltage: NA; Wattage: 1/20W; Weight: 0.17mg; Datasheet: Y:\MIS_DATABASE\DATASHEETS\RESISTORS\RCXXXXL-SER_MAR18.PDF
R437 = RESISTOR: RES 0E 1/20W 5% 0201; Chkd/date: NAVEED/301214; Crtd /date: MUDDU/120710; Custom_Duty: 15%; Customs_HS_Code: 85332119; Distributor_name: DIGIKEY; Distributor_part_number: 311-0.0NCT-ND; Footprint Path: Y:\MIS_DATABASE\Library\ALTIUM_TOOL\PCB_FOOTPRINTS\Altium_Footprint_Lib.PcbLib; Height: 0.26MM; Library Path: Y:\MIS_DATABASE\Library\ALTIUM_TOOL\SCHEMATICS_PARTS\MS_DISCRETE_Library.schlib; Mfr_name: YAGEO AMERICA; Mfr_part_number: RC0201JR-070RL; Mistral Part No: 110010070067-R; Package: 0201; Part_type: RESISTORS\FIXED; Project: PB_BUGBASE; RoHS: RoHS; SIGNAL_MODEL: RESISTOR_RES0201_0-5_0E_0E; Temperature: -55°C+125°C; Tolerance: 5%; Voltage: NA; Wattage: 1/20W; Weight: 0.17mg; Datasheet: Y:\MIS_DATABASE\DATASHEETS\RESISTORS\RCXXXXL-SER_MAR18.PDF
R438-R440 R446 R477 = RESISTOR: RES 0E 1/20W 5% 0201; Chkd/date: NAVEED/301214; Crtd /date: MUDDU/120710; Custom_Duty: 15%; Customs_HS_Code: 85332119; Distributor_name: DIGIKEY; Distributor_part_number: 311-0.0NCT-ND; Footprint Path: Y:\MIS_DATABASE\Library\ALTIUM_TOOL\PCB_FOOTPRINTS\Altium_Footprint_Lib.PcbLib; Height: 0.26MM; Library Path: Y:\MIS_DATABASE\Library\ALTIUM_TOOL\SCHEMATICS_PARTS\MS_DISCRETE_Library.schlib; Mfr_name: YAGEO AMERICA; Mfr_part_number: RC0201JR-070RL; Mistral Part No: 110010070067-R; Package: 0201; Part_type: RESISTORS\FIXED; Project: PB_BUGBASE; RoHS: RoHS; Temperature: -55°C+125°C; Tolerance: 5%; Voltage: NA; Wattage: 1/20W; Weight: 0.17mg; Datasheet: Y:\MIS_DATABASE\DATASHEETS\RESISTORS\RCXXXXL-SER_MAR18.PDF
R479 = RESISTOR: RES 2.2K 1/20W 1% 0201; Chkd/date: VASANTHA/270117; Crtd /date: MANIRAJA/270117; Custom_Duty: 15%; Customs_HS_Code: 85332119; Distributor_name: DIGIKEY; Distributor_part_number: YAG2572CT-ND; Footprint Path: Y:\MIS_DATABASE\Library\ALTIUM_TOOL\PCB_FOOTPRINTS\Altium_Footprint_Lib.PcbLib; Height: 0.26MM; Library Path: Y:\MIS_DATABASE\Library\ALTIUM_TOOL\SCHEMATICS_PARTS\MS_DISCRETE_Library.schlib; Mfr_name: YAGEO AMERICA; Mfr_part_number: RC0201FR-072K2L; Mistral Part No: 110017010016-R; Package: 0201; Part_type: RESISTORS\FIXED; Project: GOLDEN-I LITE; RoHS: RoHS; Temperature: -55°C+125°C; Tolerance: 1%; Voltage: NA; Wattage: 1/20W; Weight: 0.17mg; Datasheet: Y:\MIS_DATABASE\DATASHEETS\RESISTORS\RCXXXXL-SER_MAR18.PDF
TP56 TP59 TP65 = TESTPOINT: TESTPOINT 1.0MM DRILL PTH; Chkd/date: MAZHAR/271211; Crtd /date: SHREESHAIL/041005; Distributor_name: NA; Distributor_part_number: NA; Height: NA; Mfr_name: LOCAL; Mistral Part No: 130009030938; Package: THRU-HOLE; Project: HSE; Datasheet: NA
U59 = OSC_KC2016K: OSC 12.288MHz CMOS SMD; Chkd/date: MANIRAJA/061021; Crtd /date: ALVY/061021; Custom_Duty: 24%; Customs_HS_Code: 85437099; Distributor_name: DIGIKEY; Distributor_part_number: 1253-KC2520Z12.2880C1KX00CT-ND; Footprint Path: Y:\MIS_DATABASE\Library\ALTIUM_TOOL\PCB_FOOTPRINTS\Altium_Footprint_Lib.PcbLib; Height: 0.80MM; Library Path: Y:\MIS_DATABASE\Library\ALTIUM_TOOL\SCHEMATICS_PARTS\MS_DISCRETE_Library.schlib; Mfr_name: KYOCERA; Mfr_part_number: KC2520Z12.2880C1KX00; Mistral Part No: 130021100008-R; Package: SMD; Part_type: OSCILLATORS; Project: TI_AM62x SKEVM_BRD; RoHS: RoHS; Temperature: -40°C+85°C; Tolerance: NA; Voltage: NA; Wattage: NA; Weight: NA; Datasheet: Y:\MIS_DATABASE\DATASHEETS\MISC\CRY_OSC\KC-Z-SERPDF
U66 = TLV320AIC3106IRGZT_VQFN48: IC LOW-POWER STEREO AUDIO CODEC VQFN48; Chkd/date: SUHAS/261010; Crtd /date: MUDDU/150610; Custom_Duty: 15%; Customs_HS_Code: 85423100; Distributor_name: DIGIKEY; Distributor_part_number: TLV320AIC3106IRGZT-ND; Height: 1.00MM; Mfr_name: TEXAS INSTRUMENTS; Mistral Part No: 143010060003-R; Package: VQFN48; Part_type: ICS\TELECOM\CODEC; Project: CENTAURUS; RoHS: Sb/ Br FREE; Temperature: -40°C+85°C; Weight: NA; Datasheet: Y:\MIS_DATABASE\DATASHEETS\ICS\TELECOM\TLV320AIC3106IRGZT.PDF
U71 = SN74LVC1G08DBVRE4_SOT23-5: IC SINGLE 2-INPUT POSITIVE AND GATE SOT23-5; Chkd/date: SUHAS/221010; Crtd /date: USMAN/151008; Custom_Duty: 15%; Customs_HS_Code: 85423100; Distributor_name: DIGIKEY; Distributor_part_number: SN74LVC1G08DBVRE4-ND; Height: 1.45MM; Mfr_name: TEXAS INSTRUMENTS; Mistral Part No: 141009060026-R; Part_type: ICS\DIGITAL\GATES; Project: KHAN_MAIN; RoHS: Sb/ Br FREE; Temperature: -40°C+85°C; Datasheet: Y:\MIS_DATABASE\DATASHEETS\ICS\DIGITAL\GATES\SN74LVC1G08.PDF

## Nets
AGND_AUD: C137.2 C140.2 C145.2 C146.2 C405.2 C406.2 C410.2 C411.2 FL12.1 J12.4 TP65.1(TP) U66.15(AVSS_ADC) U66.20(DRVSS.1) U66.21(DRVSS.2) U66.26(AVSS_DAC) U66.49(TPAD)
DGND: C1.1 C384.2 C385.1 C386.2 C388.2 C393.2 C394.2 C404.1 C421.2 C422.1 C496.1 FL12.2 R172.2 R173.2 R474.1 R487.1 R488.1 R656.1 R657.1 R659.1 R714.1 U59.2(GND) U60.6(GND) U65.8(GND) U66.42(DVSS) U66.43(SELECT) U70.25(GND) U70.33(EP) U71.3(GND) U110.6(GND) U110.17(EP) ; also on sheet 1 10 11 12 13 14 15 16 17 18 19 20 21 22 23 24 25 26 27 28 29 30 31 32 33 34 35 36 37 38 41 42 43
VCC_1V8: C496.2 R446.2 U60.1(VCCA) ; also on sheet 12 13 14 18 19 21 25 34 37 42
VCC_1V8_AUD: C393.1 C394.1 R446.1 U66.36(DVDD.1)
VCC_3V3_AUD: C145.1 C146.1 C384.1 C386.1 C388.1 C405.1 C406.1 C410.1 C411.1 C421.1 R425.1 R432.1 R433.1 R469.2 R477.1 U59.4(VCC) U66.16(DRVDD.1) U66.17(DRVDD.2) U66.24(DRVDD.3) U66.25(AVDD_DAC) U66.44(IOVDD) U71.5(VCC)
VCC_3V3_SYS: C1.2 C385.2 C404.2 C422.2 R187.2 R193.2 R459.2 R477.2 R486.2 R655.2 R658.2 R713.2 U60.11(VCCB) U65.16(VCC) U70.27(VCCP) U70.31(VCC) U110.14(VCCP) U110.15(VCCI) ; also on sheet 10 12 13 14 18 19 20 22 23 24 25 26 27 29 30 31 32 33 34 35 36 37 38 41 42 43
ADDR_IO_EXP: R488.2 U70.26(ADDR)
ADDR_IO_EXP1: R714.2 U110.16(ADDR)
AUD_RSTn: R487.2 U66.33(~{RESET}) U71.4(Y)
AUDIO_MSTRCLK: R438.1 U66.37(MCLK)
BT_UART_WAKE_SOC_3V3: U70.10(P11) ; also on sheet 18
CSI_GPIO1: U70.14(P15) ; also on sheet 38
CSI_GPIO2: U70.15(P16) ; also on sheet 38
EXP_HAT_DETECT: R187.1 U70.8(P07) ; also on sheet 33
EXP_PS_3V3_EN: U70.6(P05) ; also on sheet 33
EXP_PS_5V0_EN: U70.7(P06) ; also on sheet 33
GPIO1_23_INTn: R485.1 ; also on sheet 42 43
GPIO_AUD_RSTn: R469.1 R474.2 U71.1(A) U110.4(P2)
GPIO_CPSW1_RST: U70.2(P01) ; also on sheet 23
GPIO_CPSW2_RST: U70.1(P00) ; also on sheet 24
GPIO_eMMC_RSTn: U110.5(P3) ; also on sheet 19
GPIO_HDMI_RSTn: U70.13(P14) ; also on sheet 41
GPIO_TS_RSTn: U110.3(P1) ; also on sheet 37
HDMI_INTn: U70.17(P20) ; also on sheet 41
HPLOUT: C416.2 J12.2
HPLOUT_C: C416.1 U66.18(HPLOUT)
HPROUT: C417.2 J12.3
HPROUT_C: C417.1 U66.23(HPROUT)
IO_EXP1_INTn: R713.1 U110.11(~{INT})
IO_EXP_INTn: R485.2 R486.1 U70.32(~{INT})
IO_EXP_TEST_LED: U70.24(P27) ; also on sheet 38
LINE1L+: C397.1 TP56.1(TP)
LINE1L+_C: C397.2 U66.3(LINE1L+)
LINE1R+: C399.1 TP59.1(TP)
LINE1R+_C: C399.2 U66.5(LINE1R+)
MCASP1_ACLKX: U60.7(B4) U65.4(1A) ; also on sheet 32
MCASP1_ACLKX_AUD: TP54.1(TP) U65.3(1B2) U66.38(BCLK)
MCASP1_ACLKX_BT_1V8: U60.5(A4) ; also on sheet 18
MCASP1_ACLKX_HDMI: U65.2(1B1) ; also on sheet 41
MCASP1_AFSX: U60.8(B3) U65.7(2A) ; also on sheet 32
MCASP1_AFSX_AUD: TP50.1(TP) U65.6(2B2) U66.39(WCLK)
MCASP1_AFSX_BT_1V8: U60.4(A3) ; also on sheet 18
MCASP1_AFSX_HDMI: U65.5(2B1) ; also on sheet 41
MCASP1_AXR0: U60.9(B2) U65.9(3A) ; also on sheet 32
MCASP1_AXR0_AUD: TP55.1(TP) U65.10(3B2) U66.40(DIN)
MCASP1_AXR0_BT_1V8: U60.3(A2) ; also on sheet 18
MCASP1_AXR0_HDMI: U65.11(3B1) ; also on sheet 41
MCASP1_AXR2: U60.10(B1) U65.12(4A) ; also on sheet 32
MCASP1_AXR2_AUD: R437.1 TP49.1(TP) U65.13(4B2)
MCASP1_AXR2_BT_1V8: U60.2(A1) ; also on sheet 18
MCASP1_BUF_BT_EN: R657.2 R658.1 U60.12(OE) U70.20(P23)
MCASP1_FET_EN: R459.1 R659.2 U65.15(~{OE}) U70.19(P22)
MCASP1_FET_SEL: J24.1 R655.1 U65.1(S) U70.21(P24)
MFP0: R172.1 R433.2 U66.45(MFP0)
MFP1: R173.1 R432.2 U66.46(MFP1)
MFP2: TP52.1(TP) U66.47(MFP2)
MFP3: TP53.1(TP) U66.48(MFP3)
MIC_IN: C412.1 J12.1 R479.1 U66.12(MICDET)
MMC1_SD_EN: U70.4(P03) ; also on sheet 20
PD_I2C_IRQ: U70.18(P21) ; also on sheet 10
PRU_3V3_EN: U70.16(P17) ; also on sheet 32
PRU_DETECT: R193.1 U70.3(P02) ; also on sheet 32
RESETSTATz: U70.28(~{RESET}) U71.2(B) U110.1(~{RESET}) ; also on sheet 13 19 20 21 23 24 27 32 33 37 41 42
SOC_I2C1_SCL: R440.1 U70.29(SCL) U110.12(SCL) ; also on sheet 14 22 26 41 42
SOC_I2C1_SDA: R439.1 U70.30(SDA) U110.13(SDA) ; also on sheet 14 22 26 41 42
TS_INT#: U70.23(P26) ; also on sheet 37
UART1_FET_BUF_EN: U70.11(P12) ; also on sheet 37
UART1_FET_SEL: U70.22(P25) ; also on sheet 37
VPP_LDO_EN: U70.5(P04) ; also on sheet 12
WL_LT_EN: U70.12(P13) ; also on sheet 18
WLAN_ALERT_3V3: U70.9(P10) ; also on sheet 18
WLAN_SDIO_RST_3V3: U110.2(P0) ; also on sheet 18
N16929458: TP63.1(TP) U66.7(LINE2L+)
N16929460: TP62.1(TP) U66.8(LINE2L-)
N16929474: R437.2 U66.41(DOUT)
N16929699: C137.1 U66.4(LINE1L-)
N16929703: C140.1 U66.6(LINE1R-)
N16929744: TP67.1(TP) U66.19(HPLCOM)
N16929747: TP66.1(TP) U66.22(HPRCOM)
N16929749: TP91.1(TP) U66.35(GPIO1)
N16929751: TP93.1(TP) U66.34(GPIO2)
N17498937: R439.2 U66.2(SDA)
N17498940: R440.2 U66.1(SCL)
N18736007: C412.2 U66.14(MIC3R)
N18736028: R479.2 U66.13(MICBIAS)
N20066520: J24.2 R656.2
N20174887: R425.2 U59.1(INH)
N20174906: R438.2 U59.3(OUTPUT)
N20717871: TP118.1(TP) U110.7(P4)
N20717874: TP119.1(TP) U110.8(P5)
N20717877: TP120.1(TP) U110.9(P6)
N20717880: TP121.1(TP) U110.10(P7)

Not connected (* = marked no-connect by the designer): U65 14(4B1)*; U66 9(LINE2R+)* 10(LINE2R-)* 11(MIC3L)* 27(MONO_LO+)* 28(MONO_LO-)* 29(LEFT_LO+)* 30(LEFT_LO-)* 31(RIGHT_LO+)* 32(RIGHT_LO-)*

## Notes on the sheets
sheet 39
- IO EXPANDERS
- I2C ADDRESS: 0x20
- I2C ADDRESS: 0x22
- MCASP1 FET SWITCH & BUFFER
- INPUT/OUTPUT
- OEn
- SEL
- An
- L
- H(DEFAULT)
- An=nB2
- MCASP1 - CODEC
- L
- L
- An=nB1
- MCASP1 - HDMI
sheet 40
- AUDIO CODEC
- Silk: LINE IN
- MIC + HPHONE
- I2C ADDRESS: 0x1B
- AUDIO CODEC RESET
- CODEC I2C ADDRESS SELECTION
- MFP0
- MFP1
- Device Address
- 0
- 0
- 0x18
- 0
- 1
- 0x19
- 1
- 0
- 0x1A
- 1
- 1
- 0x1B
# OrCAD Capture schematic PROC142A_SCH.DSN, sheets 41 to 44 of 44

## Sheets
41 41. HDMI INTERFACE: size C; title: HDMI INTERFACE
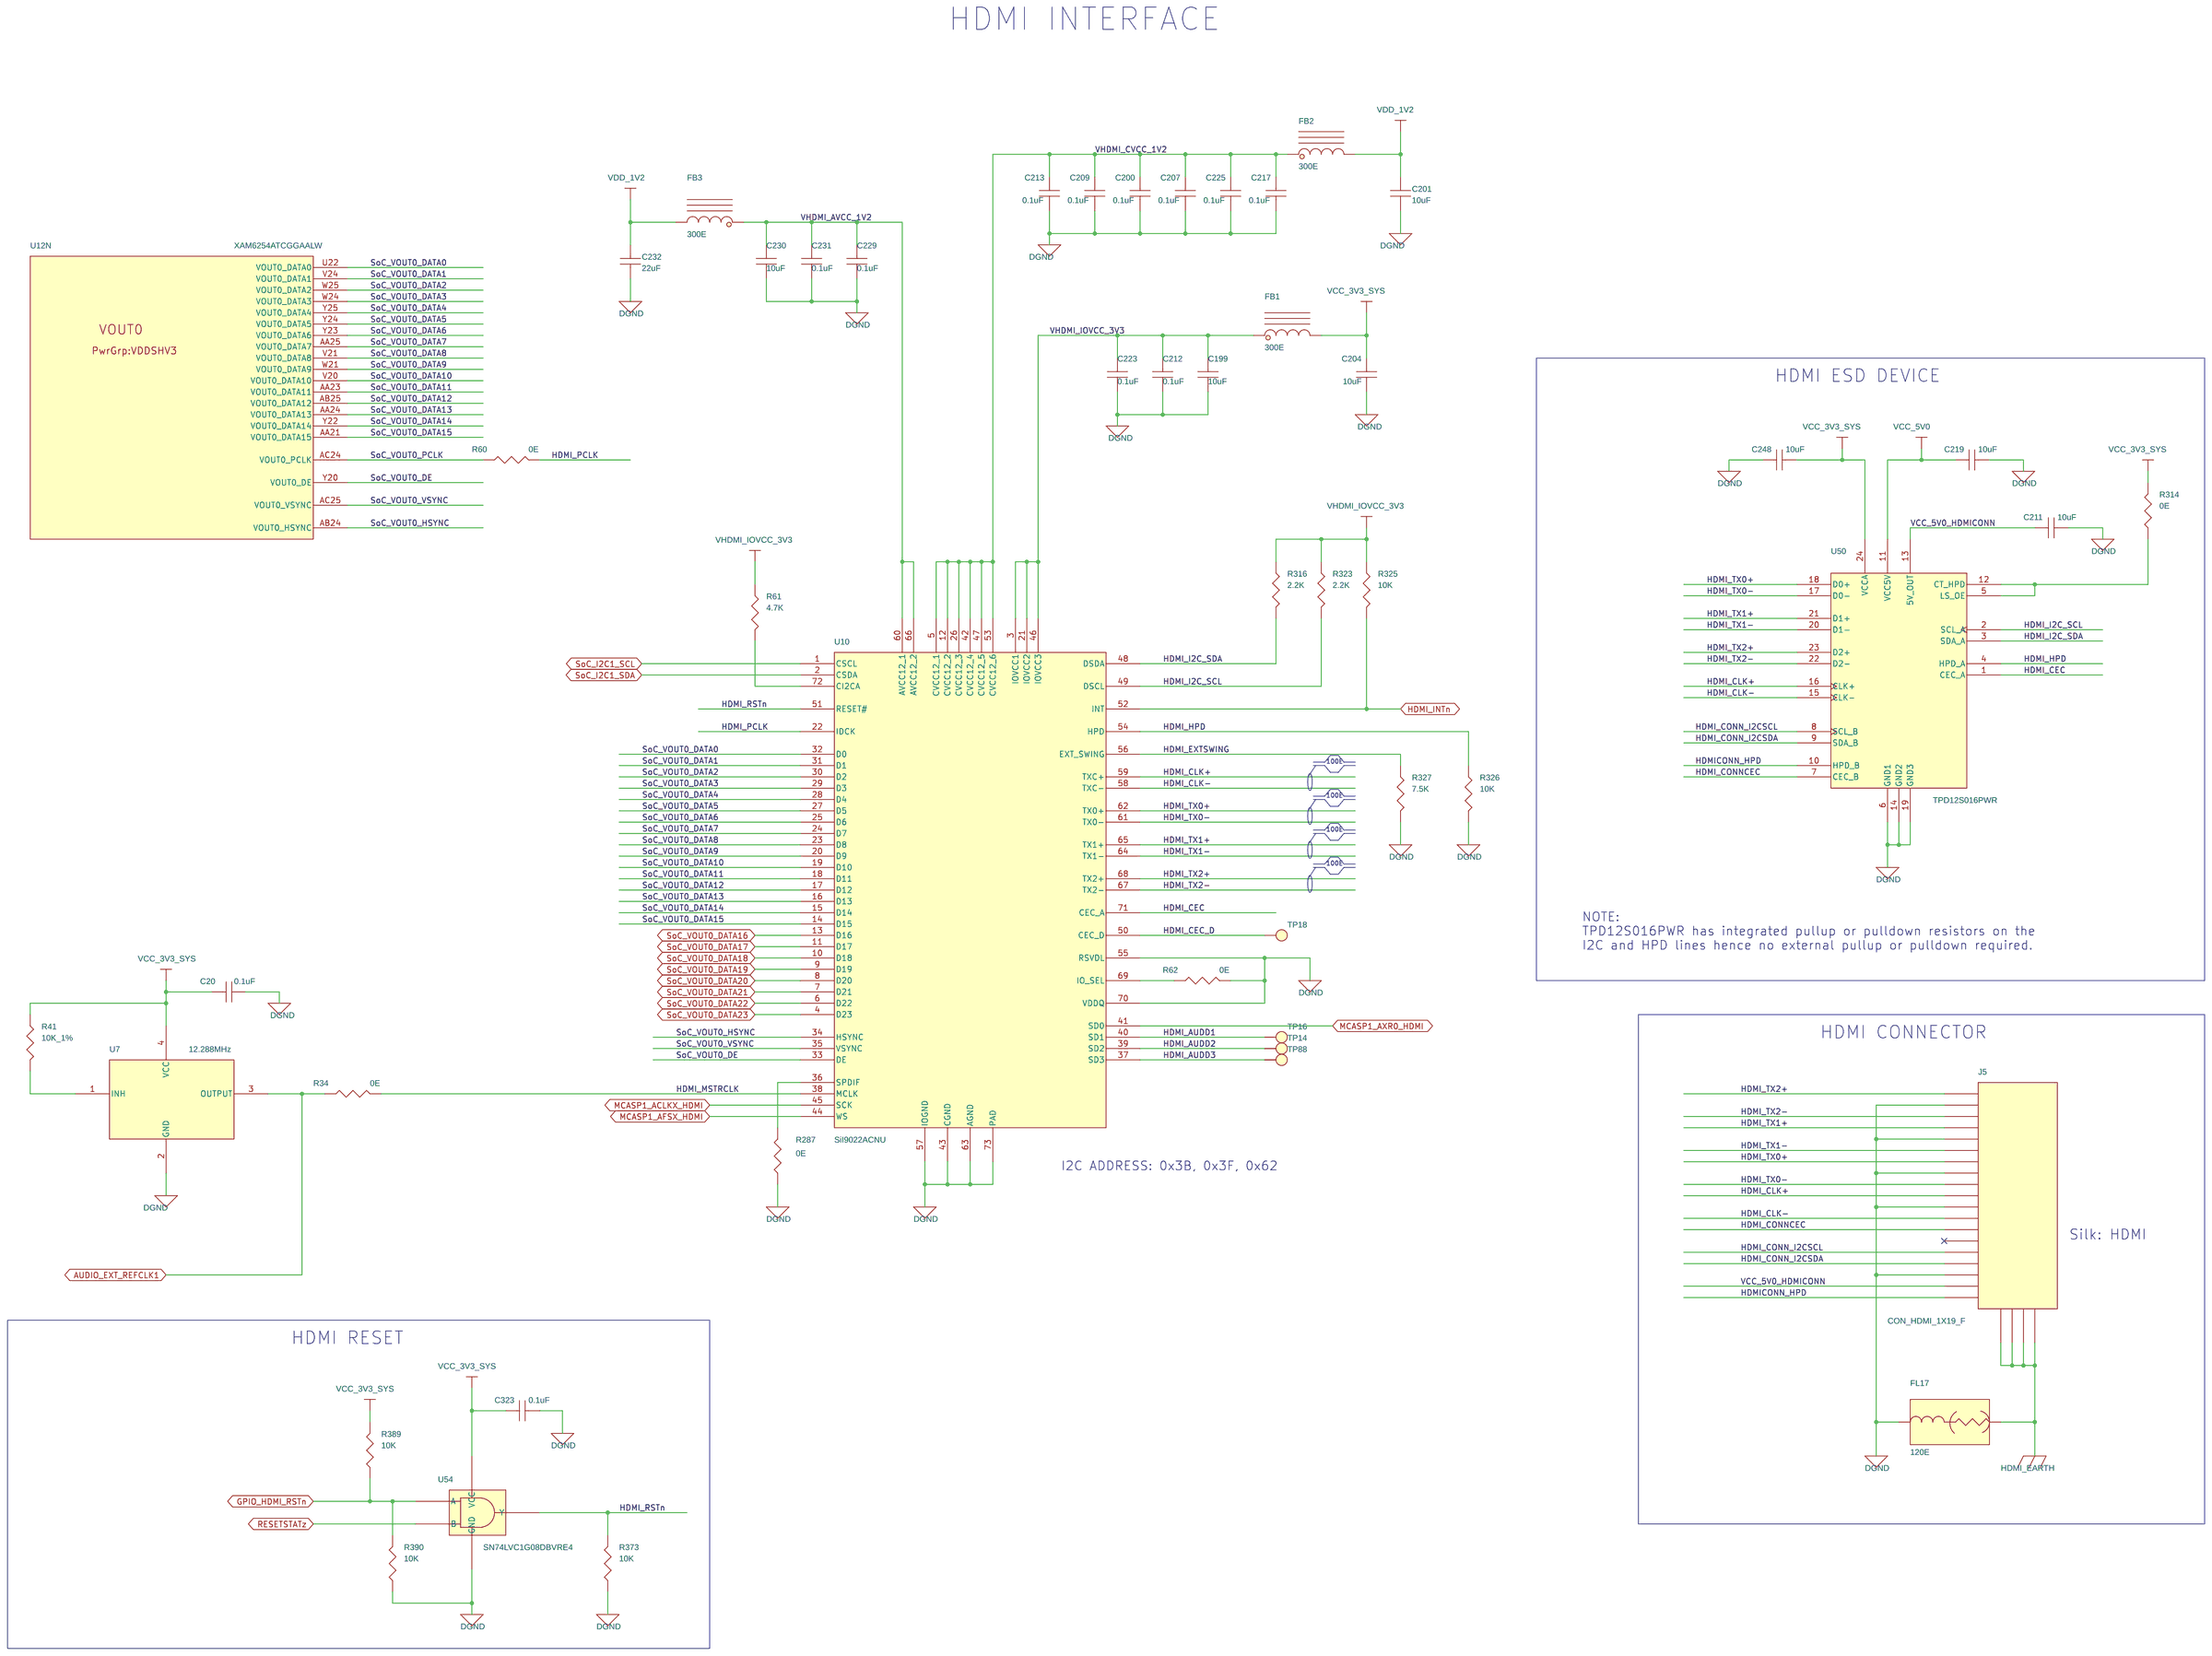
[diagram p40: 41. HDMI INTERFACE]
42 42. OSCILLATOR: size C; title: OSCILLATOR
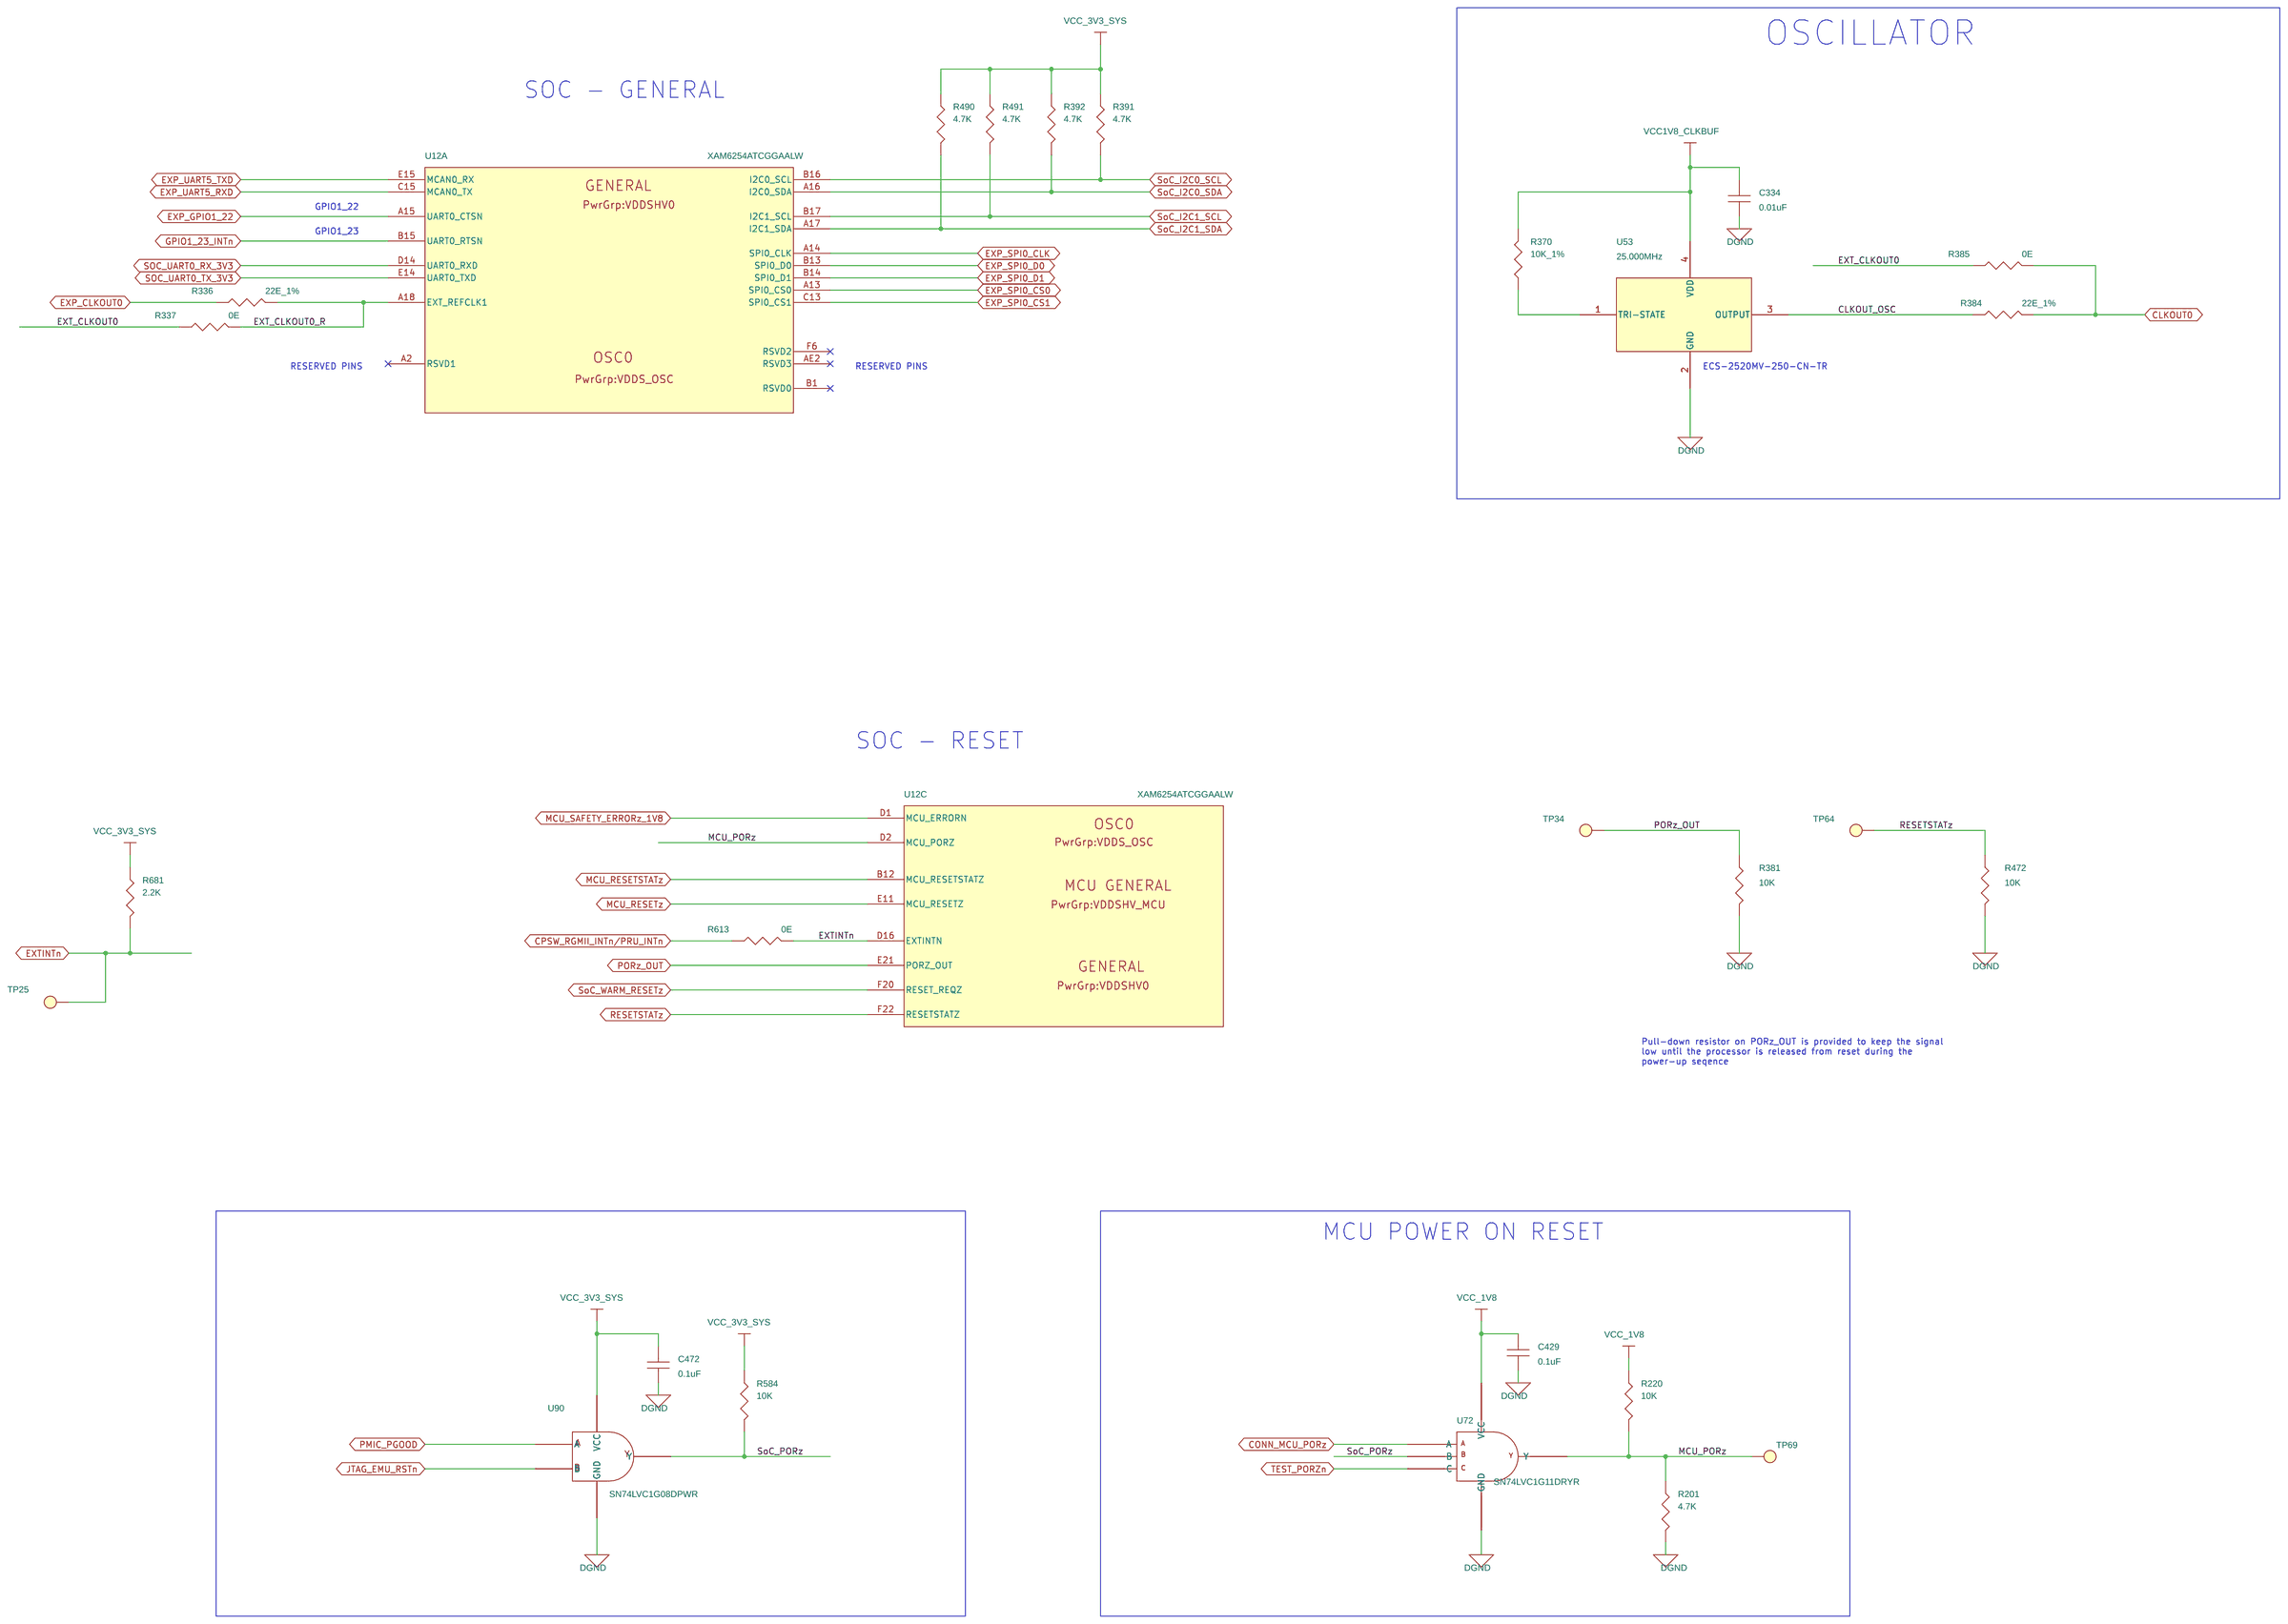
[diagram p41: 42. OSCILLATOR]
43 43. RESET: size C; title: RESET
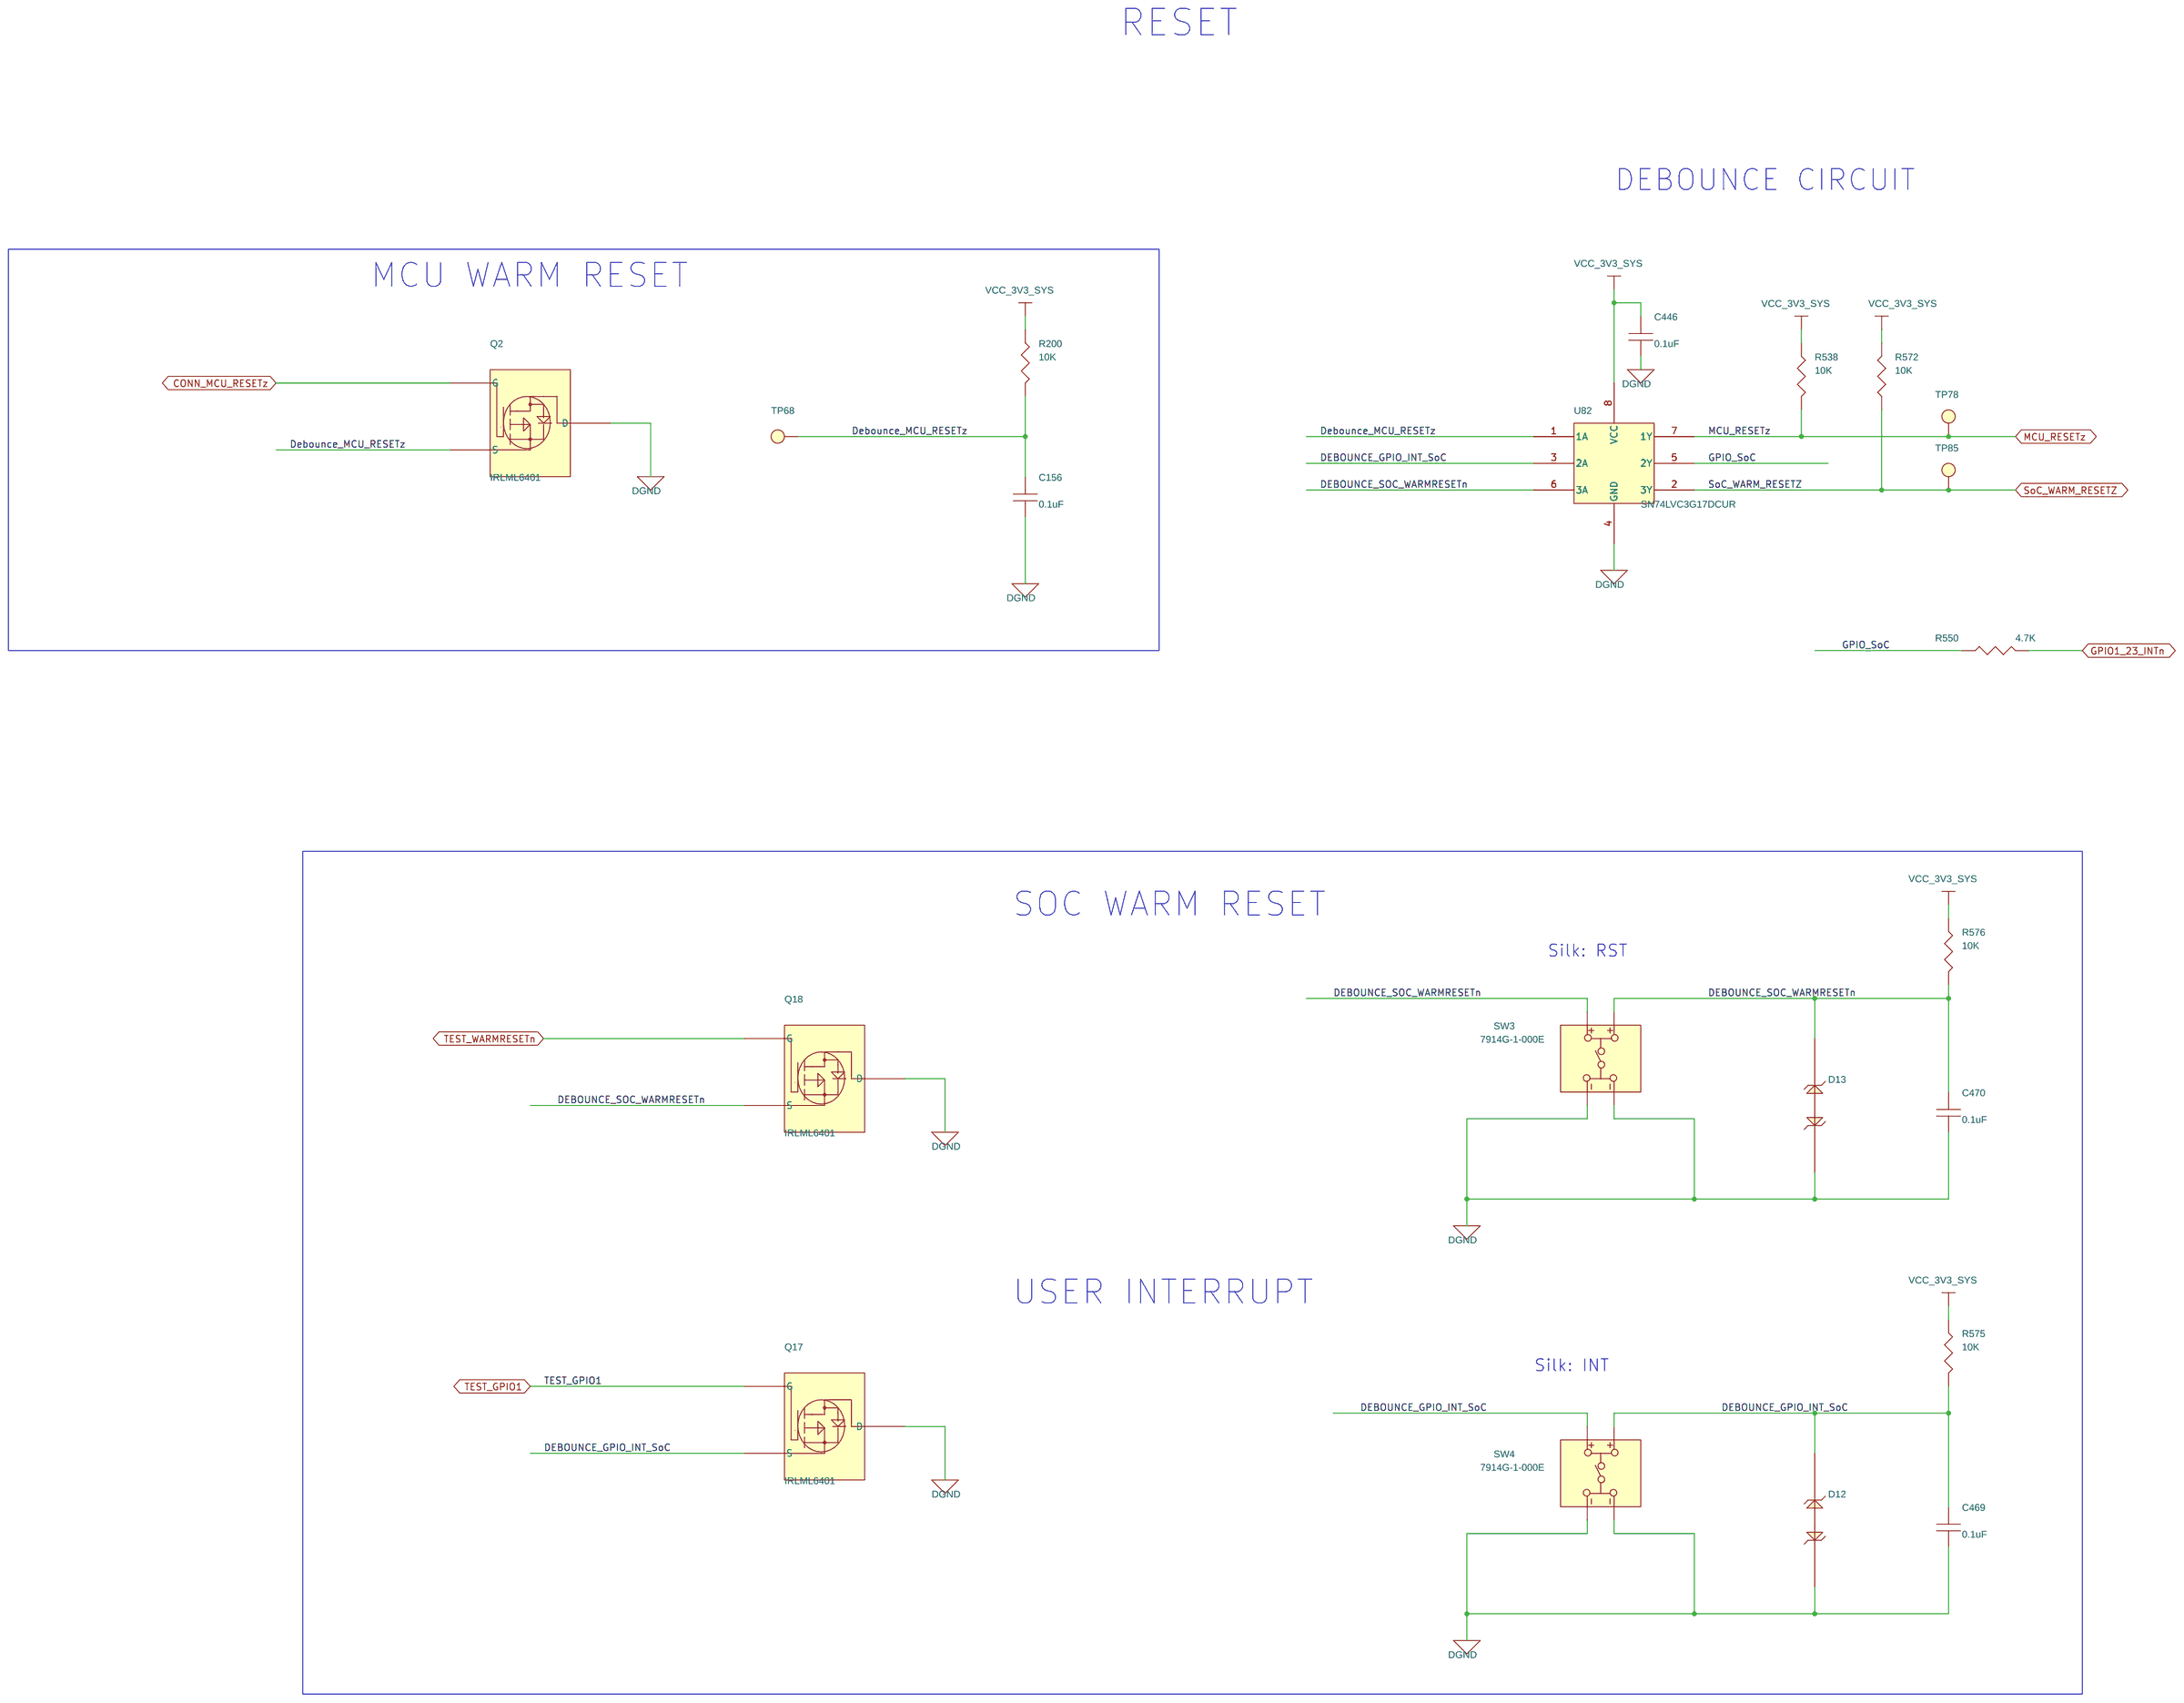
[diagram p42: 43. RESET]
44 44. ACCESSORIES: title: HARDWARE SCHEMATICS

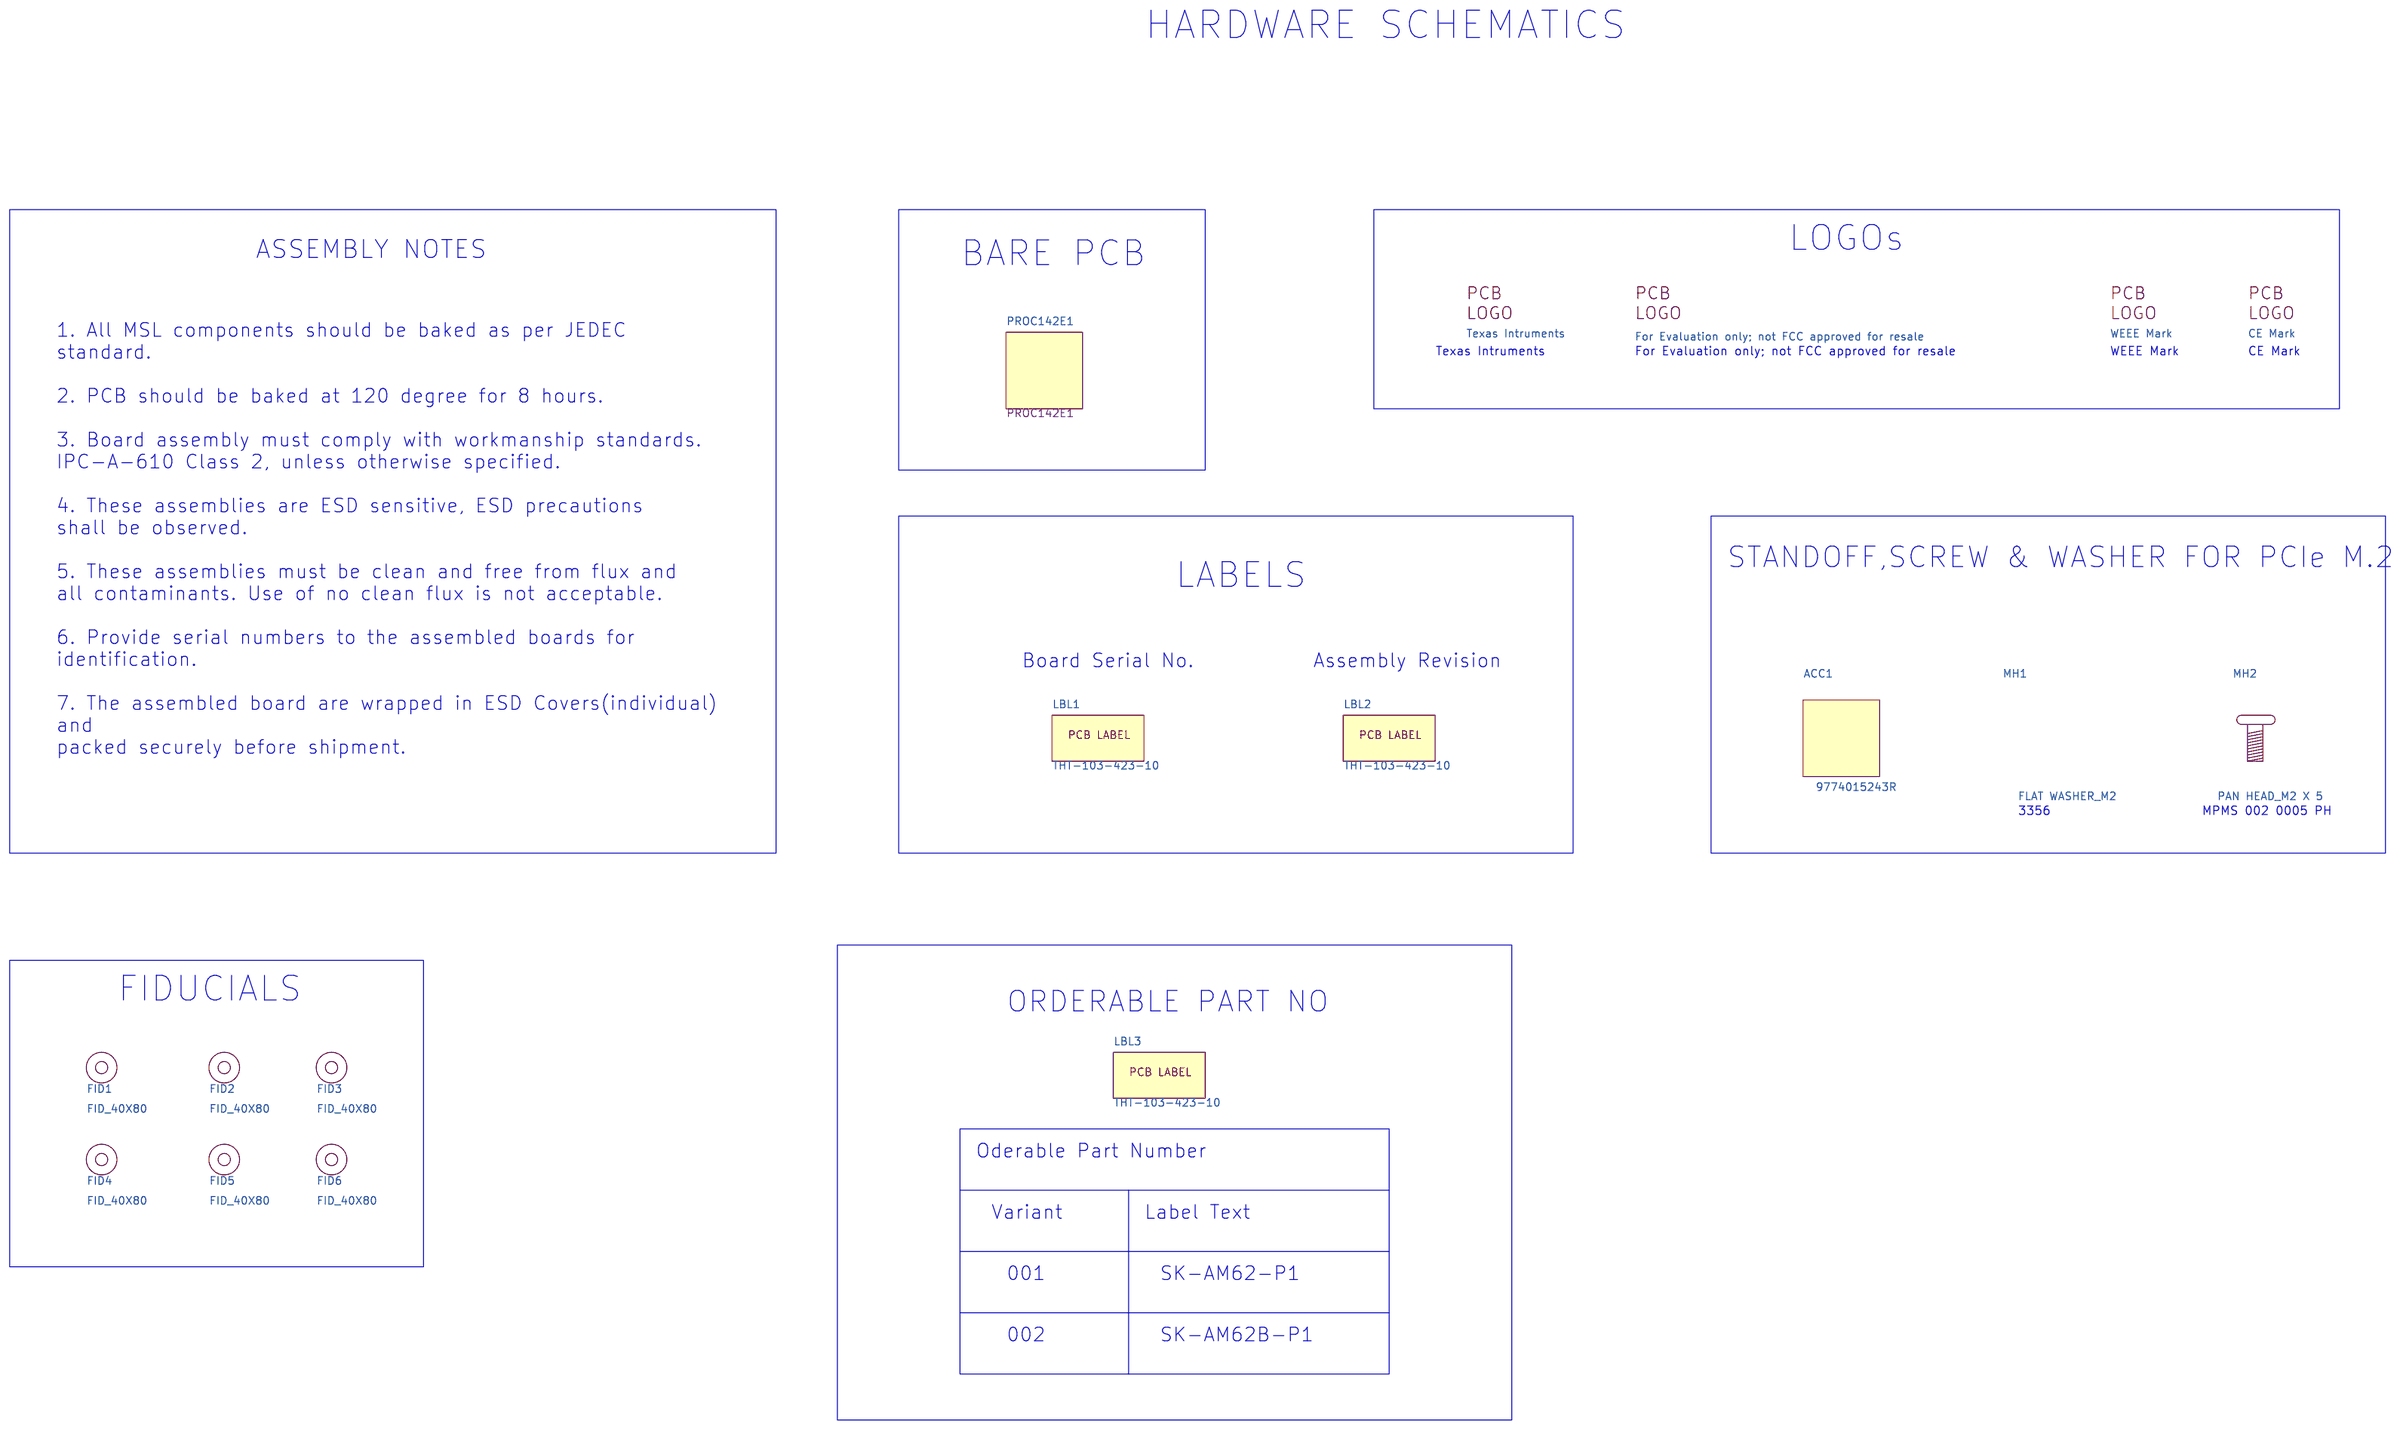
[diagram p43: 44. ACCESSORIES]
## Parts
sheet 29. JTAG BUFFER
U12  XAM6254ATCGGAALW  [BGA425_19-68_510X510_0-7]  (sections A,B,C,D,E,F,G,H,I,J,K,L,M,N,O,P,Q,R)
sheet 41. HDMI INTERFACE
C20  0.1uF  [CAP0201_0-5]
C199  10uF  [CAP0402_0-75]
C200  0.1uF  [CAP0201_0-5]
C201  10uF  [CAP0402_0-75]
C204  10uF  [CAP0402_0-75]
C207  0.1uF  [CAP0201_0-5]
C209  0.1uF  [CAP0201_0-5]
C211  10uF  [CAP0402_0-75]
C212  0.1uF  [CAP0201_0-5]
C213  0.1uF  [CAP0201_0-5]
C217  0.1uF  [CAP0201_0-5]
C219  10uF  [CAP0402_0-75]
C223  0.1uF  [CAP0201_0-5]
C225  0.1uF  [CAP0201_0-5]
C229  0.1uF  [CAP0201_0-5]
C230  10uF  [CAP0402_0-75]
C231  0.1uF  [CAP0201_0-5]
C232  22uF  [CAP0603_1]
C248  10uF  [CAP0402_0-75]
C323  0.1uF  [CAP0402_0-75]
FB1  300E  [IND0603]
FB2  300E  [IND0603]
FB3  300E  [IND0603]
FL17  120E  [EMIFIL_BLM15A_0402_0-6]
J5  CON_HDMI_1X19_F  [CON_19X1_10029449-001RLF_S_R_S_6-3]
R34  0E  [RES0201_0-5]
R41  10K_1%  [RES0201_0-5]
R60  0E  [RES0201_0-5]
R61  4.7K  [RES0201_0-5]
R62  0E  [RES0201_0-5]
R287  0E  [RES0201_0-5]
R314  0E  [RES0201_0-5]
R316  2.2K  [RES0402_0-5]
R323  2.2K  [RES0402_0-5]
R325  10K  [RES0201_0-5]
R326  10K  [RES0402_0-5]
R327  7.5K  [RES0402_0-5]
R373  10K  [RES0201_0-5]
R389  10K  [RES0201_0-5]
R390  10K  [RES0201_0-5]
TP14  TP20_SMD  [TP20_SMD]
TP16  TP20_SMD  [TP20_SMD]
TP18  TP20_SMD  [TP20_SMD]
TP88  TP20_SMD  [TP20_SMD]
U7  12.288MHz  [OSC4_KC2520B_100X80_SMD_0-8]
U10  SiI9022ACNU  [QFN72_19-68_390X390_0-9]
U50  TPD12S016PWR  [TSSOP24_25-59_315X180_1-2]
U54  SN74LVC1G08DBVRE4  [SOT23-5]
sheet 42. OSCILLATOR
C334  0.01uF  [CAP0201_0-5]
C429  0.1uF  [CAP0201_0-5]
C472  0.1uF  [CAP0201_0-5]
R201  4.7K  [RES0201_0-5]
R220  10K  [RES0201_0-5]
R336  22E_1%  [RES0201_0-5]
R337  0E  [RES0201_0-5]
R370  10K_1%  [RES0201_0-5]
R381  10K  [RES0201_0-5]
R384  22E_1%  [RES0201_0-5]
R385  0E  [RES0201_0-5]
R391  4.7K  [RES0201_0-5]
R392  4.7K  [RES0201_0-5]
R472  10K  [RES0201_0-5]
R490  4.7K  [RES0201_0-5]
R491  4.7K  [RES0201_0-5]
R584  10K  [RES0201_0-5]
R613  0E  [RES0201_0-5]
R681  2.2K  [RES0201_0-5]
TP25  TP20_SMD  [TP20_SMD]
TP34  TP20_SMD  [TP20_SMD]
TP64  TP20_SMD  [TP20_SMD]
TP69  TP20_SMD  [TP20_SMD]
U53  25.000MHz  [OSC4_ECS-2520MV_100X80_SMD_0-9]
U72  SN74LVC1G11DRYR  [SON6_SN74LVC2G17_40X60_0-6]
U90  SN74LVC1G08DPWR  [X2SON5_TLV7021_30X30_0-4]
sheet 43. RESET
C156  0.1uF  [CAP0201_0-5]
C446  0.1uF  [CAP0201_0-5]
C469  0.1uF  [CAP0201_0-5]
C470  0.1uF  [CAP0201_0-5]
D12  TPD1E10B06DPYR  [DIO_DFN0402_0-5]
D13  TPD1E10B06DPYR  [DIO_DFN0402_0-5]
Q2  IRLML6401  [TO_SOT23-123]
Q17  IRLML6401  [TO_SOT23-123]
Q18  IRLML6401  [TO_SOT23-123]
R200  10K  [RES0201_0-5]
R538  10K  [RES0201_0-5]
R550  4.7K  [RES0201_0-5]
R572  10K  [RES0201_0-5]
R575  10K  [RES0201_0-5]
R576  10K  [RES0201_0-5]
SW3  7914G-1-000E  [SW4_100X216_200X200_SMD_4-2]
SW4  7914G-1-000E  [SW4_100X216_200X200_SMD_4-2]
TP68  TP20_SMD  [TP20_SMD]
TP78  TP20_SMD  [TP20_SMD]
TP85  TP20_SMD  [TP20_SMD]
U82  SN74LVC3G17DCUR  [VSSOP8_19-68_85X95_0-9]
sheet 44. ACCESSORIES
ACC1  9774015243R  [NA]
FID1  FID_40X80  [FID_40X80]
FID2  FID_40X80  [FID_40X80]
FID3  FID_40X80  [FID_40X80]
FID4  FID_40X80  [FID_40X80]
FID5  FID_40X80  [FID_40X80]
FID6  FID_40X80  [FID_40X80]
LBL1  THT-103-423-10  [NA]
LBL2  THT-103-423-10  [NA]
LBL3  THT-103-423-10  [NA]
LOGO1  Texas Intruments  [TI_Stacked_Overlay_Small]
LOGO2  For Evaluation only; not FCC approved for resale  [FCC_disclaimer]
LOGO3  WEEE Mark  [TI_Stacked_Overlay_Small]
LOGO4  CE Mark  [TI_Stacked_Overlay_Small]
MH1  FLAT WASHER_M2  [NA]
MH2  PAN HEAD_M2 X 5  [NA]
PCB1  PROC142E1

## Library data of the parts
U12 = AM62-EVM_BGA425: IC AM62 SoC MICROPROCESSOR BGA425; Chkd/date: ALVY/110621; Crtd /date: MANIRAJA/110621; Custom_Duty: 15%; Customs_HS_Code: 85423100; Distributor_name: NA; Distributor_part_number: NA; Footprint Path: Y:\MIS_DATABASE\Library\ALTIUM_TOOL\PCB_FOOTPRINTS\Altium_Footprint_Lib.PcbLib; Height: 0.65MM; Library Path: Y:\MIS_DATABASE\Library\ALTIUM_TOOL\SCHEMATICS_PARTS\MS_MICROPROCESSOR_Library.schlib; Mfr_name: TEXAS INSTRUMENTS; Mistral Part No: 141221060001; Package: BGA425; Part_type: ICS\DIGITAL\MICROPROCESSOR; Project: AM62_EVM_BRD; RoHS: NA; Temperature: NA; Tolerance: NA; Voltage: NA; Wattage: NA; Weight: NA; Datasheet: Y:\MIS_DATABASE\DATASHEETS\ICS\DIGITAL\MICROCONTROLLER\AM62-SoC_SVB.PDF
C20 C156 C429 C446 C469 C470 C472 = CAP: CAP CERAMIC 0.1uF 16V 10% X5R 0201; Alt_Mfr_name: YAGEO AMERICA; Alt_Mfr_part_number: CC0402KRX5R8BB104; Chkd/date: MANIRAJA/230118; Crtd /date: MANIRAJA/230118; Custom_Duty: 15%; Customs_HS_Code: 85322990; Distributor_name: DIGIKEY; Distributor_part_number: 490-14305-1-ND; Footprint Path: Y:\MIS_DATABASE\Library\ALTIUM_TOOL\PCB_FOOTPRINTS\Altium_Footprint_Lib.PcbLib; Height: 0.33MM; Library Path: Y:\MIS_DATABASE\Library\ALTIUM_TOOL\SCHEMATICS_PARTS\MS_DISCRETE_Library.schlib; Mfr_name: MURATA; Mfr_part_number: GRM033R61C104KE14D; Mistral Part No: 120009030072-R; Package: 0201; Part_type: CAPACITORS\CERAMIC; Project: TI_MAXIE_CPB; RoHS: RoHS; Temperature: -55°C+85°C; Tolerance: 10%; Voltage: 16V; Wattage: NA; Weight: 0.33mg; Datasheet: Y:\MIS_DATABASE\DATASHEETS\CAPACITORS\GRM033R61C104KE14.PDF
C199 C201 C204 C211 C219 C230 C248 = CAP: CAP CERAMIC 10uF 10V 20% X5R 0402; Chkd/date: MANIRAJA/300520; Crtd /date: ALVY/260520; Custom_Duty: 15%; Customs_HS_Code: 85322990; Distributor_name: DIGIKEY; Distributor_part_number: 490-GRM155R61A106ME11DTR-ND; Footprint Path: Y:\MIS_DATABASE\Library\ALTIUM_TOOL\PCB_FOOTPRINTS\Altium_Footprint_Lib.PcbLib; Height: 0.55MM; Library Path: Y:\MIS_DATABASE\Library\ALTIUM_TOOL\SCHEMATICS_PARTS\MS_DISCRETE_Library.schlib; Mfr_name: MURATA; Mfr_part_number: GRM155R61A106ME11D; Mistral Part No: 120013110019-R; Package: 0402; Part_type: CAPACITORS\CERAMIC; Project: QCS610_NANOSOM; RoHS: RoHS; Temperature: -55°C+85°C; Tolerance: 20%; Voltage: 10V; Wattage: NA; Weight: 3.1mg; Datasheet: Y:\MIS_DATABASE\DATASHEETS\CAPACITORS\MURATA-GXX-SER_NOV17.PDF
C200 C207 C209 C212 C213 C217 C223 C225 C229 C231 = CAP: CAP CERAMIC 0.1uF 16V 10% X5R 0201; Chkd/date: MANIRAJA/230118; Crtd /date: MANIRAJA/230118; Custom_Duty: 15%; Customs_HS_Code: 85322990; Distributor_name: DIGIKEY; Distributor_part_number: 490-14305-1-ND; Footprint Path: Y:\MIS_DATABASE\Library\ALTIUM_TOOL\PCB_FOOTPRINTS\Altium_Footprint_Lib.PcbLib; Height: 0.33MM; Library Path: Y:\MIS_DATABASE\Library\ALTIUM_TOOL\SCHEMATICS_PARTS\MS_DISCRETE_Library.schlib; Mfr_name: MURATA; Mfr_part_number: GRM033R61C104KE14D; Mistral Part No: 120009030072-R; Package: 0201; Part_type: CAPACITORS\CERAMIC; Project: TI_MAXIE_CPB; RoHS: RoHS; Temperature: -55°C+85°C; Tolerance: 10%; Voltage: 16V; Wattage: NA; Weight: 0.33mg; Datasheet: Y:\MIS_DATABASE\DATASHEETS\CAPACITORS\GRM033R61C104KE14.PDF
C232 = CAP: CAP CERAMIC 22uF 10V 20% X5R 0603; Chkd/date: MANIRAJA/230118; Crtd /date: MANIRAJA/230118; Custom_Duty: 15%; Customs_HS_Code: 85322990; Distributor_name: DIGIKEY; Distributor_part_number: 490-10476-1-ND; Footprint Path: Y:\MIS_DATABASE\Library\ALTIUM_TOOL\PCB_FOOTPRINTS\Altium_Footprint_Lib.PcbLib; Height: 1.00MM; Library Path: Y:\MIS_DATABASE\Library\ALTIUM_TOOL\SCHEMATICS_PARTS\MS_DISCRETE_Library.schlib; Mfr_name: MURATA; Mfr_part_number: GRM188R61A226ME15D; Mistral Part No: 120014100009-R; Package: 0603; Part_type: CAPACITORS\CERAMIC; Project: TI_MAXIE_CPB; RoHS: RoHS; Temperature: -55°C+85°C; Tolerance: 20%; Voltage: 10V; Wattage: NA; Weight: 6.3mg; Datasheet: Y:\MIS_DATABASE\DATASHEETS\CAPACITORS\GRM188R61A226ME15.PDF
C323 = CAP: CAP CERAMIC 0.1uF 50V 10% X7R 0402; Alt_Mfr_name: YAGEO AMERICA; Alt_Mfr_part_number: CC0402KRX5R8BB104; Chkd/date: MANIRAJA/261020; Crtd /date: ALVY/211020; Custom_Duty: 15%; Customs_HS_Code: 85322990; Distributor_name: DIGIKEY; Distributor_part_number: 490-10700-1-ND; Footprint Path: Y:\MIS_DATABASE\Library\ALTIUM_TOOL\PCB_FOOTPRINTS\Altium_Footprint_Lib.PcbLib; Height: 0.55MM; Library Path: Y:\MIS_DATABASE\Library\ALTIUM_TOOL\SCHEMATICS_PARTS\MS_DISCRETE_Library.schlib; Mfr_name: MURATA; Mfr_part_number: GRM155R71H104KE14D; Mistral Part No: 120011100014-R; Package: 0402; Part_type: CAPACITORS\CERAMIC; Project: J7_CP; RoHS: RoHS; Temperature: -55°C+125°C; Tolerance: 10%; Voltage: 50V; Wattage: NA; Weight: 3.1mg; Datasheet: Y:\MIS_DATABASE\DATASHEETS\CAPACITORS\GRM155R71H104KE14.PDF
FB1-FB3 = INDUCTOR_FERRITE: IND FERRITE CHIP 300E 500mA 0603; Alternate_mfr_name_A: TDK CORPORATION; Alternate_mfr_part_number_A: MMZ1608R301ATA00; Chkd/date: VASANTHA/190614; Crtd /date: NAVEED/160614; Custom_Duty: 24%; Customs_HS_Code: 85437099; Distributor_name: DIGIKEY; Distributor_name_A: DIGIKEY; Distributor_part_number: 445-2171-1-ND; Distributor_part_number_A: 445-2171-1-ND; Height: 0.75MM; Mfr_name: TDK CORPORATION; Mfr_part_number: MMZ1608R301A; Mistral Part No: 130014060028-R; Package: 0603; Part_type: INDUCTOR; Project: AEGIS_POM; RoHS: RoHS; Temperature: -55°C+125°C; Tolerance: NA; Voltage: NA; Wattage: NA; Weight: NA; Datasheet: Y:\MIS_DATABASE\DATASHEETS\DISCRETES\INDUCTORS\MMZSER.PDF
FL17 = EMIFILTER_IND: IND FERRITE BEAD CHIP 120E 2A 0402; Chkd/date: NAVEED/241114; Crtd /date: USMAN/170613; Custom_Duty: 24%; Customs_HS_Code: 85369090; Distributor_name: DIGIKEY; Distributor_part_number: 490-9656-1-ND; Footprint Path: Y:\MIS_DATABASE\Library\ALTIUM_TOOL\PCB_FOOTPRINTS\Altium_Footprint_Lib.PcbLib; Height: 0.55MM; Library Path: Y:\MIS_DATABASE\Library\ALTIUM_TOOL\SCHEMATICS_PARTS\MS_FILTER_Library.schlib; Mfr_name: MURATA; Mfr_part_number: BLM15PX121SN1D; Mistral Part No: 130013060022-R; Package: 0402; Part_type: INDUCTOR; Project: GEN_3-8; RoHS: RoHS; Temperature: -55°C+125°C; Tolerance: 25%; Voltage: NA; Wattage: NA; Weight: 1mg; Datasheet: Y:\MIS_DATABASE\DATASHEETS\DISCRETES\INDUCTORS\BLM15-SN1-SER.PDF
J5 = CON_HDMI_19X1: CON HDMI-A TYPE 1X19 0.50MM PITCH FEMALE RT SMD; Chkd/date: VASANTHA/060117; Crtd /date: MUDDU/060510; Custom_Duty: 24%; Customs_HS_Code: 85369090; Distributor_name: DIGIKEY; Distributor_part_number: 609-1010-1-ND; Footprint Path: Y:\MIS_DATABASE\Library\ALTIUM_TOOL\PCB_FOOTPRINTS\Altium_Footprint_Lib.PcbLib; Height: 6.30MM; Library Path: Y:\MIS_DATABASE\Library\ALTIUM_TOOL\SCHEMATICS_PARTS\MS_CONNECTOR_Library.schlib; Mfr_name: FCI; Mfr_part_number: 10029449-001RLF; Mistral Part No: 150010050001-R; Package: SMD; Part_type: CONNECTOR\HDMI; Project: SHIVA; RoHS: RoHS; Temperature: -20°C+85°C; Tolerance: NA; Voltage: NA; Wattage: NA; Weight: 2700mg; Datasheet: Y:\MIS_DATABASE\DATASHEETS\CONNECTORS\10029449-001RLF.PDF
R34 R62 R287 R314 R337 R385 R613 = RESISTOR: RES 0E 1/20W 5% 0201; Chkd/date: NAVEED/301214; Crtd /date: MUDDU/120710; Custom_Duty: 15%; Customs_HS_Code: 85332119; Distributor_name: DIGIKEY; Distributor_part_number: 311-0.0NCT-ND; Footprint Path: Y:\MIS_DATABASE\Library\ALTIUM_TOOL\PCB_FOOTPRINTS\Altium_Footprint_Lib.PcbLib; Height: 0.26MM; Library Path: Y:\MIS_DATABASE\Library\ALTIUM_TOOL\SCHEMATICS_PARTS\MS_DISCRETE_Library.schlib; Mfr_name: YAGEO AMERICA; Mfr_part_number: RC0201JR-070RL; Mistral Part No: 110010070067-R; Package: 0201; Part_type: RESISTORS\FIXED; Project: PB_BUGBASE; RoHS: RoHS; Temperature: -55°C+125°C; Tolerance: 5%; Voltage: NA; Wattage: 1/20W; Weight: 0.17mg; Datasheet: Y:\MIS_DATABASE\DATASHEETS\RESISTORS\RCXXXXL-SER_MAR18.PDF
R41 R370 = RESISTOR: RES 10K 1/20W 1% 0201; Chkd/date: VASANTHA/270117; Crtd /date: MANIRAJA/270117; Custom_Duty: 15%; Customs_HS_Code: 85332119; Distributor_name: DIGIKEY; Distributor_part_number: 311-10.0KMCT-ND; Footprint Path: Y:\MIS_DATABASE\Library\ALTIUM_TOOL\PCB_FOOTPRINTS\Altium_Footprint_Lib.PcbLib; Height: 0.26MM; Library Path: Y:\MIS_DATABASE\Library\ALTIUM_TOOL\SCHEMATICS_PARTS\MS_DISCRETE_Library.schlib; Mfr_name: YAGEO AMERICA; Mfr_part_number: RC0201FR-0710KL; Mistral Part No: 110011040018-R; Package: 0201; Part_type: RESISTORS\FIXED; Project: GOLDEN-I LITE; RoHS: RoHS; Temperature: -55°C+125°C; Tolerance: 1%; Voltage: NA; Wattage: 1/20W; Weight: 0.17mg; Datasheet: Y:\MIS_DATABASE\DATASHEETS\RESISTORS\RCXXXXL-SER_MAR18.PDF
R60 = RESISTOR: RES 0E 1/20W 5% 0201; Chkd/date: NAVEED/301214; Crtd /date: MUDDU/120710; Custom_Duty: 15%; Customs_HS_Code: 85332119; Distributor_name: DIGIKEY; Distributor_part_number: 311-0.0NCT-ND; Footprint Path: Y:\MIS_DATABASE\Library\ALTIUM_TOOL\PCB_FOOTPRINTS\Altium_Footprint_Lib.PcbLib; Height: 0.26MM; Library Path: Y:\MIS_DATABASE\Library\ALTIUM_TOOL\SCHEMATICS_PARTS\MS_DISCRETE_Library.schlib; Mfr_name: YAGEO AMERICA; Mfr_part_number: RC0201JR-070RL; Mistral Part No: 110010070067-R; Package: 0201; Part_type: RESISTORS\FIXED; Project: PB_BUGBASE; RoHS: RoHS; SIGNAL_MODEL: RESISTOR_RES0201_0-5_0E_0E; Temperature: -55°C+125°C; Tolerance: 5%; Voltage: NA; Wattage: 1/20W; Weight: 0.17mg; Datasheet: Y:\MIS_DATABASE\DATASHEETS\RESISTORS\RCXXXXL-SER_MAR18.PDF
R61 R201 R391 R392 R490 R491 = RESISTOR: RES 4.7K 1/20W 5% 0201; Chkd/date: MANIRAJA/200921; Crtd /date: ALVY/200921; Custom_Duty: 15%; Customs_HS_Code: 85332119; Distributor_name: DIGIKEY; Distributor_part_number: 311-4.7KNCT-ND; Footprint Path: Y:\MIS_DATABASE\Library\ALTIUM_TOOL\PCB_FOOTPRINTS\Altium_Footprint_Lib.PcbLib; Height: 0.26MM; Library Path: Y:\MIS_DATABASE\Library\ALTIUM_TOOL\SCHEMATICS_PARTS\MS_DISCRETE_Library.schlib; Mfr_name: YAGEO AMERICA; Mfr_part_number: RC0201JR-074K7L; Mistral Part No: 110021090007-R; Package: 0201; Part_type: RESISTORS\FIXED; Project: TI_AM62x SKEVM_BRD; RoHS: RoHS; Temperature: -55°C+125°C; Tolerance: 5%; Voltage: NA; Wattage: 1/20W; Weight: 0.17mg; Datasheet: Y:\MIS_DATABASE\DATASHEETS\RESISTORS\RCXXXXL-SER_MAR18.PDF
R316 R323 = RESISTOR: RES 2.2K 1/16W 5% 0402; Chkd/date: NAVEED/150714; Crtd /date: VASANTHA/240614; Custom_Duty: 15%; Customs_HS_Code: 85332119; Distributor_name: DIGIKEY; Distributor_part_number: 541-2.2KJCT-ND; Footprint Path: Y:\MIS_DATABASE\Library\ALTIUM_TOOL\PCB_FOOTPRINTS\Altium_Footprint_Lib.PcbLib; Height: 0.40MM; Library Path: Y:\MIS_DATABASE\Library\ALTIUM_TOOL\SCHEMATICS_PARTS\MS_DISCRETE_Library.schlib; Mfr_name: VISHAY; Mfr_part_number: CRCW04022K20JNED; Mistral Part No: 110010120018-R; Package: 0402; Part_type: RESISTORS\FIXED; Project: AEGIS_POM; RoHS: RoHS; Temperature: -55°C+155°C; Tolerance: 5%; Voltage: NA; Wattage: 1/16W; Weight: 0.65mg; Datasheet: Y:\MIS_DATABASE\DATASHEETS\RESISTORS\CRCW0603.PDF
R200 R220 R325 R373 R381 R389 R390 R472 R538 R572 R575 R576 R584 = RESISTOR: RES 10K 1/20W 5% 0201; Chkd/date: MANIRAJA/050517; Crtd /date: MANIRAJA/050517; Custom_Duty: 15%; Customs_HS_Code: 85332119; Distributor_name: DIGIKEY; Distributor_part_number: 311-10KNCT-ND; Footprint Path: Y:\MIS_DATABASE\Library\ALTIUM_TOOL\PCB_FOOTPRINTS\Altium_Footprint_Lib.PcbLib; Height: 0.26MM; Library Path: Y:\MIS_DATABASE\Library\ALTIUM_TOOL\SCHEMATICS_PARTS\MS_DISCRETE_Library.schlib; Mfr_name: YAGEO AMERICA; Mfr_part_number: RC0201JR-0710KL; Mistral Part No: 110010070051-R; Package: 0201; Part_type: RESISTORS\FIXED; Project: GOLDEN-I LITE; RoHS: RoHS; Temperature: -55°C+125°C; Tolerance: 5%; Voltage: NA; Wattage: 1/20W; Weight: 0.17mg; Datasheet: Y:\MIS_DATABASE\DATASHEETS\RESISTORS\RCXXXXL-SER_MAR18.PDF
R326 = RESISTOR: RES 10K 1/16W 5% 0402; Chkd/date: MANIRAJA/120219; Crtd /date: MANIRAJA/120219; Custom_Duty: 15%; Customs_HS_Code: 85332119; Distributor_name: DIGIKEY; Distributor_part_number: 541-10KJCT-ND; Footprint Path: Y:\MIS_DATABASE\Library\ALTIUM_TOOL\PCB_FOOTPRINTS\Altium_Footprint_Lib.PcbLib; Height: 0.40MM; Library Path: Y:\MIS_DATABASE\Library\ALTIUM_TOOL\SCHEMATICS_PARTS\MS_DISCRETE_Library.schlib; Mfr_name: VISHAY; Mfr_part_number: CRCW040210K0JNED; Mistral Part No: 110011060021-R; Package: 0402; Part_type: RESISTORS\FIXED; Project: NEXTNAV_ORBIT_MODULE; RoHS: RoHS; Temperature: -55°C+155°C; Tolerance: 5%; Voltage: NA; Wattage: 1/16W; Weight: 0.65mg; Datasheet: Y:\MIS_DATABASE\DATASHEETS\RESISTORS\CRCW0603.PDF
R327 = RESISTOR: RES 7.5K 1/16W 5% 0402; Chkd/date: MAZHAR/280108; Crtd /date: USMAN/280108; Custom_Duty: 15%; Customs_HS_Code: 85332119; Distributor_name: DIGIKEY; Distributor_part_number: 541-7.5KJCT-ND; Footprint Path: Y:\MIS_DATABASE\Library\ALTIUM_TOOL\PCB_FOOTPRINTS\Altium_Footprint_Lib.PcbLib; Height: 0.40MM; Library Path: Y:\MIS_DATABASE\Library\ALTIUM_TOOL\SCHEMATICS_PARTS\MS_DISCRETE_Library.schlib; Mfr_name: VISHAY; Mfr_part_number: CRCW04027K50JNED; Mistral Part No: 110009031092-R; Package: 0402; Part_type: RESISTORS\FIXED; Project: TELEMETRY ENCODER; RoHS: RoHS; Temperature: -55°C+155°C; Tolerance: 5%; Voltage: NA; Wattage: 1/16W; Weight: 0.65mg; Datasheet: Y:\MIS_DATABASE\DATASHEETS\RESISTORS\CRCW0603.PDF
TP14 TP16 TP18 TP25 TP34 TP64 TP68 TP69 TP78 TP85 TP88 = TESTPOINT: TESTPOINT CIR 20 SMD; Chkd/date: SHREESHAIL/171006; Crtd /date: MAZHAR/171006; Custom_Duty: NA; Customs_HS_Code: NA; Distributor_name: NA; Distributor_part_number: NA; Footprint Path: Y:\MIS_DATABASE\Library\ALTIUM_TOOL\PCB_FOOTPRINTS\Altium_Footprint_Lib.PcbLib; Height: NA; Library Path: Y:\MIS_DATABASE\Library\ALTIUM_TOOL\SCHEMATICS_PARTS\MS_DISCRETE_Library.schlib; MECHANICAL 3D STEP FILE: NA; Mfr_name: LOCAL; Mistral Part No: NA; Package: SMD; Project: BT MODULE_CSRBC04; RoHS: NA; Temperature: NA; Tolerance: NA; Voltage: NA; Wattage: NA; Weight: NA; Datasheet: NA
U7 = OSC_KC2016K: OSC 12.288MHz CMOS SMD; Chkd/date: MANIRAJA/061021; Crtd /date: ALVY/061021; Custom_Duty: 24%; Customs_HS_Code: 85437099; Distributor_name: DIGIKEY; Distributor_part_number: 1253-KC2520Z12.2880C1KX00CT-ND; Footprint Path: Y:\MIS_DATABASE\Library\ALTIUM_TOOL\PCB_FOOTPRINTS\Altium_Footprint_Lib.PcbLib; Height: 0.80MM; Library Path: Y:\MIS_DATABASE\Library\ALTIUM_TOOL\SCHEMATICS_PARTS\MS_DISCRETE_Library.schlib; Mfr_name: KYOCERA; Mfr_part_number: KC2520Z12.2880C1KX00; Mistral Part No: 130021100008-R; Package: SMD; Part_type: OSCILLATORS; Project: TI_AM62x SKEVM_BRD; RoHS: RoHS; Temperature: -40°C+85°C; Tolerance: NA; Voltage: NA; Wattage: NA; Weight: NA; Datasheet: Y:\MIS_DATABASE\DATASHEETS\MISC\CRY_OSC\KC-Z-SERPDF
U10 = SII9022ACNU_QFN72: IC HDMI TRANSMITTER QFN72; Chkd/date: MANIRAJA/270818; Crtd /date: MUDDU/310510; Custom_Duty: 15%; Customs_HS_Code: 85423100; Distributor_name: NA; Distributor_part_number: NA; Footprint Path: Y:\MIS_DATABASE\Library\ALTIUM_TOOL\PCB_FOOTPRINTS\Altium_Footprint_Lib.PcbLib; Height: 0.90MM; Library Path: Y:\MIS_DATABASE\Library\ALTIUM_TOOL\SCHEMATICS_PARTS\MS_COMBINATIONAL_Library.schlib; Library Ref: SiI9022ACNU_QFN72; Mfr_name: SILICON IMAGE; Mistral Part No: 141010060001; Package: QFN72; Part_type: ICS\DIGITAL\PERIPHERAL; Project: CENTAURUS; RoHS: NA; Temperature: -20°C+85°C; Tolerance: NA; Voltage: NA; Wattage: NA; Weight: NA; Datasheet: Y:\MIS_DATABASE\DATASHEETS\ICS\DIGITAL\PERIPHERAL\SiI9022.PDF
U50 = TPD12S016PW_TSSOP24: IC HDMI COMPANION CHIP WITH I2C LEVEL SHIFTING,12-CH ESD TSSOP24; Chkd/date: MANIRAJA/110917; Crtd /date: BAVISH/180811; Custom_Duty: 15%; Customs_HS_Code: 85423100; Distributor_name: DIGIKEY; Distributor_part_number: 296-29690-1-ND; Height: 1.20MM; Mfr_name: TEXAS INSTRUMENTS; Mistral Part No: 141011080021-R; Package: TSSOP24; Part_type: ICS\INTERFACE; Project: DM385EVM_BASE-BOARD; RoHS: RoHS; Temperature: -40°C+85°C; Tolerance: NA; Voltage: NA; Wattage: NA; Weight: 212mg; Datasheet: Y:\MIS_DATABASE\DATASHEETS\ICS\INTERFACE\TPD12S016.PDF
U54 = SN74LVC1G08DBVRE4_SOT23-5: IC SINGLE 2-INPUT POSITIVE AND GATE SOT23-5; Chkd/date: SUHAS/221010; Crtd /date: USMAN/151008; Custom_Duty: 15%; Customs_HS_Code: 85423100; Distributor_name: DIGIKEY; Distributor_part_number: SN74LVC1G08DBVRE4-ND; Height: 1.45MM; Mfr_name: TEXAS INSTRUMENTS; Mistral Part No: 141009060026-R; Part_type: ICS\DIGITAL\GATES; Project: KHAN_MAIN; RoHS: Sb/ Br FREE; Temperature: -40°C+85°C; Datasheet: Y:\MIS_DATABASE\DATASHEETS\ICS\DIGITAL\GATES\SN74LVC1G08.PDF
C334 = CAP: CAP CERAMIC 0.01uF 25V 10% X5R 0201; Chkd/date: MANIRAJA/230118; Crtd /date: MANIRAJA/230118; Custom_Duty: 15%; Customs_HS_Code: 85322990; Distributor_name: DIGIKEY; Distributor_part_number: GRM033R61E103KA12J-ND; Footprint Path: Y:\MIS_DATABASE\Library\ALTIUM_TOOL\PCB_FOOTPRINTS\Altium_Footprint_Lib.PcbLib; Height: 0.33MM; Library Path: Y:\MIS_DATABASE\Library\ALTIUM_TOOL\SCHEMATICS_PARTS\MS_DISCRETE_Library.schlib; Mfr_name: MURATA; Mfr_part_number: GRM033R61E103KA12J; Mistral Part No: 120018010007-R; Package: 0201; Part_type: CAPACITORS\CERAMIC; Project: TI_MAXIE_CPB; RoHS: RoHS; Temperature: -55°C+85°C; Tolerance: 10%; Voltage: 25V; Wattage: NA; Weight: 0.33mg; Datasheet: Y:\MIS_DATABASE\DATASHEETS\CAPACITORS\GRM033R61E103KA12.PDF
R336 R384 = RESISTOR: RES 22E 1/20W 1% 0201; Chkd/date: MAZHAR/140709; Crtd /date: MAZHAR/220807; Custom_Duty: 15%; Customs_HS_Code: 85332119; Distributor_name: DIGIKEY; Distributor_part_number: P22.0ABCT-ND; Footprint Path: Y:\MIS_DATABASE\Library\ALTIUM_TOOL\PCB_FOOTPRINTS\Altium_Footprint_Lib.PcbLib; Height: 0.26MM; Library Path: Y:\MIS_DATABASE\Library\ALTIUM_TOOL\SCHEMATICS_PARTS\MS_DISCRETE_Library.schlib; Mfr_name: PANASONIC-ECG; Mfr_part_number: ERJ-1GEF22R0C; Mistral Part No: 110009030522-R; Package: 0201; Part_type: RESISTORS\FIXED; Project: V8TS; RoHS: RoHS; Temperature: -55°C+125°C; Tolerance: 1%; Voltage: NA; Wattage: 1/20W; Weight: 0.15mg; Datasheet: Y:\MIS_DATABASE\DATASHEETS\RESISTORS\PAN-ERJSER_NOV17.PDF
R681 = RESISTOR: RES 2.2K 1/20W 5% 0201; Chkd/date: VASANTHA/010117; Crtd /date: MAZHAR/010605; Custom_Duty: 15%; Customs_HS_Code: 85332119; Distributor_name: DIGIKEY; Distributor_part_number: P2.2KAGCT-ND; Footprint Path: Y:\MIS_DATABASE\Library\ALTIUM_TOOL\PCB_FOOTPRINTS\Altium_Footprint_Lib.PcbLib; Height: 0.26MM; Library Path: Y:\MIS_DATABASE\Library\ALTIUM_TOOL\SCHEMATICS_PARTS\MS_DISCRETE_Library.schlib; Mfr_name: PANASONIC-ECG; Mfr_part_number: ERJ-1GEJ222C; Mistral Part No: 110009030427-R; Package: 0201; Part_type: RESISTORS\FIXED; Project: G4SLIM; RoHS: RoHS; Temperature: -55°C+125°C; Tolerance: 5%; Voltage: NA; Wattage: 1/20W; Weight: 0.15mg; Datasheet: Y:\MIS_DATABASE\DATASHEETS\RESISTORS\PAN-ERJXGE-FEB06.PDF
U53 = OSC4_ASFL3: OSC 25.000MHz CMOS SMD; Chkd/date: MANIRAJA/181120; Crtd /date: ALVY/181120; Custom_Duty: 24%; Customs_HS_Code: 85437099; Distributor_name: DIGIKEY; Distributor_part_number: XC2752CT-ND; Footprint Path: Y:\MIS_DATABASE\Library\ALTIUM_TOOL\PCB_FOOTPRINTS\Altium_Footprint_Lib.PcbLib; Height: 0.90MM; Library Path: Y:\MIS_DATABASE\Library\ALTIUM_TOOL\SCHEMATICS_PARTS\MS_DISCRETE_Library.schlib; Mfr_name: ECS INC; Mfr_part_number: ECS-2520MV-250-CN-TR; Mistral Part No: 130020110041-R; Package: SMD; Part_type: OSCILLATORS; Project: AM64X_SKEVM; RoHS: RoHS; Temperature: -40°C+85°C; Tolerance: NA; Voltage: NA; Wattage: NA; Weight: 311mg; Datasheet: Y:\MIS_DATABASE\DATASHEETS\MISC\CRY_OSC\ECS-2520MV.PDF
U72 = SN74LVC1G11DCKR_SC70-6: IC SINGLE 3-INPUT POSITIVE-AND GATE SON6; Chkd/date: MANIRAJA/270121; Crtd /date: ALVY/270121; Custom_Duty: 15%; Customs_HS_Code: 85423100; Distributor_name: DIGIKEY; Distributor_part_number: 296-30120-1-ND; Footprint Path: Y:\MIS_DATABASE\Library\ALTIUM_TOOL\PCB_FOOTPRINTS\Altium_Footprint_Lib.PcbLib; Height: 0.60MM; Library Path: Y:\MIS_DATABASE\Library\ALTIUM_TOOL\SCHEMATICS_PARTS\MS_GATE_Library.schlib; Mfr_name: TEXAS INSTRUMENTS; Mistral Part No: 141021010013-R; Package: SON6; Part_type: ICS\DIGITAL\GATES; Project: AM64X_SKEVM; RoHS: RoHS; Temperature: -40°C+125°C; Tolerance: NA; Voltage: NA; Wattage: NA; Weight: 33mg; Datasheet: Y:\MIS_DATABASE\DATASHEETS\ICS\DIGITAL\GATES\SN74LVC1G_NOV16.PDF
U90 = 74AHC1G08GW_SOT353-5: IC SINGLE 2-INPUT POSITIVE-AND GATE X2SON5; Chkd/date: MANIRAJA/141020; Crtd /date: ALVY/131020; Custom_Duty: 15%; Customs_HS_Code: 85423100; Distributor_name: DIGIKEY; Distributor_part_number: 296-40549-1-ND; Footprint Path: Y:\MIS_DATABASE\Library\ALTIUM_TOOL\PCB_FOOTPRINTS\Altium_Footprint_Lib.PcbLib; Height: 0.40MM; Library Path: Y:\MIS_DATABASE\Library\ALTIUM_TOOL\SCHEMATICS_PARTS\MS_GATE_Library.schlib; Manufacturer: TEXAS INSTRUMENTS; Mistral Part No: 141020100009-R; Package: X2SON5; Part_type: ICS\DIGITAL\GATES; Project: AM64X_SKEVM; RoHS: RoHS; Temperature: -40°C+125°C; Tolerance: NA; Voltage: NA; Wattage: NA; Weight: 0.6mg; Datasheet: Y:\MIS_DATABASE\DATASHEETS\ICS\DIGITAL\GATES\SN74LVC1G08XX.PDF
D12 D13 = DIODE_SOD323: DIODE 1CH ESD PROTECTION X1SON2; Chkd/date: MANIRAJA/040420; Crtd /date: VASANTHA/181114; Custom_Duty: 15%; Customs_HS_Code: 85423100; Distributor_name: DIGIKEY; Distributor_part_number: 296-30406-1-ND; Footprint Path: Y:\MIS_DATABASE\Library\ALTIUM_TOOL\PCB_FOOTPRINTS\Altium_Footprint_Lib.PcbLib; Height: 0.45MM; Library Path: Y:\MIS_DATABASE\Library\ALTIUM_TOOL\SCHEMATICS_PARTS\MS_DISCRETE_Library.schlib; Mfr_name: TEXAS INSTRUMENTS; Mistral Part No: 130014110022-R; Package: X1SON2; Part_type: DIODE; Project: GALILEO_EVM; RoHS: RoHS; Temperature: -40°C+125°C; Tolerance: NA; Voltage: NA; Wattage: NA; Weight: 1mg; Datasheet: Y:\MIS_DATABASE\DATASHEETS\ICS\INTERFACE\TPD1E10B06-SER.PDF
Q2 Q17 Q18 = MOSFET_IRLML6401TR: TRANSISTOR MOSFET P-CHANNEL SOT23-3; Chkd/date: SHREESHAIL/020206; Crtd /date: MAZHAR/040505; Custom_Duty: 15%; Customs_HS_Code: 85412900; Distributor_name: DIGIKEY; Distributor_part_number: IRLML6401PBFCT-ND; Height: 1.11MM; Mfr_name: IRF; Mfr_part_number: IRLML6401TRPBF; Mistral Part No: 130009031213-P; Package: SOT23-3; Part_type: TRANSISTOR\MOSFET; Project: G4_SVGA; RoHS: Pb-Free; Temperature: -55°C+150°C; Tolerance: NA; Voltage: NA; Wattage: NA; Weight: NA; Datasheet: Y:\MIS_DATABASE\DATASHEETS\DISCRETES\TRANSISTORS_FETS\IRLML6401.PDF
R550 = RESISTOR: RES 4.7K 1/20W 5% 0201; Chkd/date: MANIRAJA/200921; Crtd /date: ALVY/200921; Custom_Duty: 15%; Customs_HS_Code: 85332119; Distributor_name: DIGIKEY; Distributor_part_number: 311-4.7KNCT-ND; Footprint Path: Y:\MIS_DATABASE\Library\ALTIUM_TOOL\PCB_FOOTPRINTS\Altium_Footprint_Lib.PcbLib; Height: 0.26MM; Library Path: Y:\MIS_DATABASE\Library\ALTIUM_TOOL\SCHEMATICS_PARTS\MS_DISCRETE_Library.schlib; Manufacturer: YAGEO AMERICA; Mfr_name: YAGEO AMERICA; Mfr_part_number: RC0201JR-074K7L; Mistral Part No: 110021090007-R; Package: 0201; Part_type: RESISTORS\FIXED; Project: TI_AM62x SKEVM_BRD; RoHS: RoHS; Temperature: -55°C+125°C; Tolerance: 5%; Voltage: NA; Wattage: 1/20W; Weight: 0.17mg; Datasheet: Y:\MIS_DATABASE\DATASHEETS\RESISTORS\RCXXXXL-SER_MAR18.PDF
SW3 SW4 = 7914G-1-000E__7914G: SWITCH SPST-NO 4MM SQ SMD 7914G; Chkd/date: VASANTHA/271216; Crtd /date: BAVISH/051010; Custom_Duty: 24%; Customs_HS_Code: 85369090; Distributor_name: DIGIKEY; Distributor_part_number: 7914G-000ECT-ND; Height: 4.19MM; Library Ref: 7914G-1-000E _7914G; Mfr_name: BOURNS; Mistral Part No: 130015110004-R; Package: 7914G; Part_type: ELECTRO-MECHANICAL\SWITCH; Project: AAAUC; RoHS: RoHS; Temperature: -55°C+125°C; Tolerance: NA; Voltage: NA; Wattage: NA; Weight: NA; Datasheet: Y:\MIS_DATABASE\DATASHEETS\ICS\DIGITAL\COMBINATIONAL\7914G-1-000E.PDF
U82 = SN74LVC3G17DCUR_VSSOP8: IC TRIPLE SCHMITT-TRIGGER BUFFER VSSOP8; Chkd/date: MANIRAJA/280917; Crtd /date: MANIRAJA/280917; Custom_Duty: 15%; Customs_HS_Code: 85423100; Distributor_name: DIGIKEY; Distributor_part_number: 296-18818-1-ND; Height: 0.90MM; Mfr_name: TEXAS INSTRUMENTS; Mistral Part No: 141017090019-R; Package: VSSOP8; Part_type: ICS\DIGITAL\COMBINATIONAL; Project: TI_MAXIE_CPB; RoHS: RoHS; Temperature: -40°C+125°C; Tolerance: NA; Voltage: NA; Wattage: NA; Weight: 9.6mg; Datasheet: Y:\MIS_DATABASE\DATASHEETS\ICS\DIGITAL\COMBINATIONAL\SN74LVC3G17.PDF
ACC1 = ACCESSORY: STANDOFF BOARD TO BOARD 1.50MM LENGTH FEMALE M2 THREADED SS; Chkd/date: MANIRAJA/280219; Crtd /date: ALVY/280219; Distributor_name: DIGIKEY; Distributor_part_number: 732-7069-1-ND; Mfr_name: WURTH ELECTRONICS; Mistral Part No: 160019020049-R; Package: SS; Part_type: MECHANICAL\STANDOFF; Project: TI_J7ES_EVM_CP; RoHS: RoHS; Weight: 178mg; Datasheet: Y:\MIS_DATABASE\DATASHEETS\MISC\MECHANICAL\9774015243R.PDF
FID1-FID6 = Fiducial
LBL1-LBL3 = ACCESSORY_THT-3-423-10: ACCESSORIE 1 WORKHORSE POLYSTER LABLE 0.25" X 1"; Chkd/date: MANIRAJA/270218; Crtd /date: ALVY/260218; Footprint Path: Y:\MIS_DATABASE\Library\ALTIUM_TOOL\PCB_FOOTPRINTS\Altium_Footprint_Lib.PcbLib; Library Path: Y:\MIS_DATABASE\Library\ALTIUM_TOOL\SCHEMATICS_PARTS\MS_MECHANICAL_Library.schlib; Mfr_name: BRADY; Mistral Part No: 160018020185; Part_type: ACCESSORIES; Project: TI_MAXIE_CPB
LOGO1 LOGO3 LOGO4 = TI_Logo
LOGO2 = FCC_disclaimer
MH1 = WASHER_FLAT: FLAT WASHER FOR M2 NYLON; Chkd/date: MANIRAJA/110319; Crtd /date: ALVY/110319; Distributor_name: DIGIKEY; Distributor_part_number: 36-3356-ND; Mfr_name: KEYSTONE; Mfr_part_number: 3356; Mistral Part No: 160019030017-R; Package: NYLON; Part_type: MECHANICAL\WASHERS; Project: TI_J7ES_EVM_CP; RoHS: RoHS; Datasheet: Y:\MIS_DATABASE\DATASHEETS\MISC\MECHANICAL\3356.PDF
MH2 = SCREW_PAN: PHILLIPS PAN HEAD SCREW - M2 X 5; Chkd/date: MANIRAJA/150319; Crtd /date: MANIRAJA/150319; Distributor_name: DIGIKEY; Distributor_part_number: H738-ND; Height: 5.00MM; Mfr_name: B AND F FASTENER; Mfr_part_number: MPMS 002 0005 PH; Mistral Part No: 160019030026-R; Part_type: MECHANICAL\SCREWS; Project: TI_J7ES_EVM_CP; RoHS: RoHS; Datasheet: Y:\MIS_DATABASE\DATASHEETS\MISC\MECHANICAL\SCREW_MPMSXXX.PDF
PCB1 = PCB: AM62x SKEVM Bare PCB

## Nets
DGND: C20.1 C156.1 C199.2 C200.2 C201.2 C204.2 C207.2 C209.2 C211.2 C212.2 C213.2 C217.2 C219.2 C223.2 C225.2 C229.2 C230.2 C231.2 C232.2 C248.1 C323.2 C334.1 C429.1 C446.1 C469.1 C470.1 C472.1 D12.1 D13.1 FL17.1 J5.2 J5.5 J5.8 J5.11 J5.17 Q2.3(D) Q17.3(D) Q18.3(D) R62.2 R201.2 R287.1 R326.2 R327.2 R373.1 R381.2 R390.1 R472.2 SW3.1 SW3.4 SW4.1 SW4.4 U7.2(GND) U10.43(CGND) U10.55(RSVDL) U10.57(IOGND) U10.63(AGND) U10.70(VDDQ) U10.73(PAD) U50.6(GND1) U50.14(GND2) U50.19(GND3) U53.2(GND) U54.3(GND) U72.2(GND) U82.4(GND) U90.3(GND) ; also on sheet 1 10 11 12 13 14 15 16 17 18 19 20 21 22 23 24 25 26 27 28 29 30 31 32 33 34 35 36 37 38 39 40
VCC1V8_CLKBUF: C334.2 R370.2 U53.4(VDD) ; also on sheet 25
VCC_1V8: C429.2 R220.1 U72.5(VCC) ; also on sheet 12 13 14 18 19 21 25 34 37 39 40
VCC_3V3_SYS: C20.2 C204.1 C248.2 C323.1 C446.2 C472.2 FB1.2 R41.2 R200.1 R314.2 R389.2 R391.1 R392.1 R490.1 R491.1 R538.1 R572.2 R575.1 R576.1 R584.1 R681.1 U7.4(VCC) U50.24(VCCA) U54.5(VCC) U82.8(VCC) U90.5(VCC) ; also on sheet 10 12 13 14 18 19 20 22 23 24 25 26 27 29 30 31 32 33 34 35 36 37 38 39 40
VCC_5V0: C219.1 U50.11(VCC5V) ; also on sheet 10 11 33 36
VCC_5V0_HDMICONN: C211.1 J5.18 U50.13(5V_OUT)
VDD_1V2: C201.1 C232.1 FB2.2 FB3.2 ; also on sheet 13 14
AUDIO_EXT_REFCLK1: R34.1 U7.3(OUTPUT) ; also on sheet 33
CLKOUT0: R384.2 R385.2 ; also on sheet 25
CLKOUT_OSC: R384.1 U53.3(OUTPUT)
CONN_MCU_PORz: U72.1(A) ; also on sheet 34
CONN_MCU_RESETz: Q2.1(G) ; also on sheet 34
CPSW_RGMII_INTn/PRU_INTn: R613.1 ; also on sheet 23 32
DEBOUNCE_GPIO_INT_SoC: C469.2 D12.2 Q17.2(S) R575.2 SW4.2 SW4.3 U82.3(2A)
Debounce_MCU_RESETz: C156.2 Q2.2(S) R200.2 TP68.1(TP) U82.1(1A)
DEBOUNCE_SOC_WARMRESETn: C470.2 D13.2 Q18.2(S) R576.2 SW3.2 SW3.3 U82.6(3A)
EXP_CLKOUT0: R336.1 ; also on sheet 33
EXP_GPIO1_22: U12.A15(UART0_CTSN) ; also on sheet 33
EXP_SPI0_CLK: U12.A14(SPI0_CLK) ; also on sheet 33
EXP_SPI0_CS0: U12.A13(SPI0_CS0) ; also on sheet 33
EXP_SPI0_CS1: U12.C13(SPI0_CS1) ; also on sheet 33
EXP_SPI0_D0: U12.B13(SPI0_D0) ; also on sheet 33
EXP_SPI0_D1: U12.B14(SPI0_D1) ; also on sheet 33
EXP_UART5_RXD: U12.C15(MCAN0_TX) ; also on sheet 33
EXP_UART5_TXD: U12.E15(MCAN0_RX) ; also on sheet 33
EXT_CLKOUT0: R337.1 R385.1
EXT_CLKOUT0_R: R336.2 R337.2 U12.A18(EXT_REFCLK1)
EXTINTn: R613.2 R681.2 TP25.1(TP) U12.D16(EXTINTN) ; also on sheet 13
GPIO1_23_INTn: R550.2 U12.B15(UART0_RTSN) ; also on sheet 39
GPIO_HDMI_RSTn: R389.1 R390.2 U54.1(A) ; also on sheet 39
GPIO_SoC: R550.1 U82.5(2Y)
HDMI_AUDD1: TP16.1(TP) U10.40(SD1)
HDMI_AUDD2: TP14.1(TP) U10.39(SD2)
HDMI_AUDD3: TP88.1(TP) U10.37(SD3)
HDMI_CEC: U10.71(CEC_A) U50.1(CEC_A)
HDMI_CEC_D: TP18.1(TP) U10.50(CEC_D)
HDMI_CLK+: J5.10 U10.59(TXC+) U50.16(CLK+)
HDMI_CLK-: J5.12 U10.58(TXC-) U50.15(CLK-)
HDMI_CONN_I2CSCL: J5.15 U50.8(SCL_B)
HDMI_CONN_I2CSDA: J5.16 U50.9(SDA_B)
HDMI_CONNCEC: J5.13 U50.7(CEC_B)
HDMI_EARTH: FL17.2 J5.20 J5.21 J5.22 J5.23
HDMI_EXTSWING: R327.1 U10.56(EXT_SWING)
HDMI_HPD: R326.1 U10.54(HPD) U50.4(HPD_A)
HDMI_I2C_SCL: R323.2 U10.49(DSCL) U50.2(SCL_A)
HDMI_I2C_SDA: R316.2 U10.48(DSDA) U50.3(SDA_A)
HDMI_INTn: R325.2 U10.52(INT) ; also on sheet 39
HDMI_MSTRCLK: R34.2 U10.38(MCLK)
HDMI_PCLK: R60.2 U10.22(IDCK)
HDMI_RSTn: R373.2 U10.51(RESET#) U54.4(Y)
HDMI_TX0+: J5.7 U10.62(TX0+) U50.18(D0+)
HDMI_TX0-: J5.9 U10.61(TX0-) U50.17(D0-)
HDMI_TX1+: J5.4 U10.65(TX1+) U50.21(D1+)
HDMI_TX1-: J5.6 U10.64(TX1-) U50.20(D1-)
HDMI_TX2+: J5.1 U10.68(TX2+) U50.23(D2+)
HDMI_TX2-: J5.3 U10.67(TX2-) U50.22(D2-)
HDMICONN_HPD: J5.19 U50.10(HPD_B)
JTAG_EMU_RSTn: U90.1(B) ; also on sheet 30
MCASP1_ACLKX_HDMI: U10.45(SCK) ; also on sheet 39
MCASP1_AFSX_HDMI: U10.44(WS) ; also on sheet 39
MCASP1_AXR0_HDMI: U10.41(SD0) ; also on sheet 39
MCU_PORz: R201.1 R220.2 TP69.1(TP) U12.D2(MCU_PORZ) U72.4(Y)
MCU_RESETSTATz: U12.B12(MCU_RESETSTATZ) ; also on sheet 32 34
MCU_RESETz: R538.2 TP78.1(TP) U12.E11(MCU_RESETZ) U82.7(1Y)
MCU_SAFETY_ERRORz_1V8: U12.D1(MCU_ERRORN) ; also on sheet 34
PMIC_PGOOD: U90.2(A) ; also on sheet 13 35
PORz_OUT: R381.1 TP34.1(TP) U12.E21(PORZ_OUT) ; also on sheet 20 23 24 27
RESETSTATz: R472.1 TP64.1(TP) U12.F22(RESETSTATZ) U54.2(B) ; also on sheet 13 19 20 21 23 24 27 32 33 37 39 40
SoC_I2C0_SCL: R391.2 U12.B16(I2C0_SCL) ; also on sheet 10 13 22 32 33 37
SoC_I2C0_SDA: R392.2 U12.A16(I2C0_SDA) ; also on sheet 10 13 22 32 33 37
SOC_I2C1_SCL: R491.2 U10.1(CSCL) U12.B17(I2C1_SCL) ; also on sheet 14 22 26 39 40
SOC_I2C1_SDA: R490.2 U10.2(CSDA) U12.A17(I2C1_SDA) ; also on sheet 14 22 26 39 40
SoC_PORz: R584.2 U72.3(B) U90.4(Y)
SOC_UART0_RX_3V3: U12.D14(UART0_RXD) ; also on sheet 31
SOC_UART0_TX_3V3: U12.E14(UART0_TXD) ; also on sheet 31
SoC_VOUT0_DATA0: U10.32(D0) U12.U22(VOUT0_DATA0)
SoC_VOUT0_DATA1: U10.31(D1) U12.V24(VOUT0_DATA1)
SoC_VOUT0_DATA2: U10.30(D2) U12.W25(VOUT0_DATA2)
SoC_VOUT0_DATA3: U10.29(D3) U12.W24(VOUT0_DATA3)
SoC_VOUT0_DATA4: U10.28(D4) U12.Y25(VOUT0_DATA4)
SoC_VOUT0_DATA5: U10.27(D5) U12.Y24(VOUT0_DATA5)
SoC_VOUT0_DATA6: U10.25(D6) U12.Y23(VOUT0_DATA6)
SoC_VOUT0_DATA7: U10.24(D7) U12.AA25(VOUT0_DATA7)
SoC_VOUT0_DATA8: U10.23(D8) U12.V21(VOUT0_DATA8)
SoC_VOUT0_DATA9: U10.20(D9) U12.W21(VOUT0_DATA9)
SoC_VOUT0_DATA10: U10.19(D10) U12.V20(VOUT0_DATA10)
SoC_VOUT0_DATA11: U10.18(D11) U12.AA23(VOUT0_DATA11)
SoC_VOUT0_DATA12: U10.17(D12) U12.AB25(VOUT0_DATA12)
SoC_VOUT0_DATA13: U10.16(D13) U12.AA24(VOUT0_DATA13)
SoC_VOUT0_DATA14: U10.15(D14) U12.Y22(VOUT0_DATA14)
SoC_VOUT0_DATA15: U10.14(D15) U12.AA21(VOUT0_DATA15)
SoC_VOUT0_DATA16: U10.13(D16) ; also on sheet 32
SoC_VOUT0_DATA17: U10.11(D17) ; also on sheet 32
SoC_VOUT0_DATA18: U10.10(D18) ; also on sheet 32
SoC_VOUT0_DATA19: U10.9(D19) ; also on sheet 32
SoC_VOUT0_DATA20: U10.8(D20) ; also on sheet 32
SoC_VOUT0_DATA21: U10.7(D21) ; also on sheet 32
SoC_VOUT0_DATA22: U10.6(D22) ; also on sheet 32
SoC_VOUT0_DATA23: U10.4(D23) ; also on sheet 32
SoC_VOUT0_DE: U10.33(DE) U12.Y20(VOUT0_DE)
SoC_VOUT0_HSYNC: U10.34(HSYNC) U12.AB24(VOUT0_HSYNC)
SoC_VOUT0_PCLK: R60.1 U12.AC24(VOUT0_PCLK)
SoC_VOUT0_VSYNC: U10.35(VSYNC) U12.AC25(VOUT0_VSYNC)
SoC_WARM_RESETZ: R572.1 TP85.1(TP) U12.F20(RESET_REQZ) U82.2(3Y)
TEST_GPIO1: Q17.1(G) ; also on sheet 1 26
TEST_PORZn: U72.6(C) ; also on sheet 1 26
TEST_WARMRESETn: Q18.1(G) ; also on sheet 1 26
VHDMI_AVCC_1V2: C229.1 C230.1 C231.1 FB3.1 U10.60(AVCC12_1) U10.66(AVCC12_2)
VHDMI_CVCC_1V2: C200.1 C207.1 C209.1 C213.1 C217.1 C225.1 FB2.1 U10.5(CVCC12_1) U10.12(CVCC12_2) U10.26(CVCC12_3) U10.42(CVCC12_4) U10.47(CVCC12_5) U10.53(CVCC12_6)
VHDMI_IOVCC_3V3: C199.1 C212.1 C223.1 FB1.1 R61.1 R316.1 R323.1 R325.1 U10.3(IOVCC1) U10.21(IOVCC2) U10.46(IOVCC3)
N16927060: R61.2 U10.72(CI2CA)
N16927228: R62.1 U10.69(IO_SEL)
N16927289: R287.2 U10.36(SPDIF)
N16947096: R370.1 U53.1(TRI-STATE)
N17285208: R314.1 U50.5(LS_OE) U50.12(CT_HPD)
N20175146: R41.1 U7.1(INH)

Not connected (* = marked no-connect by the designer): J5 14*; U12 A2(RSVD1)* AE2(RSVD3)* B1(RSVD0)* F6(RSVD2)*

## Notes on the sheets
sheet 41
- HDMI INTERFACE
- HDMI ESD DEVICE
- 100E
- 100E
- 100E
- 100E
- NOTE:
  TPD12S016PWR has integrated pullup or pulldown resistors on the
  I2C and HPD lines hence no external pullup or pulldown required.
- HDMI CONNECTOR
- I2C ADDRESS: 0x3B, 0x3F, 0x62
- Silk: HDMI
- HDMI RESET
sheet 42
- OSCILLATOR
- SOC - GENERAL
- GPIO1_22
- GPIO1_23
- RESERVED PINS
- RESERVED PINS
- ECS-2520MV-250-CN-TR
- SOC - RESET
- Pull-down resistor on PORz_OUT is provided to keep the signal
  low until the processor is released from reset during the
  power-up seqence
- MCU POWER ON RESET
sheet 43
- RESET
- DEBOUNCE CIRCUIT
- MCU WARM RESET
- SOC WARM RESET
- Silk: RST
- USER INTERRUPT
- Silk: INT
sheet 44
- HARDWARE SCHEMATICS
- LOGOs
- ASSEMBLY NOTES
- BARE PCB
- 1. All MSL components should be baked as per JEDEC
  standard.
  2. PCB should be baked at 120 degree for 8 hours.
  3. Board assembly must comply with workmanship standards.
  IPC-A-610 Class 2, unless otherwise specified.
  4. These assemblies are ESD sensitive, ESD precautions
  shall be observed.
  5. These assemblies must be clean and free from flux and
  all contaminants. Use of no clean flux is not acceptable.
  6. Provide serial numbers to the assembled boards for
  identification.
  7. The assembled board are wrapped in ESD Covers(individual)
  and
  packed securely before shipment.
- Texas Intruments
- For Evaluation only; not FCC approved for resale
- WEEE Mark
- CE Mark
- STANDOFF,SCREW & WASHER FOR PCIe M.2
- LABELS
- Board Serial No.
- Assembly Revision
- 3356
- MPMS 002 0005 PH
- FIDUCIALS
- ORDERABLE PART NO
- Oderable Part Number
- Variant
- Label Text
- 001
- SK-AM62-P1
- 002
- SK-AM62B-P1
